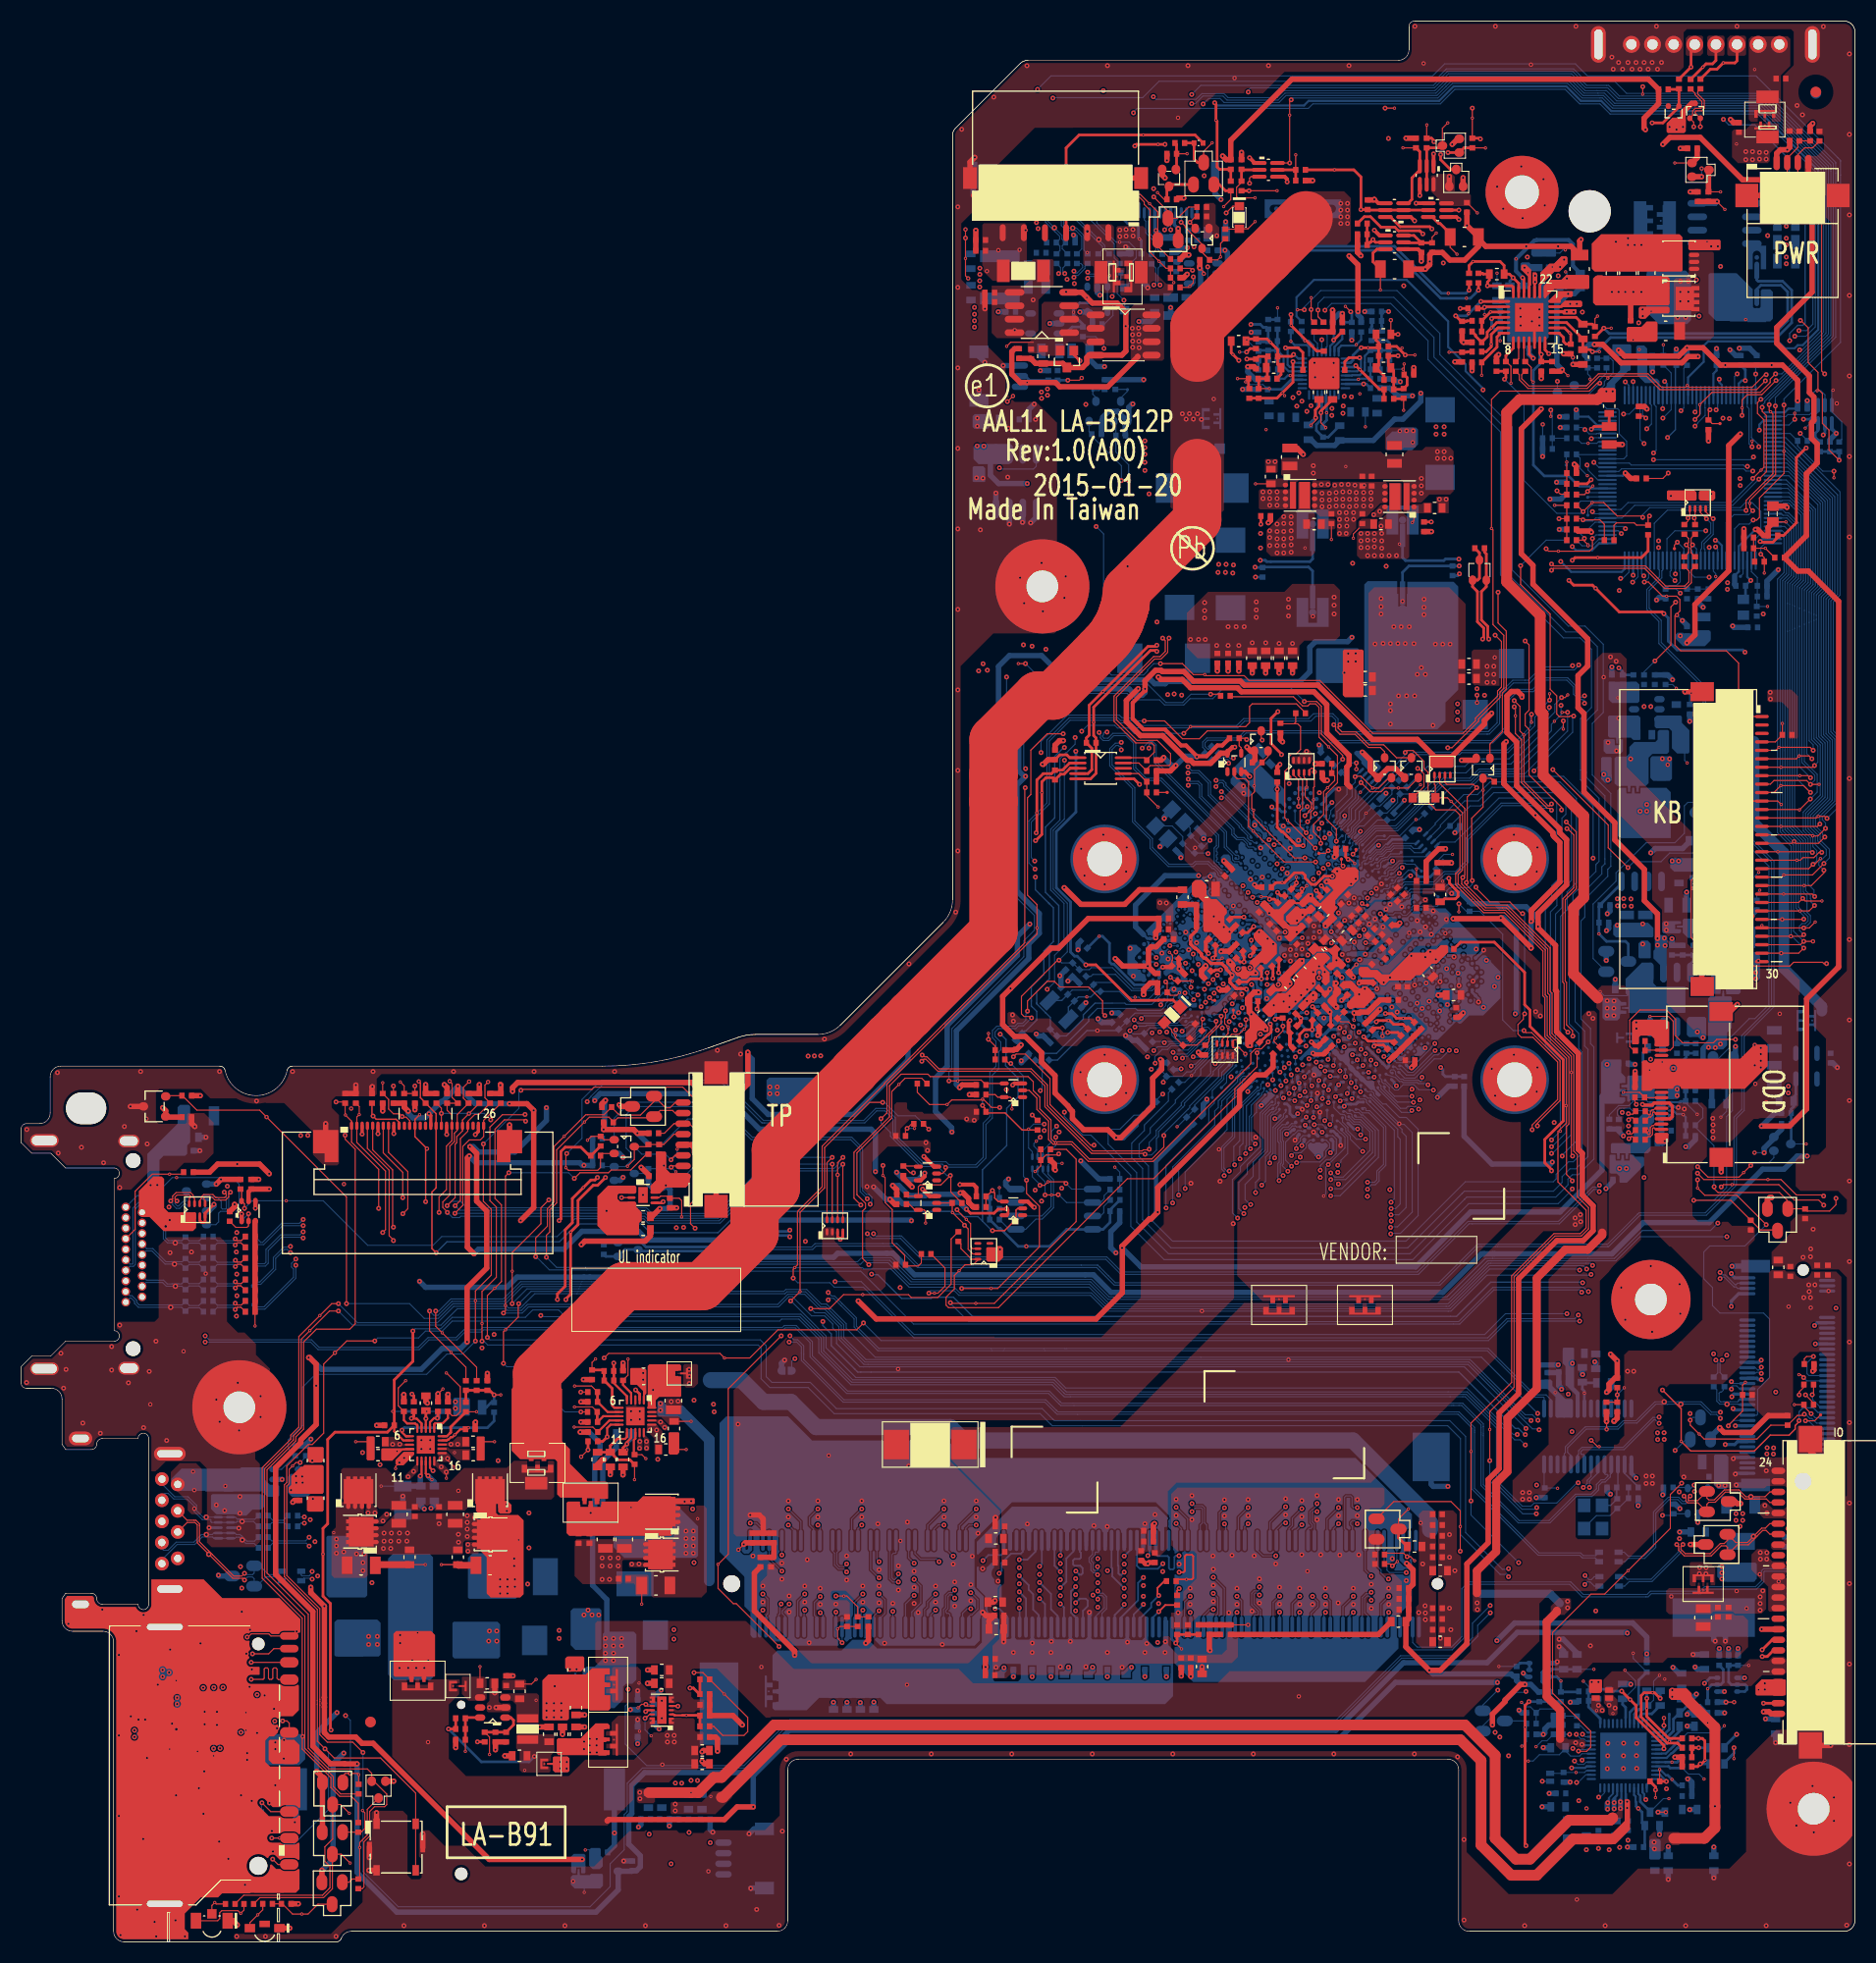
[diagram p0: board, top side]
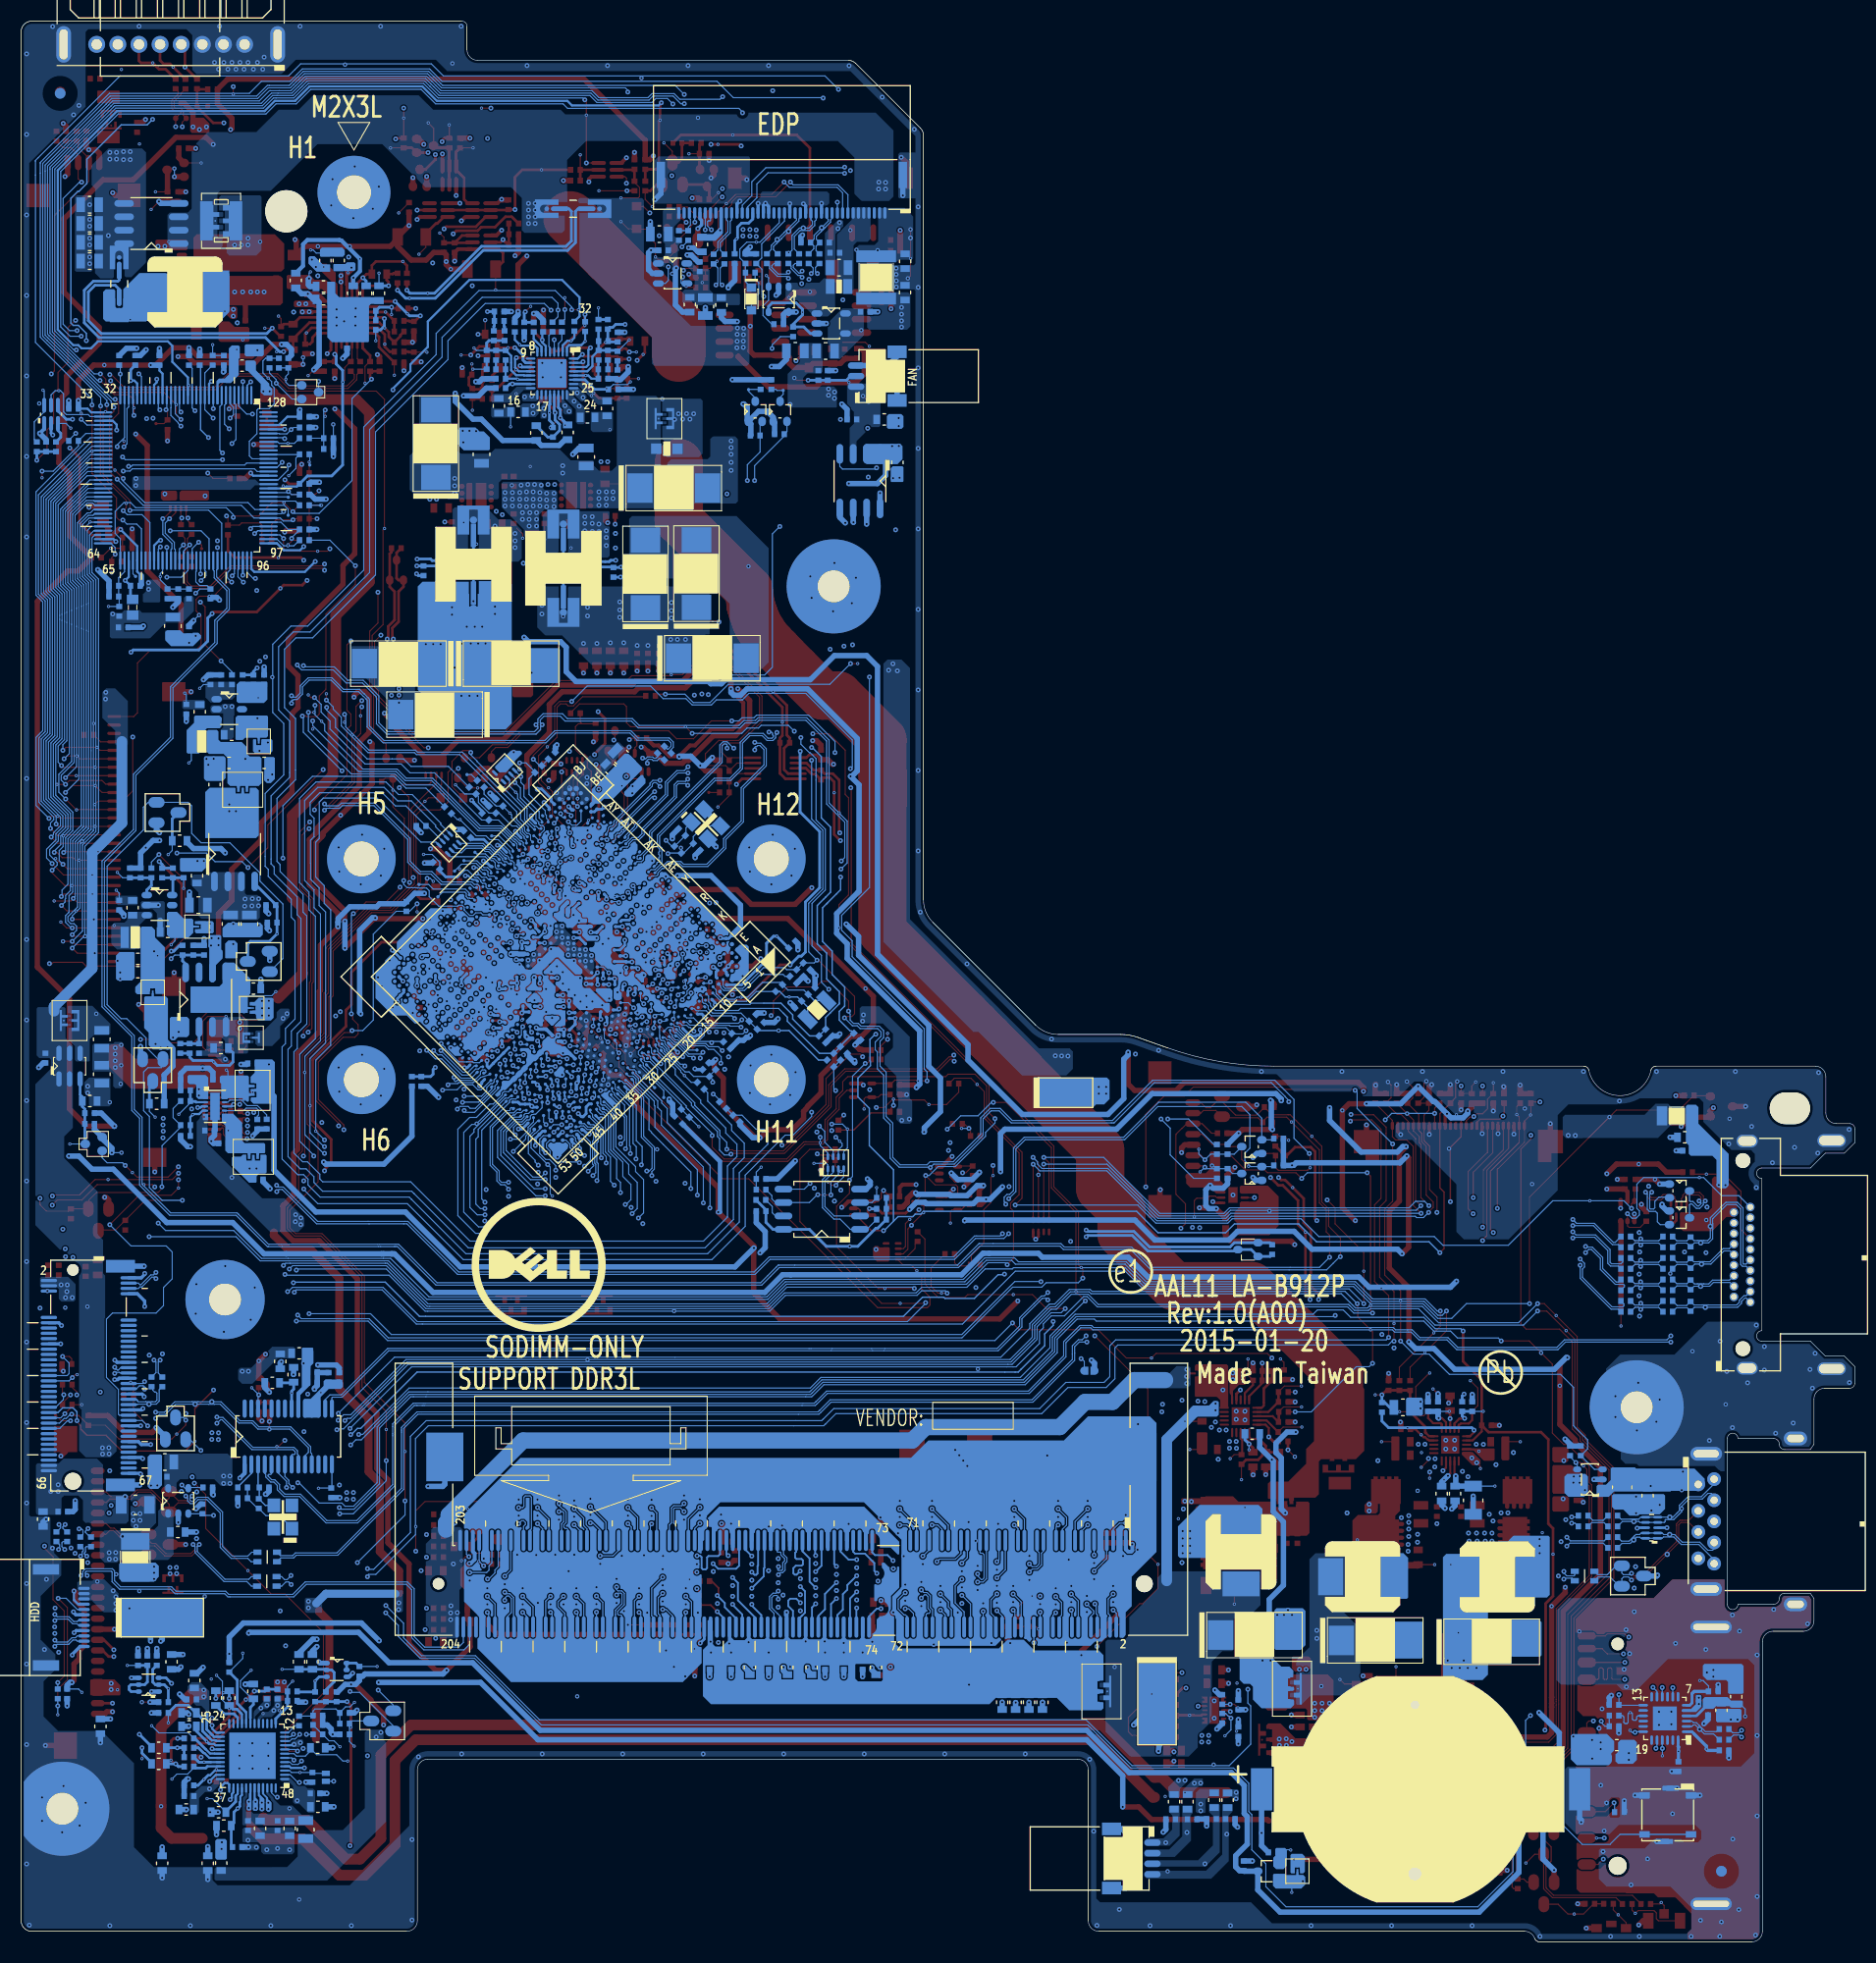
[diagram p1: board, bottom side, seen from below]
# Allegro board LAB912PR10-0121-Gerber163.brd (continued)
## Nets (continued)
USB20_HUB_P1: JEDP.35 U58.11
USB20_HUB_P2: JNGFF.3 U58.9
USB20_HUB_P3: LI6.1 U58.7
USB20_HUB_P4: RR4.2 U58.5
USB20_JUSB1_N0_R: D27.2 JUSB1.2 LI2.2
USB20_JUSB1_P0_R: D27.3 JUSB1.3 LI2.3
USB20_JUSB2_N1_R: D25.2 JIO1.22 LI5.2
USB20_JUSB2_P1_R: D25.3 JIO1.21 LI5.3
USB20_JUSB3_N3_R: D26.2 JIO1.18 LI6.3
USB20_JUSB3_P3_R: D26.3 JIO1.19 LI6.2
USB20_N0: LI2.1 USOC1.K16
USB20_N1: LI5.1 USOC1.G14
USB20_N2: RX21.2 USOC1.J12
USB20_P0: LI2.4 USOC1.M16
USB20_P1: LI5.4 USOC1.J14
USB20_P2: RX22.2 USOC1.K12
USB_EN#: CI13.1 CI26.1 UE1.84 UI4.4 UI5.4
USB_OC0#: CI15.1 RC44.2 UI5.3 USOC1.C20
USB_OC1#: CI17.1 RC46.2 UI4.3 USOC1.B20
USB_PLL_MON: RC47.2 USOC1.M13
USB_RCOMP: RC45.2 USOC1.C7 USOC1.D6
VCIN0_PH: PR13.2 R696.1 UE1.109
VCIN1_BATT_DROP: PR36.2 UE1.64
VCIN1_PROCHOT: PR15.2 R697.1 UE1.102
VCORE_GSNS: PC503.2 PC535.2 PU500.12 PU500.30 RC58.1 USOC1.N28
VCORE_VSNS: PC527.1 PC533.2 PR542.1 RC56.2 USOC1.P28
VCOUT0_PH: PR114.1 UE1.104
VCOUT1_PH: PR17.1 PR18.2 RE13.2 UE1.103
VFB: PR726.1 PU700.15 PU700.16
VGA_V1P35_S3_F1: CC35.1 CC36.1 RC67.2 USOC1.BD1
VGATE: PR530.1 PU500.15 UE1.97
VGFX_VSNS: PC502.1 PR501.2 PR504.2 RC55.2 USOC1.BB8
VL: PC117.1 PU100.13
VR_HOT#: PC520.1 PR525.1 PU500.6 R44.1
VR_ON: CE34.1 PR516.1 RE1.2 RE12.2
VR_ON_EC: RE12.1 UE1.121
VR_ON_R: PR516.2 PU500.2
VR_SVID_ALERT#: PU500.4 RC27.2 RC28.2
VR_SVID_ALERT#_SOC: RC28.1 USOC1.B24
VR_SVID_CLK: PR520.1 PR527.1 USOC1.C25
VR_SVID_CLK_R: PR520.2 PU500.3
VR_SVID_DATA: PR521.1 PR526.1 RC29.2
VR_SVID_DATA_R: PR521.2 PU500.5
VR_SVID_DATA_SOC: RC29.1 USOC1.A25
VSUM+: PC529.1 PC530.1 PR535.1 PR536.2 PR541.1 PU500.10
VSUM-: PC529.2 PC530.2 PC532.2 PC534.1 PH503.2 PL501.3 PR540.2 PR541.2
VSUMG+: PC513.2 PC514.2 PR500.2 PR509.2 PR513.2 PU500.32
VSUMG-: PC512.1 PC513.1 PC514.1 PH500.1 PL500.3 PR502.2 PR507.1 PR509.1
VTTREF_1.35VP: PC212.1 PU200.4
WL_OFF#: QM30.3 RE14.2 RP54.3 USOC1.BA26
WL_OFF#_EC: RE14.1 UE1.98
WLAN_CLKREQ#: JNGFF.45 RP63.2 USOC1.BD7
WLAN_RADIO_DIS#_R: JNGFF.48 QM30.1 RM110.2
WLAN_WAKE#: JNGFF.47 R490.2 UE1.86
XDP_H_PRDY#: CC52.1 JDB1.2 RC65.2 USOC1.D18
XDP_H_PREQ_BUF#: CC50.1 JDB1.1 RC61.2 USOC1.F16
XDP_H_TCK: CC65.1 JDB1.26 RP66.6 USOC1.D14
XDP_H_TDI: CC61.1 JDB1.22 RP66.8 USOC1.F12
XDP_H_TDO: CC56.1 JDB1.20 RC63.2 USOC1.G16
XDP_H_TMS: CC63.1 JDB1.23 RP66.7 USOC1.F14
XDP_H_TRST#: CC59.1 JDB1.21 RP66.5 USOC1.G12
XDP_OBSDATA_A0: JDB1.4 USOC1.N24
XDP_OBSDATA_A1: JDB1.5 USOC1.M20
XDP_OBSDATA_A2: JDB1.7 USOC1.J18
XDP_OBSDATA_A3: JDB1.8 USOC1.M18
XDP_RSTBTN#: CC12.1 CC49.1 CC53.1 JDB1.18 RC24.2 RC62.2
XTAL_25M_IN: CC9.1 RC19.1 USOC1.AH12 YC1.1
XTAL_25M_OUT: CC10.1 RC19.2 USOC1.AH10 YC1.3
N17188574: PC400.2 PJP400.2 PU400.4
N17188613: PC405.1 PR401.2
N17227658: PC412.1 PJP404.2 PU402.5 PU402.9
N17227663: PC413.2 PR410.2 PR412.1 PU402.2
N17227696: PC415.1 PR409.2 PR411.1 PU402.8
N17253612: PC116.1 PR111.2 PU100.12
N17256470: PC210.2 PR209.2 PU200.12
N17256593: PC211.1 PR202.2
N17322320: PC7.1 PH1.1 PR10.2 PR13.1
N17322935: PQ3.3 PR12.2
N17322941: PQ3.5 PQ3.6 PR14.1 PR19.2
N17330968: RC52.1 T211.1(TP-1)
N17354752: PL501.2 PR536.1
N17407779: CE12.1 R2354.1
N17434553: RE36.1 T218.1(TP-1)
N17434554: RE36.2 UE1.107
N18943829: PR720.2 PR724.1
N18944147: PC722.2 PC726.1 PR720.3 PU700.17
N18956218: PC722.1 PR724.2 PU700.18
N18967347: PC727.1 PR723.2
N18967375: PC721.1 PU700.4
N18967379: PR723.1 PU700.6
N18967435: PC723.1 PU700.7
N18967441: PR725.1 PR728.2 PU700.5
N18999155: PC706.1 PC709.1 PR704.2 PU700.28
N19000258: PC707.1 PC709.2 PR705.2 PU700.27
N19021042: PC710.1 PR709.2 PU700.26
N19093256: PR717.2 PU700.10
N19093259: PR719.2 PU700.9
N19095003: PR722.2 PU700.8
N19142937: PC700.2 PC701.1 PQ704.4 PQ705.4 PQ707.1 PR701.2 PR703.1
N19565438: PQ707.2 PQ708.1
N19565442: PQ709.3 PQ710.3 PR703.2
N19565444: PQ709.2 PQ709.5 PQ712.1 PR712.2
N19565472: PQ711.1 PR708.1
N22321388: T212.1(TP-1) UE1.82
N23955686: T105.1(TP-1) USOC1.C21
N23993932: CC24.2 RC39.2
N24334655: PC300.2 PJP300.2 PU300.4
N24334673: PC305.1 PR301.2
N24559749: PC307.2 PJP302.2 PU301.4
N24559796: PC306.1 PR306.2
N24654163: PC112.2 PR107.1
N24654248: PC113.1 PR108.2
N25654694: QA5.5 QA5.6 RA2.2
N25654700: CA1.1 CA2.1 QA5.2 RA3.2
N25858228: JODD1.8 RS09.2
N25860239: C1132.1 R1049.2 RC69.1 Y9.1
N25865342: R2448.2 R2450.1 U2407.7
N26297922: CX52.1 UX3.4
N26299865: CE60.1 UE4.6
N26526512: PC10.1 PR34.1 PR35.1 PR36.1
N26599744: PC12.1 PR11.2 PR15.1 PR18.1 PR20.1 PR22.1 PR23.1
N26600179: PR117.1 PU100.19
N26695162: RX10.2 UX4.3
N26916933: C976.2 U11.7
N26916935: C967.2 U11.9
N26924121: C1123.2 U12.7
N26924123: C1127.2 U12.9
N26952483: R1048.1 U58.14
N26952856: C1119.1 R1050.2 U58.21
N27019358: T103.1(TP-1) USOC1.AY26
N27069111: RA34.1 RA155.1 UA1.13
N27069175: CA24.1 UA1.37
N27069177: CA24.2 UA1.35
N27069191: CA23.2 UA1.28
N27069244: CA65.2 CA69.1 RA79.1 RA81.2
N27069257: CA65.1 UA1.12
N27069271: CA25.2 UA1.34
N27069366: RA130.2 UA1.8
N27069480: CA63.2 UA1.39
N27069495: CA64.2 UA1.7
N27069508: CA62.2 RA154.2 UA1.27
N27069623: CA21.1 R2355.2
N27070739: CA68.2 RA82.1
N27070741: CA67.2 RA80.1
N27098098: R2356.1 UA1.20
N27098403: QA1.5 QA1.6 RA16.2 RA17.2
N27098689: QA1.2 RA18.1 RA20.1
N27376108: PJP1.1 PJPDC1.1 PJPDC1.2 PL2.1
N27796256: CS17.1 JODD1.17 RS10.2
N28004468: QE9.2 R36.1
N28121198: PC515.1 PR511.2
N28124976: PQ10.6 PR23.2
N28125082: PQ10.3 PR22.2
N28199307: R34.1 U68.5
N28199357: R32.1 U69.5
N28392619: PR524.2 PU500.8
N28393122: PC517.2 PR518.1 PU500.22
N28398304: RD15.1 RX5.1 UE1.117
N28546463: D2401.2 R5205.2
N29841026: PQ713.3 PR730.2
N39970373: PQ710.6 PQ712.2 PR718.2
N40812716: CR3.2 UR1.6
N47007898: PC11.2 PQ4.5 PR26.1
N47008110: PC9.1 PQ4.2 PR17.2
N47008134: PL3.1 PQ1.1 PR2.2
N48037563: JDIMM2.197 RD6.2
N48037565: JDIMM2.201 RD7.2
N48039107: CD21.1 CD22.1 JDIMM2.126 RD4.1
N52907207: PQ706.4 PR706.1 PR708.2
N52907447: PQ711.2 PR714.1
N55201771: JHDMI1.13 RX12.2
N59110906: RE43.2 T203.1(TP-1)
N61580896: Q2307.1 R2314.2
N61580898: Q2308.1 R2315.2
N100764683: PC506.1 PR502.1
N100764685: PC506.2 PR507.2 PU500.31
N100764689: PC532.1 PR539.2
N100764691: PR539.1 PR540.1 PU500.11
N100764720: PC518.1 PR519.2 PR522.2 PU500.21
N100764741: PC504.1 PR503.1 PR508.1 PU500.28
N100764791: PC504.2 PC505.1 PC507.2 PR504.1 PR505.1 PU500.29
N100764795: PC528.2 PC531.2 PR534.2 PU500.14
N100764809: PC528.1 PR533.2 PR538.2 PR542.2 PR543.1 PU500.13
N100764813: PC507.1 PR503.2
N100764860: PR510.2 PU500.27
N100764905: PC531.1 PR543.2
N100764954: PC527.2 PR538.1
N100764996: PH500.2 PR500.1
N100765028: PC525.2 PR533.1
N100765040: PC505.2 PR501.1
N100765116: PH503.1 PR535.2
N100765769: PC511.1 PR505.2
N100765781: PR522.1 PU500.20
N100768097: PC526.1 PR532.2
N100768278: PC516.1 PR512.2
N100768460: PC524.1 PR531.2
N100768540: PL500.2 PR513.1
N102723193: T102.1(TP-1) USOC1.BG18
N102723222: T101.1(TP-1) USOC1.BH18
N102723231: T100.1(TP-1) USOC1.BG21

Pads without a net: FD1 1; FD2 1; FD3 1; FD4 1; JDB1 11 14 15 24; JDIMM2 77 122 125 198; JEDP 3 22 33 39; JHDMI1 14; JIO1 10 16; JKB 2 3 30; JNGFF 6 8 9 11 12 13 14 15 16 17 19 20 21 22 23 24 26 28 34 36 38 40 51 52 53 54 56 57 58 59 60 62 63 65; JODD1 9 16; LED2 3; PD2 3; PJPDC1 4; PU300 5; PU301 5; PU400 5; PU402 7; PU500 9; RP1 4 5; RP54 4; RP65 4; RP68 1 8; U58 12 13 22 23 24 25 27 28; U68 1; U69 1; U2407 8; UA1 14 15 16 23 24 48; UC5 1; UC7 1; UC10 1; UE1 1 14 17 25 26 37 71 90 119 120 126 127 128; UR1 7 9 12 14 16 17 19 22 23; USOC1 A13 A17 AB2 AB3 AB7 AB9 AB12 AB13 AB14 AC1 AC3 AD2 AD3 AD4 AD6 AD9 AD10 AD12 AD40 AD41 AF4 AF6 AF13 AF14 AF40 AF41 AF48 AF50 AF51 AF52 AG51 AG53 AH13 AH14 AH40 AH44 AH52 AJ51 AK4 AK6 AK7 AK9 AK40 AK42 AK45 AK47 AK48 AK50 AK51 AK52 AL1 AL3 AL51 AL53 AM4 AM6 AM9 AM10 AM13 AM14 AM41 AM42 AM45 AM47 AM48 AM50 AM52 AP4 AP6 AP7 AP9 AP10 AP12 AP41 AP42 AP44 AP45 AP47 AP48 AP50 AP51 AP52 AR51 AR53 AT6 AT7 AT13 AT14 AT20 AT22 AT26 AT32 AT34 AT36 AT40 AT41 AT42 AT44 AT45 AT48 AT50 AT51 AU20 AU22 AU26 AU34 AU36 AU53 AV9 AV10 AV20 AV22 AV26 AV28 AV32 AV34 AV36 AV40 AV44 AV45 AV48 AV50 AV52 AW1 AW41 AW51 AW53 AY2 AY3 AY6 AY7 AY20 AY24 AY28 AY30 AY34 AY38 AY40 AY42 AY44 AY45 AY47 AY48 AY51 AY52 B4 B5 B12 B14 B16 B26 B28 BA1 BA3 BA18 BA20 BA24 BA28 BA34 BA36 BA38 BA42 BA51 BB3 BB4 BB44 BB47 BB49 BB50 BB51 BC14 BC18 BC24 BC36 BC38 BC40 BC44 BC52 BC53 BD2 BD5 BD12 BD16 BD18 BD20 BD22 BD28 BD32 BD34 BD36 BD38 BD40 BD42 BD44 BD47 BE46 BE51 BE52 BF2 BF14 BF22 BF27 BF28 BF32 BF34 BF40 BF42 BF48 BF50 BF52 BG23 BG26 BG27 BG29 BG32 BG33 BG35 BG36 BG37 BG38 BG40 BG41 BG43 BG47 BH4 BH5 BH6 BH7 BH8 BH22 BH26 BH32 BH34 BH36 BH38 BH40 BH42 BH44 BH46 BH47 BH48 BH49 BH50 BJ9 BJ29 BJ33 BJ37 BJ41 BJ45 C13 C16 C18 C27 C30 D2 D26 D28 D32 D34 D48 E2 E46 F1 F18 F28 F32 F34 G2 G30 H3 H4 H5 H7 H8 J3 J28 J34 K2 K3 K18 K20 K24 K28 K34 L1 L3 M2 M3 M4 M6 M7 M9 M10 M22 M24 M32 N3 N32 N34 P2 P3 P6 P7 P10 P12 P14 P34 R1 R3 T2 T3 T4 T6 T7 T9 T10 T12 T13 T14 V2 V3 V4 V6 V9 V10 V13 V14 W1 W3 Y2 Y3 Y4 Y6 Y12 Y13; Y9 2 4

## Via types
v1: diameter 0.305, hole 0.152, TOP to BOTTOM, 442 vias
v2: diameter 0.457, hole 0.203, TOP to BOTTOM, 3086 vias
v3: diameter 0.508, hole 0.254, TOP to BOTTOM, 20 vias
v4: diameter 0.406, hole 0.203, TOP to BOTTOM, 136 vias

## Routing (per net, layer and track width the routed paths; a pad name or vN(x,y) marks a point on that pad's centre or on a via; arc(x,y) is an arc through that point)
1.0VS_GATE: length 10.7
  BOTTOM w0.254: Q70.1 152.1,94.45 151.85,94.7 150.04,94.7 v1(149.33,95.41) R1061.1 149.33,98 C1131.1 149.61,98.28 149.61,98.34 151.44,100.17 U60.4
1.8VS_ON: length 4.2
  BOTTOM w0.102: v1(158.63,78.33) 157.54,79.42 R1055.1
  BOTTOM w0.203: U12.2 156.98,79.48
  BOTTOM w0.254: 156.98,79.48 157.05,79.55 157.5,79.55 R1055.1 C1125.2
1.35VS_ON: length 3.5
  BOTTOM w0.203: U12.4 156.37,78.68 156.7,78.35 157.25,78.35 v1(157.31,78.3) 157.54,78.07 R1056.1
  BOTTOM w0.254: R1056.1 C1128.2
3VS_ON: length 3.8
  TOP w0.203: U11.2 61.73,21.53 61.8,21.46 61.88,21.46 61.89,21.45 62.6,21.45
  TOP w0.254: 62.6,21.45 v1(62.96,21.45) 64.22,21.45 C980.1 R927.1
5VS_ON: length 5.4
  TOP w0.203: v2(62.16,22.31) 62.14,22.33 U11.4
  TOP w0.254: R926.2 C979.2 64.19,23.45 63.62,24.02 v2(63.3,24.02)
  IN1 w0.254: v2(63.3,24.02) 62.16,22.88 v2(62.16,22.31)
+0.675VS: length 74.6
  BOTTOM w1.524: 65.27,53.17 68.19,53.17 70.26,51.11 72.86,51.11 75.24,48.73 87.94,48.73 89.21,47.46 126.04,47.46 133.09,40.41 133.09,39.9 133.34,39.64 133.34,39.01
  vias: v2(63.23,54.19) v2(63.25,53.53) v2(63.24,52.85) v2(132.27,31.16) v2(132.64,35.77) v2(132.87,31.81) v2(132.9,31.14) v2(132.9,30.5) v4(132.45,39.66)
+0.675VSP: length 2.7
  TOP w0.254: v2(58.16,52.24) 58.53,51.86 PU200.2
  IN1 w0.254: v2(59.81,52.24) v2(58.16,52.24)
+1.0VALW: length 18.4
  TOP w0.102: v2(137.79,118) v4(137.79,117.29)
  TOP w0.254: C1074.1 115.36,92.75 v2(115.74,92.75) 115.74,93.27 115.62,93.38 C1039.2 ; C1036.2 117.3,91.95 117.38,91.87 v2(117.38,91.15) 116.33,91.15 116.05,90.87 C1037.2
  TOP w0.508: C1034.2 107.42,94.19 106.97,94.19 106.7,93.92 106.7,92.43 v2(106.63,92.36) ; v2(106.63,92.36) 107.31,91.68 C1035.2 ; v2(106.63,92.36) 104.25,92.36 v2(103.55,93.06)
  BOTTOM w0.254: v2(115.74,92.75) 116.29,92.75 USOC1.V18 116.32,92.79 USOC1.Y19 ; USOC1.C3 106.49,92.53 106.49,92.49 v2(106.63,92.36) 106.98,92.01 USOC1.C5 106.8,91.79 106.8,91.6 USOC1.B6 ; USOC1.U22 117.36,91.13 v2(117.38,91.15) 117.39,91.16 USOC1.V22
  vias: v2(108.51,118.05) v2(109.12,118.11) v2(109.84,118) v2(137.79,118.61) v2(138.5,117.99) v2(153.22,107.02) v2(153.85,107.65) v2(153.85,107.02)
+1.0VALWP: length 10.9
  IN1 w0.254: v2(152.33,111.97) 152.01,112.29 152.01,113.98 151.21,114.78 v2(151.21,120.58)
  BOTTOM w0.254: v2(151.21,120.58) 151.21,120.59 151.57,120.24 PR307.1 PC310.1
+1.0VALWP_ON: length 1.2
  BOTTOM w0.102: PC309.1 156.29,119.01 v1(156.65,118.65)
+1.0VS: length 190.7
  TOP w0.254: v2(118.47,91.2) 118.48,91.21 118.48,92.24 118.37,92.35 ; v2(113.52,92) 113.02,92 112.91,91.9 C1060.2
  TOP w0.305: C1044.2 116.66,93.66 v2(116.32,93.33)
  TOP w0.356: C1061.2 125.02,89.12 v2(124.97,89.12)
  TOP w0.508: v2(107.63,119.72) 107.85,119.49 109.89,119.49 110.68,118.7 115.12,118.7 115.5,118.32 122.36,118.32 123.56,117.11 123.56,114.42 125.69,112.3 125.69,111.42 125.47,111.21 125.47,109.62 125.79,109.3 ; v2(107.83,83.52) 107.94,83.41 107.94,82.6 107.09,81.75 107.09,79.13 104.08,76.12 v2(103.64,76.12) 103.6,76.12 102.85,76.87 100.56,76.87 99.5,77.94 99.5,78.6 99.29,78.81 99.08,79.12 97.85,80.35 97.85,82 96.58,83.27 96.58,84.16 95.04,85.69 94.02,85.69 92.89,86.83 92.89,89.49 v4(93.64,90.24) 97.47,94.06 98.19,94.06 100.98,96.86 C1048.2 C1049.2 107.38,95.55 v2(107.38,95.04) ; C1070.2 127.86,90.84 126.71,90.84 v2(126.62,90.76) ; v2(124.11,154.45) 124.13,154.44 PC523.1 PR525.2 124.11,152.39 PR526.2 PR527.2
  IN1 w0.508: v2(154.23,103.08) 153.8,102.65 153.8,101.23 152.36,99.78 v2(152.36,98.71) ; v2(107.63,119.72) 107.63,119.78 106.57,120.84 106.57,123.88 107.5,124.81 v2(107.5,124.93) ; v2(106.75,137.05) 106.74,137.07 106.74,137.59 105.34,138.98 105.34,142.2 106.19,143.05 106.19,146.34 109.4,149.55 109.4,152.09 112.87,155.56 123.6,155.56 124.11,155.05 v2(124.11,154.45)
  IN2 w0.254: v2(111.44,100.92) 111.44,100.54 112.32,99.65 112.32,96.62 112.52,96.43 112.52,94.38 ; v2(113.52,92) 113.35,92.17 113.35,93.23 112.52,94.06 112.52,94.38 ; 112.52,94.38 114.17,94.38 115.56,95.78 116.26,95.78 117.15,94.89
  IN2 w0.508: v2(107.5,124.93) 107.5,136.3 v2(106.75,137.05)
  BOTTOM w0.254: 106.23,95.33 106.59,94.97 USOC1.G1 107.32,94.97 v2(107.38,95.04) ; v2(126.62,90.76) 126.62,90.22 USOC1.AJ36 ; v2(126.62,90.76) 126.91,90.76 126.92,90.77 USOC1.AK36 ; v2(126.62,90.76) 126.62,91.1 126.64,91.13 USOC1.AK35 ; USOC1.Y22 v2(118.47,91.2) ; USOC1.Y18 v2(116.32,93.33) ; USOC1.V24 117.93,90.63 v2(117.92,90.61) ; v2(125.26,96.69) 124.85,96.28 124.85,95.96 USOC1.AN25 ; USOC1.AF21 USOC1.AG21 v2(121.25,95.03) ; v2(118.98,90.61) 119.01,90.64 USOC1.Y24 ; 126.14,94.61 126.09,94.56 USOC1.AN29 ; 126.14,94.61 v2(126.17,94.64) ; 126.14,94.61 USOC1.AN30 ; USOC1.AF16 USOC1.AF18 119.6,95.54 v2(119.62,95.57) ; v2(116.29,92.2) USOC1.U19 ; USOC1.AM16 USOC1.AM18 ; 112.99,91.97 113.03,92 v2(113.52,92) ; USOC1.U18 115.29,92.22 v2(115.18,92.1) ; v2(124.71,109.1) 124.68,109.13 124.3,109.13 123.4,108.23 123.4,107.99 USOC1.BJ6 ; v2(121.68,87.95) USOC1.V32
  BOTTOM w0.508: v2(107.83,83.52) 108.14,83.21 RC15.2 ; v2(103.64,76.12) 104.31,76.12 105.53,77.34 RC27.1 ; v2(111.44,100.92) 108.26,100.92 105.47,98.13 105.47,96.1 106.23,95.33 ; v2(154.23,103.08) 154.64,103.49 157.24,103.49 157.85,104.1 R1052.2
  vias: v2(120.75,96.65) v2(121.28,97.19) v2(123.3,87.45) v2(124.67,97.39) v2(125.67,98.33) v2(126.15,98.81) v2(128.26,99.7) v2(128.74,100.14) v2(151.07,98.73) v2(151.09,98.06) v2(151.67,98.74) v2(151.71,98.05) v2(152.39,98.03)
+1.0VS_R: length 4.4
  BOTTOM w0.102: v1(159.63,102.92) 159.25,103.3 R1052.1
  BOTTOM w0.254: R1052.1 159.25,106.29 Q71.1
+1.05V_PGOOD: length 2.6
  BOTTOM w0.102: UE1.106 148.64,135.97 148.28,135.61 T210.1
+1.5VS: length 63.3
  TOP w0.762: 149.64,67.14 149.64,66.89 148.27,65.51 146.13,65.51 143.44,62.82 143.44,52.34 140.67,49.58 140.67,44.51 139.6,43.44 139.6,36.94 137.78,35.11 137.78,33 ; 145.65,19.21 145.65,21.94 144.38,23.21 144.38,30.28 145.34,31.25 145.34,31.35
  BOTTOM w0.203: v2(147.72,18.69) 147.8,18.61 UA1.9
  BOTTOM w0.254: v2(126.69,92.97) 126.66,92.94 USOC1.AM32
  BOTTOM w0.508: RA8.1 v2(152.03,8.97)
  BOTTOM w0.762: 145.62,32.04 144.71,32.95 138.13,32.95
  vias: v2(137.8,32.09) v2(137.83,31.45) v2(143.34,88.04) v2(143.78,87.64) v2(146.36,32.24) v2(146.36,31.62) v2(147.12,18.85) v2(148.38,87.85) v2(148.76,87.41) v2(151.29,8.95) v4(134.79,95.46)
+1.05VS: length 12.7
  TOP w0.102: v4(126.37,92.5) 125.66,91.79 C1042.1
  TOP w0.254: C1040.1 122.71,88.03 v2(122.22,88.52)
  TOP w0.356: RC100.1 120.68,87.85 v2(121.12,87.42) 121.12,87.08 C1038.1
  TOP w0.381: C1041.1 124.94,91.27 v2(125,91.27)
  TOP w0.508: C1042.1 125.66,91.72 v2(126.08,91.3)
  BOTTOM w0.254: USOC1.AA33 v2(122.22,88.52) ; USOC1.U35 USOC1.U33 121.11,87.41 v2(121.12,87.42) 121.13,87.41 USOC1.V33
  BOTTOM w0.508: 159.19,84.54 159.19,82.89 160.01,82.06 R2315.1
  vias: v2(159.7,84.67) v2(160.34,84.64) v2(160.83,84.98)
+1.05VS_SOC: length 1.1
  BOTTOM w0.254: USOC1.Y32 121.69,89.06 v2(121.69,89.06) ; v2(122.27,89.61) USOC1.AC32
  vias: v1(122.28,89.1)
+1.5VSP: length 7.3
  BOTTOM w0.254: PC414.1 153.5,84.17 153.5,83.28 153.82,82.96 155,82.96 v1(155.31,83.28) 155.45,83.42 157.28,83.42 157.6,83.74 PC413.1 PR410.1
+1.05VSP: length 12.7
  TOP w0.254: v2(160.97,93.76) 160.11,93.76 158.36,95.51 158.36,100.13 v2(160.48,102.26)
  BOTTOM w0.254: PR302.1 PC301.1 160.2,101.98 v2(160.48,102.26)
  vias: v1(160.64,93.34)
+1.05VSP_ON: length 5.3
  BOTTOM w0.102: PC304.1 163.94,100.72 v1(164.45,101.23)
  BOTTOM w0.254: PC304.1 PR303.1 PR300.2 161.22,99.99 161.66,99.56 PU300.1
+1.8VALW: length 252.7
  TOP w0.254: v2(50.92,68.27) 51.09,68.44 51.09,74.81 51.49,75.22 52.98,75.22 53.78,74.42 RE34.1 53.93,74.42 R36.2 ; v2(89.46,69.35) 89.84,68.97 92.08,68.97 92.46,69.35 93.21,69.35 v2(93.26,69.4) 93.4,69.26 93.4,68.92 93.26,68.78 UC5.5
  TOP w0.305: JDB1.16 38.77,78.21 v2(38.6,78.38)
  TOP w0.508: R34.2 82.68,69.82 v2(82.23,70.28) ; RC61.1 RC62.1 36.25,79.01 v2(36.63,78.63) ; v2(47.28,68.27) 48.51,69.5 v4(48.51,78.7) 47.87,79.33 v2(46.22,79.33) ; R32.2 v2(89.74,80.2) ; RC63.1 v2(41.33,80.98)
  TOP w1.016: 149.38,146.18 149.18,145.98 141.83,145.98 140.6,144.75 140.6,128.72 143.77,125.55 143.77,116.49 144.05,116.21 144.05,110.42 147.89,106.58 147.89,98.83 146.92,97.86 146.92,91.63 149.22,89.33
  IN1 w1.016: 63.76,68.97 77.3,68.97 79.03,70.7
  IN2 w1.016: 48.9,16.59 36.07,16.59 33.52,19.15 28.7,19.15 24.06,23.78 24.06,29.1 22,31.16 22,44.83 24.42,47.24 24.42,58.73 30.89,65.21 36.86,65.21 38.54,66.89 45.89,66.89 v2(47.28,68.27) v2(50.92,68.27) 56.91,68.27 57.84,67.34 60.81,67.34 60.83,67.33
  BOTTOM w0.229: USOC1.AA18 116.87,93.88 116.42,94.32 v2(116.42,94.81)
  BOTTOM w0.254: v2(93.26,69.4) 93.24,69.38 RC99.1 ; USOC1.N20 115.43,89.8 v2(115.53,89.7)
  BOTTOM w0.508: RC46.1 RC44.1 105.18,85.33 104.88,85.63 104.69,85.63 104.54,85.78 v2(104.53,85.78) ; v2(89.46,69.35) 88.81,70 88,70 87.88,69.87 83.43,69.87 83.03,70.28 v2(82.23,70.28) 81.86,70.28 v2(80.68,71.46) ; v2(36.63,78.63) 36.63,78.44 37.08,78 38.22,78 v2(38.6,78.38) 39.76,79.54 39.88,79.54 v2(41.33,80.98) 42.98,79.33 v2(46.22,79.33)
  vias: v2(51.03,17.03) v2(51.03,16.42) v2(51.64,17.03) v2(51.63,16.4) v2(62.01,67.6) v2(62.69,67.62) v2(80.05,71.48) v2(85.63,75.65) v2(85.78,74.91) v2(89.49,77.88) v2(90.2,77.76) v2(93.83,87.74) v2(93.91,87.14) v2(117.89,89.29) v2(142.11,42.53) v2(142.11,41.89) v2(142.74,42.53) v2(142.74,41.89) v2(150.03,146.76) v2(150.11,89.07) v2(150.11,88.37) v2(150.11,87.68) v2(150.63,146.76) v2(150.76,89.06) v2(150.74,88.37) v2(150.74,87.68) v2(156.72,80.7) v2(156.72,80.11)
+1.8VALWP: length 11.3
  TOP w0.254: v2(40.44,20.15) PR402.1 PC401.1
  BOTTOM w0.254: v2(48.57,17.55) 48.06,17.04 43.55,17.04 v2(40.44,20.15)
  vias: v1(47.66,16.24)
+1.8VS: length 454.5
  TOP w0.254: v2(18.25,69.81) 17.41,68.97 RP15.4 17.41,68.21 17.3,68.09 17.11,68.09 16.91,68.29 RP15.3
  TOP w0.406: v2(114.86,113.09) 114.64,113.09 114.17,112.61 UC10.5 ; v2(122.11,85.18) 122.48,84.82 C1055.1 C1054.1
  TOP w0.508: v2(18.47,71.73) v4(18.92,72.17) R376.1 ; QC4.2 130.06,111.05 129.33,111.05 128.45,110.18 QC3.2 127.68,110.89 127.68,111.86 v2(126.93,112.61) ; RC43.1 122.48,111.51 v2(122.46,111.49) ; RC8.2 118.49,82.79 117.76,82.06 116.83,82.06 115.31,80.54 115.31,79.13 107.58,71.39 v2(107.58,69.07) 106.94,68.44 106.79,68.44 104.2,65.84 ; v2(42.41,74.38) 42.23,74.2 42.23,65.76 v2(42.86,65.13) ; RC102.1 132.98,102.27 134.17,103.46 v2(134.8,103.46) ; v2(142.91,96.6) 142.93,96.63 142.93,97.62 145.63,100.32 145.63,104.06 145.1,104.6 144.98,104.77 144.98,104.97 v2(143.31,106.64) 140.34,109.61 RC17.1 140.34,113.39 v2(140.54,113.6) ; v2(105.72,118.61) 104.6,117.5 104.6,115.5 105.94,114.17 108.03,114.17 110.37,111.83 110.69,111.83 110.97,111.55 112.57,111.55 113.53,112.51 UC10.5 ; 104.2,65.84 v2(104.2,65.68) ; 104.2,65.84 104.22,65.82 104.22,61.45 101.73,58.96 80.93,58.96 v2(79.23,60.66) ; v2(142.91,94.06) 142.91,94.09 140.09,96.91 v2(140.04,96.91) 139.97,96.84 v2(135.53,96.84) ; R8.1 119.18,113.79 v2(119.39,113.58) ; RC16.1 130.28,96.24 v2(130.47,96.43) ; RC18.1 116.78,111.89 116.78,112.65 QC2.2 116.38,112.72 v2(116.01,113.09)
  IN1 w0.406: v2(141.41,87.84) 140.75,87.18 129.43,87.18 129.28,87.33 128.9,87.33 128.52,87.71 127.65,87.71 127.24,87.31 124.83,87.31 123.76,86.24 123.76,86.06 122.88,85.18 v2(122.11,85.18)
  IN1 w0.508: v2(79.23,60.66) 81.36,62.8 81.36,63.62 84.26,66.52 v2(84.26,68.26) ; v2(150.09,83.05) 147.08,83.05 142.96,87.18 142.07,87.18 v2(141.41,87.84)
  IN2 w0.381: v2(135.53,96.84) 135.53,96.69 135.1,96.26 133.82,96.26 132.83,97.25 131.96,97.25 131.14,96.43 v2(130.47,96.43) 130.47,95.48 128.35,93.37 127.34,93.37 v2(127.22,93.49)
  IN2 w0.508: v2(143.31,106.64) 143.06,106.38 139.89,106.38 136.82,103.31 134.96,103.31 v2(134.8,103.46) ; v2(53.27,73.5) 54.03,74.26 v2(56.97,74.26) v2(56.97,72.36) ; v2(105.72,118.61) 105.63,118.7 105.63,124.82 106.36,125.55 106.36,136.36 105.59,137.12 105.59,140.11 105.21,140.5 v2(105.21,145.56) 113.16,153.51 v2(113.16,161.49) ; v2(114.86,113.09) v2(116.01,113.09) 116.11,112.99 117.6,112.99 118.19,113.58 v2(119.39,113.58) 119.4,113.6 120.32,112.68 v2(121.65,112.68) 121.65,112.05 122.22,111.49 v2(122.46,111.49) 122.99,112.02 123.89,112.02 124.48,112.61 v2(126.93,112.61) 127.18,112.35 130.36,112.35 130.99,111.72 134.8,111.72 135.95,112.86 139.81,112.86 v2(140.54,113.6) ; v2(18.25,69.81) 18.25,71.5 v2(18.47,71.73) 19.35,72.61 20.6,72.61 22.41,74.42 42.37,74.42 v2(42.41,74.38)
  BOTTOM w0.33: USOC1.U38 122.44,85.25 122.37,85.18 v2(122.11,85.18)
  BOTTOM w0.406: v2(107.58,69.07) 107.42,69.07 107.41,69.08 107.41,73.86 RC10.1
  BOTTOM w0.508: v2(142.91,94.06) v2(142.91,96.6) ; v2(105.21,145.56) 105.15,145.56 104.83,145.25 104.83,144.03 QE11.2 ; QE7.2 56.69,72.08 v2(56.97,72.36) ; RX3.1 104.49,142.62 104.49,143.68 QE11.2 ; v2(84.26,68.26) 84.19,68.32 68.14,68.32 66.25,66.43 59.25,66.43 58.43,67.25 53.07,67.25 51.38,65.57 43.29,65.57 v2(42.86,65.13) ; v2(18.25,69.81) 18.25,69.65 17.78,69.19 Q58.2 ; v2(18.47,71.73) Q57.2 ; v2(42.41,74.38) 43.05,73.74 52.88,73.74 53.12,73.5 v2(53.27,73.5) 53.28,73.49 RE31.1 RE30.1 ; RX2.1 102.24,143.78 QE10.2 102.37,144.31 102.93,144.86 103.77,144.86 QE11.2 ; v2(104.2,65.68) 105.99,63.89 131.99,63.89 137.19,69.09 145.66,69.09 149.61,73.05 149.61,80.02 149.9,80.31 ; v2(141.41,87.84) 141.51,87.94 141.51,95.74 140.32,96.93 140.06,96.93 v2(140.04,96.91) ; v2(56.97,74.26) 56.61,74.62 QE8.2
+1.8VS_OUT: length 0.8
  BOTTOM w0.102: v1(154.12,82.52) 153.98,82.38 153.98,81.8
+1.8VSP_ON: length 6.6
  TOP w0.102: PR400.2 44.33,19.39 v1(44.33,17.74)
  TOP w0.254: PU400.1 46.35,21.23 46.6,20.98 46.6,20.54 PC404.1 PR403.1 PR400.2
+1.35V: length 79.4
  TOP w0.508: R1029.1 128.44,29.09 CD62.2 ; v2(73.21,27.14) 73.21,27.52 69.4,31.33 69.4,34.91 R1027.1 ; RD3.1 80.19,28.53 v2(79.94,28.28) ; CD11.1 93,30.87 CD13.1 v2(93,28.41)
  IN1 w0.508: v2(144.91,73.81) 145.04,73.68 147.38,73.68 147.82,73.24 150.3,73.24 151.19,72.35 v2(153.6,72.35)
  BOTTOM w0.356: 97.21,39.81 97.2,39.8 JDIMM2.87 ; JDIMM2.93 99,39.67 98.98,39.7 ; v2(102.79,39.31) 102.6,39.13 JDIMM2.105 ; JDIMM2.111 104.4,39.14 104.86,39.59 106.34,39.59 v2(106.36,39.58) 106.2,39.43 JDIMM2.117 ; JDIMM2.123 108,39.75 v2(107.31,40.44) ; JDIMM2.81 95.4,39.39 v2(95.23,39.56) 95.19,39.59 93.94,39.59 93.6,39.26 JDIMM2.75 ; JDIMM2.99 100.8,39 101.2,39.4 v2(101.53,39.4)
  BOTTOM w0.508: CD16.1 92.26,26.31 v2(92.26,25.99) ; v2(108.26,27.39) 108.39,27.26 CD10.1 ; v2(104.2,25.99) 104.2,26.31 CD20.1 ; RC6.1 136.57,76.26 139.21,73.62 144.72,73.62 v2(144.91,73.81) ; CD18.1 98.35,26.31 v2(98.35,26.04) ; v2(100.77,26.04) 100.77,26.44 CD17.1 ; CD42.1 v2(95.69,27.39) ; CD6.1 v2(97.47,27.39) ; CD9.1 v2(93.91,27.39) ; CD35.1 v2(106.36,27.39)
  vias: v2(95.7,28.29) v2(97.5,28.44) v2(99.3,28.44) v2(101.1,31.19) v2(102.8,27.39) v2(104.7,28.36) v2(106.53,28.24) v2(108.3,28.41) v2(147.07,68.52) v2(147.08,67.89) v2(147.57,68.83) v2(147.6,68.17) v4(119.94,55.1)
+1.35V_SOC: length 14.1
  BOTTOM w0.254: USOC1.BD49 136.07,90.53 v2(136.08,90.51) ; v2(124.88,75.38) 124.86,75.4 124.86,76.07 USOC1.F53 124.2,76.73 USOC1.F52 ; USOC1.BD52 137.34,89.87 USOC1.BD53 137.93,89.28 v2(137.93,88.96) ; USOC1.BG51 137.78,91.31 v2(137.41,90.94) ; USOC1.H46 122.6,79.97 122.68,80.06 v2(122.68,80.33) ; USOC1.AV41 USOC1.AV42 v2(131.88,90.56) ; USOC1.BJ48 137.68,93.13 v2(138.42,93.87) ; v2(135.61,93.23) 135.48,93.37 USOC1.BF44 ; v2(122.32,76.65) 122.48,76.48 122.53,76.48 USOC1.C51 ; USOC1.D44 121.07,78.99 v2(121.25,78.8) ; v2(120.56,75.88) 120.79,76.11 120.79,76.26 USOC1.A48 ; USOC1.AK38 127.77,90.18 128.29,90.18 v2(128.31,90.21) 128.31,90.75 USOC1.AM38 ; USOC1.BB46 134.34,90.94 v2(134.29,90.88) ; USOC1.F49 122.91,78.52 v2(122.92,78.52)
  BOTTOM w0.33: v2(124.8,86.52) 124.67,86.39 123.87,86.39 USOC1.Y38 USOC1.V38
  vias: v2(122.35,82.06) v4(130.44,77.44)
+1.35VP: length 106.8
  TOP w0.102: v2(53.65,46.57) v4(53,45.92)
  TOP w0.203: PU200.5 57.33,51.65 56.1,52.88 PR204.2
  TOP w0.254: v2(53.65,46.57) PR210.1 ; v2(56.09,54.78) PC216.2 56.1,54.03 PR204.2
  IN2 w0.254: v2(53.65,46.57) 53.65,48.13 53.78,48.26 53.78,54.92 54.84,55.99 61.18,55.99 61.91,55.27 63.84,55.27 64.76,54.35 64.76,50.06 65.82,49 65.82,32.79 61.78,28.75 v2(61.78,28.66) ; v2(56.09,54.78) 56.76,55.46 61.08,55.46 61.75,54.79 63.72,54.79 64.35,54.15 64.35,49.71 65.36,48.7 65.36,33.13 v2(61.78,29.55)
  BOTTOM w1.016: 65.13,34.17 65.13,47.53 62.41,50.25
  vias: v2(60.51,50.95) v2(60.51,50.31)
+1.35VS: length 47.3
  TOP w0.254: CC39.1 121,85.88 121.45,86.34 v2(122.19,86.34) 122.19,87.22 CC41.1 ; CC40.1 119.04,92.24 119.01,92.2 v2(119.01,91.74)
  TOP w0.508: v2(84.32,71.46) 83.5,72.28 RC30.1
  IN1 w0.254: v2(84.32,71.46) 84.77,71.9 85.73,71.9 86.73,72.91 86.73,73.22 88.91,75.4 91.56,75.4 95.63,79.46 96.2,79.46 99.9,83.17 99.9,83.27 101.29,84.65 105.26,84.65 105.45,84.83 106.86,84.83 106.96,84.93 107.43,84.93 107.71,84.65 113.84,84.65 114.99,85.81 115.37,85.81 115.82,86.25 116.01,86.25
  BOTTOM w0.203: v2(119.01,91.74) 119.54,91.2 USOC1.AA25
  BOTTOM w0.254: v2(124.45,90.74) 124.46,90.75 USOC1.AG32 ; v2(124.43,88.52) 124.42,88.52 124.45,88.56 USOC1.AD36
  BOTTOM w0.33: USOC1.V36 v2(122.19,86.34) 122.19,86.33 USOC1.U36
  vias: v2(115.68,109.39) v2(115.71,108.72) v2(119.09,95.01) v2(151.28,73.2) v2(151.92,73.2) v4(111.11,103.55)
+1.35VS_OUT:
  vias: v1(153.94,76.79)
+3V_HUB: length 17.8
  TOP w0.508: v2(150.42,55.62) v4(151.06,54.99) R1051.1 150.86,53.37 150.29,52.8 150.29,52.26 v2(150.06,52.03)
  IN1 w0.508: v2(146.42,51.85) 147.11,52.54 147.11,54.17 148.56,55.62 v2(150.42,55.62)
  IN2 w0.508: v2(145.47,54.62) 145.47,53.83 146.48,52.83 146.48,51.9 v2(146.42,51.85)
  BOTTOM w0.508: R1047.1 143.44,54.33 143.72,54.61 145.46,54.61 v2(145.47,54.62) ; v2(150.06,52.03) 150.49,52.46 R1050.1
+3VALW: length 459.1
  TOP w0.381: UC7.5 85.12,72.08 85.52,72.47 v2(85.52,72.77)
  TOP w0.508: 55.45,11.48 55.48,11.45 55.61,11.58 66.57,11.58 67.77,12.78 v2(69.29,12.78) ; RE2.2 59.56,66.82 59.06,66.33 53.35,66.33 v2(53.02,66) ; v2(157.65,122.96) 158.41,123.72 158.41,126.58 161.61,129.78 161.61,141.63 v2(162.71,142.72) ; v2(153.73,171.53) 153.6,171.66 153.6,172.61 154.97,173.99 PR7.2 154.01,176.31 120.28,176.31 114.48,170.52 PR4.2 114.05,168.69 v2(113.71,169.03) ; v2(98.72,99.78) 100.3,98.2 104.45,98.2 105.84,99.59 R1022.1
  IN1 w0.508: v2(130.85,156.75) 132.44,155.16 132.44,148.25 131.68,147.49 v2(131.68,146.34) ; v2(82.86,72.84) 82.42,72.84 81.3,71.72 81.3,66.61 80.53,65.84 79.11,65.84 77.68,67.28 75.2,67.28 v2(74.22,66.3) ; v2(162.49,27.77) 162.49,27.76 161.86,27.14 159.44,27.14 158.77,27.81 157.83,27.81 157.28,27.26 v2(153.85,27.26) ; v2(95.46,96.34) 96.96,97.84 96.96,105.51 102.34,110.89 102.34,112.99 103.41,114.06 103.41,120.28 105.1,121.97 105.1,126.6 109.15,130.65 109.15,143.28 108.58,143.85 108.58,145.49 110.03,146.95 v2(115.6,146.95) ; v2(85.52,72.77) 85.97,73.22 85.97,73.78 88.09,75.9 v2(88.09,76.65)
  IN2 w0.508: v2(53.02,66) 73.92,66 v2(74.22,66.3) ; v2(139.72,24.56) 139.88,24.72 139.88,28.29 v2(139.67,28.51) ; v2(130.85,156.75) 130.78,156.83 120.39,156.83 118.08,154.52 ; v2(95.46,96.34) 98.74,99.61 98.74,99.77 v2(98.72,99.78) ; v2(115.6,146.95) 116.16,146.95 117.89,148.67 117.89,154.33 118.08,154.52 ; 118.08,154.52 118.08,155.11 115.94,157.25 115.94,163.41 113.71,165.64 v2(113.71,169.03) ; v2(153.73,171.53) 154.62,171.53 155.89,172.8 159.03,172.8 160.49,171.34 167.16,171.34 170.74,167.76 170.74,149.93 169.6,148.79 169.6,146.18 169.65,146.13 169.65,145.17 169.35,144.86 167.21,144.86 166.07,143.72 163.71,143.72 v2(162.71,142.72)
  BOTTOM w0.508: v2(95.46,96.34) 94.29,95.17 94.29,93.38 87.65,86.74 87.65,82.88 86.54,81.77 86.54,78.58 88.07,77.06 88.07,76.68 v2(88.09,76.65) ; PR530.2 129.53,147.07 130.26,146.34 v2(131.68,146.34) ; PR510.1 v2(115.6,146.95) ; RA17.1 v2(162.49,27.77) ; v2(139.72,24.56) 130.07,24.56 124.64,19.13 72.7,19.13 69.29,15.72 v2(69.29,12.78) ; v2(139.67,28.51) 141.34,30.18 152.52,30.18 153.85,28.85 v2(153.85,27.26) R2356.2 ; v2(85.52,72.77) 84.91,72.16 83.53,72.16 82.86,72.83 v2(82.86,72.84)
  vias: v2(61.16,19.54) v2(61.17,18.92) v2(61.8,19.54) v2(61.82,18.92) v2(150.2,113.52) v2(150.42,121.62) v2(150.96,121.21) v2(150.99,112.73) v2(154.87,48.18) v2(154.88,47.54) v2(155.49,48.19) v2(155.5,47.56) v2(155.7,96.36) v2(155.71,95.77) v2(157.03,123.62) v2(160.1,77.95) v2(160.13,77.33) v2(160.1,76.73) v2(160.13,76.11) v4(38.51,18.91) v4(60.69,16.77) v4(149.78,119.71)
+3VALW_EC: length 329.2
  TOP w0.508: C1.1 13.75,78.06 U70.2 13.68,78.66 v2(13.39,78.95) ; v2(151.19,150.66) 151.75,150.1 156.88,150.1 v2(157.66,150.88) 159.18,150.88 160.81,149.25 v2(161.28,149.25) v4(165.68,149.25) 166.69,149.25 168.13,147.81 v2(168.13,145.88) ; R1.1 v2(16.95,80.09) ; v2(46.51,80.5) 46.51,80.86 46.99,81.34 63.48,81.34 64.23,80.59 68.17,80.59 68.78,81.2 v2(68.78,84.2) ; C2.1 167.38,169.86 v2(167.15,169.63) 166.49,169.63 166.15,169.29 JPWR.1
  IN1 w0.508: v2(164.88,125.69) 165.54,125.69 168.71,128.86 168.71,139.36 171.16,141.82 171.16,144.2 170.11,145.26 168.57,145.26 168.13,145.7 v2(168.13,145.88) ; v2(144.7,136.56) 144.76,136.49 144.76,134.36 145.43,133.69 v2(145.57,133.69) 145.71,133.55 v2(145.71,130.65) ; v2(13.39,78.95) 15.8,78.95 v2(16.95,80.09)
  IN2 w0.508: v2(46.51,80.5) 45.87,80.5 44.91,79.55 42.3,79.55 40.09,77.34 30.14,77.34 28.8,78.68 25.84,78.68 24.48,77.33 19.72,77.33 v2(16.95,80.09) ; v2(159.95,137.05) 159.09,137.92 159.09,147.15 161.12,149.18 161.22,149.18 v2(161.28,149.25) ; v2(145.57,133.69) 145.1,133.22 140.3,133.22 138.59,131.5 138.59,125.62 136.53,123.57 126.04,123.57 v2(125.95,123.48) ; v2(151.19,150.66) 150.3,150.66 147.31,147.67 147.31,145.16 v2(147.17,145.02) 146.58,144.42 146.58,141.08 144.7,139.2 v2(144.7,136.56) ; v2(167.15,169.63) 168.8,167.98 169.6,167.98 169.63,167.95 169.65,167.95 170.11,167.49 170.11,150.2 168.13,148.22 v2(168.13,145.88)
  BOTTOM w0.203: UE1.33 166.92,144.77 167.27,145.12 CE1.1 ; CE6.2 160.46,148.72 160.16,148.43 UE1.22 ; UE1.96 151.76,129.95 151.49,129.67 146.69,129.67 v2(145.71,130.65) ; UE1.125 149.14,143.57 148.35,144.36 CE5.2
  BOTTOM w0.508: CE6.2 161.27,149.23 v2(161.28,149.25) ; v2(144.7,136.56) 145.73,136.56 146.16,136.99 R696.2 ; v2(68.78,84.2) 68.78,83.95 69.2,83.54 69.2,79.81 70.69,78.32 78.78,78.32 83.93,83.47 83.93,84.93 92.5,93.49 92.5,120.72 93.53,121.75 96.58,121.75 98.86,119.46 106.9,119.46 107.28,119.08 108.27,119.08 108.49,119.3 121.04,119.3 121.96,120.23 121.96,122.54 122.5,123.07 125.55,123.07 v2(125.95,123.48) ; CE5.2 147.2,144.99 v2(147.17,145.02) ; R488.1 v2(157.66,150.88) ; R697.2 v2(145.57,133.69) ; v2(168.13,145.88) CE1.1
+3VALW_SOC: length 13.8
  TOP w0.305: C1067.1 111.23,95.73 110.69,95.18 v1(110.69,94.86) 110.69,94.43 111.07,94.05 111.17,94.05 111.71,93.51 111.71,93.35 111.96,93.09 112.13,93.09 112.61,92.61 113.63,92.61 114.08,92.16 114.08,92.04 v2(114.62,91.5) 114.62,91.34 114.41,91.14 114.41,90.81 115,90.23 115.9,90.23 v2(115.97,90.17)
  TOP w0.508: C1067.1 C1063.1 C1065.1 111.17,98.19 R1022.2
  BOTTOM w0.254: v2(115.97,90.17) 116.12,90.01 USOC1.N22
+3VALWP: length 110.1
  TOP w0.254: v2(36.99,51.85) 37.17,51.67 PR100.1
  TOP w0.508: v2(33.65,48.89) PR106.1
  IN2 w0.254: v2(36.99,51.85) 37.8,52.66 48.06,52.66 51.24,49.49 51.24,45.17 51.87,44.53 51.87,33.18 49.26,30.56 37.39,30.56 v2(35.87,29.04) ; v2(33.65,48.89) 34.47,49.72 34.47,51.14 36.51,53.17 48.19,53.17 51.62,49.74 51.62,45.42 52.25,44.79 52.25,32.61 49.61,29.97 37.69,29.97 36,28.28 v2(35.87,28.28)
  BOTTOM w0.254: v2(36.99,51.85) 37.17,51.67 PR100.1
  vias: v1(37.52,29.26) v2(35.81,25.93) v2(36.63,25.93) v2(37.01,26.63) v2(37.39,25.93) v2(38.16,25.93) v2(38.54,26.63)
+3VLP: length 331.5
  TOP w0.203: PU100.3 38.3,49.51 v2(38.31,49.53)
  TOP w0.254: PC105.1 v2(38.31,49.53)
  TOP w0.508: v2(53.09,7.81) 44.3,7.81 33.32,18.79 32.26,18.79 31.67,19.39 29.11,19.39 28.7,19.8 28.7,22.23 28.7,22.23 28.7,22.59 28.7,23.14 28.7,23.14 v4(28.7,31.77) 27.41,33.05 v2(27.41,33.56) ; v2(169.56,172.12) 169.31,171.86 RE49.2
  IN1 w0.508: v2(37.71,62.53) 37.69,62.53 37.69,50.78 38.31,50.16 v2(38.31,49.53) 37.64,48.85 36.7,48.85 35.74,49.8 27.68,49.8 25.84,47.96 25.84,45.8 25.33,45.3 25.33,43.52 24.82,43.01 24.82,34.76 26.09,33.49 27.34,33.49 v2(27.41,33.56)
  IN2 w0.508: 162.46,128.39 163.23,127.63 163.23,124.29 162.49,123.55 162.49,120.92 163.51,119.91 166.62,119.91 168.53,118 168.53,105.89 171.23,103.19 171.23,93.98 170.26,93.01 170.26,75.6 v2(169.04,74.38) ; 162.64,139.12 162.64,141.4 163.56,142.31 166.86,142.31 168,143.45 169.32,143.45 171.38,145.51 171.38,171.23 170.49,172.12 v2(169.56,172.12)
  BOTTOM w0.508: v2(169.04,74.38) 168.09,74.38 166.85,73.13 164.82,73.13 159.77,68.09 153.53,68.09 150.56,65.12 148.46,65.12 139.44,65.12 139.44,65.12 139.25,65.12 139.25,65.12 138.51,65.12 138.51,65.12 138.4,65.12 138.21,65.12 134.57,61.48 103.15,61.48 101.49,63.14 100.71,63.14 84.55,63.14 82.52,65.17 82.47,65.17 81.93,65.17 81.93,65.17 77.27,65.17 76.9,64.8 68.78,64.8 66.9,62.92 53.83,62.92 53.82,62.92 53.26,62.92 46.93,62.92 45.97,61.96 38.28,61.96 v2(37.71,62.53)
  vias: v2(161.5,128.65) v2(161.49,128.02) v2(162.68,138.5) v2(162.7,137.84)
+3VS: length 529.4
  TOP w0.254: C2498.1 98.3,112.35 98.97,112.35 99.24,112.08 U2407.1
  TOP w0.381: RC53.1 113.68,113.24 113.21,113.24 112.2,112.23 111.27,112.23 ; 106.37,118.45 105.2,117.28 105.2,115.78 106.22,114.77 108.25,114.77 109.77,113.24 110.25,113.24 111.27,112.23 ; 111.27,112.23 v2(111.27,112.17)
  TOP w0.406: R122.1 21.52,71 Q14.5
  TOP w0.508: R11.2 82.87,71.19 v2(82.48,71.59) ; 106.37,118.45 v2(106.37,118.6) 106.37,119.36 107.36,120.35 107.89,120.35 108,120.24 110.04,120.24 110.94,119.34 115.38,119.34 115.76,118.96 122.74,118.96 127.88,113.81 132.14,113.81 133.66,112.29 ; v2(142.32,24.37) 141.92,24.37 140.44,22.89 140.44,22.74 139.25,21.55 v2(139.25,20.53) ; v2(88.82,80.87) 89.06,81.11 R9.2 ; Q6103.2 v2(35.26,15.21) ; R122.1 v2(23.48,71.25) ; v2(23.48,72.7) 22.56,73.62 v4(20.45,73.62) 18.6,73.62 17.84,72.85 RX12.1 ; C2498.1 97.19,111.89 96.75,111.46 v2(96.67,111.46) ; v2(139.17,116.29) 138.49,115.61 138.49,115.27 135.43,112.21 ; v2(142.04,117.81) 142.04,117.95 141.65,118.35 141.04,118.35 140.62,117.93 140.62,114.47 141.55,113.55 141.55,109.42 145.61,105.35 145.61,104.98 146.26,104.33 146.26,100.05 143.57,97.36 v2(143.57,96.1) 143.57,95.97 145.22,94.32 145.22,90.08 145.32,89.97 145.32,86.15 147.37,84.1 147.37,75.02 147.76,74.64 147.76,70.69 148.77,69.67 148.77,67.31 147.84,66.38 145.35,66.38 141.73,62.76 141.73,51.9 139.88,50.06 139.88,44.8 138.84,43.76 138.84,37.78 136.84,35.77 136.84,28.23 134.31,25.7 v2(133.28,25.7) 131.06,27.92 CD62.1 131.32,30.58 CD31.1 CD47.1 CD30.1 131.37,33.49 131.73,33.84 131.73,35.22 v2(131.13,35.82) ; v2(109.28,111.34) 108.77,110.83 R2451.1 R2448.1 ; v2(108.13,112.1) 107.88,111.84 R2449.1 ; RC20.1 90.11,69.55 90.07,69.59 90.07,69.6 89.72,69.96 89.71,69.96 89.67,70 89.67,70.37 89.15,70.89 v2(88.89,70.89) ; v2(148.9,151.2) 149.69,151.2 151.43,149.46 157.18,149.46 157.77,150.05 v2(158.7,150.05)
  IN1 w0.508: v2(147.42,13.36) 148.75,14.69 150.17,14.69 151.19,15.71 154.23,15.71 155.45,14.49 v2(155.72,14.49) ; v2(93.24,80.67) 93.03,80.87 v2(88.82,80.87) ; v2(156.14,136.86) 156.14,136.38 155.63,135.87 155.63,131.39 154.9,130.66 154.9,127.12 v2(154.78,127.01) ; v2(140.77,17.61) 141.28,18.12 141.47,18.12 146.04,22.69 v2(146.61,22.69) 147.12,23.2 147.12,25.48 148.27,26.63 152.08,26.63 152.15,26.7 152.16,26.7 153.99,28.53 159.19,28.53 159.95,27.77 v2(160.71,27.77) ; v2(107.18,165.95) 107.18,171.47 108.13,172.42 149.03,172.42 152.58,168.87 159.57,168.87 161.47,170.77 164.62,170.77 168.45,166.95 168.45,166.06 169.35,165.16 169.35,152.26 168.37,151.28 168.07,151.28 167.72,150.93 167.72,150.91 167.67,150.86 167.65,150.86 167.61,150.82 163.52,150.82 162.75,150.05 v2(158.7,150.05) ; v2(100.77,145.52) 100.77,147.75 99.41,149.11 99.41,153.47 v2(100.2,154.27) 100.2,154.66 97.57,157.29 97.57,159.52 v2(99.6,161.55)
  IN2 w0.508: v2(96.67,111.46) 96.75,111.46 95.61,110.32 v2(95.05,110.32) ; v2(156.14,136.86) 156.6,137.32 156.6,144.56 156.48,144.67 156.48,147.82 158.7,150.04 v2(158.7,150.05) ; v2(88.89,70.89) 89.02,71.02 89.06,71.02 89.46,71.43 89.46,71.71 89.77,72.02 89.77,73.53 93.38,77.13 93.38,80.53 v2(93.24,80.67) ; v2(110.38,160.36) 110.38,160.7 111.69,162.01 111.69,165.34 111.11,165.92 107.21,165.92 v2(107.18,165.95) 106.84,165.95 106.37,165.48 102.69,165.48 101.49,164.27 101.49,163.44 v2(99.6,161.55) ; v2(142.04,117.81) 142.04,117.95 141.73,118.27 140.82,118.27 139.17,116.62 v2(139.17,116.29)
  BOTTOM w0.356: v2(131.13,35.82) 130.99,35.82 130.63,36.19 130.63,36.77 130.8,36.95 JDIMM2.199
  BOTTOM w0.457: v2(110.38,160.36) 109.92,160.36 109.53,159.96 RX27.2
  BOTTOM w0.508: R6110.1 147.97,150.19 147.97,150.76 148.42,151.2 v2(148.9,151.2) ; v2(108.13,112.1) 108.9,111.34 v2(109.28,111.34) 110.17,112.23 111.27,112.23 v2(111.27,112.17) ; v2(88.82,80.87) 88.51,81.17 88.51,86.23 95.37,93.09 95.37,94.47 96.36,95.46 96.36,97.33 94.39,99.3 94.25,99.44 94.25,109.51 v2(95.05,110.32) 94.93,110.32 94.42,110.83 94.42,113.9 99.12,118.6 104.86,118.6 105.47,117.99 106.1,117.99 106.37,118.26 v2(106.37,118.6) ; RA155.2 147.3,22.69 v2(146.61,22.69) ; v2(135.39,99.24) 136.31,99.24 RC68.1 137.29,98.26 139.63,98.26 139.91,97.97 142.44,97.97 143.54,96.87 143.54,96.54 143.57,96.51 v2(143.57,96.1) ; v2(99.6,161.55) 99.75,161.4 RT17.1 ; v2(82.48,71.59) 83.08,71.59 84.03,70.63 85.57,70.63 85.69,70.75 88.75,70.75 v2(88.89,70.89) ; v2(100.2,154.27) UX4.5 101.16,154.27 101.39,154.04 RX10.1 ; v2(154.78,127.01) 155.03,127.26 155.5,127.26 RA54.2 ; RS7.1 v2(169.2,22.35) ; RA1.1 143.59,23.66 142.88,24.37 v2(142.32,24.37) 141.9,24.37 141.53,24.73 RA2.1 141.22,25.15 141.01,25.36 133.62,25.36 v2(133.28,25.7) ; RA18.2 v2(160.71,27.77)
  vias: v2(13.39,25.74) v2(13.39,25.1) v2(14,25.5) v2(53.28,18.96) v2(53.27,18.25) v2(53.82,19.22) v2(53.8,18.6) v2(53.84,17.93) v2(54.48,19.2) v2(54.46,18.6) v2(54.48,17.93) v2(74.48,83.84) v2(75.08,83.85) v2(75.67,83.87) v2(90.62,120.3) v2(91.04,120.98) v2(91.45,120.37) v2(96.56,146.69) v2(96.58,146.1) v2(97.14,146.98) v2(97.14,146.39) v2(162.3,40.53) v2(162.3,39.9) v2(162.68,39.33) v2(162.93,40.53) v2(162.93,39.9)
+3VS_CAM:
  vias: v4(107.4,162)
+3VS_CARD: length 1.7
  BOTTOM w0.102: RR9.1 10.84,22.5 10.38,22.04 v4(10.38,21.34)
+3VS_LCDIN:
  vias: v4(94.04,152.55)
+3VS_OUT: length 0.7
  BOTTOM w0.508: v2(58.35,21.04) C1138.2
  vias: v1(58.53,19.93)
+3VS_SOC: length 19.9
  TOP w0.254: R1023.2 134.44,98.45 134.71,98.72 135.75,98.72 136,98.97 136,99.37 135.64,99.73 135.42,99.97 135.18,100.2 135.18,100.6 v2(135.12,100.67)
  IN2 w0.305: v2(124,95.62) 125.34,95.62 127.38,97.65 127.66,97.65 129.91,99.91 132.52,99.91 133.5,100.89 134.9,100.89 v2(135.12,100.67)
  BOTTOM w0.102: v1(134.55,100.38) 134.83,100.67 v2(135.12,100.67)
  BOTTOM w0.229: USOC1.AN24 v2(124,95.62) 124.53,95.08 125.05,95.08 USOC1.AN27
+3VS_TP: length 23.1
  TOP w0.508: RE10.1 55.15,77.54 55.15,76.92 v2(55.12,76.89) 57.97,76.89 v2(58.32,76.54) RE28.1 ; v2(60.45,69.4) 59.71,68.66 RE26.2 ; v2(55.3,79.65) 54.97,79.32 RE9.1
  IN2 w0.508: v2(61.02,71.6) 59.68,72.93 59.68,75.18 v2(58.32,76.54)
  BOTTOM w0.508: v2(60.45,69.4) 61.14,69.4 61.42,69.68 61.42,71.19 v2(61.02,71.6) 60.76,71.34 59.77,71.34 59.37,71.75 RE17.1 ; v2(55.3,79.65) 55.23,79.57 55.23,77 v2(55.12,76.89) ; v2(58.32,76.54) 59.37,75.5 RE19.1
  vias: v4(60.84,73.48)
+3VS_TPIN:
  vias: v4(55.4,69.18)
+3VS_WLAN_NGFF: length 8.8
  TOP w0.508: v2(160.76,48.67) 160.76,48.61 161.16,48.22 163.76,48.22 165.36,49.82 RM110.1
  BOTTOM w0.508: QM30.2 159.9,47.81 v2(160.76,48.67)
  vias: v2(168.71,60.98) v2(169.18,62.18) v2(169.22,61.55) v2(169.35,60.98) v2(169.77,62.19) v2(170.05,43.26) v2(170.05,42.63) v2(170.74,42.63) v4(167.28,60.13) v4(169.37,60.03) v4(171.06,61.6)
+5V_AUDIO: length 20.8
  TOP w1.016: 156.41,9.8 159.31,9.8 160.31,10.79 v4(160.31,12.83) 160.31,20.3 157.54,23.07
  BOTTOM w0.203: 155.42,19.54 155.29,19.41 UA1.26
  BOTTOM w0.254: 155.42,19.54 155.99,20.11 155.99,21.55 156,21.56
  vias: v2(154.55,9.43) v2(154.58,8.8) v2(156.27,23.83) v2(156.27,23.2)
+5V_HDD:
  vias: v2(164.59,32.66) v2(164.59,32.02) v2(164.59,31.39) v2(164.84,33.23) v4(156.18,32.7) v4(162.36,33.21) v4(163.3,31.57) v4(166.34,34.11)
+5V_HUB: length 30.2
  TOP w0.102: v2(150.06,49.26) v4(150.06,48.51)
  TOP w0.508: v2(150.06,49.26) 150.04,49.27 R1046.1
  IN1 w0.508: v2(150.06,49.26) 149.85,49.26 148.89,48.29 v2(146.78,48.29)
  IN2 w0.508: v2(156.97,38.79) 152.98,38.79 152.17,39.61 152.17,44.82 148.19,48.79 147.28,48.79 ; 147.28,48.79 v2(146.78,48.29) ; 147.28,48.79 147.28,53.13 146.82,53.59 v2(146.82,54.76)
  BOTTOM w0.508: R1053.2 v2(156.97,38.79)
+5V_PVDD:
  vias: v4(148.15,12.63)
+5V_USB_PWR1:
  vias: v4(16.27,44.51) v4(16.39,42.76) v4(16.39,41)
+5V_USB_PWR2:
  vias: v2(164.6,36.85) v2(164.61,36.23) v2(165.22,36.84) v2(165.21,36.23) v4(164.55,34.79)
+5VALW: length 199.6
  TOP w0.254: PU700.11 142.73,150.27 v2(143.11,149.89)
  TOP w0.508: PR3.1 109.48,165.06 v2(110.04,165.06) ; Q6101.3 28.52,10.41 Q6102.3 28.52,15.59 v2(27.97,16.14) ; v2(143.86,145.09) 141.98,143.21 141.98,131.39 143.08,130.28 143.08,128.51 148.27,123.32 148.27,120.76 147.35,119.85 147.35,116.82 147.91,116.26 147.91,108.85 150.83,105.93 150.83,104.3 153.63,101.51 153.63,98.55 154.87,97.3 v2(154.87,94.98) ; v2(55.17,45.64) 55.01,45.64 54.55,45.18 PR203.1 ; v2(125.68,159.57) 126.52,158.73 v2(126.52,154.31)
  IN1 w0.508: v2(150.04,95.72) 150.32,95.44 154.41,95.44 v2(154.87,94.98) ; v2(129.41,170.7) 112.62,170.7 110.04,168.12 v2(110.04,165.06) ; v2(134.6,158.91) 133.14,157.45 133.14,147.25 v2(132.47,146.58)
  IN2 w0.508: v2(129.41,170.7) 131.12,168.98 131.12,161.04 131.07,160.99 ; 131.07,160.99 129.22,160.99 128.58,160.36 126.17,160.36 125.68,159.87 v2(125.68,159.57) ; 131.07,160.99 131.73,160.33 133.18,160.33 v2(134.6,158.91) 135.69,157.82 138.61,157.82 139.81,156.62 139.81,151.67 140.52,150.96 142.04,150.96 v2(143.11,149.89) 143.11,145.84 v2(143.86,145.09)
  BOTTOM w0.203: v2(156.84,78.98) 156.56,78.98 156.46,79.08 U12.3
  BOTTOM w0.508: v2(132.47,146.58) 132.47,145.82 130.78,144.13 129.99,144.13 127.98,142.11 PR519.1 124.32,141.64 122.62,141.64 122.08,142.18 PR518.2 ; PR209.1 56.33,46.79 v2(55.17,45.64) 55.05,45.51 55.05,40.72 54.08,39.76 54.08,33.75 55.43,32.41 55.43,28.85 v2(55.3,28.72) ; v2(126.52,154.31) 126.52,154 126.82,153.7 PR524.1 ; v2(143.11,149.89) 142.7,150.3 PC715.1 ; v2(27.97,16.14) 27.97,19.78 v2(29.89,21.7) ; R1061.2 150.25,95.92 v2(150.04,95.72)
  vias: v2(25.55,42.76) v2(26.02,44.08) v2(26.04,43.45) v2(26.6,44.05) v2(26.64,43.47) v2(55.3,28.02) v2(55.3,27.33) v2(55.3,26.63) v2(56.06,28.72) v2(56.06,28.02) v2(56.06,27.33) v2(56.06,26.63) v2(56.83,28.72) v2(56.83,28.02) v2(152.04,54.01) v2(152.62,54.01) v2(153.79,44.09) v2(153.79,43.39) v2(154.39,44.09) v2(154.39,43.39) v2(154.87,94.34) v2(155.52,95) v2(155.58,94.31) v2(157.41,78.84) v4(70.06,26.02) v4(83.84,24.34) v4(120.92,23.24)
+5VALWP: length 67.6
  TOP w0.102: v2(39.45,51.87) 39.46,51.87 v1(39.92,52.33)
  TOP w0.203: PU100.14 38.7,44.88 v2(38.98,44.6)
  TOP w0.508: PR101.2 v2(39.45,51.87)
  IN1 w0.254: v2(39.45,51.87) 40.05,52.47 45.21,52.47 52.69,44.99 52.69,31.75 50.92,29.98 v2(50.92,29.48)
  IN1 w0.508: v2(38.98,44.6) 38.98,45.88 39.55,46.44 48.82,46.44 52.11,43.15 52.11,32.01 50.31,30.21 50.31,29.12 50.7,28.72 v2(50.92,28.72)
  BOTTOM w0.508: v2(39.45,51.87) PR101.2
+5VS: length 228.8
  TOP w0.508: Q6104.3 v2(28.47,6.79)
  IN1 w1.016: 90.99,142.58 91.62,143.21 91.62,145.92 93.87,148.16 93.87,168.71 94.93,169.77 94.93,175.33 96.11,176.51 114.33,176.51 114.48,176.36 150.96,176.36 152.73,174.58 165.54,174.58 171.76,168.36 171.76,150.71 168.14,147.09 167.41,147.09 167.22,146.9 163.25,146.9 161.73,145.37
  IN2 w0.508: v2(95.22,138.03) 95.21,138.04 95.21,153.75 96.5,155.05 96.5,158.76 97.03,159.29 103.32,159.29 105.05,157.56 105.05,154.11 v2(105.79,153.37)
  BOTTOM w0.508: v2(95.22,138.03) 92.51,138.03 91.74,138.81 91.74,140.13 ; v2(30.54,17.86) 29.52,16.85 29.52,7.84 v2(28.47,6.79) ; v2(105.79,153.37) 106.92,153.37 107.28,153.73 RX28.2
  BOTTOM w1.016: 170.43,88.1 170.43,88.54 166.83,92.13 166.83,103.08 164.01,105.9 164.01,113.62
  vias: v2(26.46,76.32) v2(27.13,76.33) v2(49.73,22.59) v2(49.73,21.89) v2(49.73,21.25) v2(50.43,22.59) v2(50.43,21.89) v2(50.43,21.25) v2(51.12,22.59) v2(51.12,21.89) v2(51.12,21.25) v2(90.48,141.59) v2(91.12,141.57) v2(139.5,19.83) v2(139.95,19.39) v2(158.86,35.44) v2(158.83,34.86) v2(159.47,35.43) v2(159.45,34.84) v2(161.07,144.22) v2(161.68,144.18) v2(165.25,46.77) v2(165.22,46.19) v2(165.54,118.27) v2(165.56,117.64) v2(165.86,46.76) v2(165.84,46.17) v4(50.5,24.2)
+5VS_ODD:
  vias: v2(164.65,84.62) v2(164.65,84.03) v2(164.65,83.4) v2(164.65,82.76) v4(164.08,84.89) v4(164.08,82.96) v4(164.13,81.21)
+5VS_ODD_R1:
  vias: v4(166.44,87.84)
+5VS_OUT: length 0.9
  BOTTOM w0.508: v2(58.35,23.77) C1139.2
  vias: v1(58.48,24.49)
+5VS_TOUCH: length 23.3
  TOP w0.102: v4(111.93,157.89) 111.93,158.05 v2(111.55,158.43)
  TOP w0.508: v2(111.55,158.43) 111.55,158.55 111.56,158.57 RX42.1
  IN2 w0.508: v2(106.24,147.86) 106.24,147.86 106.61,147.86 111.55,152.8 v2(111.55,158.43)
  BOTTOM w0.508: v2(106.24,147.86) RX39.1 RX40.1 ; RX30.1 110.95,154.26 111.63,154.94 111.63,158.35 v2(111.55,158.43)
+V18R: length 4.6
  TOP w0.254: v2(148.61,143.17) 148.87,143.43 CE16.1 RE21.2
  BOTTOM w0.203: UE1.124 v2(148.61,143.17)
+VCC_3IN1:
  vias: v2(14.76,23.11) v2(14.76,22.51) v2(24.06,18.88) v2(24.06,18.25) v4(24.87,19.11) v4(24.86,17.34) v4(26.65,19.44)
+VCC_LPC:
  vias: v1(153.14,150.72)
+VCC_LPC_SOC: length 8.8
  TOP w0.102: RC102.2 v1(132.06,101.56)
  IN2 w0.508: v2(132.9,98.64) 132.24,98.64 130.97,97.37 130.12,97.37 129.61,96.86 129.61,95.88 128.96,95.23 128.35,95.23 127.95,94.83
  BOTTOM w0.203: USOC1.AM27 v2(124.01,94.55)
B+_3/5V: length 1.7
  BOTTOM w0.508: v2(36.12,42.18) PR111.1
  vias: v4(41.38,42.69)
GND: length 1275.3
  TOP w0.203: U11.8 59.24,21.93 v2(59.11,21.8)
  TOP w0.254: CC19.2 123.94,87.94 v2(123.86,88.02) ; PU700.12 143.23,152.53 v2(143.69,152.99) ; PU700.14 144.23,150.68 v2(144.58,150.33) ; UE4.5 60.65,69.95 v2(60.76,70.06) ; U2407.6 105.32,110.08 v2(105.85,109.56) ; RP66.4 77.77,66.75 v2(77.53,66.51) 77.27,66.76 RP66.3
  TOP w0.305: v2(153.45,79.27) 153.51,79.21 154.36,79.21 154.56,79.4 JODD1.7 155.98,79.4 156.28,79.11 156.28,78.12 156.06,77.91 JODD1.4 ; JDB1.9 v2(35.27,76.5) ; JDB1.3 v2(32.27,76.45) ; JDB1.19 40.27,76.43 v2(40.28,76.42) ; v2(42.98,76.41) 43.27,76.7 JDB1.25 ; JDB1.6 v2(33.77,76.49)
  TOP w0.356: PQ710.1 131.52,163.26 v2(131.88,162.9) ; v2(136.07,163.03) 135.83,163.26 PQ713.4 ; PQ3.4 132.2,160.22 PR19.1 ; PC934.1 123.05,90.05 123.09,90.05 CC44.2 123.87,90.12 123.87,90.18 v2(123.87,90.19) ; v2(128.07,162.01) 128.57,161.52 PQ3.1 ; v2(132.38,165.3) PQ709.4 ; PQ4.4 119.58,167.07 119.82,166.84 v2(119.82,166.58) ; v2(128.07,164.93) 128.09,164.93 128.45,164.56 PQ710.4 ; CC39.2 120.08,84.88 C1038.2 119.95,86.18 119.95,87.08 v2(120.08,87.2) ; v2(116.26,168.87) 116.75,168.37 PQ4.1 ; v2(132.02,164.56) PQ713.1 ; v2(133.68,169.23) PQ709.1
  TOP w0.381: UC5.3 95.27,70.08 95.82,69.53 v2(95.89,69.53) ; UC7.3 86.4,73.38 v2(85.44,74.34) ; U68.3 85.98,70.58 v2(85.32,71.24) ; v2(88.85,71.68) 90.13,71.68 90.4,71.41 CC11.2 ; U69.3 94,81.25 v2(93.85,81.1) ; UC10.3 115.81,110.77 v2(116.27,110.31)
  TOP w0.406: Q14.1 v2(20.87,68.9) ; RC45.1 109.56,92.6 109.61,92.54 v2(109.61,92.11) ; C1054.2 C1055.2 123.26,84 122.38,84 v2(122.27,84.11) ; Q14.4 v2(22.17,69.44) ; RC57.2 116.97,99.83 v2(116.73,100.06)
  TOP w0.457: CD41.2 106.09,36.1 106.39,35.8 v2(106.63,35.8) 106.75,35.91 CD36.2
  TOP w0.508: PR105.2 40.39,51.81 v2(40.4,51.82) ; v2(128.07,164.93) 128.02,164.88 PC708.2 ; JDB1.27 v2(28.82,77.44) ; CD34.2 CD5.2 107.16,39.49 v2(107.26,39.59) ; v2(23.93,22.06) 24.2,22.33 JREAD.6 ; PR404.2 v2(41.13,18.38) ; PU400.2 v2(44.95,22.18) ; v2(169.4,167.09) 169.15,167.34 JPWR.4 ; PR19.1 v2(132.52,159.09) ; v2(92.17,32.3) 92.02,32.15 CD12.2 ; C2318.2 64.7,16.85 v2(64.45,17.1) ; PC210.1 56.97,44.22 v2(56.95,44.2) ; CC29.1 131.91,83.06 v2(131.59,82.74) ; v2(157.46,118.32) 157.47,118.33 JKB.32 ; v2(55.76,44.23) PC213.2 ; JKB.31 159.06,90.47 159.06,91.73 v2(159.07,91.74) ; v2(20.46,1.6) 20.06,2 LED1.3 ; v2(110.36,157.84) 110.03,157.51 RX23.2 ; D25.1 162.21,41.68 162.4,41.49 v2(162.74,41.49) ; v2(128.59,88.27) 127.27,86.96 CC2.2 ; v2(110.51,159.67) 110.08,159.67 R3405.2 ; v2(97.87,73.06) 97.8,73.13 97.8,73.62 R1024.2 ; CE26.2 152.33,138.51 v2(151.82,139.02) ; v2(44.89,18.18) PR403.2 PC404.2 ; JODD1.22 v2(160.9,72.88) ; CD8.2 92.18,40.13 v2(92.22,40.17) ; v2(65.91,18.05) 65.91,19.2 65.72,19.39 C1143.1 ; v2(119.06,120.1) PC913.1 ; DE3.1 56.76,79.08 v2(56.61,79.23) ; PC5.2 162.07,172.19 v2(161.78,172.49) ; v2(52.98,51.11) PC215.2 ; PH1.2 134.68,93.79 v2(133.89,93) ; C2498.2 97.85,113.27 98.28,113.7 v2(98.63,113.7) ; PQ2.3 107.99,167.23 v2(108.26,166.96) ; RC41.1 C1035.1 106.86,90.76 106.24,90.14 106.24,89.67 v2(106.23,89.66) ; v2(153.87,145.09) 153.64,145.32 CE27.2 ; CC41.2 122.84,85.94 v2(122.72,85.82) ; v2(108.44,168.61) PR5.1 ; PC7.2 147.19,139.03 147.19,139.67 147.01,139.85 v2(147,139.85) ; v2(53.33,21.48) C2308.2 ; PC727.2 v2(135.69,149.55) ; CD37.2 CD38.2 ; 152.33,155.02 PC716.2 ; CC50.2 CC52.2 v2(31.68,81.1) ; v2(133.47,133.48) PH502.1 ; v2(126.8,159.6) 126.47,159.93 PC8.2 PR21.2 ; CC43.2 114.57,101.58 v2(113.83,102.32) ; RC42.1 110.11,91.61 v2(109.61,92.11) ; Q9.3 v2(109.51,162.16) ; v2(65.73,71.19) 65.77,71.15 JTP.9 ; v2(36.21,51.8) 36.23,51.79 PR104.1 ; v2(112.1,92.39) 112.1,92.33 111.72,91.94 111.72,91.49 C1060.1 ; SW2.6 v2(38.01,10.23) ; JIO1.26 169.35,46.42 v2(169.79,45.98) ; v2(44.13,53.81) PR116.2 ; RC23.1 v2(114.37,95.61) ; JREAD.15 v2(21.18,5.4) ; v2(123.62,109.94) 123.35,109.94 123.16,110.13 123.16,110.59 RC48.2 ; v2(116.1,149.09) 116.68,149.09 PC512.2 ; CC56.2 40.32,80.87 v2(40.05,81.14) ; v2(33.24,80.94) 33.2,80.91 CC54.2 ; JREAD.3 v2(24.05,14.82) ; CE16.2 v2(151.54,141.73) ; v2(136.49,87.92) 136.07,87.51 CC31.1 ; v2(156.01,171.79) 156.01,171.98 PD2.1 ; v2(136.47,166.98) PQ708.3 ; v2(90.25,168.91) 89.8,168.45 PJPDC1.8 ; v2(162.43,88.73) 161.75,88.05 JODD1.21 ; PR729.1 136.38,151.53 v2(136.51,151.4) PR728.1 ; v2(91,31.19) 91.31,30.88 CD11.2 91.6,30.39 CD13.2 ; PC723.2 v2(137.32,148.71) ; v2(91.22,154.58) PC3.2 PC4.2 ; CD2.2 70.23,40.04 69.86,40.4 v2(69.01,40.4) ; CD2.2 CD1.2 ; CD2.2 C1076.2 ; v2(16.44,77.17) 16.14,77.48 C1.2 ; PR20.2 147.35,133.54 148.51,133.54 v2(148.61,133.43) ; v2(118.04,134.32) 118.24,134.53 PH501.1 ; PQ712.3 135.96,170.66 v2(135.44,170.14) ; v2(124.29,102.7) 124.44,102.84 RC50.1 ; CC57.2 v2(34.22,78.65) ; C979.1 C1144.1 C980.2 67.37,21.42 v2(68.26,20.53) ; v2(53.22,53.22) PR206.2 ; v2(135.37,102.11) 135.34,102.14 C1075.2 ; R1033.2 93.93,84.41 93.98,84.46 94.2,84.46 v2(94.63,84.89) ; QC1.3 137.52,111.84 v2(136.33,111.84) ; v2(159.7,142.07) CE35.2 ; PC405.2 v2(46.55,25.18) ; PC519.2 120.74,141.4 v2(121.34,140.8) ; v2(58.68,73.31) 59.42,72.58 CE59.2 ; v2(45.36,81.08) 45.36,81.15 45.4,81.11 CC65.2 CC63.2 ; v2(115.25,120.29) PC928.1 ; U70.1 v2(10.34,79.08) ; v2(59.29,25.74) C2306.2 ; v2(111.42,84.2) 111.66,83.95 CC13.2 ; PC725.1 139.63,150.03 v2(139.83,150.24) ; v2(104.87,166.79) 105.02,166.95 PJPDC1.7 ; v2(157.28,171.79) 157.28,173.19 158.11,174.01 PD1.1 ; CD4.2 91.26,26 v2(91.27,26.02) CD7.2 ; CI14.2 25.89,41.79 v2(25.71,41.61) ; PR716.2 v2(143.87,147.98) ; v2(120.33,120.1) PC916.1 ; v2(43.01,49.19) 42.97,49.16 PR117.2 ; v2(134.12,89.61) 134.13,89.62 CC33.2 ; EC6104.2 v2(26.23,3.6) ; JIO1.25 v2(171.25,18.59) ; v2(169.57,54.02) 169.68,54.13 RM11.1 ; v2(123.86,88.02) 123.35,88.53 C1040.2 ; v2(38.45,51) 38.31,51.14 PC105.2 ; v2(56.97,54.8) PC212.2 ; SW2.1 v2(33.64,12.22) ; PC403.2 v2(49.08,20.34) ; v2(20.2,69.81) 20.2,69.58 R121.2 ; C1039.1 C1074.2 113.6,93.77 v2(113.57,93.73) ; v2(90.35,162) PC1.2 PC2.2 ; v2(52.98,49.21) PC214.2 ; PC726.2 v2(146.87,149.31) ; JDB1.28 v2(46.22,77.33) ; v2(164.88,165.56) 164.62,165.3 JPWR.5 ; LE2.1 167.01,135.9 v2(167.13,135.78) ; v2(38.28,81.14) CC51.2 CC53.2 ; C1045.2 114.12,90.2 114.01,90.09 113.48,90.09 v2(113.34,90.23) ; C2316.2 64.57,18.12 v2(64.45,17.99) ; CE60.2 v2(62.03,69.48) ; D26.1 v2(157.98,37.61) ; SW2.2 v2(32.91,6.77) ; v2(117.79,120.1) PC914.1 ; C1121.2 151.06,49.58 150.76,49.27 v2(150.76,49.31) ; PC400.1 v2(44.82,23.58) ; v2(129.45,83.4) 129.91,83.86 RC5.1 RC3.1 RC4.1 RC1.1 RC2.1 ; CD40.2 v2(110.7,25.13) ; v2(59.28,24.47) C2305.2 ; CD39.2 v2(109.8,25.17) ; v2(53.33,20.34) C2323.2 ; CD14.2 v2(111.77,26.03) ; CC59.2 CC61.2 v2(43.36,81.14) ; v2(163.05,133.74) PC10.2 PR35.2 ; CC49.2 v2(37.27,78.76) ; C2324.2 v2(51.24,19.64) ; v2(116.52,120.1) PC915.1 ; Q8.3 165.27,70.24 165.49,70.46 165.66,70.46 v2(165.64,70.48) ; R1030.1 C1078.2 112.45,27.64 v2(112.52,27.58) ; R122.2 v2(22.49,72.17) ; CS10.2 152.75,80.91 CS11.2 v2(152.75,82.39) ; PC402.2 v2(45.78,17.61) ; v2(115.5,169.38) PC9.2 ; v2(113.21,120.29) PC926.1 ; SW2.5 v2(32.97,7.97) ; v2(114.23,120.29) PC927.1 ; PC523.2 v2(125.04,154.12) ; v2(122.23,166.71) PR26.2 ; v2(63.72,74.71) 63.72,75.15 63.43,75.44 JTP.4 ; v2(159.05,167.07) PQ711.3 ; PC534.2 v2(131.81,149) ; LED2.1 v2(25.42,1.3)
  VCC w0.203: 101.03,80.08 H11.1 ; H11.1 102.55,79.52 ; H11.1 101.03,83.12 ; H11.1 104.63,81.6 ; H11.1 104.07,80.08 ; H11.1 100.47,81.6 ; H11.1 102.55,83.68 ; H11.1 104.07,83.12 ; 151.42,179.6 PBATT1.1 ; PBATT1.1 153.38,179.6 ; PBATT1.1 153.14,178.86 ; PBATT1.1 152.4,180.58 ; PBATT1.1 151.66,180.34 ; PBATT1.1 152.4,178.62 ; PBATT1.1 153.14,180.34 ; PBATT1.1 151.66,178.86 ; 152.83,62.22 H4.1 ; H4.1 152.32,60.8 ; H4.1 152.83,59.38 ; H4.1 155.67,62.22 ; H4.1 154.25,58.87 ; H4.1 155.67,59.38 ; H4.1 156.18,60.8 ; H4.1 154.25,62.73 ; 10.2,53.52 JHDMI1.22 ; JHDMI1.22 11.38,55.08 ; JHDMI1.22 9.02,55.08 ; JHDMI1.22 10.2,55.08 ; JHDMI1.22 11.38,54.3 ; JHDMI1.22 9.02,53.52 ; JHDMI1.22 9.02,54.3 ; JHDMI1.22 11.38,53.52 ; 168.65,177.69 PBATT1.9 ; PBATT1.9 170.4,177.69 ; PBATT1.9 170.4,179.6 ; PBATT1.9 169.52,177.69 ; PBATT1.9 168.65,179.6 ; 9.32,62.55 JHDMI1.5 ; JHDMI1.5 9.44,63.01 ; JHDMI1.5 10.36,63.01 ; JHDMI1.5 10.48,62.55 ; JHDMI1.5 10.36,62.09 ; JHDMI1.5 9.44,62.09 ; PBATT1.10 150.15,179.6 ; PBATT1.10 148.4,177.69 ; PBATT1.10 148.4,179.6 ; PBATT1.10 150.15,177.69 ; PBATT1.10 149.28,177.69 ; 13.6,2.82 JREAD.14 ; JREAD.14 11.47,4.38 ; JREAD.14 15.73,3.6 ; JREAD.14 11.47,3.6 ; JREAD.14 13.6,4.38 ; JREAD.14 15.73,4.38 ; JREAD.14 15.73,2.82 ; JREAD.14 11.47,2.82 ; H3.1 22.58,50.6 ; H3.1 18.72,50.6 ; H3.1 22.07,52.02 ; H3.1 19.23,49.18 ; H3.1 22.07,49.18 ; H3.1 20.65,48.67 ; H3.1 20.65,52.53 ; H3.1 19.23,52.02 ; JUSB1.10 14.07,47.03 ; JUSB1.10 15.75,47.03 ; JUSB1.10 15.75,46.2 ; JUSB1.10 14.07,45.37 ; JUSB1.10 15.75,45.37 ; JUSB1.7 13.32,40.63 ; JUSB1.7 12.68,39.17 ; JUSB1.7 12.68,40.44 ; JUSB1.7 13.95,40.44 ; JUSB1.7 13.32,38.97 ; JUSB1.7 12.49,39.8 ; JUSB1.7 13.95,39.17 ; JUSB1.7 14.15,39.8 ; 14.82,35.47 JUSB1.4 ; JUSB1.4 15.45,36.94 ; JUSB1.4 15.45,35.67 ; JUSB1.4 15.65,36.3 ; JUSB1.4 14.82,37.13 ; JUSB1.4 14.18,36.94 ; 9.44,68.09 JHDMI1.17 ; JHDMI1.17 9.32,68.55 ; JHDMI1.17 10.36,68.09 ; JHDMI1.17 10.36,69.01 ; JHDMI1.17 9.44,69.01 ; JHDMI1.17 10.48,68.55 ; H9.1 98.07,129.72 ; H9.1 98.07,126.88 ; H9.1 95.23,126.88 ; H9.1 94.72,128.3 ; H9.1 98.58,128.3 ; H9.1 95.23,129.72 ; H9.1 96.65,126.37 ; H9.1 96.65,130.23 ; 156.4,178.62 PBATT1.3 ; PBATT1.3 156.4,180.58 ; PBATT1.3 157.14,180.34 ; PBATT1.3 155.66,180.34 ; PBATT1.3 157.14,178.86 ; PBATT1.3 155.66,178.86 ; PBATT1.3 155.42,179.6 ; H5.1 141.35,104.58 ; H5.1 139.83,104.02 ; H5.1 143.43,102.5 ; H5.1 142.87,104.02 ; H5.1 142.87,100.98 ; H5.1 139.83,100.98 ; H5.1 141.35,100.42 ; H5.1 139.27,102.5 ; 0.68,76.63 JHDMI1.20 ; JHDMI1.20 2.2,75.07 ; JHDMI1.20 3.72,75.85 ; JHDMI1.20 2.2,76.63 ; JHDMI1.20 3.72,75.07 ; JHDMI1.20 3.72,76.63 ; JHDMI1.20 0.68,75.85 ; H6.1 142.87,83.12 ; H6.1 139.27,81.6 ; H6.1 139.83,83.12 ; H6.1 141.35,83.68 ; H6.1 139.83,80.08 ; H6.1 143.43,81.6 ; H6.1 142.87,80.08 ; H6.1 141.35,79.52 ; 11.47,29.8 JREAD.13 ; JREAD.13 15.73,29.02 ; JREAD.13 15.73,29.8 ; JREAD.13 11.47,29.02 ; JREAD.13 15.73,30.58 ; JREAD.13 13.6,29.02 ; JREAD.13 11.47,30.58 ; JREAD.13 13.6,30.58 ; 0.68,54.25 JHDMI1.23 ; JHDMI1.23 3.72,55.03 ; JHDMI1.23 3.72,53.47 ; JHDMI1.23 0.68,53.47 ; JHDMI1.23 2.2,55.03 ; JHDMI1.23 3.72,54.25 ; JHDMI1.23 2.2,53.47 ; H10.1 171.07,11.18 ; H10.1 167.72,12.6 ; H10.1 171.58,12.6 ; H10.1 169.65,10.67 ; H10.1 171.07,14.02 ; H10.1 169.65,14.53 ; H10.1 168.23,11.18 ; H10.1 168.23,14.02 ; PBATT1.2 154.4,180.58 ; PBATT1.2 153.66,178.86 ; PBATT1.2 155.38,179.6 ; PBATT1.2 155.14,178.86 ; PBATT1.2 155.14,180.34 ; PBATT1.2 153.66,180.34 ; PBATT1.2 153.42,179.6 ; PBATT1.2 154.4,178.62 ; 10.99,63.59 JHDMI1.8 ; JHDMI1.8 11.91,64.51 ; JHDMI1.8 10.87,64.05 ; JHDMI1.8 12.03,64.05 ; JHDMI1.8 11.91,63.59 ; JHDMI1.8 10.99,64.51 ; 100.47,102.5 H12.1 ; H12.1 101.03,100.98 ; H12.1 104.07,100.98 ; H12.1 102.55,104.58 ; H12.1 104.07,104.02 ; H12.1 102.55,100.42 ; H12.1 101.03,104.02 ; H12.1 104.63,102.5 ; JUSB1.11 14.07,34.23 ; JUSB1.11 14.07,32.57 ; JUSB1.11 15.75,33.4 ; JUSB1.11 15.75,34.23 ; JUSB1.11 15.75,32.57 ; 142.05,163.57 H1.1 ; H1.1 144.08,165.6 ; H1.1 140.02,165.6 ; H1.1 143.54,164.11 ; H1.1 140.56,164.11 ; H1.1 142.05,167.63 ; H1.1 140.56,167.09 ; H1.1 143.54,167.09 ; 4.34,48.48 JUSB1.13 ; JUSB1.13 5.62,48.48 ; JUSB1.13 6.9,47.65 ; JUSB1.13 6.9,48.48 ; JUSB1.13 4.34,47.65 ; JUSB1.12 6.9,31.95 ; JUSB1.12 4.34,31.12 ; JUSB1.12 6.9,31.12 ; JUSB1.12 5.62,31.12 ; JUSB1.12 4.34,31.95 ; JHDMI1.21 10.2,76.58 ; JHDMI1.21 11.38,76.58 ; JHDMI1.21 10.2,75.02 ; JHDMI1.21 9.02,75.8 ; JHDMI1.21 11.38,75.8 ; JHDMI1.21 9.02,76.58 ; JHDMI1.21 11.38,75.02 ; JHDMI1.21 9.02,75.02 ; JHDMI1.11 10.48,65.55 ; JHDMI1.11 9.44,66.01 ; JHDMI1.11 9.44,65.09 ; JHDMI1.11 10.36,65.09 ; JHDMI1.11 9.32,65.55 ; JHDMI1.11 10.36,66.01 ; JHDMI1.2 11.91,60.59 ; JHDMI1.2 10.99,60.59 ; JHDMI1.2 12.03,61.05 ; JHDMI1.2 11.45,60.47 ; JHDMI1.2 10.99,61.51 ; JHDMI1.2 10.87,61.05 ; JHDMI1.2 11.91,61.51
  GND w0.203: JUSB1.11 15.75,34.23 ; JUSB1.11 15.75,33.4 ; JUSB1.11 14.07,32.57 ; JUSB1.11 15.75,32.57 ; JUSB1.11 14.07,34.23 ; 12.68,40.44 JUSB1.7 ; JUSB1.7 13.95,39.17 ; JUSB1.7 13.32,40.63 ; JUSB1.7 14.15,39.8 ; JUSB1.7 13.95,40.44 ; JUSB1.7 13.32,38.97 ; JUSB1.7 12.49,39.8 ; JUSB1.7 12.68,39.17 ; 100.47,102.5 H12.1 ; H12.1 102.55,100.42 ; H12.1 104.07,100.98 ; H12.1 104.07,104.02 ; H12.1 101.03,100.98 ; H12.1 104.63,102.5 ; H12.1 101.03,104.02 ; H12.1 102.55,104.58 ; JHDMI1.8 11.91,64.51 ; JHDMI1.8 10.99,63.59 ; JHDMI1.8 10.99,64.51 ; JHDMI1.8 12.03,64.05 ; JHDMI1.8 11.91,63.59 ; JHDMI1.8 10.87,64.05 ; JREAD.14 13.6,4.38 ; JREAD.14 11.47,3.6 ; JREAD.14 11.47,4.38 ; JREAD.14 15.73,3.6 ; JREAD.14 15.73,2.82 ; JREAD.14 11.47,2.82 ; JREAD.14 13.6,2.82 ; JREAD.14 15.73,4.38 ; 19.23,49.18 H3.1 ; H3.1 20.65,52.53 ; H3.1 22.58,50.6 ; H3.1 22.07,49.18 ; H3.1 19.23,52.02 ; H3.1 22.07,52.02 ; H3.1 18.72,50.6 ; H3.1 20.65,48.67 ; 0.68,76.63 JHDMI1.20 ; JHDMI1.20 3.72,76.63 ; JHDMI1.20 3.72,75.07 ; JHDMI1.20 3.72,75.85 ; JHDMI1.20 0.68,75.85 ; JHDMI1.20 2.2,75.07 ; JHDMI1.20 2.2,76.63 ; 101.03,83.12 H11.1 ; H11.1 101.03,80.08 ; H11.1 102.55,79.52 ; H11.1 104.07,83.12 ; H11.1 100.47,81.6 ; H11.1 104.07,80.08 ; H11.1 104.63,81.6 ; H11.1 102.55,83.68 ; 5.62,31.12 JUSB1.12 ; JUSB1.12 4.34,31.95 ; JUSB1.12 6.9,31.12 ; JUSB1.12 4.34,31.12 ; JUSB1.12 6.9,31.95 ; JHDMI1.2 12.03,61.05 ; JHDMI1.2 10.99,61.51 ; JHDMI1.2 10.87,61.05 ; JHDMI1.2 11.45,60.47 ; JHDMI1.2 11.91,61.51 ; JHDMI1.2 11.91,60.59 ; JHDMI1.2 10.99,60.59 ; JHDMI1.22 11.38,53.52 ; JHDMI1.22 9.02,53.52 ; JHDMI1.22 10.2,53.52 ; JHDMI1.22 9.02,54.3 ; JHDMI1.22 11.38,55.08 ; JHDMI1.22 10.2,55.08 ; JHDMI1.22 11.38,54.3 ; JHDMI1.22 9.02,55.08 ; JHDMI1.21 11.38,75.02 ; JHDMI1.21 11.38,75.8 ; JHDMI1.21 9.02,75.02 ; JHDMI1.21 10.2,75.02 ; JHDMI1.21 11.38,76.58 ; JHDMI1.21 10.2,76.58 ; JHDMI1.21 9.02,75.8 ; JHDMI1.21 9.02,76.58 ; PBATT1.3 157.14,180.34 ; PBATT1.3 156.4,178.62 ; PBATT1.3 157.14,178.86 ; PBATT1.3 155.66,178.86 ; PBATT1.3 156.4,180.58 ; PBATT1.3 155.66,180.34 ; 169.52,177.69 PBATT1.9 ; PBATT1.9 170.4,179.6 ; PBATT1.9 170.4,177.69 ; PBATT1.9 168.65,179.6 ; PBATT1.9 168.65,177.69 ; 0.68,54.25 JHDMI1.23 ; JHDMI1.23 3.72,54.25 ; JHDMI1.23 2.2,53.47 ; JHDMI1.23 3.72,55.03 ; JHDMI1.23 0.68,53.47 ; JHDMI1.23 3.72,53.47 ; JHDMI1.23 2.2,55.03 ; H6.1 142.87,80.08 ; H6.1 141.35,79.52 ; H6.1 142.87,83.12 ; H6.1 139.83,83.12 ; H6.1 139.83,80.08 ; H6.1 139.27,81.6 ; H6.1 143.43,81.6 ; H6.1 141.35,83.68 ; 9.32,68.55 JHDMI1.17 ; JHDMI1.17 9.44,68.09 ; JHDMI1.17 10.36,68.09 ; JHDMI1.17 9.44,69.01 ; JHDMI1.17 10.48,68.55 ; JHDMI1.17 10.36,69.01 ; JHDMI1.5 10.36,63.01 ; JHDMI1.5 10.36,62.09 ; JHDMI1.5 9.32,62.55 ; JHDMI1.5 9.44,62.09 ; JHDMI1.5 9.44,63.01 ; JHDMI1.5 10.48,62.55 ; 9.44,66.01 JHDMI1.11 ; JHDMI1.11 10.36,66.01 ; JHDMI1.11 10.48,65.55 ; JHDMI1.11 9.32,65.55 ; JHDMI1.11 10.36,65.09 ; JHDMI1.11 9.44,65.09 ; 153.66,178.86 PBATT1.2 ; PBATT1.2 155.14,180.34 ; PBATT1.2 154.4,178.62 ; PBATT1.2 154.4,180.58 ; PBATT1.2 153.66,180.34 ; PBATT1.2 155.14,178.86 ; JREAD.13 15.73,29.8 ; JREAD.13 13.6,29.02 ; JREAD.13 15.73,30.58 ; JREAD.13 13.6,30.58 ; JREAD.13 11.47,29.8 ; JREAD.13 15.73,29.02 ; JREAD.13 11.47,29.02 ; JREAD.13 11.47,30.58 ; H9.1 98.58,128.3 ; H9.1 94.72,128.3 ; H9.1 98.07,129.72 ; H9.1 95.23,129.72 ; H9.1 98.07,126.88 ; H9.1 95.23,126.88 ; H9.1 96.65,126.37 ; H9.1 96.65,130.23 ; 14.18,36.94 JUSB1.4 ; JUSB1.4 14.82,35.47 ; JUSB1.4 15.45,35.67 ; JUSB1.4 15.65,36.3 ; JUSB1.4 14.82,37.13 ; JUSB1.4 15.45,36.94 ; PBATT1.10 150.15,179.6 ; PBATT1.10 148.4,177.69 ; PBATT1.10 148.4,179.6 ; PBATT1.10 149.28,177.69 ; PBATT1.10 150.15,177.69 ; PBATT1.1 153.14,178.86 ; PBATT1.1 151.66,178.86 ; PBATT1.1 152.4,178.62 ; PBATT1.1 153.14,180.34 ; PBATT1.1 151.42,179.6 ; PBATT1.1 152.4,180.58 ; PBATT1.1 151.66,180.34 ; 168.23,14.02 H10.1 ; H10.1 167.72,12.6 ; H10.1 171.58,12.6 ; H10.1 171.07,11.18 ; H10.1 169.65,14.53 ; H10.1 171.07,14.02 ; H10.1 168.23,11.18 ; H10.1 169.65,10.67 ; 139.83,104.02 H5.1 ; H5.1 141.35,104.58 ; H5.1 141.35,100.42 ; H5.1 139.27,102.5 ; H5.1 142.87,100.98 ; H5.1 142.87,104.02 ; H5.1 139.83,100.98 ; H5.1 143.43,102.5 ; H4.1 155.67,59.38 ; H4.1 156.18,60.8 ; H4.1 152.32,60.8 ; H4.1 154.25,58.87 ; H4.1 152.83,62.22 ; H4.1 155.67,62.22 ; H4.1 152.83,59.38 ; H4.1 154.25,62.73 ; 140.56,164.11 H1.1 ; H1.1 143.54,164.11 ; H1.1 142.05,163.57 ; H1.1 142.05,167.63 ; H1.1 144.08,165.6 ; H1.1 143.54,167.09 ; H1.1 140.02,165.6 ; H1.1 140.56,167.09 ; JUSB1.13 6.9,47.65 ; JUSB1.13 4.34,47.65 ; JUSB1.13 6.9,48.48 ; JUSB1.13 5.62,48.48 ; JUSB1.13 4.34,48.48 ; JUSB1.10 15.75,47.03 ; JUSB1.10 14.07,47.03 ; JUSB1.10 15.75,46.2 ; JUSB1.10 15.75,45.37 ; JUSB1.10 14.07,45.37
  BOTTOM w0.102: v2(164.97,74.7) v4(164.05,74.7) ; v4(144.01,143.63) 144,143.62 RE1.1 ; 125.93,151.65 v2(125.93,151.6) ; v4(156.71,125.59) 157.22,125.08 v2(157.22,125.06) ; v2(159.05,167.07) 159.05,167.85 v4(159.05,167.85) ; 61.52,11.63 CA30.2 ; v4(146.87,149.97) v2(146.87,149.31)
  BOTTOM w0.152: USOC1.BJ27 130.48,100.52 130.76,100.52 130.8,100.55 130.88,100.55 131.23,100.91 v2(131.5,100.91)
  BOTTOM w0.203: UE1.94 v2(152.56,129.36) ; v2(155.54,147.7) 155.76,147.47 UE1.11 ; USOC1.A43 118.88,77.92 v2(118.66,77.92) ; v2(160.71,147.91) 160.71,147.62 160.96,147.37 UE1.24 ; UE1.113 151.59,138.77 151.82,139 v2(151.82,139.02) ; USOC1.J16 112.65,90.23 v2(113.34,90.23) ; v2(164.51,143.09) 164.51,143.61 164.87,143.97 UE1.35 ; v2(153.45,79.27) 153.64,79.08 U12.8 ; UA1.4 148.16,16.61 148.01,16.47 v2(146.74,16.47)
  BOTTOM w0.229: USOC1.A27 113.09,83.12 v2(113.01,83.12) ; v2(111.42,84.2) 111.47,84.25 111.47,84.26 111.82,84.61 111.83,84.61 USOC1.A23
  BOTTOM w0.254: v2(129.8,102.31) 129.59,102.1 129.43,102.1 129.11,101.78 USOC1.BJ23 ; USOC1.A47 120.39,76.82 120.29,76.82 119.94,76.47 v2(119.78,76.47) ; USOC1.J53 126.13,76.94 v2(126.49,76.94) ; 125.22,79.09 125.12,79 124.72,79 ; 125.22,79.09 v2(125.22,79.09) ; 125.22,79.09 125.41,79.29 USOC1.M51 126.33,79.29 USOC1.N51 126.52,79.48 USOC1.P52 ; USOC1.AB45 USOC1.AB47 USOC1.AB48 USOC1.AB50 128.87,83.14 USOC1.AB51 129.45,82.9 v2(129.45,83.4) ; v2(107.86,88.69) 107.86,88.88 108.17,89.19 USOC1.A11 ; USOC1.AA53 129.95,81.37 129.95,81.24 v2(130.16,81.03) ; USOC1.A15 109.12,87.82 108.86,87.56 v2(108.86,87.52) ; USOC1.AT12 119.88,101.21 v2(119.82,101.15) ; v2(120.73,95.58) USOC1.AJ21 ; USOC1.E53 124.17,75.77 124.17,74.94 v2(123.92,74.69) ; USOC1.BJ19 128.27,103.8 v2(128.47,103.8) ; v2(126.76,105.11) 126.65,105 126.65,104.92 USOC1.BJ15 ; v2(121.53,77.3) 121.79,77.04 USOC1.C49 ; v2(125.26,106.59) 125.26,106.29 USOC1.BJ11 ; USOC1.Y25 120.04,90.64 v2(120.08,90.68) ; DI1.8 20.57,39.2 v2(20.61,39.16) ; v2(130.92,108.06) 130.71,107.85 130.71,107.81 129.93,107.03 RC60.1 ; USOC1.A35 116.09,80.63 v2(116.09,80.48) ; v2(168.69,144.12) 169.27,144.12 170.07,144.91 PQ10.4 ; v2(120.81,78.39) 120.53,78.1 USOC1.C45 120.08,78.4 120.08,79.02 119.79,79.31 USOC1.C42 ; USOC1.P47 124.94,81.38 v2(124.69,81.13) 124.44,80.88 USOC1.M47 ; USOC1.A19 110.28,85.81 110.14,85.81 110.04,85.71 109.71,85.71 109.61,85.81 109.4,85.81 109.24,85.97 109.24,86.29 v2(109.28,86.33) ; v2(124.06,107.84) 123.57,107.35 USOC1.BJ7 ; USOC1.A49 121.44,75.74 121.21,75.51 v2(121.21,75.37) ; v2(131.59,82.74) 131.33,82.74 USOC1.AE53 ; v2(118.38,107.42) 118.59,107.21 USOC1.BC1 119.29,106.97 USOC1.BC2 ; DI1.3 v2(17.79,39.2)
  BOTTOM w0.305: USOC1.J40 120.81,81.43 120.94,81.29 ; JNGFF.1 162.18,62.85 161.85,63.18 v2(161.85,63.27) ; JEDP.16 99.3,164.3 v2(99.51,164.51) ; JNGFF.25 164.47,54.85 v2(164.69,55.06) ; v2(161.28,47.07) 162.17,47.07 162.45,47.35 JNGFF.55 ; JEDP.23 102.8,164.26 v2(103.1,164.56) 103.3,164.36 JEDP.24 ; v2(162.02,50.48) 162.15,50.35 JNGFF.43 ; JHDD.9 168.34,29.46 v2(168.54,29.27) ; JEDP.19 v2(100.8,164.53) ; JNGFF.37 162.1,51.85 161.91,51.66 v2(161.91,51.6) ; JNGFF.49 v2(162.24,48.85) ; JNGFF.18 v2(169.81,56.6) ; JHDD.12 167.96,27.96 168.71,27.21 v2(168.71,27.15) ; CC8.1 109.71,82.56 v2(109.78,82.63) ; v2(121.73,107.45) 121.41,107.13 USOC1.BF4 ; JEDP.25 v2(103.8,164.55) ; JHDD.6 168.37,30.96 168.6,31.19 v2(168.6,31.24) ; 120.94,81.29 121,81.23 USOC1.G42 ; 120.94,81.29 v2(120.95,81.29) ; JNGFF.10 169.99,58.6 v2(169.73,58.34) ; JNGFF.31 164.28,53.35 164.41,53.22 v2(164.7,53.22) ; v2(162.24,44.28) 162.31,44.35 JNGFF.67 ; v2(105.53,164.76) 105.8,164.49 JEDP.29 ; v2(162.05,45.74) 162.15,45.85 JNGFF.61 ; JEDP.13 v2(97.8,164.56) ; JEDP.36 109.3,163.09 109.15,162.94 109.15,162.52 v2(109.51,162.16) ; v2(161.85,60.14) 161.85,60.65 162.55,61.35 JNGFF.7
  BOTTOM w0.356: JDIMM2.61 87,36.96 v2(88.21,35.75) ; JDIMM2.155 117.6,39.78 117.05,40.33 116.13,40.33 v2(116.12,40.34) ; v2(129.77,36.27) 129.6,36.44 JDIMM2.195 ; JDIMM2.71 90,36.53 v2(90.02,36.5) ; v2(79.66,32.16) 80.27,31.55 80.27,31.08 80.1,30.91 JDIMM2.38 ; JDIMM2.9 71.4,39.01 v2(72.61,40.22) ; v2(78.13,34.25) 79.8,35.92 JDIMM2.37 ; v2(78.13,36.54) 78,36.66 JDIMM2.31 ; v2(124.64,32.09) 124.5,31.94 JDIMM2.178 ; JDIMM2.128 v2(109.5,31.16) ; v2(171.79,142.78) 171.37,143.2 PQ10.1 ; JDIMM2.14 72.9,31.01 v2(72.69,31.22) ; JDIMM2.49 83.4,39.26 v2(83.88,39.73) 84,39.61 84.66,39.61 85.2,39.07 JDIMM2.55 ; v2(126.46,40.34) 127.8,39 JDIMM2.189 ; JDIMM2.48 83.1,31.45 v2(82.5,32.04) ; v2(87.18,28.15) 86.7,28.63 JDIMM2.60 ; v2(116.7,36.54) 116.4,36.84 JDIMM2.151 ; v2(109.31,40.37) 108.77,39.82 108.77,39.34 109.2,38.91 JDIMM2.127 ; JDIMM2.54 v2(84.9,31.17) ; JDIMM2.179 v2(124.8,36.62) ; JDIMM2.185 v2(126.6,36.64) ; v2(110.81,39.96) 111,39.77 JDIMM2.133 ; JDIMM2.72 90.3,30.73 90.76,31.19 v2(91,31.19) ; v2(70.2,33.68) 71.1,32.78 JDIMM2.8 ; JDIMM2.66 88.5,31.63 v2(88.35,31.78) ; v2(112.52,27.58) 112.5,27.6 JDIMM2.138 ; JDIMM2.13 72.6,36.45 v2(72,35.85) ; v2(119.1,31.97) 119.7,31.37 JDIMM2.162 ; v2(114.3,31.16) 114.3,31.16 JDIMM2.144 ; v2(75.4,40.22) 76.2,39.42 JDIMM2.25 ; v2(70.2,32.16) 69.3,31.26 JDIMM2.2 ; v2(87.34,40.22) 88.2,39.36 JDIMM2.65 ; JDIMM2.134 111.3,31.29 v2(110.64,31.95) ; v2(69.26,36.52) 69.6,36.86 JDIMM2.3 ; v2(123.45,31.95) 122.7,31.2 JDIMM2.172 ; JDIMM2.19 v2(74.4,36.17) ; v2(122.22,31.94) 121.63,31.36 121.63,31.1 121.5,30.96 JDIMM2.168 ; v2(116.5,31.31) 116.1,30.91 JDIMM2.150 ; JDIMM2.145 v2(114.6,36.59) ; v2(117.19,32.07) 117.9,31.37 JDIMM2.156 ; v2(129.43,31.95) 130.07,31.31 130.07,31.03 129.9,30.87 JDIMM2.196 ; JDIMM2.167 v2(121.2,36.64) ; v2(81.72,28.28) 81.9,28.46 JDIMM2.44 ; v2(118.74,35.78) 119.4,36.43 JDIMM2.161 ; JDIMM2.43 81.6,39.05 v2(81.08,39.57) ; JDIMM2.139 v2(112.8,36.53) ; JDIMM2.173 v2(123,36.64)
  BOTTOM w0.381: U58.1 152.39,44.36 v2(152.85,43.9) ; QA5.4 142.52,25.09 v2(142.17,25.43)
  BOTTOM w0.457: QA5.1 145.26,26.39 v2(145.38,26.51) ; C1123.1 151.2,76.73 v2(151.64,76.28)
  BOTTOM w0.508: v2(122.84,113.29) 122.97,113.16 122.97,112.99 123.01,112.95 CC12.2 ; v2(132.35,105.29) 131.79,105.29 RC14.2 ; v2(99.12,25.99) 99.12,25.67 CD18.2 ; PC12.2 171.19,142.18 v2(171.79,142.78) ; CC15.2 CC16.2 v2(99.07,90.94) ; v2(109.76,102.62) 109.76,102.84 CC10.2 ; v2(68.26,20.53) 66.24,22.55 CLIP2.1 65.86,22.36 65.86,18.55 v2(65.91,18.05) ; v2(171.19,40) 171.47,39.72 CM6.2 ; v2(145.56,28.65) 145.94,28.65 147.25,27.34 CA1.2 ; v2(161.98,124.54) 162.11,124.42 CE2.2 ; CA31.2 62.24,11.63 61.52,11.63 ; D27.1 18.75,34.63 v2(18.68,34.7) ; v2(145.79,52.31) 145.79,52.4 145.52,52.66 C1118.2 C1117.2 145.47,53.88 C1122.1 ; UI5.2 v2(24.69,43.77) ; v2(100.03,93.9) 100.03,94.48 RC49.1 ; CE1.2 v2(169.04,145.88) ; v2(60.38,20.15) 59.87,20.66 C967.1 ; v2(112.22,79.76) 112.22,79.61 111.88,79.27 111.88,78.33 RC11.2 ; JSPK.5 69.35,10.69 v2(68.89,10.23) ; C1147.2 152.19,83.05 v2(152.75,83.05) ; 113,167.14 113,165.47 v2(113.56,164.92) ; v2(150.42,42.38) 150.36,42.38 150.09,42.64 C1133.2 ; CD17.2 101.4,25.67 v2(101.4,25.99) ; PC533.1 v2(127.16,154.31) ; CA57.2 v2(143.95,12.78) ; v2(144.06,18.4) 144.09,18.37 CA64.1 ; v2(57.66,21.98) C1139.1 ; v2(156.99,41) 156.56,41.44 CI17.2 ; v2(157.92,12.52) 157.93,12.53 CA59.2 ; v2(135.03,43.11) 133.65,43.11 133.45,43.31 JDIMM2.205 ; v2(95.55,134.31) 96.07,134.83 UE3.5 ; CC7.2 136.15,105.44 v2(135.69,104.99) ; C1127.1 150.32,76.93 C1123.1 ; v2(141.76,21.93) 142.02,21.67 RA81.1 ; PC908.2 76.89,22.66 v2(76.88,22.68) ; v2(156.24,94.95) PR411.2 PC415.2 ; CD35.2 v2(106.36,25.1) ; RA32.2 v2(160.2,6.05) ; SW1.1 v2(14.66,13.87) ; v2(103.23,87.92) 103.86,87.92 CC22.2 ; CE36.2 v2(156.65,150.76) ; PC412.2 v2(150.87,91.1) ; RA19.2 v2(144.06,19.64) 144.2,19.78 144.2,20.15 144.58,20.53 CA21.2 CA69.2 ; v2(160.45,104.25) 161.07,104.25 v4(161.75,103.56) 162.24,103.08 PR303.2 PC304.2 ; PR529.2 125.93,151.65 ; v2(166.3,129.88) 165.23,128.81 CE8.2 RE5.1 ; v2(23.04,23.33) 23.25,23.12 CR9.2 ; C1148.2 150.65,71.95 v2(149.99,71.29) ; CC18.2 100.33,88.46 v2(100.77,88.9) ; JEDP.42 v2(90.1,165.3) ; RC7.1 135.09,80.99 v2(134.04,79.94) ; CE23.2 95.38,145.05 v2(95.88,145.55) ; UX1.2 v2(97.35,153.18) ; CR4.1 v2(17.33,16.14) ; C1128.1 158.45,75.93 157.79,75.27 v2(157.54,75.27) ; v2(93.45,72.21) 93.19,71.94 93.19,71.64 93.57,71.25 UC8.4 ; PR534.1 129.48,147.96 PC525.1 129.91,147.94 130.18,147.67 v2(130.52,147.67) ; RX26.2 RX9.2 105,159.98 v2(104.54,160.43) ; CC20.1 94.17,85.36 v2(94.63,84.89) ; v2(96.07,85.94) 96.27,85.74 RC26.2 CC14.2 ; YC1.4 108.19,106.47 v2(108.19,106.33) ; PU300.2 v2(160.57,98.13) ; v2(147.78,53.7) 147.76,53.73 C1119.2 ; CC17.2 98.41,91.34 v2(98.31,91.45) CE31.2 ; v2(40.4,51.82) PR103.2 ; v2(154.41,148.6) 154.36,148.65 CE12.2 ; v2(14.28,20.66) 13.9,21.04 CR1.2 ; v2(27.43,47.58) 26.96,47.11 CI13.2 CI15.2 ; 108.55,104.42 107.79,103.66 v2(107.78,103.66) ; CX6.2 109.49,159.01 110.15,159.67 v2(110.51,159.67) ; CA32.2 65.21,10.64 v2(65.46,10.38) ; SW1.2 v2(20.81,13.87) ; JFAN.4 90.65,150.07 v2(91.21,149.51) ; CA29.2 58.65,11.09 v2(58.43,10.87) ; CX22.2 v2(17.49,76.16) ; v2(60.57,23.83) 60.14,23.4 C976.1 ; v2(79.42,22.65) 79.43,22.64 PC904.2 ; v2(163.82,97.07) 163.82,97.23 PC305.2 ; RE18.2 163.58,150.83 v2(162.62,150.83) ; CX51.2 v2(108.79,154.69) ; UE3.6 94.8,134.39 v2(94.77,134.36) ; v2(168.43,41.74) 168.43,40.93 168.64,40.72 CM7.2 ; CR3.1 v2(12.93,24.34) ; RA29.2 v2(155.89,5.91) ; PR309.2 v2(150.55,120.67) ; v2(72.26,55.06) 71.96,54.77 CLRP1.2 ; CR6.2 v2(22.33,19.77) ; v2(93.02,25.94) 93.02,25.74 92.64,25.36 CD16.2 ; C1126.1 155.35,75.59 v2(155.56,75.79) 155.56,76.03 155.25,76.33 C1146.1 155.2,76.84 U12.11 ; CC21.2 103.97,68.07 103.13,67.23 103.13,65.7 v2(103.61,65.22) ; CX9.2 v2(92.47,154.29) ; RA30.2 v2(158.24,27.2) ; v2(150.12,97.32) 150.37,97.57 C1131.2 ; JDIMM2.206 v2(67.85,49) ; CE6.1 v2(160.46,150.81) ; v2(92.26,137.13) UE3.8 ; RS9.1 166.6,76.9 QS3.3 165.73,76.02 165.73,75.88 164.97,75.12 v2(164.97,74.7) ; v2(161.73,150.69) 162.27,150.15 CE29.2 ; v2(156.29,119.46) 155.84,119.92 PC309.2 PR305.2 ; CE10.2 RE7.1 158.68,126.83 v2(159.19,126.32) ; PR102.1 v2(36.21,51.8) ; RR1.2 v2(11.92,17.41) ; CA2.2 145.98,27.53 v2(145.56,27.95) ; CX49.2 v2(114,162.81) ; v2(111.92,104.41) 111.92,104.77 CC9.2 ; v2(148.93,54.91) 149.03,54.81 C1120.2 ; CD42.2 v2(95.69,25.1) ; v2(102.53,149.11) 101.8,149.11 101.12,149.78 CX7.2 ; v2(69.06,5.06) 69.09,5.09 JSPK.6 ; PC520.2 124.15,153.51 124.75,154.12 v2(125.04,154.12) ; v2(129.83,108.06) CC25.2 ; RA31.2 v2(166.05,18.85) ; CA58.2 v2(144.62,14.05) ; SW1.5 v2(16.82,14.55) ; CC24.1 101.99,72.21 v2(100.29,73.92) ; CD6.2 v2(97.47,25.1) ; UI4.2 v2(158.68,39.71) ; v2(157.92,115.53) PC306.2 ; RC59.2 134.64,102.11 v2(135.37,102.11) ; CE18.1 146.13,138.16 v2(145.32,138.16) ; RX20.2 106.01,157.26 106.62,156.65 v2(106.62,156.56) ; CE32.2 v2(96.46,148.72) ; v2(116.1,149.09) 116.1,148.58 116.82,147.87 PC511.2 117.2,147.96 PR508.2 ; PC519.2 120.74,141.4 v2(121.34,140.8) ; C1059.1 v2(157.63,99.36) ; C1125.1 C1145.1 158.45,82.18 157.94,82.68 v2(156.37,82.68) 155.78,82.68 155.4,82.3 C1124.1 ; R1048.2 v2(143.39,42.04) ; v2(102.1,155.86) 101.86,156.1 UX4.2 ; v2(144,140.6) CE34.2 RE1.1 ; PC502.2 v2(116.41,152.35) ; PC116.2 37.84,41.3 v2(38.16,40.98) ; v2(155.37,42.31) 155.43,42.38 CI26.2 ; v2(105.09,25.99) 104.83,25.74 104.83,25.73 104.58,25.47 CD20.2 ; JNGFF.68 v2(161.92,63.95) ; CR11.2 v2(21.82,13.34) ; CX50.2 113.93,160.1 v2(113.94,160.12) 114.17,159.88 114.17,158.28 113.81,157.92 UX3.2 ; C1132.2 v2(153.04,41.28) ; CE61.1 157.66,124.62 v2(157.22,125.06) ; CS13.2 171.46,83.19 v2(171.89,82.76) ; CD9.2 v2(93.91,25.1) ; v2(38.79,41.04) 39.11,41.36 PC117.2 ; CD33.2 v2(102.8,25.1) ; CA22.2 v2(146.6,15.12) ; v2(25.9,11.32) 25.9,11.53 26.05,11.68 JRTC.2 ; JFAN.3 v2(92.94,149.2) ; PC902.2 v2(80.7,22.69) ; CA60.2 CA25.1 158.12,15.12 157.82,15.43 v2(157.73,15.43) ; CD10.2 v2(108.39,25.1) ; UE3.7 v2(93.53,134.2) ; v2(160.33,28.47) 160.19,28.61 CLIP3.1 161.3,29.58 v2(161.3,28.47) ; Q71.3 160.74,105.27 v2(160.46,104.99) ; Q2308.3 162.25,83.74 v2(162.25,84.75) ; SW1.6 v2(18.74,9.5) ; v2(129.17,108.72) CC26.2 ; PC300.1 v2(160.39,96.69) ; Q70.3 v2(150.02,92.9) ; v2(58.35,18.75) C1138.1 ; JNGFF.69 v2(162.33,43.25) ; CA30.2 v2(61.35,10.97) ; CE28.2 v2(145.66,143.34) ; CC23.2 v2(57.03,7.65) ; CX21.2 v2(16.92,74.89) ; CE5.1 v2(145.6,144.36) ; JFAN.5 v2(90.65,146.88) ; PC906.2 v2(78.16,22.68)
  vias: v2(0.54,76.89) v2(0.51,52.94) v2(3.44,82.28) v2(3.51,74.66) v2(3.77,55.71) v2(4.02,52.41) v2(4.25,54.19) v2(4.48,30.11) v2(5.71,75.2) v2(5.84,49.11) v2(7.5,48.14) v2(7.68,31.45) v2(7.8,73.74) v2(8.57,56.35) v2(8.57,54.12) v2(9.25,27.16) v2(9.25,19.54) v2(9.25,11.92) v2(9.25,4.3) v2(9.33,71.39) v2(9.33,58.38) v2(9.4,0.64) v2(9.77,77.17) v2(10.15,52.92) v2(10.92,29.41) v2(10.99,3.05) v2(11.11,21.04) v2(11.31,82.38) v2(11.59,48.67) v2(11.59,30.95) v2(11.55,9.74) v2(11.74,21.04) v2(11.93,75.52) v2(12.12,54) v2(12.63,1.89) v2(12.76,56.85) v2(12.78,0.52) v2(13.77,47.46) v2(13.99,69.55) v2(14.09,65.24) v2(14.1,27.67) v2(14.61,2.04) v2(15.5,0.52) v2(16.12,65.3) v2(16.97,28.25) v2(17.25,12.12) v2(17.37,21.79) v2(17.37,20.59) v2(18.47,51.33) v2(18.47,41.36) v2(18.54,21.78) v2(18.54,20.53) v2(18.78,82.38) v2(18.79,49.23) v2(19.26,40.83) v2(19.52,71.52) v2(19.61,7.86) v2(20.37,65.3) v2(20.38,59.23) v2(20.41,67.14) v2(20.41,63.2) v2(20.42,61.16) v2(20.4,0.52) v2(20.5,52.92) v2(20.63,48.41) v2(20.71,42.15) v2(20.71,40.57) v2(20.76,35.52) v2(20.88,33.49) v2(20.88,31.25) v2(21.32,27.27) v2(21.39,17.86) v2(21.39,17.23) v2(21.66,29.55) v2(21.62,24.14) v2(21.84,25.79) v2(22.28,79.59) v2(22.66,51.65) v2(22.66,49.68) v2(23.12,0.52) v2(23.5,13.15) v2(23.73,10.5) v2(23.83,8.55) v2(24.21,20.21) v2(25.69,82.38) v2(27.36,39.96) v2(27.55,45.55) v2(27.62,41.93) v2(27.81,37.88) v2(28.06,34.63) v2(29.8,0.52) v2(32.31,46.31) v2(32.89,28.91) v2(32.89,28.15) v2(33.2,33.99) v2(33.31,82.38) v2(33.71,28.91) v2(33.71,28.15) v2(33.97,45.17) v2(34.28,37.23) v2(34.35,38.69) v2(34.35,37.93) v2(34.98,37.93) v2(34.98,37.23) v2(35.05,38.69) v2(35.74,37.93) v2(35.81,38.69) v2(36.23,1.53) v2(36.57,38.69) v2(36.51,37.93) v2(37.88,47.49) v2(37.88,46.65) v2(38.72,47.49) v2(38.72,46.65) v2(39.55,39.58) v2(40.93,82.38) v2(41.1,51.13) v2(41.1,50.49) v2(41.38,38.58) v2(41.4,37.83) v2(42.22,40.34) v2(42.22,39.71) v2(42.22,39.07) v2(42.22,38.37) v2(42.92,40.15) v2(43.62,56.22) v2(43.85,1.53) v2(44.25,28.47) v2(44.32,29.42) v2(44.32,22.18) v2(44.76,57.49) v2(45.01,29.42) v2(45.01,28.47) v2(45.14,45.55) v2(47.94,33.87) v2(48.06,40.6) v2(48.06,37.3) v2(48.55,82.38) v2(51.47,1.53) v2(51.94,25.8) v2(52.57,25.8) v2(53.27,30.95) v2(53.65,31.4) v2(54.03,30.95) v2(54.67,30.95) v2(54.98,36.34) v2(54.98,35.58) v2(54.98,34.31) v2(55.68,34.31) v2(55.75,36.34) v2(55.75,35.58) v2(56.17,82.38) v2(56.51,36.34) v2(56.51,35.58) v2(57.73,50.22) v2(57.73,49.4) v2(58.55,50.22) v2(58.55,49.46) v2(58.55,47.37) v2(58.53,46.72) v2(58.86,70.7) v2(58.87,53.84) v2(58.87,53.21) v2(59.09,1.53) v2(60.25,45.68) v2(60.64,22.82) v2(60.64,21.17) v2(61.52,51.14) v2(62.17,51.18) v2(63.56,40.98) v2(63.68,35.9) v2(65.53,50.88) v2(65.59,50.17) v2(65.89,84.39) v2(66.71,1.53) v2(68.09,84.03) v2(69.61,3.07) v2(70.86,80.92) v2(70.86,80.28) v2(71.56,80.92) v2(71.56,80.28) v2(71.74,1.56) v2(72,34.33) v2(72.04,10.47) v2(72.42,17.28) v2(72.61,41.74) v2(72.69,32.74) v2(74.16,33.68) v2(74.16,32.16) v2(74.58,28.32) v2(75.4,41.74) v2(75.63,33.47) v2(75.63,31.94) v2(76.03,85.45) v2(77.11,31.97) v2(78.52,17.79) v2(79.56,41.74) v2(79.56,40.22) v2(79.66,33.68) v2(81.2,35.22) v2(81.2,33.7) v2(81.2,32.1) v2(83.03,35.59) v2(83.03,33.3) v2(84.03,92.57) v2(84,45.04) v2(84.38,45.55) v2(84.51,35.08) v2(84.51,33.56) v2(84.51,32.03) v2(84.77,46.06) v2(85.15,46.57) v2(86.14,17.79) v2(86.54,33.68) v2(86.54,32.16) v2(87.34,41.74) v2(88.35,34.07) v2(88.45,97.47) v2(88.65,164.22) v2(88.65,156.6) v2(88.65,148.98) v2(88.65,141.36) v2(88.65,133.74) v2(88.65,126.12) v2(88.65,118.5) v2(88.65,110.88) v2(88.65,103.26) v2(89.02,171.56) v2(89.88,33.81) v2(89.88,32.29) v2(90.39,41.74) v2(90.39,40.22) v2(90.49,144.23) v2(90.49,143.47) v2(90.42,138.58) v2(90.56,38.68) v2(90.73,158.41) v2(90.73,157.83) v2(90.72,157.22) v2(90.72,156.64) v2(90.79,133.65) v2(91.03,138.54) v2(91,35.33) v2(92.06,174.61) v2(92.46,34.15) v2(92.64,65.54) v2(93.38,138.64) v2(93.43,143.27) v2(93.76,17.79) v2(94.47,35.42) v2(94.47,33.89) v2(94.47,32.37) v2(94.54,129.12) v2(94.93,126.7) v2(95.07,167.66) v2(95.19,177.58) v2(95.97,71.15) v2(96.09,162.73) v2(96.01,144.1) v2(96.25,162.16) v2(96.39,34.78) v2(96.39,33.26) v2(96.58,130.51) v2(96.58,70.11) v2(96.7,125.94) v2(96.83,76.79) v2(98.24,76.65) v2(98.35,35.81) v2(98.35,34.29) v2(98.35,32.76) v2(98.48,71.33) v2(98.74,127.21) v2(98.86,129.24) v2(98.99,157.36) v2(99.68,156.95) v2(99.8,34.38) v2(99.8,32.86) v2(99.8,31.34) v2(100.26,82.32) v2(100.32,103.46) v2(100.64,100.92) v2(100.77,80.16) v2(101.38,17.79) v2(101.44,32.82) v2(101.9,36.28) v2(101.9,33.99) v2(101.9,31.68) v2(102.42,104.8) v2(102.55,100.1) v2(102.55,83.97) v2(102.67,79.27) v2(102.81,177.59) v2(102.81,35.13) v2(103.98,162.03) v2(103.98,161.41) v2(104.4,35.76) v2(104.4,34.23) v2(104.4,32.71) v2(104.58,162.07) v2(104.58,161.45) v2(104.58,101.3) v2(104.51,82.95) v2(104.58,80.35) v2(104.64,103.59) v2(104.96,94.04) v2(105.23,162.07) v2(105.24,161.46) v2(105.26,91.41) v2(106.22,33.73) v2(106.22,32.71) v2(106.36,142.07) v2(106.36,141.44) v2(106.36,140.8) v2(106.36,140.04) v2(106.36,139.28) v2(106.6,83.76) v2(106.97,82.6) v2(107.56,28.34) v2(107.65,32.02) v2(107.78,98.36) v2(107.75,86.13) v2(107.97,93.59) v2(108.04,35.06) v2(108.39,98.33) v2(108.43,86.11) v2(108.55,93.03) v2(109,17.79) v2(109.11,90.18) v2(109.28,83.65) v2(109.31,41.89) v2(109.6,35.75) v2(110.22,95.57) v2(110.43,177.59) v2(110.5,93.9) v2(110.64,33.47) v2(110.71,71.8) v2(110.81,42.25) v2(111.25,94.57) v2(112.53,100.84) v2(112.88,97.06) v2(112.83,35.27) v2(112.83,33.75) v2(112.83,32.23) v2(113.28,129.62) v2(113.34,130.39) v2(113.4,96.53) v2(113.47,71.99) v2(113.83,96.05) v2(113.88,41.84) v2(113.88,40.32) v2(113.98,129.62) v2(114.04,130.39) v2(114.44,92.72) v2(114.52,81.88) v2(114.67,129.56) v2(114.74,130.32) v2(114.72,98.06) v2(114.71,67.98) v2(114.92,86.29) v2(115.07,33.47) v2(115.07,31.95) v2(115.21,87.95) v2(115.82,69.51) v2(116.12,41.87) v2(116.3,84.85) v2(116.35,100.56) v2(116.42,87.8) v2(116.62,17.79) v2(116.74,105.7) v2(116.83,91.7) v2(116.85,76.16) v2(117.16,95.58) v2(117.11,89.88) v2(117.19,34.36) v2(117.3,133.31) v2(117.3,131.94) v2(117.31,103.54) v2(117.38,79.16) v2(117.46,100.78) v2(117.77,86.37) v2(117.97,94.96) v2(117.99,81.13) v2(118.05,177.59) v2(118.13,97.37) v2(118.51,94.45) v2(119.1,33.57) v2(119.46,105.61) v2(119.67,41.94) v2(119.67,40.42) v2(120,110.22) v2(119.94,105.2) v2(120.01,109.63) v2(120.11,103.51) v2(120.89,104.27) v2(121.06,74.28) v2(121,33.47) v2(121,31.95) v2(121.23,92.85) v2(121.21,41.76) v2(121.21,40.24) v2(122.06,104.58) v2(122.04,99) v2(122.4,149.46) v2(122.46,148.09) v2(122.65,42.25) v2(122.65,39.96) v2(122.79,74.29) v2(122.87,108.77) v2(122.95,72.36) v2(123.12,137.12) v2(123.12,136.48) v2(123.12,135.85) v2(123.45,96.17) v2(123.4,93.97) v2(123.45,33.47) v2(123.56,100.34) v2(123.82,137.12) v2(123.82,136.48) v2(123.82,135.85) v2(123.84,104.88) v2(124.19,148.09) v2(124.23,149.45) v2(124.24,17.79) v2(124.33,137.88) v2(124.45,137.18) v2(124.45,136.55) v2(124.45,135.91) v2(124.49,92.91) v2(124.55,101.33) v2(124.62,72.84) v2(124.67,71.74) v2(124.68,41.87) v2(124.68,40.34) v2(124.77,135.28) v2(124.77,134.64) v2(124.77,134.01) v2(124.77,133.31) v2(124.96,137.94) v2(125.09,137.24) v2(125.09,136.55) v2(125.09,135.91) v2(125.41,135.28) v2(125.47,134.64) v2(125.47,134.01) v2(125.41,133.31) v2(125.6,137.94) v2(125.6,121.94) v2(125.6,121.18) v2(125.67,177.59) v2(125.69,85.65) v2(125.72,137.24) v2(125.72,136.55) v2(125.72,135.85) v2(125.87,100.14) v2(126.02,130.49) v2(126.08,33.47) v2(126.08,31.95) v2(126.1,135.28) v2(126.1,134.64) v2(126.23,137.88) v2(126.36,137.18) v2(126.36,136.55) v2(126.36,135.91) v2(126.31,121.95) v2(126.31,121.19) v2(126.31,100.62) v2(126.46,41.87) v2(126.63,89.68) v2(127.06,137.18) v2(127.06,136.55) v2(127.06,135.91) v2(127.17,90.21) v2(127.42,70.57) v2(127.6,96.32) v2(127.76,137.18) v2(127.76,136.55) v2(127.76,135.91) v2(127.78,33.85) v2(127.78,31.57) v2(128.13,96.81) v2(128.89,96.06) v2(128.96,90.81) v2(129.19,130.21) v2(129.17,97.74) v2(129.43,33.47) v2(129.58,98.2) v2(129.56,91.28) v2(129.54,71.2) v2(129.67,68.23) v2(129.73,88.49) v2(130.23,88.01) v2(130.67,97.97) v2(131.1,34.2) v2(131.12,143.02) v2(131.57,93.32) v2(131.63,80.7) v2(131.76,143.02) v2(131.86,17.79) v2(131.91,181.31) v2(132.13,96.66) v2(132.12,88.85) v2(132.38,79.69) v2(132.4,95.59) v2(132.59,88.35) v2(132.89,93.21) v2(132.88,84.61) v2(132.91,96.06) v2(132.97,90.76) v2(133.26,89.03) v2(133.36,93.71) v2(133.46,95.36) v2(133.65,97.58) v2(133.91,143.4) v2(133.91,142.71) v2(134.26,88.11) v2(134.32,28.74) v2(134.68,143.4) v2(134.68,142.71) v2(134.89,96.78) v2(134.92,92.11) v2(134.98,88.72) v2(135.18,38.55) v2(135.18,36.41) v2(135.18,31.58) v2(135.31,29.55) v2(135.69,35.14) v2(135.82,84.34) v2(135.95,117.18) v2(135.95,116.42) v2(135.95,115.65) v2(135.99,91.69) v2(135.95,17.51) v2(136.56,9.69) v2(136.56,2.07) v2(137.71,93.97) v2(138.4,88.46) v2(138.68,92.91) v2(138.74,120.73) v2(138.74,119.97) v2(138.74,119.21) v2(139.19,103.46) v2(139.19,82.63) v2(139.38,120.73) v2(139.38,119.97) v2(139.38,119.21) v2(139.44,90.43) v2(139.53,181.31) v2(139.5,100.92) v2(139.5,80.09) v2(139.69,166.14) v2(139.77,91.29) v2(140.26,164.04) v2(141.28,104.8) v2(141.28,83.97) v2(141.41,100.1) v2(141.41,79.27) v2(141.89,154.6) v2(141.98,168.04) v2(141.92,153.82) v2(141.92,152.99) v2(142.11,163.15) v2(142.3,1.53) v2(142.55,159.47) v2(143.44,101.3) v2(143.44,80.48) v2(143.5,103.59) v2(143.5,82.76) v2(143.69,154.52) v2(143.69,153.75) v2(144.07,166.84) v2(144.2,164.36) v2(145.47,157.69) v2(146.28,154.29) v2(146.86,18.31) v2(146.93,154.27) v2(147.15,181.31) v2(147.76,154.26) v2(148.14,8.72) v2(148.52,28.02) v2(149.03,31.33) v2(149.28,8.85) v2(149.79,110.5) v2(149.92,1.53) v2(150.18,109.98) v2(150.17,18.79) v2(150.16,17.61) v2(150.12,16.39) v2(150.3,8.72) v2(150.55,178.39) v2(150.55,156.17) v2(150.68,177.25) v2(151.06,96.22) v2(151.19,177.88) v2(151.19,156.17) v2(151.44,61.93) v2(151.57,177.25) v2(151.53,78.51) v2(151.67,18.8) v2(151.65,17.61) v2(151.64,16.4) v2(151.82,156.17) v2(151.82,58.89) v2(152.08,177.88) v2(152.08,9.62) v2(152.13,77.22) v2(152.46,177.25) v2(152.58,156.17) v2(152.84,177.88) v2(152.86,87.03) v2(152.88,86.44) v2(152.88,17.62) v2(152.9,18.79) v2(152.9,16.42) v2(153.09,153.25) v2(153.22,177.25) v2(153.35,156.17) v2(153.47,96.35) v2(153.47,94.45) v2(153.6,177.88) v2(153.6,116.92) v2(153.98,177.25) v2(154.23,116.92) v2(154.22,83.55) v2(154.23,63.97) v2(154.36,177.88) v2(154.36,57.74) v2(154.77,181.31) v2(154.87,177.25) v2(155.25,177.88) v2(155.33,111.98) v2(156.01,111.97) v2(156.25,102.31) v2(156.67,171.53) v2(156.86,102.31) v2(156.97,62.25) v2(156.93,42.59) v2(156.95,38.17) v2(157.03,59.46) v2(157.36,44) v2(157.54,1.53) v2(157.96,50.01) v2(158.38,42.63) v2(158.55,157.31) v2(158.64,86.13) v2(158.81,153.88) v2(159.18,85.59) v2(160.18,55.66) v2(160.66,43.2) v2(160.84,158.58) v2(160.97,35.52) v2(160.97,34.93) v2(160.97,34.35) v2(161.26,43.19) v2(161.42,55.53) v2(162.39,181.31) v2(164.18,91.75) v2(164.18,91.16) v2(165.03,41.31) v2(165.16,44.59) v2(165.16,1.53) v2(165.23,40.59) v2(167.06,164.42) v2(167.06,163.03) v2(167.06,162.39) v2(167.06,161.25) v2(167.06,160.61) v2(167.06,159.47) v2(167.06,158.83) v2(167.25,80.98) v2(167.25,80.35) v2(167.25,35.9) v2(167.44,13.17) v2(168.08,173.82) v2(168.01,11.01) v2(168.45,36.77) v2(168.59,172.93) v2(168.65,64.79) v2(168.83,37.28) v2(169.37,65.59) v2(169.35,64.85) v2(169.54,14.75) v2(169.6,67.46) v2(169.67,10.37) v2(170,27.41) v2(170.34,31.59) v2(170.38,29.81) v2(170.36,29.19) v2(170.57,181.29) v2(170.59,37.27) v2(171.15,34.32) v2(171.34,27.67) v2(171.57,13.67) v2(171.57,11.45) v2(172.78,1.58) v2(173.03,178.7) v2(173.03,171.08) v2(173.03,163.46) v2(173.03,155.84) v2(173.03,148.22) v2(173.03,140.6) v2(173.03,132.98) v2(173.03,110.12) v2(173.03,94.88) v2(173.03,87.26) v2(173.03,79.64) v2(173.03,72.02) v2(173.03,64.4) v2(173.03,56.78) v2(173.03,49.16) v2(173.03,41.54) v2(173.03,33.92) v2(173.03,26.3) v2(173.03,18.68) v2(173.03,7.37) v4(11.86,77.91) v4(12.22,50.87) v4(15.37,55.9) v4(17.47,63.25) v4(19.32,43.15) v4(26.08,29.38) v4(30.55,71.72) v4(31.24,78.87) v4(38.41,75.08) v4(52.24,5.74) v4(65.04,6.68) v4(76.43,46.03) v4(83,54.22) v4(83.22,37.96) v4(104.72,130.2) v4(109.49,172.65) v4(111.75,59.71) v4(113.37,75.01) v4(114.84,176.41) v4(121.74,35.09) v4(125.24,120.12) v4(127.11,137.87) v4(130.49,143) v4(131.37,95.5) v4(131.71,141.93) v4(132.73,177.8) v4(139.46,121.57) v4(142.89,177.68) v4(142.98,153.39) v4(147.24,4.01) v4(155.84,111.41) v4(164.42,92.86) v4(165.16,79.47) v4(171.84,145.61)
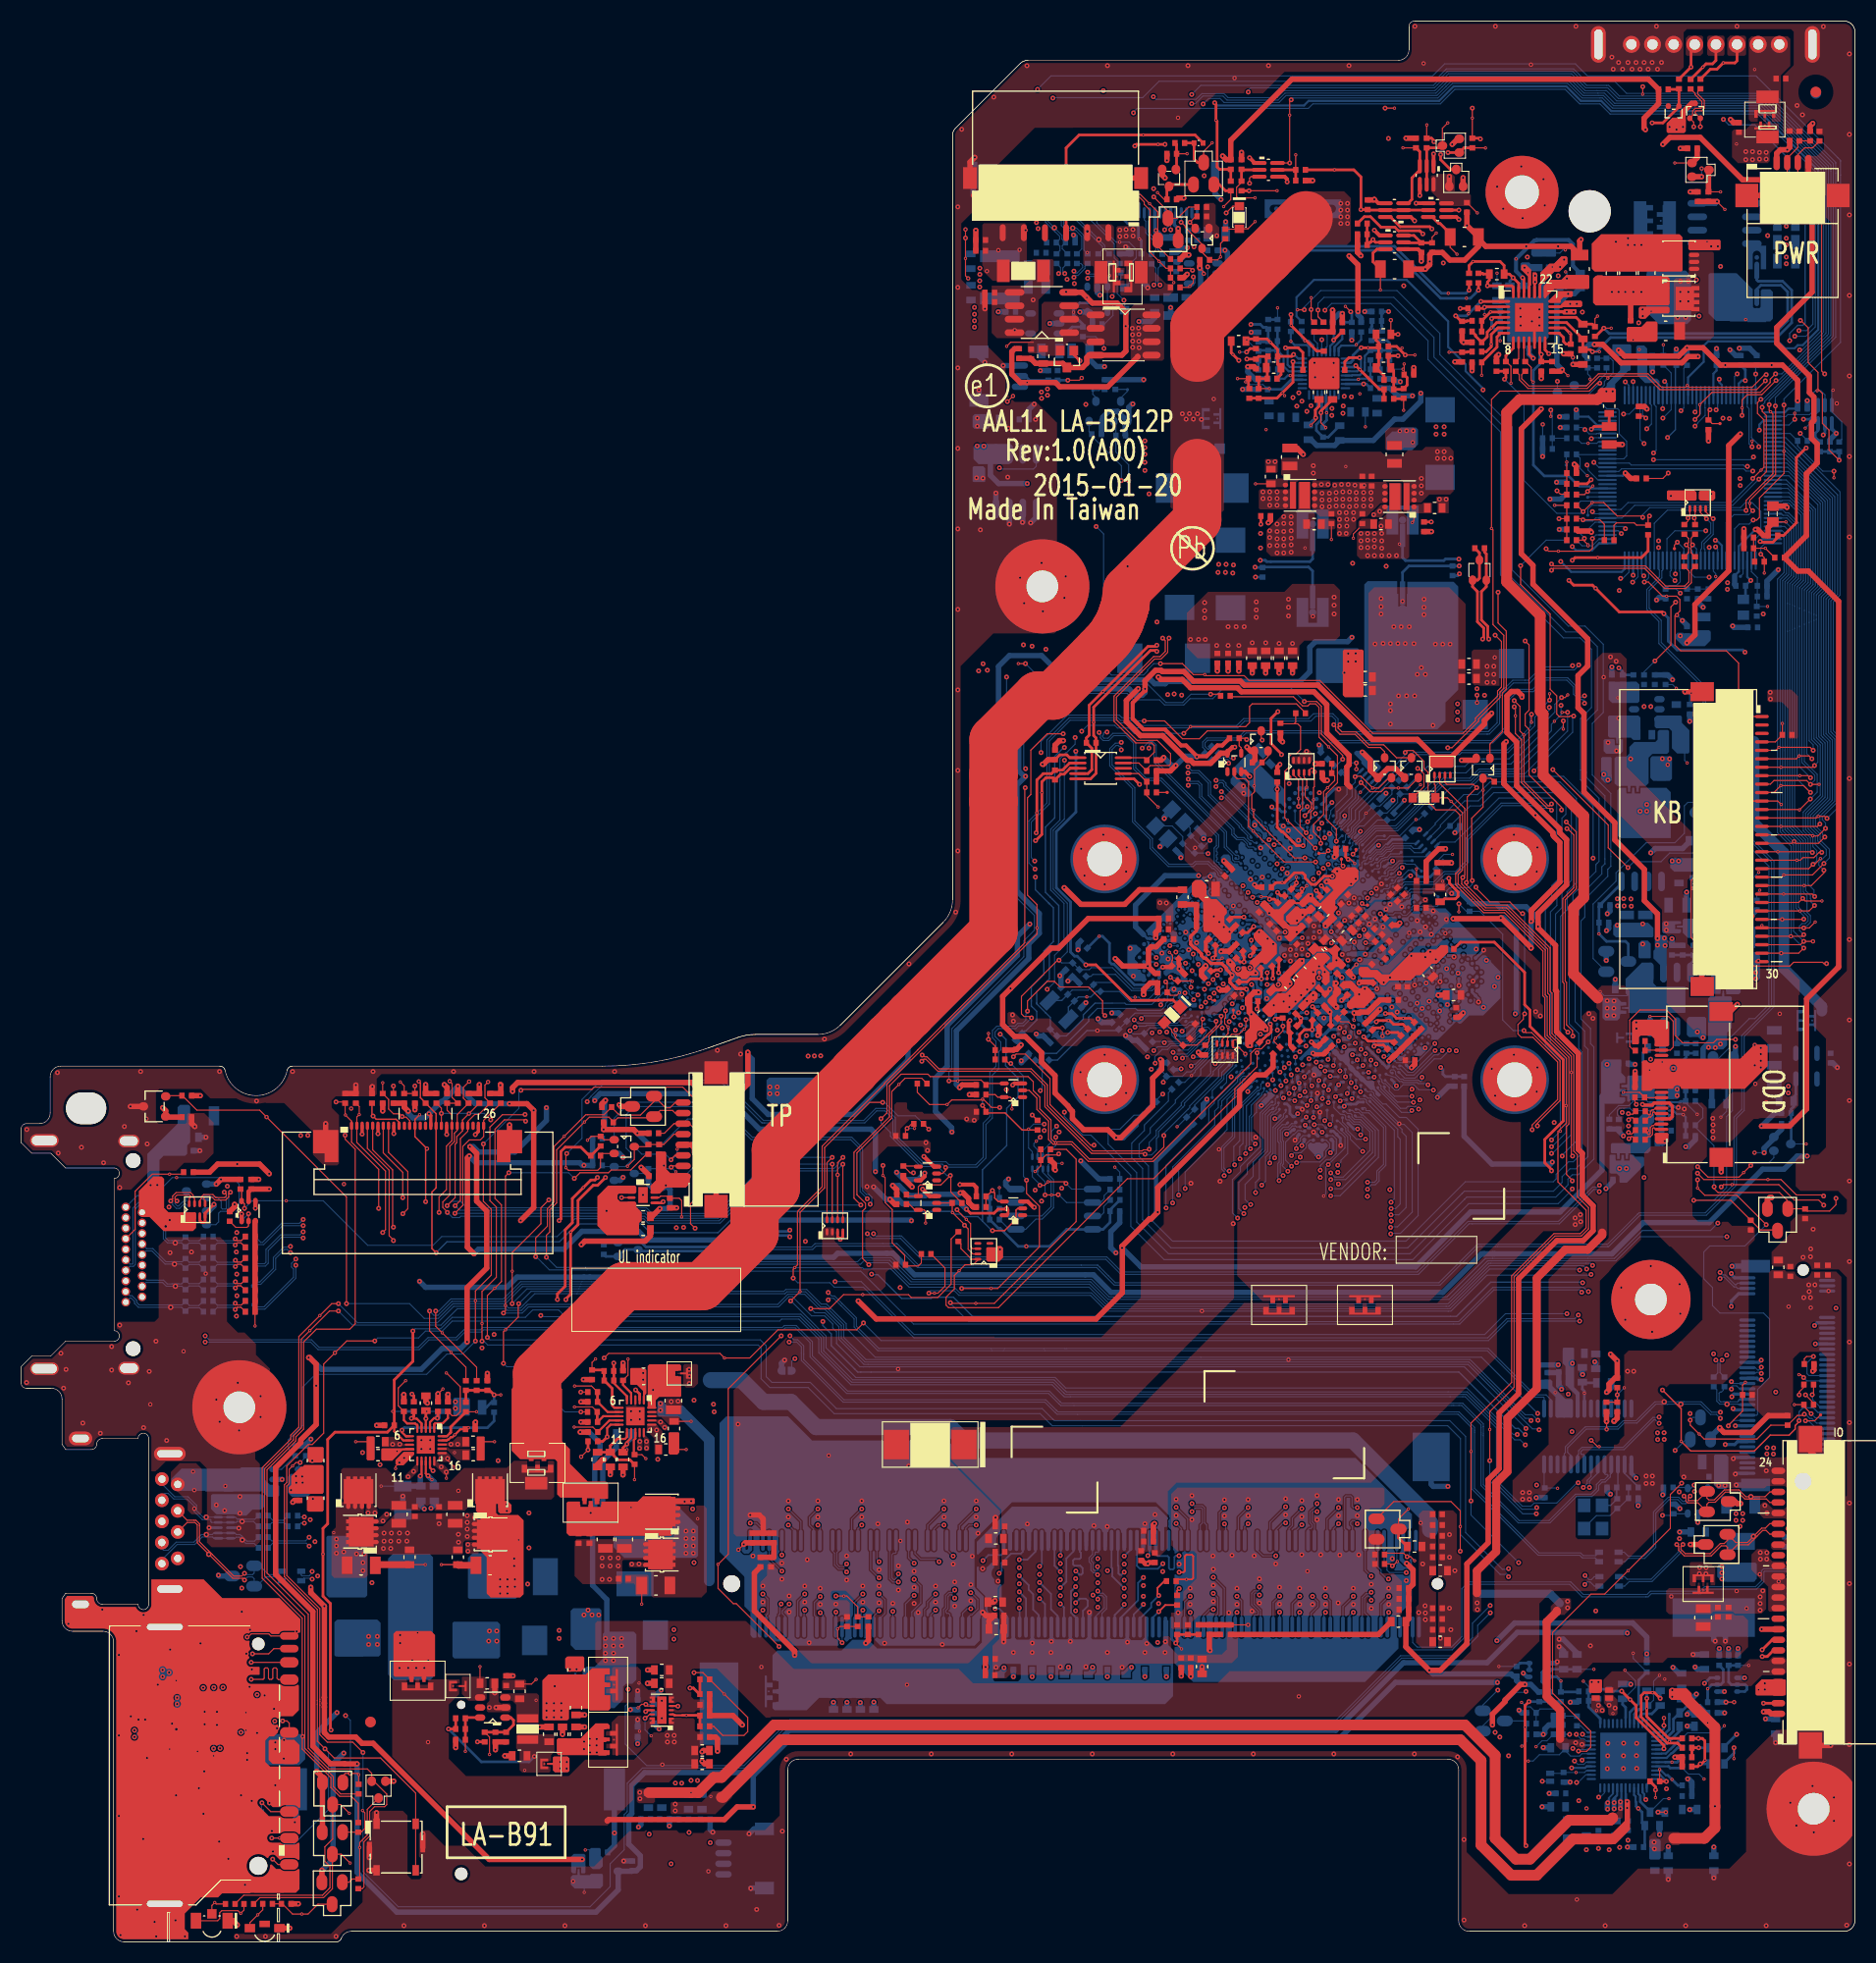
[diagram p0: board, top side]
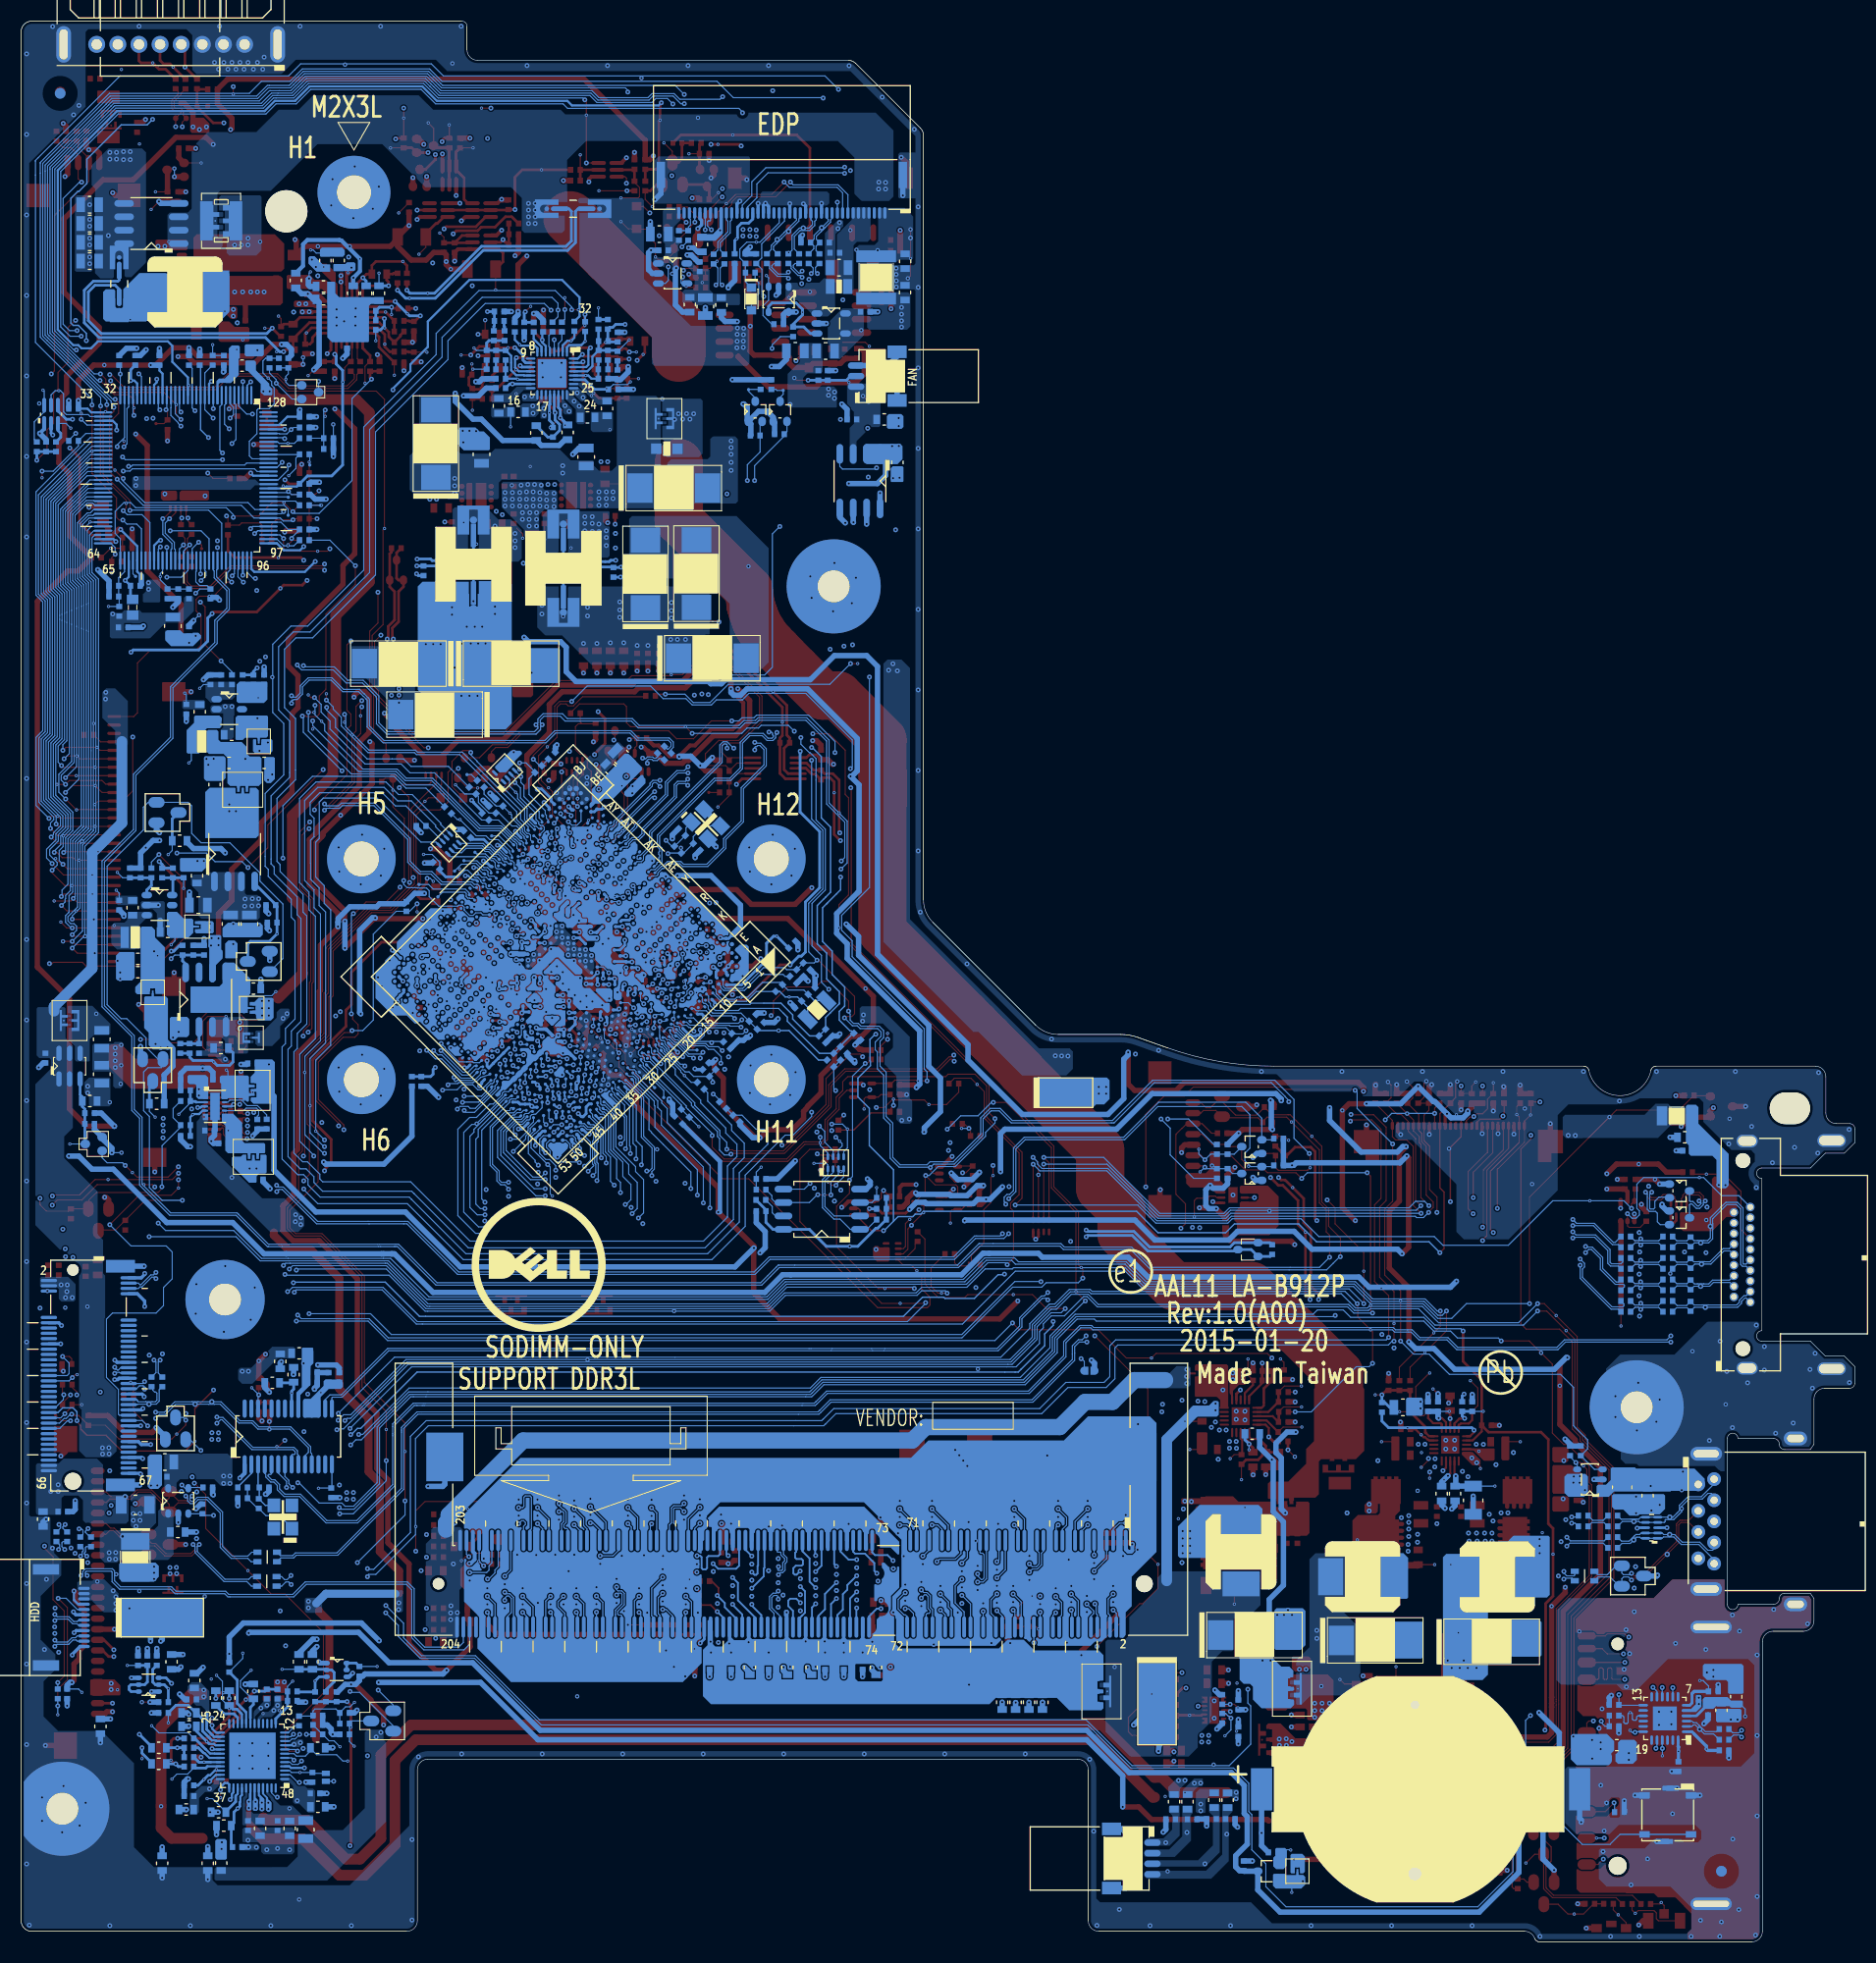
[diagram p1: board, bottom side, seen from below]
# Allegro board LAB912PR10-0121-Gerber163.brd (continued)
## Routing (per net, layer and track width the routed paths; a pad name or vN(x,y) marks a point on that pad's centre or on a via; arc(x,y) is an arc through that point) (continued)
GNDA: length 21.5
  TOP w0.102: v2(155.48,20.48) v4(155.48,21.19) ; v2(161.35,22.69) v4(162.12,22.69) ; v2(154.92,12.28) v4(155.66,12.28)
  TOP w0.508: JIO1.9 v2(164.73,29.59) ; JIO1.1 165.62,21.59 165.43,21.78 v2(164.9,21.78) ; RA84.2 RA83.2 v2(156.52,17.48)
  BOTTOM w0.203: v2(153.76,13.47) 153.61,13.63 153.61,14 153.45,14.15 UA1.38 ; UA1.25 155.1,19.81 155.48,20.19 v2(155.48,20.48)
  BOTTOM w0.406: QA1.4 v2(163.11,24.99) ; QA1.1 v2(161.2,23.69)
  BOTTOM w0.508: CA71.2 156.89,25.42 v2(156.33,25.98) ; CA51.2 158.04,22.94 v2(158.55,23.45) ; RA31.1 v2(165.09,21.1) ; CA23.1 157.7,20.4 v2(157.68,20.43) ; CA74.2 152.32,24.4 v2(152.34,24.38) ; RA154.1 v2(161.22,21.67) ; CA62.1 157.82,21.67 v2(157.68,21.53) ; CA61.2 v2(155.06,10.16) ; CA63.1 v2(154.92,12.28) ; RA29.1 v2(155.89,9.01) ; RA20.2 v2(161.35,22.69) ; v2(158.43,26.02) 158.64,25.8 RA30.1 ; RA32.1 v2(160.2,8.97)
V1: length 26.5
  TOP w0.102: PR702.2 v1(137.81,163.65)
  TOP w0.508: v2(135.17,167.09) PQ708.2 ; v2(157.03,169.76) PR714.2
  IN2 w0.508: v2(135.17,167.09) 136.2,168.12 136.2,168.15 137.81,169.76 154.39,169.76 154.39,169.73 154.97,169.15 155.79,169.15 156.37,169.73 156.37,169.76 v2(157.03,169.76)
V18: length 2.1
  BOTTOM w0.254: UR1.24 16.73,18.5
  BOTTOM w0.305: CR4.2 v1(16.69,18.03) 16.69,18.46 16.73,18.5
VCCST_PG_EC: length 3.7
  TOP w0.102: T209.1 160.04,143.71 CE35.1 159.7,144.88 v2(159.84,145.02)
  BOTTOM w0.102: UE1.21 159.76,145.09 v2(159.84,145.02)
VDD_1.35VP: length 8.4
  TOP w0.102: v1(58.06,43.75) PR201.1
  TOP w0.203: PU200.11 57.33,47.79 57.16,47.61 56.42,47.61
  TOP w0.254: PC213.1 55.76,46.95 56.42,47.61 ; PC213.1 PR203.2 ; PC213.1 56.48,45.63 57.61,45.63 58.04,45.2 PR201.1
VDDP_LDO: length 11.2
  TOP w0.102: v1(146.39,148.25) 145.85,148.79 v2(145.85,148.8)
  TOP w0.508: PR710.1 145.71,148.66 v2(145.85,148.8)
  BOTTOM w0.508: PR709.1 147,155.99 v2(146.41,155.99) 145.89,155.47 PC714.1 145.34,155.18 145.34,149.31 v2(145.85,148.8)
VIN: length 106.2
  TOP w0.254: v2(136.2,154.6) PR711.2
  TOP w0.508: v2(147.63,161.12) 147.5,160.99 PR707.1 146.68,160.49 v4(145.46,160.49) v4(142.45,160.49) 138.61,160.49 137.92,161.18 ; 137.92,161.18 PR730.1 v2(136.84,162.45) PR702.1 ; 137.92,161.18 137.92,160.47 136.63,159.19 135.22,159.19 134.51,159.9 PR14.2 133.32,159.68 v2(133.32,159.05) 133.32,158.76 v4(132.89,158.33) PR12.1 ; v2(157.97,165.64) PR706.2
  IN1 w0.508: v2(136.84,162.45) 137.42,163.04 137.42,167.27 136.76,167.93 131.53,167.93 130.13,169.32 117.62,169.32 116.53,168.23 116,168.23 115.99,168.24 113.05,168.24 v2(111.97,167.17)
  IN2 w0.508: v2(157.97,165.64) 157.97,166.02 156.77,167.22 151.31,167.22 150.96,166.86 150.96,162.42 149.66,161.12 v2(147.63,161.12) ; v2(133.32,159.05) 133.32,158.58 136.2,155.7 v2(136.2,154.6) ; v2(95.78,155.42) 95.78,160.82 96.92,161.96 96.92,165.07 97.67,165.82 102.14,165.82 103.99,167.67 111.46,167.67 v2(111.97,167.17)
+BIOS_SPI: length 17.9
  BOTTOM w0.254: RC38.1 RC99.2 RC36.1 92.48,67.55 92.65,67.55 94.37,65.83 v4(95.13,65.83) 97.34,65.83 98.95,67.44 UC8.8 102.39,67.44 103.06,68.11 CC21.1 103.06,69.29 RC37.1
+CHGRTC: length 0.6
  BOTTOM w0.102: 53.3,5.33 v1(53.3,4.68)
+CODEC_AVDD2: length 6.1
  BOTTOM w0.203: 152.85,13.22 152.8,13.27 152.8,13.76 152.65,13.9 UA1.40
  BOTTOM w0.254: 152.85,13.22 152.85,12.83 v4(153.05,12.63) 153.41,12.28 153.41,11.26 CA61.1 153.66,9.09 RA8.2
+DDR_SOC_VREF: length 12.7
  TOP w0.102: v4(128.85,85.73) 128.85,86.5 v2(128.83,86.51)
  TOP w0.254: v2(128.83,86.51) 128.09,86.51 CC2.1
  IN1 w0.254: v2(128.83,86.51) 128.83,86.51 128.83,85.9 129.38,85.35 130.67,85.35 133.25,82.77 v2(134.36,82.77)
  BOTTOM w0.254: USOC1.AF44 128.82,86.5 v2(128.83,86.51) ; RC6.2 RC7.2 134.79,81.9 134.56,82.13 134.56,82.56 v2(134.36,82.77)
+DIMM1_VREF_CA: length 4.7
  TOP w0.102: R1029.2 v4(116.12,30.01)
  TOP w0.508: R1029.2 R1030.2 C1078.1 RD4.2
+DIMM1_VREF_DQ: length 8.5
  TOP w0.102: v2(68.39,37.63) 68.39,37.62 v4(67.89,37.12)
  TOP w0.508: v2(68.39,37.63) 68.54,37.77 CD1.1 CD2.1 C1076.1 71.24,36.4 R1028.2 R1027.2
  BOTTOM w0.356: JDIMM2.1 69,37.15 68.78,36.93 68.49,36.93 68.38,37.04 68.38,37.62 v2(68.39,37.63)
+EC_VCCA: length 44
  TOP w0.254: v2(148.58,138.39) 148.2,138.01 PR10.1 ; v2(155.47,125.72) 155.31,125.88 151.25,125.88 v4(149.02,128.11) 148.71,128.42 146.93,128.42 v2(146.49,128.86)
  IN2 w0.254: v2(163.15,122.07) 163.73,122.66 163.73,127.84 163.7,127.88 v2(163.7,128.86) ; v2(146.49,128.86) 146.3,129.05 146.3,136.1 v2(148.58,138.39)
  BOTTOM w0.203: UE1.67 163.36,129.19 v2(163.7,128.86) 163.36,128.53 163.36,128.52 CE7.1
  BOTTOM w0.254: LE1.2 163.2,127.28 CE7.1 ; v2(155.47,125.72) 155.89,125.31 155.89,123.12 156.72,122.28 162.94,122.28 v2(163.15,122.07)
+FAN_POWER: length 0.7
  TOP w0.102: v4(93.87,146.31) 93.35,145.79 v2(93.34,145.79)
+INV_PWR_SRC: length 4.7
  TOP w0.102: v4(89.38,162.09) v2(89.38,161.27) v1(89.38,159.34) 89.38,157.7 v4(89.63,157.45)
+LCDVDD:
  vias: v4(98.9,156.18)
+LCDVDD_CONN:
  vias: v4(95.07,162.01)
+MIC2-VREFO: length 10.2
  TOP w0.254: v2(151.48,23.73) v4(152.28,22.93) 152.85,22.36 152.85,21.22 155.48,18.59 v2(155.48,18.28)
  BOTTOM w0.203: UA1.29 155.32,18.21 155.39,18.28 v2(155.48,18.28)
  BOTTOM w0.254: v2(151.48,23.73) 150.48,23.73 RA53.2 RA1109.2
+RTCBATT: length 6.2
  BOTTOM w0.508: RC33.2 56.15,9.11 v2(56.15,10.31) JRTC.1
+RTCBATT_R: length 0.7
  BOTTOM w0.102: 54.07,8.72 53.42,8.72 v1(53.4,8.69)
+RTCVCC: length 348
  TOP w0.508: v2(31.79,16.85) 30.63,16.85 30.61,16.86 29.27,16.86 27.61,18.52 27.61,31.27 24.09,34.79 24.09,44.89 26.47,47.28 26.47,47.52 27.92,48.97 v4(27.92,52.64) 27.92,54.68 27.3,55.3 v2(27.21,55.3) ; v2(42.47,75.27) 43.11,74.63 43.11,70.12 44.06,69.17 44.06,63.77 42.21,61.92 v2(42.21,56.79)
  IN1 w0.508: v2(161.6,27.77) 161.91,28.07 161.91,28.85 161.21,29.55 152.33,29.55 v2(152.01,29.23) ; v2(101.92,87.37) 101.85,87.44 100.85,87.44 97.44,90.85 96.58,90.85 94.57,88.84 94.57,87.08 95.31,86.34 95.31,84.05 v2(94.66,83.4) 94.66,83.27 93.92,82.53 87.38,82.53 84.97,80.12 84.97,79.62 84.35,79 83.39,79 80.85,76.46 v2(80.85,72.91) ; v2(49.71,78.95) 49.9,78.76 53.68,78.76 54.25,79.33 54.25,79.55 54.29,79.59 v2(54.29,79.62)
  IN2 w0.508: v2(116.45,90.62) 116.43,90.64 116.32,90.64 116.21,90.75 115.72,90.75 115.61,90.64 115.5,90.64 113.09,88.22 112.21,88.22 111.92,87.93 110.97,87.93 109.75,89.15 108.7,89.15 108.58,89.27 107.62,89.27 107.2,88.86 102.67,88.86 101.92,88.1 v2(101.92,87.37)
  BOTTOM w0.254: USOC1.P22 116.62,90.45 v2(116.45,90.62)
  BOTTOM w0.508: v2(152.01,29.23) 151.95,29.29 141.61,29.29 138.74,26.42 130.82,26.42 124.42,20.02 72.69,20.02 68.69,16.02 59.01,16.02 57.79,14.8 57.79,12.15 57.51,11.86 57.51,9.25 58.6,8.15 58.6,7.11 58.24,6.74 CC23.1 57.79,6.69 DC3.1 56.51,4.92 54.4,2.81 35.55,2.81 31.79,6.57 v2(31.79,16.85) ; v2(80.85,72.91) 80.85,76.51 80.45,76.92 69.88,76.92 66.52,80.28 54.79,80.28 54.29,79.78 v2(54.29,79.62) ; RA16.1 v2(161.6,27.77) ; v2(42.47,75.27) 42.79,75.27 43.3,74.76 46.73,74.76 49.71,77.74 v2(49.71,78.95) ; v2(94.66,83.4) 94.66,83.22 95.36,83.92 RC34.1 ; RC35.1 102.27,87.02 v2(101.92,87.37) ; v2(42.21,56.79) 41.57,56.15 39.83,56.15 37.86,54.19 28.44,54.19 27.32,55.3 v2(27.21,55.3)
+SOC_VCC:
  vias: v2(118.55,88.65) v2(119.49,89.01) v2(120.05,89.54) v2(120.03,88.47) v2(120.64,91.23) v2(120.61,89) v2(121.14,89.61) v2(121.71,90.14) v2(122.29,91.78) v2(122.28,90.7) v2(122.84,92.34) v2(123.38,91.8) v2(128.14,122.84) v2(128.71,127.15) v2(128.71,126.39) v2(128.71,125.69) v2(128.9,122.89) v2(129.6,122.89) v2(129.6,117.18) v2(129.6,116.54) v2(129.6,115.27) v2(129.91,124.48) v2(130.3,122.89) v2(130.36,117.94) v2(130.61,124.48) v2(130.99,122.89) v2(131.12,117.94) v2(131.37,124.48) v2(131.82,122.88) v2(131.88,117.94) v2(132.14,119.97) v2(132.52,120.61) v2(132.77,127.08) v2(132.77,126.32) v2(132.77,125.62) v2(132.9,119.97) v2(133.62,115.15) v2(133.85,122.83) v2(134.55,122.83) v2(135.25,122.83) v4(130.74,126.89)
+SOC_VNN: length 0.9
  TOP w0.406: RC55.1 118.88,111.2 v2(119.14,111.45)
  vias: v2(110.67,123.27) v2(111.44,123.27) v2(112.01,126.77) v2(112.01,126) v2(112.01,125.31) v2(112.07,123.27) v2(113.15,122.7) v2(114.23,124.48) v2(114.23,122.7) v2(114.99,124.48) v2(115.25,122.7) v2(115.75,124.48) v2(116.52,122.96) v2(116.9,126.83) v2(116.9,126.07) v2(116.9,125.37) v2(117.79,122.96) v2(119.06,122.89) v2(119.57,93.36) v2(119.94,127.08) v2(119.94,126.32) v2(119.94,125.5) v2(120.13,93.92) v2(120.13,92.84) v2(120.33,122.89) v2(120.67,93.41) v2(121.23,93.97) v2(121.78,94.5) v2(121.78,93.42) v2(122.35,96.15) v2(122.34,95.06) v2(122.88,95.6) v2(124.26,127.27) v2(124.26,126.51) v2(124.26,125.69) v2(125.04,93.45) v2(125.57,92.92) v4(122.26,125.46)
+V_TS:
  vias: v1(109.09,157.06)
+VDISPLAY_VCC:
  vias: v2(12.25,71.62) v2(12.88,71.64) v4(14.06,68.32)
ACIN: length 180.6
  TOP w0.102: v1(133.04,171.98) 133.03,171.97 PR712.1
  TOP w0.254: PR712.1 133.48,170.72 133.71,170.49 v2(133.71,170.39) ; DC1.1 109.02,89.15 107.67,89.15 107.63,89.11 105.09,89.11 101.72,92.48 v2(100.77,92.48) ; v2(132.66,161.67) 132.36,161.96 130.35,161.96 130.01,162.3 128.7,162.3 127.7,163.29 127.12,163.29 PR16.1 ; PR710.2 PR716.1 v2(143.87,150.26) 143.73,150.4 PU700.13
  IN1 w0.254: v2(99.82,112.69) 99.12,113.39 99.12,114.69 98.85,114.96 98.85,121.28 100.89,123.32 100.89,142.96 102.92,144.98 102.92,147.17 104.03,148.28 104.03,153.25 105.39,154.61 105.39,160.8 105.77,161.18 105.77,162.46 107.69,164.38 107.69,170.25 109.1,171.66 131.88,171.66 133.15,170.39 v2(133.71,170.39)
  IN2 w0.254: v2(143.87,150.26) 142.67,151.47 140.77,151.47 140.32,151.93 140.32,157.13 138.87,158.58 137.22,158.58 134.23,161.56 132.76,161.56 v2(132.66,161.67) 132.66,162.76 133.17,163.27 133.17,169.44 133.71,169.99 v2(133.71,170.39)
  BOTTOM w0.203: UE1.110 148.64,137.57 148.46,137.75 147.45,137.75 CE18.2
  BOTTOM w0.254: CE18.2 146.45,138.76 144.15,138.76 143.12,139.78 143.12,148.74 143.73,149.35 143.73,150.12 v2(143.87,150.26) ; v2(100.77,92.48) 99.94,93.3 99.7,93.3 99.32,93.68 99.32,98.43 97.97,99.78 97.97,105.09 99.83,106.94 99.83,112.56 99.82,112.57 v2(99.82,112.69)
ACIN_65W: length 1.9
  BOTTOM w0.102: UE1.108 148.3,136.77 T221.1
ACOFF: length 76.4
  TOP w0.102: PR718.1 v1(137.34,172.63) v2(137.34,173.57)
  TOP w0.254: PR718.1 138.03,170.72 v2(138.11,170.65) ; v2(136.07,163.91) PQ713.5
  IN1 w0.127: v2(162.41,148.41) 162.55,148.41 162.55,148.5 163.65,149.6 163.9,149.85 168.45,149.85 170.05,151.44 170.05,167.47 165.91,171.6 160.75,171.6 159.5,172.86 159.29,172.86 159.29,172.85 151.97,172.85 150.76,174.07 137.85,174.07 v2(137.34,173.57)
  IN2 w0.254: v2(138.11,170.65) 137.85,170.39 137.72,170.39 134.55,167.22 134.55,166.33 136.07,164.8 v2(136.07,163.91)
  BOTTOM w0.102: UE1.27 162.16,148.16 v2(162.41,148.41)
ACSETIN: length 5.8
  TOP w0.254: PR711.1 138.39,154.6 v2(138.5,154.72) 138.55,154.77 PU700.2
  BOTTOM w0.102: v2(138.5,154.72) v1(138.5,154.02)
  BOTTOM w0.254: PR715.2 PC712.2 139.64,154.72 v2(138.5,154.72)
AD_BID0: length 5.6
  BOTTOM w0.102: UE1.66 163.76,129.68 164.32,129.13 CE8.1 RE5.2 164.27,127.29 RE3.1 v1(165.28,126.4)
AD_BID1: length 5.1
  BOTTOM w0.102: RE11.1 RE7.2 CE10.1 159.7,128.24 160.38,128.93 v1(160.38,129.23) 160.38,129.51 160.16,129.73 UE1.75
AD_I_HW1: length 7.3
  TOP w0.102: v2(167.86,144.11) v1(167.86,144.69)
  IN1 w0.127: v2(170.55,142.63) 169.35,142.63 v2(167.86,144.11)
  BOTTOM w0.102: v2(167.86,144.11) 167.32,143.57 UE1.36
  BOTTOM w0.254: v2(170.55,142.63) 170.72,142.79 PQ10.2
AD_I_HW2: length 8.1
  BOTTOM w0.102: UE1.34 167.01,144.37 167.2,144.56 169.27,144.56 169.54,144.83 169.54,146.54 169.82,146.82 v1(169.98,146.82) 170.33,146.82 170.72,146.43 PQ10.5
ADP_I: length 43.6
  TOP w0.102: v2(153.47,134.83) 153.35,134.96 151.06,134.96 149.79,136.23 v1(148.68,136.23) v2(147.83,135.38) 147.24,135.97 PR11.1
  TOP w0.254: v2(140.39,147.91) 140.52,148.04 PR722.1 PC725.2
  BOTTOM w0.102: UE1.65 164.16,132.82 164.65,133.31 164.65,135.4 163.82,136.23 163.19,136.23 162.71,135.75 154.13,135.75 153.47,135.09 v2(153.47,134.83) ; v2(140.39,147.91) 142.23,146.07 142.23,138.32 145.34,135.21 147.67,135.21 v2(147.83,135.38)
ADPIN:
  vias: v4(91.41,158.14) v4(92.49,160.12) v4(94.49,160.15)
AUD_HP_OUT_L_CN: length 12.8
  TOP w0.254: JIO1.8 165.72,28.59 v2(164.78,27.64)
  IN2 w0.254: v2(162.36,19.64) 163.7,20.98 163.7,25.04 164.27,25.61 164.27,27.33 164.59,27.64 v2(164.78,27.64)
  BOTTOM w0.254: LA8.2 161.21,18.49 v2(162.36,19.64)
AUD_HP_OUT_R_CN: length 14.4
  TOP w0.102: v2(162.11,18.37) v1(162.11,17.34)
  TOP w0.254: JIO1.7 165.84,27.59 165.26,27.01 v2(164.78,27.01)
  IN2 w0.254: v2(164.78,27.01) 164.78,25.4 164.26,24.88 164.26,20.58 162.11,18.44 v2(162.11,18.37)
  BOTTOM w0.254: v2(162.11,18.37) 162.11,17.86 161.21,16.96 LA9.2
B+: length 253.6
  TOP w0.508: v2(155.38,170.14) 156.04,170.8 158.91,170.8 162.92,166.78 165.79,166.78 169.5,163.08 169.5,156.15 166.16,152.81 166.16,151.3 169.25,148.22 169.25,146.64 169.67,146.22 169.67,144 169.45,143.78 169.45,142.31 169.98,141.78 169.98,139.97 168.97,138.96 168.97,133.1 PR34.2 168.15,129.75 169.14,129.75 172.01,126.88 172.01,92.28 171.95,92.22 168.98,89.25 168.98,78.84 167.35,77.21 v2(164.71,77.21)
  TOP w4.572: 48.82,51.9 48.82,53.81 52.79,57.77 52.81,57.77 54.58,59.54 54.58,59.56 57.08,62.06 64.45,62.06 69.41,67.03 69.41,69.31 71.43,71.33 71.43,74.96 78.87,82.4 78.87,82.45 81.8,85.38 82.03,85.62 82.03,85.62 83.17,86.76 83.22,86.8 84.18,87.77 84.18,87.78 92.03,95.63 92.03,107.96 92,107.99 92,110.49 92.03,110.52 92.03,113.77 96.22,117.97 97.69,117.97 100.2,120.48 101.99,122.31 102.48,122.79 102.55,122.88 102.93,123.26 103.06,123.46 103.22,123.65 103.49,124.13 103.79,124.58 103.88,124.81 104,125.02 104.18,125.54 104.34,125.96 104.34,126.05 104.49,126.49 104.5,126.52 104.68,127.96 111.31,134.59 111.31,139.97
  TOP w5.08: 121.6,163.16 117.89,159.46 117.87,159.46 111.31,152.89 111.31,150.2
  BOTTOM w0.508: RS6.2 165.97,78.44 164.73,77.2 v2(164.71,77.21)
  vias: v2(90.23,154.71) v2(90.23,154.06) v2(90.23,153.44) v2(90.23,152.84) v2(91.74,166.53) v2(91.74,165.91) v2(92.37,166.56) v2(92.4,165.91) v2(109.9,144.64) v2(110.25,144.13) v2(110.57,144.65) v2(110.95,144.13) v2(111.33,144.64) v2(111.7,144.1) v2(124.9,164.55) v2(124.9,163.91) v2(124.9,163.28) v2(124.9,162.64) v2(125.53,164.55) v2(125.53,163.91) v2(125.53,163.28) v2(125.53,162.64) v4(112.87,146.03)
B+_1.35VP: length 10
  TOP w0.508: v2(52.91,48.26) PR205.1
  BOTTOM w0.508: v2(53.9,40.6) 54.29,40.98 54.29,45.8 54.79,46.31 54.79,47.2 53.74,48.26 v2(52.91,48.26)
  vias: v1(57.73,41.12)
BAT_AMBER: length 6.1
  TOP w0.102: LED1.1 18.6,2 18.79,2.19 18.79,2.75 18.99,2.95 20.53,2.95 v1(20.78,2.7) 21.09,3.01 R6103.1
BAT_WHITE: length 2.2
  TOP w0.102: LED1.2 18.05,3.45 v1(18.33,3.72) 18.46,3.59 R6107.1
BATT+: length 32.9
  TOP w0.508: PR726.2 v2(145.98,150.31)
  IN1 w0.508: v2(145.98,150.31) 146.72,150.31 148.51,152.1 150.04,152.1 150.55,152.61 166.55,152.61 168.08,154.14 168.08,156.42 165.3,159.2 v2(165.3,161.5)
  vias: v1(162.35,170.18) v2(163.23,169.45) v2(163.23,168.69) v2(163.86,169.45) v2(163.86,168.69) v2(164.52,169.38) v2(164.52,168.74) v2(165.16,169.38) v2(165.16,168.74)
BATT++:
  vias: v1(164.06,177.22)
BATT_LOW_LED: length 13.3
  TOP w0.102: R6103.2 22.6,4.19 28.62,4.19 29.46,5.02 Q6101.1 30.3,8.3 v1(31.13,7.46)
BATT_LOW_LED#: length 281.1
  TOP w0.102: R6105.2 31.91,13.11 31.25,13.77 30.15,13.77 29.32,14.61 29.32,15.53 26.6,18.25 26.6,30.63 22.82,34.41 22.82,44.88 25.52,47.58 25.52,47.97 26.28,48.73 26.28,57.3 v1(28.27,59.29) 29.39,60.41 v2(30.03,60.41)
  IN1 w0.127: v2(152.52,128.7) 152.52,126.93 155.28,124.16 156.25,123.2 157.2,123.2 157.45,123.44 158.42,123.44 162.24,119.62 162.24,116.22 165.37,113.08 165.37,102.38 167.15,100.6 167.15,93.41 167.15,86.92 166.54,86.3 166.54,82.54 166.54,81.9 166.3,81.66 166.3,77.03 166.59,76.74 166.59,75.66 166.59,72.89 166.3,72.6 166.3,69.62 164.71,68.03 164.71,64.45 153.49,53.23 149.54,53.23 147.45,51.15 145.42,51.15 143.64,49.37 v2(143.55,49.37)
  BOTTOM w0.102: v2(152.52,128.7) 153.03,129.2 153.03,129.9 152.96,129.97 UE1.93 ; v2(30.03,60.41) 31.83,58.61 39.4,58.61 40.95,60.16 45.97,60.16 46.13,60 47.26,60 47.55,60.29 48.61,61.35 52.6,61.35 72.29,61.35 72.47,61.53 74.25,61.53 75.67,60.11 76.16,60.11 77.86,58.41 77.86,57.22 79.96,55.11 137.13,55.11 142.35,49.89 143.03,49.89 v2(143.55,49.37)
BATT_LOW_LED_R#: length 4
  TOP w0.102: Q6101.2 R6105.1 32.18,10.38 32.53,10.74 32.53,12.21 v1(32.31,12.43)
BATT_PRS: length 10
  TOP w0.102: v2(153.47,175.6) v1(153.47,174.89)
  TOP w0.254: PR6.1 v2(158.04,177.45) 158.04,179.25 PBATT1.4
  IN1 w0.254: v2(153.47,175.6) 155,175.6 156.85,177.45 v2(158.04,177.45)
BATT_TEMP: length 122.9
  TOP w0.254: v2(168.94,141.4) 168.93,141.4 168.01,140.48 168.01,134.32 166.81,133.12 CE9.2 166.24,132.93 165.79,132.48 164.65,132.48 v2(164.59,132.55) ; PR7.1 156.85,175.34 PR6.2 156.9,173.77 PD2.2 156.89,173.69 155.38,172.17 v2(154.36,172.17) ; PC11.1 v1(124.3,167.72) 126.13,167.72 126.8,167.05 v2(126.8,163.96) PC708.1 127.49,163.91 PQ710.5 PQ710.2 PQ713.2
  IN2 w0.254: v2(126.8,163.96) 126.8,165.25 125.85,166.2 125.85,171.22 128.68,174.05 130.07,174.05 131.95,172.17 v2(154.36,172.17) 155.5,173.31 159.24,173.31 160.7,171.85 167.79,171.85 168.4,171.85 169.18,172.64 170.78,172.64 171.89,171.53 171.89,145.21 168.94,142.26 v2(168.94,141.4)
  BOTTOM w0.203: v2(164.59,132.55) 164.81,132.77 UE1.63
BEEP#: length 156.6
  IN1 w0.127: v2(143.43,43.24) 143.65,43.46 146.24,43.46 146.65,43.87 150.17,43.87 151.61,45.31 153.95,45.31 156.14,47.51 160.27,47.51 160.79,48.03 162.01,48.03 162.87,48.89 162.87,54.97 163.93,56.03 165.37,56.03 171.28,61.94 171.28,70.86 170.96,71.18 170.96,83.2 170.11,84.05 170.11,92.54 170.62,93.05 170.62,93.22 171.62,94.22 171.62,97.71 171.62,99.91 171.34,100.19 171.34,107.08 170.43,107.99 170.43,108.2 170.43,118.45 163.99,124.88 163.84,124.88 163.17,125.56 161.75,125.56 161.07,126.25 161.07,143.11 160.42,143.76 v2(160.42,145)
  IN2 w0.127: v2(142.42,23.71) 142.89,24.18 142.89,25.66 142.89,26.5 142.89,36.95 143.9,37.96 143.9,42.77 v2(143.43,43.24)
  BOTTOM w0.102: v2(142.42,23.71) 142.33,23.62 141.51,23.62 138.33,20.44 DA8.2 ; UE1.23 160.56,145.15 v2(160.42,145)
BKOFF#: length 142.9
  TOP w0.102: v2(164.65,146.01) 164.33,145.69 164.33,144.67 164.95,144.06 164.95,139.57 v1(164.67,139.3) v2(163.89,138.51)
  IN1 w0.127: v2(107.16,174.65) 107.16,173.99 106.47,173.3 106.47,169.67 104.1,167.29 104.1,165.2 104.35,164.94 104.35,164.3 102.93,162.87 102.93,157.89 104.37,156.44 v2(104.37,155.38)
  BOTTOM w0.102: DX1.2 104.44,155.32 v2(104.37,155.38) 103.74,156.01 103.74,157.04 104.08,157.39 RX25.1 ; v2(164.65,146.01) 164.88,146.01 170.92,152.04 171.05,152.18 171.05,167.7 171.05,168.08 165.28,173.85 164.88,174.25 151.01,174.25 150.04,175.22 149.94,175.22 149.14,175.22 149.14,175.22 148.02,175.22 147.56,175.68 146.65,176.59 135.18,176.59 134.67,176.08 134.67,176.08 134.27,175.68 133.81,175.22 119.53,175.22 118.87,174.56 114.22,174.56 113.84,174.94 111.75,174.94 111.21,174.4 107.4,174.4 v2(107.16,174.65) ; UE1.105 151.42,135.57 152.08,136.23 161.85,136.23 163.91,138.29 163.91,138.49 v2(163.89,138.51)
BOOT1:
  vias: v1(126.7,146.53)
BOOT_1.35VP: length 1.6
  TOP w0.102: PR200.2 v1(63.4,49.27)
BOOTG:
  vias: v1(119.58,146.35)
BST:
  vias: v1(142.61,157.98) v2(142.28,158.47)
BST_1.35VP: length 1.2
  TOP w0.102: PC207.1 v1(62.95,46.6)
BST_3V:
  vias: v1(35.58,46.44)
BST_5V:
  vias: v1(41.01,46.31)
BST_CHGA: length 1.5
  BOTTOM w0.102: PC713.1 145.62,159.85 145.92,160.14 v1(146.14,160.14)
BT_ON#: length 104.1
  TOP w0.102: v2(146.83,74.38) 146.71,74.5 146.71,83.82 144.66,85.88 144.66,89.62 144.48,89.8 144.48,93.97 140.58,97.87 140.2,97.87 138.6,97.87 136.34,100.13 136.34,100.6 136.44,100.71 v2(136.44,100.74) 136.44,100.76 136.63,100.95 136.63,107.28 134.25,109.65 RP54.2 ; v2(168.88,51.77) 169.64,51.01 RM9.2 ; v2(170.59,70.59) 170.49,70.7 168.01,70.7 166.55,72.16 v1(165.32,72.16) 159.25,72.16 v2(158.65,72.75)
  IN1 w0.127: v2(158.65,72.75) 156.8,72.75 155.87,73.68 148.14,73.68 147.44,74.38 v2(146.83,74.38)
  IN2 w0.102: 134.17,100.16 133.41,100.16 132.77,99.53 129.98,99.53 127.79,97.33 127.49,97.33 126.66,96.5 v2(126.66,95.2)
  IN2 w0.127: v2(168.88,51.77) 168.88,51.81 169.36,52.29 170.38,52.29 171.34,53.26 171.34,60.16 171.96,60.78 171.96,69.22 170.63,70.56 170.63,70.59 v2(170.59,70.59) ; 134.17,100.16 135.39,100.16 135.9,100.67 136.37,100.67 v2(136.44,100.74)
  BOTTOM w0.102: v2(126.66,95.2) 126.63,95.2 126.45,95.39 USOC1.AT28
CAPS_LED: length 24.7
  TOP w0.102: JKB.1 162.89,115.98 162.54,116.33 162.54,121.04 161.38,122.19 157.07,122.19 156.52,122.74 156.52,125.5 156.99,125.97 156.99,127.06 156.68,127.37 v1(155.73,127.37) 155.35,127.37 154.01,128.71 v2(153.63,128.71)
  BOTTOM w0.102: UE1.91 153.76,129.87 154.03,129.6 154.03,129.12 v2(153.63,128.71)
CHG:
  vias: v1(163.21,153.55)
CHG_B+:
  vias: v2(152.08,161.25) v2(152.08,160.61) v2(152.71,160.61) v2(153.35,160.61) v4(150.93,160.92)
CLK_PCIE_WLAN: length 117.5
  IN2 w0.102: v2(115.63,99.96) 115.63,100.9 118.17,103.44 118.73,103.44 119,103.71 119,105 118.77,105.23 118.77,107.83 121.18,110.23 121.6,110.23
  IN2 w0.127: 121.6,110.23 122.84,110.23 123.29,110.68 125.36,110.68 125.78,111.1 129.31,111.1 129.97,110.45 135.59,110.45 137.12,111.97 140.42,111.97 142.18,113.73 145.83,113.73 149.75,109.8 149.76,109.8 150.84,108.72 159.37,108.72 163.64,104.46 163.64,102.36 166.05,99.95 166.05,86.78 165.77,86.5 165.77,82.52 163.83,80.58 163.83,74.23 163.23,73.64 163.23,68.4 164.42,67.22 164.42,59.27 160.88,55.73 160.88,55.17 v2(160.98,55.07)
  BOTTOM w0.102: USOC1.AF7 115.46,99.78 v2(115.63,99.96) ; v2(160.98,55.07) 160.79,54.88 160.79,53.88 RI5.2
CLK_PCIE_WLAN#: length 117.5
  IN2 w0.102: 121.86,109.97 121.25,109.97 119.01,107.73 119.01,105.33 119.23,105.1 119.23,103.62 118.82,103.21 118.27,103.21 115.86,100.8 115.86,100.32 116.01,100.17 116.01,99.8 115.96,99.74 115.96,99.49 v2(116.12,99.33)
  IN2 w0.127: 121.86,109.97 122.95,109.97 123.39,110.42 125.47,110.42 125.89,110.84 129.21,110.84 129.86,110.19 135.7,110.19 137.22,111.71 140.53,111.71 142.28,113.47 145.72,113.47 149.65,109.55 149.65,109.55 150.73,108.47 159.26,108.47 163.38,104.35 163.38,102.26 165.79,99.84 165.79,86.89 165.51,86.61 165.51,82.63 163.57,80.69 163.57,74.34 162.98,73.74 162.98,68.3 164.16,67.11 164.16,59.38 160.62,55.83 160.62,55.29 v2(160.39,55.07)
  BOTTOM w0.102: v2(160.39,55.07) 160.57,54.89 160.57,53.84 RI6.2 ; v2(116.12,99.33) 116.04,99.33 115.86,99.14 115.86,98.88 USOC1.AF9
CLK_PCIE_WLAN#_R: length 4.5
  BOTTOM w0.102: JNGFF.41 162.56,50.85 162.52,50.9 v3(161.45,50.9) 160.76,50.9 160.48,51.18 160.48,52.26 RI6.1
CLK_PCIE_WLAN_R: length 4.5
  BOTTOM w0.102: RI5.1 161.1,52.44 161.1,52.22 160.92,52.04 160.8,52.04 160.7,51.94 160.7,51.27 160.85,51.11 161.14,51.11 161.15,51.13 161.75,51.13 161.76,51.11 162.46,51.11 162.54,51.19 162.54,51.27 162.62,51.35 JNGFF.39
CLK_SMB: length 5.7
  TOP w0.254: PBATT1.6 162.4,178.05 162.2,177.85 v1(161.09,177.85) 160.5,177.25 159.87,177.25 PR8.1
CLR_CMOS: length 43.2
  IN1 w0.127: v2(96.46,80.58) 96.23,80.58 92.91,77.25 91.38,77.25 90.19,76.06 88.98,76.06 86.42,73.49 86.42,73.04 85.7,72.32 84.36,72.32 83.75,71.71 83.75,69.67 83.05,68.97 83.05,67.02 80.79,64.76 78.76,64.76 77.84,63.84 77.84,61.58 74.61,58.34 74.61,56.57 v2(73.23,55.2)
  BOTTOM w0.102: v2(73.23,55.2) 73.18,55.2 72.93,54.95 CLRP1.1 ; R1088.1 R1089.1 96.63,80.75 v2(96.46,80.58)
CPU_B+:
  vias: v1(125.37,139.64) v2(117.53,137.24) v2(117.53,136.61) v2(118.17,137.24) v2(118.17,136.61) v2(118.17,135.97) v2(118.87,137.24) v2(118.87,136.61) v2(118.87,135.97) v2(122.29,139.72) v2(122.29,139.02) v2(132.52,138.51) v2(132.52,137.82) v2(132.52,137.12) v2(134.04,141.05) v2(134.04,140.42) v2(134.68,141.05) v2(134.68,140.42) v2(135.31,140.42)
CPU_DPB_CTRLCLK_R: length 13
  TOP w0.102: v2(14.74,70.12) 14.57,70.3 14.57,70.5 14.76,70.69 15.95,70.69 16.05,70.59 16.05,70.49 15.91,70.35 RP15.8
  IN2 w0.127: v2(14.74,70.12) 14.57,70.3 14.57,70.55 14.29,70.82 11.6,70.82 10.51,69.73 10.51,68.16 JHDMI1.15
  BOTTOM w0.102: v2(14.74,70.12) 14.57,69.95 14.57,69.86 14.78,69.65 14.9,69.65 15.32,70.07 15.56,70.07 15.65,70.16 Q57.1
CPU_DPB_CTRLDAT_R: length 13.9
  TOP w0.102: v2(14.16,70.12) 14.34,70.3 14.34,70.59 14.66,70.92 16.04,70.92 16.28,70.68 16.28,70.49 16.41,70.35 RP15.7
  IN2 w0.127: JHDMI1.16 11.12,67.72 10.92,67.72 10.76,67.88 10.76,69.62 11.71,70.57 14.18,70.57 14.31,70.44 14.31,70.28 v2(14.16,70.12)
  BOTTOM w0.102: Q58.1 15.65,69.77 15.58,69.85 15.42,69.85 15,69.43 14.68,69.43 14.34,69.77 14.34,69.95 v2(14.16,70.12)
CPU_EDP_AUX#_C: length 4.9
  BOTTOM w0.102: JEDP.12 97.3,163.17 97.16,163.02 97.16,162.87 v3(97.79,162.24) 98.51,161.52 98.51,161.17 RT17.2 98.53,160.54 98.53,160.26 CX43.2
CPU_EDP_AUX_C: length 4.9
  BOTTOM w0.102: JEDP.11 96.8,163.13 96.94,162.99 96.94,162.78 97.44,162.29 97.44,162.27 97.82,161.88 97.84,161.88 98.29,161.43 98.29,161.16 RT18.1 98.32,160.5 98.32,160.09 CX44.2
CPU_EDP_N0_C: length 5.4
  BOTTOM w0.102: CX46.2 100.37,160.23 100.37,161.42 99.81,161.98 98.91,161.98 98.44,162.45 98.44,162.86 98.3,163 JEDP.14
CPU_EDP_N1_C: length 5.1
  BOTTOM w0.102: CX47.2 102.34,160.17 102.34,160.47 102.09,160.73 102.07,160.73 101.58,161.21 101.58,161.23 v3(100.91,161.9) 100.51,162.31 99.94,162.87 99.94,163.08 99.8,163.22 JEDP.17
CPU_EDP_P0_C: length 5.4
  BOTTOM w0.102: CX42.2 100.59,160.12 100.59,161.51 99.89,162.21 v3(99.52,162.21) 98.99,162.21 98.66,162.54 98.66,162.86 98.8,163 JEDP.15
CPU_EDP_P1_C: length 5.1
  BOTTOM w0.102: JEDP.18 100.3,163.22 100.16,163.08 100.16,162.96 100.87,162.25 100.89,162.25 101.35,161.79 101.35,161.77 v3(102,161.12) 102.56,160.56 102.56,160.18 CX45.2
CS1: length 8.3
  TOP w0.102: v1(40.24,53.84) 40.27,53.84 41.56,52.55 41.56,50.19 41.18,49.8 40.79,49.8 40.39,50.2
  TOP w0.203: PR105.1 40.39,49.58 39.91,49.09 39.2,49.09 39.1,48.99 PU100.1
CS2: length 6
  TOP w0.102: v1(36.39,53.12) 35.69,52.42 35.69,50.74 PR104.2
  TOP w0.203: PR104.2 36.23,49.37 36.53,49.07 37.29,49.07 37.5,48.86 PU100.5
CS_1.35VP: length 3.4
  TOP w0.102: PR201.2 58.75,46.12 v1(59.12,45.74)
  TOP w0.203: PR201.2 57.99,46.18 57.99,47.5 58.13,47.65 PU200.13
CSIN: length 22.5
  TOP w0.254: v2(137.04,156.33) PR705.1
  BOTTOM w0.254: v2(137.04,156.33) 136.75,156.04 v1(135.07,156.04) 134.42,156.04 129.98,160.49 121.98,160.49 121.47,160.99 121.47,163.79 121.72,164.04 PR700.3
CSIP: length 24.2
  TOP w0.254: v2(137.93,156.33) PR704.1
  BOTTOM w0.254: PR700.2 120.83,164.04 121.09,163.79 121.09,160.84 121.82,160.1 129.82,160.1 134.35,155.57 v1(136.79,155.57) 137.17,155.57 v2(137.93,156.33)
DAT_SMB: length 4.7
  TOP w0.254: PR9.1 v1(159.16,177.45) 159.47,177.76 160.08,177.76 160.4,178.08 PBATT1.5
DBC_EN: length 134.2
  TOP w0.102: v2(110.86,158.21) 110.67,158.4 RX19.2 ; v2(163.25,135.49) 163.25,136.42 165.79,138.96 165.79,144.61 v1(165.58,144.83) 165.44,144.96 v2(165.44,145.5)
  IN2 w0.127: v2(110.79,174.86) 111.26,174.39 111.26,173.54 112.91,171.89 112.91,165.7 112.45,165.24 112.45,160.1 110.86,158.52 v2(110.86,158.21)
  BOTTOM w0.102: UE1.89 154.56,134.27 155.81,135.52 163.25,135.52 v2(163.25,135.49) ; v2(165.44,145.5) 165.44,145.92 171.11,151.58 171.51,151.99 171.51,167.51 171.51,167.51 171.51,168.27 171.51,168.27 171.51,168.33 165.13,174.71 151.26,174.71 150.25,175.72 150.06,175.72 150.06,175.71 148.17,175.71 148.01,175.87 146.84,177.05 134.99,177.05 134.48,176.54 133.66,175.71 111.64,175.71 v2(110.79,174.86)
DBC_EN_R: length 22.4
  TOP w0.102: v2(100.74,166.57) 102.14,165.17 105.81,165.17 106.29,164.69 106.29,164.45 106.85,163.89 106.85,159.91 v1(107.7,159.07) 108.36,158.4 RX19.1 RX23.1
  BOTTOM w0.102: JEDP.8 95.3,165.38 96.23,166.3 100.48,166.3 v2(100.74,166.57)
DBG_UART_RXD: length 1.5
  TOP w0.102: v2(125.11,101.83) 124.95,101.99 T107.1
  BOTTOM w0.102: USOC1.BC16 124.93,102.01 v2(125.11,101.83)
DBG_UART_TXD: length 1.5
  TOP w0.102: v2(123.71,103.28) 123.46,103.03 T106.1
  BOTTOM w0.102: USOC1.BD14 123.78,103.21 v2(123.71,103.28)
DCIN: length 2.1
  BOTTOM w0.102: v1(146.17,158.07) 146.3,157.95 v2(146.3,157.44)
  BOTTOM w0.508: v2(146.3,157.44) 146.36,157.37 146.36,156.83 146.22,156.69 PC711.1
DDI0_RCOMPN: length 1.5
  TOP w0.254: v2(118.91,99.33) 119.23,99.01 RC9.1
  BOTTOM w0.254: v2(118.91,99.33) 118.91,98.71 USOC1.AK13
DDI0_RCOMPP: length 2.4
  TOP w0.102: v1(117.37,98.93) 117.92,98.93 v2(118.15,98.69)
  TOP w0.254: v2(118.15,98.69) 118.61,98.69 RC9.2
  BOTTOM w0.254: USOC1.AK12 118.15,98.96 v2(118.15,98.69)
DDI1_ENABLE: length 3.3
  TOP w0.102: v2(119.42,86.68) 119.42,86.24 v1(118.72,85.54) 118.57,85.39 118.57,85.24 119.12,84.69 RC8.1
  BOTTOM w0.102: USOC1.P30 119.37,86.73 v2(119.42,86.68)
DDI1_ENBKL: length 51
  TOP w0.102: R28.2 88.94,66.06 88.94,65.63 89.96,64.61 RP1.8 90.54,64.53 90.1,64.09 89.34,64.09 v1(88.78,63.53) 88.32,63.08 88.32,61.81 87.54,61.02 87.54,60.27 87.78,60.03 92.49,60.03 104.69,72.23 107.17,72.23 114.86,79.93 114.86,80.73 116.97,82.84 v2(116.97,84.15)
  BOTTOM w0.102: v2(116.97,84.15) 116.97,84.13 117.19,84.35 117.19,85.09 117.36,85.25 USOC1.J30
DDI1_ENVDD: length 70.4
  TOP w0.102: 88.14,69.03 88.12,69.05 R30.1 U68.2 ; 88.14,69.03 89.27,67.9 89.27,67.84 v2(89.29,67.83) 89.63,67.48 89.63,65.55 90.07,65.11 RP1.7 ; 88.14,69.03 v1(88.14,69.02)
  IN1 w0.127: v2(83.19,61.93) 83.19,62.12 86.23,65.16 86.23,66.58 87.48,67.83 v2(89.29,67.83)
  IN2 w0.102: 106.02,86.1 106.72,86.8 108.39,86.8 108.9,86.29 108.9,86.06 109.72,85.24 111.25,85.24 112.83,83.65 115.88,83.65 118.04,85.81 118.4,85.81 v2(118.89,86.3)
  IN2 w0.127: 106.02,86.1 105.11,85.19 100.95,85.19 97.38,81.62 97.38,76.42 96.67,75.71 95.75,75.71 90.99,70.95 90.99,68.85 84.07,61.93 v2(83.19,61.93)
  BOTTOM w0.102: USOC1.N30 118.87,86.32 118.89,86.29 v2(118.89,86.3)
DDI1_PWM: length 76.6
  TOP w0.102: RP1.6 90.07,65.61 89.86,65.82 89.86,67.98 v1(89.45,68.38) 88.58,69.26 v2(88.58,69.3) ; U69.2 95.4,80.6 96.13,79.87 96.13,78.8 97.24,77.69 97.24,75.94 97.68,75.5 99.38,75.5 101,73.87 107.13,73.87 116.38,83.12 116.38,84.09 116.82,84.53 117.37,84.53 v2(118.02,85.18)
  IN1 w0.102: 109.9,82.22 109.92,82.25 110.17,82.25 110.29,82.38 110.29,83.01 110.68,83.4 111.09,83.4 111.28,83.59 116.95,83.59 118.02,84.66 v2(118.02,85.18)
  IN1 w0.127: 109.9,82.22 109.45,81.78 107.88,81.78 107.22,81.12 107.22,79.71 104.38,76.87 101.1,76.87 98.38,74.15 93.34,74.15 88.58,69.38 v2(88.58,69.3)
  BOTTOM w0.102: 118.36,86.35 118.36,85.52 v2(118.02,85.18)
DDR_A_BS0: length 74.3
  IN2 w0.102: v2(123.71,79.44) 123.54,79.62 123.54,79.85 124.07,80.38 124.85,80.38 125.15,80.69 125.66,80.69 127.44,78.91 127.44,78.57 126.08,77.21 126.08,76.4 126.53,75.95 126.53,75.46 126.76,75.23 128.18,75.23 129.17,74.24 129.17,74.21
  IN2 w0.216: v2(104.4,34.99) 104.88,34.99 105.27,35.38 105.27,40.53 105.49,40.75 105.99,40.75 106.11,40.88 106.11,41.36 105.99,41.49 105.62,41.49 105.49,41.61 105.49,42.11 105.62,42.24 106.85,42.24 106.98,42.36 106.98,42.86 114.38,50.26 114.98,50.26 127.87,63.14 128.17,63.14 128.75,62.57 128.93,62.57 129.36,63 129.36,63.18 128.79,63.75 128.79,64.06 129.09,64.36 129.4,64.36 129.97,63.78 130.15,63.78 130.59,64.22 130.59,64.4 130.01,64.97 130.01,65.28 130.85,66.12 130.85,72.54 129.17,74.21
  BOTTOM w0.165: v2(123.71,79.44) 123.74,79.47 123.74,79.98 ; JDIMM2.109 103.8,35.62 103.85,35.57 103.85,34.87 103.98,34.74 104.15,34.74 v2(104.4,34.99)
DDR_A_BS1: length 74.2
  IN2 w0.102: v2(122.82,81.53) 124.03,81.53 124.54,82.04 124.96,82.04 125.18,82.26 125.79,82.26 129.08,78.98 129.08,78.8 131.46,76.43
  IN2 w0.216: 131.46,76.43 133.96,73.93 133.96,63.16 117.84,47.04 115.91,47.04 112.1,43.23 112.1,40.39 108.91,37.21 108.91,35.17 108.29,34.56 107.75,34.56 106.42,33.23 106.04,33.23 104.75,31.95 v2(104.4,31.95)
  BOTTOM w0.165: v2(122.82,81.53) 122.74,81.45 USOC1.K44 ; JDIMM2.108 103.5,30.93 104.37,31.81 104.37,31.82 104.4,31.85 v2(104.4,31.95)
DDR_A_BS2: length 70.8
  IN2 w0.102: 117.82,72.94 118.2,72.94 119.13,73.87 120.6,73.87 v2(120.71,73.75)
  IN2 w0.216: v2(92.56,34.88) 92.56,36.53 91.76,37.34 91.76,41.35 92.14,41.74 92.14,54.47 105.63,67.96 108.56,67.96 109.21,68.6 111.75,68.6 112.27,69.12 112.57,69.12 112.78,68.91 113.09,68.91 113.39,69.21 113.39,69.52 113.18,69.73 113.18,70.04 113.49,70.34 113.79,70.34 114.01,70.13 114.31,70.13 114.62,70.44 114.62,70.74 114.4,70.95 114.4,71.26 114.71,71.57 115.01,71.57 115.5,71.08 115.96,71.08 116.34,71.46 116.34,71.76 115.78,72.33 115.78,72.63 116.23,73.09 116.54,73.09 117.1,72.53 117.41,72.53 117.82,72.94
  BOTTOM w0.102: USOC1.D52 123.52,75.88 123.84,75.55 123.84,75.2 123.49,74.84 123.49,74.39 122.92,73.82 120.78,73.82 v2(120.71,73.75)
  BOTTOM w0.165: JDIMM2.79 94.8,36.93 94.62,36.75 93.69,36.75 92.8,35.86 92.8,35.12 v2(92.56,34.88)
DDR_A_CAS#: length 71
  IN2 w0.102: 131.02,75.99 130.83,76.17 130.83,76.2 128.57,78.47 128.57,79.2 126.06,81.71 125.71,81.71 125.5,81.5 124.87,81.5 124.86,81.51 124.29,81.51 123.82,81.04 v2(123.31,81.04)
  IN2 w0.216: 131.02,75.99 133.33,73.67 133.33,63.42 118.91,49 118.61,49 118.38,49.22 118.08,49.22 117.77,48.92 117.77,48.61 118,48.39 118,48.08 117.68,47.77 117.37,47.77 117.14,47.99 116.88,47.99 116.65,47.77 115.67,47.77 111.45,43.54 111.45,42.93 111.25,42.74 110.64,42.74 110.22,42.31 110.22,39.45 108.26,37.5 108.26,36 v2(108.06,35.8)
  BOTTOM w0.165: USOC1.M44 123.31,81.56 v2(123.31,81.04) ; v2(108.06,35.8) 107.58,35.31 105.89,35.31 105.6,35.6 JDIMM2.115
DDR_A_CKE0: length 71.5
  IN2 w0.102: 114.67,74.45 114.67,74.69 116.52,76.54 118.12,76.54 118.78,75.88 119.83,75.88 120.18,76.23 120.18,76.63 v2(121.62,78.06)
  IN2 w0.216: v2(91.03,36.09) 91.03,36.24 90.3,36.96 90.3,38.21 89.93,38.59 89.93,44.36 90.14,44.57 90.77,44.57 90.9,44.7 90.9,45.31 90.77,45.44 90.14,45.44 89.93,45.65 89.93,46.09 90.14,46.3 90.77,46.3 90.9,46.43 90.9,47.04 90.77,47.16 90.14,47.16 89.93,47.38 89.93,47.81 90.14,48.03 90.77,48.03 90.9,48.16 90.9,48.76 90.77,48.89 90.14,48.89 89.93,49.11 89.93,49.54 90.14,49.76 90.77,49.76 90.9,49.88 90.9,50.49 90.77,50.62 90.14,50.62 89.93,50.84 89.93,51.27 90.14,51.48 90.77,51.48 90.9,51.61 90.9,54.99 105.14,69.23 107.05,69.23 110.42,72.61 112.83,72.61 114.67,74.45
  BOTTOM w0.165: JDIMM2.73 93,36.87 92.74,36.61 91.55,36.61 v2(91.03,36.09) ; USOC1.C47 121.54,78.06 v2(121.62,78.06)
DDR_A_CKE2: length 72.4
  IN2 w0.102: v2(121.71,79.17) 121.71,78.72 120.03,77.05 116.39,77.05 114.23,74.89
  IN2 w0.216: v2(92.17,31.54) 91.31,31.54 90.43,32.42 90.43,35.44 89.53,36.34 89.53,37.98 89.3,38.2 89.3,52.15 89.43,52.28 90.15,52.28 90.28,52.41 90.28,53.17 90.15,53.3 89.43,53.3 89.3,53.42 89.3,53.93 89.49,54.12 89.91,54.12 90.17,54.38 90.17,55.14 104.88,69.85 106.79,69.85 110.31,73.37 112.18,73.37 112.69,73.87 113.21,73.87 114.23,74.89
  BOTTOM w0.165: v2(121.71,79.17) 121.6,79.17 121.28,79.49 USOC1.F44 ; v2(92.17,31.54) 92.57,31.54 93.3,30.81 JDIMM2.74
DDR_A_CLK0: length 72.3
  IN2 w0.102: 127.71,72.75 127.69,72.77 127.43,73.04 127.43,73.57 127.18,73.81 126.65,73.81 125.78,74.68 125.78,75.72 125.36,76.14 125.36,77.93 124.38,78.91 124.38,79.14 v2(124.83,79.6)
  IN2 w0.127: 127.71,72.75 128.1,72.36 128.1,66.83 118.4,57.14 118.01,57.14 117.62,57.52 117.44,57.52 117.17,57.25 117.17,57.07 117.56,56.69 117.56,56.29 117.14,55.87 116.75,55.87 116.36,56.26 116.18,56.26 115.91,55.99 115.91,55.81 116.3,55.42 116.3,55.03 115.87,54.61 115.44,54.61 114.62,55.42 114.32,55.42 114.09,55.19 114.09,54.92 114.52,54.49 114.52,53.97 114.26,53.7 113.46,53.7 113.15,54.01 113.02,54.01 112.73,53.72 103.51,44.5 103.51,43.77 103.18,43.44 102.27,43.44 102.13,43.3 102.13,42.87 102.27,42.73 102.69,42.73 102.97,42.45 102.97,41.92 102.69,41.64 102.29,41.64 102.16,41.52 102.16,41.14 102.29,41.01 102.52,41.01 102.8,40.73 102.8,40.02 102.56,39.78 102.33,39.78 102.21,39.66 102.21,38.95 102.33,38.82 102.51,38.82 102.79,38.54 102.79,37.95 102.51,37.68 102.26,37.68 102.13,37.55 102.13,37.04 102.22,36.95 102.31,36.95 102.57,36.7 102.57,35.5 101.87,34.81 v2(101.87,34.75)
  BOTTOM w0.102: JDIMM2.101 101.4,36.68 101.07,36.36 101.07,35.97 101.25,35.8 101.25,35.17 101.48,34.95 101.68,34.95 v2(101.87,34.75) ; USOC1.M50 124.95,79.7 124.85,79.6 v2(124.83,79.6)
DDR_A_CLK0#: length 72.3
  IN2 w0.102: 127.53,72.57 127.52,72.58 127.52,72.59 127.47,72.65 127.47,72.67 127.46,72.67 127.19,72.94 127.19,73.47 127.08,73.58 126.55,73.58 126.49,73.65 126.49,73.65 125.55,74.58 125.55,75.62 125.13,76.04 125.13,76.15 125.12,76.16 125.12,77.83 124.14,78.81 124.14,79.29 124.45,79.61 124.45,79.95 v2(124.4,80)
  IN2 w0.127: 127.53,72.57 127.84,72.26 127.84,66.94 118.29,57.39 118.12,57.39 117.73,57.78 117.34,57.78 116.92,57.36 116.92,56.96 117.3,56.58 117.3,56.4 117.03,56.13 116.85,56.13 116.47,56.52 116.08,56.52 115.66,56.09 115.66,55.7 116.04,55.32 116.04,55.14 115.77,54.86 115.54,54.86 114.72,55.68 114.21,55.68 113.84,55.3 113.84,54.81 114.27,54.38 114.27,54.08 114.15,53.96 113.56,53.96 113.26,54.26 112.91,54.26 112.62,53.97 103.25,44.6 103.25,43.88 103.07,43.7 102.16,43.7 101.87,43.41 101.87,42.76 102.16,42.47 102.58,42.47 102.71,42.35 102.71,42.03 102.58,41.9 102.19,41.9 101.91,41.62 101.91,41.03 102.19,40.75 102.41,40.75 102.54,40.63 102.54,40.13 102.45,40.04 102.23,40.04 101.95,39.76 101.95,38.84 102.23,38.56 102.41,38.56 102.53,38.44 102.53,38.06 102.41,37.93 102.15,37.93 101.87,37.66 101.87,36.93 102.11,36.7 102.21,36.7 102.31,36.59 102.31,35.61 102.11,35.4 101.98,35.4 101.87,35.51 v2(101.87,35.52)
  BOTTOM w0.102: USOC1.M48 124.57,80.18 v2(124.4,80) ; v2(101.87,35.52) 101.94,35.45 101.94,35.22 101.87,35.16 101.57,35.16 101.47,35.26 101.47,35.89 101.29,36.06 101.29,36.27 101.64,36.62 101.64,36.83 101.71,36.89 101.94,36.89 102,36.95 JDIMM2.103
DDR_A_CLK2: length 71.4
  IN2 w0.102: v2(125.95,79.81) 125.76,79.81 125.67,79.73 125.67,79.61 125.67,79.51 126.02,79.16 126.02,77.86 125.82,77.65 125.82,76.32 126.23,75.9 126.23,74.98 126.78,74.43 127.26,74.43 127.65,74.04
  IN2 w0.127: 127.65,74.04 129.12,72.57 129.12,66.41 115.39,52.68 113.14,52.68 104.53,44.07 104.53,43.35 103.99,42.82 103.99,41.46 103.82,41.28 103.82,37.08 103.59,36.85 103.59,34.63 103.32,34.36 102.93,34.36 102.8,34.23 102.8,33.83 102.93,33.7 103.3,33.7 103.58,33.42 103.58,31.4 103.3,31.12 102.74,31.12 102.47,31.4 102.47,32.45 102.3,32.62 102.07,32.62 v2(101.9,32.44)
  BOTTOM w0.102: JDIMM2.102 101.7,30.81 101.94,31.05 102.51,31.62 102.51,32.58 102.3,32.79 102.01,32.79 101.9,32.67 v2(101.9,32.44) ; v2(125.95,79.81) 125.96,79.81 126.12,79.98 USOC1.P50
DDR_A_CLK2#: length 71.4
  IN2 w0.102: 127.39,73.94 127.13,74.2 126.69,74.2 126,74.88 126,75.81 125.59,76.22 125.59,77.75 125.79,77.95 125.79,79.07 125.58,79.28 125.44,79.41 125.44,79.42 125.44,79.82 125.46,79.84 125.46,80.26 v2(125.5,80.3)
  IN2 w0.127: v2(101.9,33.2) 101.9,33.04 102.06,32.88 102.4,32.88 102.72,32.56 102.72,31.5 102.85,31.38 103.19,31.38 103.32,31.5 103.32,33.32 103.19,33.44 102.82,33.44 102.54,33.72 102.54,34.34 102.82,34.62 103.21,34.62 103.33,34.74 103.33,36.96 103.56,37.18 103.56,41.39 103.74,41.57 103.74,42.92 104.27,43.46 104.27,44.18 113.03,52.94 115.29,52.94 128.86,66.52 128.86,72.47 127.39,73.94
  BOTTOM w0.102: JDIMM2.104 102.3,31.11 102.72,31.53 102.72,32.67 102.39,33 102.1,33 v2(101.9,33.2) ; USOC1.P48 125.69,80.84 125.69,80.49 v2(125.5,80.3)
DDR_A_CS0#: length 76.8
  IN2 w0.102: 132.56,77.93 132.39,78.1 131.22,78.1 128.9,80.43 128.58,80.43 125.1,83.91 123.53,83.91 123.31,83.69 123.31,83.33 123.4,83.23 v2(123.4,82.43)
  IN2 w0.216: 132.56,77.93 132.59,77.93 135.82,74.7 135.82,62.06 116.1,42.33 115.93,42.33 115.66,42.06 114.96,41.36 114.96,39.47 109.86,34.37 108.99,34.37 108.16,33.54 107.77,33.54 106.52,32.29 106.52,32.25 v2(106.22,31.95)
  BOTTOM w0.165: v2(106.22,31.95) 106.19,31.92 106.19,31.88 105.3,30.99 JDIMM2.114 ; USOC1.P44 124.09,82.43 v2(123.4,82.43)
DDR_A_CS2#: length 75.5
  IN2 w0.102: 131.37,77.05 129.4,79.03 129.4,79.04 125.11,83.33 124.03,83.33 123.81,83.1 123.81,82.56 123.9,82.48 v2(123.9,81.94)
  IN2 w0.216: 131.37,77.05 131.71,77.05 134.58,74.18 134.58,62.85 117.7,45.97 117.32,45.97 116.87,46.42 116.69,46.42 116.3,46.03 116.3,45.85 116.86,45.3 116.86,45.13 116.56,44.83 116.25,44.83 115.59,45.49 115.28,45.49 114.98,45.19 114.98,44.88 115.64,44.22 115.64,43.91 115.21,43.49 114.88,43.49 114.51,43.86 114.06,43.86 112.76,42.55 112.76,39.99 109.58,36.81 v2(109.58,36.55)
  BOTTOM w0.165: v2(109.58,36.55) 109.28,36.55 109.15,36.42 109.15,35.39 109.02,35.26 108.76,35.26 108.63,35.39 108.63,36.39 108.5,36.52 107.58,36.52 107.4,36.7 JDIMM2.121 ; USOC1.P45 123.95,81.88 v2(123.9,81.94)
DDR_A_D0: length 88.7
  IN1 w0.102: 115.58,82.01 116.91,82.01 119.16,84.26 v2(121.01,84.26)
  IN1 w0.127: v2(69.01,39.64) 68.65,39.64 68.59,39.71 68.59,41.01 69.05,41.46 69.05,43.16 69.42,43.54 69.42,45.59 87.27,63.43 88.47,63.43 89.78,64.74 90.14,64.74 90.42,64.46 90.6,64.46 90.93,64.78 90.93,64.96 90.58,65.31 90.58,65.49 91.14,66.05 91.32,66.05 92.32,65.05 92.78,65.05 93.39,65.66 93.39,65.84 92.78,66.45 92.78,66.63 93.05,66.9 93.23,66.9 93.84,66.29 94.02,66.29 94.29,66.56 94.29,66.74 93.75,67.27 93.75,67.45 94.02,67.72 94.2,67.72 94.74,67.19 94.92,67.19 95.19,67.46 95.19,67.64 94.79,68.04 94.79,68.22 95.05,68.49 95.23,68.49 95.64,68.09 95.82,68.09 96.23,68.5 97.6,68.5 97.94,68.84 97.94,69.01 97.73,69.22 97.73,69.4 98,69.67 98.18,69.67 98.39,69.46 98.57,69.46 99.22,70.11 99.22,70.29 98.75,70.76 98.75,70.94 99.02,71.21 99.2,71.21 99.67,70.74 99.85,70.74 100.12,71.01 100.12,71.19 99.49,71.82 99.49,71.99 99.76,72.26 99.94,72.26 100.56,71.64 100.74,71.64 102.9,73.8 102.9,73.93 103.38,74.42 105.04,74.42 108.01,77.39 108.73,77.39 111.7,80.36 113.94,80.36 115.58,82.01
  BOTTOM w0.102: v2(121.01,84.26) 120.98,84.29 USOC1.M36 ; v2(69.01,39.64) 69.59,39.64 70.2,39.03 JDIMM2.5
DDR_A_D1: length 88.4
  IN1 w0.102: v2(119.56,82.75) 119.7,82.6 119.7,82.25 118.86,81.41
  IN1 w0.127: v2(72,35.09) 72.56,35.09 72.69,35.22 72.69,37.09 72.56,37.22 71.61,37.22 71.49,37.35 71.49,37.85 71.61,37.98 71.75,37.98 71.88,38.11 71.88,38.53 71.75,38.65 71.57,38.65 71.44,38.78 71.44,41.46 71.44,42.03 71.85,42.44 71.85,44.23 87.52,59.9 88.07,59.9 89.01,60.84 92.03,60.84 92.41,61.22 92.87,61.22 93.25,60.84 93.43,60.84 93.78,61.19 93.78,61.37 93.26,61.89 93.26,62.07 93.57,62.38 93.75,62.38 94.58,61.54 94.93,61.54 95.1,61.71 95.1,61.89 94.18,62.81 94.18,62.99 94.45,63.26 94.63,63.26 95.55,62.34 95.73,62.34 96,62.61 96,62.79 95.08,63.71 95.08,63.89 95.35,64.16 95.53,64.16 96.44,63.24 96.62,63.24 105.37,71.98 106.71,71.98 112.28,77.54 114.37,77.54 115.77,78.93 116.38,78.93 117.25,79.8 117.43,79.8 117.66,79.57 117.84,79.57 118.12,79.85 118.12,80.03 117.89,80.26 117.89,80.44 118.86,81.41
  BOTTOM w0.102: v2(72,35.09) 70.8,36.29 JDIMM2.7 ; v2(119.56,82.75) 119.42,82.88 USOC1.J36
DDR_A_D2: length 88
  IN1 w0.127: v2(72.61,39.45) 73.05,39.01 73.41,39.01 73.65,39.25 73.65,42.98 86.19,55.52 87.36,55.52 89.21,57.36 90.02,57.36 90.38,57.72 93.58,57.72 94.46,58.6 94.64,58.6 95.25,57.99 95.43,57.99 95.7,58.26 95.7,58.44 95.09,59.04 95.09,59.22 95.36,59.49 95.54,59.49 96.15,58.89 96.32,58.89 96.59,59.16 96.59,59.34 95.99,59.94 95.99,60.12 96.26,60.39 96.44,60.39 97.04,59.79 97.22,59.79 97.49,60.05 97.49,60.23 96.89,60.84 96.89,61.02 97.16,61.29 97.34,61.29 97.94,60.68 98.12,60.68 98.39,60.95 98.39,61.13 97.78,61.74 97.78,61.92 98.05,62.19 98.23,62.19 98.84,61.58 99.02,61.58 99.29,61.85 99.29,62.03 98.68,62.64 98.68,62.82 98.95,63.09 99.13,63.09 99.74,62.48 99.92,62.48 100.19,62.75 100.19,62.93 99.58,63.53 99.58,63.71 99.85,63.98 100.03,63.98 100.64,63.38 100.82,63.38 101.08,63.65 101.08,63.83 100.48,64.43 100.48,64.61 106.09,70.23 107.44,70.23 112.2,74.99 114.57,74.99 117.06,77.48 118.78,77.48 119.61,78.31 119.61,79.32 121.89,81.6 v2(121.89,83.58)
  BOTTOM w0.102: JDIMM2.15 73.2,38.86 v2(72.61,39.45) ; v2(121.89,83.58) 121.95,83.65 122.39,83.65 122.56,83.82 USOC1.P40
DDR_A_D3: length 88.1
  IN1 w0.102: v2(121.28,83.02) 121.28,82.38 121.02,82.12 121.02,81.96 118.99,79.93 118.99,78.94
  IN1 w0.127: 118.99,78.94 118.19,78.14 116.86,78.14 115.09,76.37 114.47,76.37 114.33,76.23 114.33,75.74 114.17,75.57 113.54,75.57 113.38,75.74 113.38,76.22 113.23,76.37 112.76,76.37 112.54,76.15 112.54,75.78 112.37,75.61 112,75.61 107.2,70.81 105.85,70.81 94.56,59.52 93.77,59.52 93.57,59.32 93.57,58.53 93.34,58.3 93.02,58.3 92.9,58.43 92.9,59.51 92.77,59.63 92.39,59.63 92.26,59.51 92.26,58.43 92.13,58.3 91.75,58.3 91.63,58.43 91.63,59.51 91.5,59.63 91.12,59.63 90.99,59.51 90.99,58.43 90.86,58.3 90.14,58.3 89.78,57.95 88.96,57.95 88.21,57.2 88.06,57.2 87.7,57.56 87.52,57.56 87.31,57.35 87.31,57.17 87.67,56.81 87.67,56.65 87.41,56.39 87.02,56.39 86.43,56.98 86.25,56.98 85.78,56.51 85.78,56.33 85.89,56.23 85.89,56.05 85.65,55.8 85.47,55.8 85.36,55.91 85.18,55.91 84.91,55.64 84.91,55.46 85.02,55.35 85.02,55.17 84.75,54.9 84.57,54.9 84.46,55.01 84.28,55.01 84.01,54.74 84.01,54.56 84.12,54.46 84.12,54.28 83.85,54.01 83.67,54.01 83.57,54.11 83.39,54.11 83.12,53.84 83.12,53.66 83.22,53.56 83.22,53.38 82.95,53.11 82.77,53.11 82.67,53.21 82.49,53.21 82.22,52.94 82.22,52.76 82.32,52.66 82.32,52.48 82.05,52.21 81.87,52.21 81.77,52.31 81.59,52.31 81.33,52.04 81.33,51.86 81.43,51.76 81.43,51.58 81.16,51.31 80.98,51.31 80.88,51.41 80.7,51.41 80.43,51.14 80.43,50.96 80.53,50.86 80.53,50.68 80.26,50.41 80.08,50.41 79.98,50.51 79.8,50.51 79.53,50.24 79.53,50.06 79.63,49.96 79.63,49.79 79.36,49.52 79.18,49.52 79.08,49.62 78.9,49.62 78.63,49.35 78.63,49.17 78.73,49.07 78.73,48.89 78.46,48.62 78.28,48.62 78.18,48.72 78,48.72 77.73,48.45 77.73,48.27 77.83,48.17 77.83,47.99 77.56,47.72 77.38,47.72 77.28,47.82 77.1,47.82 76.83,47.55 76.83,47.37 76.93,47.27 76.93,47.09 76.67,46.82 76.49,46.82 76.39,46.92 76.21,46.92 75.94,46.65 75.94,46.47 76.04,46.37 76.04,46.19 75.77,45.92 75.59,45.92 75.49,46.02 75.31,46.02 75.04,45.75 75.04,45.57 75.14,45.47 75.14,45.29 74.87,45.03 74.69,45.03 74.59,45.12 74.41,45.12 74.14,44.86 74.14,44.68 74.24,44.58 74.24,44.4 73.97,44.13 73.79,44.13 73.69,44.23 73.51,44.23 73.24,43.96 73.24,43.78 73.34,43.68 73.34,43.5 73.03,43.19 73.03,41.21 72.8,40.98 v2(72.61,40.98)
  BOTTOM w0.102: v2(72.61,40.98) 73.8,39.79 JDIMM2.17 ; USOC1.M40 121.29,83.02 v2(121.28,83.02)
DDR_A_D4: length 88.4
  IN1 w0.102: 116.12,83.12 117.1,83.12 118.86,84.88 120.75,84.88 v2(121.65,85.78)
  IN1 w0.127: 116.12,83.12 114.21,83.12 112.75,81.66 111.35,81.66 108.25,78.56 107.5,78.56 104.53,75.59 103.26,75.59 102.75,75.59 102.3,75.14 102.3,75.09 101.86,74.65 101.8,74.65 100.64,73.49 98.9,73.49 95.54,70.12 92.31,70.12 86.93,64.75 86.93,64.75 71.09,48.9 67.39,45.2 67.39,35.77 68.37,34.79 68.37,33.22 v2(70.2,31.4)
  BOTTOM w0.102: USOC1.P36 121.43,85.56 v2(121.65,85.78) ; JDIMM2.4 69.9,31.1 v2(70.2,31.4)
DDR_A_D5: length 88.9
  IN1 w0.102: 116.31,82.56 117.04,82.56 119.01,84.53 120.73,84.53 120.99,84.79 v2(121.6,84.79)
  IN1 w0.127: v2(70.2,32.92) 68.98,34.14 68.98,35.01 67.97,36.01 67.97,43.58 68.1,43.71 68.37,43.71 68.5,43.83 68.5,44.21 68.37,44.34 68.1,44.34 67.97,44.47 67.97,44.9 68.1,45.03 68.49,45.03 68.62,45.16 68.62,45.61 87.14,64.13 88.34,64.13 90.93,66.72 91.99,66.72 94.36,69.08 96.59,69.08 97.33,69.83 97.33,71.09 99.09,72.85 100.86,72.85 102.08,74.06 102.1,74.06 102.89,74.85 102.9,74.85 103.05,75 104.79,75 107.77,77.97 108.49,77.97 111.41,80.89 112.93,80.89 114.6,82.56 116.31,82.56
  BOTTOM w0.102: v2(70.2,32.92) 70.67,32.45 70.67,31.07 70.5,30.9 JDIMM2.6 ; USOC1.N36 121.6,84.79 v2(121.6,84.79)
DDR_A_D6: length 88.5
  IN1 w0.102: 118.41,79.24 118.58,79.41 118.58,79.81 120.78,82.01 v2(120.78,82.55)
  IN1 w0.127: 118.41,79.24 117.76,78.6 116.35,78.6 114.72,76.96 112.52,76.96 106.96,71.39 105.61,71.39 94.47,60.26 90.48,60.26 90.35,60.13 90.35,59.14 90.23,59.01 89.85,59.01 89.72,59.14 89.72,59.9 89.59,60.03 89.08,60.03 88.96,59.9 88.96,58.76 88.83,58.63 88.32,58.63 88.19,58.76 88.19,58.97 88.07,59.1 87.56,59.1 87.43,58.97 87.43,58.38 87.31,58.25 86.7,58.25 72.43,43.99 72.43,42.16 72.03,41.75 72.03,39.21 73.3,37.94 73.3,37.52 73.42,37.4 73.87,37.4 74,37.27 74,36.89 73.87,36.76 73.42,36.76 73.3,36.63 73.3,36.25 73.42,36.13 73.87,36.13 74,36 74,35.62 73.87,35.49 73.42,35.49 73.3,35.36 73.3,34.98 73.42,34.86 74.1,34.86 74.22,34.73 74.22,34.35 74.1,34.22 73.42,34.22 73.3,34.09 73.3,33.16 73.53,32.92 v2(74.16,32.92)
  BOTTOM w0.102: v2(74.16,32.92) 73.5,32.26 JDIMM2.16 ; USOC1.K40 120.93,82.39 v2(120.78,82.55)
DDR_A_D7: length 88.5
  IN1 w0.127: v2(122.15,81.03) 122.15,80.53 120.17,78.55 120.17,77.99 119.2,77.01 117.13,77.01 114.46,74.34 112.38,74.34 107.68,69.64 107.44,69.64 106.88,69.08 106.7,69.08 106.52,69.26 106.34,69.26 106.07,68.99 106.07,68.81 106.49,68.39 106.49,68.21 106.22,67.94 106.04,67.94 105.46,68.53 105.28,68.53 105.01,68.26 105.01,68.08 105.6,67.49 105.6,67.31 105.33,67.04 105.15,67.04 104.56,67.63 104.38,67.63 104.11,67.36 104.11,67.18 104.7,66.59 104.7,66.41 104.43,66.14 104.25,66.14 103.66,66.73 103.48,66.73 103.21,66.46 103.21,66.28 103.56,65.94 103.56,65.76 103.29,65.49 103.11,65.49 102.76,65.83 102.58,65.83 102.32,65.56 102.32,65.38 102.9,64.8 102.9,64.62 102.64,64.36 102.46,64.36 101.86,64.96 101.68,64.96 101.42,64.69 101.42,64.51 102.01,63.91 102.01,63.73 95.42,57.13 90.62,57.13 90.26,56.78 89.45,56.78 87.6,54.93 86.43,54.93 74.24,42.74 74.24,37.94 74.82,37.36 74.82,32.06 v2(74.16,31.4)
  BOTTOM w0.102: v2(122.15,81.03) 122,81.18 USOC1.K42 ; JDIMM2.18 74.1,31.34 v2(74.16,31.4)
DDR_A_D8: length 74.3
  IN1 w0.127: v2(75.4,40.98) 75.82,41.4 75.82,42.67 83.17,50.02 83.52,50.02 83.79,49.75 84.08,49.75 84.37,50.05 84.37,50.22 83.97,50.62 83.97,50.8 84.24,51.07 84.42,51.07 84.82,50.67 85,50.67 85.27,50.94 85.27,51.12 84.87,51.52 84.87,51.7 85.14,51.97 85.32,51.97 85.72,51.57 85.9,51.57 86.17,51.84 86.17,52.02 85.77,52.42 85.77,52.6 86.04,52.87 86.22,52.87 86.61,52.47 86.79,52.47 87.06,52.74 87.06,52.92 86.67,53.32 86.67,53.5 86.94,53.76 87.12,53.76 87.51,53.37 87.69,53.37 89.06,54.73 89.7,54.73 89.82,54.86 89.82,55.37 89.95,55.49 90.33,55.49 90.46,55.37 90.46,54.86 90.58,54.73 90.97,54.73 91.09,54.86 91.09,55.84 91.22,55.96 91.6,55.96 91.73,55.84 91.73,54.86 91.85,54.73 94.67,54.73 108.98,69.05 v2(108.98,69.94)
  BOTTOM w0.102: USOC1.B32 115.13,81.72 115.13,81.42 113.3,79.59 113.3,78.98 112.96,78.64 112.96,77.32 108.98,73.34 v2(108.98,69.94) ; v2(75.4,40.98) 74.61,40.18 74.61,39.45 75,39.06 JDIMM2.21
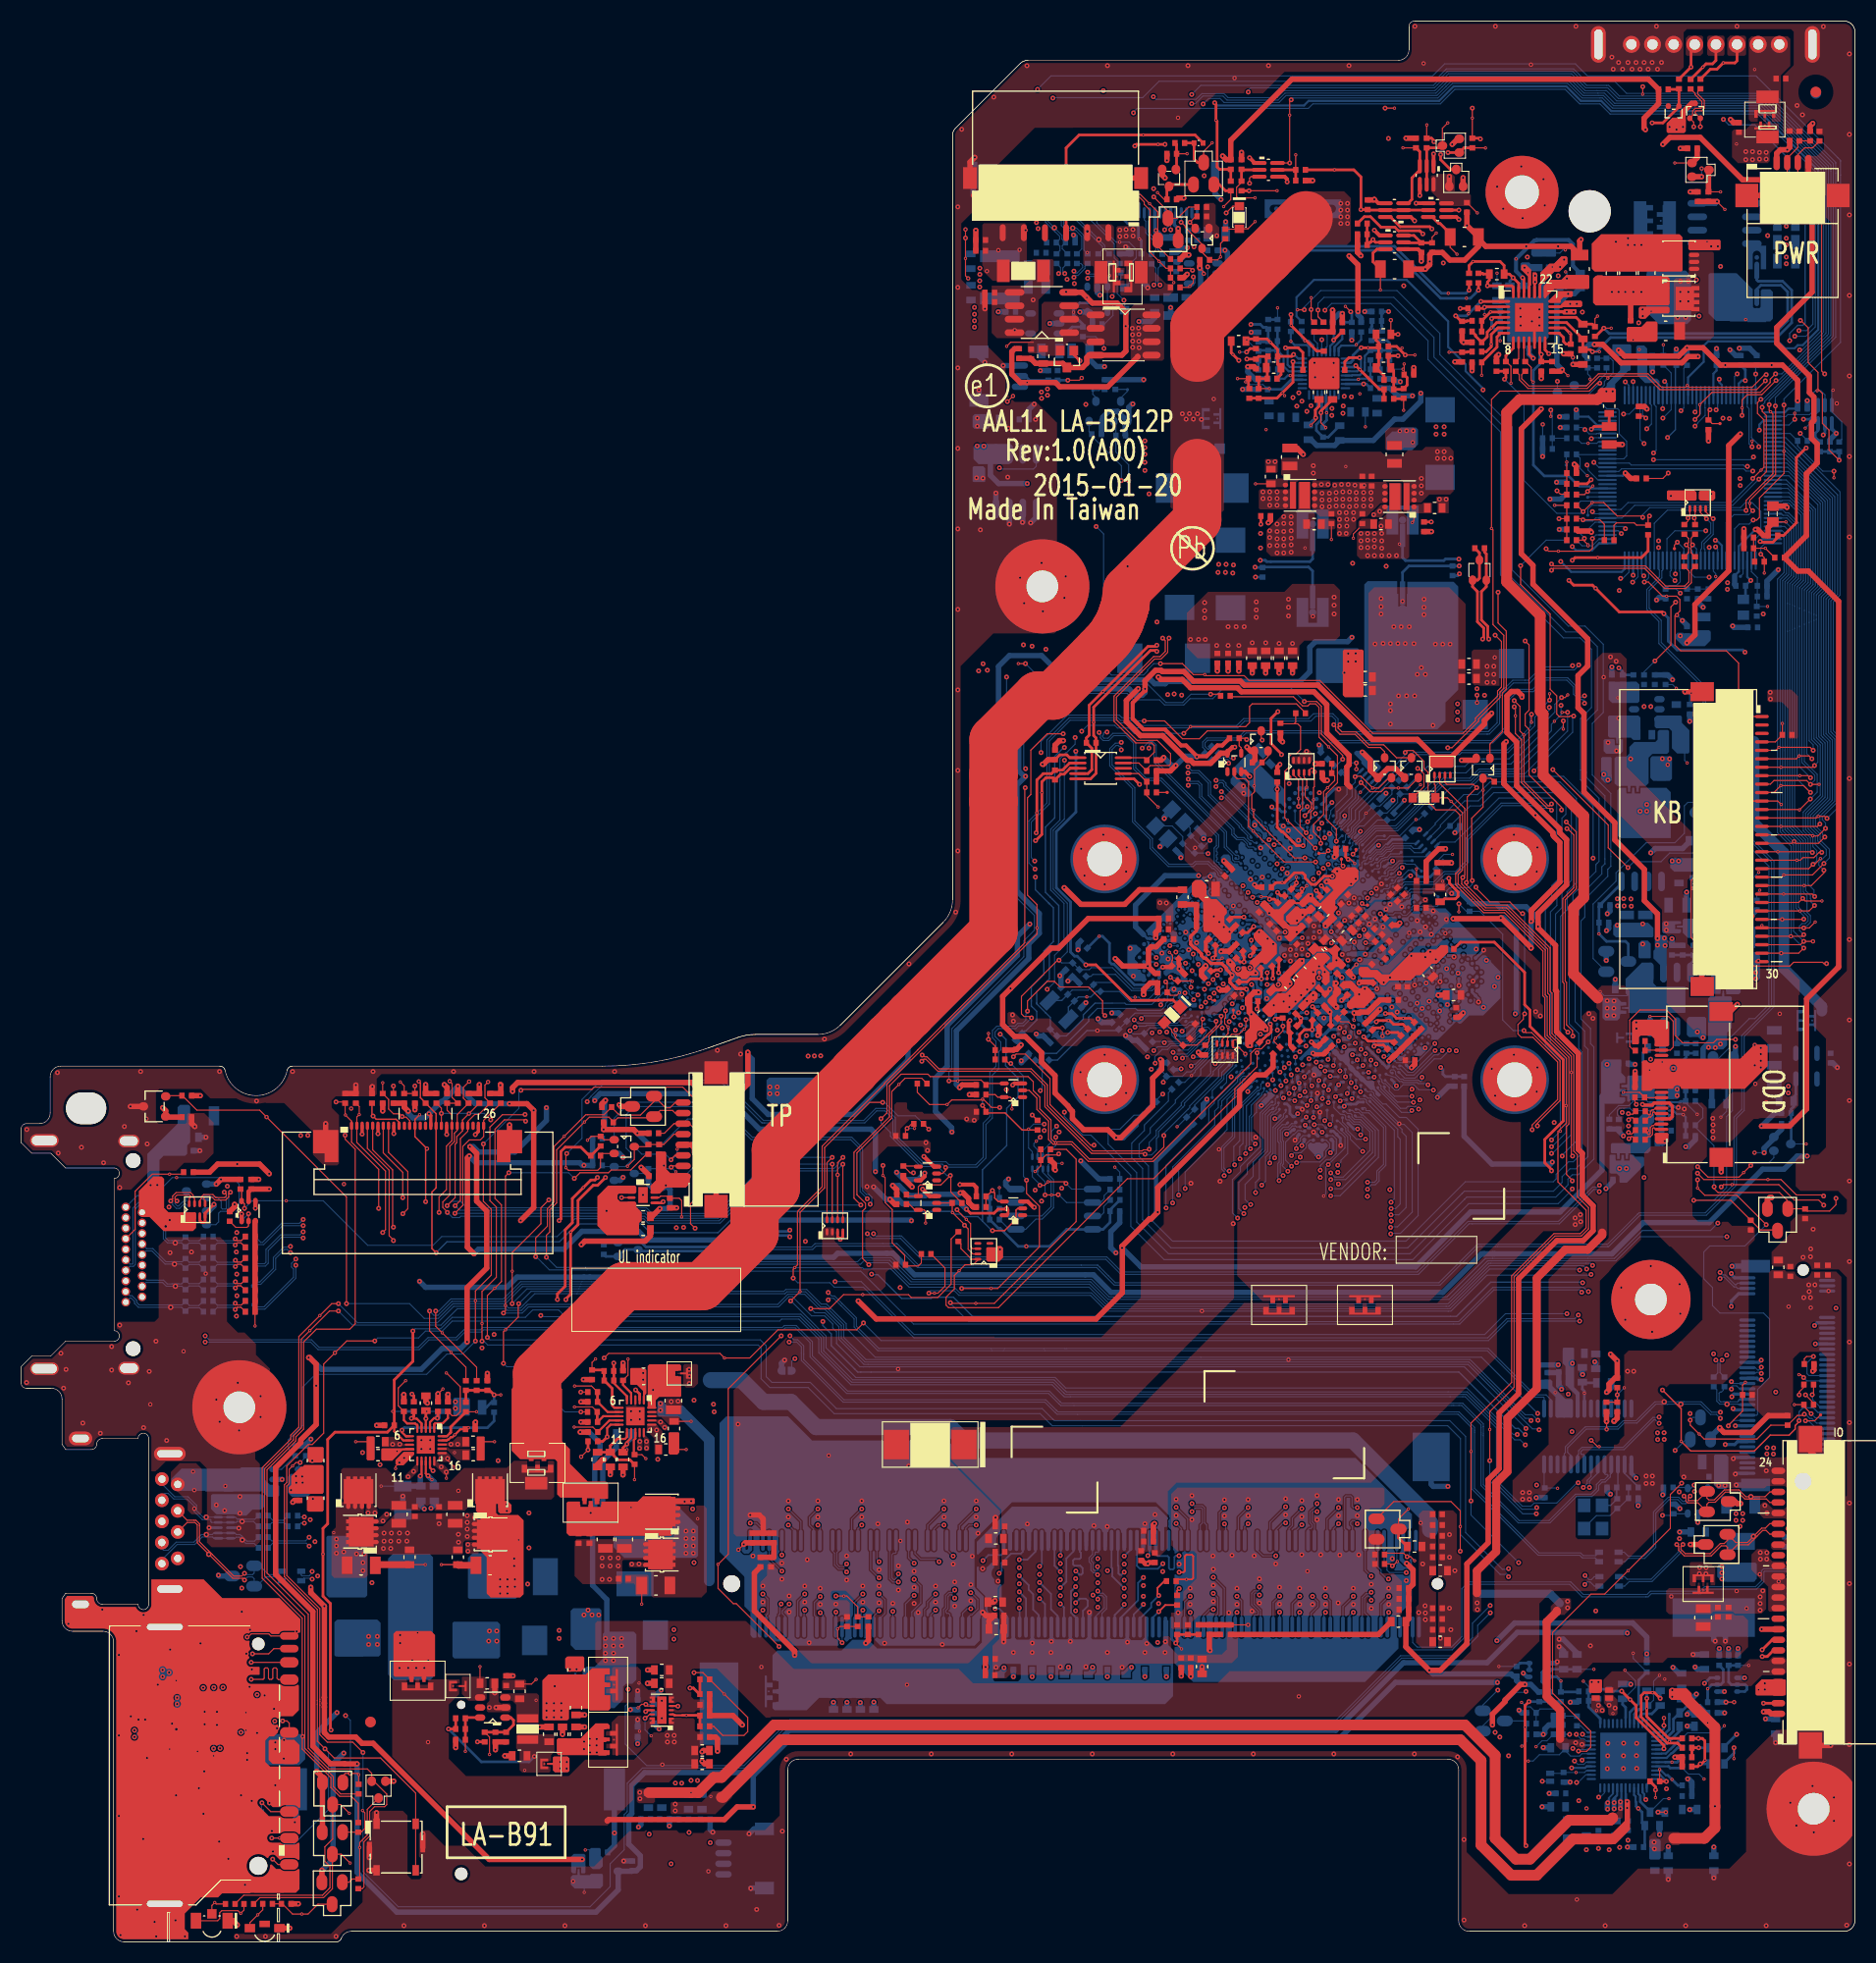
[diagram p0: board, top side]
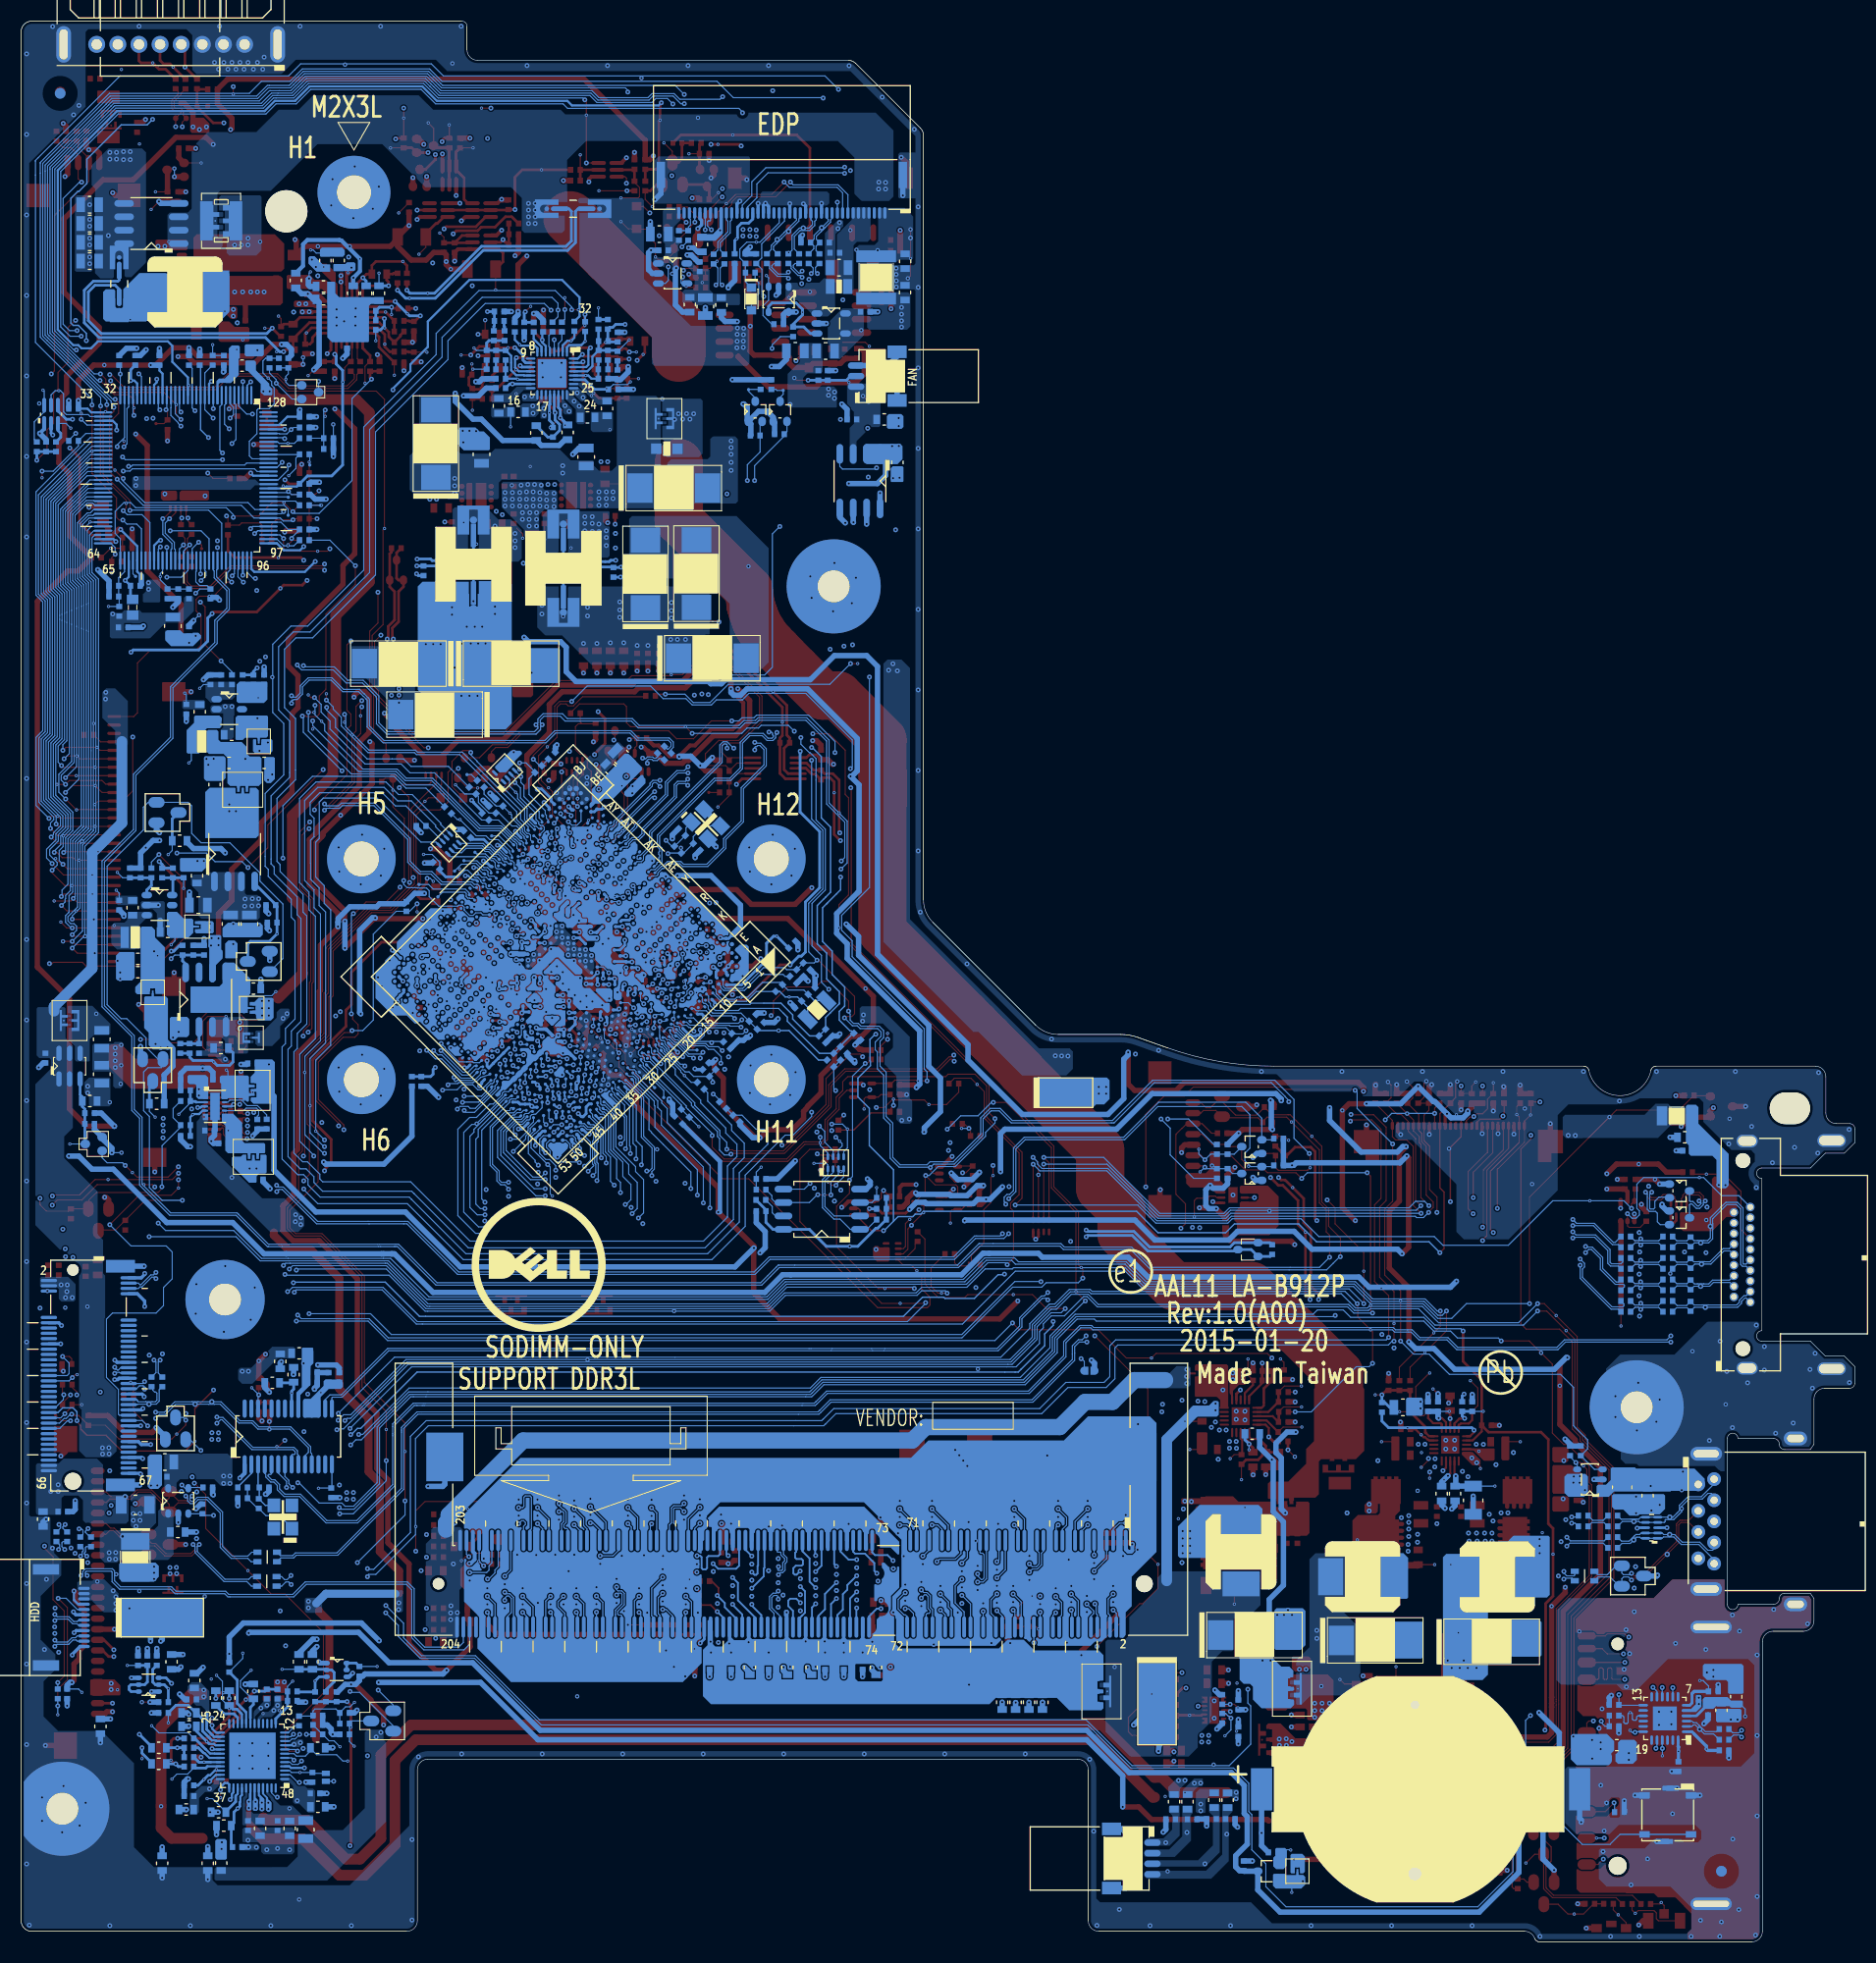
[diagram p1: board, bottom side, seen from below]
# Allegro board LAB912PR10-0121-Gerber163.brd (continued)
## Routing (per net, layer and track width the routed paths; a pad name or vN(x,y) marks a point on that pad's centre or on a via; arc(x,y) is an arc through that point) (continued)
DDR_A_D9: length 73.7
  IN1 w0.127: v2(75.4,39.45) 75.65,39.21 75.65,38.18 75.52,38.06 74.95,38.06 74.82,38.18 74.82,42.5 86.67,54.35 87.85,54.35 89.69,56.19 90.51,56.19 90.86,56.55 91.84,56.55 92.32,56.07 92.32,55.46 92.45,55.33 92.83,55.33 92.95,55.46 92.95,56.42 93.08,56.55 93.46,56.55 93.59,56.42 93.59,55.46 93.72,55.33 94.1,55.33 94.22,55.46 94.22,56.24 94.53,56.55 95.66,56.55 108.36,69.25 v2(108.36,69.46)
  BOTTOM w0.102: v2(75.4,39.45) 75.6,39.26 JDIMM2.23 ; USOC1.C32 115.95,82.55 115.52,82.55 115.35,82.38 115.35,82.24 114.93,81.81 114.93,81.6 112.92,79.59 112.92,79.39 112.4,78.87 112.4,77.55 108.35,73.5 108.35,69.48 v2(108.36,69.46)
DDR_A_D10: length 73.8
  IN1 w0.127: v2(115.36,74.11) 115.43,74.03 115.43,72.97 113.92,71.46 113.92,70.82 112.53,69.43 112.53,67.3 96.44,51.2 90.76,51.2 82.87,43.31 81.84,43.31 81.72,43.19 81.72,42.65 81.84,42.53 82.83,42.53 82.96,42.4 82.96,40.29 82.83,40.17 82.33,40.17 82.2,40.29 82.2,41.66 82.07,41.79 81.64,41.79 81.51,41.66 81.51,40.19 81.39,40.06 80.97,40.06 80.84,40.19 80.84,41.61 80.71,41.74 80.33,41.74 80.21,41.61 80.21,40.74 80.08,40.61 79.68,40.61 79.56,40.74 v2(79.56,40.98)
  BOTTOM w0.102: USOC1.C36 117.33,81.18 117.33,80.75 117.15,80.57 117.02,80.57 115.64,79.2 115.64,75.58 115.33,75.27 115.33,74.13 v2(115.36,74.11) ; v2(79.56,40.98) 78.6,40.02 JDIMM2.33
DDR_A_D11: length 73.3
  IN1 w0.127: v2(115.89,74.61) 116.02,74.49 116.02,72.73 114.61,71.33 114.61,70.69 113.11,69.19 113.11,67.05 96.68,50.62 91,50.62 83.89,43.51 83.89,40.4 83.46,39.96 83.46,38.57 83.57,38.45 83.76,38.45 83.89,38.32 83.89,37.82 83.76,37.69 82.26,37.69 82.14,37.82 82.14,38.96 82.01,39.09 81.57,39.09 81.45,38.96 81.45,37.79 81.32,37.66 80.96,37.66 80.83,37.79 80.83,38.96 80.7,39.09 80.33,39.09 80.21,38.96 80.21,37.56 80.08,37.43 79.7,37.43 79.55,37.59 79.55,39.44 v2(79.56,39.45)
  BOTTOM w0.102: v2(79.56,39.45) 79.2,39.1 JDIMM2.35 ; v2(115.89,74.61) 115.89,75.29 115.97,75.37 115.97,79.13 USOC1.A37
DDR_A_D12: length 73.7
  IN1 w0.127: v2(75.63,32.68) 76.11,33.15 76.11,36.52 76.41,36.82 76.41,42.43 83.15,49.17 84.32,49.17 89.3,54.15 94.91,54.15 109.57,68.8 109.57,70.67 v2(109.55,70.68)
  BOTTOM w0.102: JDIMM2.22 75.3,30.7 75.07,30.92 75.07,32.12 v2(75.63,32.68) ; v2(109.55,70.68) 109.55,73.09 113.57,77.11 113.57,79.12 113.63,79.18 113.63,79.57 115.36,81.29 115.36,81.67 115.64,81.95 116.04,81.95 USOC1.C33
DDR_A_D13: length 74.1
  IN1 w0.127: v2(75.63,31.16) 75.63,31.15 75.63,30.75 75.76,30.63 76.4,30.63 76.53,30.75 76.53,32.62 76.69,32.79 76.69,36.24 76.99,36.54 76.99,42.19 83.39,48.59 84.56,48.59 89.54,53.57 95.41,53.57 110.17,68.32 v2(110.17,71.31)
  BOTTOM w0.102: JDIMM2.24 75.9,30.89 v2(75.63,31.16) ; v2(110.17,71.31) 110.17,72.87 112.79,75.5 113.9,76.6 113.9,76.65 114.13,76.88 114.13,79.73 115.58,81.19 115.58,81.49 USOC1.A33
DDR_A_D14: length 73.4
  IN1 w0.127: v2(116.35,75.07) 116.64,74.78 116.64,72.53 115.26,71.15 115.26,70.51 113.7,68.95 113.7,66.81 96.92,50.03 91.24,50.03 84.48,43.27 84.48,37.4 84.16,37.08 80.88,37.08 79.85,36.06 79.85,34.47 79.62,34.23 79.29,34.23 79.17,34.11 79.17,33.05 79.29,32.92 v2(79.66,32.92)
  BOTTOM w0.102: USOC1.C37 117.63,80.54 117.42,80.33 117.42,80.18 116.43,79.19 116.43,78.32 116.24,78.13 116.24,75.18 v2(116.35,75.07) ; JDIMM2.34 78.9,32.16 v2(79.66,32.92)
DDR_A_D15: length 72.4
  IN1 w0.127: v2(79.66,31.4) 80.44,32.18 80.44,35.81 81.12,36.49 84.82,36.49 85.06,36.74 85.06,43.02 91.48,49.45 97.16,49.45 114.28,66.57 114.28,68.7 115.88,70.3 115.88,70.94 117.28,72.34 117.28,75.06 v2(116.81,75.53)
  BOTTOM w0.102: JDIMM2.36 79.5,31.24 v2(79.66,31.4) ; v2(116.81,75.53) 116.44,75.89 116.44,78.04 116.92,78.52 116.92,79.3 117.72,80.1 USOC1.B38
DDR_A_D16: length 81.6
  IN2 w0.102: v2(118.45,81.59) 118.43,81.56 115.24,81.56 114.89,81.21 112.05,81.21 111.48,80.64
  IN2 w0.127: v2(81.2,34.46) 81.08,34.61 80.26,35.44 80.26,42.4 80.13,42.53 79.27,42.53 79.14,42.65 79.14,43.03 79.27,43.16 80.13,43.16 80.26,43.29 80.26,43.67 80.13,43.8 79.27,43.8 79.14,43.92 79.14,44.3 79.27,44.43 80.13,44.43 80.26,44.56 80.26,44.94 80.13,45.07 79.27,45.07 79.14,45.19 79.14,45.57 79.27,45.7 80.13,45.7 80.26,45.83 80.26,46.16 80.13,46.29 79.74,46.29 79.61,46.41 79.61,46.79 79.74,46.92 80.13,46.92 80.26,47.05 80.26,53.23 87.53,60.5 87.52,60.51 87.52,61.04 92.31,65.83 93.01,66.53 93.74,66.53 97.59,70.38 97.59,71.2 99.74,73.35 100.56,73.35 102.55,75.33 102.55,75.78 103.31,76.54 104.44,76.54 107.01,79.1 108.73,79.1 109.34,79.71 110.55,79.71 110.85,80.02 110.85,80.02 111.48,80.64
  BOTTOM w0.102: JDIMM2.39 80.4,35.22 80.98,34.64 v2(81.2,34.46) ; USOC1.F36 118.45,82.23 v2(118.45,81.59)
DDR_A_D17: length 83.4
  IN2 w0.102: 111.81,80.15 112.64,80.98 117.02,80.98 117.7,80.31 118.37,80.31 118.48,80.21 118.94,80.21 119.7,80.97 v2(119.7,81.49)
  IN2 w0.127: v2(81.2,35.98) 81.5,36.29 81.5,36.82 81.37,36.95 80.97,36.95 80.84,37.08 80.84,37.46 80.97,37.58 81.37,37.58 81.5,37.71 81.5,38.09 81.37,38.22 80.97,38.22 80.84,38.35 80.84,38.73 80.97,38.85 81.37,38.85 81.5,38.98 81.5,40 81.37,40.13 80.97,40.13 80.84,40.26 80.84,40.64 80.97,40.77 81.37,40.77 81.5,40.89 81.5,41.27 81.37,41.4 80.97,41.4 80.84,41.53 80.84,41.91 80.97,42.04 81.37,42.04 81.5,42.16 81.5,42.54 81.37,42.67 80.97,42.67 80.84,42.8 80.84,43.18 80.97,43.31 81.37,43.31 81.5,43.43 81.5,43.81 81.37,43.94 80.97,43.94 80.84,44.07 80.84,44.45 80.97,44.58 81.37,44.58 81.5,44.7 81.5,45.1 81.37,45.22 80.97,45.22 80.84,45.35 80.84,45.73 80.97,45.86 81.37,45.86 81.5,45.99 81.5,46.37 81.37,46.49 80.97,46.49 80.84,46.62 80.84,47 80.97,47.13 81.37,47.13 81.5,47.26 81.5,47.64 81.37,47.76 80.97,47.76 80.84,47.89 80.84,48.27 80.97,48.4 81.37,48.4 81.5,48.53 81.5,48.91 81.37,49.03 80.97,49.03 80.84,49.16 80.84,49.54 80.97,49.67 81.37,49.67 81.5,49.8 81.5,50.18 81.37,50.3 80.97,50.3 80.84,50.43 80.84,50.81 80.97,50.94 81.37,50.94 81.5,51.07 81.5,51.45 81.37,51.57 80.97,51.57 80.84,51.7 80.84,52.08 80.97,52.21 81.37,52.21 81.5,52.34 81.5,53.46 103.18,75.14 103.87,75.14 107.17,78.44 109.32,78.44 110,79.13 110.79,79.13 111.09,79.43 111.1,79.43 111.81,80.15
  BOTTOM w0.102: USOC1.G38 119.6,81.87 119.7,81.77 v2(119.7,81.49) ; JDIMM2.41 81,36.18 v2(81.2,35.98)
DDR_A_D18: length 83.1
  IN2 w0.102: v2(120.47,80.81) 120.47,80.19 120.16,79.87 120.16,79.78 120.16,79.78 120.16,79.46 120.16,79.46 120.16,79.38 119.79,79.01 117.92,79.01 117.91,79 117.89,79 117.86,78.97
  IN2 w0.127: 117.86,78.97 117.59,78.7 114.53,78.7 113.62,77.78 113.26,77.42 112.62,77.42 111.22,76.03 109.35,76.03 105.73,72.41 103.82,72.41 102.32,70.91 86.75,55.33 86.75,49.67 86.62,49.55 85.71,49.55 85.58,49.42 85.58,49.04 85.71,48.91 86.62,48.91 86.75,48.78 86.75,48.4 86.62,48.28 85.71,48.28 85.58,48.15 85.58,47.77 85.71,47.64 86.62,47.64 86.75,47.51 86.75,46.92 86.62,46.79 85.69,46.79 85.57,46.67 85.57,45.4 85.44,45.27 85.19,45.27 85.06,45.14 85.06,44.06 84.93,43.93 83.99,43.93 83.87,43.81 83.87,43.42 83.99,43.3 84.93,43.3 85.06,43.17 85.06,42.79 84.93,42.66 83.99,42.66 83.87,42.54 83.87,42.15 83.99,42.03 84.93,42.03 85.06,41.9 85.06,41.52 84.93,41.39 83.99,41.39 83.87,41.27 83.87,40.88 83.99,40.76 84.93,40.76 85.06,40.63 85.06,40.25 84.93,40.12 84.42,40.12 84.3,40 84.3,39.61 84.42,39.49 84.93,39.49 85.06,39.36 85.06,38.81 84.93,38.68 84.43,38.68 84.3,38.56 84.3,38.18 84.43,38.05 84.93,38.05 85.06,37.92 85.06,37.54 84.93,37.41 84.43,37.41 84.3,37.29 84.3,36.91 84.43,36.78 84.93,36.78 85.06,36.65 85.06,36.26 84.65,35.84 v2(84.51,35.84)
  BOTTOM w0.102: v2(84.51,35.84) 84,36.36 JDIMM2.51 ; USOC1.F42 120.5,80.78 v2(120.47,80.81)
DDR_A_D19: length 83.6
  IN2 w0.102: 113.6,75.52 113.97,75.52 115.88,77.43 119.18,77.43 121.5,79.75 v2(121.5,80.47)
  IN2 w0.127: 113.6,75.52 113.19,75.52 111.85,74.18 109.97,74.18 106.46,70.66 104.55,70.66 104.08,70.19 104.08,70.19 88.5,54.61 88.5,42.83 88.37,42.7 87.98,42.7 87.85,42.58 87.85,42.21 87.98,42.08 88.37,42.08 88.5,41.96 88.5,41.56 88.37,41.44 87.98,41.44 87.85,41.31 87.85,40.9 87.98,40.77 88.37,40.77 88.5,40.64 88.5,40.28 88.37,40.15 87.98,40.15 87.85,40.03 87.85,39.58 87.98,39.45 88.33,39.45 88.46,39.33 88.46,37.88 88.72,37.63 88.72,35.36 88.84,35.24 89.33,35.24 89.46,35.11 89.46,32.08 89.33,31.95 88.97,31.95 88.84,32.08 88.84,34.39 88.72,34.51 87.92,34.51 87.79,34.64 87.79,37.1 87.66,37.23 87.2,37.23 87.08,37.1 87.08,36.11 86.95,35.99 v2(86.87,35.99)
  BOTTOM w0.102: JDIMM2.53 84.6,36.75 85.12,36.23 86.63,36.23 v2(86.87,35.99) ; v2(121.5,80.47) 121.51,80.48 USOC1.J42
DDR_A_D20: length 83.7
  IN2 w0.102: v2(120.2,82.07) 119.43,82.07 119.3,81.94 118.98,81.94 118.75,82.17 116.77,82.17 116.56,82.38 111.56,82.38 110.65,81.47
  IN2 w0.127: v2(81.2,31.33) 81.2,31.17 81.07,31.05 80.21,31.05 80.08,31.17 80.08,33.86 79,34.95 79,36.26 77.97,37.3 77.97,50.7 78.1,50.83 78.77,50.83 78.9,50.96 78.9,51.34 78.77,51.47 78.19,51.47 78.06,51.59 78.06,52.13 78.19,52.26 78.57,52.26 78.77,52.45 78.77,53.39 86.35,60.98 86.35,61.54 90.96,66.15 90.96,67.05 91.94,68.03 92.65,68.03 94.3,69.68 94.3,70.09 98.07,73.85 98.4,73.85 102.4,77.85 104.1,77.85 107.1,80.86 108.39,80.86 108.9,81.36 110.55,81.36 110.65,81.47
  BOTTOM w0.102: USOC1.G40 120.3,81.97 v2(120.2,82.07) ; JDIMM2.40 80.7,30.84 v2(81.2,31.33)
DDR_A_D21: length 82.4
  IN2 w0.102: 111.06,81.06 111.5,81.49 114.82,81.49 115.3,81.97 118.61,81.97 118.83,81.75 118.83,81.18 118.71,81.06 v2(118.71,80.59)
  IN2 w0.127: 111.06,81.06 110.61,80.6 109.4,80.6 108.49,79.69 106.76,79.69 104.34,77.27 102.81,77.27 96.19,70.64 96.19,70.53 86.94,61.29 86.94,60.74 86.87,60.67 79.5,53.3 79.5,50.25 79.37,50.12 78.68,50.12 78.55,49.99 78.55,49.61 78.68,49.49 79.37,49.49 79.5,49.36 79.5,48.98 79.37,48.85 78.68,48.85 78.55,48.72 78.55,48.34 78.68,48.22 79.37,48.22 79.5,48.09 79.5,47.71 79.37,47.58 78.68,47.58 78.55,47.45 78.55,37.54 79.65,36.44 79.65,35.13 80.67,34.12 80.67,33.47 v2(81.2,32.94)
  BOTTOM w0.102: JDIMM2.42 81.3,30.64 81.76,31.1 81.76,32.38 v2(81.2,32.94) ; 118.21,80.68 118.31,80.59 v2(118.71,80.59)
DDR_A_D22: length 83.4
  IN2 w0.102: v2(121.02,80.07) 121.02,79.56 119.96,78.5 118.7,78.5 117.9,77.69 115.48,77.69 114.09,76.3
  IN2 w0.127: v2(84.51,32.8) 85.52,32.8 85.65,32.66 85.65,31.17 85.92,30.91 87.76,30.91 87.89,31.03 87.89,31.38 87.76,31.5 87.12,31.5 86.99,31.63 86.99,31.99 87.12,32.11 87.76,32.11 87.89,32.24 87.89,32.58 87.76,32.71 87.12,32.71 86.99,32.84 86.99,33.23 87.12,33.36 87.76,33.36 87.89,33.49 87.89,33.82 87.76,33.95 87.12,33.95 86.99,34.08 86.99,34.91 86.23,35.67 86.23,37.08 86.79,37.64 86.79,38.18 86.91,38.31 87.71,38.31 87.84,38.44 87.84,38.81 87.71,38.93 86.91,38.93 86.79,39.06 86.79,42.34 87.91,43.46 87.91,54.85 103.49,70.43 104.31,71.24 106.21,71.24 109.73,74.76 111.61,74.76 113.06,76.21 114,76.21 114.09,76.3
  BOTTOM w0.102: v2(121.02,80.07) 121.12,79.98 USOC1.G44 ; JDIMM2.50 83.7,31.98 v2(84.51,32.8)
DDR_A_D23: length 83.4
  IN2 w0.102: v2(120.54,79.62) 120.54,79.48 119.88,78.81 118.01,78.81 117.51,78.32 115.12,78.32 113.64,76.84 113.55,76.84
  IN2 w0.127: v2(84.51,34.32) 84.51,34.2 84.64,34.07 86.28,34.07 86.4,34.2 86.4,34.67 86.28,34.79 85.2,34.79 85.07,34.92 85.07,35.33 85.2,35.45 85.52,35.45 85.64,35.58 85.64,37.6 85.77,37.73 86.05,37.73 86.18,37.86 86.18,38.23 86.05,38.36 85.77,38.36 85.64,38.49 85.64,38.9 85.77,39.02 86.05,39.02 86.18,39.15 86.18,39.56 86.05,39.68 85.77,39.68 85.64,39.81 85.64,40.22 85.77,40.34 86.05,40.34 86.18,40.47 86.18,40.9 86.05,41.03 85.77,41.03 85.64,41.16 85.64,41.63 85.77,41.75 86.07,41.75 86.2,41.88 86.2,42.79 86.07,42.92 85.77,42.92 85.64,43.05 85.64,43.44 85.77,43.57 87.19,43.57 87.33,43.71 87.33,44.03 87.2,44.15 85.77,44.15 85.64,44.28 85.64,44.66 85.77,44.79 87.2,44.79 87.33,44.92 87.33,45.33 87.2,45.46 86.37,45.46 86.24,45.59 86.24,46.08 86.37,46.21 87.2,46.21 87.33,46.34 87.33,55.09 102.91,70.67 104.06,71.83 105.97,71.83 109.53,75.39 111.41,75.39 112.86,76.84 113.55,76.84
  BOTTOM w0.102: v2(120.54,79.62) 120.45,79.71 USOC1.D42 ; v2(84.51,34.32) 85.15,33.68 85.15,32.09 84.3,31.24 JDIMM2.52
DDR_A_D24: length 68.2
  IN1 w0.127: v2(87.34,40.98) 87.11,40.98 86.91,41.17 86.91,42.4 89.71,45.2 90.64,45.2 90.77,45.33 90.77,46.24 90.89,46.36 91.36,46.36 91.49,46.49 91.49,46.98 91.62,47.1 92,47.1 92.13,46.98 92.13,46.49 92.25,46.36 92.63,46.36 92.76,46.49 92.76,47.57 92.89,47.7 93.27,47.7 93.4,47.57 93.4,46.49 93.52,46.36 93.9,46.36 94.03,46.49 94.03,47.57 94.16,47.7 94.54,47.7 94.67,47.57 94.67,46.49 94.79,46.36 95.17,46.36 95.3,46.49 95.3,47.57 95.43,47.7 95.81,47.7 95.94,47.57 95.94,46.49 96.06,46.36 96.59,46.36 96.73,46.5 96.73,47.38 96.96,47.61 97.84,47.61 116.37,66.14 116.37,66.18 116.38,66.18 116.38,69.79 v2(116.37,69.8)
  BOTTOM w0.102: v2(116.37,69.8) 116.29,69.8 115.84,70.25 115.84,71.69 116.6,72.46 116.6,73.8 117.75,74.94 117.75,78.32 118.19,78.77 118.36,78.77 USOC1.A41 ; JDIMM2.57 85.8,39.44 v2(87.34,40.98)
DDR_A_D25: length 67.7
  IN1 w0.127: v2(116.83,70.92) 116.99,70.76 116.99,65.93 96.82,45.77 95.6,45.77 95.3,45.46 95.3,44.24 95.17,44.11 94.79,44.11 94.66,44.24 94.66,45.65 94.53,45.78 94.15,45.78 94.03,45.65 94.03,44.24 93.9,44.11 93.52,44.11 93.39,44.24 93.39,45.65 93.26,45.78 92.83,45.78 92.7,45.65 92.7,44.7 92.59,44.58 92.11,44.58 91.98,44.71 91.98,45.65 91.86,45.78 91.48,45.78 91.35,45.65 91.35,44.71 91.22,44.58 89.93,44.58 87.93,42.59 87.93,39.62 87.76,39.45 v2(87.34,39.45)
  BOTTOM w0.102: v2(116.83,70.92) 116.83,71.89 117.19,72.25 117.19,74.06 117.97,74.84 117.97,78.17 118.35,78.55 118.56,78.55 118.79,78.78 118.79,78.98 119,79.2 USOC1.C41 ; JDIMM2.59 86.4,39.06 86.8,39.45 v2(87.34,39.45)
DDR_A_D26: length 67
  IN1 w0.127: v2(90.39,40.98) 92.61,40.98 92.74,40.85 92.74,40.6 92.86,40.47 93.24,40.47 93.37,40.6 93.37,40.85 93.5,40.98 93.88,40.98 94.01,40.85 94.01,40.6 94.13,40.47 94.51,40.47 94.64,40.6 94.64,40.85 94.77,40.98 96.77,40.98 97.98,42.19 97.98,42.37 97.47,42.89 97.47,43.07 97.74,43.34 97.92,43.34 98.43,42.82 98.61,42.82 98.88,43.09 98.88,43.27 98.37,43.79 98.37,43.97 98.64,44.24 98.82,44.24 99.33,43.72 99.51,43.72 99.78,43.99 99.78,44.17 99.26,44.69 99.26,44.87 99.53,45.14 99.71,45.14 100.23,44.62 100.41,44.62 100.68,44.89 100.68,45.07 100.16,45.58 100.16,45.76 100.43,46.03 100.61,46.03 101.13,45.52 101.31,45.52 101.58,45.79 101.58,45.97 101.06,46.48 101.06,46.66 101.33,46.93 101.51,46.93 102.03,46.42 102.21,46.42 102.47,46.69 102.47,46.87 101.96,47.38 101.96,47.56 111.7,57.3 119.44,65.04 119.44,71.67 v2(119.06,72.05)
  BOTTOM w0.102: v2(119.06,72.05) 118.94,72.17 118.94,73.67 119.07,73.8 119.07,75.62 118.94,75.75 118.94,76.93 119.36,77.35 119.69,77.35 USOC1.A45 ; JDIMM2.67 88.8,39.39 v2(90.39,40.98)
DDR_A_D27: length 66.5
  IN1 w0.102: 120.02,71.94 120.02,71.94 v2(119.43,72.53)
  IN1 w0.127: v2(90.39,39.45) 94.52,39.45 95.34,40.27 96.93,40.27 103.35,46.7 103.35,46.88 102.82,47.41 102.82,47.59 103.09,47.86 103.27,47.86 103.8,47.33 103.98,47.33 104.25,47.6 104.25,47.78 103.71,48.31 103.71,48.49 103.98,48.76 104.16,48.76 104.7,48.22 104.88,48.22 105.15,48.49 105.15,48.67 104.61,49.21 104.61,49.39 104.88,49.66 105.06,49.66 105.6,49.12 105.78,49.12 106.04,49.39 106.04,49.57 105.51,50.11 105.51,50.29 105.78,50.56 105.96,50.56 106.49,50.02 106.67,50.02 106.94,50.29 106.94,50.47 106.41,51 106.41,51.18 106.68,51.45 106.86,51.45 107.39,50.92 107.57,50.92 107.84,51.19 107.84,51.37 107.31,51.9 107.31,52.08 120.02,64.8 120.02,71.94
  BOTTOM w0.102: v2(119.43,72.53) 119.17,72.8 119.17,73.62 119.27,73.72 119.27,75.71 119.17,75.81 119.17,76.82 119.46,77.12 119.91,77.12 120.24,77.45 120.51,77.45 USOC1.B46 ; v2(90.39,39.45) 89.72,39.45 89.4,39.14 JDIMM2.69
DDR_A_D28: length 68.5
  IN1 w0.127: v2(115.72,68.93) 115.79,68.86 115.79,66.43 97.65,48.28 91.97,48.28 86.33,42.64 86.33,35.73 86.96,35.1 86.96,33.34 v2(86.54,32.92)
  BOTTOM w0.102: v2(86.54,32.92) 85.78,32.16 85.78,31.71 85.5,31.43 JDIMM2.56 ; v2(115.72,68.93) 115.24,69.41 115.24,71.88 116.05,72.69 116.05,73.57 117.49,75.02 117.49,78.37 118.31,79.2 118.58,79.2 118.7,79.32 118.7,79.8 USOC1.C40
DDR_A_D29: length 67.7
  IN1 w0.127: v2(115.13,68.51) 115.21,68.43 115.21,66.67 97.4,48.86 91.73,48.86 85.64,42.78 85.64,35.4 85.91,35.14 85.91,32.03 v2(86.54,31.4)
  BOTTOM w0.102: JDIMM2.58 86.1,30.95 v2(86.54,31.4) ; v2(115.13,68.51) 114.64,69 114.64,72.16 115.4,72.91 115.4,73.38 117.26,75.25 117.26,78.45 118.32,79.5 USOC1.B40
DDR_A_D30: length 66.7
  IN1 w0.102: v2(120.23,73.42) 121.19,72.46 121.19,70.77
  IN1 w0.127: 121.19,70.77 121.19,64.22 111.06,54.09 111.06,53.91 112.07,52.89 112.07,52.71 111.8,52.44 111.62,52.44 110.61,53.46 110.43,53.46 110.16,53.19 110.16,53.01 110.68,52.49 110.68,52.31 95.04,36.67 93.64,36.67 91.12,34.15 91.12,32.68 v2(89.88,31.53)
  BOTTOM w0.102: v2(89.88,31.53) 89.54,31.53 89.1,31.09 JDIMM2.68 ; USOC1.B48 121.18,76.73 121.12,76.79 120.84,76.79 120.47,76.42 120.39,76.42 119.68,75.71 119.68,73.98 v2(120.23,73.42)
DDR_A_D31: length 67.2
  IN1 w0.127: v2(89.88,33.05) 90.27,33.05 90.53,33.31 90.53,36.25 91.86,37.58 95.11,37.58 108.73,51.21 108.73,51.39 108.18,51.94 108.18,52.12 108.45,52.39 108.62,52.39 109.18,51.83 109.36,51.83 109.63,52.1 109.63,52.28 109.07,52.84 109.07,53.02 120.61,64.55 120.61,72.11 119.88,72.83 v2(119.88,72.94)
  BOTTOM w0.102: USOC1.B47 120.71,77.14 120.62,77.23 120.31,77.23 119.98,76.9 119.62,76.9 119.37,76.65 119.37,75.89 119.47,75.79 119.47,73.63 119.37,73.53 119.37,73.45 v2(119.88,72.94) ; JDIMM2.70 89.7,30.8 89.85,30.95 89.97,30.95 90.55,31.52 90.55,32.4 90.05,32.9 v2(89.88,33.05)
DDR_A_D32: length 60.7
  IN1 w0.102: 124.33,71.5 124.11,71.72 123.8,71.72 123.51,72.01 123.51,72.42 123.87,72.78 v2(123.94,72.78)
  IN1 w0.127: 124.33,71.5 124.57,71.26 124.57,70.41 123.28,69.12 123.28,63.81 113.83,54.36 113.83,50.2 108.1,44.47 108.1,41.52 108.68,40.93 108.68,38.9 108.81,38.77 109.96,38.77 110.09,38.64 110.09,37.63 110.22,37.5 110.76,37.5 110.89,37.63 110.89,39.33 110.74,39.48 110.41,39.48 110.29,39.61 110.29,40.08 110.16,40.2 109.8,40.2 109.67,40.08 109.67,39.71 109.57,39.61 v2(109.31,39.61)
  BOTTOM w0.102: v2(109.31,39.61) 109.8,39.12 JDIMM2.129 ; USOC1.K52 126.15,77.61 126.7,77.61 127.65,76.66 127.65,74.91 125.12,72.39 124.34,72.39 v2(123.94,72.78)
DDR_A_D33: length 61.7
  IN1 w0.102: 124.79,72.15 v2(123.94,72.15)
  IN1 w0.127: v2(109.31,41.13) 108.68,41.76 108.68,42.91 108.81,43.04 109.43,43.04 109.56,43.16 109.56,43.56 109.43,43.68 108.81,43.68 108.68,43.81 108.68,44.18 108.81,44.31 109.54,44.31 109.67,44.43 109.67,45.03 114.55,49.91 114.55,50.78 114.68,50.91 115.5,50.91 115.63,51.04 115.63,51.5 115.5,51.63 114.55,51.63 114.42,51.76 114.42,52.14 114.55,52.27 115.5,52.27 115.63,52.39 115.63,52.77 115.5,52.9 114.55,52.9 114.42,53.03 114.42,53.41 114.55,53.54 115.5,53.54 115.63,53.66 115.63,54.04 115.5,54.17 115.16,54.17 115.03,54.3 115.03,54.68 115.16,54.81 115.5,54.81 115.63,54.93 115.63,55.33 116.32,56.03 117.44,56.03 117.63,56.22 117.63,57.34 123.91,63.61 123.91,68.92 125.25,70.26 125.25,71.83 124.93,72.15 124.79,72.15
  BOTTOM w0.102: v2(123.94,72.15) 125.34,72.15 127.9,74.71 127.9,76.7 126.76,77.84 126.21,77.84 125.95,78.1 125.95,78.28 125.83,78.41 125.52,78.41 125.33,78.6 USOC1.K51 ; JDIMM2.131 110.4,40.04 v2(109.31,41.13)
DDR_A_D34: length 62.3
  IN1 w0.127: v2(113.88,41.08) 114.36,41.08 114.53,41.25 114.53,42.52 114.95,42.95 114.95,44.45 123.55,53.05 123.55,54.47 123.77,54.68 125.2,54.68 125.33,54.81 125.33,55.27 125.2,55.39 123.65,55.39 123.53,55.52 123.53,55.9 123.65,56.03 125.17,56.03 125.3,56.15 125.3,56.54 125.17,56.66 123.65,56.66 123.53,56.79 123.53,57.17 123.65,57.3 125.17,57.3 125.3,57.42 125.3,57.81 125.17,57.93 124.69,57.93 124.56,58.06 124.56,58.44 124.69,58.57 125.17,58.57 125.3,58.69 125.3,59.18 125.78,59.66 126.54,59.66 126.78,59.9 126.78,60.66 128.16,62.04 128.16,65.39 128.6,65.82 129.26,65.82 130.24,66.81 130.24,67.27 129.92,67.6 129.59,67.6 v2(129.61,67.62)
  BOTTOM w0.102: JDIMM2.141 113.4,40.59 v2(113.88,41.08) ; USOC1.T52 130.51,77.37 130.9,77.37 131.66,76.61 131.66,69.08 130.26,67.67 129.66,67.67 v2(129.61,67.62)
DDR_A_D35: length 62.4
  IN1 w0.127: v2(113.88,39.55) 113.89,39.55 113.89,39.16 113.76,39.04 113.42,39.04 113.29,39.16 113.29,42.18 113.42,42.31 113.76,42.31 113.89,42.44 113.89,42.87 113.76,43 113.43,43 113.3,43.12 113.3,43.59 113.43,43.72 114.23,43.72 114.36,43.85 114.36,44.68 121.96,52.29 121.96,53.13 122.18,53.35 122.79,53.35 122.94,53.5 122.94,53.89 122.82,54.02 122.07,54.02 121.94,54.14 121.94,54.52 122.07,54.65 122.82,54.65 122.94,54.78 122.94,55.16 122.82,55.29 122.08,55.29 121.94,55.43 121.94,55.78 122.08,55.92 122.82,55.92 122.94,56.05 122.94,56.43 122.82,56.56 122.51,56.56 122.33,56.73 122.33,57.01 122.51,57.19 122.82,57.19 122.94,57.32 122.94,57.65 123.21,57.91 123.74,57.91 123.9,58.08 123.9,58.61 127.57,62.28 127.57,65.83 128.21,66.47 128.82,66.47 128.91,66.56 128.91,66.9 129.03,67.01 v2(129.63,67.01)
  BOTTOM w0.102: v2(113.88,39.55) 114,39.44 JDIMM2.143 ; v2(129.63,67.01) 129.68,67.06 130.54,67.06 132.22,68.75 132.22,76.92 131.1,78.03 130.45,78.03 129.18,79.3 128.87,79.3 128.02,80.16 128.02,80.31 127.86,80.47 127.42,80.47 USOC1.T51
DDR_A_D36: length 61.7
  IN1 w0.127: v2(123.94,70.62) 122.69,69.37 122.69,64.05 113.24,54.6 113.24,50.5 107.51,44.77 107.51,41.28 108.01,40.78 108.01,38.71 108.54,38.18 109.33,38.18 109.51,38.01 109.51,37.38 110.22,36.67 110.22,33.13 v2(110.64,32.71)
  BOTTOM w0.102: JDIMM2.130 110.1,32.17 v2(110.64,32.71) ; USOC1.L51 126,78.7 126.21,78.49 126.61,78.49 126.84,78.26 127,78.26 128.46,76.8 128.46,74.25 124.82,70.62 v2(123.94,70.62)
DDR_A_D37: length 60.8
  IN1 w0.127: v2(110.64,31.18) 110.45,31.18 108.95,32.68 108.95,36.82 106.84,38.93 106.84,44.92 112.66,50.74 112.66,54.84 121.84,64.02 121.84,69.44 123.68,71.29 v2(123.94,71.29)
  BOTTOM w0.102: JDIMM2.132 110.7,31.13 v2(110.64,31.18) ; v2(123.94,71.29) 124.99,71.29 128.15,74.45 128.15,76.8 126.89,78.06 126.39,78.06 USOC1.L53
DDR_A_D38: length 62.4
  IN1 w0.127: v2(112.83,32.99) 113.58,33.74 113.58,37.1 113.46,37.23 113.11,37.23 112.99,37.36 112.99,37.74 113.11,37.86 113.46,37.86 113.58,37.99 113.58,38.32 113.46,38.45 112.83,38.45 112.71,38.58 112.71,43.86 121.35,52.51 121.35,56.89 126.99,62.52 126.99,66.16 v2(129.65,68.82)
  BOTTOM w0.102: v2(129.65,68.82) 130.39,68.82 131.08,69.51 131.08,76.26 130.69,76.64 130.69,76.9 127.73,79.86 127.44,79.86 127.23,80.08 USOC1.R51 ; JDIMM2.140 113.1,30.92 113.25,31.07 113.25,32.57 v2(112.83,32.99)
DDR_A_D39: length 62
  IN1 w0.127: v2(129.66,69.4) 129.36,69.4 126.4,66.45 126.4,62.76 120.77,57.13 120.77,54.15 120.64,54.02 120.24,54.02 120.11,53.89 120.11,53.51 120.24,53.38 120.64,53.38 120.77,53.26 120.77,52.75 120.66,52.64 120.4,52.64 120.18,52.42 120.18,52.16 112.08,44.06 112.08,34.34 112.29,34.13 112.66,34.13 112.83,34.3 v2(112.83,34.51)
  BOTTOM w0.102: JDIMM2.142 113.7,30.69 113.87,30.87 113.87,33.47 v2(112.83,34.51) ; 127.64,79.55 130.29,76.91 130.29,76.21 130.52,75.98 130.52,69.84 130.08,69.4 v2(129.66,69.4)
DDR_A_D40: length 70.9
  IN1 w0.102: 126.48,78.66 126.48,79.82 125.88,80.43 v2(125.88,81.33)
  IN1 w0.127: v2(116.12,41.1) 115.83,41.1 115.7,41.23 115.7,42.04 116.12,42.46 116.12,43.95 127.85,55.68 127.85,56.48 127.98,56.61 128.75,56.61 128.87,56.74 128.87,57.89 129,58.02 130.16,58.02 130.28,58.14 130.28,58.72 130.16,58.85 128.62,58.85 128.49,58.97 128.49,59.38 128.62,59.51 131.24,59.51 131.36,59.63 131.36,60.02 131.24,60.14 129.52,60.14 129.39,60.27 129.39,60.65 129.52,60.78 131.24,60.78 131.36,60.9 131.36,61.29 131.24,61.41 130.65,61.41 130.52,61.54 130.52,62.58 130.4,62.71 130.07,62.71 129.94,62.58 129.94,61.54 129.81,61.41 129.48,61.41 129.36,61.54 129.36,63.15 129.48,63.28 130.34,63.28 130.47,63.41 130.47,65.36 131.03,65.92 131.26,65.92 131.41,66.07 131.41,68.03 131.07,68.37 131.07,70.76 129.78,72.06 129.6,72.06 129.25,71.71 129.07,71.71 128.8,71.98 128.8,72.16 129.15,72.5 129.15,72.68 128.88,72.95 128.7,72.95 128.49,72.74 128.31,72.74 128.04,73.01 128.04,73.19 128.25,73.4 128.25,73.58 128.04,73.79 127.86,73.79 127.65,73.59 127.44,73.59 127.25,73.78 127.25,74.07 127.63,74.46 127.63,76.14 127.4,76.37 127.4,76.6 126.48,77.52 126.48,78.66
  BOTTOM w0.102: JDIMM2.147 115.2,40.18 v2(116.12,41.1) ; v2(125.88,81.33) 125.83,81.38 USOC1.T47
DDR_A_D41: length 69.6
  IN1 w0.127: v2(125.34,81.88) 125.14,81.88 124.92,81.67 124.92,81.47 125.11,81.28 125.11,79.94 125.63,79.43 125.63,72.28 125.74,72.17 126.07,72.17 126.19,72.3 126.19,72.55 126.3,72.66 127.69,72.66 128.2,72.14 128.2,70.82 128.43,70.6 130.08,70.6 130.4,70.28 130.4,68.03 130.83,67.6 130.83,66.55 129.81,65.53 129.81,65.35 129.69,65.22 128.94,65.22 128.81,65.1 128.81,64.59 128.94,64.47 129.67,64.47 129.8,64.34 129.8,64.03 129.67,63.9 128.87,63.9 128.75,63.77 128.75,60.78 128.62,60.66 127.6,60.66 127.48,60.53 127.48,60.08 127.6,59.95 127.78,59.95 127.91,59.82 127.91,59.3 127.78,59.18 127.29,59.18 127.16,59.05 127.16,58.25 127.29,58.12 128,58.12 128.12,58 128.12,57.45 128,57.32 126.78,57.32 126.65,57.45 126.65,58.94 126.52,59.06 126.01,59.06 125.88,58.94 125.88,56.73 126.04,56.57 127.06,56.57 127.16,56.47 127.16,55.89 127.03,55.76 126.16,55.76 126.03,55.63 126.03,54.69 115.54,44.19 115.54,42.7 115.12,42.28 115.12,39.45 115.24,39.33 115.99,39.33 116.12,39.45 v2(116.12,39.58)
  BOTTOM w0.102: USOC1.T45 125.33,81.89 v2(125.34,81.88) ; v2(116.12,39.58) 115.8,39.26 JDIMM2.149
DDR_A_D42: length 69.8
  IN1 w0.102: v2(124.22,85.71) 123.96,85.71 123.83,85.58 123.83,85.02 124.08,84.77 124.72,84.77 125.05,85.1 125.37,85.1 125.66,84.8 125.66,84.59 125.25,84.18 125.25,83.98 125.61,83.63
  IN1 w0.127: 125.61,83.63 129.81,79.42 129.81,77.02 135.03,71.8 135.03,66.47 135.22,66.28 135.46,66.28 135.59,66.15 135.59,65.77 135.46,65.64 135.22,65.64 135.1,65.51 135.1,65.13 135.22,65.01 135.46,65.01 135.59,64.88 135.59,64.5 135.46,64.37 135.22,64.37 135.1,64.24 135.1,63.86 135.22,63.74 135.46,63.74 135.59,63.61 135.59,63.23 135.46,63.1 135.22,63.1 135.1,62.97 135.1,62.59 135.22,62.47 135.46,62.47 135.59,62.34 135.59,61.96 135.46,61.83 135.22,61.83 135.1,61.7 135.1,61.32 135.22,61.2 135.46,61.2 135.59,61.07 135.59,60.69 135.46,60.56 135.22,60.56 135.1,60.43 135.1,57.21 121.91,44.03 121.91,42.93 121.51,42.53 121.51,42.31 121.39,42.18 120.96,42.18 120.83,42.31 120.83,42.55 120.58,42.81 120.35,42.81 120.1,42.55 120.1,41.7 120.22,41.57 120.54,41.57 120.67,41.45 120.67,40.34 120.54,40.22 120.23,40.22 120.1,40.34 120.1,40.71 120,40.82 119.8,40.82 119.67,40.95 v2(119.67,41.18)
  BOTTOM w0.102: USOC1.Y40 124.46,85.94 v2(124.22,85.71) ; v2(119.67,41.18) 118.2,39.71 JDIMM2.157
DDR_A_D43: length 70.6
  IN1 w0.102: 131.34,76.31 130.1,77.55 130.1,80.55 126.23,84.42 126.23,84.52 125.45,85.3 124.7,85.3 v2(124.68,85.27)
  IN1 w0.127: 131.34,76.31 135.64,72.02 135.64,66.92 136.18,66.38 136.18,60.14 136.05,60.02 135.81,60.02 135.68,59.89 135.68,59.51 135.81,59.38 136.05,59.38 136.18,59.25 136.18,58.87 136.05,58.75 135.81,58.75 135.68,58.62 135.68,58.24 135.81,58.11 136.05,58.11 136.18,57.98 136.18,57.47 135.82,57.11 122.5,43.79 122.5,42.69 122.1,42.29 122.1,37.99 121.97,37.86 121.53,37.86 121.41,37.99 121.41,38.79 121.28,38.92 120.91,38.92 120.78,38.79 120.78,36.93 120.66,36.81 120.31,36.81 120.19,36.93 120.19,39.52 120.06,39.65 119.67,39.65 v2(119.67,39.66)
  BOTTOM w0.102: JDIMM2.159 118.8,39.02 119.44,39.66 v2(119.67,39.66) ; v2(124.68,85.27) 124.49,85.09 USOC1.V41
DDR_A_D44: length 70.6
  IN1 w0.102: v2(126.31,80.87) 126.31,80.35 126.9,79.76 126.9,77.57 128.11,76.36
  IN1 w0.127: v2(115.07,31.18) 114.57,31.68 114.57,32.79 114.17,33.19 114.17,33.55 114.29,33.68 114.62,33.68 114.75,33.8 114.75,34.2 114.62,34.32 114.29,34.32 114.17,34.45 114.17,38.62 114.29,38.74 114.76,38.74 114.89,38.62 114.89,37.7 115.02,37.57 115.59,37.57 115.72,37.7 115.72,38.62 115.84,38.74 116.58,38.74 116.71,38.87 116.71,43.61 132,58.9 132,61.99 131.87,62.12 131.25,62.12 131.12,62.25 131.12,62.63 131.25,62.76 131.87,62.76 132,62.88 132,63.26 131.87,63.39 131.25,63.39 131.12,63.52 131.12,63.9 131.25,64.03 131.87,64.03 132,64.15 132,64.53 131.87,64.66 131.25,64.66 131.12,64.79 131.12,65.17 131.25,65.3 131.87,65.3 132,65.42 132,68.3 131.65,68.64 131.65,71.01 128.11,74.55 128.11,76.36
  BOTTOM w0.102: v2(126.31,80.87) 126.33,80.9 USOC1.T48 ; v2(115.07,31.18) 114.9,31.02 JDIMM2.146
DDR_A_D45: length 70.7
  IN1 w0.102: 129.23,74.26 128.72,74.77 128.72,76.7 127.23,78.19 127.23,80 v2(126.77,80.46)
  IN1 w0.127: v2(115.07,32.71) 115.44,32.71 115.56,32.58 115.56,31.86 115.69,31.73 116.26,31.73 116.39,31.86 116.39,33.49 116.26,33.62 115.6,33.62 115.47,33.74 115.47,34.12 115.6,34.25 116.49,34.25 116.62,34.38 116.62,34.76 116.49,34.89 114.88,34.89 114.75,35.01 114.75,35.39 114.88,35.52 116.15,35.52 116.28,35.65 116.28,36.09 116.15,36.22 115.2,36.22 115.07,36.34 115.07,36.79 115.2,36.91 116.15,36.91 116.28,37.04 116.28,37.52 117.29,38.53 117.29,43.23 132.58,58.52 132.58,68.6 132.26,68.92 132.26,71.22 129.35,74.14 129.23,74.26
  BOTTOM w0.102: USOC1.T50 126.79,80.49 v2(126.77,80.46) ; v2(115.07,32.71) 115.5,32.28 JDIMM2.148
DDR_A_D46: length 70.7
  IN1 w0.102: 127.2,84.79 127.06,84.93 126.4,84.93 v2(126.27,85.06)
  IN1 w0.127: v2(119.1,32.73) 119.57,32.73 119.82,32.98 119.82,34.64 119.94,34.77 120.88,34.77 121.01,34.89 121.01,35.35 120.88,35.48 120.44,35.48 120.31,35.61 120.31,36.1 120.44,36.22 121.87,36.22 122,36.35 122,37.06 122.78,37.84 122.78,38.77 123.08,39.07 123.08,43.54 136.77,57.23 136.77,66.63 136.28,67.11 136.28,72.21 130.74,77.75 130.74,81.33 127.28,84.79 127.2,84.79
  BOTTOM w0.102: v2(126.27,85.06) 126.15,84.94 USOC1.Y42 ; v2(119.1,32.73) 118.5,32.13 JDIMM2.158
DDR_A_D47: length 70.7
  IN1 w0.102: 127.55,85.28 126.69,85.28 125.88,86.09 v2(125.23,86.09)
  IN1 w0.127: v2(119.1,31.21) 120.47,32.57 120.47,33.53 122.58,35.64 122.58,36.82 123.45,37.68 123.45,38.49 123.67,38.71 123.67,43.3 137.35,56.99 137.35,66.87 136.99,67.23 136.99,72.42 131.12,78.28 131.12,82.29 128.14,85.28 127.55,85.28
  BOTTOM w0.102: JDIMM2.160 v2(119.1,31.21) ; v2(125.23,86.09) 125.38,86.23 USOC1.AB40
DDR_A_D48: length 84.3
  IN2 w0.102: 132.7,82.72 132.21,82.72 131.85,82.36 128.67,82.36 128.37,82.66 128.02,82.66 127.2,83.48 v2(126.46,83.48)
  IN2 w0.127: 132.7,82.72 133.08,82.72 135.02,80.78 135.02,80 139.01,76.02 139.01,60.74 135.15,56.88 135.15,56.7 135.83,56.02 135.83,55.84 135.56,55.57 135.38,55.57 134.7,56.25 134.52,56.25 134.25,55.98 134.25,55.8 134.93,55.13 134.93,54.95 134.66,54.68 134.48,54.68 133.8,55.35 133.62,55.35 133.36,55.09 133.36,54.86 134.01,54.2 134.01,54.02 133.74,53.75 133.56,53.75 132.98,54.34 132.8,54.34 132.53,54.07 132.53,53.89 133.11,53.31 133.11,53.13 132.84,52.86 132.66,52.86 132.08,53.44 131.9,53.44 131.63,53.17 131.63,52.99 132.21,52.41 132.21,52.23 131.94,51.96 131.76,51.96 131.18,52.54 131,52.54 130.73,52.27 130.73,52.09 131.31,51.51 131.31,51.33 131.04,51.06 130.86,51.06 130.28,51.64 130.1,51.64 129.83,51.37 129.83,51.19 130.42,50.61 130.42,50.43 130.15,50.16 129.97,50.16 129.38,50.74 129.2,50.74 128.93,50.48 128.93,50.3 129.52,49.71 129.52,49.53 129.25,49.26 129.07,49.26 128.48,49.85 128.31,49.85 128.04,49.58 128.04,49.4 128.62,48.81 128.62,48.64 128.35,48.37 128.17,48.37 127.59,48.95 127.41,48.95 127.14,48.68 127.14,48.5 127.72,47.92 127.72,47.74 127.45,47.47 127.27,47.47 126.69,48.05 126.51,48.05 126.24,47.78 126.24,47.6 126.82,47.02 126.82,46.84 123.9,43.92 123.6,43.92 123.06,44.46 122.73,44.46 120.78,42.52 120.78,41.43 v2(121.21,41)
  BOTTOM w0.102: JDIMM2.163 120,39.09 120.31,39.4 120.31,40.1 v2(121.21,41) ; v2(126.46,83.48) 126.22,83.24 USOC1.V45
DDR_A_D49: length 85.8
  IN2 w0.102: v2(126.99,82.94) 127.44,82.94 127.93,82.45 128.29,82.45 128.59,82.16 132.11,82.16 132.18,82.23 132.6,82.23
  IN2 w0.127: v2(121.21,39.48) 121.06,39.48 120.94,39.35 120.94,38.83 121.06,38.7 121.46,38.7 121.58,38.58 121.58,37.59 121.46,37.46 120.44,37.46 120.31,37.33 120.31,36.96 120.44,36.84 120.65,36.84 120.78,36.71 120.78,36.33 120.65,36.2 120.44,36.2 120.31,36.07 120.31,35.69 120.44,35.57 121.51,35.57 121.63,35.44 121.63,34.11 121.51,33.98 120.94,33.98 120.81,34.11 120.81,34.64 120.68,34.77 119.64,34.77 119.51,34.89 119.51,37.83 119.64,37.96 120.07,37.96 120.2,38.08 120.2,38.43 120.07,38.55 119.5,38.55 119.37,38.68 119.37,39.06 119.5,39.19 120.07,39.19 120.2,39.32 120.2,42.76 122.8,45.36 122.98,45.36 123.66,44.68 123.84,44.68 124.11,44.95 124.11,45.13 123.43,45.81 123.43,45.99 123.7,46.26 123.88,46.26 124.56,45.58 124.74,45.58 125.01,45.85 125.01,46.03 124.33,46.71 124.33,46.89 124.6,47.16 124.78,47.16 125.46,46.48 125.64,46.48 125.91,46.75 125.91,46.93 125.23,47.61 125.23,47.79 138.42,60.98 138.42,75.77 134.69,79.51 134.69,80.28 132.74,82.23 132.6,82.23
  BOTTOM w0.102: v2(121.21,39.48) 120.6,38.87 JDIMM2.165 ; v2(126.99,82.94) 126.79,82.74 USOC1.V47
DDR_A_D50: length 86.2
  IN2 w0.102: 130.87,84.54 128.69,84.54 v2(128.47,84.32)
  IN2 w0.127: 130.87,84.54 132.01,85.68 136.58,85.68 137.66,84.6 142.87,84.6 144.56,82.91 144.56,79.37 142.35,77.16 142.35,57.4 136.29,51.34 136.29,51.11 137.15,50.25 137.15,50.07 136.88,49.8 136.7,49.8 135.87,50.64 135.69,50.64 135.42,50.37 135.42,50.19 136.98,48.62 136.98,48.44 136.71,48.17 136.53,48.17 135.94,48.77 135.76,48.77 135.49,48.5 135.49,48.32 136.08,47.72 136.08,47.54 126.29,37.75 124.41,37.75 123.79,38.37 123.79,40.22 v2(124.68,41.1)
  BOTTOM w0.102: USOC1.AD48 v2(128.47,84.32) ; JDIMM2.175 123.6,40.02 v2(124.68,41.1)
DDR_A_D51: length 85.5
  IN2 w0.102: 131.4,84.74 130.89,84.24 129.41,84.24 v2(128.98,83.8)
  IN2 w0.127: v2(124.68,39.58) 124.6,39.5 124.6,38.5 124.73,38.37 125.38,38.37 125.51,38.5 125.51,38.96 125.59,39.04 126.75,39.04 127.86,40.14 127.86,40.32 126.85,41.33 126.85,41.51 127.12,41.78 127.3,41.78 128.3,40.77 128.48,40.77 131.89,44.18 131.89,44.36 131.65,44.59 131.65,44.77 131.92,45.04 132.1,45.04 132.34,44.81 132.52,44.81 132.99,45.27 132.99,45.94 131.62,47.31 131.62,47.49 132.02,47.9 132.2,47.9 133.82,46.29 134,46.29 134.27,46.56 134.27,46.74 132.65,48.35 132.65,48.53 132.92,48.8 133.1,48.8 134.72,47.18 134.9,47.18 135.17,47.45 135.17,47.63 133.55,49.25 133.55,49.43 133.55,49.43 133.79,49.67 133.97,49.67 134.78,48.86 134.96,48.86 135.23,49.13 135.23,49.3 134.42,50.12 134.42,50.3 141.56,57.44 141.56,76.89 138.28,80.17 138.28,82.47 135.33,85.42 132.08,85.42 131.4,84.74
  BOTTOM w0.102: v2(124.68,39.58) 124.2,39.1 JDIMM2.177 ; v2(128.98,83.8) 129.32,83.8 USOC1.AD50
DDR_A_D52: length 83.4
  IN2 w0.102: 132.24,81.13 131.69,81.68 128.78,81.68 128.21,82.25 127.85,82.25 127.79,82.31 v2(127.52,82.31)
  IN2 w0.127: 132.24,81.13 137.84,75.53 137.84,61.22 119.17,42.55 119.17,41.83 118.98,41.64 118.25,41.64 118.04,41.43 118.04,41 118.17,40.87 119.09,40.87 119.22,40.75 119.22,40.37 119.09,40.24 118.17,40.24 118.04,40.11 118.04,39.73 118.17,39.6 118.66,39.6 118.79,39.48 118.79,39.1 118.66,38.97 118.17,38.97 118.04,38.84 118.04,38.2 118.17,38.07 118.79,38.07 118.92,37.94 118.92,37.49 118.79,37.36 117.28,37.36 117.15,37.23 117.15,36.85 117.28,36.73 117.92,36.73 118.04,36.6 118.04,36.22 117.92,36.09 117.28,36.09 117.15,35.96 117.15,35.58 117.28,35.46 117.54,35.46 117.67,35.33 117.67,32.28 117.8,32.15 118.22,32.15 118.34,32.28 118.34,33.88 118.47,34.01 119.46,34.01 119.59,33.88 119.59,32.28 119.72,32.15 120.19,32.15 120.31,32.28 120.31,32.58 120.44,32.71 v2(121,32.71)
  BOTTOM w0.102: v2(127.52,82.31) 127.3,82.31 127.23,82.24 USOC1.V48 ; JDIMM2.164 120.3,32 v2(121,32.71)
DDR_A_D53: length 85.5
  IN2 w0.102: v2(128.06,81.85) 128.49,81.42 131.53,81.42 132.79,80.16 132.79,79.75 133.79,78.76
  IN2 w0.127: 133.79,78.76 137.25,75.29 137.25,61.46 118.41,42.62 117.46,41.67 117.46,38.2 117.33,38.07 116.41,38.07 116.28,37.94 116.28,36.51 116.15,36.38 114.98,36.38 114.86,36.25 114.86,35.87 114.98,35.75 116.15,35.75 116.28,35.62 116.28,35.24 116.15,35.11 113.63,35.11 113.51,34.98 113.51,33.45 113.63,33.32 114.23,33.32 114.36,33.45 114.36,34.35 114.48,34.48 116.15,34.48 116.28,34.35 116.28,33.97 116.15,33.84 115.61,33.84 115.49,33.71 115.49,33.33 115.61,33.21 116.15,33.21 116.28,33.08 116.28,32.7 116.15,32.57 115.61,32.57 115.49,32.44 115.49,30.88 115.61,30.75 120.57,30.75 v2(121,31.18)
  BOTTOM w0.102: USOC1.V50 127.99,81.78 v2(128.06,81.85) ; v2(121,31.18) 120.9,31.08 JDIMM2.166
DDR_A_D54: length 85.9
  IN2 w0.102: v2(126.81,84.49) 127.09,84.49 127.78,85.17 128.33,85.17 128.52,84.98 130.8,84.98 132.01,86.19
  IN2 w0.127: 132.01,86.19 136.96,86.19 137.92,85.24 143.06,85.24 144.8,83.5 145.14,83.15 145.14,79.13 143.98,77.96 143.98,76.95 143.94,76.91 143.49,76.46 143.49,76.23 142.96,75.69 142.96,57.19 137.8,52.03 137.8,48.44 130.98,41.61 130.98,41.43 131.07,41.34 131.07,41.16 130.8,40.89 130.62,40.89 130.53,40.98 130.35,40.98 130.08,40.72 130.08,40.54 130.17,40.44 130.17,40.26 129.91,39.99 129.73,39.99 129.63,40.09 129.45,40.09 129.18,39.82 129.18,39.64 129.28,39.54 129.28,39.36 129.01,39.09 128.83,39.09 128.73,39.19 128.55,39.19 128.28,38.92 128.28,38.74 128.38,38.65 128.38,38.47 128.11,38.2 127.93,38.2 127.84,38.29 127.66,38.29 122.86,33.5 122.86,31.77 v2(123.45,31.18)
  BOTTOM w0.102: JDIMM2.174 123.3,31.04 v2(123.45,31.18) ; USOC1.AB44 126.88,84.56 v2(126.81,84.49)
DDR_A_D55: length 86.2
  IN2 w0.102: 131.76,86.57 130.38,85.19 128.6,85.19 128.36,85.43 127.42,85.43 126.88,84.89 126.68,84.89 126.4,84.62 126.4,84.36 v2(126,83.96)
  IN2 w0.127: v2(123.45,32.71) 138.52,47.78 138.52,51.92 143.54,56.94 143.54,75.45 144.07,75.98 144.07,76.22 144.58,76.73 144.58,77.74 145.73,78.89 145.73,83.4 145.38,83.74 145.04,84.08 143.3,85.82 138.17,85.82 137.42,86.57 131.76,86.57
  BOTTOM w0.102: v2(123.45,32.71) 123.9,32.26 JDIMM2.176 ; v2(126,83.96) 126.34,83.96 126.37,83.93 USOC1.Y45
DDR_A_D56: length 72.9
  IN1 w0.102: v2(131.62,78.69) 131.62,78.61 132.63,77.6
  IN1 w0.127: 132.63,77.6 137.57,72.66 137.57,67.47 137.93,67.11 137.93,56.74 128.1,46.91 128.1,45.36 127.97,45.23 126.8,45.23 126.68,45.1 126.68,44.72 126.8,44.6 127.97,44.6 128.1,44.47 128.1,44.09 127.97,43.96 125.24,43.96 125.11,43.83 125.11,43.31 124.99,43.19 124.38,43.19 124.25,43.06 124.25,42.57 124.38,42.44 125.06,42.44 125.19,42.31 125.19,41.96 125.32,41.83 125.84,41.83 125.96,41.96 125.96,43.2 126.09,43.33 127.97,43.33 128.1,43.2 128.1,42.82 127.97,42.69 126.97,42.69 126.84,42.56 126.84,42.18 126.97,42.06 127.97,42.06 128.1,41.93 128.1,40.32 127.97,40.19 127.37,40.19 127.25,40.32 127.25,40.98 127.12,41.1 v2(126.46,41.1)
  BOTTOM w0.102: v2(126.46,41.1) 126.09,41.1 125.96,41.23 125.96,42.08 125.84,42.21 125.38,42.21 125.25,42.08 125.25,39.09 125.4,38.94 JDIMM2.181 ; v2(131.62,78.69) 131.44,78.52 130.63,78.52 128.4,80.75 USOC1.V52
DDR_A_D57: length 72.3
  IN1 w0.102: 133.05,78.02 132.26,78.8 v2(132.26,78.82)
  IN1 w0.127: 133.05,78.02 138.16,72.9 138.16,67.71 138.52,67.35 138.52,56.38 129.69,47.55 129.69,46.32 129.57,46.2 128.81,46.2 128.68,46.07 128.68,39.92 128.34,39.58 127.3,39.58 127.17,39.45 127.17,39.05 127.04,38.92 126.21,38.92 126.08,38.79 126.08,38.44 126.21,38.31 126.43,38.31 126.56,38.18 126.56,37.73 126.43,37.6 125.58,37.6 125.46,37.47 125.46,36.32 125.33,36.19 124.16,36.19 124.03,36.32 124.03,36.93 124.16,37.05 124.69,37.05 124.82,37.18 124.82,37.55 124.69,37.68 124.16,37.68 124.03,37.8 124.03,38.25 124.16,38.37 125.05,38.37 125.18,38.5 125.18,41.05 125.3,41.18 125.74,41.18 125.86,41.05 125.86,39.71 125.99,39.58 v2(126.46,39.58)
  BOTTOM w0.102: JDIMM2.183 126,39.33 125.82,39.51 125.82,39.69 125.99,39.87 126.17,39.87 v2(126.46,39.58) ; USOC1.W51 128.49,81.23 128.71,81.01 128.71,80.75 130.56,78.9 131.06,78.9 131.24,79.08 132.01,79.08 v2(132.26,78.82)
DDR_A_D58: length 73.2
  IN1 w0.102: 135.81,83.9 135.39,83.9 135.17,84.12 v2(135.17,84.39)
  IN1 w0.127: v2(129.41,34.35) 130.02,34.35 130.24,34.58 130.24,35.73 130.6,36.08 130.6,36.71 131.55,37.66 132.81,38.92 132.99,38.92 133.42,38.48 133.6,38.48 133.87,38.75 133.87,38.93 133.44,39.37 133.44,39.55 133.71,39.82 133.89,39.82 134.33,39.38 134.51,39.38 134.78,39.64 134.78,39.82 134.33,40.27 134.33,40.45 134.6,40.71 134.78,40.71 135.13,40.37 135.3,40.37 135.57,40.64 135.57,40.82 135.26,41.14 135.26,42.07 135.55,42.36 135.55,43.2 136.7,44.34 136.7,48.61 142.19,54.1 142.19,74.04 136.34,79.89 136.34,83.54 135.97,83.9 135.81,83.9
  BOTTOM w0.102: v2(135.17,84.39) 134.36,83.58 133.75,83.58 131.92,81.75 130.94,81.75 USOC1.AC53 ; v2(129.41,34.35) 129.28,34.35 128.71,34.92 128.71,35.2 128.4,35.51 JDIMM2.191
DDR_A_D59: length 74.1
  IN1 w0.102: v2(134.51,84.37) 135,84.86 135.85,84.86 136.3,84.4
  IN1 w0.127: 136.3,84.4 136.92,83.78 136.92,80.13 142.77,74.28 142.77,53.86 137.28,48.37 137.28,44.1 136.16,42.98 136.16,40.2 133.52,37.56 133.3,37.56 132.91,37.95 132.73,37.95 132.46,37.68 132.46,37.5 133.11,36.85 133.11,36.67 132.84,36.4 132.66,36.4 132.01,37.05 131.83,37.05 131.56,36.79 131.56,36.61 132.21,35.96 132.21,35.44 131.5,34.73 131.32,34.73 v2(131.1,34.96)
  BOTTOM w0.102: JDIMM2.193 129,35.86 129.27,35.59 129.27,35.19 129.5,34.96 v2(131.1,34.96) ; 129.87,82.83 130.05,82.83 130.26,82.62 130.53,82.62 131.11,82.04 131.83,82.04 133.75,83.96 134.1,83.96 v2(134.51,84.37)
DDR_A_D60: length 72.5
  IN1 w0.102: v2(131.77,79.46) 131.77,79.46 131.77,79.45 131.98,79.23 132.66,79.23 133.46,78.43
  IN1 w0.127: 133.46,78.43 138.74,73.15 138.74,67.96 139.1,67.59 139.1,55.71 131.14,47.75 131.14,47.14 130.96,46.96 130.44,46.96 130.31,46.83 130.31,46.4 130.44,46.27 130.66,46.27 130.79,46.15 130.79,45.7 130.66,45.58 129.44,45.58 129.26,45.4 129.26,44.98 129.39,44.85 130.05,44.85 130.18,44.72 130.18,44.34 130.05,44.22 129.39,44.22 129.26,44.09 129.26,43.71 129.39,43.58 130,43.58 130.13,43.45 130.13,43.07 130,42.95 129.39,42.95 129.26,42.82 129.26,42.46 129.39,42.33 129.9,42.33 130.03,42.21 130.03,41.83 129.9,41.7 129.39,41.7 129.26,41.57 129.26,39.65 127.15,37.54 127.15,36.58 126.63,36.06 126.04,36.06 125.91,35.94 125.91,35.73 125.79,35.61 125.05,35.61 124.92,35.48 124.92,35.03 125.05,34.91 125.79,34.91 125.91,34.78 125.91,34.37 125.79,34.25 124.91,34.25 124.78,34.12 124.78,32.84 124.91,32.71 v2(126.08,32.71)
  BOTTOM w0.102: JDIMM2.180 125.1,31.72 v2(126.08,32.71) ; v2(131.77,79.46) 131.77,79.46 131.77,79.45 131.73,79.48 130.26,79.48 129.02,80.72 USOC1.W53
DDR_A_D61: length 73.2
  IN1 w0.102: 133.91,78.88 132.68,80.11 131.69,80.11 v2(131.63,80.04)
  IN1 w0.127: v2(126.08,31.18) 127.12,31.18 127.25,31.31 127.25,31.67 127.12,31.8 126.65,31.8 126.52,31.92 126.52,32.29 126.72,32.49 126.87,32.49 126.99,32.62 126.99,33 126.87,33.13 126.69,33.13 126.56,33.25 126.56,33.63 126.69,33.76 127.07,33.76 127.2,33.89 127.2,34.27 127.07,34.4 126.66,34.4 126.54,34.52 126.54,35.05 126.66,35.17 126.82,35.17 126.94,35.3 126.94,35.52 127.73,36.3 127.73,37.29 130.57,40.13 130.57,40.76 130.7,40.89 131.31,40.89 131.44,41.02 131.44,41.37 131.31,41.49 130.85,41.49 130.73,41.62 130.73,42 130.85,42.13 131.31,42.13 131.44,42.25 131.44,42.64 131.31,42.76 130.88,42.76 130.75,42.89 130.75,43.27 130.88,43.4 131.31,43.4 131.44,43.52 131.44,43.91 131.31,44.03 130.93,44.03 130.8,44.16 130.8,44.54 130.93,44.67 131.31,44.67 131.44,44.79 131.44,46.48 131.56,46.6 132.72,46.6 132.85,46.73 132.85,47.06 132.72,47.19 132.01,47.19 131.88,47.32 131.88,47.65 132.01,47.77 132.45,47.77 132.58,47.9 132.58,48.18 139.69,55.28 139.69,67.84 139.33,68.2 139.33,73.46 133.91,78.88
  BOTTOM w0.102: JDIMM2.182 125.7,30.8 v2(126.08,31.18) ; v2(131.63,80.04) 129.99,80.04 129.49,80.54 129.49,80.86 129.11,81.24 128.94,81.24 128.79,81.39 128.79,81.59 128.6,81.78 USOC1.Y51
DDR_A_D62: length 72.2
  IN1 w0.102: 136.72,84.81 136.33,85.2 134.66,85.2 v2(133.82,84.37)
  IN1 w0.127: 136.72,84.81 137.5,84.02 137.5,80.37 143.36,74.52 143.36,53.62 137.86,48.13 137.86,43.86 136.74,42.73 136.74,39.48 133.06,35.8 133.06,35.42 130.36,32.71 v2(129.43,32.71)
  BOTTOM w0.102: USOC1.AD52 130.65,82.92 131.26,82.31 131.74,82.31 133.8,84.37 v2(133.82,84.37) ; JDIMM2.192 128.7,31.98 v2(129.43,32.71)
DDR_A_D63: length 73.4
  IN1 w0.102: v2(133.8,85.03) 134.58,85.81 136.9,85.81 137.31,85.4
  IN1 w0.127: 137.31,85.4 138.14,84.57 138.14,80.57 143.94,74.76 143.94,53.38 138.45,47.88 138.45,43.61 137.81,42.97 137.81,39.7 133.71,35.59 133.71,35.11 129.79,31.18 v2(129.43,31.18)
  BOTTOM w0.102: v2(133.8,85.03) 133.41,84.64 133.41,84.57 132.14,83.29 131.35,83.29 131.34,83.3 130.82,83.3 130.73,83.22 130.17,83.22 USOC1.AD51 ; v2(129.43,31.18) 129.3,31.06 JDIMM2.194
DDR_A_DM0: length 88.2
  IN1 w0.102: 117.36,80.75 117.36,81.04 118.64,82.32 v2(119.14,82.32)
  IN1 w0.127: v2(72,36.62) 71.68,36.62 71.56,36.49 71.56,35.8 71.43,35.67 70.98,35.67 70.86,35.8 70.86,41.7 70.86,42.27 71.27,42.68 71.27,44.47 88.22,61.43 91.79,61.43 95.19,64.82 95.8,64.82 96.49,64.13 96.67,64.13 97,64.47 97,64.65 96.04,65.61 96.04,65.79 96.39,66.14 96.57,66.14 97.55,65.16 97.72,65.16 98,65.44 98,65.62 97.35,66.27 97.35,66.45 97.62,66.72 97.8,66.72 98.45,66.07 98.63,66.07 98.9,66.34 98.9,66.52 98.61,66.81 98.61,66.99 98.88,67.26 99.06,67.26 99.35,66.97 99.53,66.97 99.8,67.24 99.8,67.42 99.51,67.71 99.51,67.89 99.78,68.16 99.96,68.16 100.25,67.87 100.43,67.87 100.7,68.13 100.7,68.31 100.41,68.6 100.41,68.78 100.68,69.05 100.86,69.05 101.15,68.76 101.32,68.76 101.59,69.03 101.59,69.21 101.3,69.5 101.3,69.68 101.57,69.95 101.75,69.95 102.04,69.66 102.22,69.66 102.46,69.9 102.46,70.08 102.17,70.37 102.17,70.55 102.44,70.82 102.62,70.82 102.91,70.53 103.09,70.53 103.36,70.8 103.36,70.98 103.07,71.27 103.07,71.44 103.34,71.71 103.52,71.71 103.81,71.42 103.99,71.42 105.12,72.56 106.47,72.56 112.12,78.21 114.12,78.21 115.47,79.56 116.17,79.56 117.36,80.75
  BOTTOM w0.102: JDIMM2.11 72,36.62 v2(72,36.62) ; v2(119.14,82.32) 118.91,82.54 USOC1.G36
DDR_A_DM1: length 73.3
  IN1 w0.127: v2(114.85,73.55) 114.67,73.72 113.01,73.72 111.89,72.61 111.89,72.08 110.75,70.94 110.75,68.08 95.65,52.98 89.79,52.98 84.8,48 83.63,48 77.58,41.95 77.58,36.3 77.37,36.09 77.37,33.96 77.53,33.8 77.53,31.63 v2(77.11,31.21)
  BOTTOM w0.102: JDIMM2.28 77.1,31.2 v2(77.11,31.21) ; v2(114.85,73.55) 114.77,73.62 114.77,75.28 115.33,75.84 115.33,79.18 USOC1.B36
DDR_A_DM2: length 82
  IN2 w0.102: v2(119.24,81.04) 119.24,81.56 119.54,81.87 119.86,81.87 120.08,81.65 120.08,81.06 119.03,80 118.3,80 118.19,80.11 116.53,80.11 116.39,79.97 113.44,79.97 112.83,79.36 112.6,79.36
  IN2 w0.127: v2(82.5,31.28) 81.95,31.84 81.95,32.47 82.09,32.61 82.09,51.33 82.21,51.45 83.74,51.45 83.86,51.58 83.86,52.22 83.74,52.34 82.21,52.34 82.09,52.47 82.09,53.02 82.21,53.15 83.17,53.15 83.29,53.27 83.29,53.96 83.42,54.08 83.97,54.08 84.09,53.96 84.09,53.47 84.22,53.34 84.72,53.34 84.85,53.47 84.85,55.98 103.37,74.51 104.06,74.51 107.36,77.81 109.66,77.81 110.39,78.54 111.03,78.54 111.34,78.85 111.34,78.85 111.84,79.36 112.6,79.36
  BOTTOM w0.102: v2(119.24,81.04) 119.24,81.45 USOC1.F38 ; JDIMM2.46 v2(82.5,31.28)
DDR_A_DM3: length 66.8
  IN1 w0.127: v2(88.21,36.52) 88.21,36.77 88.03,36.95 87.22,36.95 87.09,37.08 87.09,37.46 87.22,37.59 88.48,37.59 88.61,37.71 88.61,38.09 88.48,38.22 87.2,38.22 87.08,38.35 87.08,38.73 87.2,38.86 88.38,38.86 88.51,38.98 88.51,42.06 89.9,43.44 90.87,43.44 91,43.57 91,43.86 91.12,43.99 91.5,43.99 91.63,43.86 91.63,43.57 91.76,43.44 92.14,43.44 92.27,43.57 92.27,43.86 92.39,43.99 92.77,43.99 92.9,43.86 92.9,43.57 93.03,43.44 95.32,43.44 117.65,65.77 117.65,70.94 117.41,71.17 v2(117.41,71.62)
  BOTTOM w0.102: JDIMM2.63 87.6,37.13 v2(88.21,36.52) ; v2(117.41,71.62) 117.77,71.99 117.77,74.29 118.25,74.77 118.25,78.14 118.46,78.35 118.74,78.35 119.09,78.7 USOC1.B42
DDR_A_DM4: length 61
  IN1 w0.127: v2(112.83,31.46) 111.47,32.82 111.47,44.28 119.51,52.31 119.51,54.21 120.19,54.88 120.19,57.37 125.77,62.96 125.77,66.66 129.13,70.01 v2(129.65,70.01)
  BOTTOM w0.102: USOC1.P51 126.73,79.78 127.2,79.78 127.33,79.65 127.33,79.46 129.96,76.83 129.96,70.32 v2(129.65,70.01) ; v2(112.83,31.46) 112.5,31.46 111.9,30.86 JDIMM2.136
DDR_A_DM5: length 70.8
  IN1 w0.102: v2(125.21,84.71) 124.97,84.71 124.67,84.41 124.67,84.26 129.05,79.88 129.05,79.43 129.18,79.31 129.34,79.31 129.47,79.18 129.47,78.9 129.34,78.77 129.09,78.77 128.96,78.65 128.96,78.37 129.09,78.24 129.43,78.24 129.56,78.11 129.56,76.45 130.49,75.52
  IN1 w0.127: 130.49,75.52 134.03,71.98 134.03,71.83 134.19,71.66 134.35,71.66 134.45,71.56 134.45,71.15 134.3,70.99 134.17,70.99 134.04,70.87 134.04,70.48 134.17,70.36 134.3,70.36 134.42,70.23 134.42,57.8 134.04,57.42 134.04,57.29 134.11,57.22 134.11,57.06 133.76,56.71 133.58,56.71 133.54,56.74 133.36,56.74 133.09,56.47 133.09,56.29 133.13,56.26 133.13,56.08 132.86,55.81 132.68,55.81 132.64,55.84 132.46,55.84 132.2,55.57 132.2,55.39 132.23,55.36 132.23,55.18 131.96,54.91 131.78,54.91 131.75,54.94 131.57,54.94 131.3,54.67 131.3,54.49 131.33,54.46 131.33,54.28 131.06,54.01 130.88,54.01 130.85,54.05 130.67,54.05 130.4,53.78 130.4,53.6 130.43,53.56 130.43,53.38 130.16,53.11 129.98,53.11 129.95,53.15 129.77,53.15 129.5,52.88 129.5,52.7 129.53,52.66 129.53,52.49 129.26,52.22 129.08,52.22 129.05,52.25 128.87,52.25 128.6,51.98 128.6,51.8 128.64,51.77 128.64,51.59 128.37,51.32 128.19,51.32 128.15,51.35 127.97,51.35 127.7,51.08 127.7,50.9 127.74,50.87 127.74,50.69 127.47,50.42 127.29,50.42 127.26,50.45 127.08,50.45 126.81,50.18 126.81,50 126.84,49.97 126.84,49.79 126.57,49.52 126.39,49.52 126.36,49.55 126.18,49.55 125.91,49.29 125.91,49.11 125.94,49.07 125.94,48.89 125.67,48.62 125.49,48.62 125.46,48.66 125.28,48.66 125.01,48.39 125.01,48.21 125.04,48.17 125.04,47.99 124.77,47.73 124.59,47.73 124.56,47.76 124.38,47.76 124.11,47.49 124.11,47.31 124.14,47.28 124.14,47.1 123.88,46.83 123.7,46.83 123.66,46.86 123.48,46.86 123.21,46.59 123.21,46.41 123.25,46.38 123.25,46.2 122.98,45.93 122.8,45.93 122.76,45.96 122.58,45.96 122.32,45.69 122.32,45.51 122.35,45.48 122.35,45.3 122.07,45.02 121.91,45.02 121.87,45.06 121.69,45.06 121.33,44.7 121.33,43.85 121.09,43.61 120.31,43.61 119.08,42.38 119.08,39.41 119.6,38.89 119.6,37.3 119.44,37.14 119.34,37.03 119.34,36.84 119.74,36.43 119.74,36.2 119.5,35.96 119.16,35.96 118.74,36.37 v2(118.74,36.54)
  BOTTOM w0.102: JDIMM2.153 117,37.07 117.52,36.54 v2(118.74,36.54) ; 124.99,84.25 124.99,84.5 v2(125.21,84.71)
DDR_A_DM6: length 86
  IN2 w0.102: v2(128.23,83.09) 128.74,82.58 130.06,82.58 130.63,83.15 134.59,83.15 134.97,82.78
  IN2 w0.127: v2(122.22,32.71) 122.22,39.8 121.89,40.13 121.89,42.47 122.75,43.33 124.14,43.33 130.98,50.17 131.16,50.17 131.37,49.95 131.55,49.95 131.82,50.22 131.82,50.4 131.61,50.62 131.61,50.8 131.88,51.07 132.06,51.07 132.27,50.85 132.45,50.85 132.72,51.12 132.72,51.3 132.51,51.52 132.51,51.7 132.77,51.96 132.95,51.96 133.17,51.75 133.35,51.75 133.62,52.02 133.62,52.2 133.4,52.41 133.4,52.59 133.67,52.86 133.85,52.86 134.07,52.65 134.25,52.65 134.52,52.92 134.52,53.1 134.3,53.31 134.3,53.49 134.57,53.76 134.75,53.76 134.97,53.55 135.15,53.55 135.41,53.82 135.41,54 135.2,54.21 135.2,54.39 135.47,54.66 135.65,54.66 135.86,54.44 136.04,54.44 136.31,54.71 136.31,54.89 136.1,55.11 136.1,55.29 136.74,55.93 136.74,56.11 136.08,56.78 136.08,56.96 136.35,57.23 136.53,57.23 137.59,56.17 137.77,56.17 138.04,56.44 138.04,56.62 136.98,57.68 136.98,57.86 137.25,58.13 137.43,58.13 138.49,57.07 138.67,57.07 138.94,57.34 138.94,57.51 137.87,58.58 137.87,58.76 138.14,59.02 138.32,59.02 139.12,58.23 139.3,58.23 139.63,58.56 139.63,58.74 138.84,59.53 138.84,59.75 139.59,60.5 139.59,76.26 135.43,80.42 135.43,81.19 134.97,81.65 134.97,82.78
  BOTTOM w0.102: JDIMM2.170 122.1,31.1 122.74,31.74 122.74,32.19 v2(122.22,32.71) ; v2(128.23,83.09) 128.17,83.03 USOC1.Y50
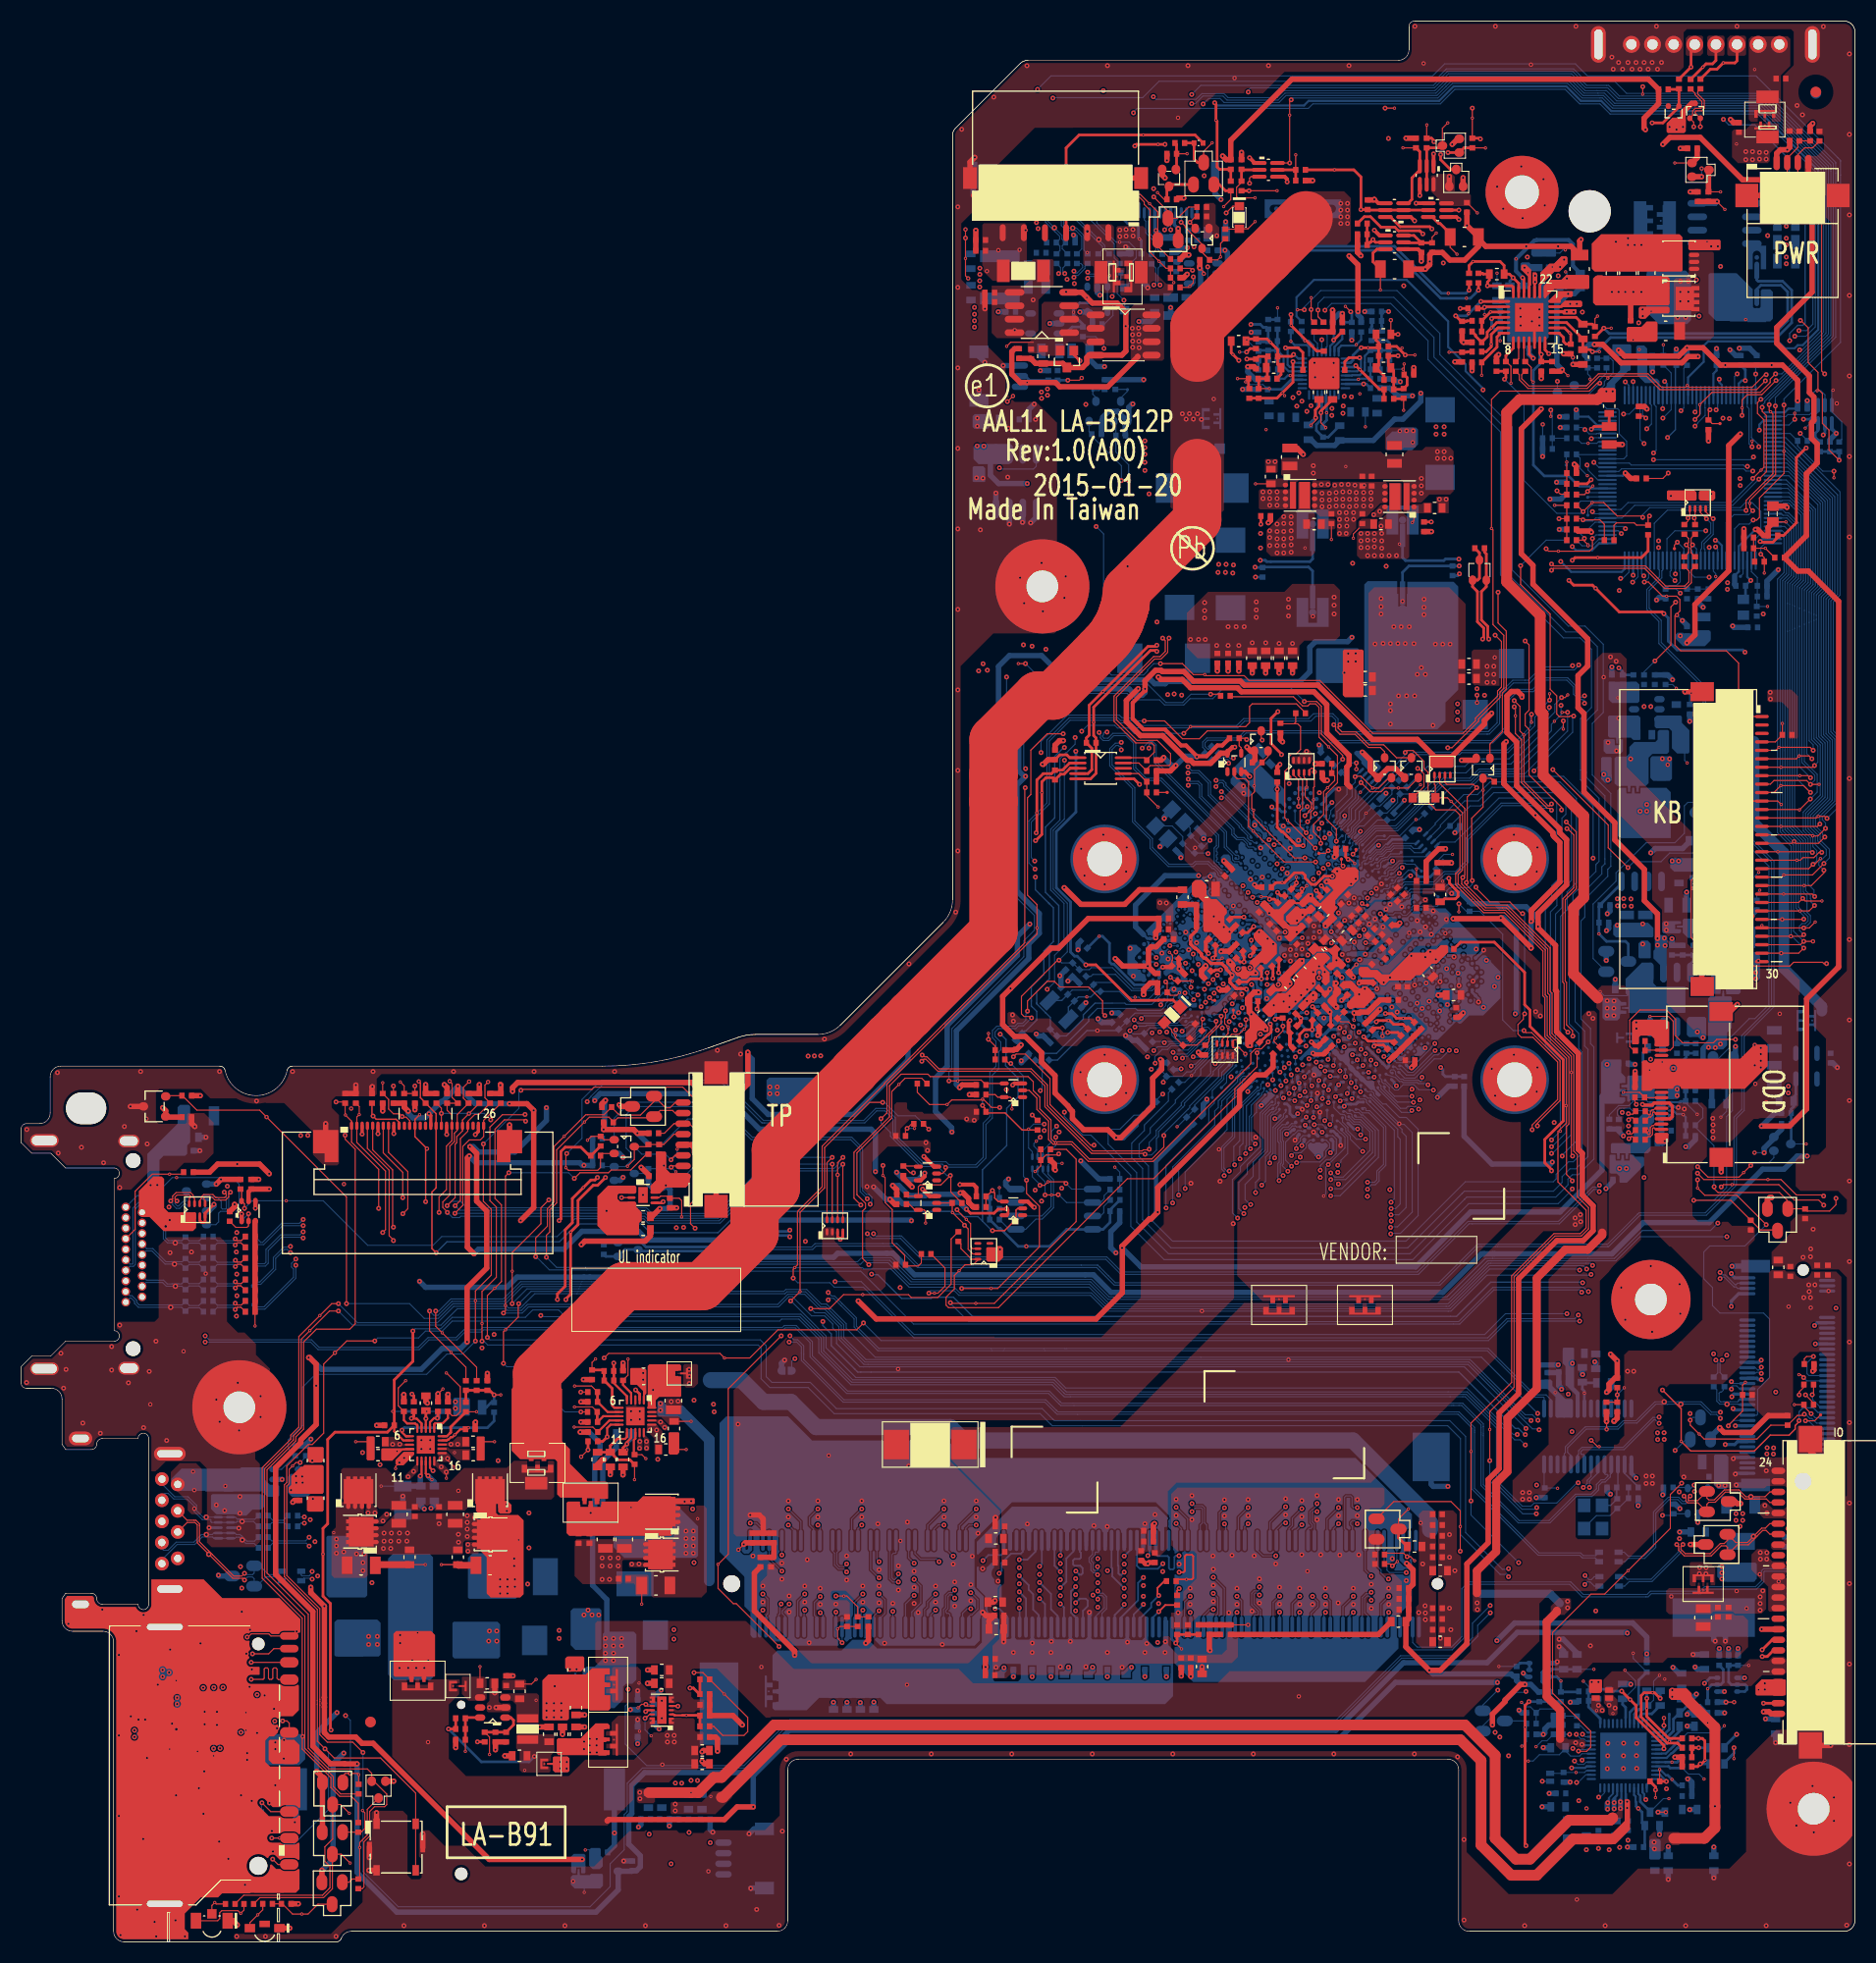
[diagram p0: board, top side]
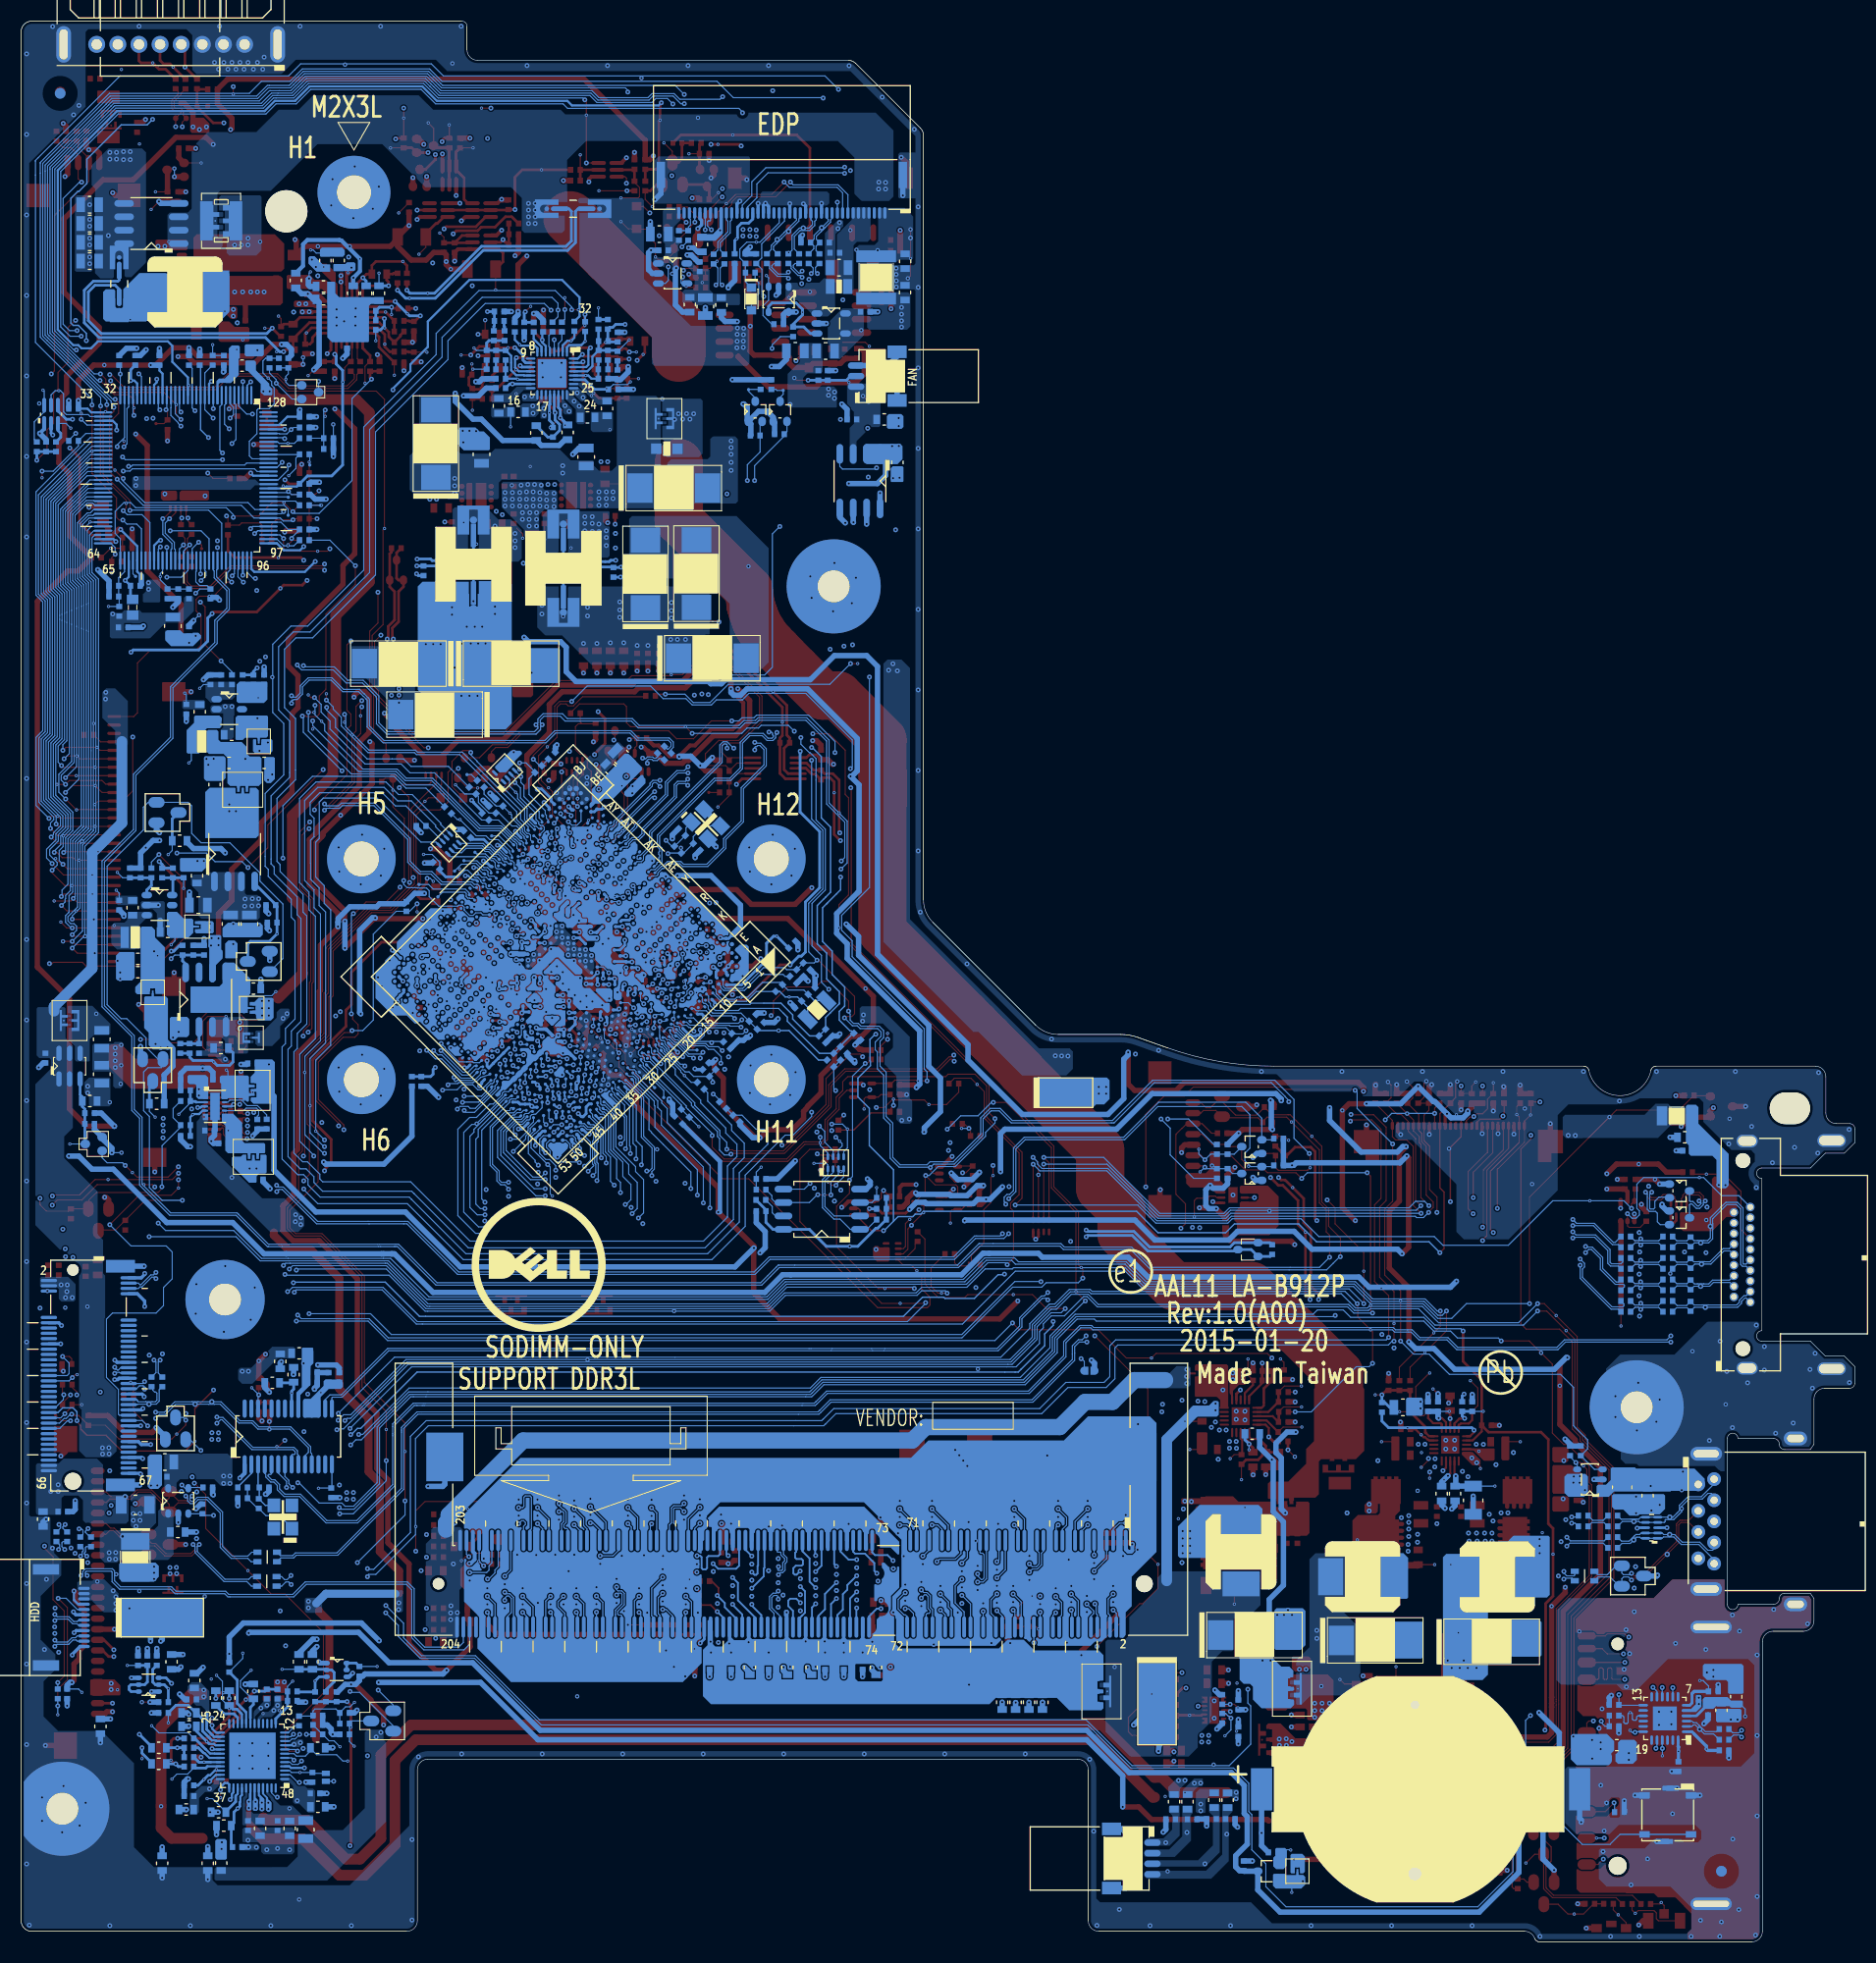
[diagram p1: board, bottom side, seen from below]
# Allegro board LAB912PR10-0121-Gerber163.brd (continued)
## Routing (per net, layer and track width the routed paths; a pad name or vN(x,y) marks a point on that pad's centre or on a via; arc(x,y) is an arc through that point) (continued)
DDR_A_DM7: length 72.5
  IN1 w0.102: v2(133.66,80.61) 134.13,80.61 134.55,80.19 134.55,79.07
  IN1 w0.127: 134.55,79.07 140.01,73.61 140.01,72.45 140.14,72.32 140.24,72.32 140.36,72.2 140.36,71.81 140.24,71.69 140.14,71.69 140.01,71.56 140.01,71.18 140.14,71.05 140.24,71.05 140.36,70.93 140.36,70.54 140.24,70.42 140.14,70.42 140.01,70.29 140.01,69.91 140.14,69.78 140.24,69.78 140.36,69.66 140.36,68.02 140.27,67.93 140.27,55.03 133.48,48.24 133.48,46.12 133.36,45.99 132.17,45.99 132.05,45.86 132.05,45.48 132.17,45.35 133.34,45.35 133.47,45.23 133.47,44.85 133.34,44.72 132.19,44.72 132.06,44.59 132.06,44.21 132.19,44.08 133.33,44.08 133.46,43.96 133.46,43.58 133.33,43.45 132.2,43.45 132.07,43.32 132.07,42.94 132.2,42.81 133.34,42.81 133.47,42.69 133.47,42.2 133.34,42.07 132.24,42.07 132.02,41.85 132.02,40.75 128.31,37.04 128.31,35.96 127.53,35.17 127.53,34.86 v2(127.78,34.61)
  BOTTOM w0.102: v2(127.78,34.61) 127.2,35.19 JDIMM2.187 ; USOC1.Y52 129.77,80.86 129.79,80.86 130,80.65 130.32,80.65 130.8,81.13 131.81,81.13 132.28,80.66 133.62,80.66 v2(133.66,80.61)
DDR_A_DQS0: length 87.7
  IN1 w0.102: 116.25,81.02 116.26,81.02 116.27,81.03 116.71,81.03 119.35,83.67 120.01,83.67 120.15,83.54 120.15,83.32 v2(119.99,83.16)
  IN1 w0.127: v2(72.69,31.98) 72.54,31.98 72.25,32.27 72.25,33.43 71.08,34.61 70.27,34.61 70.06,34.81 70.06,37.58 69.79,37.86 69.4,37.86 69.27,37.99 69.27,38.37 69.4,38.49 69.79,38.49 70.06,38.77 70.06,42.65 70.48,43.06 70.48,44.79 88.03,62.34 89.53,62.34 89.83,62.64 89.83,63.3 89.96,63.43 90.4,63.43 90.53,63.3 90.53,62.56 90.81,62.29 91.53,62.29 91.81,62.56 91.81,63.76 92,63.95 93.12,63.95 96.65,67.48 98.02,67.48 103.37,72.83 104.22,72.83 104.72,73.32 106.11,73.32 111.86,79.08 113.6,79.08 115.55,81.02 116.25,81.02
  BOTTOM w0.102: JDIMM2.12 72.3,30.82 72.03,31.09 72.03,31.32 v2(72.69,31.98) ; USOC1.J38 120.11,83.04 v2(119.99,83.16)
DDR_A_DQS1: length 72.8
  IN1 w0.127: v2(78.13,35.78) 78.36,35.78 78.76,36.17 78.76,36.87 78.53,37.1 78.53,41.82 79.5,42.8 80.54,42.8 80.65,42.9 80.65,43.94 81.07,44.36 81.98,44.36 82.29,44.67 82.29,44.85 82.12,45.02 82.12,45.41 82.55,45.83 82.94,45.83 83.11,45.66 83.29,45.66 84.87,47.24 85.24,47.24 90.22,52.22 96,52.22 111.51,67.73 111.51,70.56 111.95,71 112.45,71 112.73,71.29 112.73,72.37 113.32,72.96 v2(114.34,72.96)
  BOTTOM w0.102: v2(114.34,72.96) 114.1,72.96 113.83,73.23 113.83,75.14 114.85,76.16 114.85,79.85 116.26,81.26 116.5,81.26 116.71,81.47 116.94,81.47 ; v2(78.13,35.78) 77.86,35.51 77.46,35.51 77.21,35.76 77.21,36.85 77.4,37.04 JDIMM2.29
DDR_A_DQS2: length 82.8
  IN2 w0.102: 113.17,78.78 113.85,79.46 114.38,79.46 114.66,79.73 116.63,79.73 116.8,79.9 118.08,79.9 118.53,79.45 119.61,79.45 119.72,79.56 119.72,79.81 119.66,79.87 v2(119.47,79.87)
  IN2 w0.127: 113.17,78.78 112.83,78.44 112.2,78.44 110.8,77.05 107.77,77.05 104.15,73.43 103.37,73.43 85.73,55.79 85.73,52.74 85.6,52.62 84.96,52.62 84.69,52.34 84.69,51.75 84.96,51.47 85.6,51.47 85.73,51.34 85.73,50.68 85.61,50.56 83.13,50.56 82.85,50.29 82.85,49.45 83.13,49.18 84.43,49.18 84.56,49.05 84.56,48.67 84.43,48.54 83.13,48.54 82.85,48.26 82.85,47.67 83.13,47.39 84.4,47.39 84.53,47.27 84.53,46.88 84.4,46.76 83.13,46.76 82.85,46.48 82.85,36.92 83.5,36.27 83.5,35.99 83.5,35.53 83.5,34.5 83.43,34.43 83.26,34.43 83.2,34.48 83.17,34.48 83.03,34.63 v2(83.03,34.83)
  BOTTOM w0.102: v2(119.47,79.87) 119.27,79.87 119.2,79.94 119.2,80.28 USOC1.D40 ; v2(83.03,34.83) 83.03,34.64 82.67,34.28 82.59,34.28 82.42,34.45 82.42,36.65 82.56,36.79 82.74,36.79 82.8,36.85 JDIMM2.47
DDR_A_DQS3: length 66.7
  IN1 w0.127: v2(88.35,32.54) 88.35,32.56 89.14,33.35 89.14,34.99 89.6,35.45 89.6,36.88 89.73,37 89.9,37 90.18,37.28 90.18,37.93 89.9,38.21 89.78,38.21 89.6,38.39 89.6,41.64 90.2,42.24 95.56,42.24 118.66,65.34 118.66,71.37 118.45,71.58 118.45,72.57 118.78,72.9 118.78,73.5 118.63,73.64 v2(118.63,74.21)
  BOTTOM w0.102: USOC1.B44 119.78,78.09 118.7,77.01 118.7,74.27 v2(118.63,74.21) ; v2(88.35,32.54) 88.05,32.85 87.89,32.85 87.72,32.68 87.72,31.57 87.52,31.37 87.52,31.2 87.62,31.1 87.79,31.1 87.9,30.99 JDIMM2.64
DDR_A_DQS4: length 61.4
  IN1 w0.102: 126.4,71.43 126.4,71.45 126.52,71.57 126.54,71.57
  IN1 w0.127: v2(110.81,41.49) 110.57,41.24 110.43,41.24 110.33,41.34 110.33,42.42 110.7,42.79 110.7,44.58 116.64,50.52 116.64,50.79 116.76,50.91 116.94,50.91 117.22,51.19 117.22,51.85 116.94,52.13 116.83,52.13 116.71,52.26 116.71,52.75 116.83,52.88 117.43,52.88 117.56,52.75 117.56,52.63 117.83,52.35 118.46,52.35 118.74,52.63 118.74,53.9 118.46,54.17 117.18,54.17 117.05,54.3 117.05,54.77 117.18,54.89 119.11,54.89 119.39,55.17 119.39,55.93 119.11,56.21 118.87,56.21 118.74,56.33 118.74,56.74 118.87,56.87 119.14,56.87 119.42,57.15 119.42,57.69 124.95,63.21 124.95,68.49 125.38,68.92 126.93,68.92 127.21,69.2 127.21,69.9 126.93,70.18 126.52,70.18 126.4,70.3 126.4,71.43 ; v2(127.42,71.24) 127.42,71.28 127.13,71.57 126.54,71.57
  BOTTOM w0.102: JDIMM2.137 112.2,39.45 112.01,39.64 112.01,41.06 111.79,41.28 111.02,41.28 v2(110.81,41.49) ; USOC1.N53 126.96,78.88 127.04,78.96 127.18,78.96 127.27,78.87 127.27,78.73 127.32,78.68 127.63,78.68 129.16,77.16 129.16,73.5 128.52,72.86 128.52,72.03 128.16,71.66 127.78,71.66 127.42,71.3 v2(127.42,71.24)
DDR_A_DQS5: length 70.1
  IN1 w0.102: 128.27,79.58 128.26,79.59 128.25,79.59 127.94,79.91 127.94,80.33 125.2,83.07 124.76,83.07 124.64,82.94 v2(124.19,82.94)
  IN1 w0.127: 128.27,79.58 128.55,79.3 128.55,78.05 129.34,77.26 129.34,75.59 129.95,74.98 133.28,71.65 133.28,69.55 133.66,69.17 133.66,58.12 118.31,42.76 118.31,38.9 118.43,38.78 118.55,38.78 118.83,38.51 118.83,37.63 118.55,37.36 117.56,37.36 117.43,37.23 117.43,35.43 117.56,35.3 118.77,35.3 119.05,35.03 119.05,34.42 118.77,34.15 118.53,34.15 118.37,33.99 118.37,33.11 118.1,32.84 v2(117.19,32.84)
  BOTTOM w0.102: v2(117.19,32.84) 117.02,33 116.79,33 116.68,32.9 116.68,32 117.3,31.39 117.3,30.97 JDIMM2.154 ; USOC1.T42 124.32,83.07 v2(124.19,82.94)
DDR_A_DQS6: length 84.8
  IN2 w0.102: v2(127.23,84.05) 128.18,84.05 129.22,83.02 129.73,83.02 130.26,83.55 130.54,83.83 131.48,83.83 131.61,83.95 135.24,83.95 135.55,83.64
  IN2 w0.127: v2(122.65,40.72) 122.83,40.9 123.16,40.9 123.44,41.18 123.44,42.01 123.74,42.32 124.58,42.32 124.88,42.61 125.09,42.61 125.61,42.1 126,42.1 126.89,42.98 126.89,43.38 126.35,43.92 126.35,44.09 126.62,44.37 126.8,44.37 127.78,43.38 127.78,42.65 128.21,42.22 128.73,42.22 129.45,42.94 129.45,43.34 127.61,45.18 127.61,45.36 127.88,45.63 128.06,45.63 129.9,43.79 130.29,43.79 130.71,44.2 130.71,44.6 128.87,46.44 128.87,46.62 129.14,46.89 129.32,46.89 130.76,45.45 131.15,45.45 131.57,45.87 131.57,46.26 130.13,47.7 130.13,47.88 130.4,48.15 130.58,48.15 130.69,48.04 131.08,48.04 140.65,57.61 140.65,76.67 137.24,80.07 137.24,81.95 135.55,83.64
  BOTTOM w0.102: JDIMM2.171 122.4,39.57 122.19,39.77 122.19,40.61 122.31,40.72 v2(122.65,40.72) ; USOC1.Y47 127.19,84.01 v2(127.23,84.05)
DDR_A_DQS7: length 72.7
  IN1 w0.127: v2(132.58,81.84) 132.59,81.83 132.76,81.83 132.93,82 133.78,82 135.5,80.28 135.5,79.56 141.38,73.68 141.38,54.59 135.86,49.07 135.86,48.41 135.54,48.09 134.89,48.09 134.77,47.96 134.77,47.25 134.89,47.12 135.63,47.12 135.91,46.84 135.91,46.25 135.63,45.97 134.63,45.97 134.5,45.84 134.5,45.46 134.63,45.34 135.47,45.34 135.74,45.06 135.74,44.47 135.47,44.19 134.63,44.19 134.5,44.06 134.5,41.69 129.33,36.53 129.33,35.52 128.8,34.98 128.8,32.65 128.48,32.33 v2(127.78,32.33)
  BOTTOM w0.102: USOC1.AB52 129.66,82.23 129.57,82.32 129.57,82.44 129.66,82.53 129.91,82.53 130.08,82.37 130.08,82.11 130.53,81.66 130.75,81.66 130.86,81.55 132.27,81.55 132.37,81.45 132.48,81.45 132.58,81.55 v2(132.58,81.84) ; v2(127.78,32.33) 127.78,32.54 127.58,32.74 127.39,32.74 127.16,32.51 127.16,31.16 127.5,30.82 JDIMM2.188
DDR_A_DQS#0: length 87.6
  IN1 w0.102: v2(120.6,83.76) 120.25,83.76 120.11,83.9 119.26,83.9 116.61,81.26 116.27,81.26 116.26,81.27 116.25,81.27
  IN1 w0.127: v2(71.93,31.98) 72,32.05 72,33.33 70.97,34.35 70.16,34.35 69.81,34.71 69.81,37.48 69.68,37.6 69.3,37.6 69.02,37.88 69.02,38.47 69.3,38.75 69.68,38.75 69.81,38.88 69.81,42.75 70.22,43.17 70.22,44.89 87.93,62.6 89.42,62.6 89.58,62.75 89.58,63.41 89.85,63.69 90.51,63.69 90.79,63.41 90.79,62.67 90.92,62.54 91.42,62.54 91.55,62.67 91.55,63.87 91.89,64.21 93.01,64.21 96.54,67.74 97.92,67.74 103.27,73.09 104.12,73.09 104.61,73.58 106,73.58 111.75,79.33 113.5,79.33 115.44,81.27 116.25,81.27
  BOTTOM w0.102: JDIMM2.10 71.7,30.96 71.81,31.07 71.81,31.86 v2(71.93,31.98) ; v2(120.6,83.76) 120.61,83.75 USOC1.K38
DDR_A_DQS#1: length 72.8
  IN1 w0.127: v2(78.13,35.01) 78.14,35.02 78.14,35.19 79.01,36.06 79.01,36.98 78.78,37.21 78.78,41.71 79.61,42.54 80.65,42.54 80.91,42.79 80.91,43.84 81.17,44.1 82.09,44.1 82.55,44.56 82.55,44.96 82.38,45.12 82.38,45.3 82.65,45.57 82.83,45.57 83,45.4 83.39,45.4 84.97,46.99 85.35,46.99 90.33,51.96 96.11,51.96 111.77,67.63 111.77,70.46 112.06,70.75 112.55,70.75 112.99,71.18 112.99,72.26 113.25,72.53 v2(113.86,72.53)
  BOTTOM w0.102: JDIMM2.27 76.8,36.98 76.99,36.79 76.99,35.67 77.37,35.29 77.85,35.29 v2(78.13,35.01) ; v2(113.86,72.53) 113.86,72.9 113.62,73.14 113.62,75.23 114.63,76.25 114.63,79.94 116.26,81.56 USOC1.B34
DDR_A_DQS#2: length 82.8
  IN2 w0.102: 113.36,78.6 113.36,78.61 113.36,78.63 113.42,78.68 113.42,78.7 113.94,79.23 114.48,79.23 114.76,79.5 116.73,79.5 116.9,79.67 117.98,79.67 118.44,79.22 119.71,79.22 119.96,79.47 119.96,80.25 v2(120.01,80.3)
  IN2 w0.127: 113.36,78.6 113.27,78.52 112.94,78.19 112.3,78.19 110.91,76.79 107.88,76.79 104.26,73.17 103.48,73.17 85.98,55.68 85.98,52.64 85.71,52.36 85.07,52.36 84.94,52.23 84.94,51.85 85.07,51.72 85.71,51.72 85.98,51.45 85.98,50.58 85.71,50.31 83.23,50.31 83.1,50.18 83.1,49.56 83.23,49.43 84.54,49.43 84.82,49.15 84.82,48.56 84.54,48.28 83.23,48.28 83.1,48.16 83.1,47.78 83.23,47.65 84.51,47.65 84.78,47.37 84.78,46.78 84.51,46.5 83.23,46.5 83.1,46.37 83.1,37.03 83.75,36.38 83.75,35.99 83.75,35.53 83.75,34.39 83.45,34.08 83.04,34.08 v2(83.03,34.07)
  BOTTOM w0.102: v2(83.03,34.07) 82.5,34.07 82.2,34.36 JDIMM2.45 ; 119.8,80.89 119.8,80.51 v2(120.01,80.3)
DDR_A_DQS#3: length 67
  IN1 w0.127: v2(118.18,73.72) 118.23,73.72 118.38,73.57 118.38,73.54 118.52,73.39 118.52,73 118.19,72.67 118.19,71.48 118.41,71.26 118.41,65.45 95.45,42.49 90.09,42.49 89.34,41.74 89.34,38.28 89.67,37.95 89.8,37.95 89.92,37.83 89.92,37.39 89.8,37.26 89.62,37.26 89.34,36.98 89.34,35.56 88.89,35.1 88.89,33.53 88.66,33.3 v2(88.35,33.3)
  BOTTOM w0.102: v2(88.35,33.3) 88.12,33.07 87.8,33.07 87.5,32.77 87.5,31.66 87.3,31.46 JDIMM2.62 ; v2(118.18,73.72) 118.18,74.33 118.48,74.64 118.48,77.1 119.47,78.09 119.47,78.33 119.69,78.54 USOC1.C43
DDR_A_DQS#4: length 61.4
  IN1 w0.127: v2(110.81,40.72) 110.6,40.94 110.37,40.94 110.07,41.24 110.07,42.53 110.44,42.9 110.44,44.69 116.39,50.63 116.39,50.89 116.66,51.17 116.83,51.17 116.96,51.29 116.96,51.75 116.83,51.87 116.73,51.87 116.45,52.15 116.45,52.86 116.73,53.13 117.54,53.13 117.81,52.86 117.81,52.74 117.94,52.61 118.36,52.61 118.48,52.74 118.48,53.79 118.36,53.92 117.07,53.92 116.79,54.19 116.79,54.87 117.07,55.15 119.01,55.15 119.13,55.28 119.13,55.82 119.01,55.95 118.76,55.95 118.48,56.23 118.48,56.85 118.76,57.12 119.04,57.12 119.17,57.25 119.17,57.79 124.69,63.32 124.69,68.6 125.27,69.17 126.83,69.17 126.96,69.3 126.96,69.79 126.83,69.92 126.42,69.92 126.14,70.2 126.14,71.52 126.45,71.83 127.36,71.83 v2(127.42,71.9)
  BOTTOM w0.102: v2(127.42,71.9) 128.09,71.9 128.31,72.12 128.31,72.95 128.94,73.59 128.94,77.07 127.54,78.47 126.92,78.47 126.59,78.79 USOC1.M52 ; v2(110.81,40.72) 111.15,41.06 111.7,41.06 111.79,40.97 111.79,39.65 111.6,39.45 JDIMM2.135
DDR_A_DQS#5: length 70.1
  IN1 w0.102: 128.09,79.4 128.08,79.4 128.08,79.42 128.03,79.48 128.03,79.49 127.71,79.81 127.71,80.23 125.12,82.82 124.85,82.82 124.76,82.74 124.76,82.5 v2(124.82,82.44)
  IN1 w0.127: 128.09,79.4 128.29,79.19 128.29,77.94 129.09,77.15 129.09,75.48 132.53,72.04 132.53,72.04 133.03,71.54 133.03,69.44 133.4,69.07 133.4,58.22 118.05,42.87 118.05,38.79 118.32,38.53 118.45,38.53 118.57,38.4 118.57,37.74 118.45,37.61 117.45,37.61 117.17,37.34 117.17,35.32 117.45,35.05 118.66,35.05 118.79,34.92 118.79,34.53 118.66,34.4 118.42,34.4 118.12,34.09 118.12,33.22 117.99,33.09 117.58,33.09 117.19,33.48 v2(117.19,33.6)
  BOTTOM w0.102: v2(124.82,82.44) 124.82,82.44 USOC1.T44 ; JDIMM2.152 116.7,30.86 116.77,30.93 117,30.93 117.08,31.02 117.08,31.3 116.47,31.91 116.47,32.99 116.7,33.22 117.06,33.22 117.19,33.35 v2(117.19,33.6)
DDR_A_DQS#6: length 84.8
  IN2 w0.102: v2(127.75,83.47) 127.75,83.66 127.91,83.82 128.09,83.82 129.12,82.78 129.83,82.78 130.64,83.59 131.58,83.59 131.7,83.72 135.14,83.72 135.3,83.56 135.3,83.54 135.35,83.5 135.35,83.48 135.37,83.46
  IN2 w0.127: v2(122.65,41.49) 122.65,41.23 122.73,41.16 123.05,41.16 123.18,41.29 123.18,42.12 123.63,42.57 124.48,42.57 124.78,42.87 125.2,42.87 125.71,42.35 125.89,42.35 126.63,43.09 126.63,43.27 126.09,43.81 126.09,44.2 126.51,44.62 126.9,44.62 128.04,43.49 128.04,42.76 128.32,42.48 128.62,42.48 129.19,43.05 129.19,43.23 127.35,45.07 127.35,45.46 127.77,45.88 128.16,45.88 130,44.04 130.18,44.04 130.45,44.31 130.45,44.49 128.61,46.33 128.61,46.72 129.03,47.14 129.42,47.14 130.87,45.7 131.05,45.7 131.32,45.97 131.32,46.15 129.87,47.59 129.87,47.99 130.29,48.41 130.69,48.41 130.8,48.3 130.98,48.3 140.39,57.71 140.39,76.56 136.98,79.97 136.98,81.85 135.37,83.46
  BOTTOM w0.102: 127.69,82.93 127.69,83.41 v2(127.75,83.47) ; JDIMM2.169 121.8,39.02 121.9,39.12 122.07,39.12 122.18,39.24 122.18,39.48 121.98,39.68 121.98,40.7 122.22,40.94 122.28,40.94 122.66,41.32 122.66,41.47 v2(122.65,41.49)
DDR_A_DQS#7: length 72.7
  IN1 w0.127: v2(133.15,81.12) 132.86,81.12 132.75,81.24 132.75,81.43 133.06,81.75 133.67,81.75 135.25,80.17 135.25,79.45 141.13,73.57 141.13,54.7 135.6,49.18 135.6,48.52 135.43,48.34 134.79,48.34 134.51,48.07 134.51,47.14 134.79,46.86 135.53,46.86 135.65,46.74 135.65,46.36 135.53,46.23 134.52,46.23 134.24,45.95 134.24,45.36 134.52,45.08 135.36,45.08 135.49,44.95 135.49,44.57 135.36,44.45 134.52,44.45 134.24,44.17 134.24,41.8 129.08,36.63 129.08,35.63 128.54,35.09 128.54,32.75 128.38,32.59 128.12,32.59 127.78,32.93 v2(127.78,33.09)
  BOTTOM w0.102: USOC1.AA51 129.28,82.07 130.06,81.82 130.44,81.44 130.66,81.44 130.77,81.33 132.14,81.33 132.24,81.24 133.04,81.24 v2(133.15,81.12) ; v2(127.78,33.09) 127.64,32.95 127.3,32.95 126.94,32.6 126.94,30.86 126.9,30.82 JDIMM2.186
DDR_A_MA0: length 71.1
  IN2 w0.102: v2(123.16,79.82) 123.16,79.46 123.89,78.72 123.92,78.72 124.9,77.73 124.9,75.95 125.34,75.51 125.34,74.47 126.94,72.87 126.94,71.97
  IN2 w0.216: 126.94,71.97 126.94,67.17 118.43,58.66 116.96,58.66 114.82,56.53 113.85,56.53 101.07,43.75 101.07,33.36 100.86,33.15 100.86,32.51 101.15,32.22 101.15,31.91 100.77,31.53 100.64,31.53 100.39,31.28 100.39,30.95 100.25,30.81 99.25,30.81 99.1,30.96 99.1,31.95 99.25,32.1 v2(99.8,32.1)
  BOTTOM w0.165: v2(99.8,32.1) 100.18,32.48 100.77,32.48 100.95,32.3 100.95,31.78 100.5,31.34 JDIMM2.98 ; USOC1.K45 123.24,80.14 123.16,80.06 v2(123.16,79.82)
DDR_A_MA1: length 71.5
  IN2 w0.102: v2(122.62,79.03) 122.99,79.03 123.71,78.31 123.75,78.31 124.46,77.6 124.46,75.8 124.3,75.64 124.3,74.85 125.69,73.46 125.69,70.73
  IN2 w0.216: 125.69,70.73 125.69,69.12 125.19,68.62 125.19,68.4 125.61,67.98 125.61,67.61 125.29,67.29 124.99,67.29 124.58,67.7 124.27,67.7 123.97,67.39 123.97,67.09 124.38,66.68 124.38,66.37 124.07,66.07 123.77,66.07 123.36,66.48 123.05,66.48 122.74,66.17 122.74,65.87 123.15,65.46 123.15,65.15 122.85,64.85 122.54,64.85 122.13,65.26 121.83,65.26 121.52,64.95 121.52,64.65 121.93,64.24 121.93,63.93 121.63,63.62 121.32,63.62 120.91,64.03 120.61,64.03 120.3,63.73 120.3,63.42 120.71,63.01 120.71,62.71 120.41,62.4 120.1,62.4 119.69,62.81 119.38,62.81 119.08,62.51 119.08,62.2 119.49,61.79 119.49,61.49 117.91,59.91 116.44,59.91 114.31,57.77 113.33,57.77 99.76,44.2 99.76,35.15 v2(99.82,35.1)
  BOTTOM w0.102: 122.62,79.03 v2(122.62,79.03)
  BOTTOM w0.165: JDIMM2.97 100.2,36.92 100.3,36.83 100.3,36.37 100.17,36.24 99.69,36.24 99.56,36.11 99.56,35.73 99.69,35.61 100.23,35.61 100.46,35.38 100.46,34.89 100.33,34.76 100.16,34.76 v2(99.82,35.1) ; 123.1,79.22 122.91,79.03 122.62,79.03
DDR_A_MA2: length 70.1
  IN2 w0.102: v2(121.45,81.88) 121.21,82.12 121.21,82.13 121.21,82.25 121.47,82.51 121.84,82.51 121.97,82.38 121.97,81.73 121.59,81.36 121.59,80.98 122.27,80.3 122.27,80.06 123.81,78.52 123.83,78.52 124.66,77.69 124.66,75.72 124.5,75.55 124.5,74.99 126.31,73.18 126.31,71.35
  IN2 w0.216: v2(99.8,33.62) 99.84,33.59 100.29,33.59 100.44,33.75 100.44,44 113.59,57.15 114.56,57.15 116.7,59.29 118.17,59.29 126.31,67.43 126.31,71.35
  BOTTOM w0.165: v2(121.45,81.88) 121.45,81.94 USOC1.L41 ; v2(99.8,33.62) 99.36,33.18 99.36,31.16 99.62,30.9 99.63,30.9 99.69,30.84 99.9,30.63 JDIMM2.96
DDR_A_MA3: length 72.8
  IN2 w0.102: v2(122.08,79.63) 122.16,79.54 122.16,78.75 122.8,78.11 123.66,78.11 124.26,77.52 124.26,76.2 123.54,75.48 123.54,74.53 123.85,74.21 124.64,74.21 125.42,73.44 125.42,71.34 125.07,70.99 125.07,70.33
  IN2 w0.216: 125.07,70.33 125.07,69.38 118.03,62.34 118.03,62.07 118.46,61.64 118.46,61.33 118.15,61.03 117.84,61.03 117.42,61.46 117.11,61.46 114.05,58.4 113.08,58.4 103.08,48.4 102.77,48.4 102.39,48.77 102.09,48.77 101.78,48.47 101.78,48.16 102.16,47.78 102.16,47.48 101.85,47.17 101.55,47.17 101.17,47.55 100.86,47.55 100.56,47.25 100.56,46.94 100.94,46.56 100.94,46.26 100.63,45.95 100.33,45.95 99.95,46.33 99.64,46.33 99.34,46.02 99.34,45.72 99.72,45.34 99.72,45.04 99.14,44.46 99.14,33.75 98.91,33.52 v2(98.35,33.52)
  BOTTOM w0.165: USOC1.H44 122.12,80.07 122.08,80.03 v2(122.08,79.63) ; JDIMM2.95 99.6,36.97 98.93,36.29 98.93,34.09 v2(98.35,33.52)
DDR_A_MA4: length 71.7
  IN2 w0.102: 122.95,70.33 122.95,71.34 123.36,71.75 123.36,73.34 123.21,73.49 123.21,75.54 123.87,76.21 123.87,77.36 v2(123.88,77.36)
  IN2 w0.216: 122.95,70.33 122.95,69.9 117.3,64.25 114.9,64.25 110.65,60 110.34,60 109.88,60.46 109.7,60.46 109.27,60.02 109.27,59.84 109.73,59.39 109.73,59.08 109.42,58.78 109.12,58.78 108.47,59.42 108.17,59.42 107.86,59.12 107.86,58.81 108.51,58.17 108.51,57.86 108.2,57.56 107.9,57.56 107.25,58.2 106.94,58.2 106.64,57.9 106.64,57.59 107.29,56.95 107.29,56.64 106.98,56.33 106.67,56.33 106.03,56.98 105.72,56.98 105.42,56.68 105.42,56.37 106.06,55.72 106.06,55.42 105.76,55.11 105.45,55.11 104.81,55.76 104.5,55.76 97.01,48.27 97.01,35.4 97.78,34.63 97.78,32.57 v2(98.35,32)
  BOTTOM w0.102: USOC1.H50 124.11,77.59 v2(123.88,77.36)
  BOTTOM w0.165: JDIMM2.92 98.7,31.65 v2(98.35,32)
DDR_A_MA5: length 72.5
  IN2 w0.102: v2(124.61,73.52) 125.18,72.94 125.18,71.56 124.45,70.83 124.45,70.33
  IN2 w0.216: 124.45,70.33 124.45,69.64 117.12,62.31 116.9,62.31 116.22,61.63 115.93,61.63 115.25,62.31 114.74,62.31 114.45,62.02 114.45,61.72 115.28,60.88 115.28,60.7 114.85,60.27 114.67,60.27 113.84,61.11 113.53,61.11 113.22,60.8 113.22,60.5 114.06,59.66 114.06,59.48 113.63,59.05 113.45,59.05 112.61,59.88 112.31,59.88 112,59.58 112,59.27 112.39,58.89 112.39,58.59 112.08,58.28 111.77,58.28 111.39,58.66 111.09,58.66 110.78,58.36 110.78,58.05 111.16,57.67 111.16,57.36 110.86,57.06 110.55,57.06 110.17,57.44 109.86,57.44 109.56,57.14 109.56,56.83 109.94,56.45 109.94,56.14 109.64,55.84 109.33,55.84 108.95,56.22 108.64,56.22 108.34,55.91 108.34,55.61 108.72,55.23 108.72,54.92 108.41,54.61 108.11,54.61 107.73,55 107.42,55 107.12,54.69 107.12,54.39 107.5,54 107.5,53.7 107.19,53.39 106.89,53.39 106.5,53.78 106.2,53.78 105.89,53.47 105.89,53.16 106.28,52.78 106.28,52.48 105.97,52.17 105.67,52.17 105.28,52.55 104.98,52.55 104.67,52.25 104.67,51.94 105.05,51.56 105.05,51.26 104.75,50.95 104.44,50.95 104.06,51.33 103.76,51.33 103.45,51.03 103.45,50.72 103.83,50.34 103.83,50.03 103.53,49.73 103.22,49.73 102.84,50.11 102.53,50.11 98.41,45.99 98.41,36.63 v2(98.35,36.57)
  BOTTOM w0.102: v2(124.61,73.52) 124.91,73.82 124.91,73.98 125.54,74.61 125.54,76.21 124.98,76.77 USOC1.G53
  BOTTOM w0.165: v2(98.35,36.57) 98.4,36.62 JDIMM2.91
DDR_A_MA6: length 73
  IN2 w0.102: 121.71,70.5 121.71,72.7 122.34,73.34 122.34,75.13 123.51,76.3 123.51,76.96 123.38,77.09 v2(123.38,77.73)
  IN2 w0.216: 121.71,70.5 116.7,65.49 112.47,65.49 105.89,58.91 105.59,58.91 104.87,59.63 104.56,59.63 104.26,59.33 104.26,59.02 104.98,58.3 104.98,58 104.67,57.69 104.37,57.69 103.65,58.41 103.34,58.41 103.04,58.11 103.04,57.8 103.76,57.08 103.76,56.78 103.45,56.47 103.14,56.47 102.42,57.19 102.12,57.19 101.81,56.88 101.81,56.58 102.53,55.86 102.53,55.55 102.23,55.25 101.92,55.25 101.2,55.97 100.9,55.97 95.76,50.83 95.76,34.64 v2(96.39,34.02)
  BOTTOM w0.102: USOC1.H49 123.6,77.95 v2(123.38,77.73)
  BOTTOM w0.165: v2(96.39,34.02) 97.47,32.93 97.47,31.48 98.1,30.85 JDIMM2.90
DDR_A_MA7: length 69.6
  IN2 w0.102: v2(123.13,76.64) 123.13,76.34 122.11,75.32 122.11,73.44 121,72.33 121,70.95
  IN2 w0.216: v2(96.39,32.49) 95.14,33.74 95.14,38.78 94.67,39.25 94.67,50.76 104.65,60.74 104.96,60.74 105.75,59.95 106.05,59.95 106.36,60.26 106.36,60.56 105.57,61.35 105.57,61.66 105.88,61.96 106.18,61.96 106.97,61.17 107.27,61.17 107.58,61.48 107.58,61.78 106.79,62.57 106.79,62.88 107.1,63.18 107.4,63.18 108.19,62.4 108.5,62.4 112.21,66.11 116.37,66.11 120.95,70.69 120.95,70.9 121,70.95
  BOTTOM w0.102: USOC1.D50 122.8,76.97 v2(123.13,76.64)
  BOTTOM w0.165: JDIMM2.86 96.9,31.98 v2(96.39,32.49)
DDR_A_MA8: length 75.2
  IN2 w0.102: v2(123.71,73.57) 123.71,73.11 123.56,72.96 123.56,70.46 123.57,70.45 123.57,70.33
  IN2 w0.216: 123.57,70.33 123.57,70.17 123.69,70.05 123.69,69.76 117.56,63.62 115.16,63.62 105.61,54.07 105.3,54.07 104.66,54.72 104.35,54.72 104.05,54.42 104.05,54.11 104.69,53.46 104.69,53.16 104.39,52.85 104.08,52.85 103.43,53.5 103.13,53.5 102.82,53.19 102.82,52.89 103.47,52.24 103.47,51.94 103.17,51.63 102.86,51.63 102.21,52.28 101.91,52.28 101.6,51.97 101.6,51.67 102.25,51.02 102.25,50.71 101.94,50.41 101.64,50.41 100.99,51.06 100.69,51.06 100.38,50.75 100.38,50.45 101.03,49.8 101.03,49.49 100.72,49.19 100.42,49.19 99.77,49.83 99.46,49.83 99.16,49.53 99.16,49.22 99.81,48.58 99.81,48.27 99.5,47.97 99.2,47.97 98.55,48.61 98.24,48.61 97.94,48.31 97.94,48 98.58,47.35 98.58,47.05 97.64,46.11 97.64,35.76 v2(98.35,35.05)
  BOTTOM w0.102: v1(123.27,70.59) 123.48,70.8 123.48,73.33 v2(123.71,73.57) 125.29,75.15 125.29,76.16 124.91,76.54 124.86,76.54 124.42,76.98 USOC1.G52
  BOTTOM w0.165: JDIMM2.89 97.8,35.6 v2(98.35,35.05)
DDR_A_MA9: length 71.6
  IN2 w0.102: 122.33,70.5 122.33,72.42 v2(122.95,73.04)
  IN2 w0.216: 122.33,70.5 122.33,70.24 116.96,64.87 114.64,64.87 113.35,63.58 112.97,63.58 112.39,64.15 112.01,64.15 111.68,63.82 111.68,63.51 112.26,62.93 112.26,62.63 111.95,62.32 111.65,62.32 111.07,62.9 110.76,62.9 110.46,62.6 110.46,62.29 111.04,61.71 111.04,61.41 110.73,61.1 110.43,61.1 109.85,61.68 109.54,61.68 101.93,54.06 101.62,54.06 100.97,54.72 100.66,54.72 100.36,54.41 100.36,54.11 101.01,53.45 101.01,53.15 100.7,52.84 100.4,52.84 99.75,53.49 99.44,53.49 99.14,53.19 99.14,52.88 99.79,52.23 99.79,51.93 99.48,51.62 99.18,51.62 98.52,52.27 98.22,52.27 97.91,51.97 97.91,51.66 98.57,51.01 98.57,50.71 98.26,50.4 97.95,50.4 97.3,51.05 97,51.05 96.69,50.75 96.69,50.44 97.34,49.79 97.34,49.48 96.39,48.53 v2(96.39,35.54)
  BOTTOM w0.102: v2(122.95,73.04) 122.95,73.47 123.54,74.05 123.9,74.05 124.48,74.63 124.48,75.97 124.14,76.31 USOC1.E52
  BOTTOM w0.165: JDIMM2.85 96.6,35.76 v2(96.39,35.54)
DDR_A_MA10: length 74.5
  IN2 w0.102: 129.66,74.7 128.84,75.52 127.16,75.52 126.78,75.9 v2(126.78,76.39)
  IN2 w0.216: v2(104.4,33.47) 104.67,33.19 105.1,33.19 105.43,33.53 105.43,34.65 105.89,35.1 105.89,37.77 106.48,38.36 106.48,38.8 106.34,38.95 106.1,38.95 105.89,39.16 105.89,39.77 106.22,40.1 106.63,40.1 106.77,40.24 106.77,41.27 106.99,41.49 107.35,41.49 107.6,41.74 107.6,42.6 114.64,49.63 115.24,49.63 125.11,59.51 125.42,59.51 125.95,58.98 126.12,58.98 126.56,59.41 126.56,59.59 126.03,60.12 126.03,60.42 126.35,60.74 126.65,60.74 127.14,60.25 127.16,60.27 127.54,60.27 127.94,60.66 127.94,60.97 127.41,61.5 127.41,61.8 127.72,62.11 128.02,62.11 128.55,61.58 128.85,61.58 131.47,64.19 131.47,64.6 131.12,64.95 131.12,65.24 131.47,65.58 131.47,72.89 129.66,74.7
  BOTTOM w0.102: USOC1.K48 124.24,78.95 124.85,78.34 125.01,78.34 125.04,78.31 125.21,78.31 125.35,78.17 125.35,77.91 125.47,77.8 125.67,77.8 126.09,77.38 126.64,77.38 126.94,77.08 126.94,76.55 v2(126.78,76.39)
  BOTTOM w0.165: v2(104.4,33.47) 103.27,34.6 103.27,35.34 103.2,35.41 JDIMM2.107
DDR_A_MA11: length 74.3
  IN2 w0.102: v2(122.39,77.35) 121.68,76.64 121.68,73.62 120.23,72.17 120.23,71.76 118.79,70.33
  IN2 w0.216: 118.79,70.33 115.82,67.36 110.11,67.36 109.28,66.53 107.14,66.53 103.56,62.95 103.56,62.65 103.96,62.25 103.96,61.95 103.66,61.64 103.35,61.64 102.95,62.04 102.65,62.04 102.34,61.73 102.34,61.43 102.74,61.03 102.74,60.72 102.44,60.42 102.13,60.42 101.73,60.82 101.43,60.82 101.12,60.51 101.12,60.21 101.52,59.81 101.52,59.5 101.21,59.2 100.91,59.2 100.51,59.59 100.21,59.59 99.9,59.29 99.9,58.98 100.3,58.59 100.3,58.28 99.99,57.97 99.69,57.97 99.29,58.37 98.98,58.37 98.68,58.07 98.68,57.76 99.08,57.36 99.08,57.06 98.77,56.75 98.47,56.75 98.07,57.15 97.76,57.15 97.46,56.85 97.46,56.54 97.85,56.14 97.85,55.84 93.43,51.41 93.43,38.73 93.81,38.35 93.81,35.31 v2(94.47,34.65)
  BOTTOM w0.102: v2(122.39,77.35) 123.17,77.35 USOC1.E51
  BOTTOM w0.165: JDIMM2.84 96.3,30.93 95.78,31.45 95.78,32.91 95.36,33.33 95.36,33.77 v2(94.47,34.65)
DDR_A_MA12: length 70
  IN2 w0.102: v2(122.31,78.03) 122.77,77.58 122.77,76.92 122.72,76.87 122.72,76.45 121.89,75.61 121.89,73.52 120.55,72.19 120.55,71.49 120.51,71.45 ; 120.07,70.7 120.01,70.63
  IN2 w0.216: 120.01,70.63 116.11,66.74 111.96,66.74 111.44,66.22 111.18,66.22 110.67,66.72 110.5,66.72 109.93,66.16 109.93,65.98 110.28,65.63 110.28,65.09 109.93,64.74 109.64,64.74 108.6,65.78 108.42,65.78 107.91,65.26 107.91,65.08 108.94,64.06 108.94,63.88 108.5,63.45 108.33,63.45 106.79,64.98 106.47,64.98 105.83,64.34 105.83,64.04 106.23,63.64 106.23,63.33 105.92,63.03 105.62,63.03 105.22,63.42 104.92,63.42 104.61,63.12 104.61,62.81 105.01,62.41 105.01,62.11 94.05,51.15 94.05,38.99 94.42,38.63 94.52,38.52 94.52,36.23 v2(94.47,36.18) ; 120.07,70.7 120.33,70.95 120.33,71.27 120.51,71.45
  BOTTOM w0.165: v2(94.47,36.18) 95.23,36.18 96,36.95 JDIMM2.83 ; 122.31,78.61 122.31,78.6 v2(122.31,78.03)
DDR_A_MA13: length 71.8
  IN2 w0.102: v2(127.24,75.98) 127.24,76.34 127.82,76.92 128.32,76.92 130.1,75.14
  IN2 w0.216: v2(106.63,36.56) 106.74,36.66 106.74,37.73 108.23,39.22 108.23,42.34 114.9,49.01 116.11,49.01 117.93,50.83 118.19,50.83 118.45,50.58 118.73,50.58 119.04,50.89 119.04,51.19 118.51,51.72 118.51,52.03 118.82,52.33 119.13,52.33 119.65,51.8 119.96,51.8 120.26,52.11 120.26,52.41 119.74,52.94 119.74,53.25 120.04,53.55 120.35,53.55 120.87,53.03 121.18,53.03 121.49,53.33 121.49,53.64 120.96,54.16 120.96,54.47 121.26,54.77 121.57,54.77 122.1,54.25 122.4,54.25 122.71,54.55 122.71,54.86 122.18,55.39 122.18,55.69 122.49,56 122.79,56 123.32,55.47 123.62,55.47 123.96,55.81 123.96,56.11 123.44,56.64 123.44,56.95 123.74,57.25 124.05,57.25 124.57,56.73 124.88,56.73 125.18,57.03 125.18,57.34 124.66,57.86 124.66,58.17 124.96,58.47 125.27,58.47 125.8,57.95 126.1,57.95 132.09,63.94 132.09,73.15 130.1,75.14
  BOTTOM w0.102: v2(127.24,75.98) 126.37,75.98 125.57,76.78 125.57,77.1 125.06,77.61 USOC1.J51
  BOTTOM w0.165: JDIMM2.119 106.8,36.73 v2(106.63,36.56)
DDR_A_MA14: length 71
  IN2 w0.102: 118.26,70.86 118.5,70.86 121.48,73.84 121.48,74.48 120.87,75.09 v2(120.69,75.09)
  IN2 w0.216: 118.26,70.86 117.79,70.39 115.62,70.39 113.21,67.98 109.47,67.98 108.82,67.34 106.55,67.34 96.1,56.88 96.1,56.57 96.75,55.92 96.75,55.61 96.45,55.31 96.14,55.31 95.48,55.96 95.18,55.96 94.87,55.66 94.87,55.35 95.53,54.7 95.53,54.39 95.22,54.09 94.92,54.09 94.26,54.74 93.96,54.74 93.53,54.31 93.53,53.93 94.04,53.42 94.04,52.9 92.77,51.63 92.77,38.1 93.19,37.68 93.19,33.35 93.4,33.13 v2(94.47,33.13)
  BOTTOM w0.102: v2(120.69,75.09) 120.69,75.42 121.07,75.8 121.07,76.06 121.31,76.31 USOC1.B49
  BOTTOM w0.165: v2(94.47,33.13) 95.1,32.5 JDIMM2.80
DDR_A_MA15: length 71.2
  IN2 w0.102: v2(120.23,74.43) 119.52,75.14 117.15,75.14 115.31,73.3
  IN2 w0.216: v2(94.47,31.61) 93.58,31.61 91.88,33.31 91.88,36.27 91.13,37.01 91.13,41.61 91.52,42 91.52,54.73 105.37,68.58 108.31,68.58 110.17,70.44 110.55,70.44 111.44,69.55 111.82,69.55 112.16,69.9 112.16,70.21 111.2,71.17 111.2,71.35 111.63,71.78 111.81,71.78 112.77,70.82 113.08,70.82 115.31,73.05 115.31,73.3
  BOTTOM w0.102: v2(120.23,74.43) 120.49,74.68 121.12,74.68 121.6,75.17 121.6,75.5 121.98,75.88 USOC1.B50
  BOTTOM w0.165: v2(94.47,31.61) 94.5,31.57 JDIMM2.78
DDR_A_ODT0: length 75
  TOP w0.165: v2(109.6,34.99) 110.01,34.99 110.14,35.12 110.14,36.51 110.27,36.63 110.8,36.63 110.93,36.51 110.93,34.44 110.8,34.31 v1(110.29,34.31) 109.48,34.31 RD8.2
  IN2 w0.102: 132.12,77.5 131.78,77.85 130.87,77.85 125.01,83.71 123.87,83.71 v2(123.69,83.53)
  IN2 w0.216: 132.12,77.5 132.14,77.5 135.2,74.44 135.2,62.46 115.61,42.86 114.25,42.86 113.42,42.03 113.42,38.82 112.77,38.16 112.46,38.16 112.34,38.29 112.03,38.29 111.73,37.98 111.73,37.68 111.85,37.55 111.85,37.25 111.55,36.94 111.24,36.94 111.11,37.07 110.81,37.07 110.5,36.76 110.5,36.46 110.63,36.33 110.63,36.03 v2(109.6,34.99)
  BOTTOM w0.165: USOC1.T41 123.82,83.66 v2(123.69,83.53)
DDR_A_ODT2: length 72.8
  TOP w0.165: RD9.2 109.4,33.24 v2(109.6,33.43)
  IN2 w0.102: v2(123,82.86) 123,83.67 123.45,84.11 125.18,84.11 128.55,80.75 128.93,80.75 131.37,78.3 133.1,78.3
  IN2 w0.216: 133.1,78.3 136.45,74.96 136.45,61.8 116.65,42 116.65,39.46 113.17,35.97 112.49,35.97 110.11,33.59 109.76,33.59 v2(109.6,33.43)
  BOTTOM w0.165: v2(123,82.86) 123.03,82.89 USOC1.P42
DDR_A_RAS#: length 69.9
  IN2 w0.102: 130.54,75.58 130.39,75.73 130.39,76.24 125.75,80.89 125.07,80.89 124.81,80.63 v2(123.74,80.63)
  IN2 w0.216: v2(106.22,34.49) 107.36,35.63 107.36,37.48 108.85,38.97 108.85,42.08 115.15,48.39 116.36,48.39 117.91,49.93 118.97,49.93 132.71,63.68 132.71,73.41 130.54,75.58
  BOTTOM w0.165: JDIMM2.110 104.1,30.72 105.71,32.33 105.71,33.98 v2(106.22,34.49) ; v2(123.74,80.63) 123.74,80.98 USOC1.M45
DDR_A_RST#: length 5
  TOP w0.102: v2(77.7,28.32) 77.27,28.74 v1(77.27,29.61) 77.27,29.62 77.5,29.85 CD3.1 RD5.1
  BOTTOM w0.102: JDIMM2.30 v2(77.7,28.32)
DDR_A_RST#_CPU: length 85.7
  TOP w0.102: v2(77.11,32.73) v1(77.87,32.73) 78.15,32.73 79.18,31.71 RD5.2 RD3.2
  IN2 w0.102: v2(122.57,83.27) 122.38,83.08 121.81,83.08 121.46,83.43 121.05,83.43 120.83,83.22 120.54,83.22 120.11,83.65 119.03,83.65 117.96,82.58 112.86,82.58 112.48,82.96 111.49,82.96 110.67,82.15 109.97,82.15
  IN2 w0.127: v2(77.11,32.73) 77.11,54.05 86.01,62.95 86.54,62.95 89.44,65.84 89.44,66.68 91.24,68.49 91.24,69.02 97.49,75.27 98.74,75.27 102.08,78.62 103.79,78.62 107.32,82.15 109.97,82.15
  BOTTOM w0.102: USOC1.P41 122.69,83.39 v2(122.57,83.27)
DDR_A_WE#: length 70.8
  IN2 w0.102: v2(126.97,74.82) 127.16,75.01 127.49,75.01 128.73,73.77
  IN2 w0.216: v2(104.4,36.52) 104.65,36.77 104.65,40.98 104.81,41.14 104.81,42.49 105.45,43.14 105.72,43.14 105.85,43.01 106.25,43.01 106.49,43.25 106.49,43.56 105.91,44.13 105.91,44.31 106.34,44.75 106.52,44.75 107.1,44.17 107.4,44.17 107.71,44.47 107.71,44.78 107.14,45.35 107.14,45.53 107.57,45.96 107.75,45.96 108.32,45.39 108.62,45.39 108.93,45.69 108.93,46 108.36,46.57 108.36,46.74 108.79,47.18 108.97,47.18 109.54,46.61 109.85,46.61 110.15,46.92 110.15,47.22 109.58,47.79 109.58,47.97 110.01,48.4 110.19,48.4 110.76,47.83 111.07,47.83 111.37,48.14 111.37,48.44 110.81,49 110.81,49.18 111.24,49.61 111.42,49.61 111.98,49.05 112.29,49.05 112.59,49.36 112.59,49.66 112.02,50.24 112.02,50.42 112.45,50.85 112.63,50.85 113.21,50.27 113.51,50.27 113.82,50.58 113.82,50.89 113.34,51.36 113.34,51.65 113.57,51.88 114.05,51.88 114.66,51.27 115.11,51.27 130.22,66.38 130.22,72.28 128.73,73.77
  BOTTOM w0.102: 124.55,77.71 124.66,77.71 125.37,77 125.37,76.7 125.8,76.26 125.8,75.99 v2(126.97,74.82)
  BOTTOM w0.165: JDIMM2.113 105,37.12 v2(104.4,36.52)
DDR_CORE_PWROK: length 140
  TOP w0.102: v2(126.08,86.63) 125.63,87.08 124.91,87.08 CC19.1 CC1.1 ; v2(84.45,72.79) 84.14,72.79 RC30.2 84.85,73.44 UC7.4
  IN1 w0.102: v2(126.08,86.63) 128.38,86.63 128.71,86.95 128.72,86.95 129.16,86.95 129.29,86.82 136.46,86.82 136.9,86.38 138.29,86.38
  IN1 w0.127: 138.29,86.38 140.52,86.38 142.36,84.54 143.88,84.54 145.47,82.95 145.47,77.94 v2(145.09,77.55) ; v2(77.03,62.49) 77.03,63.85 78.19,65.01 80.68,65.01 82.8,67.12 82.8,69.12 83.5,69.82 83.5,71.84 v2(84.45,72.79)
  IN2 w0.127: v2(145.09,77.55) 145.73,77.55 147.25,76.03 147.25,69.5 146.39,68.64 146.39,59.55 v2(146.3,59.46)
  BOTTOM w0.102: USOC1.AB42 126.2,85.82 126.2,86.5 v2(126.08,86.63) ; v2(146.3,59.46) 140.48,59.46 138.51,57.49 84.52,57.49 79.5,62.5 77.04,62.5 v2(77.03,62.49)
DDR_PWROK: length 155.7
  TOP w0.102: v2(55.17,55.27) 55.61,55.7 66.13,55.7 v1(66.57,55.27) 68.95,55.27 71.62,57.93 79.08,57.93 v2(79.72,58.58)
  TOP w0.203: v2(55.47,47.8) 55.47,48.64 55.78,48.95 PU200.10
  TOP w0.254: v2(55.47,47.8) 55.05,47.38 PR210.2
  IN1 w0.127: v2(55.47,47.8) 55.17,48.09 v2(55.17,55.27)
  IN2 w0.127: v2(126.61,86.09) 126.77,86.25 127.44,86.25 128.01,85.68 128.41,85.68 128.69,85.41 130.21,85.41 131.7,86.9 137.78,86.9 137.98,86.7 143.52,86.7 147.5,82.71 147.5,70.03 148.04,69.5 148.04,67.62 146.64,66.22 146.64,59.75 146.81,59.58 146.81,59.2 147.25,58.76 v2(147.5,58.76)
  BOTTOM w0.102: v2(147.5,58.76) 140.71,58.76 138.87,56.92 81.39,56.92 v2(79.72,58.58) ; USOC1.AD42 126.84,86.33 v2(126.61,86.09)
DDR_RCOMP0: length 3.7
  TOP w0.254: RC3.2 129.84,85.25 127.48,85.25 v2(127.07,85.66)
  BOTTOM w0.254: USOC1.AD44 127.41,85.66 v2(127.07,85.66)
DDR_RCOMP1: length 2
  TOP w0.254: RC4.2 130.28,86.08 v2(129.34,86.08)
  BOTTOM w0.254: v2(129.34,86.08) 129.25,85.99 USOC1.AF45
DDR_RCOMP2: length 2.1
  TOP w0.254: RC5.2 128.93,84.89 128.15,84.89 v2(128.03,84.77)
  BOTTOM w0.254: v2(128.03,84.77) 128.03,85.28 USOC1.AD45
DDR_TERMN0: length 3.9
  TOP w0.254: v2(128.26,87.09) 128.38,87.21 v1(129.39,87.21) 129.53,87.21 129.9,86.84 130.79,86.84 RC1.2
  BOTTOM w0.254: USOC1.AF42 127.83,87.09 v2(128.26,87.09)
DDR_TERMN1: length 3.8
  TOP w0.254: RC2.2 131.49,87.42 v1(130.8,87.42) 130.17,87.42 129.73,87.86 v2(129.12,87.86)
  BOTTOM w0.254: USOC1.AH42 128.76,87.69 128.84,87.76 129.01,87.76 v2(129.12,87.86)
DEVSLP0: length 152.6
  TOP w0.102: UC10.4 115.47,113.02 115.28,113.21 RC53.2 115.86,113.92 v2(115.99,113.8) ; v2(170.08,24.54) 169.47,25.15 169.47,31.33 170.53,32.38 170.53,36.46 171.34,37.27 v2(171.34,37.46)
  IN2 w0.127: v2(171.34,37.46) 171.35,37.46 171.63,37.74 171.63,45.72 169.89,47.46 167.14,47.46 166.41,48.18 160.33,48.18 159.99,48.52 159.99,50.34 160.58,50.93 162.07,50.93 162.39,51.26 162.39,55.77 164.98,58.35 164.98,67.38 164.39,67.97 164.39,74.95 164.74,75.29 165.36,75.29 165.83,75.76 165.83,76.77 165.83,81.77 166.29,82.23 166.29,86.3 166.56,86.57 166.56,100.16 164.14,102.57 164.14,104.67 159.48,109.33 151.55,109.33 149.96,110.92 149.5,110.92 146.18,114.23 146.13,114.23 146.12,114.24 140.54,114.24 140.3,114 137.08,114 136.58,113.5 131.79,113.5 131.33,113.96 123.24,113.96 122.99,114.22 122.89,114.22 122.77,114.34 121.08,114.34 117.07,114.34 116.52,113.8 v2(115.99,113.8)
  BOTTOM w0.102: RS8.1 v2(170.08,24.54)
DEVSLP0_R: length 15.3
  TOP w0.102: v2(170.08,22.33) 170.08,23.9 169.17,24.81 169.17,31.64 v2(170.05,32.52)
  BOTTOM w0.102: JHDD.5 168.22,31.46 169.28,32.52 v2(170.05,32.52) ; v1(170.08,21.5) v2(170.08,22.33) RS8.2
DEVSLP_SOC: length 14.5
  TOP w0.102: v2(122.52,102.22) 119.54,102.22 v1(116.62,105.14) 116.17,105.59 116.17,109.8 115.87,110.09 115.07,110.09 114.82,110.34 UC10.2
  BOTTOM w0.102: v2(122.52,102.22) 122.52,102.06 122.73,101.85 USOC1.AY14
DH_1.35VP: length 6.1
  IN1 w1.016: 63.11,42.76 63.11,47.06 61.86,48.32
  vias: v2(60.52,49.21) v2(60.9,48.7) v2(62.79,41.68) v2(63.42,41.71)
DH_CHG: length 17
  IN2 w0.762: 159.95,159.34 151.44,159.34 150.68,160.1 144.84,160.1 143.69,158.96
  vias: v1(159.57,160.93) v2(143.29,157.7) v2(143.29,157.12) v2(159.95,160.49) v2(160.58,160.49)
DISPOFF#: length 9.8
  BOTTOM w0.102: DX1.1 105,157.14 RX25.2 RX9.1 105.53,159.39 105.53,160.22 104.87,160.88 v1(103.97,160.88) 103.63,160.88 101.8,162.71 JEDP.21
DL_1.35VP: length 9.5
  IN2 w1.016: 59.18,45.93 59.18,37.74 58.22,36.79
  vias: v2(57.79,35.76) v2(58.48,35.77) v2(59.19,47.37) v2(59.19,46.73)
DL_CHG: length 4.8
  IN2 w0.762: 152.96,155.15 148.14,155.15
  vias: v1(154.27,154.34) v2(146.6,155.04) v2(147.24,155.04) v2(153.46,154.52) v2(153.47,153.88)
DRAM_VDD_S4_CLK: length 5.7
  TOP w0.102: v2(126.15,87.92) v1(126.15,87.23)
  TOP w0.508: RC54.2 128.59,89.16 CC28.1 CC27.1 127.45,88.02 126.76,88.02 126.66,87.92 v2(126.15,87.92)
  BOTTOM w0.254: USOC1.AF38 126.05,88.03 126.06,88.02 ; 126.06,88.02 v2(126.15,87.92) ; 126.06,88.02 USOC1.AD38
E51_RX2: length 4
  TOP w0.102: T15.1 169.74,49.32 v2(168.88,49.32)
  BOTTOM w0.102: v2(168.88,49.32) 169.17,49.32 169.89,48.6 JNGFF.50
EC_LID_OUT#: length 165.9
  TOP w0.102: R26.2 87.43,63.79 87.43,62.06 86.77,61.4 v1(86.44,61.4) v2(85.91,61.4)
  IN1 w0.127: v2(151.83,133.76) 151.83,133.51 151.87,133.47 151.87,131.98 149.71,129.82 149.71,125.73 153.43,122 154.93,122 155.92,121.01 158.33,121.01 160.46,118.89 160.46,114.54 163.59,111.4 163.59,101.64 165.37,99.86 165.37,94.15 165.37,94.15 165.37,91.2 165.37,87.97 164.23,86.83 164.23,83.04 163.07,81.88 163.07,68.92 162.62,68.46 162.62,66.24 161.92,65.54 150.95,65.54 v2(148.58,63.18)
  BOTTOM w0.102: UE1.101 151.63,133.97 v2(151.83,133.76) ; v2(148.58,63.18) 148.51,63.1 138.72,63.1 135.32,59.7 135.07,59.7 102.7,59.7 101.2,61.2 88.76,61.2 88.32,61.63 86.07,61.63 85.91,61.46 v2(85.91,61.4)
EC_MUTE#: length 148.8
  TOP w0.102: v1(149.35,46.88) 149.19,46.88 148.61,47.47 v2(148.6,47.47)
  IN1 w0.127: v2(157.03,127.66) 157.47,127.21 159.3,127.21 161.55,124.96 163.04,124.96 163.63,124.38 163.78,124.38 168.17,119.99 168.17,103.24 168.74,102.66 169.78,102.66 170.2,102.24 170.2,100.61 171.11,99.7 171.11,97.81 170.62,97.31 170.62,93.94 170.11,93.43 170.11,93.26 169.6,92.75 169.6,79.14 170.05,78.7 170.05,72.05 169.94,71.95 169.94,69.53 170.55,68.92 170.55,64.16 168.71,62.31 168.71,62.08 161.98,55.35 161.98,54.63 157.53,50.18 154.74,50.18 154.32,49.77 151.86,49.77 149.56,47.47 v2(148.6,47.47)
  IN2 w0.127: v2(149.31,13.7) 149.21,13.8 149.21,19.21 146.12,22.3 146.12,22.76 146.12,29.97 151.72,35.57 151.72,44.63 148.89,47.47 v2(148.6,47.47)
  BOTTOM w0.102: UA1.47 149.85,14.11 149.45,13.7 v2(149.31,13.7) ; v2(157.03,127.66) 156.64,128.05 RA54.1 155.96,128.38 156.66,128.38 157.02,128.74 157.02,129.69 156.96,129.74 UE1.83
EC_ON: length 228.4
  TOP w0.102: PR115.1 42.09,54.39 v1(40.69,55.79) 38.65,57.83 v2(38.65,59.71)
  IN1 w0.127: v2(148.2,139.78) 149.75,138.23 149.75,131.36 148.65,130.26 148.65,125.32 153.97,120 157.85,120 159.44,118.4 159.44,114.07 162.58,110.93 162.58,103.36 160.29,101.07 158.75,101.07 157.21,99.53 157.21,99.19 157.84,98.55 157.84,91.41 163.21,86.04 163.21,83.47 161.94,82.2 161.94,69.24 161.6,68.9 161.6,66.91 v2(161.44,66.75)
  BOTTOM w0.102: v2(38.65,59.71) 39.06,59.3 39.45,59.3 40.77,60.62 45.73,60.62 47.37,62.26 52.98,62.26 67.18,62.26 67.31,62.4 69.06,64.14 79.44,64.14 79.81,64.51 82.2,64.51 84.23,62.48 101.21,62.48 102.88,60.82 135.14,60.82 138.79,64.46 139.16,64.46 139.17,64.46 148.18,64.46 150.92,64.46 153.21,66.75 v2(161.44,66.75) ; UE1.112 149.23,138.37 148.3,139.3 148.3,139.68 v2(148.2,139.78)
EC_RSMRST#: length 340
  TOP w0.127: CC54.1 33.2,78.27 v2(33.31,78.16) 33.61,77.86 35.49,77.86 35.77,77.58 JDB1.10
  IN1 w0.127: v2(167.38,151.56) 167.28,151.66 151.25,151.66 148.65,149.06 148.65,146.13 151.11,143.67 151.11,133.43 151.25,133.3 v2(151.45,133.3) ; v2(94.86,122.77) 94.43,122.33 94.43,118.4 93.34,117.31 91.03,117.31 90.5,116.78 90.5,96.46 90.5,96.04 77.6,83.14 77.6,82.76 77.6,82.76 77.6,82.68 73.43,78.5 63.87,78.5 62.97,77.6 58.08,77.6 56.4,75.93 47.03,75.93 45.46,77.5 45.46,77.51 44.65,78.32 43.61,78.32 42.7,77.4 34.56,77.4 33.8,78.16 v2(33.31,78.16)
  IN2 w0.127: v2(98.74,113.05) 98.2,113.05 94.43,116.82 94.43,122.33 v2(94.86,122.77) 94.86,123.76 91.99,126.63 91.99,134.7 94.51,137.22 94.51,164.08 97.52,167.09 97.52,171.47 100.65,174.6 103.64,174.6 105.15,176.11 118.29,176.11 119.44,174.96 137.98,174.96 139.06,173.88 159.48,173.88 159.54,173.82 159.57,173.82 160.88,172.51 161.09,172.51 v2(161.11,172.5)
  BOTTOM w0.102: 103.27,88.85 104.46,88.85 104.58,88.73 107.02,88.73 USOC1.B10
  BOTTOM w0.127: 103.27,88.85 101.64,88.85 100.53,87.74 100.53,87.35 98.92,85.75 CC14.1 RC26.1 97.41,87.5 96.98,87.93 96.11,88.79 96.11,88.84 96.11,88.85 96.11,89.94 97.31,91.14 97.31,93.58 98.2,94.47 98.2,98.09 97.56,98.74 97.42,98.87 96.95,99.35 96.95,105.52 97.82,106.39 97.82,112.2 98.67,113.05 v2(98.74,113.05) ; v2(151.45,133.3) 151.43,133.3 151.15,133.57 UE1.100 ; v2(161.11,172.5) 161.63,171.98 164.08,171.98 167.33,168.73 167.33,166.43 168.08,165.68 168.19,165.68 168.84,165.03 168.84,153.22 168.62,153 168.13,153 167.38,152.25 v2(167.38,151.56)
EC_RX: length 101.7
  TOP w0.102: v2(168.7,53.41) 168.42,53.69 v1(168.26,53.69)
  IN2 w0.127: v2(168.7,53.41) 168.7,53.78 169.54,54.62 169.75,54.62 170.29,55.15 170.29,60.57 170.95,61.23 170.95,68.15 169.88,69.21 169.88,70.63 171.08,71.83 171.08,89.81 171.95,90.69 171.95,102.72 171.94,102.73 171.94,113.95 170.03,115.86 170.03,124.75 165.66,129.12 165.66,140.36 164.52,141.5 164.48,141.5 v2(164.46,141.52)
  BOTTOM w0.102: UE1.31 163.76,142.38 164.46,141.69 v2(164.46,141.52) ; v2(168.7,53.41) 169.01,53.1 JNGFF.32
EC_SCI#: length 190.2
  TOP w0.102: v2(110.04,114.38) v1(110.67,115.02) 115.88,115.02 116.26,115.4 116.26,116.92 116.52,117.18 120.71,117.18 121.55,116.34 R29.2
  IN1 w0.127: v2(96.98,122.35) 97.21,122.58 98.98,122.58 100.32,123.92 100.32,143.27 102.35,145.29 102.35,147.41 103.45,148.51 103.45,153.53 104.79,154.87 104.79,156.4 103.18,158.01 103.18,162.77 104.6,164.19 104.6,165.05 104.35,165.3 104.35,167.19 106.74,169.57 106.74,171.65 107.95,172.87 151.19,172.87 151.45,172.6 159.39,172.6 160.65,171.34 164.72,171.34 168.94,167.12 168.94,166.19 169.79,165.34 169.79,151.55 168.37,150.12 163.82,150.12 163.7,150.01 163.7,150.01 162.52,148.83 162.24,148.83 161.98,148.57 161.98,147.63 161.12,146.77 159.65,146.77 158.93,146.06 158.93,143.98 v2(158.43,143.47)
  IN2 w0.127: v2(100.37,114.59) 100.23,114.59 96.98,117.84 v2(96.98,122.35)
  BOTTOM w0.102: v2(110.04,114.38) 105.35,114.38 104.84,114.89 103.76,114.89 103.51,115.15 100.93,115.15 v2(100.37,114.59) ; UE1.20 159.36,145.22 159.38,145.21 159.38,144.48 158.69,143.79 158.69,143.73 v2(158.43,143.47)
EC_SMB_CK1: length 96.1
  TOP w0.102: v2(158.93,171.81) PD1.3 158.43,173.11 158.43,173.21 158.53,173.31 159.06,173.31 159.3,173.55 159.3,174.29 158.68,174.91 158.68,175.14 PR8.2 ; v2(160.14,134.7) 160.08,134.7 159.42,135.36 159.42,135.64 RP36.4 ; v2(165.16,148.34) 165.01,148.34 163.82,147.15 157.85,147.15 v1(157.69,147.32) 157.52,147.15 155.25,147.15 153.98,148.42 149.28,148.42 148.13,147.26 142.71,147.26 142.02,147.96 142.02,148.33 PR717.1
  IN2 w0.127: v2(160.14,134.7) 159.12,135.72 158.71,135.72 157.88,136.55 157.88,147.4 160.43,149.94 162.62,149.94 163.25,149.31 163.25,148.29 163.35,148.2 163.35,148.2 164.27,147.28 165.41,147.28 165.66,147.53 165.66,147.83 v2(165.16,148.34) 165.75,148.93 167.85,148.93 169.41,150.49 169.41,166.38 167.94,167.85 162.09,167.85 160.14,169.8 160.14,170.48 158.93,171.69 v2(158.93,171.81)
  BOTTOM w0.102: v2(160.14,134.7) 160.14,133.22 159.28,132.35 159.28,131.87 159.36,131.78 UE1.77
EC_SMB_CK2: length 302.9
  TOP w0.102: RE15.1 158.43,134.69 v2(158.35,134.77) 158.43,134.85 RP36.2 ; QC3.1 129.04,112.65 128.64,113.05 127.5,113.05 126.25,114.3 124.81,114.3 124.42,114.69 124.42,115.03 v2(124.24,115.2)
  IN2 w0.127: v2(65.03,77.88) 65.53,78.38 72.51,78.38 74.23,80.1 74.8,80.1 74.8,80.1 76.07,80.1 76.7,80.1 76.7,80.1 77.07,80.1 93.02,96.05 93.02,99.4 v2(95.93,102.31) ; v2(158.35,134.77) 158.18,134.6 158.18,133.83 157.72,133.37 153.64,133.37 150.81,130.54 150.81,126.95 146.68,122.83 146.68,121.79 147.29,121.18 147.29,120.99 v2(147.41,120.86) 147.41,120.68 147.22,120.49 147.22,117.1 148.01,116.31 148.01,114.74 150.31,112.44 150.6,112.44 152.16,110.88 159.46,110.88 160.09,110.88 165.67,105.3 165.67,103.24 168.09,100.83 168.09,85.94 168.07,85.92 168.07,79.13 167.36,78.42 167.36,75.13 166.85,74.62 166.85,69.17 166.71,69.03 166.71,57.69 164,54.99 164,51.35 167.38,47.98 170.13,47.98 172.14,45.97 172.14,37.23 170.59,35.68 168.17,35.68 167.75,35.26 167.75,34.82 v2(167.89,34.68)
  BOTTOM w0.102: RE33.1 60.65,75.47 63.06,77.88 v2(65.03,77.88) ; v2(95.93,102.31) 95.6,102.64 95.6,105.99 97.31,107.7 97.31,110.54 97.31,113.66 99.28,115.63 103.71,115.63 103.96,115.37 105.04,115.37 105.51,114.9 115.14,114.9 115.79,115.55 122.07,115.55 122.53,116.01 124.06,116.01 124.42,115.66 124.42,115.38 v2(124.24,115.2) 124.39,115.05 124.39,114.75 124.82,114.32 138.75,114.32 138.77,114.32 138.95,114.32 139.92,115.29 139.92,115.3 139.92,117.84 141.24,119.16 142.78,119.16 144.01,120.39 147,120.39 147.24,120.63 147.24,120.69 v2(147.41,120.86) ; v2(167.89,34.68) 167.71,34.85 167.71,35.07 167.47,35.31 164.91,35.31 164.71,35.12 164.71,34.18 164.14,33.61 159.31,33.61 158.89,33.19 154.19,33.19 153.89,32.89 147.84,32.89 146.66,34.07 137,34.07 136.35,33.43 136.35,28.89 135.36,27.9 132.14,27.9 131.7,28.33 JDIMM2.202
EC_SMB_CK2_EC: length 4.2
  TOP w0.102: RE22.2 158.04,131.48 158.04,132.09 v2(158.18,132.23) 158.04,132.37 158.04,132.85 RE15.2
  BOTTOM w0.102: UE1.79 158.56,131.85 v2(158.18,132.23)
EC_SMB_DA1: length 96.7
  TOP w0.102: PR9.2 158.43,174.96 158.43,174.84 159.07,174.19 159.07,173.64 158.97,173.54 158.43,173.54 158.2,173.31 158.2,172.88 PD1.2 158.3,172.24 v2(158.3,171.8) ; RP36.3 158.93,135.28 159.5,134.71 v2(159.5,134.7) ; v2(165.08,147.76) 164.24,146.92 155.1,146.92 153.83,148.19 149.38,148.19 148.22,147.04 142.61,147.04 141.79,147.86 141.79,148.33 PR719.1
  IN2 w0.127: v2(158.3,171.8) 158.3,171.69 159.82,170.16 159.82,169.76 161.98,167.6 167.83,167.6 169.16,166.27 169.16,150.59 167.75,149.18 165.16,149.18 164.65,148.67 164.65,148.17 165.03,147.79 165.08,147.79 ; v2(159.5,134.7) 159.5,134.7 159.5,134.96 159.19,135.28 158.46,135.28 157.56,136.18 157.56,147.68 160.08,150.2 162.72,150.2 163.51,149.41 163.51,148.4 164.38,147.53 164.83,147.53 165.08,147.79 ; 165.08,147.79 v2(165.08,147.76)
  BOTTOM w0.102: v2(159.5,134.7) 159.91,134.29 159.91,133.33 159.05,132.47 159.05,131.87 158.96,131.78 UE1.78
EC_SMB_DA2: length 308.2
  TOP w0.102: v2(124.82,115.2) 124.64,115.03 124.64,114.88 125,114.53 126.34,114.53 127.56,113.3 128.95,113.3 130.18,112.08 QC4.1 ; RE16.1 157.76,134.5 v2(157.76,134.77) 157.93,134.94 RP36.1
  IN2 w0.127: v2(157.76,134.77) 157.93,134.6 157.93,133.94 157.61,133.62 153.49,133.62 150.55,130.68 150.55,127.06 146.42,122.93 146.42,121.67 146.98,121.12 146.98,120.95 v2(146.83,120.8) 146.96,120.67 146.96,117.01 147.76,116.21 147.76,114.63 150.2,112.19 150.49,112.19 152.05,110.63 159.56,110.63 159.98,110.63 165.42,105.2 165.42,103.14 167.83,100.72 167.83,86.04 167.81,86.02 167.81,79.24 167.1,78.53 167.1,75.23 166.59,74.73 166.59,74.61 166.59,69.28 166.45,69.13 166.45,57.8 163.75,55.09 163.75,51.46 163.75,51.25 167.27,47.73 170.03,47.73 171.89,45.87 171.89,37.34 170.49,35.94 168.07,35.94 167.49,35.36 167.49,34.87 v2(167.3,34.68) ; v2(65.67,77.88) 65.91,78.13 72.61,78.13 74.33,79.85 74.9,79.85 74.91,79.85 75.96,79.85 76.59,79.85 76.97,79.85 76.97,79.85 77.18,79.85 93.28,95.95 93.28,98.87 v2(95.95,101.54)
  BOTTOM w0.102: v2(65.67,77.88) 64.8,77.02 64.8,74.49 62.58,72.27 RE32.1 ; v2(146.83,120.8) 146.72,120.68 143.91,120.68 142.64,119.41 142.32,119.41 141.17,119.41 139.69,117.93 139.69,115.39 138.99,114.69 138.85,114.55 138.66,114.55 138.66,114.55 124.96,114.55 124.64,114.87 124.64,115.03 v2(124.82,115.2) 124.64,115.38 124.64,115.75 124.15,116.24 122.31,116.24 121.85,115.78 115.7,115.78 115.05,115.13 105.61,115.13 105.14,115.6 104.06,115.6 103.8,115.86 99.19,115.86 97.08,113.75 97.08,107.8 95.37,106.08 95.37,102.13 v2(95.95,101.54) ; JDIMM2.200 131.1,28.17 131.63,27.64 135.44,27.64 136.58,28.79 136.58,33.33 137.09,33.84 146.56,33.84 147.75,32.66 153.8,32.66 153.99,32.66 154.29,32.96 158.79,32.96 158.79,32.96 158.98,32.96 159.41,33.38 164.24,33.38 164.94,34.09 164.94,35.02 165,35.09 167.37,35.09 167.48,34.98 167.48,34.85 v2(167.3,34.68)
EC_SMB_DA2_EC: length 4.4
  TOP w0.102: RE23.2 157.82,131.5 157.82,132.01 v2(157.6,132.23) 157.82,132.44 157.82,132.82 RE16.2
  BOTTOM w0.102: v2(157.6,132.23) 158.16,131.66 UE1.80
EC_SMI#: length 235.1
  TOP w0.102: v2(81.54,79.46) 80.32,79.46 76.04,75.18 76.04,71.37 73.72,69.05 v1(73.72,61.55) v2(72.83,60.66) ; R31.2 85.4,77.42 v2(85.9,76.92)
  IN1 w0.127: v2(157.09,144.93) 157.09,142.39 157.52,141.96 157.52,135.26 157.17,134.91 157.17,131.22 156.1,130.16 156.1,126.69 156.41,126.39 158.02,126.39 158.03,126.39 158.11,126.39 160.63,123.87 163.57,123.87 167.15,120.28 167.15,103.12 169.09,101.17 169.09,100.75 170.35,99.49 170.35,98.12 169.86,97.63 169.86,93.89 169.6,93.64 169.6,93.53 168.93,92.86 168.93,85.9 168.69,85.66 168.69,79.16 168.69,78.29 168.69,77.87 168.37,77.55 168.37,76.39 168.37,72.16 168.08,71.86 168.08,67.57 167.19,66.68 167.19,61.64 163.69,58.14 161.23,58.14 156.74,53.64 156.74,52.69 155.2,51.15 154.25,51.15 153.56,50.46 149.95,50.46 148.56,49.07 146.43,49.07 144.37,47.01 143.08,47.01 142.64,47.46 142.17,47.46 v2(141.6,48.03)
  BOTTOM w0.102: v2(157.09,144.93) 157.36,145.2 UE1.15 157.36,148.93 R488.2 ; v2(85.9,76.92) 84.63,78.19 82.99,78.19 81.72,79.46 v2(81.54,79.46) ; v2(141.6,48.03) 141.22,48.03 136.83,52.42 98.86,52.42 97.86,53.42 78.99,53.42 76.18,56.23 76.18,57.34 72.86,60.66 v2(72.83,60.66)
EC_TP_INT#: length 245.7
  TOP w0.102: v2(46.16,72.8) 45.84,72.48 v1(45.84,60.24) 45.84,59.71 v2(45.65,59.52) ; RE29.1 59.19,74.56 57.69,73.06 55.85,73.06 55.59,72.8 52.9,72.8 v2(52.36,72.26)
  IN1 w0.127: v2(154.97,131.98) 154.36,131.37 154.36,127.99 154.11,127.74 154.11,126.49 156.06,124.54 158.39,124.54 164.2,118.73 164.2,118.52 164.2,115.34 166.13,113.41 166.13,102.69 167.91,100.91 167.91,93.1 167.91,86.32 167.67,86.08 167.67,78.74 167.35,78.42 167.35,75.97 167.35,72.58 167.06,72.29 167.06,67.99 165.51,66.44 165.51,63.03 161.72,59.24 160.88,59.24 153.92,52.28 150.97,52.28 150.26,51.57 149.42,51.57 147.96,50.11 146.03,50.11 143.97,48.05 143.48,48.05 142.93,48.6 v2(142.42,48.6)
  IN2 w0.127: v2(154.97,131.98) 155.79,131.15 159.52,131.15 160.37,132 v2(160.37,132.04)
  BOTTOM w0.102: v2(52.36,72.26) 51.81,72.8 v2(46.16,72.8) ; v2(142.42,48.6) 136.59,54.43 80.24,54.43 80.24,54.43 79.68,54.43 79.38,54.43 77.17,56.64 77.17,57.75 76.81,58.11 76.81,58.49 76.05,59.25 74.81,59.25 73,61.07 72.66,61.07 71.69,60.1 71.51,60.1 71.5,60.1 48.01,60.1 47.43,59.52 v2(45.65,59.52) ; UE1.74 160.56,131.84 v2(160.37,132.04)
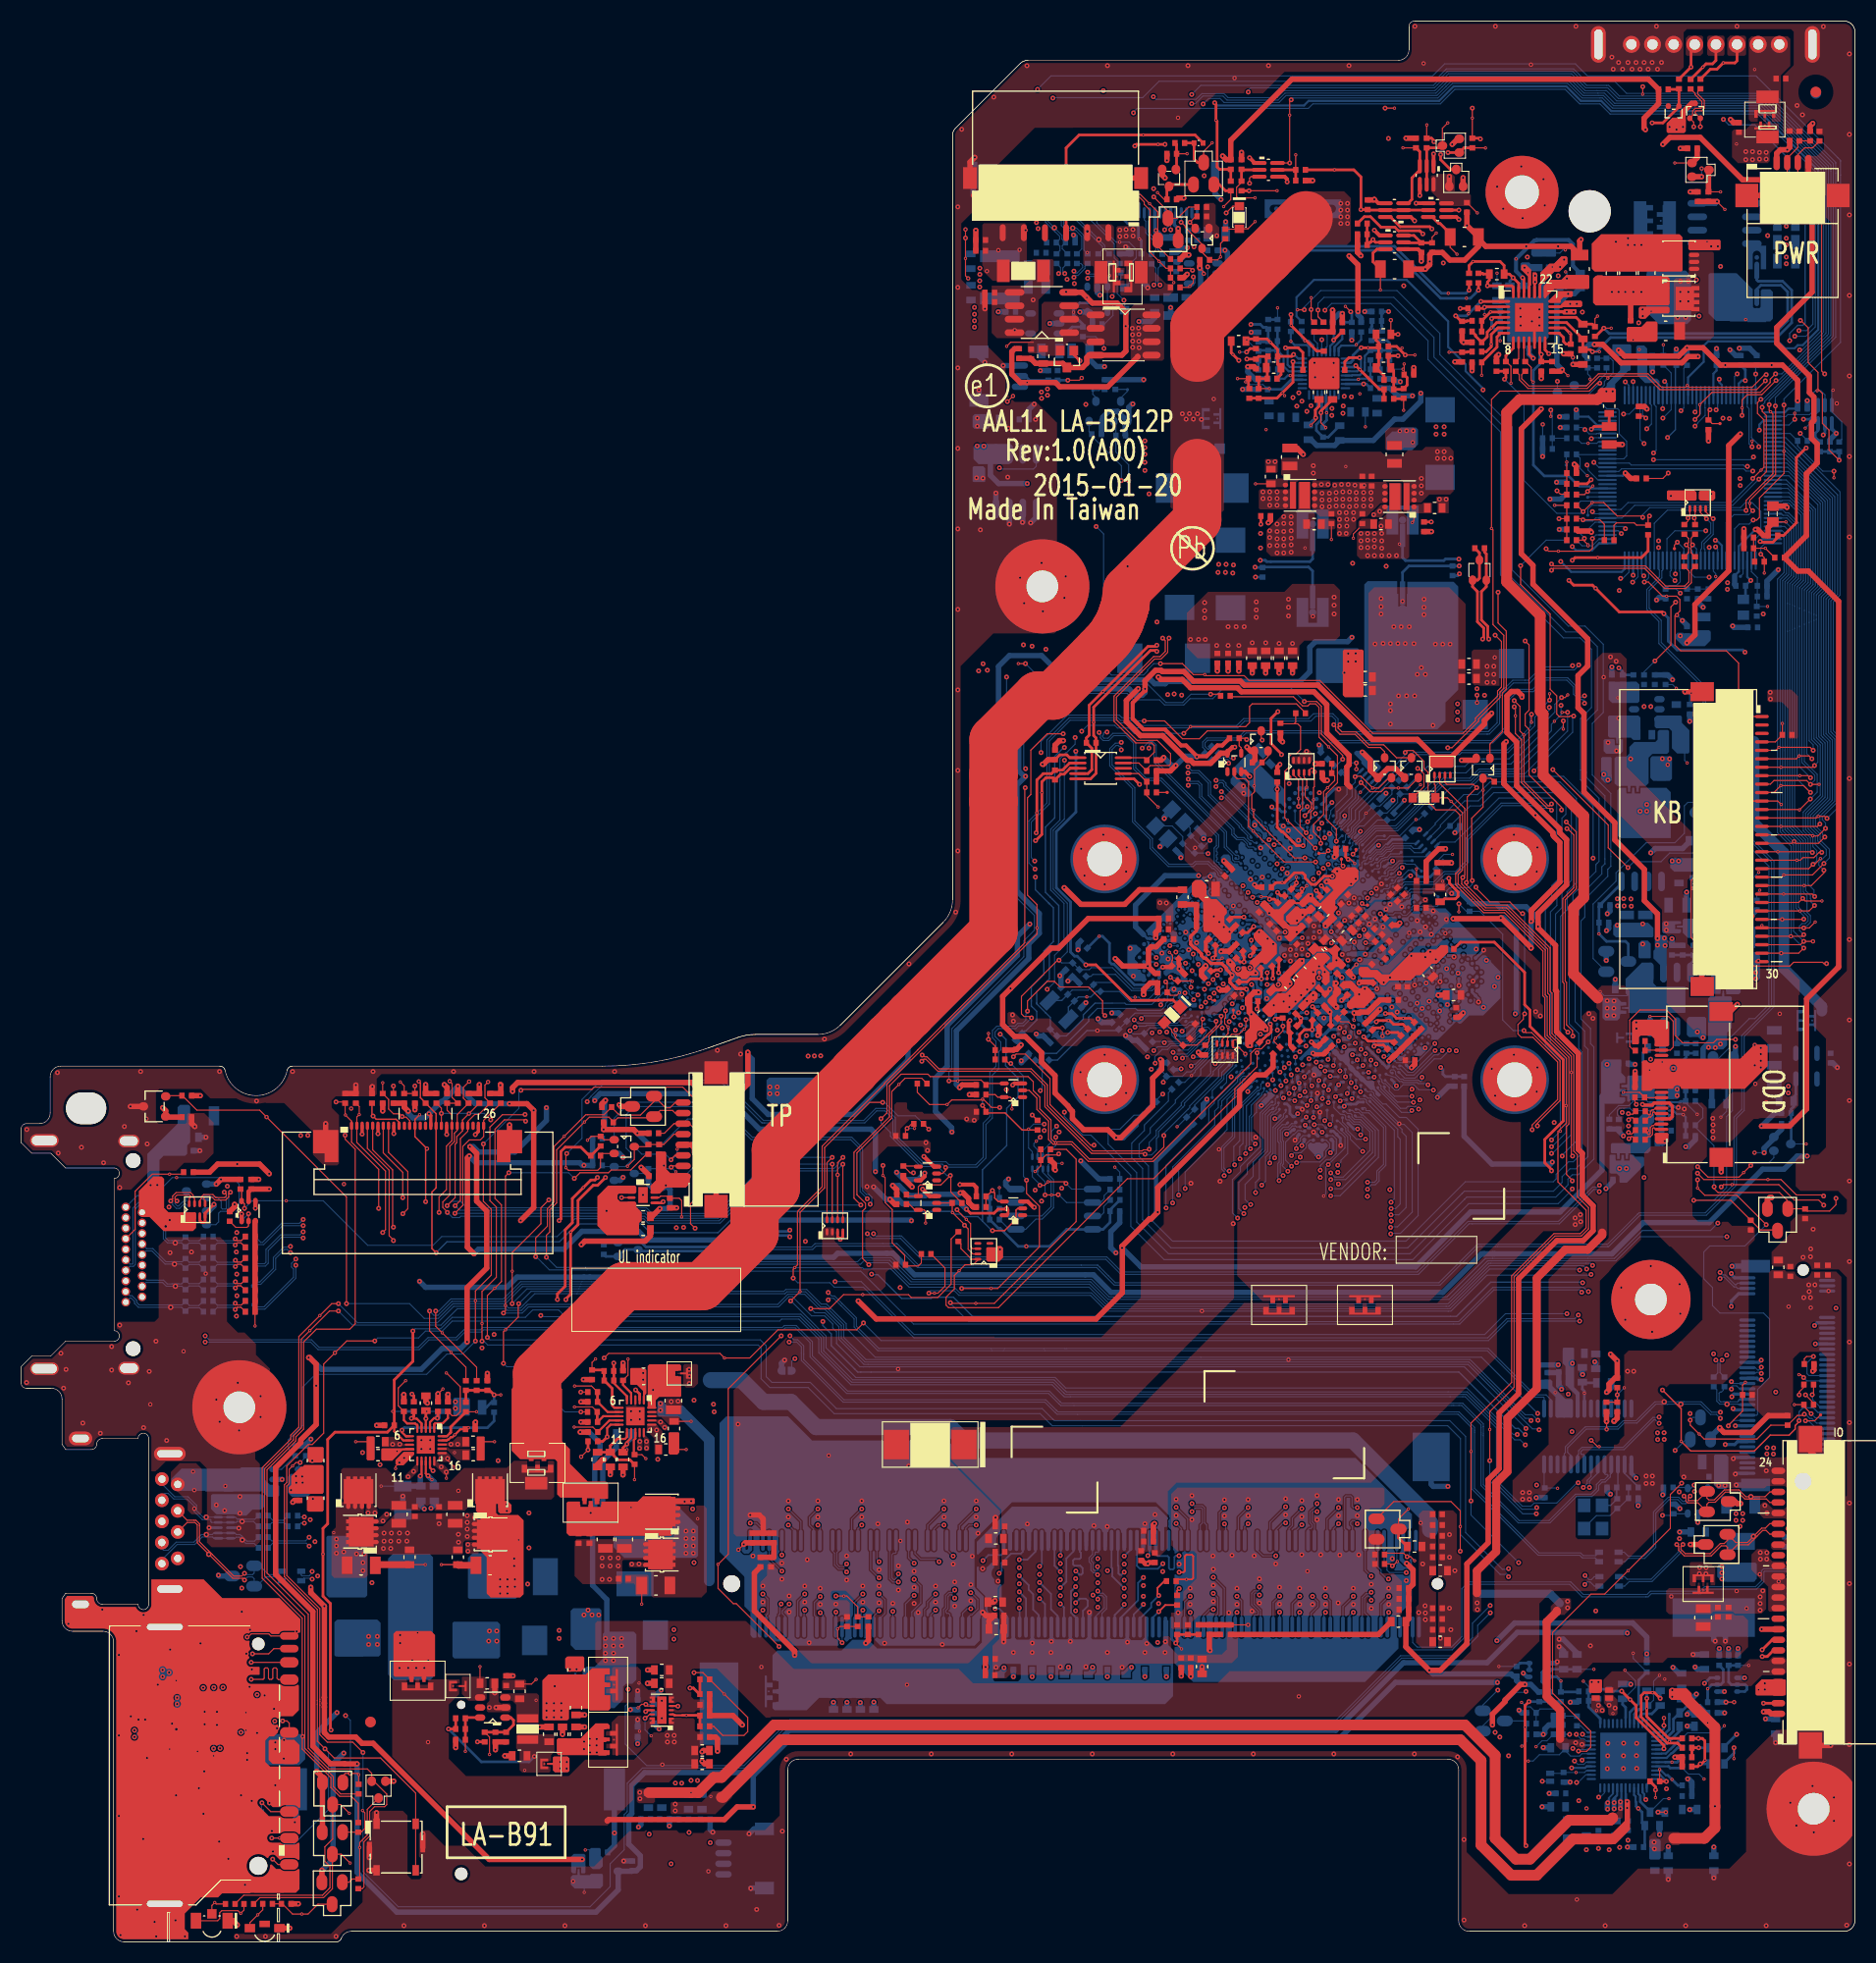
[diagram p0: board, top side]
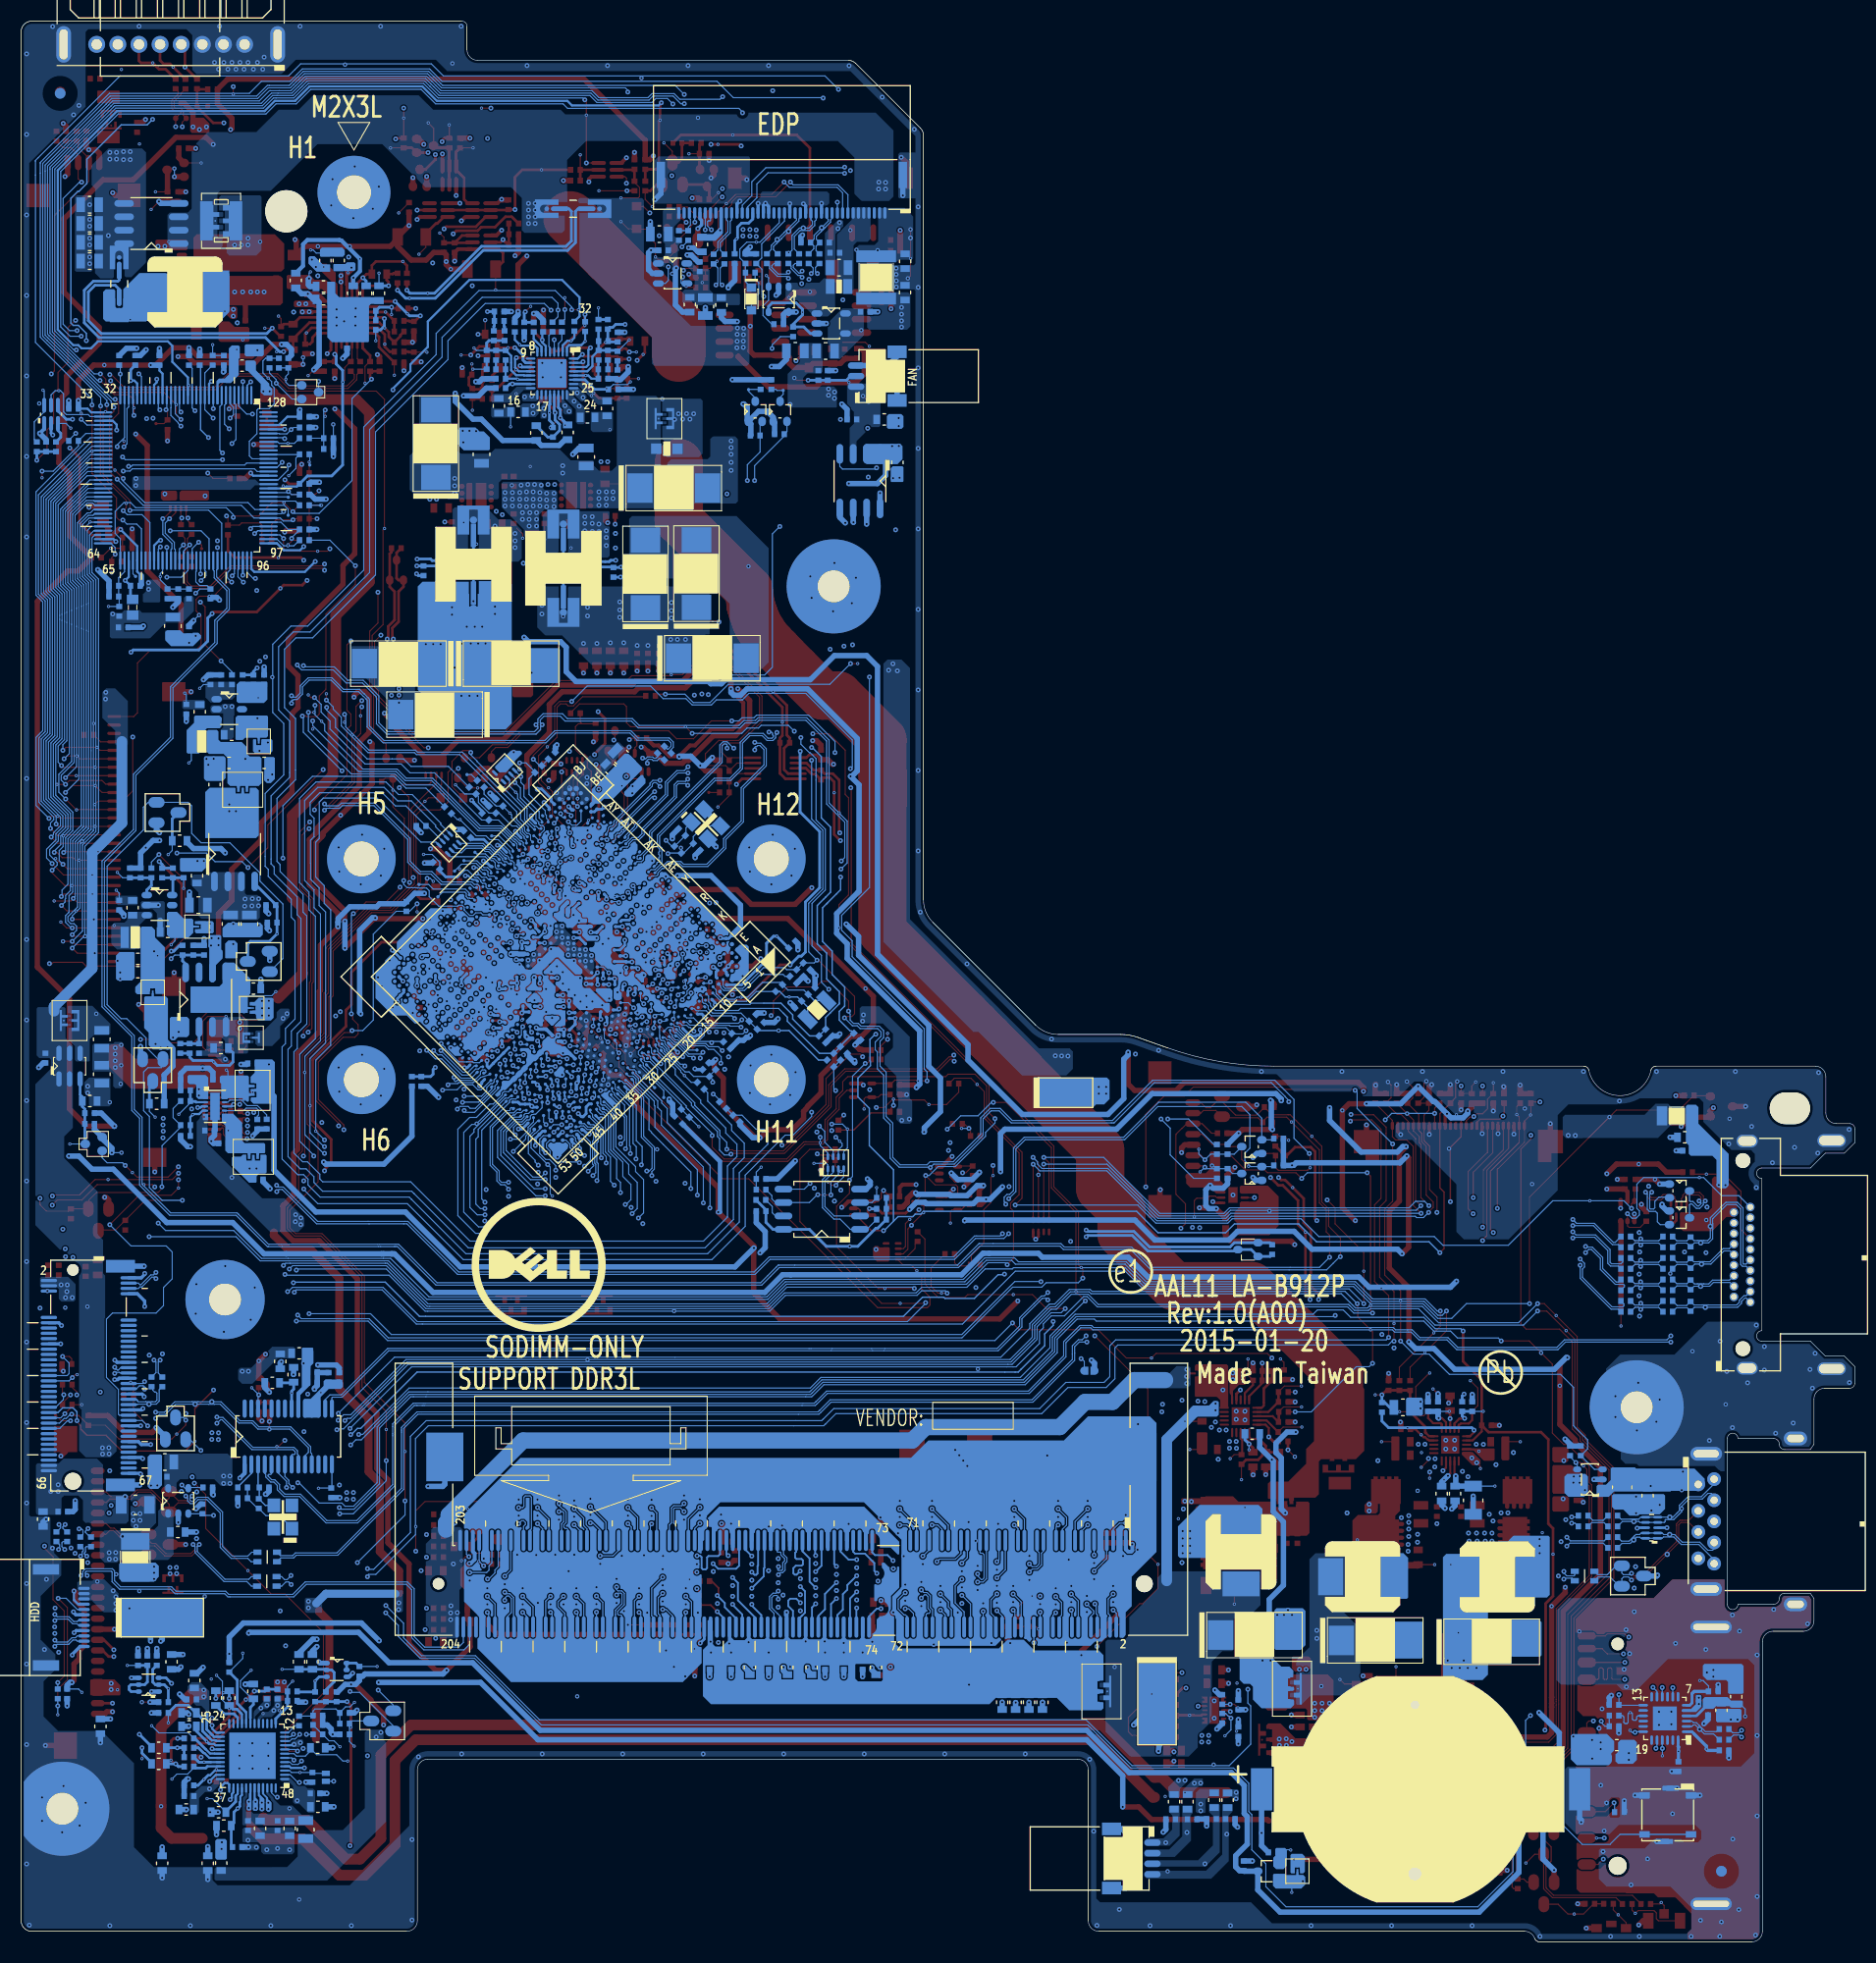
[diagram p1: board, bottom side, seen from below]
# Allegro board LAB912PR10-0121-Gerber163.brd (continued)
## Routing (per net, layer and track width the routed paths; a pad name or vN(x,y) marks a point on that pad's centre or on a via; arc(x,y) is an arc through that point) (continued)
EC_TX: length 102.3
  TOP w0.102: v2(163.82,141.51) v1(163.82,142.06) ; v2(169.63,55.41) 168.98,55.41 168.76,55.19 RM11.2
  IN2 w0.127: v2(163.82,141.51) 163.82,141.31 165.41,139.72 165.41,128.99 169.68,124.72 169.68,115.85 171.68,113.85 171.68,90.78 170.82,89.92 170.82,72.02 169.63,70.83 169.63,68.87 170.69,67.81 170.69,61.33 169.28,59.93 169.28,55.75 v2(169.63,55.41)
  BOTTOM w0.102: UE1.30 163.36,145.29 163.54,145.12 163.54,141.79 v2(163.82,141.51) ; v2(169.63,55.41) 169.02,54.8 169.02,53.78 169.2,53.6 JNGFF.30
ECAGND: length 10.3
  TOP w0.102: LE2.2 v1(167.02,134.4)
  TOP w0.508: LE2.2 165.79,134.32 165.33,133.87 CE9.1 164.9,133.12 164.33,133.69 v2(164.14,133.69)
  BOTTOM w0.203: 162.17,129.31 162.56,129.7 UE1.69 162.56,132.11 v2(164.14,133.69)
  BOTTOM w0.508: 162.17,129.31 162.17,128.47 CE7.2
EDP_CPU_AUX: length 69.7
  IN2 w0.127: v2(98.19,157.91) 98.28,157.82 98.28,132.89 99.5,131.68 99.5,116.29 101.25,114.54 101.25,113.02 102.3,111.97 106.29,111.97 106.71,112.39 106.71,112.96 v2(106.74,112.99)
  BOTTOM w0.102: CX44.1 98.37,158.48 98.37,158.09 v2(98.19,157.91) ; v2(106.74,112.99) 106.74,113.29 106.83,113.38 107.03,113.38 107.21,113.2 107.21,111.64 112.23,106.61 113.87,104.98 113.87,103.61 114.65,102.82 114.65,102.43 114.83,102.25 115.25,102.25 USOC1.AK3
EDP_CPU_AUX#: length 69.6
  IN2 w0.127: v2(106.1,112.99) 106.2,112.99 106.34,112.85 106.34,112.79 106.45,112.67 106.45,112.5 106.18,112.23 102.41,112.23 101.5,113.13 101.5,114.65 99.75,116.4 99.75,131.78 98.54,133 98.54,157.67 v2(98.77,157.91)
  BOTTOM w0.102: v2(98.77,157.91) 98.59,158.09 98.59,158.43 CX43.1 ; v2(106.1,112.99) 106.13,112.99 106.74,113.6 107.12,113.6 107.42,113.29 107.42,111.73 114.08,105.07 114.08,103.69 114.93,102.85 115.15,102.85 115.25,102.75 115.25,102.52 115.2,102.47 115.03,102.47 USOC1.AK2
EDP_CPU_HPD: length 262.4
  TOP w0.102: v2(95.03,109.24) 94.99,109.2 94.99,94.56 87.03,86.6 87.03,86.59 84.88,84.44 84.88,84.44 81.72,81.27 81.72,81.22 75.81,75.31 75.81,71.46 73.49,69.14 73.49,69.07 73.48,69.06 73.48,64.08 v1(73.22,63.83) 73.07,63.67 v2(73.07,62.82) ; v2(107.19,165.16) 108.54,163.81 Q9.1 109.44,163.14 110.51,164.21 R3406.2
  IN1 w0.127: v2(95.03,109.24) 96.16,110.37 96.16,111.61 96.95,112.39 96.95,119.82 100.58,123.45 100.58,143.12 102.6,145.15 102.6,147.3 103.7,148.4 103.7,153.37 105.05,154.72 105.05,156.5 103.43,158.11 103.43,162.59 105.06,164.22 106.25,164.22 v2(107.19,165.16)
  IN2 w0.102: v2(117.29,85.92) 117.53,85.92 117.61,85.99 117.93,85.99 119,87.06 119.58,87.06 119.8,86.84 119.8,86.71 120.6,85.92 121.25,85.92 121.49,86.16 121.81,86.16 122.54,85.43 123.13,85.43 124.74,87.05 126.3,87.05
  IN2 w0.127: 126.3,87.05 126.71,86.63 127.38,86.63 128.08,85.94 128.48,85.94 128.78,85.64 130.06,85.64 131.63,87.21 143.37,87.21 147.76,82.82 147.76,70.14 148.29,69.6 148.29,67.47 147,66.17 147,60.03 147.38,59.65 v2(147.38,59.33)
  BOTTOM w0.102: v2(73.07,62.82) 73.5,62.39 76.54,62.39 76.96,61.97 79.71,61.97 84.51,57.17 138.8,57.17 140.61,58.99 147.03,58.99 v2(147.38,59.33) ; USOC1.K30 117.36,85.84 v2(117.29,85.92)
EDP_CPU_LANE_N0: length 69
  IN2 w0.127: v2(99.64,158.14) 100.21,158.14 100.45,157.89 100.45,156.53 99.76,155.84 99.76,147.16 99.47,146.86 99.47,133.19 100.23,132.43 100.54,132.12 100.54,117.32 102.41,115.45 102.41,114.65 102.55,114.51 v2(102.77,114.51)
  BOTTOM w0.102: CX46.1 100.3,158.86 100.46,158.69 100.46,158.48 99.93,157.95 99.83,157.95 v2(99.64,158.14) ; USOC1.AG1 113.61,101.8 113.38,102.03 113.38,102.14 113.33,102.19 113.21,102.19 113.12,102.28 113.12,102.38 113.2,102.46 113.2,102.61 113.12,102.69 113.12,102.87 113.2,102.94 113.2,103.14 113.12,103.22 113.12,103.45 113.34,103.66 113.34,104.74 107.94,110.14 106.47,110.14 105.49,111.12 105.49,113.55 104.65,114.38 103.32,114.38 102.86,113.93 102.48,113.93 102.36,114.05 102.36,114.17 102.43,114.24 102.43,114.4 102.55,114.51 v2(102.77,114.51)
EDP_CPU_LANE_N1: length 71.1
  IN2 w0.127: v2(100.94,158.04) 101.1,157.88 101.37,157.88 101.65,157.6 101.65,147.8 100.25,146.4 100.25,133.68 101.36,132.57 101.36,118.64 104.84,115.17 104.84,113.54 v2(104.12,112.82)
  BOTTOM w0.102: v2(104.12,112.82) 104.12,113.06 104.06,113.13 103.94,113.13 103.83,113.24 103.64,113.24 103.24,112.85 103.24,111.4 105.4,109.24 105.4,106.09 107.07,104.43 107.07,103.59 108.66,102 110.85,102 111.1,102.26 112.39,102.26 112.83,101.81 112.95,101.81 113.57,101.18 USOC1.AF2 ; v2(100.94,158.04) 101.12,157.86 101.88,157.86 102.51,158.48 102.51,158.64 102.29,158.86 CX47.1
EDP_CPU_LANE_P0: length 69.1
  IN2 w0.127: v2(99.64,157.55) 99.66,157.55 99.99,157.88 100.1,157.88 100.19,157.79 100.19,156.63 99.51,155.95 99.51,147.26 99.22,146.97 99.22,133.08 99.82,132.47 100.28,132.01 100.28,117.21 102.15,115.34 102.15,114.6 v2(102.03,114.47)
  BOTTOM w0.102: USOC1.AG3 114.15,101.27 113.94,101.48 113.57,101.48 112.91,102.14 112.91,103.54 113.12,103.75 113.12,104.66 107.85,109.93 106.38,109.93 105.28,111.03 105.28,113.46 104.56,114.17 103.41,114.17 102.95,113.71 102.39,113.71 102.14,113.96 102.14,114.36 v2(102.03,114.47) ; CX42.1 100.68,158.61 100.68,158.39 100.02,157.73 99.82,157.73 v2(99.64,157.55)
EDP_CPU_LANE_P1: length 71.2
  IN2 w0.127: v2(100.94,157.46) 101.1,157.62 101.26,157.62 101.39,157.49 101.39,147.91 99.99,146.51 99.99,133.58 101.11,132.46 101.11,118.53 104.57,115.07 104.57,113.63 104.42,113.48 104.17,113.48 v2(104.12,113.53)
  BOTTOM w0.102: USOC1.AF3 113.86,100.88 113.42,100.88 113.28,101.03 113.28,101.19 112.87,101.59 112.74,101.59 112.3,102.04 111.19,102.04 110.94,101.79 108.57,101.79 106.85,103.5 106.85,104.34 105.19,106 105.19,109.15 103.03,111.31 103.03,112.94 103.55,113.46 104.04,113.46 v2(104.12,113.53) ; CX45.1 102.72,158.62 102.72,158.39 101.97,157.64 101.12,157.64 v2(100.94,157.46)
EDP_HPD: length 20.2
  TOP w0.102: R3405.1 107.58,160.5 Q9.2 107.58,163.75 v1(106.8,164.52) 105.92,165.4 102.51,165.4 v2(101.34,166.57)
  BOTTOM w0.102: JEDP.9 95.8,165.55 96.32,166.07 100.84,166.07 v2(101.34,166.57)
EN_0.675VSP: length 5.8
  TOP w0.102: v1(52.38,52.61) 53.98,52.61 54.55,52.04 PR208.2
  TOP w0.203: PU200.7 55.51,50.15 PC215.1
  TOP w0.254: PR208.2 54.55,51.12 PC215.1
EN_1.35VP: length 5.6
  TOP w0.102: v1(52.37,50.63) 54.07,50.63 54.52,50.18 PR207.2
  TOP w0.203: PU200.8 55.1,49.75 PC214.1
  TOP w0.254: PR207.2 54.52,49.24 PC214.1
EN_3V: length 11
  TOP w0.203: v2(36.05,48.43) 36.05,48.23 36.42,47.86 PU100.6
  BOTTOM w0.254: v2(36.05,48.43) 36.05,48.46 36.25,48.66 v1(42.34,48.66) 44.13,48.66 44.76,49.3 PR113.1
EN_5V: length 4.5
  TOP w0.102: PR112.1 v1(43.1,50.17)
  TOP w0.203: PU100.20 40.3,47.86 40.59,48.15
  TOP w0.254: PR112.1 40.66,48.74 40.66,48.22 40.59,48.15
EN_5V3V: length 6.6
  TOP w0.102: v2(44.76,51.77) v1(45.4,51.77)
  TOP w0.254: v2(44.76,51.77) 44.33,52.2 PR116.1 PR114.2 PR115.2 PR112.2
  BOTTOM w0.254: PC118.1 44.02,50.59 44.48,51.05 PR113.2 v2(44.76,51.77)
EN_DFAN1: length 165.8
  TOP w0.102: v2(163.92,134.58) 164.27,134.58 164.52,134.83 164.52,136.67 166.84,138.99 166.84,141.07 v1(166.83,141.08) 166.84,141.09 v2(166.84,145.47)
  IN1 w0.127: v2(96.2,175.34) 95.73,174.87 95.73,169.55 94.57,168.4 94.57,147.87 92.44,145.74 92.44,139.67 v2(92.59,139.52)
  BOTTOM w0.102: v2(163.92,134.58) 163.54,134.2 162.62,134.2 162.16,133.74 UE1.70 ; v2(96.2,175.34) 97.47,176.61 133.59,176.61 134.73,177.76 147.1,177.76 147.63,177.22 148.24,176.61 164.19,176.61 164.22,176.59 171.92,168.88 172.19,168.61 172.19,168.55 172.19,168.55 172.19,167.23 172.19,167.23 172.19,151.39 166.84,146.04 v2(166.84,145.47) ; UE3.4 96.07,139.66 95.81,139.4 92.7,139.4 v2(92.59,139.52)
EN_INVPWR: length 1.6
  BOTTOM w0.102: UE1.68 162.96,129.49 T197.1
ENVDD: length 107.9
  TOP w0.102: v2(98.62,114.35) 97.11,114.35 95.56,112.8 95.56,108.61 95.24,108.29 95.24,99.08 96.14,98.18 v1(96.14,95.98) 96.14,95.39 87.25,86.5 87.25,86.49 81.95,81.18 81.95,78.47 81.4,77.92 v2(81.38,77.92) ; R30.2 87.99,70.98 87.99,72.49 v2(87.94,72.54) 87.05,71.65 85.09,71.65 84.91,71.47 U68.4 83.94,70.58 R11.1
  IN1 w0.127: v2(102.48,150.82) 101.82,150.16 101.82,145.49 99.82,143.48 99.82,124.3 98.76,123.25 96.16,123.25 95.68,122.77 v2(95.68,122.64)
  IN2 w0.127: v2(98.62,114.35) 98.27,114.35 95.68,116.94 v2(95.68,122.64)
  BOTTOM w0.102: v2(102.48,150.82) 102.47,150.83 102.47,151.16 101.69,151.94 RX7.2 ; v2(87.94,72.54) 87.61,72.54 86.76,73.38 85.14,73.38 82.28,76.25 82.28,76.61 81.38,77.5 v2(81.38,77.92)
ENVDD_R: length 8.7
  BOTTOM w0.254: UX1.3 98.85,152.23 99.47,152.85 RX7.1 100.49,153.11 99.6,154 v1(99.6,154.25) 99.6,154.53 100.2,155.13 102.48,155.13 102.81,154.8 UX4.4
ERP_LOT6: length 110.1
  TOP w0.102: v2(129.09,173.57) v1(129.98,173.57)
  TOP w0.254: v2(127.95,161.12) 127.95,161.09 ; 127.95,161.09 127.72,160.87 127.64,160.87 PC8.1 PR21.1 PR16.2 ; 127.95,161.09 128.17,160.87 PQ3.2
  IN1 w0.254: v2(129.09,173.57) 129.98,174.46 150.82,174.46 152.08,173.2 152.08,173.2 152.1,173.19 159.62,173.19 160.89,171.92 165.78,171.92 165.78,171.92 166.05,171.92 170.18,167.78 170.36,167.6 170.36,151.31 168.58,149.53 164.03,149.53 162.99,148.48 162.99,148.3 162.87,148.18 162.87,148.15 162.81,148.09 162.78,148.09 162.36,147.68 162.36,147.53 161.19,146.36 159.68,146.36 159.35,146.03 159.35,143.31 158.93,142.9 158.93,137.18 160.65,135.47 160.65,133.62 160.34,133.32 v2(160.34,132.66)
  IN2 w0.254: v2(127.95,161.12) 127.37,161.69 127.37,165.22 126.23,166.36 126.23,170.71 v2(129.09,173.57)
  BOTTOM w0.203: v2(160.34,132.66) 160.47,132.66 160.96,132.17 UE1.73
FAN_SPEED1: length 137.8
  TOP w0.102: v4(100.37,148.03) 100.16,147.81 v2(99.07,147.81)
  IN1 w0.254: v2(99.07,147.81) 98.75,148.13 98.75,155.39 96.82,157.32 96.82,164.73 97.91,165.82 97.91,169.6 103.78,175.47 112.83,175.47 114.23,174.07 119.02,174.07 119.91,174.96 150.86,174.96 152.25,173.57 165,173.57 170.74,167.83 170.74,151.15 168.74,149.15 164.19,149.15 163.44,148.4 163.44,148.04 v2(163.18,147.78)
  BOTTOM w0.203: UE1.28 162.56,147.5 162.84,147.78 v2(163.18,147.78)
  BOTTOM w0.254: JFAN.2 95.04,148.2 95.43,147.81 CE32.1 RE50.2 v2(99.07,147.81) ; v2(163.18,147.78) 163.18,148.8 CE29.1
FB_1.0VALWP:
  vias: v1(151.11,117.75)
FB_1.05VSP: length 4.7
  BOTTOM w0.102: v1(158.17,99.72) PR304.1
  BOTTOM w0.254: PR304.1 PR302.2 ; PR302.2 159.19,99.15 PU300.6 ; PR302.2 PC301.2
FB_1.35VP: length 6.7
  TOP w0.102: PR206.1 54.03,54.85 v1(54.36,55.18)
  TOP w0.203: 55.94,51.01 55.94,50.76 56.14,50.55 PU200.6
  TOP w0.254: PR206.1 55.07,54.14 PC216.1 55.17,53.14 PR204.1 55.94,52.38 55.94,51.01
FB_3V: length 5.1
  TOP w0.203: v2(36.94,49.55) 36.96,49.53 37.44,49.53 37.9,49.07 PU100.4
  TOP w0.254: PR100.2 37.17,49.78 v2(36.94,49.55)
  BOTTOM w0.102: v1(35.17,50.21) PR102.2
  BOTTOM w0.254: v2(36.94,49.55) 37.17,49.78 PR100.2 PR102.2
FB_5V: length 4.8
  TOP w0.203: PU100.2 38.7,49.19 39.08,49.58 v2(39.39,49.58)
  TOP w0.254: PR101.1 39.45,49.65 39.39,49.59 v2(39.39,49.58)
  BOTTOM w0.102: PR101.1 v1(38.39,50.21)
  BOTTOM w0.508: PR103.1 PR101.1 39.45,49.64 v2(39.39,49.58)
FB_+1.8VSP: length 4.6
  TOP w0.102: v1(42.04,18.03) PR404.1
  TOP w0.254: PR404.1 PR402.2 PC401.2 42.11,21.23 PU400.6
GPIO_NC12: length 2.7
  BOTTOM w0.102: T98.1 114.09,81.35 114.09,82.02 114.97,82.9 USOC1.B30
GPIO_NC13: length 7.9
  BOTTOM w0.102: v1(109.4,77.16) 109.43,77.16 110.31,78.04 RC10.2 RC11.1 111.07,79.2 113.63,81.77 113.63,82.29 USOC1.A29
GPIO_NC14: length 4.5
  BOTTOM w0.102: T97.1 112.73,80.57 113.83,81.67 113.83,82.08 114.67,82.91 114.67,83.17 114.88,83.38 USOC1.C29
GPIO_RCOMP: length 1.4
  TOP w0.254: RC32.2 117.05,88.41 v2(116.96,88.31)
  BOTTOM w0.254: USOC1.N26 117.06,88.21 v2(116.96,88.31)
GPIO_S0_SC_56: length 9.3
  TOP w0.102: RC43.2 RC48.1 124.31,110.35 124.31,109.91 v1(123.64,109.24) 123.27,108.87 123.27,106.72 122.31,105.77 122.31,105.06 123,104.37 v2(123,103.98)
  BOTTOM w0.102: USOC1.BC12 123.03,103.95 v2(123,103.98)
GPIO_S0_SC_63: length 1.3
  TOP w0.102: v2(128.64,97.31) 128.68,97.31 RC16.2
  BOTTOM w0.102: v2(128.64,97.31) 128.73,97.22 USOC1.BA30
GPIO_S0_SC_65: length 21.8
  TOP w0.102: v2(137.34,100.45) 137.34,100.58 137.29,100.64 137.29,106.35 138.36,107.42 v1(138.36,109.01) QC1.1 139.11,110.13 RC17.2
  BOTTOM w0.102: v2(137.34,100.45) 137.34,100.1 137.02,99.78 136.07,99.78 136.04,99.75 135.18,99.75 134.93,99.5 134.93,98.94 134.02,98.03 132.23,98.03 132.13,98.12 131.8,98.12 131.79,98.11 131.62,97.94 131.62,97.7 131.62,97.68 131.1,97.16 130.76,97.16 130.52,97.4 130.03,97.4 129.85,97.21 USOC1.BC30
GPIO_S0_SC_92: length 5.3
  BOTTOM w0.102: USOC1.BH30 131.13,99.25 131.19,99.32 131.19,99.33 131.51,99.65 134.55,99.65 134.98,100.08 T110.1
GPIO_S0_SC_93: length 4.1
  BOTTOM w0.102: USOC1.BG30 130.79,98.76 131.07,98.76 131.1,98.8 131.27,98.8 131.42,98.94 131.42,99.24 131.54,99.36 133.66,99.36 T111.1
GPIO_S5_14: length 4.2
  TOP w0.102: v2(113.99,88.13) 113.99,87.46 113.91,87.38 113.91,86.92 v1(114.23,86.6) 114.23,85.98 113.68,85.43 RP65.3
  BOTTOM w0.102: USOC1.J20 113.92,88.2 v2(113.99,88.13)
GPIO_S5_17: length 1.3
  TOP w0.102: v2(114.77,87.55) 114.73,87.6 T104.1
  BOTTOM w0.102: USOC1.J24 115.09,87.39 114.93,87.55 v2(114.77,87.55)
H_PROCHOT#: length 248.4
  TOP w0.102: PQ4.6 v2(120.06,168.37) v1(120.06,172.91) 120.06,174.21 v2(120.2,174.35) ; v2(154.11,134.96) 153.98,134.83 R44.2 152.89,134.09 152.68,134.31 150.98,134.31 150.76,134.08 RE13.1 ; v2(101.54,75.41) 101.22,75.41 97.38,79.25 97.38,81.71 95.05,84.03 94.16,84.03 v2(93.91,83.78) ; PQ4.3 116.39,167.07 116.26,166.95 v2(116.26,166.45)
  IN1 w0.127: v2(101.54,75.41) 101.54,75.71 102.45,76.61 104.48,76.61 107.5,79.63 107.5,80.98 107.88,81.36 v2(108.1,81.36) ; v2(154.11,134.96) 153.07,136 153.07,146.52 153.57,147.02 161.01,147.02 161.73,147.74 161.73,148.68 162.13,149.08 162.41,149.08 163.71,150.38 168.03,150.38 v2(168.33,150.67) ; v2(116.26,166.45) 113.43,163.62 109.12,163.62 107.69,162.19 107.69,161.34 108.25,160.78 108.25,156.06 106.29,154.1 106.29,150.1 103.24,147.04 103.24,144.85 101.21,142.83 101.21,123.08 99.21,121.08 99.21,115.21 99.75,114.66 v2(99.75,113.99)
  IN2 w0.127: v2(93.91,83.78) 94.21,84.08 94.21,85.07 96.07,86.92 96.07,88.9 97.11,89.94 v2(97.11,90.17) ; v2(116.26,166.45) 118.18,168.37 v2(120.06,168.37)
  BOTTOM w0.102: 108.41,81.92 108.41,81.97 RC15.1 ; 108.41,81.92 109.9,81.92 110.33,82.34 110.71,82.34 112.67,84.3 112.67,84.47 112.89,84.69 113.02,84.7 113.21,84.89 113.21,85.06 113.4,85.25 USOC1.C24 ; 108.41,81.92 108.1,81.61 v2(108.1,81.36) ; v2(97.11,90.17) 97.11,90.14 97.81,90.84 97.81,93.38 98.7,94.27 98.7,98.3 97.44,99.55 97.44,105.31 98.32,106.19 98.32,109.95 98.32,109.95 98.32,110.36 98.32,110.37 98.32,111.99 98.88,112.56 98.94,112.56 99.75,113.37 v2(99.75,113.99) ; v2(120.2,174.35) 120.38,174.53 134.09,174.53 135.46,175.9 146.36,175.9 147.74,174.53 149.43,174.53 149.66,174.53 150.62,173.57 164.59,173.57 170.36,167.8 170.36,152.48 168.59,150.71 168.36,150.71 v2(168.33,150.67)
HDA_BIT_CLK: length 5.2
  BOTTOM w0.102: RP64.6 132.58,103.09 131.86,103.09 131.44,103.51 129.94,103.51 129.64,103.21 129.32,103.21 128.97,102.85 128.87,102.76 128.6,102.76 USOC1.BJ21
HDA_BITCLK_AUDIO: length 113.3
  IN2 w0.127: v2(147.73,17.2) 147.69,17.24 147.62,17.24 147.23,17.63 146.63,17.63 146.36,17.9 146.36,19.45 v2(146.55,19.64) 143.91,22.28 143.91,25.66 143.91,35.96 144.91,36.96 144.91,50.4 143.52,51.79 143.52,55.13 144.84,56.44 144.84,70.48 145.34,70.99 145.34,74.84 145.05,75.14 144.96,75.14 v2(144.84,75.27)
  BOTTOM w0.102: v2(147.73,17.2) 147.94,17.41 UA1.6 ; RP64.3 135.11,105.62 CC7.1 137.13,107.51 138.12,107.51 139.37,108.77 145.29,108.77 146.2,107.87 146.2,106.73 145.83,106.36 145.83,104.61 146.16,104.28 146.16,102.12 146.15,102.07 146.15,100.58 145.34,99.77 145.34,98.09 144.74,97.48 144.74,85.09 146.21,83.61 v1(146.21,79.15) 146.21,76.59 144.88,75.27 v2(144.84,75.27) ; R2355.1 v2(146.55,19.64)
HDA_RCOMP: length 5.8
  BOTTOM w0.102: 129.32,103.91 129.16,103.91 128.62,103.37 128.23,103.37 127.7,102.83 127.57,102.83 127.4,102.65 127.4,102.5 127.23,102.33 127.08,102.33 126.89,102.14 126.89,101.71 USOC1.BF20
  BOTTOM w0.254: 129.32,103.91 129.76,104.35 130.85,104.35 RC14.1
HDA_RST#: length 6.2
  BOTTOM w0.102: RP64.5 132.91,102.72 129.63,102.72 129.36,102.45 129.13,102.45 129.03,102.34 128.9,102.34 128.68,102.13 128.68,101.72 128.52,101.55 128.09,101.55 127.89,101.36
HDA_RST_AUDIO#: length 107.9
  IN2 w0.127: v2(144.84,75.9) 145.05,75.9 146.36,74.59 146.36,70.57 145.85,70.06 145.85,56.02 144.54,54.7 144.54,52.42 145.93,51.02 145.93,36.41 144.93,35.4 144.93,22.77 147.77,19.93 v2(147.77,19.66)
  BOTTOM w0.102: UA1.11 148.04,19.41 148.02,19.44 147.99,19.44 v2(147.77,19.66) ; v2(144.84,75.9) v1(145.67,76.74) 145.67,83.45 144.25,84.87 144.25,97.68 144.86,98.29 144.86,99.97 145.67,100.78 145.67,104.09 145.33,104.43 145.33,107.89 144.96,108.26 139.87,108.26 135.7,104.1 134.29,104.1 RP64.4
HDA_SDIN0: length 7.7
  BOTTOM w0.102: USOC1.BG19 127.1,102.83 127.31,103.04 127.31,103.24 128.39,104.33 129.19,104.33 129.55,104.69 130.47,104.69 v1(132.01,106.23) 132.26,106.23 RA130.1
HDA_SDOUT: length 6.2
  BOTTOM w0.102: USOC1.BG20 127.42,102.04 127.62,102.24 127.82,102.24 128,102.43 128,102.55 128.41,102.96 128.78,102.96 128.84,103.01 129.24,103.41 129.55,103.41 129.88,103.74 131.54,103.74 131.79,103.49 132.27,103.49 RP64.7
HDA_SDOUT_AUDIO: length 114.9
  IN2 w0.127: v2(144.84,74.63) 144.71,74.63 144.3,74.23 144.3,56.63 142.96,55.28 142.96,51.63 144.09,50.5 144.09,43.97 144.41,43.65 144.41,37.35 143.4,36.34 143.4,26.29 143.4,26.29 143.4,25.87 143.4,25.45 143.4,20.91 144.48,19.83 144.48,18.47 145.85,17.1 146.83,17.1 146.84,17.12 v2(147.01,17.12)
  BOTTOM w0.102: RP64.2 134.32,105.54 134.32,105.69 136.62,108 137.92,108 139.2,109.28 145.47,109.28 146.72,108.03 146.72,100.46 145.83,99.57 145.83,97.89 145.22,97.28 145.22,85.29 146.69,83.81 146.69,82.32 v1(146.72,82.29) 146.69,82.27 146.69,76.39 144.93,74.63 v2(144.84,74.63) ; v2(147.01,17.12) 147.34,16.8 147.9,16.8 148.12,17.01 UA1.5
HDA_SYNC: length 5
  BOTTOM w0.102: USOC1.BH20 127.7,102.54 128.33,103.16 128.7,103.16 128.87,103.33 129.15,103.61 129.47,103.61 129.83,103.97 132.04,103.97 RP64.8
HDA_SYNC_AUDIO: length 112
  IN2 w0.127: v2(145.85,74.38) 145.85,70.78 145.34,70.27 145.34,56.23 144.03,54.92 144.03,52 145.42,50.61 145.42,36.66 144.42,35.66 144.42,22.56 147.19,19.79 v2(147.19,19.64)
  BOTTOM w0.102: UA1.10 148.12,19.01 147.92,19.21 147.62,19.21 v2(147.19,19.64) ; v2(145.85,74.38) 145.85,74.46 147.17,75.78 147.17,84.01 145.7,85.49 145.7,97.08 146.31,97.69 146.31,99.37 147.2,100.26 147.2,108.23 145.64,109.79 139.02,109.79 137.83,108.59 136.54,108.59 133.84,105.89 133.84,105.77 RP64.1
HDMI_CLK+: length 127.5
  IN2 w0.127: v2(110.46,109.47) 110.29,109.63 109.23,109.63 107.43,107.83 98.04,107.83 92.49,102.28 92.49,96.24 76.9,80.65 76.69,80.65 73.59,80.65 72.08,79.14 64.73,79.14 64.25,78.66 57.21,78.66 56.04,77.49 53.27,77.49 46.73,70.95 35.76,70.95 35.63,70.82 35.63,69.28 35.35,69.01 34.76,69.01 34.48,69.28 34.48,70.82 34.35,70.95 32.8,70.95 32.63,70.78 32.63,70.6 33.35,69.88 33.35,69.49 32.93,69.06 32.54,69.06 31.82,69.78 31.64,69.78 28.65,66.8 26.87,66.8 v2(26.69,66.62)
  BOTTOM w0.102: CX13.2 22.39,63.97 23.12,63.97 23.39,64.23 23.39,65.45 24.64,66.7 26.62,66.7 v2(26.69,66.62) ; v2(110.46,109.47) 110.62,109.63 111.34,109.63 111.52,109.44 111.52,108.33 114.58,105.27 114.58,104.8 114.76,104.61 114.82,104.55 114.83,104.55 114.9,104.48 114.98,104.4 115.06,104.32 115.64,104.32 116.03,103.94 116.03,103.78 116.18,103.63 116.63,103.63 USOC1.AP3
HDMI_CLK-: length 127.5
  IN2 w0.127: v2(26.69,67.21) 26.81,67.1 26.85,67.05 28.55,67.05 31.53,70.04 31.93,70.04 32.65,69.32 32.82,69.32 33.1,69.59 33.1,69.77 32.38,70.49 32.38,70.88 32.7,71.21 34.46,71.21 34.74,70.93 34.74,69.39 34.86,69.26 35.25,69.26 35.37,69.39 35.37,70.93 35.65,71.21 46.62,71.21 53.16,77.74 55.93,77.74 57.11,78.92 64.14,78.92 64.62,79.4 71.97,79.4 73.48,80.91 76.69,80.91 76.8,80.91 92.23,96.34 92.23,102.38 97.94,108.09 107.32,108.09 109.13,109.89 110.29,109.89 v2(110.46,110.05)
  BOTTOM w0.102: v2(26.69,67.21) 26.4,66.91 24.55,66.91 23.17,65.54 23.17,64.32 23.03,64.18 22.14,64.18 21.98,64.35 21.98,64.57 CX12.2 ; USOC1.AP2 115.73,104.52 115.15,104.52 115.04,104.63 114.98,104.7 114.98,104.7 114.91,104.77 114.79,104.89 114.79,105.36 111.74,108.42 111.74,109.53 111.43,109.85 110.67,109.85 v2(110.46,110.05)
HDMI_DDCCLK: length 128.4
  TOP w0.102: v2(85.24,83.35) 85.44,83.55 85.63,83.55 86.77,82.41 95.51,82.41 96.89,81.02 96.89,79.05 100.17,75.78 101.31,74.63 106.29,74.63 v2(106.37,74.56) ; v2(19.22,70.95) 19.41,70.76 19.41,70.6 19.26,70.44 18.44,70.44 18.15,70.73 17.27,70.73 17.05,70.51 17.05,70.32 16.91,70.18 RP15.6
  IN2 w0.127: v2(85.24,83.35) 85.07,83.52 82.85,83.52 77.9,78.58 76.65,78.58 76.65,78.58 76.44,78.58 76.07,78.58 75.43,78.58 75.33,78.58 75.33,78.58 74.86,78.58 72.8,76.51 60.51,76.51 59.7,77.31 57.68,77.31 55.64,75.27 53.98,75.27 50.81,72.09 49.77,72.09 47.25,69.58 43.22,69.58 41.7,68.07 31.09,68.07 26.31,63.28 23.37,63.28 21.04,65.62 21.04,67.22 19.39,68.88 19.39,70.79 v2(19.22,70.95)
  BOTTOM w0.102: v2(19.22,70.95) 19.41,70.76 19.41,69.43 19.36,69.37 19.04,69.37 18.93,69.48 18.93,70.09 18.53,70.49 17.96,70.49 17.9,70.43 Q57.3 ; USOC1.C28 114.59,84.13 114.38,83.92 114.13,83.92 113.98,83.77 113.98,83.55 112.82,82.38 112.82,82.11 110.11,79.4 110.11,79.16 109.96,79.01 109.96,79.01 107.65,76.7 107.65,76.23 107.45,76.03 107.45,74.94 106.99,74.48 106.44,74.48 v2(106.37,74.56)
HDMI_DDCDATA: length 128.1
  TOP w0.102: v2(19.81,70.95) 19.64,70.79 19.64,70.51 19.35,70.22 18.34,70.22 18.05,70.5 17.37,70.5 17.28,70.41 17.28,70.31 17.41,70.18 RP15.5 ; v2(106.76,75.03) 106.7,74.96 106.2,74.96 106.1,74.86 101.4,74.86 100.39,75.87 97.12,79.14 97.12,81.12 95.6,82.63 86.86,82.63 85.72,83.77 85.53,83.77 85.52,83.79 85.42,83.79 v2(85.28,83.94)
  IN2 w0.127: v2(19.81,70.95) 19.64,70.79 19.64,68.98 21.3,67.33 21.3,65.72 23.48,63.54 26.21,63.54 30.99,68.32 41.6,68.32 43.11,69.83 43.32,69.83 47.15,69.83 49.66,72.35 50.7,72.35 53.88,75.52 55.53,75.52 57.58,77.57 59.81,77.57 60.61,76.77 72.69,76.77 74.76,78.83 75.22,78.83 75.22,78.83 75.54,78.83 76.17,78.83 76.55,78.83 76.76,78.83 77.8,78.83 82.74,83.78 85.11,83.78 85.15,83.82 85.16,83.82 v2(85.28,83.94)
  BOTTOM w0.102: v2(19.81,70.95) 19.64,70.79 19.64,69.33 19.45,69.14 18.87,69.14 18.69,68.97 18.69,68.16 18.42,67.89 Q58.3 ; USOC1.C26 113.89,84.6 113.89,84.14 113.76,84.01 113.34,84.01 112.58,83.24 112.58,82.4 112.59,82.38 112.59,82.21 109.8,79.42 109.8,79.17 107.42,76.8 107.42,76.33 106.76,75.67 v2(106.76,75.03)
HDMI_GND: length 9.9
  TOP w0.102: v1(22.14,58.3) R1078.2
  TOP w0.508: Q14.3 22.14,68.19 R1073.2 R1074.2 R1071.2 R1072.2 R1075.2 R1076.2 R1077.2 R1078.2
HDMI_HPD#: length 122.6
  TOP w0.102: v2(108.15,76.32) 108.15,75.23 107.02,74.1 101.1,74.1 99.47,75.72 99.28,75.72 97.77,75.72 97.47,76.03 97.47,77.79 97.39,77.86 97.39,77.87 96.41,78.85 96.41,79.95 95.79,80.57 95.79,81.42 95.31,81.9 86.05,81.9 85.82,82.13 83.27,82.13 82.18,81.03 82.18,78.08 78.82,74.73 78.82,70.39 v2(79.47,69.74) ; v2(21.14,69.43) 21.14,69.85 Q14.6 20.87,71.14 R376.2
  BOTTOM w0.102: v2(21.14,69.43) 21.86,70.14 v1(25.09,70.14) 28.59,70.14 32.8,65.93 38.98,65.93 39.81,66.76 50.73,66.76 52.42,68.45 58.92,68.45 59.34,68.03 66.16,68.03 67.87,69.74 v2(79.47,69.74) ; v2(108.15,76.32) 108.15,76.52 110.42,78.79 110.6,78.97 110.6,79.12 113.33,81.84 113.33,82.59 114.06,83.32 114.47,83.32 114.58,83.43 114.58,83.68 114.73,83.83 114.95,83.83 115.13,84.01 115.13,84.29 114.91,84.51 114.9,84.51 USOC1.D27
HDMI_HPLUG: length 19.8
  TOP w0.102: R121.1 20.32,67.63 21.38,67.63 21.52,67.78 Q14.2 v2(21.52,68.92)
  BOTTOM w0.102: v2(21.52,68.92) 21.1,68.5 20.7,68.5 20.39,68.8 20.39,69.19 20.63,69.43 20.63,71.71 20,72.35 v1(14.71,72.35) 14.31,72.35 12.6,70.63 10.98,70.63 JHDMI1.19
HDMI_TX0+: length 120.6
  IN2 w0.127: v2(26.69,67.79) 28.12,67.79 32.05,71.71 33.12,71.71 46.41,71.71 52.95,78.25 54.86,78.25 56.27,79.66 63.87,79.66 64.22,80.02 69.36,80.02 70.76,81.41 76.59,81.41 91.6,96.43 91.6,102.54 97.68,108.62 107.01,108.62 108.79,110.4 109.96,110.4 110.2,110.64 v2(110.43,110.64)
  BOTTOM w0.102: v2(110.43,110.64) 111.4,110.64 112.36,109.68 112.36,108.52 115.28,105.6 115.28,105.5 115.55,105.23 115.56,105.23 116.07,104.71 116.07,104.47 116.31,104.23 116.49,104.23 116.7,104.02 USOC1.AR3 ; CX15.2 22.39,66 22.95,66 24.74,67.79 v2(26.69,67.79)
HDMI_TX0-: length 120.6
  IN2 w0.127: v2(26.69,68.38) 26.94,68.14 26.95,68.14 27.03,68.05 28.02,68.05 31.94,71.97 33.23,71.97 46.31,71.97 52.84,78.51 54.75,78.51 56.16,79.92 63.76,79.92 64.12,80.27 69.26,80.27 70.66,81.67 76.48,81.67 91.34,96.54 91.34,102.64 97.58,108.87 106.9,108.87 108.68,110.65 109.86,110.65 110.26,111.06 110.27,111.06 v2(110.43,111.22)
  BOTTOM w0.102: CX14.2 22.68,66.21 22.86,66.21 24.66,68.01 26.34,68.01 26.47,68.15 26.47,68.16 v2(26.69,68.38) ; v2(110.43,111.22) 110.62,111.04 110.62,111.03 110.79,110.85 111.49,110.85 112.58,109.77 112.58,108.6 115.49,105.69 115.49,105.59 115.64,105.44 115.7,105.38 115.7,105.37 116.39,104.68 USOC1.AR1
HDMI_TX1+: length 127.1
  IN2 w0.127: v2(25.49,65.24) 25.71,65.46 25.98,65.46 26.26,65.73 26.26,66.37 26,66.62 26,68.45 30.03,72.48 31.73,72.48 31.73,72.48 33.44,72.48 44.94,72.48 45.98,73.53 46.99,73.53 53.93,80.47 63.41,80.47 63.78,80.84 69.11,80.84 70.66,82.39 75.85,82.39 75.85,82.39 76.48,82.39 90.71,96.62 90.71,102.78 97.42,109.48 105.07,109.48 105.61,110.02 107.32,110.02 109.07,111.77 110.61,111.77 111.09,111.28 111.09,109.84 112.4,108.53 113.35,108.53 v2(113.59,108.29)
  BOTTOM w0.102: CX17.2 21.81,62 21.81,62.15 21.9,62.24 22.67,62.24 24.09,63.65 24.09,64.69 24.94,65.54 25.19,65.54 v2(25.49,65.24) ; USOC1.AT2 117.01,104.62 116.91,104.72 116.82,104.72 116.1,105.44 116.1,106.12 115.98,106.24 115.91,106.31 115.9,106.31 113.8,108.42 113.72,108.42 v2(113.59,108.29)
HDMI_TX1-: length 127.1
  IN2 w0.127: v2(25.49,65.82) 25.6,65.71 25.88,65.71 26,65.84 26,66.26 25.75,66.51 25.75,68.55 29.93,72.73 31.62,72.73 31.62,72.74 33.55,72.74 44.83,72.74 45.88,73.78 46.88,73.78 53.83,80.73 63.3,80.73 63.67,81.1 69,81.1 70.55,82.65 75.95,82.65 76.37,82.65 90.45,96.73 90.45,102.88 97.31,109.74 104.97,109.74 105.5,110.27 107.21,110.27 108.97,112.02 110.71,112.02 111.35,111.39 111.35,109.94 112.5,108.79 113.51,108.79 v2(113.59,108.87)
  BOTTOM w0.102: v2(25.49,65.82) 25.42,65.76 24.85,65.76 23.87,64.78 23.87,63.74 22.58,62.45 22.38,62.45 CX16.2 ; v2(113.59,108.87) 113.65,108.87 114.23,108.29 115.99,106.53 116.06,106.47 116.06,106.46 116.31,106.21 116.31,105.52 116.91,104.92 117.13,104.92 117.31,104.73 117.31,104.32 USOC1.AT3
HDMI_TX2+: length 132.3
  IN2 w0.127: v2(113.09,109.94) 112.2,110.83 112.2,112.2 111.55,112.85 107.91,112.85 106.2,111.14 105.13,111.14 104.66,110.67 97.07,110.67 89.63,103.23 89.63,96.98 76.06,83.41 70.11,83.41 68.56,81.86 63.35,81.86 62.99,81.49 53.51,81.49 46.56,74.55 45.56,74.55 44.53,73.52 29.31,73.52 24.57,68.77 24.57,64.73 25.25,64.05 v2(26,64.05)
  BOTTOM w0.102: USOC1.AV3 118.12,104.95 117.99,105.25 117.99,105.43 117.8,105.61 117.62,105.61 117.45,105.78 117.45,106.06 114.03,109.48 114.03,109.67 113.76,109.94 v2(113.09,109.94) ; CX19.2 22.38,59.89 23.07,59.89 26,62.81 v2(26,64.05)
HDMI_TX2-: length 132.4
  IN2 w0.127: v2(26,64.63) 25.83,64.47 25.82,64.47 25.66,64.3 25.35,64.3 24.82,64.84 24.82,68.66 29.42,73.26 44.63,73.26 45.67,74.29 46.67,74.29 53.61,81.24 63.09,81.24 63.46,81.61 68.66,81.61 70.21,83.15 76.16,83.15 89.88,96.88 89.88,103.12 97.17,110.41 104.77,110.41 105.24,110.88 106.31,110.88 108.02,112.59 111.44,112.59 111.94,112.09 111.94,110.72 112.67,110 112.67,109.77 112.91,109.52 112.96,109.52 113.09,109.39 v2(113.09,109.35)
  BOTTOM w0.102: CX18.2 21.86,60.39 21.86,60.21 21.97,60.1 22.98,60.1 25.78,62.9 25.78,63.69 25.59,63.88 25.59,64.22 v2(26,64.63) ; USOC1.AV2 117.61,105.39 117.53,105.39 117.23,105.69 117.23,105.97 114.19,109.01 113.82,109.39 113.82,109.58 113.67,109.72 113.45,109.72 113.26,109.53 113.19,109.53 113.09,109.43 v2(113.09,109.35)
HPOUT-L: length 2.7
  BOTTOM w0.203: UA1.32 155.61,17.01
  BOTTOM w0.254: RA55.1 156.85,17.13 156.85,17.13 156.72,17 156.25,17 v1(156.24,17.01) 155.61,17.01
HPOUT-R: length 5.3
  BOTTOM w0.102: v1(159.28,15.41) 158.81,15.88 157.79,15.88 157.21,16.47 RA56.1
  BOTTOM w0.203: UA1.33 155.92,16.61 155.92,16.61
  BOTTOM w0.254: RA56.1 157.07,16.45 156.08,16.45 155.92,16.61
HSIC_RCOMP: length 9.3
  BOTTOM w0.254: RC49.2 100.9,94.06 v1(102.03,95.18) 102.34,95.18 103,94.52 103,92.76 103.21,92.55 103.4,92.55 105.36,90.59 106.77,90.59
HUB_BUSJ: length 0
  BOTTOM w0.102: R1047.2 143.43,52.97
  vias: v1(145.18,51.99)
HUB_OVCJ: length 4.7
  TOP w0.102: R1051.2 v2(151.06,51.77) C1121.1 R1046.2
  BOTTOM w0.102: v1(151.72,52.45) 151.06,51.79 v2(151.06,51.77) 151.12,51.71 U58.26
HUB_XIN: length 5
  BOTTOM w0.127: Y9.3 150.43,41.32 RC69.2 151.01,41.99 C1133.1 151.12,43.12 U58.3
HUB_XOUT: length 2.7
  BOTTOM w0.127: U58.2 151.76,44.34 153.04,43.06 R1049.1
I2C1_SCL: length 3.2
  BOTTOM w0.102: T114.1 131.62,102.32 130.4,102.32 130.1,102.01 130.07,102.01 129.74,101.68 129.41,101.68 129.07,101.35 USOC1.BH24
I2C1_SDA: length 5
  BOTTOM w0.102: T113.1 131.88,102 131.07,102 130.98,102.09 130.5,102.09 129.86,101.46 129.52,101.46 129.37,101.3 129.37,100.97 129.27,100.87 128.78,100.87 USOC1.BG24
I2C2_SCL_TP: length 167.6
  TOP w0.102: v2(146.39,86.1) 146.03,86.46 146.03,90.72 145.9,90.85 145.9,98.72 146.95,99.77 146.95,104.78 146.36,105.37 v2(146.3,105.37)
  IN1 w0.127: v2(80.36,69.82) 80.36,69.71 80.37,69.7 80.37,68.03 80.26,67.91 80.26,67.21 80.13,67.09 80.12,67.09 80.09,67.06 v2(80.09,67.03)
  IN2 w0.127: v2(130.71,101.68) 131.07,102.04 132.06,102.04 132.59,102.57 137.06,102.57 140.12,105.62 146.04,105.62 v2(146.3,105.37) ; v2(146.39,86.1) 146.39,85.61 148.39,83.6 148.39,71.7 148.89,71.2 149.23,71.2 149.36,71.08 v2(149.36,71.01)
  BOTTOM w0.102: v2(130.71,101.68) 130.41,101.68 129.82,101.09 USOC1.BJ25 ; v2(80.09,67.03) 80.54,66.58 83.22,66.58 85.2,64.6 102.66,64.6 104.08,63.18 132.24,63.18 137.03,67.97 137.33,67.97 137.33,67.97 140.62,67.97 145.59,67.97 148.84,71.22 149.15,71.22 v2(149.36,71.01) ; v2(80.36,69.82) 80.36,69.92 80.51,70.07 80.51,70.48 80.25,70.75 80,70.75 79.64,71.11 79.64,75.13 78.61,76.16 69.21,76.16 65.89,79.47 57.65,79.47 56.13,77.95 QE8.3 55.11,75.92 RE30.2
I2C2_SCL_TP_R: length 6.6
  TOP w0.102: JTP.3 61.88,74.44 61.51,74.07 v2(61.51,74.02)
  BOTTOM w0.102: v1(62.08,75.03) 62.08,74.56 61.55,74.02 v2(61.51,74.02) 60.98,74.56 RE33.2 RE19.2 58.74,74.56 QE8.1
I2C2_SDA_TP: length 171.5
  TOP w0.102: v2(146.86,85.73) 146.83,85.76 146.83,86.24 146.26,86.81 146.26,90.81 146.13,90.94 146.13,98.63 147.18,99.68 147.18,99.82 147.18,99.86 147.18,99.87 147.18,105.06 146.24,106 v2(146.23,106)
  IN1 w0.127: v2(80.08,70.34) 80.13,70.39 80.38,70.39 80.78,69.99 80.78,68.08 80.51,67.81 80.51,67.19 v2(80.67,67.03)
  IN2 w0.102: v2(130.44,101.14) 130.17,101.4 130.17,101.67
  IN2 w0.127: v2(146.86,85.73) 146.86,85.53 148.65,83.74 148.65,71.8 148.99,71.46 149.22,71.46 v2(149.37,71.61) ; v2(146.23,106) 146.11,105.88 140.01,105.88 136.97,102.84 132.5,102.84 131.95,102.29 130.46,102.29 130.17,102 130.17,101.67
  BOTTOM w0.102: USOC1.BG25 129.33,100.57 129.53,100.77 129.94,100.77 130.18,101.01 130.31,101.01 v2(130.44,101.14) ; v2(149.37,71.61) 149.21,71.45 148.74,71.45 145.49,68.19 140.71,68.19 136.94,68.19 132.15,63.41 104.18,63.41 102.75,64.83 85.3,64.83 83.32,66.81 83.13,66.81 80.89,66.81 v2(80.67,67.03) ; RE31.2 55.11,73.38 QE7.3 57.17,73.38 57.73,73.93 57.73,74.66 57.26,75.13 57.26,78.3 58.02,79.07 65.97,79.07 69.11,75.93 78.52,75.93 79.41,75.04 79.41,71.01 v2(80.08,70.34)
I2C2_SDA_TP_R: length 5.5
  TOP w0.102: v2(61.52,73.32) 61.64,73.44 JTP.2
  BOTTOM w0.102: QE7.1 58.91,72.73 RE17.2 RE32.2 61.39,73.19 v2(61.52,73.32) v1(61.97,72.88)
I2C5_SCL_PNL: length 97.1
  TOP w0.102: v2(141.31,117.48) 141.85,116.94 141.85,114.61 v1(142.23,114.23) 142.23,109.82 144.53,107.53 144.66,107.53 v2(144.84,107.7)
  IN2 w0.127: v2(104.82,138.31) 104.65,138.15 104.65,118.63 105.63,117.65 106.52,117.65 108.26,115.91 120.91,115.91 121.1,116.1 134.39,116.1 135.32,115.17 136.09,115.17 136.45,115.53 139.48,115.53 140.28,116.33 140.28,116.72 140.86,117.31 141.13,117.31 v2(141.31,117.48)
  BOTTOM w0.102: v2(144.84,107.7) 144.66,107.53 143.5,107.53 143.24,107.78 140.07,107.78 136.73,104.45 136.73,102.29 135.75,101.3 134.68,101.3 133.7,100.32 130.89,100.32 130.66,100.09 130.46,100.09 130.33,100.09 130.15,99.91 130.15,99.53 129.93,99.32 129.93,99.29 ; v2(104.82,138.31) 104.82,139.81 103.61,141.02 RX3.2 103.61,143.72 QE11.3
I2C5_SCL_PNL_R: length 2.5
  BOTTOM w0.102: RX39.2 104.68,146.95 T99.1 104.7,146.77 104.07,146.13 QE11.1
I2C5_SDA_PNL: length 96.9
  TOP w0.102: v2(141.31,116.9) 141.42,116.79 v1(141.42,116.05) 141.42,114.37 142,113.79 142,109.72 144.43,107.3 144.66,107.3 v2(144.84,107.12)
  IN2 w0.127: v2(104.13,138.31) 104.4,138.04 104.4,118.52 105.52,117.4 106.41,117.4 108.16,115.65 121.01,115.65 121.2,115.84 134.28,115.84 135.21,114.92 136.2,114.92 136.56,115.28 139.59,115.28 140.53,116.22 140.53,116.62 140.97,117.05 141.16,117.05 v2(141.31,116.9)
  BOTTOM w0.102: v2(104.13,138.31) 104.13,139.72 101.33,142.53 RX2.2 101.07,142.96 QE10.3 ; USOC1.BH28 130.69,99.79 130.99,100.09 133.79,100.09 134.77,101.07 135.85,101.07 136.96,102.19 136.96,104.35 140.16,107.55 143.15,107.55 143.4,107.3 144.66,107.3 v2(144.84,107.12)
I2C5_SDA_PNL_R: length 2.3
  BOTTOM w0.102: QE10.1 101.72,146.18 101.43,146.48 T109.1 102.01,146.85 102.11,146.95 RX40.2
ICLK_ICOMP: length 2
  TOP w0.254: RC23.2 116.08,95.53 v2(116.65,96.1)
  BOTTOM w0.254: v2(116.65,96.1) 116.66,96.1 USOC1.AD14
ICLK_RCOMP: length 2.7
  TOP w0.254: v2(115.72,97) 114.59,97 RC22.2
  BOTTOM w0.254: USOC1.AD13 116.68,96.72 116,96.72 v2(115.72,97)
ICLK_USB_TERMN: length 2.9
  TOP w0.102: v1(110.83,90.91) 110.79,90.95 RC42.2 109.12,90.95 v2(108.77,91.29)
  BOTTOM w0.102: v2(108.77,91.29) 108.83,91.24 USOC1.F10
ICLK_USB_TERMP: length 3.1
  TOP w0.102: v1(109.63,89.85) 109.38,89.59 108.76,89.59 108.48,89.87 RC41.2 108.46,90.73 v2(108.32,90.87)
  BOTTOM w0.102: USOC1.D10 108.46,90.73 v2(108.32,90.87)
ILB_RTC_EXTPAD: length 7.8
  BOTTOM w0.102: USOC1.B8 107.33,90.45 107.33,90.33 107.05,90.05 105.09,90.05 103.57,91.57 101.43,91.57 101.25,91.39 CC15.1
ILB_RTC_X1: length 11.9
  BOTTOM w0.102: USOC1.C9 107.78,90.11 107.78,89.78 107.09,89.09 106.85,89.09 106.78,89.02 104.89,89.02 103.96,89.95 RC31.2 102.12,89.95
  BOTTOM w0.127: 102.12,89.95 101.75,89.95 101.24,89.44 v1(100.86,89.44) 100.07,89.44 CC18.1 99.11,88.48 YC2.2
ILB_RTC_X2: length 11.7
  BOTTOM w0.102: USOC1.A9 106.7,89.23 105.99,89.23 105.8,89.42 v1(105.43,89.42) 104.78,89.42 103.39,90.81 101.7,90.81 RC31.1 100.98,90.09 99.47,90.09 CC17.1
  BOTTOM w0.127: YC2.1 98.49,89.11 CC17.1
INT-SPK-L+: length 97.9
  TOP w1.016: 66.27,13.69 66.44,13.69 71.89,19.13 136.2,19.13 138.17,17.17 138.17,9.16 141.03,6.31 143.44,6.31 146.87,9.74 150.53,9.74
  vias: v1(65.27,13.76) v2(61.91,13.04) v2(61.91,12.4) v2(152,13.27) v2(152,12.67)
INT-SPK-L-: length 105.4
  TOP w1.016: 150.63,11.73 150.62,11.73 150.4,11.51 146.49,11.51 142.8,7.83 141.47,7.83 139.5,9.8 139.5,17.67 136.65,20.53 71.27,20.53 66.3,15.57 65.55,15.57 64.12,14.13 v1(63.4,14.13) 59.42,14.13
  vias: v2(58.55,14.14) v2(58.57,13.55) v2(151.36,13.25) v2(151.36,12.63)
INT-SPK-R+: length 93.9
  IN1 w1.016: 64.89,15.06 68.22,15.06 68.73,15.57 68.73,18.02 71.05,20.34 137.03,20.34 139.44,17.93 139.44,15.51 143.69,11.26 149.35,11.26 149.79,11.7
  vias: v2(63.4,15.29) v2(64.01,15.27) v2(150.16,13.17) v2(150.15,12.57)
INT-SPK-R-: length 97.7
  IN1 w1.016: 150.68,10.75 149.79,9.86 143.06,9.86 137.98,14.94 137.98,17.42 136.33,19.07 72,19.07 70.19,17.25 70.19,15.12 68.79,13.72 62.71,13.72 62.24,14.19
  vias: v2(61.92,15.03) v2(62.52,15.02) v2(150.77,13.18) v2(150.77,12.59)
INVT_PWM: length 100
  TOP w0.102: U69.4 91.46,81.25 R9.1 90.85,81.58 88.74,81.58 v1(88.65,81.49) v2(87.81,81.49)
  IN1 w0.127: v2(93.26,119.72) 93.57,120.02 93.57,122.8 94.48,123.72 98.56,123.72 99.53,124.69 99.53,143.55 101.57,145.59 101.57,153.86 103.26,155.54 v2(103.26,155.74)
  BOTTOM w0.102: JEDP.20 101.3,162.88 103.46,160.72 103.46,159.38 RX26.1 103.43,158.31 103.43,155.91 v2(103.26,155.74) ; v2(87.81,81.49) 87.81,82.35 88.08,82.62 88.08,86.43 94.9,93.25 94.9,94.76 95.89,95.75 95.89,97.16 93.26,99.79 v2(93.26,119.72)
ISL88731_ICREF: length 6.9
  TOP w0.254: v2(138.16,155.27) PU700.1 ; v2(135.77,153.91) 136.29,153.39 PR729.2 136.79,153.39 136.84,153.44 PR727.1
  BOTTOM w0.254: v2(138.16,155.27) v1(136.99,154.1) 136.8,153.91 v2(135.77,153.91)
ISL88731_VREF: length 3.5
  TOP w0.254: PR725.2 PR727.2 v1(139.06,154.27) PU700.3
JACK_PLUG#: length 56.5
  TOP w0.254: v2(142.7,22.74) 142.33,22.37 v1(142.33,20.32) 142.33,9.28 142.42,9.19 v2(142.42,9.1) ; JIO1.2 v2(164.9,22.59)
  IN1 w0.254: v2(164.9,22.59) 165.58,21.92 165.58,20.9 165.54,20.86 165.54,19.07 163.19,16.73 163.19,7.89 162.01,6.7 144.82,6.7 v2(142.42,9.1)
  BOTTOM w0.254: v2(142.7,22.74) RA1.2 RA3.1 RA4.2
JACK_SENSE#: length 4
  BOTTOM w0.254: RA34.2 147.38,23.66 RA4.1 v1(145.73,24.7) 145.33,25.09 QA5.3
JHDD_P10: length 13.9
  TOP w0.508: v2(168.75,24.56) 168.55,24.76 168.55,26.31 168.06,26.8 168.06,27.56 167.57,28.05 167.57,31.45 168.41,32.29 168.41,33.07 v2(168.55,33.21)
  BOTTOM w0.102: RS7.2 168.12,23.93 v1(167.8,23.62)
  BOTTOM w0.203: JHDD.4 168.15,31.96 168.55,32.35 v2(168.55,33.21)
  BOTTOM w0.508: RS7.2 169.2,24.29 168.93,24.56 v2(168.75,24.56)
KB_CAPS_PWR: length 3.3
  TOP w0.102: JKB.4 166.02,113.58 RE60.2 v1(166.68,115.32)
KB_RST#: length 205.5
  TOP w0.127: R22.2 v2(95.69,78.26)
  IN1 w0.127: v2(95.69,78.26) 91.33,73.9 88.71,73.9 83.56,68.75 83.56,66.81 80.66,63.91 80.66,63.39 80.49,63.22 v2(80.49,63.2) ; v2(151.82,147.66) 152.38,147.1 152.38,131.77 150.32,129.71 150.32,125.86 153.55,122.64 155.01,122.64 156.13,121.52 158.25,121.52 158.54,121.52 160.97,119.1 160.97,114.75 164.1,111.61 164.1,101.85 165.88,100.07 165.88,93.94 165.88,87.76 165.27,87.15 165.27,82.49 165,82.23 165,80.39 163.9,79.28 163.9,76.4 164.13,76.17 164.13,69.26 163.12,68.25 163.12,65.25 162.91,65.03 151.16,65.03 148.79,62.67 148.37,62.67 148.37,62.67 148.06,62.67 v2(147.78,62.39)
  BOTTOM w0.127: v2(147.78,62.39) 147.73,62.44 139.08,62.44 135.85,59.2 135.27,59.2 90.05,59.2 88.23,61.02 86.23,61.02 86.11,60.9 83.33,60.9 81.08,63.15 80.54,63.15 v2(80.49,63.2) ; UE1.2 152.16,147.32 v2(151.82,147.66)
KSI0: length 45.4
  TOP w0.102: v2(169.75,98.95) 169.51,99.18 v1(166.81,99.18) JKB.22
  BOTTOM w0.102: v2(169.75,98.95) 169.68,99.01 169.68,99.55 169.12,100.11 169.12,104.4 168.46,105.06 168.46,105.07 167.85,105.68 167.85,124.32 167.85,128.35 168.45,128.94 168.45,135.03 167.53,135.95 167.53,135.95 167.29,136.19 166.78,136.19 166.56,135.97 UE1.55
KSI1: length 45.5
  TOP w0.102: v2(169.73,98.09) 169.21,97.58 v1(168.36,97.58) JKB.24
  BOTTOM w0.102: UE1.56 166.68,135.57 167,135.25 167.29,135.25 168.22,134.32 168.22,129.04 167.62,128.44 167.62,126.5 167.62,105.59 167.63,105.58 168.23,104.98 168.23,104.97 168.89,104.31 168.89,99.5 169.34,99.05 169.34,98.74 169.39,98.69 169.39,98.43 v2(169.73,98.09)
KSI2: length 47.5
  TOP w0.102: JKB.26 164.76,95.97 v2(168.71,95.97) 169.23,95.97 v1(169.79,96.53)
  BOTTOM w0.102: UE1.57 166.59,135.17 166.74,135.02 167.19,135.02 167.99,134.23 167.99,129.13 167.39,128.54 167.39,126.6 167.39,124.14 167.39,124.13 167.39,105.49 167.4,105.49 167.53,105.35 167.66,105.22 167.67,105.22 168,104.88 168,104.87 168.66,104.21 168.66,99.37 169.02,99.02 169.02,97.46 169.06,97.42 169.35,97.13 169.35,96.5 168.81,95.97 v2(168.71,95.97)
KSI3: length 44.4
  TOP w0.102: v1(170.43,98.52) 168.85,98.52 v2(168.61,98.76) 168.23,98.38 164.75,98.38 JKB.23
  BOTTOM w0.102: v2(168.61,98.76) 168.43,98.94 168.43,104.12 167.17,105.38 167.17,105.39 167.16,105.4 167.16,124.04 167.16,128.63 167.76,129.23 167.76,134.13 167.12,134.77 UE1.58
KSI4: length 46.3
  TOP w0.102: JKB.27 v4(167.49,95.18) 168.56,95.18 v2(168.71,95.33)
  BOTTOM w0.102: UE1.59 167.01,134.37 167.53,133.85 167.53,129.32 166.93,128.72 166.93,112.74 166.93,112.74 166.93,105.3 166.94,105.3 166.94,105.29 167.07,105.15 168.2,104.02 168.2,97.95 169.12,97.04 169.12,96.64 168.86,96.38 168.54,96.38 168.31,96.14 168.31,95.74 v2(168.71,95.33)
KSI5: length 43.5
  TOP w0.102: JKB.25 v4(166.67,96.78) 168.69,96.78 v2(168.71,96.81)
  BOTTOM w0.102: v2(168.71,96.81) 168.71,97.11 167.98,97.85 167.98,103.91 166.71,105.18 166.71,105.2 166.71,105.21 166.71,128.82 167.3,129.42 167.3,133.57 166.91,133.97 UE1.60
KSI6: length 46.1
  TOP w0.102: JKB.28 168.39,94.38 v2(168.71,94.7) v4(169.59,94.7)
  BOTTOM w0.102: v2(168.71,94.7) 167.75,95.66 167.75,103.82 166.48,105.09 166.48,128.91 167.07,129.51 167.07,133.17 166.67,133.57 UE1.61
KSI7: length 45.4
  TOP w0.102: JKB.29 v4(166.58,93.58) 168.23,93.58 v2(168.71,94.06)
  BOTTOM w0.102: UE1.62 166.56,133.17 166.85,132.89 166.85,129.61 166.22,128.98 166.22,104.99 167.52,103.69 167.52,95.26 v2(168.71,94.06)
KSO0: length 46.7
  TOP w0.102: JKB.13 169.93,106.38 v1(170.08,106.54) 170.69,106.54 170.89,106.34 v2(170.91,106.34)
  BOTTOM w0.102: UE1.39 167.01,142.37 172.14,137.24 172.14,127.46 171.51,126.83 171.51,114.64 172.14,114 172.14,107.57 v2(170.91,106.34)
KSO1: length 47.3
  TOP w0.102: v2(170.77,105.39) 170.06,104.68 v1(169.55,104.68) 169.45,104.78 JKB.15
  BOTTOM w0.102: UE1.40 166.91,141.97 171.91,136.96 171.91,127.56 171.28,126.92 171.28,114.54 171.41,114.41 171.87,113.95 171.87,107.88 170.47,106.47 170.47,106.21 170.77,105.91 v2(170.77,105.39)
KSO2: length 45.5
  TOP w0.102: JKB.14 v1(166.55,105.58) 170.02,105.58 v2(170.24,105.8)
  BOTTOM w0.102: v2(170.24,105.8) 170.24,106.56 171.65,107.97 171.65,113.85 171.32,114.18 171.05,114.45 171.05,127.02 171.65,127.62 171.65,136.78 171.51,136.92 166.86,141.57 UE1.41
KSO3: length 47.5
  TOP w0.102: JKB.16 167.62,103.98 v4(167.8,104.16) 167.98,103.98 170.11,103.98 v2(170.71,104.57)
  BOTTOM w0.102: UE1.42 166.94,141.17 171.42,136.69 171.42,127.71 170.82,127.11 170.82,114.35 171.22,113.95 171.42,113.76 171.42,108.06 169.83,106.48 169.83,105.63 170.49,104.97 170.49,104.79 v2(170.71,104.57)
KSO4: length 50
  TOP w0.102: JKB.20 166.61,100.78 v1(166.82,100.99) 169.54,100.99 v2(170.62,102.07)
  BOTTOM w0.102: UE1.43 166.97,140.77 171.19,136.55 171.19,127.81 170.59,127.21 170.59,114.26 171.19,113.66 171.19,108.16 169.6,106.57 169.6,105.54 170.26,104.88 170.26,104.3 171.14,103.42 171.14,102.59 v2(170.62,102.07)
KSO5: length 50.7
  TOP w0.102: v2(170.62,101.43) 170.62,101.18 169.42,99.98 v1(168.75,99.98) JKB.21
  BOTTOM w0.102: v2(170.62,101.43) 170.14,101.91 170.14,102.16 170.45,102.47 170.85,102.87 170.85,103.39 170.03,104.2 170.03,104.78 169.35,105.47 169.35,106.64 170.96,108.25 170.96,113.57 170.5,114.03 170.36,114.16 170.36,127.3 170.96,127.9 170.96,136.45 167.04,140.37 UE1.44
KSO6: length 47.3
  TOP w0.102: v2(170.41,103.12) 170.16,103.12 169.67,102.62 168.62,102.62 168.38,102.38 v1(168.05,102.38) JKB.18
  BOTTOM w0.102: UE1.45 167.12,139.97 170.36,136.73 170.36,136.72 170.46,136.62 170.6,136.48 170.73,136.35 170.73,127.99 170.14,127.4 170.14,114.07 170.4,113.8 170.4,113.8 170.73,113.47 170.73,108.35 169.12,106.74 169.12,105.37 169.81,104.69 169.81,103.86 170.41,103.25 v2(170.41,103.12)
KSO7: length 48
  TOP w0.102: v1(170.29,102.53) 169.74,101.99 v2(169.59,101.99) 169.18,101.58 JKB.19
  BOTTOM w0.102: UE1.46 167.2,139.57 170.11,136.66 170.11,136.65 170.37,136.39 170.5,136.25 170.5,128.09 169.91,127.49 169.91,125.56 169.91,125.18 169.91,125.18 169.91,113.97 170.31,113.57 170.5,113.38 170.5,108.44 168.89,106.83 168.89,105.28 169.58,104.59 169.58,103.67 169.94,103.3 169.94,102.34 v2(169.59,101.99)
KSO8: length 45.1
  TOP w0.102: JKB.17 v1(166.26,103.18) 169.45,103.18 v2(169.53,103.11)
  BOTTOM w0.102: v2(169.53,103.11) 169.35,103.28 169.35,104.5 168.66,105.18 168.66,106.93 170.27,108.54 170.27,113.28 170.21,113.34 169.68,113.88 169.68,125.08 169.68,127.59 170.27,128.18 170.27,136.16 167.26,139.17 UE1.47
KSO9: length 35.8
  TOP w0.102: v2(169.73,111.34) 169.57,111.18 v1(166.55,111.18) JKB.7
  BOTTOM w0.102: v2(169.73,111.34) 170.05,111.65 170.05,113.19 169.45,113.78 169.45,124.99 169.45,125.74 169.45,125.75 169.45,127.68 170.05,128.28 170.05,136.03 167.31,138.77 UE1.48
KSO10: length 33.5
  TOP w0.102: JKB.5 166.08,112.78 v1(166.36,113.06) 169.32,113.06 v2(169.6,112.78)
  BOTTOM w0.102: UE1.49 167.05,138.37 168.9,136.52 168.9,136.52 169.65,135.77 169.82,135.6 169.82,128.37 169.22,127.78 169.22,125.84 169.22,125.84 169.22,124.89 169.22,124.89 169.22,113.69 169.6,113.31 v2(169.6,112.78)
KSO11: length 33.8
  TOP w0.102: v2(169.48,111.98) 169.21,112.25 v1(168.28,112.25) 168.01,111.98 JKB.6
  BOTTOM w0.102: v2(169.48,111.98) 168.99,112.47 168.99,124.8 168.99,127.87 169.59,128.47 169.59,135.51 169.43,135.67 169.11,135.98 169.11,135.99 168.67,136.42 168.67,136.43 167.13,137.97 UE1.50
KSO12: length 37.8
  TOP w0.102: JKB.12 168.27,107.18 v1(168.31,107.15) v2(169.34,108.17)
  BOTTOM w0.102: UE1.51 167.21,137.57 168.45,136.33 168.45,136.33 168.76,136.02 169.36,135.41 169.36,128.56 168.76,127.97 168.76,126.03 168.76,126.03 168.76,124.7 168.76,111.73 169.98,110.51 169.98,108.82 v2(169.34,108.17)
KSO13: length 36.5
  TOP w0.102: v1(170.16,109.56) v2(169.35,109.56) 168.98,109.93 165.9,109.93 165.55,109.58 JKB.9
  BOTTOM w0.102: UE1.52 167.28,137.17 168.22,136.24 168.22,136.23 168.6,135.85 169.13,135.32 169.13,128.66 168.54,128.06 168.54,126.12 168.53,126.12 168.53,124.61 168.54,124.61 168.54,111.63 169.75,110.41 169.75,109.96 v2(169.35,109.56)
KSO14: length 34.1
  TOP w0.102: v2(169.35,110.19) 169.29,110.19 169.1,110.38 v1(168.33,110.38) JKB.8
  BOTTOM w0.102: v2(169.35,110.19) 168.31,111.23 168.31,124.51 168.31,128.16 168.9,128.75 168.9,135.22 168.44,135.69 167.99,136.14 167.99,136.14 167.36,136.77 UE1.53
KSO15: length 35.7
  TOP w0.102: JKB.10 164.77,108.8 165.89,108.8 v1(166.54,109.44) 168.7,109.44 v2(169.35,108.8)
  BOTTOM w0.102: v2(169.35,108.8) 168.08,110.07 168.08,124.42 168.08,128.25 168.67,128.85 168.67,135.13 167.76,136.04 167.76,136.05 167.39,136.42 166.68,136.42 166.63,136.37 UE1.54
KSO16: length 36.8
  TOP w0.102: v1(166.58,107.65) 166.25,107.98 JKB.11 163.94,107.98 162.99,108.94 v2(162.99,114.04)
  IN2 w0.127: v2(162.99,114.04) 163.02,114 166.43,114 167.06,114.64 167.06,118.83 166.43,119.46 163.69,119.46 162.62,119.46 161.42,120.66 161.42,125.15 160.92,125.65 160.92,128.34 160.09,129.17 v2(159.76,129.17)
  BOTTOM w0.102: v2(159.76,129.17) 158.39,129.17 157.76,129.79 UE1.81
LAN_CLKREQ#: length 4
  TOP w0.102: v2(120.9,107.47) v1(120.9,108.2) 120.9,109.98 120.42,110.46 RP63.1
  BOTTOM w0.102: v2(120.9,107.47) 121.24,107.81 USOC1.BG3
LCD_TEST: length 133.4
  TOP w0.102: v2(166.03,145.37) 166.05,145.37 166.05,138.9 163.61,136.46 v1(163.61,136.15) 163.61,135.75 v2(163.89,135.47)
  IN1 w0.127: v2(96.3,164.66) 97.59,165.95 97.59,174.47 v2(97.64,174.52)
  BOTTOM w0.102: v2(97.64,174.52) 97.68,174.56 106.14,174.56 107.69,176.11 133.72,176.11 134.89,177.27 146.93,177.27 147.44,176.77 148.1,176.11 150.81,176.11 151.95,174.96 165.19,174.96 171.74,168.42 171.74,168.36 171.74,167.42 171.74,167.42 171.74,151.89 166.02,146.18 166.02,145.37 v2(166.03,145.37) ; UE1.72 161.36,134.34 162.11,135.09 163.51,135.09 v2(163.89,135.47) ; JEDP.10 v2(96.3,164.66)
LG_3V: length 2.4
  IN1 w1.016: 34.61,41.41 34.6,41.42 34.6,42.12 35.81,43.33
  vias: v2(34.25,39.84) v2(34.6,40.47) v2(36.62,44.03) v2(37.14,44.53)
LG_5V: length 7.3
  TOP w0.102: v2(40.24,44.47) v1(40.24,43.89)
  IN1 w1.016: 40.51,43.71 40.49,43.7 40.49,37.05 40.51,37.04
  vias: v2(39.76,44.95) v2(42.28,37.61) v2(42.28,36.98)
LGATE1: length 8.8
  IN2 w1.016: 128.77,136.42 128.77,138.58 124.07,143.28
  vias: v2(124.06,145.14) v2(124.05,144.48) v2(128.01,135.09) v2(128.58,135.4)
LGATEG: length 5.7
  IN2 w1.016: 121.66,143.98 121.66,141.88 123.37,140.17 123.37,138.96
  vias: v2(121.68,144.86) v2(122.07,145.4) v2(123.06,137.94) v2(123.69,137.94)
LID_SW#: length 365
  TOP w0.102: v2(30.79,60.41) 30.79,70.51 v4(23.23,78.07) 22.57,78.72 16.63,78.72 15.26,80.09 R1.2 13.75,80.09 U70.3 ; D2401.1 114.69,164.29 v2(114.05,163.65) ; C3.2 169.55,169.81 168.8,169.81 168.15,169.15 JPWR.3 168.15,166.88 v2(167.82,166.56)
  IN1 w0.127: v2(168.26,152.51) 167.37,152.51 167.02,152.17 151,152.17 148.14,149.31 148.14,148.14 ; 148.14,148.14 148.14,144.86 147.38,144.1 147.38,141.44 148.77,140.04 v2(148.85,140.04) 150.01,138.88 150.01,131.19 148.91,130.1 148.91,125.42 154.08,120.25 157.95,120.25 159.7,118.51 159.7,114.22 162.83,111.09 162.83,103.26 160.39,100.82 158.94,100.82 158.1,99.97 158.1,91.52 163.47,86.15 163.47,83.37 162.2,82.1 162.2,69.14 161.85,68.79 161.85,66.56 161.62,66.33 149.83,66.33 147.5,64 v2(147.5,63.58) ; 148.14,148.14 148.13,148.15 145.69,148.15 145.37,148.47 138.73,148.47 136.1,145.85 131.44,145.85 131.06,146.23 131.06,149.37 131.59,149.91 131.59,154.12 129.43,156.28 115.6,156.28 114.48,157.4 114.48,163.22 v2(114.05,163.65)
  BOTTOM w0.102: v2(30.79,60.41) 36.76,60.41 38.16,59.01 39.48,59.01 40.86,60.4 45.82,60.4 47.46,62.03 52.89,62.03 67.27,62.03 69.05,63.81 79.63,63.81 79.74,63.7 82.31,63.7 84.05,61.96 88.32,61.96 88.85,61.43 101.3,61.43 102.8,59.93 134.97,59.93 135.22,59.93 138.98,63.69 147.4,63.69 v2(147.5,63.58) ; v2(168.26,152.51) 168.97,152.51 169.58,153.12 169.58,165.01 168.03,166.56 v2(167.82,166.56) ; v2(148.85,140.04) 149.31,139.57 UE1.115
LINE1-L: length 3.1
  BOTTOM w0.203: UA1.22 153.05,21.23
  BOTTOM w0.254: 153.05,21.23 153.41,21.59 154.34,21.59 CA67.1
LINE1-R: length 5.9
  BOTTOM w0.102: v1(155.06,25.23) 154.5,24.67 154.5,22.89 153.98,22.37 CA68.1
  BOTTOM w0.203: UA1.21 152.65,21.55 152.74,21.64
  BOTTOM w0.254: CA68.1 153.5,22.02 153.12,22.02 152.74,21.64
LINE1-VREFO-L: length 2.9
  BOTTOM w0.203: UA1.31 155.73,17.41 156.18,17.86 156.27,17.86 156.36,17.95
  BOTTOM w0.254: 156.36,17.95 156.77,18.37 RA165.1
LINE1-VREFO-R: length 7.6
  BOTTOM w0.102: v1(161.19,20.45) 161.16,20.42 161.15,20.42 160.51,19.78 157.71,19.78 157.21,19.27 RA166.1
  BOTTOM w0.203: UA1.30 155.23,17.81 155.24,17.83 155.67,17.83 156.09,18.25 156.1,18.25
  BOTTOM w0.254: RA166.1 157.12,19.26 156.1,18.25
LINE-IN-L: length 4.1
  TOP w0.254: RA83.1 RA80.2 v2(158.77,18.37)
  BOTTOM w0.254: RA83.1 RA80.2 v2(158.77,18.37) LA8.1
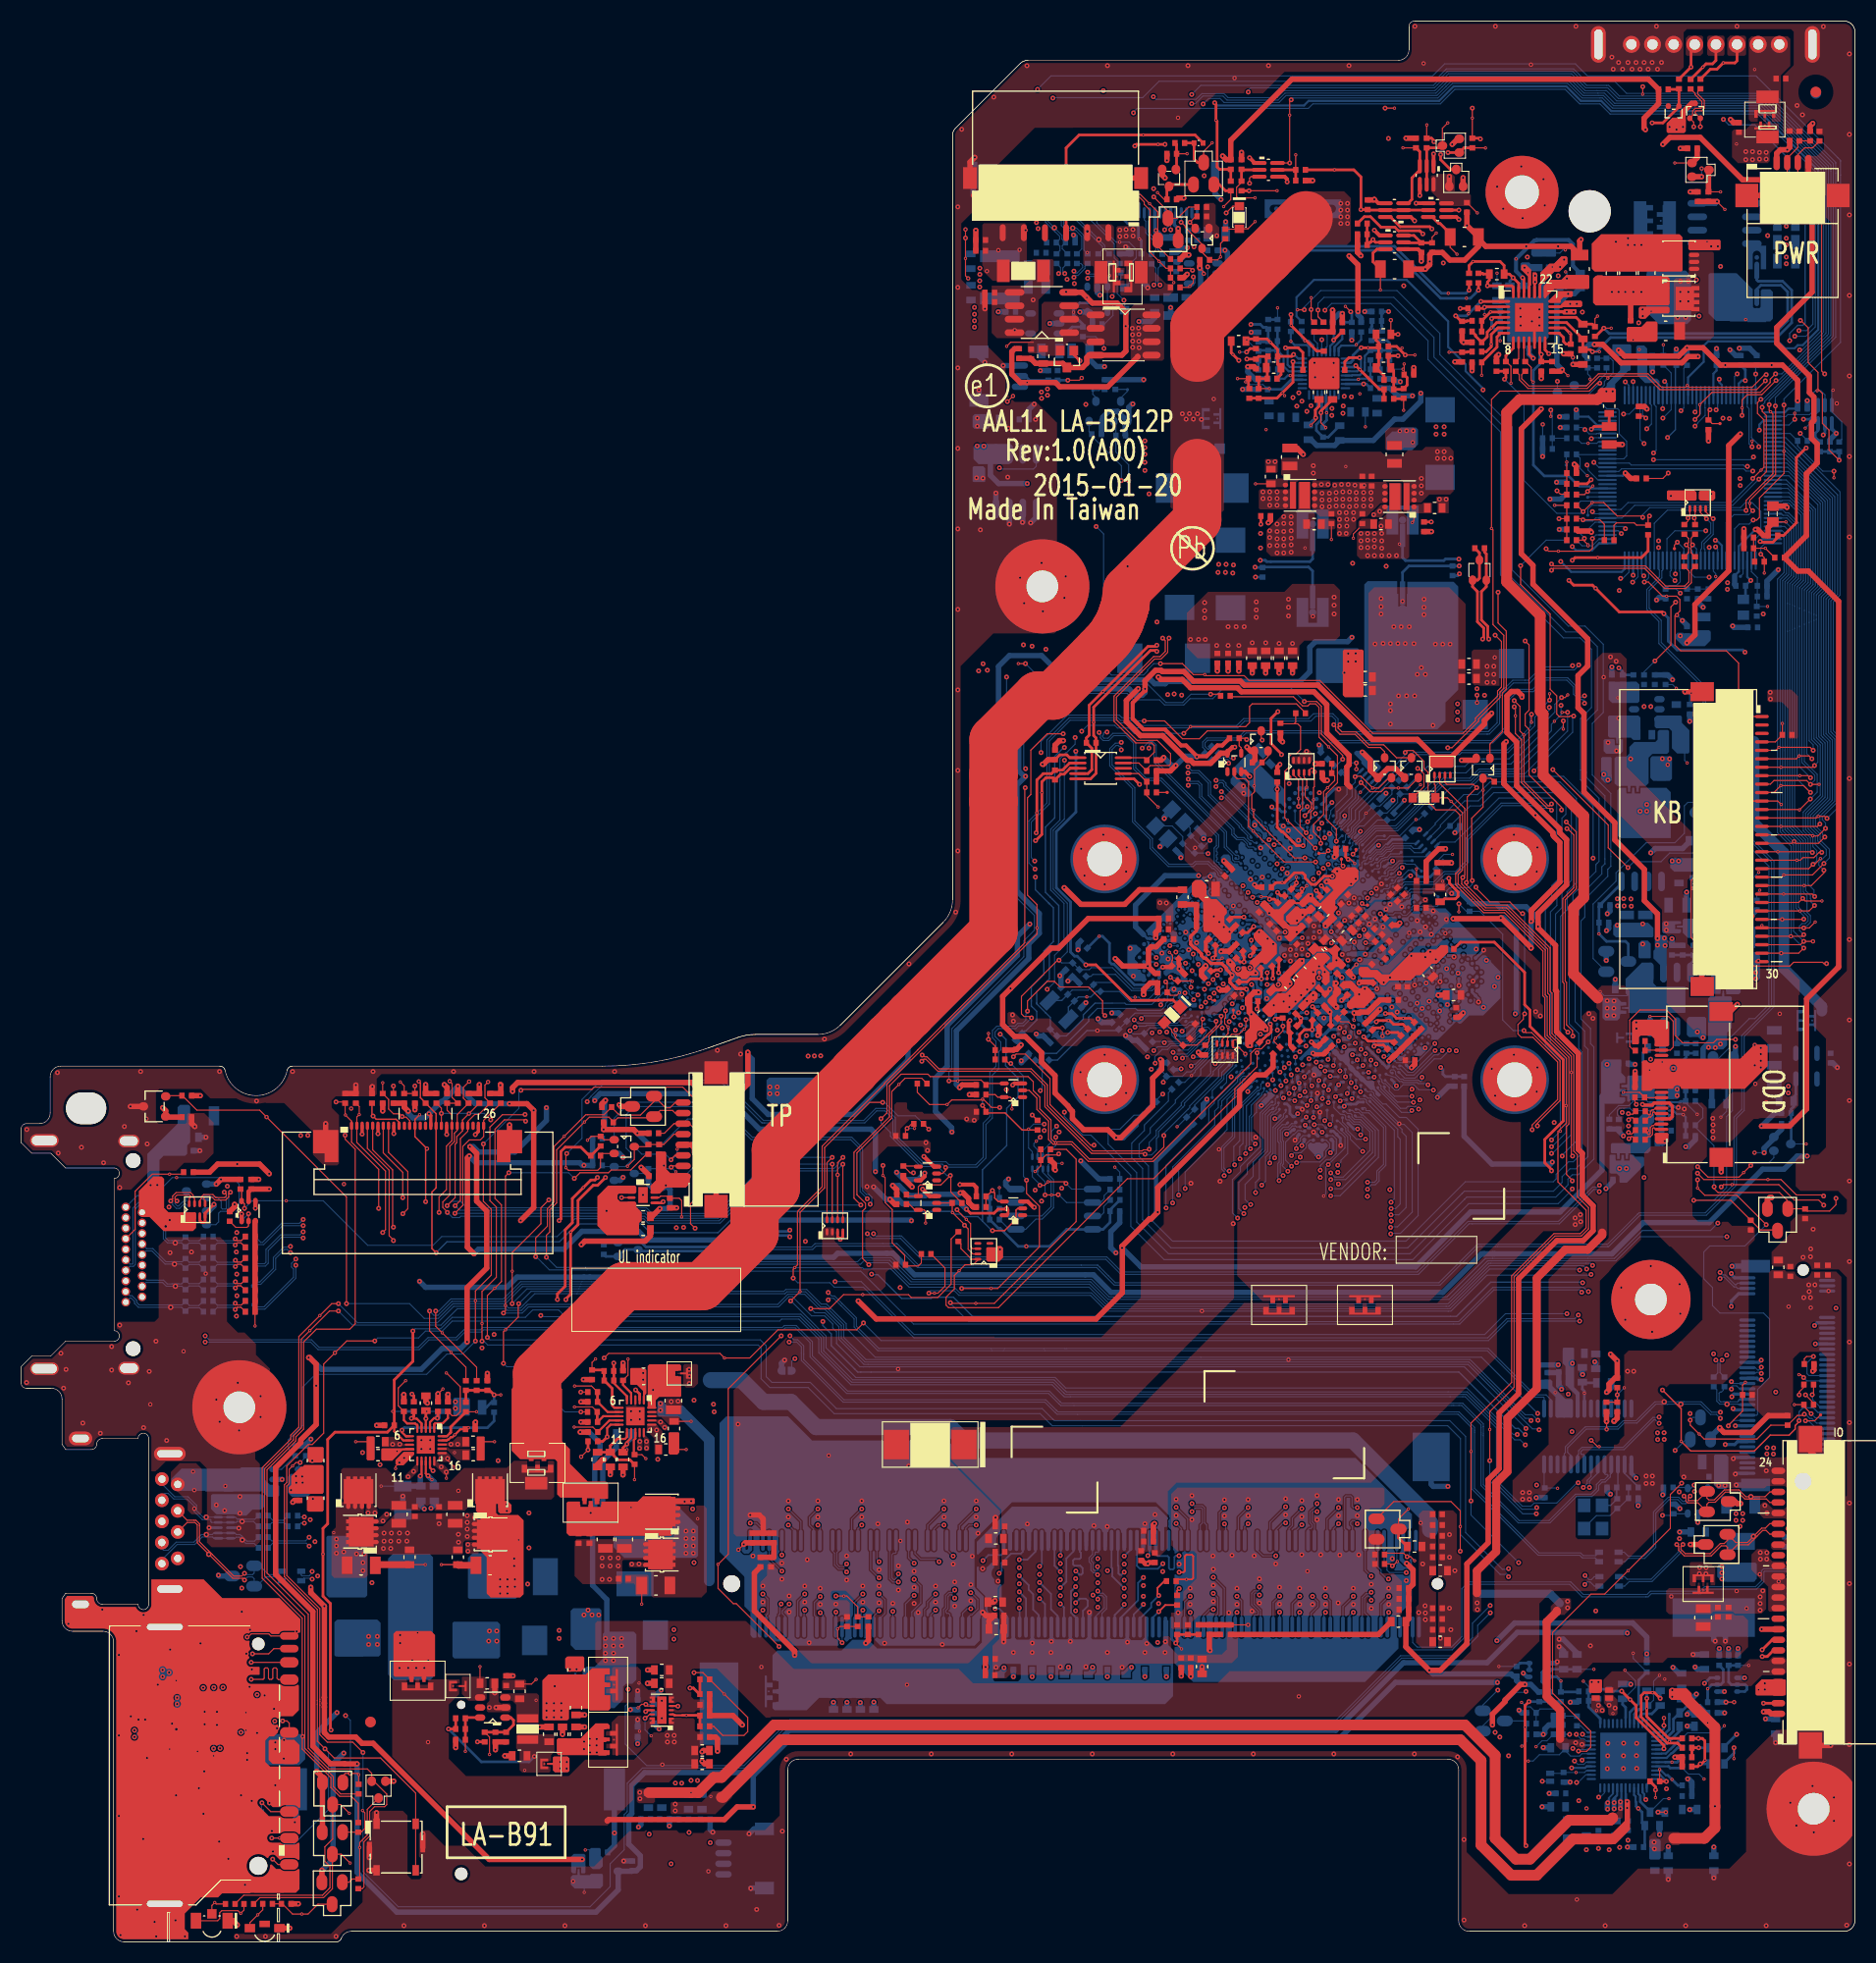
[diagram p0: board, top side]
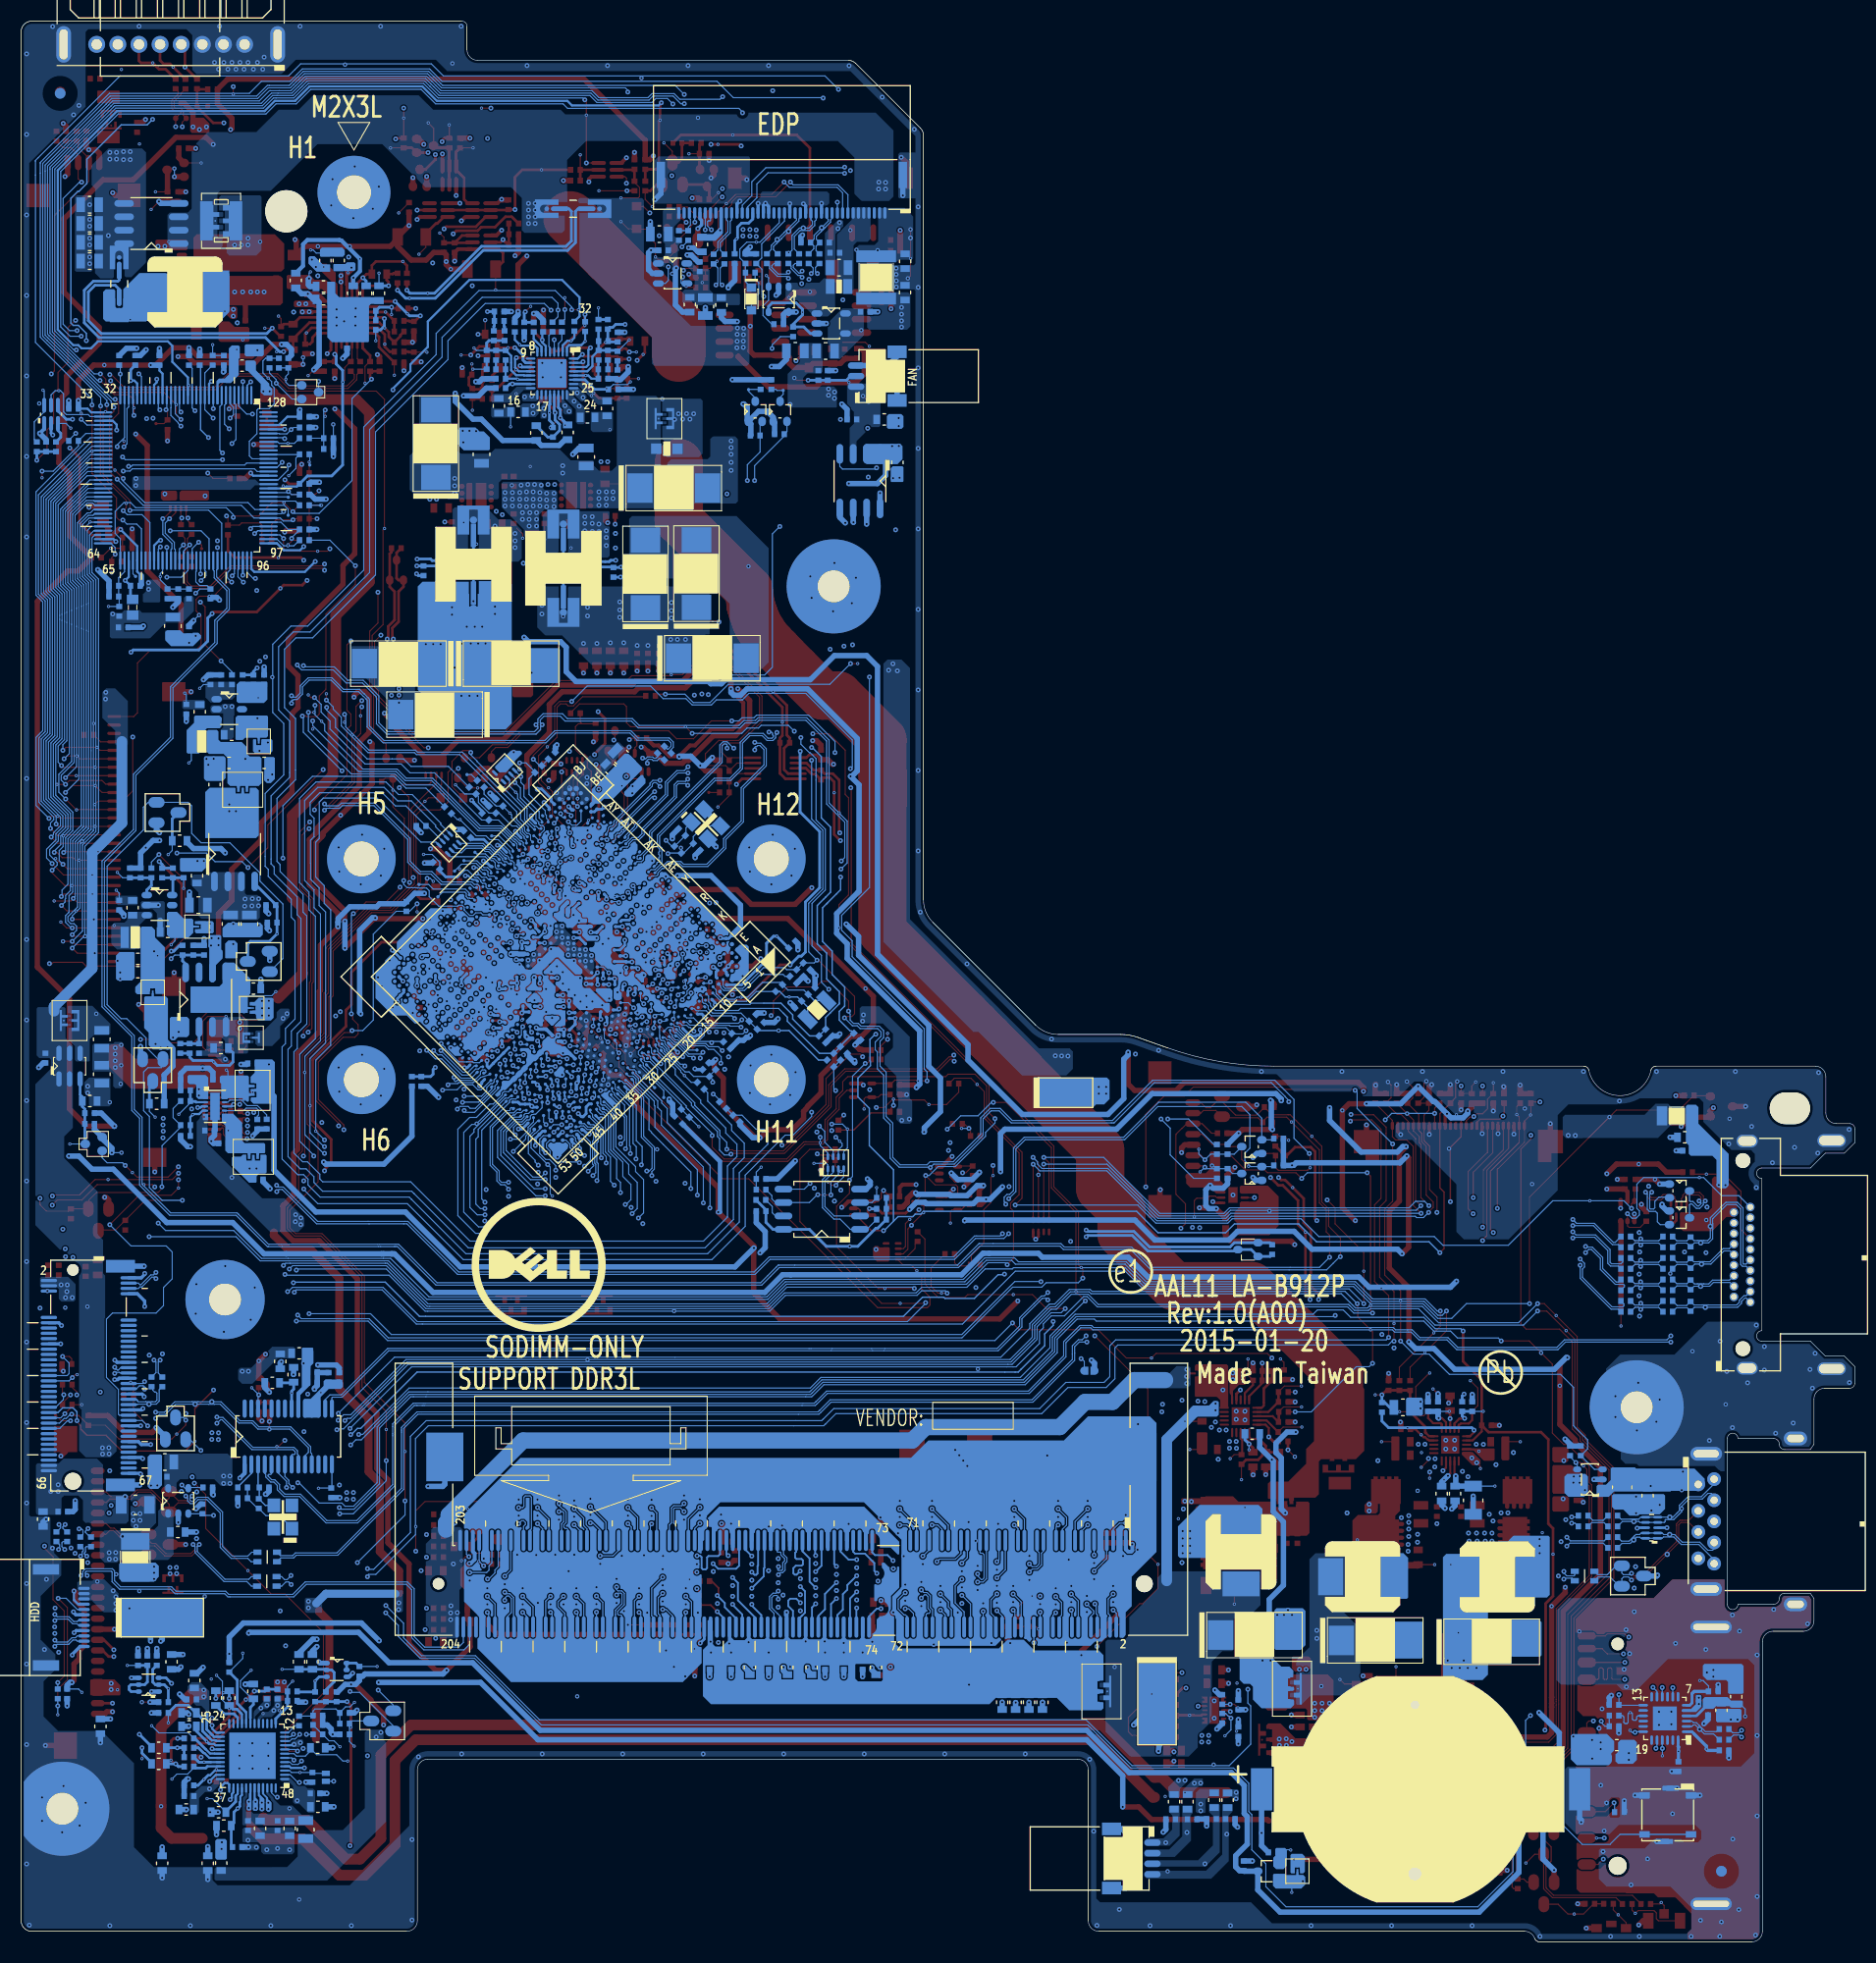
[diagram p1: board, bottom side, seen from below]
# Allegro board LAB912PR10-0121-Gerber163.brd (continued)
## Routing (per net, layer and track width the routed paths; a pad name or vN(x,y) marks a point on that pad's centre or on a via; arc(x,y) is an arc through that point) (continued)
LINE-IN-R: length 7.1
  TOP w0.254: RA84.1 158.67,16.59 v2(158.92,16.85) 159.02,16.85 v1(159.37,17.19) 159.35,17.2 159.35,19.02 159.11,19.26 v2(158.74,19.26) RA82.2
  BOTTOM w0.254: RA84.1 158.67,16.59 v2(158.92,16.85) LA9.1 ; RA82.2 v2(158.74,19.26)
LPC_AD0: length 60.2
  IN2 w0.127: v2(145.74,117.04) 145.28,117.5 145.28,117.65 144.89,118.04 144.89,123.58 148.79,127.48 148.79,130.91 150.74,132.86 150.74,133.26 153.16,135.68 153.16,140.48 155.89,143.21 155.89,144.6 v2(155.36,145.12)
  BOTTOM w0.102: USOC1.BH16 126.76,104.35 126.83,104.35 128.11,105.63 130.08,105.63 134.6,110.14 137.1,110.14 137.97,111.01 141.2,111.01 144.82,114.63 144.82,115.23 v1(145.12,115.53) 145.74,116.15 v2(145.74,117.04) ; UE1.10 v2(155.36,145.12)
LPC_AD1: length 61.4
  TOP w0.102: v2(146.36,116.38) v1(145.84,116.38)
  IN2 w0.127: v2(146.36,116.38) 146.34,116.4 146.34,119.81 145.9,120.24 145.9,123.01 150.02,127.12 150.02,130.55 153.35,133.88 154.49,133.88 155.03,134.42 155.03,140.64 154.74,140.93 v2(154.49,140.93)
  BOTTOM w0.102: USOC1.BJ17 128.27,105.17 130.27,105.17 134.61,109.51 137.12,109.51 138.16,110.55 142.3,110.55 146.36,114.61 v2(146.36,116.38) ; UE1.8 154.56,145.5 154.74,145.32 154.74,141.18 v2(154.49,140.93)
LPC_AD2: length 60.8
  TOP w0.102: v2(142.94,116.19) v1(142.94,115.44)
  IN2 w0.127: v2(142.94,116.19) 143.4,116.64 143.4,124.29 147.52,128.4 147.52,133.61 147.83,133.92 148.09,133.92 148.7,134.53 149.79,134.53 151.06,135.79 151.06,142.22 152.05,143.21 v2(153.85,143.21)
  BOTTOM w0.102: v2(142.94,116.19) 142.83,116.07 142.83,115 140.62,112.8 136.23,112.8 136.04,112.61 131.78,112.61 131.02,111.84 126.28,107.1 126.28,106.25 125.56,105.54 USOC1.BJ13 ; UE1.7 154.16,145.58 154.3,145.45 154.3,143.66 v2(153.85,143.21)
LPC_AD3: length 60
  TOP w0.102: v2(144.66,117.53) v1(144.66,118.13)
  IN2 w0.127: v2(144.66,117.53) 144.63,117.56 144.63,123.93 148.53,127.83 148.53,131.01 150.27,132.75 150.27,133.35 152.79,135.86 152.79,140.48 153.61,141.31 153.61,141.83 v2(153.6,141.82)
  BOTTOM w0.102: v2(153.6,141.82) 153.22,142.2 153.22,145.48 153.36,145.63 UE1.5 ; USOC1.BG14 125.34,104.3 125.34,104.76 125.48,104.9 125.64,104.9 125.89,105.15 125.89,105.47 126.64,106.22 126.64,106.96 132.06,112.38 136.14,112.38 136.33,112.57 140.72,112.57 143.25,115.1 143.25,115.91 144.01,116.67 144.01,116.89 v2(144.66,117.53)
LPC_CLK_0: length 9.7
  BOTTOM w0.102: v1(132.44,109.52) 131.57,108.65 RC51.2 130.27,108.42 130.27,107.85 129.27,106.84 CC25.1 128.31,106.84 127.09,105.62 126.66,105.62 126.3,105.26 126.3,104.98 125.94,104.62 125.94,104.47 125.72,104.25 USOC1.BG15
LPC_CLK_1: length 6.8
  BOTTOM w0.102: RC52.2 129.74,108.64 128.7,107.6 128.69,107.6 128.59,107.51 CC26.1 v1(127.29,106.84) 127.13,106.67 127.13,106.39 126.1,105.36 126.1,105.06 USOC1.BH14
LPC_CLK_EC: length 55.7
  IN2 w0.127: v2(144.63,116.85) 144.53,116.85 144.13,117.25 144.13,124.2 148.02,128.1 148.02,131.22 149.76,132.96 149.76,133.56 152.28,136.07 152.28,141.21 153.49,142.43 154.38,142.43 155.38,143.42 v2(155.38,144.23)
  BOTTOM w0.102: v2(155.38,144.23) 156.16,145.02 UE1.12 156.16,148.5 R2354.2 ; v2(144.63,116.85) 144.63,116.59 143.8,115.76 143.8,114.96 140.8,111.97 138.43,111.97 138.43,111.97 137.36,111.97 136.65,111.26 133.11,111.26 RC51.1
LPC_CLKRUN#: length 71.3
  TOP w0.102: v2(145.79,117.77) 146.12,117.77 v1(146.37,118.03)
  IN1 w0.127: v2(163.95,140.55) 166.93,140.55 168.38,141.99 v2(168.38,142.78)
  IN2 w0.127: v2(154.49,140.29) 154.53,140.25 154.53,134.64 154.28,134.39 153.14,134.39 149.4,130.65 149.4,127.26 145.4,123.26 145.4,118.37 145.79,117.98 v2(145.79,117.77)
  BOTTOM w0.102: v2(163.95,140.55) 163.7,140.29 v2(154.49,140.29) ; RX4.1 169.04,142.12 v2(168.38,142.78) ; USOC1.BG16 125.83,103.6 126.02,103.79 126.02,104.04 126.18,104.2 126.33,104.2 126.73,104.61 126.8,104.61 128.37,106.18 RC60.2 129.96,106.18 134.42,110.65 136.75,110.65 137.59,111.49 141,111.49 144.32,114.8 144.32,115.57 145.15,116.4 145.15,117.14 v2(145.79,117.77)
LPC_FRAME#: length 66
  TOP w0.102: v2(145.95,115.57) v1(145.95,114.79)
  IN2 w0.127: v2(145.95,115.57) 145.8,115.72 142.32,115.72 142.09,115.95 142.09,117.05 142.98,117.94 142.98,124.49 147.26,128.77 147.26,133.5 147.26,133.71 147.73,134.18 147.99,134.18 148.59,134.78 149.69,134.78 150.55,135.64 150.55,143.51 v2(151.66,144.61)
  BOTTOM w0.102: v2(145.95,115.57) 145.95,115.12 141.61,110.78 138.06,110.78 137.2,109.91 134.69,109.91 130.18,105.4 128.17,105.4 126.91,104.15 126.85,104.15 126.63,103.92 126.63,103.53 USOC1.BG17 ; v2(151.66,144.61) 152.2,144.61 152.96,145.37 UE1.4
LPC_RCOMP: length 2.4
  TOP w0.102: v1(126.22,102.07) 125.81,102.47 v2(125.59,102.47)
  TOP w0.254: v2(125.59,102.47) 125.36,102.7 RC50.2
  BOTTOM w0.254: v2(125.59,102.47) 125.74,102.32 USOC1.BF18
LX_1.0VALWP: length 2.1
  BOTTOM w0.102: PL301.1 157.44,111.82 v1(157.68,111.59)
LX_1.05VSP:
  vias: v1(164.75,96.2)
LX_3V: length 10.1
  IN2 w1.016: 34.14,46.68 31.62,44.15 31.62,37.66
  vias: v1(29.58,38.73) v2(29.84,38.12) v2(29.84,37.49) v2(29.84,36.79) v2(30.54,36.91) v2(31.74,36.72) v2(32.35,35.9) v2(32.35,35.14) v2(32.44,36.72) v2(35.16,47.09) v2(35.83,47.1)
LX_5V: length 11.2
  IN2 w1.016: 46.92,37.42 46.92,42.34 42.45,46.81
  vias: v1(47.08,38.04) v2(40.68,47.1) v2(41.32,47.1) v2(45.33,34.31) v2(45.33,33.61) v2(45.33,32.98) v2(46.03,34.31) v2(46.03,33.61) v2(46.03,32.98) v2(46.67,36.28) v2(46.67,35.58) v2(46.73,34.31) v2(46.73,33.61)
LX_+1.8VSP:
  vias: v1(48.74,22.87)
LX_CHG: length 10.1
  IN2 w0.762: 156.39,157.95 151.44,157.95 150.68,158.71 146.61,158.71
  vias: v1(144.91,158.53) v2(145.65,158.53) v2(146.03,159.23) v2(156.77,153.75) v2(157.03,157.18) v2(157.03,156.17) v2(157.03,155.28) v2(157.54,153.75) v2(157.79,157.18) v2(157.79,156.17) v2(157.79,155.28)
M_ODT0: length 5.6
  TOP w0.165: RD8.1 108.2,34.15 107.55,33.5 107.55,32.9 v2(107.67,32.78)
  BOTTOM w0.165: JDIMM2.116 105.9,30.62 106.95,31.68 106.95,32.07 v2(107.67,32.78)
M_ODT1: length 3.7
  TOP w0.165: RD9.1 108.29,31.88 v2(107.67,31.26)
  BOTTOM w0.165: JDIMM2.120 107.1,30.69 v2(107.67,31.26)
MAINPWON: length 1
  TOP w0.102: R2450.2 T217.1
MIC1-L: length 6.2
  BOTTOM w0.102: v1(151.78,25.71) 152.79,24.71 152.79,24.11 151.68,23.01 CA74.1
  BOTTOM w0.203: UA1.19 151.85,21.2
  BOTTOM w0.254: 151.85,21.2 151.85,22.19 151.57,22.47 CA74.1
MIC_CLK: length 301
  TOP w0.102: v2(47.69,78.32) 47.67,78.29 45.54,78.29 44.37,77.12 44.37,76.52 44.37,70.16 44.98,69.55 44.98,62.91 43.62,61.55 v1(43.62,58.53) v2(43.62,56.85)
  IN1 w0.127: v2(47.69,78.32) 48,78.32 48.25,78.06 55.22,78.06 55.64,78.48 57.52,78.48 57.86,78.82 60.56,78.82 61.41,79.67 73.16,79.67 76.59,83.1 76.59,83.18 76.59,83.18 76.59,83.56 89.48,96.46 89.48,117.25 92.61,120.39 92.61,129.64 97.88,134.91 97.88,155.09 95.14,157.83 95.14,165.43 96.08,166.37 96.08,167.22 95.88,167.42 95.64,167.42 v2(95.61,167.39)
  IN2 w0.127: v2(140.77,34.56) 140.79,34.59 140.84,34.54 140.84,29.57 141.18,29.22 141.18,23.5 140.84,23.15 140.84,20.65 141.71,19.77 141.71,17.51 143.05,16.17 144.99,16.17 145.33,15.83 145.33,15.6 144.93,15.2 v2(143.97,15.2)
  BOTTOM w0.102: v2(140.77,34.56) 140.77,34.68 140.67,34.78 139.99,34.78 136.23,38.54 136.23,47.64 135.01,48.85 100.44,48.85 97.59,48.85 97.45,48.99 97.44,48.99 96.44,50 76.96,50 74.48,52.47 70.86,52.47 70.03,53.3 70.03,56.22 69.75,56.5 44.15,56.5 43.78,56.87 43.63,56.87 v2(43.62,56.85) ; LA1.2 v2(143.97,15.2) ; JEDP.27 104.8,164.2 103.92,165.08 103.92,166.39 102.86,167.44 95.66,167.44 v2(95.61,167.39)
MIC_CLK_C: length 4
  BOTTOM w0.102: LA1.1 145.9,15.95 CA22.1 v1(147.16,16.04) 147.96,16.04 148.14,16.21 UA1.3
MIC_DATA: length 303.4
  TOP w0.102: v2(44.13,57.21) 44.13,61.17 v1(44.82,61.86) 45.46,62.5 45.46,69.75 44.85,70.36 44.85,76.72 44.85,76.72 44.85,76.92 45.74,77.81 47.62,77.81 v2(47.75,77.68)
  IN1 w0.127: v2(95.61,167.98) 96.04,167.98 96.59,167.43 96.59,166.16 95.65,165.22 95.65,158.04 98.39,155.3 98.39,134.7 93.12,129.43 93.12,120.18 89.99,117.04 89.99,96.25 77.1,83.35 77.1,82.97 77.09,82.97 77.09,82.89 73.37,79.17 61.62,79.17 60.77,78.32 58.07,78.32 57.73,77.97 55.85,77.97 55.43,77.55 47.87,77.55 v2(47.75,77.68)
  IN2 w0.127: v2(140.77,35.33) 141.34,34.76 141.34,29.78 141.69,29.43 141.69,23.29 141.34,22.94 141.34,20.86 142.22,19.98 142.22,17.72 143.26,16.68 145.2,16.68 145.84,16.04 145.84,15.79 146.09,15.54 146.78,15.54 147.02,15.29 147.02,15.28 v2(147.21,15.09)
  BOTTOM w0.102: v2(95.61,167.98) 95.66,167.93 103.06,167.93 104.4,166.59 104.4,165.28 105.3,164.38 JEDP.28 ; v2(44.13,57.21) 44.35,56.98 69.95,56.98 70.52,56.42 70.52,53.5 71.06,52.95 74.28,52.95 74.28,52.95 74.68,52.95 77.16,50.48 96.64,50.48 97.64,49.47 97.65,49.47 97.79,49.33 100.24,49.33 135.21,49.33 136.71,47.84 136.71,38.74 140.19,35.26 140.71,35.26 v2(140.77,35.33) ; UA1.2 148.08,15.81 147.36,15.09 v2(147.21,15.09)
MIC_GND: length 5
  BOTTOM w0.254: RX20.1 106.01,161.02 v1(105.85,161.18) 105.75,161.29 105.75,162.3 105.37,162.68 104.69,162.68 104.3,163.07 JEDP.26
MMC1_RCOMP: length 7.8
  TOP w0.254: v2(124.09,100.87) 123.31,100.87 122.86,100.42 122.54,100.1 122.13,100.1 121.53,100.7 121.53,100.94 121.28,101.19 120.52,101.19 119.59,100.26 v1(119.35,100.26) 118.76,100.26 RC57.1
  BOTTOM w0.254: v2(124.09,100.87) 124.12,100.84 USOC1.AY18
MS_CLK_SD_WP: length 11.8
  TOP w0.102: JREAD.11 23.64,28.95 23.44,29.15 21.79,29.15 21.48,28.85 v2(21.39,28.85)
  IN2 w0.127: v2(21.39,28.85) 21.08,28.85 17.23,25.01 v2(17.23,24.06)
  BOTTOM w0.102: UR1.8 v2(17.23,24.06)
MS_D1_SD_D3: length 13.7
  TOP w0.102: JREAD.1 v2(23.72,9.82)
  IN2 w0.127: v2(18.83,18.32) 18.83,18.26 18.85,18.23 18.85,14.69 v2(23.72,9.82)
  BOTTOM w0.102: UR1.20 18.73,18.42 v2(18.83,18.32) ; v2(23.72,9.82) v1(24.45,9.82)
MS_D2_SD_CLK: length 8.1
  TOP w0.102: JREAD.5 25.38,20.7 25.16,20.91 v2(24.75,20.91)
  IN2 w0.127: v2(24,20.89) 24,20.6 23.79,20.39 23.79,20.04 24.48,19.35 25.11,19.35 25.42,19.65 25.42,20.24 v2(24.75,20.91)
  BOTTOM w0.102: v2(24,20.89) 24,20.76 23.65,20.4 CR6.1 RR2.2
MS_D2_SD_CLK_R: length 4.7
  BOTTOM w0.102: UR1.15 20.55,21.4 20.65,21.29 20.65,21.08 20.75,20.98 20.95,20.98 21.05,21.08 21.05,21.6 21.16,21.7 v1(21.28,21.7) 21.36,21.7 21.46,21.6 21.46,20.77 21.56,20.67 21.77,20.67 21.87,20.77 21.87,21.29 21.99,21.42 RR2.1
NGFF_BT_ON#: length 3.7
  TOP w0.102: v2(169.41,50) 168.73,50.68 RM9.1 v1(167.81,50.85)
  BOTTOM w0.102: JNGFF.46 169.81,49.6 v2(169.41,50)
NTC: length 2.2
  BOTTOM w0.203: PU500.7 124.3,150.97 125.04,151.72 PR523.1
NTC_1: length 30.5
  TOP w0.102: v2(125.83,154.29) v1(125.33,154.8)
  TOP w0.254: v2(133.46,134.4) PH502.2
  IN2 w0.254: v2(133.46,134.4) 133.64,134.58 134.55,134.58 136.45,136.48 136.45,144.48 132.44,148.5 130.54,148.5 125.83,153.2 v2(125.83,154.29)
  BOTTOM w0.254: v2(125.83,154.29) 125.93,154.19 PR529.1 125.93,153.29 PR523.2
NTCG: length 3.3
  BOTTOM w0.203: PR515.2 v1(120.17,151.5) 120.53,151.14 121.69,151.14 121.9,150.93 PU500.1
NTCG_1: length 29.3
  TOP w0.254: v2(117.33,134.18) PH501.2 ; v2(120.18,154.03) 120.2,154.01 v1(120.2,152.99) 122.62,150.57 PR514.2
  IN2 w0.254: v2(120.18,154.03) 118.67,152.52 118.67,148.17 115.5,144.99 115.5,138.39 116.64,137.24 116.64,134.58 117.04,134.18 v2(117.33,134.18)
  BOTTOM w0.203: PR515.1 120.18,153.36 v2(120.18,154.03)
ODD_DA#: length 90.3
  TOP w0.102: v2(146.81,72.03) 146.81,72.09 146.26,72.64 146.26,77.19 146.49,77.42 146.49,83.73 144.43,85.78 144.43,89.46 144.25,89.64 144.25,93.87 140.48,97.65 140.29,97.65 138.5,97.65 136,100.15 136,101.03 136.4,101.44 136.4,106.88 v1(135.33,107.95) 134.99,108.29 DX2.1 133.84,109.47 133.75,109.56 RP54.1 ; v2(162.25,85.42) 160.48,85.42 160.17,85.1 157.24,85.1 156.58,85.76 156.58,87.33 155.71,88.21 153.21,88.21 152.24,87.24 152.24,84.75 152.63,84.36 RS10.1
  IN1 w0.127: v2(162.25,85.42) 161.83,85 161.83,83.17 161.17,82.5 161.17,73.92 159.38,72.13 159.38,71.85 158.95,71.42 151.12,71.42 150,72.54 147.31,72.54 v2(146.81,72.03)
ODD_DETECT#: length 51.6
  TOP w0.102: v2(136.07,98.26) v1(136.07,97.49) ; RS09.1 152.74,79.4 v2(152.86,79.27) ; v2(142.23,86.25) 142.42,86.06 142.96,86.06 145.65,83.38 145.65,79.63 143.5,77.49 v2(143.5,77.24)
  IN1 w0.127: v2(152.86,79.27) 151.64,79.27 149.38,77.01 143.73,77.01 v2(143.5,77.24)
  IN2 w0.102: 133.72,99.72 133.34,99.72 132.9,99.27 130.01,99.27 127.73,96.99 127.5,96.99 127.09,96.57 v2(127.09,95.81)
  IN2 w0.127: 133.72,99.72 134.11,99.72 135.06,98.76 135.57,98.76 v2(136.07,98.26)
  BOTTOM w0.102: v2(142.23,86.25) 141.22,86.25 140.22,87.25 140.22,95.38 138.06,97.54 RC68.2 136.79,97.54 v2(136.07,98.26) ; USOC1.AU28 126.53,95.89 127.01,95.89 v2(127.09,95.81)
ODD_EN: length 7.8
  BOTTOM w0.102: v1(168.94,75.52) QS3.1
  BOTTOM w0.254: QS2.3 167.97,80.17 167.76,79.97 CS16.1 167.76,79.07 167.52,78.82 RS6.1 RS9.2 167.52,75.56 QS3.1
ODD_EN#: length 68.9
  TOP w0.102: v2(163.7,73.49) v1(163.02,72.82) 162.59,72.39 159.65,72.39 v2(158.67,73.36) ; v2(143.01,76.87) 143.01,77.32 143.42,77.73 145.42,79.73 145.42,83.28 143.09,85.62 141.98,85.62 141.66,85.94 141.66,86.83 142.17,87.33 142.17,87.71 v2(142.3,87.84) ; v2(142.11,97.33) 141.99,97.33 140.89,98.43 139.01,98.43 137.69,99.75 v2(137.69,99.83)
  IN1 w0.127: v2(143.01,76.87) 143.47,76.41 145.85,76.41 148.33,73.93 156.08,73.93 156.89,73.12 158.43,73.12 v2(158.67,73.36)
  IN2 w0.102: 132.87,101.65 131.74,100.53 131.34,100.53 131.33,100.54 129.72,100.54 128.45,99.27 v2(127.8,99.27)
  IN2 w0.127: 132.87,101.65 132.9,101.68 135.12,101.68 135.16,101.64 137.15,101.64 137.8,101 137.8,99.94 v2(137.69,99.83)
  BOTTOM w0.102: v2(142.3,87.84) 142.3,97.14 v2(142.11,97.33) ; QS3.2 165.88,74.21 165.41,73.74 163.95,73.74 v2(163.7,73.49) ; v2(127.8,99.27) 128,99.07 USOC1.BD26
ON/OFFBTN#: length 382.8
  TOP w0.102: v2(33.47,56.88) 30.82,56.88 v4(29.69,55.75) 28.63,54.69 28.63,48.15 27.55,47.07 27.17,47.07 25.14,45.04 25.14,43.48 24.91,43.25 24.91,34.58 28.04,31.45 28.04,22.86 28.04,18.99 v2(28.76,18.27) 29.62,17.41 34.02,17.41 37.34,14.08 SW2.3 SW2.4 ; RE49.1 CE20.1 168.15,170.32 168.15,169.83 167.15,168.83 JPWR.2 167.15,166.65 170.4,163.39 170.4,148.7 v2(170.69,148.41)
  IN1 w0.127: v2(143.44,41.11) 144.77,41.11 146.11,42.44 149.46,42.44 151.82,44.8 154.16,44.8 156.29,46.93 160.51,46.93 161.09,47.52 162.36,47.52 163.44,48.6 163.44,54.41 164.55,55.52 165.75,55.52 172.19,61.96 172.19,71.32 171.47,72.05 171.47,82.93 172.18,83.65 172.18,100.25 171.89,100.54 171.89,107.25 170.94,108.2 170.94,118.66 164.2,125.39 164.05,125.39 163.12,126.32 163.12,130.26 162.49,130.89 162.49,136.23 163.47,137.21 163.47,138.79 v2(163.89,139.21) 163.89,139.89 163.44,140.34 163.44,140.76 163.77,141.09 165.44,141.09 167.32,142.96 167.32,146.01 167.7,146.39 168.46,146.39 170.48,148.41 v2(170.69,148.41)
  BOTTOM w0.102: SW1.3 SW1.4 22.23,10.17 23.17,9.23 25.8,9.23 29.09,12.52 29.09,17.94 v2(28.76,18.27) ; v2(163.89,139.21) 163.25,139.21 163.03,139.43 151.47,139.43 151.21,139.17 UE1.114 ; v2(143.44,41.11) 143.29,40.95 142.04,40.95 139.63,43.37 139.63,48.65 136.68,51.6 136.43,51.6 99.3,51.6 99.3,51.6 98.73,51.6 98.59,51.73 98.58,51.73 97.58,52.74 78.52,52.74 75.49,55.76 75.49,57.06 73.6,58.95 71.98,58.95 71.79,58.76 40.8,58.76 39.85,57.81 38.26,57.81 37.61,57.16 33.75,57.16 v2(33.47,56.88)
P2: length 2.7
  TOP w0.102: v1(93.27,151.02) 93.66,151.4 95.8,151.4
P3: length 16.6
  TOP w0.508: PC701.2 94.04,150.79 93.76,150.52 93.76,148.39 94.56,147.59 v1(95.21,147.59) 97.9,147.59 98.3,147.19 102.84,147.19 105.7,150.05 105.67,150.07
  vias: v2(105.16,152.73) v2(105.19,152.12) v2(105.2,151.51) v2(105.2,150.92) v2(105.76,152.75) v2(105.78,152.15) v2(105.78,151.49) v2(105.81,150.88)
PANEL_BKLEN: length 206
  TOP w0.102: v2(74.73,59.94) 76.51,59.94 77.83,61.26 v1(79.65,61.26) 83.98,61.26 84.24,60.99 86.75,60.99 88.02,62.26 88.02,66.53 R28.1
  IN1 w0.127: v2(143.67,48.47) 143.9,48.7 144.03,48.7 145.91,50.58 147.9,50.58 149.98,52.66 153.64,52.66 165.22,64.24 165.22,66.57 166.81,68.16 166.81,72.39 167.1,72.68 167.1,75.24 167.1,75.24 167.1,75.87 167.1,76.95 166.81,77.24 166.81,81.45 167.05,81.69 167.05,82.75 167.05,86 167.66,86.61 167.66,92.15 167.66,100.81 165.88,102.59 165.88,113.29 163.95,115.22 163.95,118.63 158.29,124.29 155.95,124.29 153.85,126.39 153.85,127.85 154.11,128.1 154.11,131.7 154.62,132.21 154.62,132.25 v2(154.97,132.61)
  IN2 w0.127: v2(154.97,132.61) 155.7,132.61 156.73,131.57 159.35,131.57 v2(159.76,131.99)
  BOTTOM w0.102: UE1.76 v2(159.76,131.99) ; v2(143.67,48.47) 143.58,48.56 143.03,48.56 136.94,54.66 80.15,54.66 79.77,54.66 77.4,57.03 77.4,58.22 76.08,59.55 75.13,59.55 v2(74.73,59.94)
PBTN_OUT#: length 197.6
  TOP w0.102: v2(80.23,64.1) 79.64,64.69 79.64,69.17 79.91,69.45 79.91,69.91 79.1,70.72 79.1,74.68 82.27,77.85 82.4,77.99 82.4,80.49 v1(83.08,81.16) 83.66,81.75 85.22,81.75 R27.2
  IN1 w0.127: v2(148.61,142.29) 148.61,142.11 150.51,140.2 150.51,130.98 149.43,129.9 149.43,125.62 153.39,121.66 154.91,121.66 155.81,120.76 158.17,120.76 160.2,118.72 160.2,114.43 163.34,111.3 163.34,101.54 165.12,99.76 165.12,94.25 165.12,88.08 163.98,86.93 163.98,83.14 162.77,81.94 162.77,68.97 162.36,68.57 162.36,66.34 161.83,65.81 150.5,65.81 v2(148.72,64.03)
  BOTTOM w0.102: UE1.122 148.69,142.37 v2(148.61,142.29) ; v2(148.72,64.03) 148.52,64.23 148.09,64.23 139.07,64.23 138.88,64.23 135.03,60.38 134.78,60.38 102.99,60.38 101.12,62.25 84.08,62.25 82.05,64.28 80.41,64.28 v2(80.23,64.1)
PC_BEEP: length 4.6
  BOTTOM w0.102: DA8.1 142.47,20.91 RA79.2 RA19.1 142.47,18.97 v1(142.03,18.52)
PCH_USB3_RX0_N: length 132
  IN2 w0.127: v2(107.43,93.16) 104.54,93.16 103.1,94.6 96.69,94.6 90.61,88.52 90.61,88 88.62,86.01 88.62,83.28 84.54,79.21 83.94,79.21 82.19,77.45 80.1,77.45 78.43,75.78 76.83,75.78 75.75,74.69 75.75,62.42 73.57,60.24 65.1,60.24 61.94,63.4 51.82,63.4 51.25,63.4 51.24,63.4 50.4,63.4 50.4,63.4 43.11,63.4 40.95,61.23 35.06,61.23 28.19,54.36 28.19,39.51 27.73,39.05 26.77,39.05 26.29,38.57 26.29,37.81 26.64,37.46 v2(27.26,37.46)
  BOTTOM w0.102: v2(107.43,93.16) 107.09,93.51 USOC1.E3 ; v2(27.26,37.46) 26.98,37.74 23.82,37.74 R2367.2
PCH_USB3_RX0_P: length 132
  IN2 w0.127: v2(107.43,92.52) 107.43,92.68 107.34,92.77 107.27,92.77 107.13,92.91 104.43,92.91 103,94.34 96.79,94.34 90.86,88.41 90.86,87.89 88.87,85.91 88.87,83.18 84.65,78.95 84.05,78.95 82.29,77.2 80.21,77.2 78.53,75.52 76.93,75.52 76,74.59 76,62.31 73.68,59.99 64.99,59.99 61.83,63.14 51.72,63.14 51.14,63.14 43.22,63.14 41.06,60.98 35.17,60.98 28.44,54.25 28.44,39.41 27.83,38.79 26.88,38.79 26.55,38.46 26.55,37.91 26.74,37.72 26.92,37.72 27.09,37.88 27.26,37.88 27.36,37.98 27.36,38.2 v2(27.26,38.3)
  BOTTOM w0.102: R2366.2 23.73,37.96 26.92,37.96 v2(27.26,38.3) ; v2(107.43,92.52) 107.2,92.76 USOC1.D4
PCH_USB3_TX0_N: length 130.7
  IN2 w0.102: 105.02,95.28 105.9,94.4 107.58,94.4 108.52,95.34 109.02,95.34 109.65,94.71 109.65,94.28 109.29,93.92 v2(109.29,93.69)
  IN2 w0.127: v2(26.8,39.63) 26.68,39.63 26.22,40.09 26.22,40.98 26.91,41.68 26.91,41.91 26.91,42.24 27.28,42.61 27.28,44.61 26.85,45.04 26.85,46.73 26.74,46.84 26.74,54.05 34.68,62 40.63,62 42.8,64.16 45.1,64.16 45.95,64.16 45.95,64.16 50.08,64.16 52.14,64.16 62.26,64.16 64.74,61.68 73.65,61.68 74.98,63.02 74.98,75.07 76.45,76.54 78.06,76.54 80.54,79.01 81.91,79.01 84.23,81.34 85.55,81.34 87.85,83.64 87.85,86.87 88.18,87.2 88.18,87.2 89.89,88.91 97.05,96.07 104.22,96.07 105.02,95.28
  BOTTOM w0.102: v2(26.8,39.63) 26.47,39.63 CI3.2 ; v2(109.29,93.69) 109.37,93.77 USOC1.K7
PCH_USB3_TX0_N_C: length 2.2
  BOTTOM w0.102: CI3.1 24.9,39.68 23.73,39.68 R2369.2
PCH_USB3_TX0_P: length 130.5
  IN2 w0.102: 104.8,95.06 105.69,94.17 107.67,94.17 108.62,95.11 108.92,95.11 109.41,94.62 109.41,94.38 108.71,93.67 108.53,93.67 108.29,93.91 108.29,94.09 108.49,94.29 v2(108.72,94.29)
  IN2 w0.127: v2(26.8,40.22) 26.47,40.55 26.47,40.88 27.17,41.57 27.17,41.8 27.17,41.8 27.17,42.13 27.54,42.5 27.54,44.71 27.11,45.14 27.11,46.83 26.99,46.95 26.99,53.94 34.79,61.74 40.74,61.74 42.9,63.91 45.21,63.91 45.21,63.91 45.84,63.91 45.84,63.91 50.19,63.91 50.19,63.91 51.46,63.91 51.46,63.91 52.03,63.91 62.15,63.91 64.63,61.43 73.75,61.43 75.24,62.91 75.24,74.97 76.56,76.28 78.17,76.28 80.64,78.76 82.01,78.76 84.34,81.08 85.66,81.08 88.11,83.53 88.11,86.76 88.36,87.01 88.36,87.02 90.15,88.8 97.16,95.81 104.04,95.81 104.8,95.06
  BOTTOM w0.102: v2(26.8,40.22) 26.3,40.22 CI4.2 ; USOC1.K6 108.74,94.27 v2(108.72,94.29)
PCH_USB3_TX0_P_C: length 2.2
  BOTTOM w0.102: R2368.2 23.82,39.9 24.81,39.9 CI4.1
PCIE_CLKREQ_2#: length 5.5
  TOP w0.102: v2(121.49,106.6) 121.86,106.96 121.86,107.04 122.11,107.29 122.11,107.42 122.11,107.42 122.11,107.8 121.53,108.39 121.53,109.14 v1(121.67,109.29) 121.67,109.99 121.42,110.25 RP63.3
  BOTTOM w0.102: v2(121.49,106.6) 121.5,106.6 121.5,106.66 121.68,106.84 121.84,106.84 USOC1.BG5
PCIE_PRX_DTX_N1: length 118.1
  IN2 w0.102: v2(118.87,102.04) 119.03,101.88 119.03,101.78 118.99,101.74 118.99,101.53 118.86,101.4 118.55,101.4 118.26,101.7 118.26,102.38 118.54,102.66 119.11,102.66 119.68,103.24 119.68,103.67 120.57,104.56 120.57,105.6 119.92,106.25 119.92,107.85 121.09,109.01 122.53,109.01 122.68,109.16
  IN2 w0.127: v2(161.87,52.32) 161.87,52.54 161.79,52.61 161.69,52.61 161.53,52.77 160.26,52.77 159.5,53.53 159.5,53.74 159.5,55.94 163.39,59.83 163.39,66.78 162.21,67.96 162.21,74.06 162.81,74.66 162.81,81.35 163.68,82.22 163.68,85.86 165.03,87.21 165.03,99.53 162.61,101.94 162.61,103.97 160.33,106.25 151.84,106.25 145.43,112.67 142.59,112.67 140.87,110.95 137.59,110.95 135.79,109.15 128.2,109.15 128.08,109.03 126.44,109.03 125.88,109.6 124.32,109.6 123.92,109.2 122.72,109.2 122.68,109.16
  BOTTOM w0.102: v2(118.87,102.04) 119.05,102.22 USOC1.AT9 ; JNGFF.35 162.64,52.35 162.35,52.63 161.99,52.63 161.87,52.51 v2(161.87,52.32)
PCIE_PRX_DTX_P1: length 118.2
  IN2 w0.102: v2(119.37,101.58) 118.96,101.17 118.45,101.17 118.02,101.6 118.02,102.48 118.44,102.89 119.01,102.89 119.45,103.33 119.45,103.76 120.34,104.65 120.34,105.51 119.69,106.15 119.69,107.94 120.99,109.24 122.39,109.24 122.49,109.34 122.49,109.34
  IN2 w0.127: v2(161.87,53.03) 160.36,53.03 159.76,53.63 159.76,55.84 163.65,59.72 163.65,66.89 162.47,68.06 162.47,73.95 163.06,74.55 163.06,81.24 163.94,82.11 163.94,85.75 165.29,87.1 165.29,99.63 162.87,102.05 162.87,104.08 160.44,106.51 151.95,106.51 145.53,112.93 142.49,112.93 140.77,111.21 137.48,111.21 135.68,109.41 128.09,109.41 127.98,109.29 126.55,109.29 125.98,109.86 124.21,109.86 123.81,109.46 122.61,109.46 122.49,109.34
  BOTTOM w0.102: v2(161.87,53.03) 162.05,52.85 JNGFF.33 ; USOC1.AT10 119.5,101.71 v2(119.37,101.58)
PCIE_PTX_C_DRX_N1: length 128.6
  IN2 w0.127: v2(164.69,53.81) 165.44,53.81 167.49,55.86 167.49,68.73 167.61,68.85 167.61,74.3 168.12,74.81 168.12,78.11 168.87,78.85 168.87,93.13 169.39,93.66 169.39,97.08 169.29,97.19 169.29,100.71 166.43,103.56 166.43,104.98 166.43,105.62 159.56,112.5 159.56,117.85 157.26,120.15 150.17,120.15 v2(147.96,117.95)
  BOTTOM w0.102: JNGFF.29 164.19,53.85 164.24,53.91 164.6,53.91 v2(164.69,53.81) ; CC6.2 112.03,112.86 111.83,113.06 111.83,113.57 112.21,113.95 115.16,113.95 115.84,114.64 123.04,114.64 123.97,113.71 139.2,113.71 140.58,115.09 140.58,117.62 140.69,117.73 140.69,117.74 141.05,118.11 141.06,118.11 141.51,118.55 143.03,118.55 144.12,119.64 146.37,119.64 147.14,118.88 147.14,118.19 147.52,117.81 147.83,117.81 v2(147.96,117.95)
PCIE_PTX_C_DRX_P1: length 128.5
  IN2 w0.127: v2(147.96,117.23) 147.96,117.43 148.06,117.53 148.13,117.53 148.38,117.77 148.38,118 150.27,119.89 157.15,119.89 159.3,117.74 159.3,112.39 166.18,105.51 166.18,105.09 166.18,103.45 169.03,100.6 169.03,97.08 169.13,96.98 169.13,93.76 168.61,93.24 168.61,78.96 167.86,78.21 167.86,74.92 167.36,74.41 167.36,68.96 167.23,68.83 167.23,55.96 165.33,54.06 165.03,54.06 164.87,54.23 164.86,54.23 v2(164.69,54.39)
  BOTTOM w0.102: v2(147.96,117.23) 147.96,117.47 147.89,117.54 147.79,117.54 147.73,117.6 147.43,117.6 146.92,118.11 146.92,118.79 146.28,119.43 144.21,119.43 143.12,118.33 141.6,118.33 141.15,117.89 141.14,117.89 140.9,117.65 140.9,117.64 140.8,117.53 140.8,115 139.29,113.5 123.88,113.5 122.95,114.42 115.93,114.42 115.25,113.74 112.3,113.74 112.05,113.48 112.05,113.15 112.3,112.9 112.41,112.9 CC5.2 ; v2(164.69,54.39) 164.69,54.28 164.63,54.21 164.53,54.21 164.43,54.12 164.35,54.12 164.13,54.35 JNGFF.27
PCIE_PTX_DRX_N1: length 13
  IN2 w0.102: v2(118.11,104.32) 118.39,104.32 118.53,104.47 118.53,104.81 117.02,106.33 117.02,107.28
  IN2 w0.127: 117.02,107.28 117.02,110.48 116.43,111.07 115.35,111.07 114.85,111.56 114.39,111.56 114.38,111.55 v2(114.28,111.55)
  BOTTOM w0.102: CC6.1 112.8,112 113.16,112 113.34,111.82 113.75,111.82 113.86,111.93 114.19,111.93 114.39,111.73 114.39,111.66 v2(114.28,111.55) ; v2(118.11,104.32) 118.19,104.4 USOC1.AV4
PCIE_PTX_DRX_P1: length 13.1
  IN2 w0.102: v2(118.58,103.85) 118.58,104.19 118.76,104.37 118.76,104.91 117.28,106.4 117.28,107.54
  IN2 w0.127: 117.28,107.54 117.28,110.59 116.54,111.32 115.45,111.32 v2(114.73,112.04)
  BOTTOM w0.102: USOC1.AV6 118.66,103.92 v2(118.58,103.85) ; v2(114.73,112.04) 114.67,111.98 114.45,111.98 114.28,112.15 113.77,112.15 113.66,112.03 113.47,112.03 113.31,112.19 CC5.1
PCIE_RCOMPN: length 1.9
  TOP w0.102: v1(120.69,100.78) v2(120.69,100.24)
  TOP w0.254: v2(120.69,100.24) 120.69,100.12 RC13.2
  BOTTOM w0.254: USOC1.AP13 120.44,100.24 v2(120.69,100.24)
PCIE_RCOMPP: length 1.9
  TOP w0.102: v1(121.67,99.96) 121.37,99.66 v2(121.23,99.66)
  TOP w0.254: v2(121.23,99.66) 121.23,99.36 RC13.1
  BOTTOM w0.254: USOC1.AP14 121.08,99.52 v2(121.23,99.66)
PCU_SMB_ALERT#: length 6.4
  BOTTOM w0.102: USOC1.BG11 124.56,105.38 124.77,105.59 124.96,105.59 124.96,105.59 124.98,105.59 125.67,106.28 125.67,107.31 126.56,108.21 126.56,108.63 v1(126.75,108.82) 127.32,109.39 127.32,109.94 RP68.2
PCU_SMB_CLK: length 10.3
  TOP w0.102: v2(126.25,110.29) 126.29,110.32 126.81,110.32 v1(127.92,109.22) 128.49,109.22 129.46,110.18 QC3.3
  BOTTOM w0.102: RP68.4 v2(126.25,110.29) 126.25,109.74 125.96,109.46 125.96,108.41 124.56,107 124.52,107 124.52,106.37 124.26,106.11 USOC1.BH10
PCU_SMB_DATA: length 13.7
  TOP w0.102: QC4.3 131.27,109.22 v1(130.35,109.22) 129.06,109.22 128.71,108.86 127.68,108.86 v2(126.81,109.73)
  BOTTOM w0.102: USOC1.BG12 124.45,104.83 124.04,105.24 124.04,105.52 124.2,105.67 124.39,105.67 124.39,105.67 124.42,105.67 124.56,105.81 124.56,105.99 124.83,106.25 124.83,106.81 126.29,108.28 126.29,109.22 v2(126.81,109.73) 126.81,110.14 RP68.3
PECI_KB9012: length 5.4
  BOTTOM w0.102: UE1.118 147.23,140.77 RE43.1 147.2,140.79 147.54,140.44 147.54,139.47 v1(148.23,138.78)
PHASE1: length 14.8
  IN2 w1.016: 130.74,131.91 131.44,132.61 131.44,138.9 126.1,144.23
  vias: v1(130.45,132.3) v2(125.13,145.37) v2(125.1,144.69) v2(126.8,133.31) v2(126.8,132.61) v2(126.8,131.97) v2(127.44,133.31) v2(127.44,132.67) v2(127.44,131.97) v2(127.44,131.21) v2(128.07,133.31) v2(128.07,132.67) v2(128.07,132.04) v2(128.07,131.21) v2(128.71,134.01) v2(128.77,133.31) v2(128.77,132.61) v2(128.77,131.91) v2(128.77,131.21) v2(129.47,131.21) v2(130.17,131.21)
PHASEG: length 8.2
  IN2 w1.016: 120.07,135.97 120.07,144.17
  vias: v1(121.51,131.94) v2(118.17,133.56) v2(118.17,132.93) v2(118.17,132.16) v2(118.87,134.2) v2(118.87,133.5) v2(118.87,132.8) v2(118.87,132.16) v2(118.87,131.47) v2(119.5,134.89) v2(119.5,134.26) v2(119.5,133.5) v2(119.5,132.8) v2(119.5,132.16) v2(119.5,131.47) v2(120.2,134.89) v2(120.2,134.26) v2(120.2,133.56) v2(120.2,132.86) v2(120.2,132.23) v2(120.2,131.53) v2(120.73,145.36) v2(121.21,145.83)
PLT_RST#: length 249
  TOP w0.127: RC20.2 91.32,70.51 ; 91.32,70.51 v2(91.92,71.12) 92.14,70.89 92.14,70.4 92.47,70.08 UC5.4 ; 91.32,70.51 CC11.1 ; v2(155.34,52.23) 157.11,50.46 v1(157.11,47.37) 158.03,46.46 164.03,46.46 165.54,47.96 167.33,47.96 167.9,48.53 167.9,48.86 168.27,49.23 v2(168.27,49.33)
  IN1 w0.127: v2(75.88,58.72) 78.89,58.72 85.72,65.55 85.72,66.79 87.8,68.87 89.66,68.87 91.9,71.12 v2(91.92,71.12) ; v2(155.82,142.39) 157.02,141.19 157.02,135.47 156.33,134.79 156.33,131.1 155.59,130.37 155.59,126.48 156.2,125.88 157.85,125.88 160.37,123.36 163.36,123.36 166.64,120.07 166.64,102.91 168.46,101.09 168.46,100.67 169.31,99.82 169.31,97.92 169.35,97.88 169.35,94.1 169.09,93.85 169.09,93.75 168.42,93.07 168.42,92.46 168.42,86.11 168.18,85.87 168.18,78.95 168.18,78.08 167.86,77.76 167.86,76.18 167.86,72.37 167.57,72.08 167.57,67.78 166.68,66.89 166.68,61.85 163.51,58.68 161.04,58.68 156.14,53.79 156.14,53.03 v2(155.34,52.23) 154.83,51.72 154.08,51.72 153.37,51.01 149.62,51.01 148.2,49.59 146.23,49.59 144.16,47.52 143.29,47.52 142.78,48.03 142.37,48.03 v2(142.36,48.02)
  BOTTOM w0.127: v2(142.36,48.02) 142.27,48.1 142.22,48.1 141.72,48.6 141.41,48.6 136.07,53.93 80.45,53.93 79.18,53.93 78.89,54.22 76.68,56.43 76.68,57.55 75.88,58.35 v2(75.88,58.72) ; JNGFF.44 170.07,50.1 169.63,50.54 168.64,50.54 168.27,50.17 v2(168.27,49.33) ; CE36.1 156.56,149.15 UE1.13 156.56,143.13 v2(155.82,142.39)
PMC_ACIN: length 7.9
  TOP w0.102: DC1.2 108.9,86.3 108.9,86.16 v1(109.25,85.81) 109.25,85.57 RC21.2 110,84.88 111.27,84.88 113.1,86.71 v2(113.1,87.14)
  BOTTOM w0.102: USOC1.D20 112.6,87.14 v2(113.1,87.14)
PMC_BATLOW#: length 4
  TOP w0.102: v2(115.91,87.29) 115.91,86.56 v1(115.75,86.4) 115.26,85.91 114.57,85.91 114.18,85.52 RP65.2
  BOTTOM w0.102: USOC1.K26 116.29,87.2 116.21,87.29 v2(115.91,87.29)
PMC_CORE_PWROK: length 298.1
  TOP w0.102: v2(87.5,73.3) 87.5,73.02 87.2,72.73 UC7.2 ; v2(98.23,92.92) 98.1,92.92 94.67,89.49 94.67,87.84 94.93,87.59 95.5,87.59 v2(95.62,87.46) ; JDB1.12 36.77,77.73 36.44,78.06 36.12,78.06 v2(36.06,78.12) 35.8,78.38 35.24,78.38 34.78,78.84 34.78,79.74 CC57.1 v1(34.22,81.31)
  IN1 w0.127: v2(102.42,175.22) 102.99,175.79 113.02,175.79 114.38,174.43 118.92,174.43 119.83,175.34 150.98,175.34 152.44,173.88 165.25,173.88 171.06,168.07 171.06,151 168.9,148.83 164.45,148.83 164.16,148.55 v2(164.16,148.4) ; v2(53.57,79.52) 53.45,79.65 49.59,79.65 48.76,78.82 43.4,78.82 42.5,77.92 36.26,77.92 v2(36.06,78.12)
  IN2 w0.127: v2(102.42,175.22) 100.55,175.22 97.01,171.68 97.01,167.35 94,164.34 94,137.57 91.48,135.06 91.48,126.39 93.92,123.95 93.92,116.13 98.15,111.89 98.69,111.89 v2(98.74,111.84)
  BOTTOM w0.102: USOC1.B7 107.11,90.44 106.92,90.25 105.24,90.25 103.29,92.21 101.29,92.21 101.1,92.02 CC16.1 CE31.1 98.49,92.66 v2(98.23,92.92) 99.02,93.71 99.02,98.3 97.67,99.65 97.67,105.22 98.74,106.28 98.74,111.84 v2(98.74,111.84) ; v2(95.62,87.46) 94.87,86.71 94.41,86.71 94.15,86.44 92.49,86.44 92.17,86.13 92.17,85.71 92.72,85.16 92.72,84.44 92.51,84.23 92.51,82.63 91.92,82.04 91.92,77.97 91.31,77.36 91.31,74.18 90.45,73.32 87.52,73.32 v2(87.5,73.3) 87.18,73.61 85.23,73.61 82.51,76.34 82.51,77.9 81.75,78.66 80.98,78.66 79.84,77.52 70.36,77.52 70.11,77.52 66.3,81.33 55.22,81.33 53.9,80.01 53.9,79.98 53.57,79.65 v2(53.57,79.52) ; RE18.1 164.16,149.13 v2(164.16,148.4) UE1.32
PMC_PCIE_WAKE#: length 3.4
  TOP w0.102: v4(115.86,84.05) 115.27,84.64 114.73,84.64 114.68,84.69 RP65.1 114.68,85.26 114.79,85.37 115.07,85.37 v2(115.25,85.2)
  BOTTOM w0.102: v2(115.25,85.2) 115,85.45 USOC1.F26
PMC_PLTRST#: length 128.4
  TOP w0.102: v2(113.58,87.62) 113.58,86.95 113.3,86.67 113.3,86.62 112.43,85.75 112.43,85.23 CC13.1
  TOP w0.127: UC5.2 94.33,69.43 94.16,69.25 94.16,68.4 93.07,67.32 v2(91.93,67.32) ; v4(37.64,81.44) 37.79,81.29 37.79,79.9 38.28,79.41 CC51.1 39.27,78.39 JDB1.17 39.27,71.37 38.88,70.97 38.88,65.63 v2(39.27,65.24)
  IN1 w0.102: v2(113.58,87.62) 112.93,87.62 112.07,86.76 111.06,86.76 110.87,86.95 107.66,86.95 106.31,88.3 105.81,88.3 105.12,88.98 103.14,88.98
  IN1 w0.127: v2(92.67,85.91) 92.67,88.39 96.14,91.86 98.74,91.86 101.62,88.98 103.14,88.98
  BOTTOM w0.102: USOC1.F20 113.43,87.77 v2(113.58,87.62)
  BOTTOM w0.127: 90.99,68.21 90.99,73.08 93.27,75.37 93.27,78.9 94.35,79.98 94.35,81.75 93.17,82.94 93.17,83.35 93.21,83.39 93.21,85.42 92.69,85.94 v2(92.67,85.91) ; 90.99,68.21 90.55,68.65 89.15,68.65 88.92,68.88 88.4,68.88 88.14,69.15 67.98,69.15 65.96,67.13 59.54,67.13 58.72,67.95 52.63,67.95 50.95,66.26 40.3,66.26 v2(39.27,65.24) ; 90.99,68.21 91.88,67.32 v2(91.93,67.32)
PMC_PWRBTN#: length 36.3
  TOP w0.102: v2(92.61,78.98) 91.85,78.98 91.14,79.69 88.07,79.69 v1(87.64,79.26) 85.97,79.26 84.82,80.41 R27.1
  IN1 w0.102: 106.59,85.53 108.98,85.53 109.11,85.4 113.45,85.4 114.84,86.79 v2(115.41,86.79)
  IN1 w0.127: 106.59,85.53 105.05,85.53 104.74,85.22 100.74,85.22 97.52,82 96.81,82 93.78,78.98 v2(92.61,78.98)
  BOTTOM w0.102: USOC1.J26 115.78,86.7 115.7,86.79 v2(115.41,86.79)
PMC_RSTBTN#: length 8.1
  TOP w0.102: v2(126.37,111.59) v4(126.37,110.99)
  BOTTOM w0.102: v2(126.37,111.59) 125.75,111.59 124.92,110.76 RC24.1 125.48,110.12 125.48,108.61 123.95,107.07 123.95,106.74 123.84,106.63 123.84,106.36 123.67,106.19 USOC1.BG9
PMC_SLP_S3#: length 25.9
  TOP w0.102: v2(98.2,74.58) 98.1,74.48 97,74.48 96.51,74 R1024.1 ; R24.2 R1024.1 ; R1024.1 96.5,73.45 v1(95.97,72.92)
  IN1 w0.102: 109.25,82.87 109.39,83 109.41,83 109.43,83.02 109.91,83.02 110.67,83.78 v2(110.93,83.78)
  IN1 w0.127: v2(98.2,74.58) 98.36,74.58 100.92,77.15 104.3,77.15 106.93,79.78 106.93,81.25 107.79,82.11 108.49,82.11 109.25,82.87
  BOTTOM w0.102: v2(110.93,83.78) 110.95,83.75 111.54,83.75 112.25,84.46 112.25,84.63 112.61,84.99 112.61,85.2 112.71,85.3 112.93,85.3 113.05,85.42 113.1,85.49 113.12,85.62 113.09,85.76 113.13,85.8 USOC1.D22
PMC_SLP_S4#: length 31.8
  TOP w0.102: R25.2 R1033.1 92.18,84.79 v2(91.55,85.43) v1(91.55,85.99)
  IN1 w0.102: v2(113.68,86.5) 110.1,86.5 109.89,86.71 107.61,86.71 106.23,88.1 105.72,88.1 105.33,88.49 103.66,88.49 103.64,88.48
  IN1 w0.127: v2(91.55,85.43) 91.85,85.12 92.89,85.12 93.3,85.53 93.3,88.31 96.29,91.3 97.75,91.3 100.56,88.48 103.64,88.48
  BOTTOM w0.102: v2(113.68,86.5) 113.68,86.77 113.6,86.85 USOC1.F22
PMC_SUSCLK: length 129.4
  TOP w0.102: v2(168.28,51.77) 168.28,52.05 168.73,52.5 RM8.2 ; v2(170.61,69.73) 170.12,70.21 167.81,70.21 166.35,71.67 v1(161.93,71.67) 161.11,71.67 v2(160.9,71.46)
  IN1 w0.102: v2(107.04,86.04) 107.35,85.73 109.07,85.73 109.2,85.6 112.26,85.6 112.78,86.12 113.85,86.12 114.34,86.6 v2(114.34,87.1)
  IN1 w0.127: v2(160.9,71.46) 160.07,70.63 157.79,70.63 157.72,70.56 148.78,70.56 148.08,71.27 v2(146.81,71.27)
  IN2 w0.102: v2(107.04,86.04) 106.56,85.56
  IN2 w0.127: v2(168.28,51.77) 168.28,52.04 169.06,52.81 170.18,52.81 170.83,53.47 170.83,60.4 171.45,61.02 171.45,68.88 v2(170.61,69.73) ; 106.56,85.56 105.61,84.62 101.33,84.62 98.19,81.48 98.19,79.08 v2(98.74,78.53)
  BOTTOM w0.102: v2(146.81,71.27) 146.81,71.21 145.47,69.87 137,69.87 131.7,64.57 108.17,64.57 105.02,67.72 105.02,72.57 101.23,76.36 100.5,76.36 98.74,78.13 v2(98.74,78.53) ; v2(114.34,87.1) 114.36,87.08 114.61,87.08 USOC1.G24
PS_ID: length 102.3
  TOP w0.254: v2(112.96,174.07) 113.09,173.95 v1(113.09,172.42) 113.19,172.32 113.19,168 113.42,167.77 PR4.1 PR1.2
  BOTTOM w0.203: UE1.16 157.76,148.08 159.24,149.55 159.24,151.06 159.67,151.49 166.28,151.49 166.93,150.83 167.84,150.83 168.14,151.13 168.62,151.13 170.08,152.6 170.08,167.68 164.48,173.29 150.51,173.29 149.54,174.25 147.62,174.25 146.25,175.62 135.58,175.62 134.21,174.25 121.85,174.25 121.42,173.82 113.21,173.82 v2(112.96,174.07)
PSID: length 21.8
  TOP w0.254: PJPDC1.3 98.9,169.79 100.13,171.03 v1(106.2,171.03) 111.1,171.03 PL3.2
PSID-1: length 3.6
  TOP w0.102: v1(110.34,169.25) PR5.2
  TOP w0.254: PQ2.2 109.35,167.82 PR5.2 109.35,170.11 PR2.1
PSID-2: length 4.9
  TOP w0.102: v1(107.55,165.57) 108.18,164.93 PR3.2
  TOP w0.254: PR3.2 108.44,165.96 PQ2.1 108.81,166.33 PQ1.2
PSID-3: length 3.6
  TOP w0.102: v1(113.81,164.24) 114.48,164.92 PR1.1
  TOP w0.254: PR1.1 113.99,165.74 113.4,166.33 PQ1.3
PTP_DIS#: length 297.6
  TOP w0.102: RE28.2 60.88,76.54 61.78,77.44 JTP.6 63.23,77.44 63.67,77.01 63.68,77.01 64.26,76.44 64.26,70.76 63.35,69.86 63.35,67.98 v2(63.79,67.55) ; v2(171.57,139.2) v1(171.57,138.58)
  IN1 w0.127: v2(63.68,51.27) 63.75,51.33 63.75,55.5 63.26,55.98 63.26,66.95 63.79,67.47 v2(63.79,67.55) ; v2(139.03,31.83) 139.03,34.68 142.41,38.06 150.17,38.06 151.47,39.36 151.47,41.62 152.41,42.55 154.47,42.55 157.7,45.78 157.7,45.99 161.35,45.99 163.7,48.34 163.7,50.4 165.92,52.62 165.92,55.33 170.58,59.99 v2(171.76,59.99)
  IN2 w0.127: v2(63.68,51.27) 63.68,49.3 64.89,48.09 64.89,33.55 62.22,30.88 60.64,30.88 57.78,28.02 57.78,24.24 v2(57.45,23.91) ; v2(171.57,139.2) 170.43,138.06 170.43,116.23 172.19,114.46 172.19,108.71 172.21,108.69 172.21,90.58 171.34,89.72 171.34,70.2 172.22,69.33 172.22,60.45 v2(171.76,59.99)
  BOTTOM w0.102: v2(171.57,139.2) 170.51,139.2 168.13,141.59 RX4.2 167.43,142.77 UE1.38 ; v2(57.45,23.91) 57.45,22.6 57.18,22.33 57.18,18.71 59.21,16.68 68.42,16.68 72.76,21.02 124.49,21.02 130.55,27.08 135.66,27.08 137.36,28.79 137.36,30.16 v2(139.03,31.83)
PWR_PWM_LED: length 19.9
  TOP w0.102: v1(31.06,12.17) 30.23,13 Q6102.1 29.48,9.74 28.75,9 28.75,7.63 29.23,7.15 29.23,5.12 29.14,5.03 28.52,4.41 21.06,4.41 20.25,3.6 R6107.2
PWR_PWM_LED#: length 277.9
  TOP w0.102: R6104.2 30.24,14 29.55,14.7 29.55,15.63 26.85,18.32 26.85,30.82 23.04,34.63 23.04,44.78 25.77,47.51 25.77,47.9 26.51,48.64 26.51,57.04 v1(27.32,57.86) 29.18,59.71 v2(30.03,59.71)
  IN1 w0.127: v2(153.57,129.29) 153.21,128.93 153.21,126.67 155.46,124.42 155.84,124.04 158.18,124.04 162.49,119.73 162.49,119.52 162.49,116.32 165.63,113.19 165.63,102.48 167.41,100.7 167.41,93.31 167.41,86.72 166.8,86.11 166.8,82.64 166.8,81.8 166.55,81.56 166.55,77.14 166.85,76.85 166.85,75.76 166.85,72.79 166.55,72.5 166.55,68.26 164.97,66.67 164.97,64.35 153.6,52.98 149.85,52.98 147.71,50.83 145.8,50.83 143.92,48.95 143.3,48.95 v2(142.91,49.35)
  BOTTOM w0.102: UE1.92 153.36,129.5 v2(153.57,129.29) ; v2(142.91,49.35) 142.7,49.55 142.37,49.55 137.03,54.88 79.87,54.88 77.63,57.12 77.63,58.32 76.07,59.88 75.57,59.88 74.15,61.3 72.56,61.3 71.6,60.33 47.92,60.33 47.78,60.2 47.78,60.2 47.35,59.77 46.03,59.77 45.88,59.93 41.29,59.93 39.74,58.38 31.36,58.38 v2(30.03,59.71)
PWR_PWM_LED_R#: length 269.2
  TOP w0.102: R6104.1 v1(31.95,15.83) 31.83,15.95 v2(31.16,15.95) 30.68,15.95 30.45,15.72 Q6102.2
  IN1 w0.127: v2(30.7,21.42) 45.75,21.42 47.57,23.24 59.14,23.24 60.75,24.85 63.76,24.85 64.14,25.23 64.14,29.92 64.85,30.63 74.45,30.63 75.28,29.8 76.97,29.8 77.5,30.34 130.08,30.34 132.77,33.03 134.52,33.03 135.01,33.51 135.01,35.19 138.89,39.07 138.89,42.58 140.07,43.77 140.07,48.07 144.96,52.95 144.96,61.82 149.72,66.58 160.68,66.58 161.35,67.25 161.35,70.81 161.67,71.13 161.67,82.29 162.92,83.54 162.92,85.98 157.59,91.31 157.59,98.45 156.95,99.08 156.95,99.64 158.64,101.33 160.18,101.33 162.32,103.47 162.32,110.82 159.06,114.09 159.06,116.1 156.21,118.95 155.42,119.74 153.87,119.74 148.39,125.22 148.39,130.36 149.5,131.47 149.5,136.82 147.78,138.54 147.78,140.67 147.12,141.33 147.12,144.15 145.4,145.88 v2(145.4,147.71)
  BOTTOM w0.102: v2(31.16,15.95) 31.16,20.96 v2(30.7,21.42) ; Q6105.1 v2(145.4,147.71)
REMOTE1+: length 80.1
  TOP w0.254: U2407.2 99.24,111.58 98.56,110.9 C2502.1 97.52,110.57 96.74,110.57 96.13,109.97 v1(96.13,106.87) 96.13,105.04 v2(96.07,104.97)
  IN2 w0.254: v2(96.07,104.97) 96.07,104.73 96.08,104.72 96.21,104.72 96.49,104.44 96.49,104.31 97.02,103.78 97.02,100.36 94.77,98.11 94.77,94.65 86.53,86.41 86.53,83.21 85.38,82.06 82.76,82.06 77.84,77.13 75.68,77.13 73.74,75.2 73.74,67.27 73.32,66.85 72.87,66.85 v2(72.75,66.73)
  BOTTOM w0.254: C2500.1 55.34,64.88 Q2407.2 57.14,65.53 Q2407.1 58.53,65.39 66.91,65.39 68.38,66.86 72.62,66.86 v2(72.75,66.73)
REMOTE1-: length 78.7
  TOP w0.254: v2(96.01,104.24) 96.02,104.24 96.6,104.82 v1(96.6,108.77) 96.6,109.8 97,110.19 97.64,110.19 C2502.2 98.38,110.52 98.72,110.52 99.27,111.08 U2407.3
  IN2 w0.254: v2(72.75,67.37) 72.89,67.23 73.17,67.23 73.36,67.43 73.36,75.36 75.52,77.52 77.68,77.52 82.61,82.44 85.22,82.44 86.15,83.37 86.15,86.56 94.39,94.81 94.39,98.27 96.64,100.52 96.64,103.6 v2(96.01,104.24)
  BOTTOM w0.254: v2(72.75,67.37) 72.62,67.24 68.22,67.24 66.75,65.77 59.14,65.77 58.73,66.18 Q2407.3 55.34,66.18 C2500.2
REMOTE2+: length 59.9
  TOP w0.254: U2407.4 100.97,110.58 101.34,110.96 101.34,112.97 C2504.1 100.82,113.95 101.09,114.22 101.09,117.05 v1(102.38,118.35) 106.65,122.61 107.37,122.61 v2(107.49,122.73) ; v2(138.32,123.31) 138.42,123.41 138.42,124.35 137.83,124.95 137.83,127.81 137.37,128.27 Q2408.2 137.84,128.89 138.02,129.07 Q2408.1 138.02,131.48 C2505.1
  IN2 w0.254: v2(107.49,122.73) 107.7,122.73 109.2,121.23 124.65,121.23 125.2,120.68 127.2,120.68 128.11,121.6 137.65,121.6 138.44,122.39 138.44,123.2 v2(138.32,123.31)
REMOTE2-: length 59.7
  TOP w0.254: v2(107.49,122.14) 107.4,122.23 106.88,122.23 101.5,116.86 v1(101.5,115.44) 101.5,114.18 101.73,113.95 C2504.2 101.73,110.6 101.21,110.08 U2407.5 ; C2505.2 138.5,131.54 138.67,131.38 Q2408.3 138.67,128.27 138.21,127.81 138.21,125.11 138.8,124.51 138.8,123.41 v2(138.91,123.31)
  IN2 w0.254: v2(138.91,123.31) 138.82,123.22 138.82,122.23 137.81,121.22 128.27,121.22 127.35,120.3 125.04,120.3 124.49,120.85 109.04,120.85 107.7,122.19 107.54,122.19 v2(107.49,122.14)
RING2:
  vias: v1(149.1,21.89) v2(149.28,22.39) v2(149.64,21.9)
RING2_R:
  vias: v1(164.43,23.86) v2(148.65,24.6) v2(149.28,24.6) v2(165.03,24.47) v2(165.03,23.88)
RREF: length 4
  BOTTOM w0.254: 15.23,19.71 15.42,19.9 UR1.1
  BOTTOM w0.305: 15.23,19.71 14.05,18.52 v1(14.05,18.25) 13.93,18.12 RR1.1
RTC_RST#: length 14.9
  BOTTOM w0.102: 104.04,86.53 CC22.1 105.42,87.9 108.1,87.9 108.52,88.32 108.52,88.58 108.77,88.83 108.92,88.83 109.08,88.98 109.08,89.42 USOC1.C12
  BOTTOM w0.127: 104.04,86.53 RC35.2 103.76,86.25 v4(101.86,86.25) 100.87,86.25 98.08,83.47 R1089.2
RTC_TEST#: length 116.7
  TOP w0.127: v2(38.28,70.06) 38.28,75.2 37.27,76.22 JDB1.13 37.27,77.85 v1(37.71,78.29)
  IN2 w0.127: v2(38.28,70.06) 38.61,70.39 46.89,70.39 49.53,73.04 50.66,73.04 53.65,76.03 55.3,76.03 57.38,78.11 60.18,78.11 60.92,77.38 72.58,77.38 74.55,79.34 75.11,79.34 75.12,79.34 75.75,79.34 76.38,79.34 76.38,79.34 76.76,79.34 76.97,79.34 76.97,79.34 77.39,79.34 93.79,95.73 93.79,98.58 v2(95.99,100.78)
  BOTTOM w0.102: 101.45,87.94 101.86,88.35 105.46,88.35 105.66,88.16 107.87,88.16 108.32,88.61 108.32,88.81 108.49,88.98 108.49,89.51 USOC1.C11
  BOTTOM w0.127: v2(95.99,100.78) 95.99,99.58 96.44,99.14 97.21,98.36 97.35,98.23 97.69,97.88 97.69,94.68 96.79,93.78 96.79,91.56 95.61,90.37 95.61,89.06 95.6,89.06 95.6,88.58 95.66,88.53 96.12,88.07 96.12,87.26 95.08,86.22 94.95,86.22 CC20.2 94.79,86.01 96.01,84.79 RC34.2 R1088.2 97.99,84.1 101.03,87.14 101.03,87.53 101.45,87.94
SATA_LED: length 6.4
  TOP w0.102: R6108.1 EC6104.1 24.72,3.6 25.69,2.64 v1(26.56,2.64) 27.16,2.64 28.09,3.56 Q6104.1
SATA_LED#_B: length 10.1
  TOP w0.102: Q6104.2 31.03,5.65 31.34,5.95 R6106.2 32.05,6.09 v1(32.05,8.94) 32.05,9.4 32.76,10.11 32.76,12.54 Q6103.1
SATA_LED#_R: length 4
  BOTTOM w0.102: RD15.2 R6110.2 148.27,148.41 148.49,148.18 v1(148.49,147.91) 148.49,147.62 148.2,147.33 Q6105.2
SATA_LED#_SOC: length 14.1
  TOP w0.102: QC2.3 118.01,112.21 RC18.2 116.72,110.93 116.72,108.84 116.47,108.59 116.47,107.29 v1(116.64,107.12) 116.64,106.44 120.48,102.6 v2(121.5,102.6)
  BOTTOM w0.102: v2(121.5,102.6) 121.85,102.6 122.03,102.41
SATA_LED_R: length 2.8
  TOP w0.102: LED2.2 21.65,1.81 v1(22.4,2.56) 22.87,3.03 R6108.2
SATA_PRX_DTX_N0: length 12.2
  IN1 w0.127: v2(170.36,30.41) 170.53,30.57 170.83,30.57 171.08,30.82 171.08,32.45 167.98,35.55 167.98,36.13 167.81,36.3 167.81,36.4 v2(167.93,36.51)
  BOTTOM w0.102: JHDD.8 168.11,29.96 168.26,30.11 168.66,30.11 169.11,30.55 170.22,30.55 v2(170.36,30.41) ; v2(167.93,36.51) 167.77,36.66 167.77,36.91 167.67,37.02 167.67,37.21 167.87,37.41 CS34.2
SATA_PRX_DTX_N0_C: length 135.5
  IN2 w0.102: v2(122.81,101.19) 123.01,100.99 123.01,100.82 122.9,100.72 122.73,100.72 122.45,101 122.2,101 122.04,101.16 122.04,102.26 122.17,102.39 122.17,103.14 121.98,103.34 121.98,104.06 121.13,104.91 121.13,105.84 120.4,106.56 120.4,107.53 120.88,108.01 123.42,108.01 123.62,108.21
  IN2 w0.127: v2(168.07,39.09) 168.07,39.16 167.89,39.34 167.7,39.34 167.63,39.28 167.63,38.92 167.47,38.76 167.47,38.37 167.69,38.15 169.84,38.15 170.4,38.71 170.4,40.64 170.03,41 167.73,41 162.56,46.18 159.75,46.18 158.43,47.51 158.43,55.98 162.51,60.07 162.51,66.56 161.32,67.76 161.32,74.26 162.04,74.98 162.04,81.3 161.55,81.79 161.55,85.61 158.19,88.97 158.19,97.01 156.9,98.3 156.9,101.02 157.33,101.46 157.33,102.69 155.55,104.47 152.54,104.47 145.16,111.85 143.42,111.85 143.41,111.84 142.85,111.84 141.2,110.19 141.17,110.19 141.16,110.19 137.93,110.19 135.91,108.17 133.73,108.17 132.94,107.38 128.94,107.38 128.16,108.16 124.8,108.16 124.62,108.34 123.75,108.34 123.62,108.21
  BOTTOM w0.102: v2(168.07,39.09) 167.84,39.09 167.7,38.95 167.7,38.58 CS34.1 ; v2(122.81,101.19) 122.9,101.1 122.9,100.52 USOC1.AV16
SATA_PRX_DTX_N1: length 2.1
  TOP w0.102: JODD1.5 154.7,78.4 154.56,78.55 154.47,78.55 154.41,78.49 154.41,78.27 154.22,78.07 154.06,78.07 CS14.1
SATA_PRX_DTX_N1_C: length 63.3
  TOP w0.102: CS14.2 152.53,78 152.33,78 v2(152.14,77.81)
  IN2 w0.102: v2(123.71,101.99) 123.87,101.83 124.04,101.83 125.82,103.6 126.86,103.6 127.16,103.31 128.74,103.31 128.76,103.32 128.77,103.32
  IN2 w0.127: 128.77,103.32 129.15,103.32 129.68,103.86 133.27,103.86 133.88,104.47 136.57,104.47 139.73,107.63 143.67,107.63 144.58,108.54 145.59,108.54 151.7,102.44 152.45,102.44 154.35,100.53 154.35,95.82 154.17,95.65 154.17,85.94 153.64,85.41 153.64,80.97 154.17,80.44 154.17,78.71 153.27,77.81 v2(152.14,77.81)
  BOTTOM w0.102: USOC1.BA16 123.78,101.51 123.71,101.58 v2(123.71,101.99)
SATA_PRX_DTX_P0: length 12.2
  IN1 w0.127: v2(170.36,30.99) 170.52,30.83 170.72,30.83 170.82,30.93 170.82,32.34 167.72,35.44 167.72,36.03 167.56,36.19 167.56,36.29 v2(167.34,36.51)
  BOTTOM w0.102: v2(167.34,36.51) 167.56,36.72 167.56,36.82 167.46,36.93 167.46,37.33 167.38,37.41 CS31.2 ; v2(170.36,30.99) 170.13,30.77 169.02,30.77 168.57,30.32 168.23,30.32 168.09,30.46 JHDD.7
SATA_PRX_DTX_P0_C: length 135.5
  IN2 w0.102: v2(122.3,100.58) 122.05,100.82 121.81,101.06 121.81,102.36 121.94,102.48 121.94,103.05 121.75,103.24 121.75,103.96 120.89,104.81 120.89,105.74 120.17,106.47 120.17,107.62 120.79,108.24 123.29,108.24 123.44,108.4
  IN2 w0.127: 123.44,108.4 123.64,108.59 124.73,108.59 124.9,108.42 128.27,108.42 129.05,107.64 132.83,107.64 133.62,108.43 135.81,108.43 137.82,110.44 141.06,110.44 141.06,110.45 141.09,110.45 142.74,112.1 143.3,112.1 143.31,112.11 145.27,112.11 152.65,104.73 155.66,104.73 157.59,102.8 157.59,101.35 157.16,100.92 157.16,98.41 158.45,97.12 158.45,89.08 161.8,85.72 161.8,81.9 162.3,81.4 162.3,74.88 161.58,74.15 161.58,67.86 162.77,66.67 162.77,59.96 158.68,55.88 158.68,47.62 159.86,46.44 162.66,46.44 167.84,41.26 170.14,41.26 170.66,40.74 170.66,38.61 169.94,37.89 167.59,37.89 167.21,38.26 v2(167.21,39.12)
  BOTTOM w0.102: USOC1.AU16 122.48,100.06 122.48,100.39 v2(122.3,100.58) ; v2(167.21,39.12) 167.48,38.85 167.48,38.78 167.02,38.32 CS31.1
SATA_PRX_DTX_P1: length 2.1
  TOP w0.102: CS15.1 154.04,78.29 154.13,78.29 154.2,78.35 154.2,78.58 154.38,78.76 154.52,78.76 154.66,78.91 JODD1.6
SATA_PRX_DTX_P1_C: length 63.3
  TOP w0.102: v2(152.11,78.39) 152.16,78.34 152.52,78.34 CS15.2
  IN2 w0.102: v2(123.24,101.61) 123.31,101.68 123.48,101.68 123.56,101.6 124.14,101.6 125.92,103.37 126.77,103.37 127.06,103.08 128.74,103.08 128.76,103.07 128.77,103.07
  IN2 w0.127: v2(152.11,78.39) 152.16,78.34 152.2,78.34 152.48,78.06 153.16,78.06 153.91,78.82 153.91,80.33 153.38,80.86 153.38,85.51 153.92,86.05 153.92,95.75 154.1,95.93 154.1,100.43 152.34,102.18 151.59,102.18 145.48,108.29 144.69,108.29 143.77,107.37 139.84,107.37 136.68,104.21 133.98,104.21 133.38,103.6 129.79,103.6 129.25,103.07 128.77,103.07
  BOTTOM w0.102: v2(123.24,101.61) 123.37,101.61 123.54,101.44 123.54,101.12 USOC1.AY16
SATA_PTX_DRX_N0: length 15.1
  IN1 w0.127: v2(170.36,28.55) 170.52,28.39 171.19,28.39 171.59,28.8 171.59,32.7 169.66,34.63 169.66,36.9 v2(169.42,37.14)
  BOTTOM w0.102: v2(170.36,28.55) 170.19,28.38 169.15,28.38 168.74,28.79 168.41,28.79 168.23,28.96 JHDD.10 ; v2(169.42,37.14) 169.69,37.41 169.69,37.78 169.58,37.89 CS32.2
SATA_PTX_DRX_N0_C: length 125
  IN2 w0.102: v2(123.1,105.88) 122.92,105.88 122.78,106.03 122.78,106.31 123.11,106.64 124.17,106.64 124.94,105.86 125.67,105.86 125.94,106.13 128.04,106.13 128.06,106.12 128.13,106.12 128.14,106.11 128.16,106.11
  IN2 w0.127: v2(169.39,39.5) 169.58,39.69 169.58,40.02 169.42,40.18 167.29,40.18 162.55,44.92 156.62,44.92 155.73,45.8 152.53,45.8 149.37,48.96 149.37,60.85 150.13,61.62 150.13,66.59 154.26,70.72 154.26,74.97 154.61,75.32 156.34,75.32 159.08,78.07 159.08,84.09 157.43,85.75 157.43,96.59 155.89,98.13 155.89,101.72 155,102.61 155,102.82 155,102.82 155,103.08 154.37,103.71 152.22,103.71 145.87,110.07 143.82,110.07 142.66,108.9 139.16,108.9 136.91,106.65 134.09,106.65 133.55,106.11 128.16,106.11
  BOTTOM w0.102: v2(123.1,105.88) 122.84,106.15 USOC1.BG7 ; v2(169.39,39.5) 169.6,39.29 169.6,39.15 169.26,38.81 CS32.1
SATA_PTX_DRX_N1: length 2.5
  TOP w0.102: CS9.1 153.7,76.72 153.99,76.43 154.1,76.43 154.18,76.51 154.18,77.07 154.38,77.26 154.5,77.26 154.64,77.4 JODD1.3
SATA_PTX_DRX_N1_C: length 71.5
  TOP w0.102: CS9.2 152.79,76.82 152.42,76.45 152.29,76.45 v2(152.13,76.61)
  IN2 w0.102: 124.8,104.79 124.25,105.34 123.44,105.34 123.13,105.04 123.02,105.04 122.83,104.85 122.83,104.62 122.99,104.45 123.33,104.45 v2(123.38,104.5)
  IN2 w0.127: v2(152.13,76.61) 152.27,76.47 156.3,76.47 158.3,78.48 158.3,83.41 156.66,85.05 156.66,96.25 155.12,97.79 155.12,100.69 152.87,102.94 151.91,102.94 145.57,109.28 144.27,109.28 143.12,108.14 139.48,108.14 137.15,105.81 134.46,105.81 133.03,104.38 125.22,104.38 124.8,104.79
  BOTTOM w0.102: v2(123.38,104.5) 123.33,104.55 USOC1.BF10
SATA_PTX_DRX_P0: length 15
  IN1 w0.127: v2(170.01,37.14) 169.92,37.05 169.92,34.74 171.85,32.81 171.85,28.69 171.29,28.13 170.52,28.13 v2(170.36,27.97)
  BOTTOM w0.102: JHDD.11 168.22,28.46 168.33,28.57 168.65,28.57 169.06,28.16 170.17,28.16 v2(170.36,27.97) ; v2(170.01,37.14) 169.91,37.24 169.91,37.59 CS30.2
SATA_PTX_DRX_P0_C: length 124.9
  IN2 w0.102: v2(122.49,106.79) 122.6,106.68 122.82,106.68 123.01,106.87 124.26,106.87 125.04,106.09 125.57,106.09 125.85,106.37 128.16,106.37
  IN2 w0.127: v2(169.97,39.5) 169.83,39.64 169.83,40.12 169.53,40.43 167.39,40.43 162.65,45.17 156.72,45.17 155.83,46.06 152.63,46.06 149.63,49.07 149.63,60.75 150.39,61.51 150.39,66.49 154.52,70.62 154.52,74.86 154.72,75.06 156.44,75.06 159.34,77.96 159.34,84.2 157.68,85.86 157.68,96.7 156.14,98.24 156.14,101.61 156.14,101.83 155.25,102.71 155.25,103.19 154.48,103.96 152.33,103.96 145.97,110.32 143.72,110.32 142.55,109.16 139.05,109.16 136.8,106.91 133.99,106.91 133.45,106.37 128.16,106.37
  BOTTOM w0.102: USOC1.BF6 122.29,106.44 122.49,106.65 v2(122.49,106.79) ; v2(169.97,39.5) 169.82,39.35 169.82,39.17 170.19,38.81 CS30.1
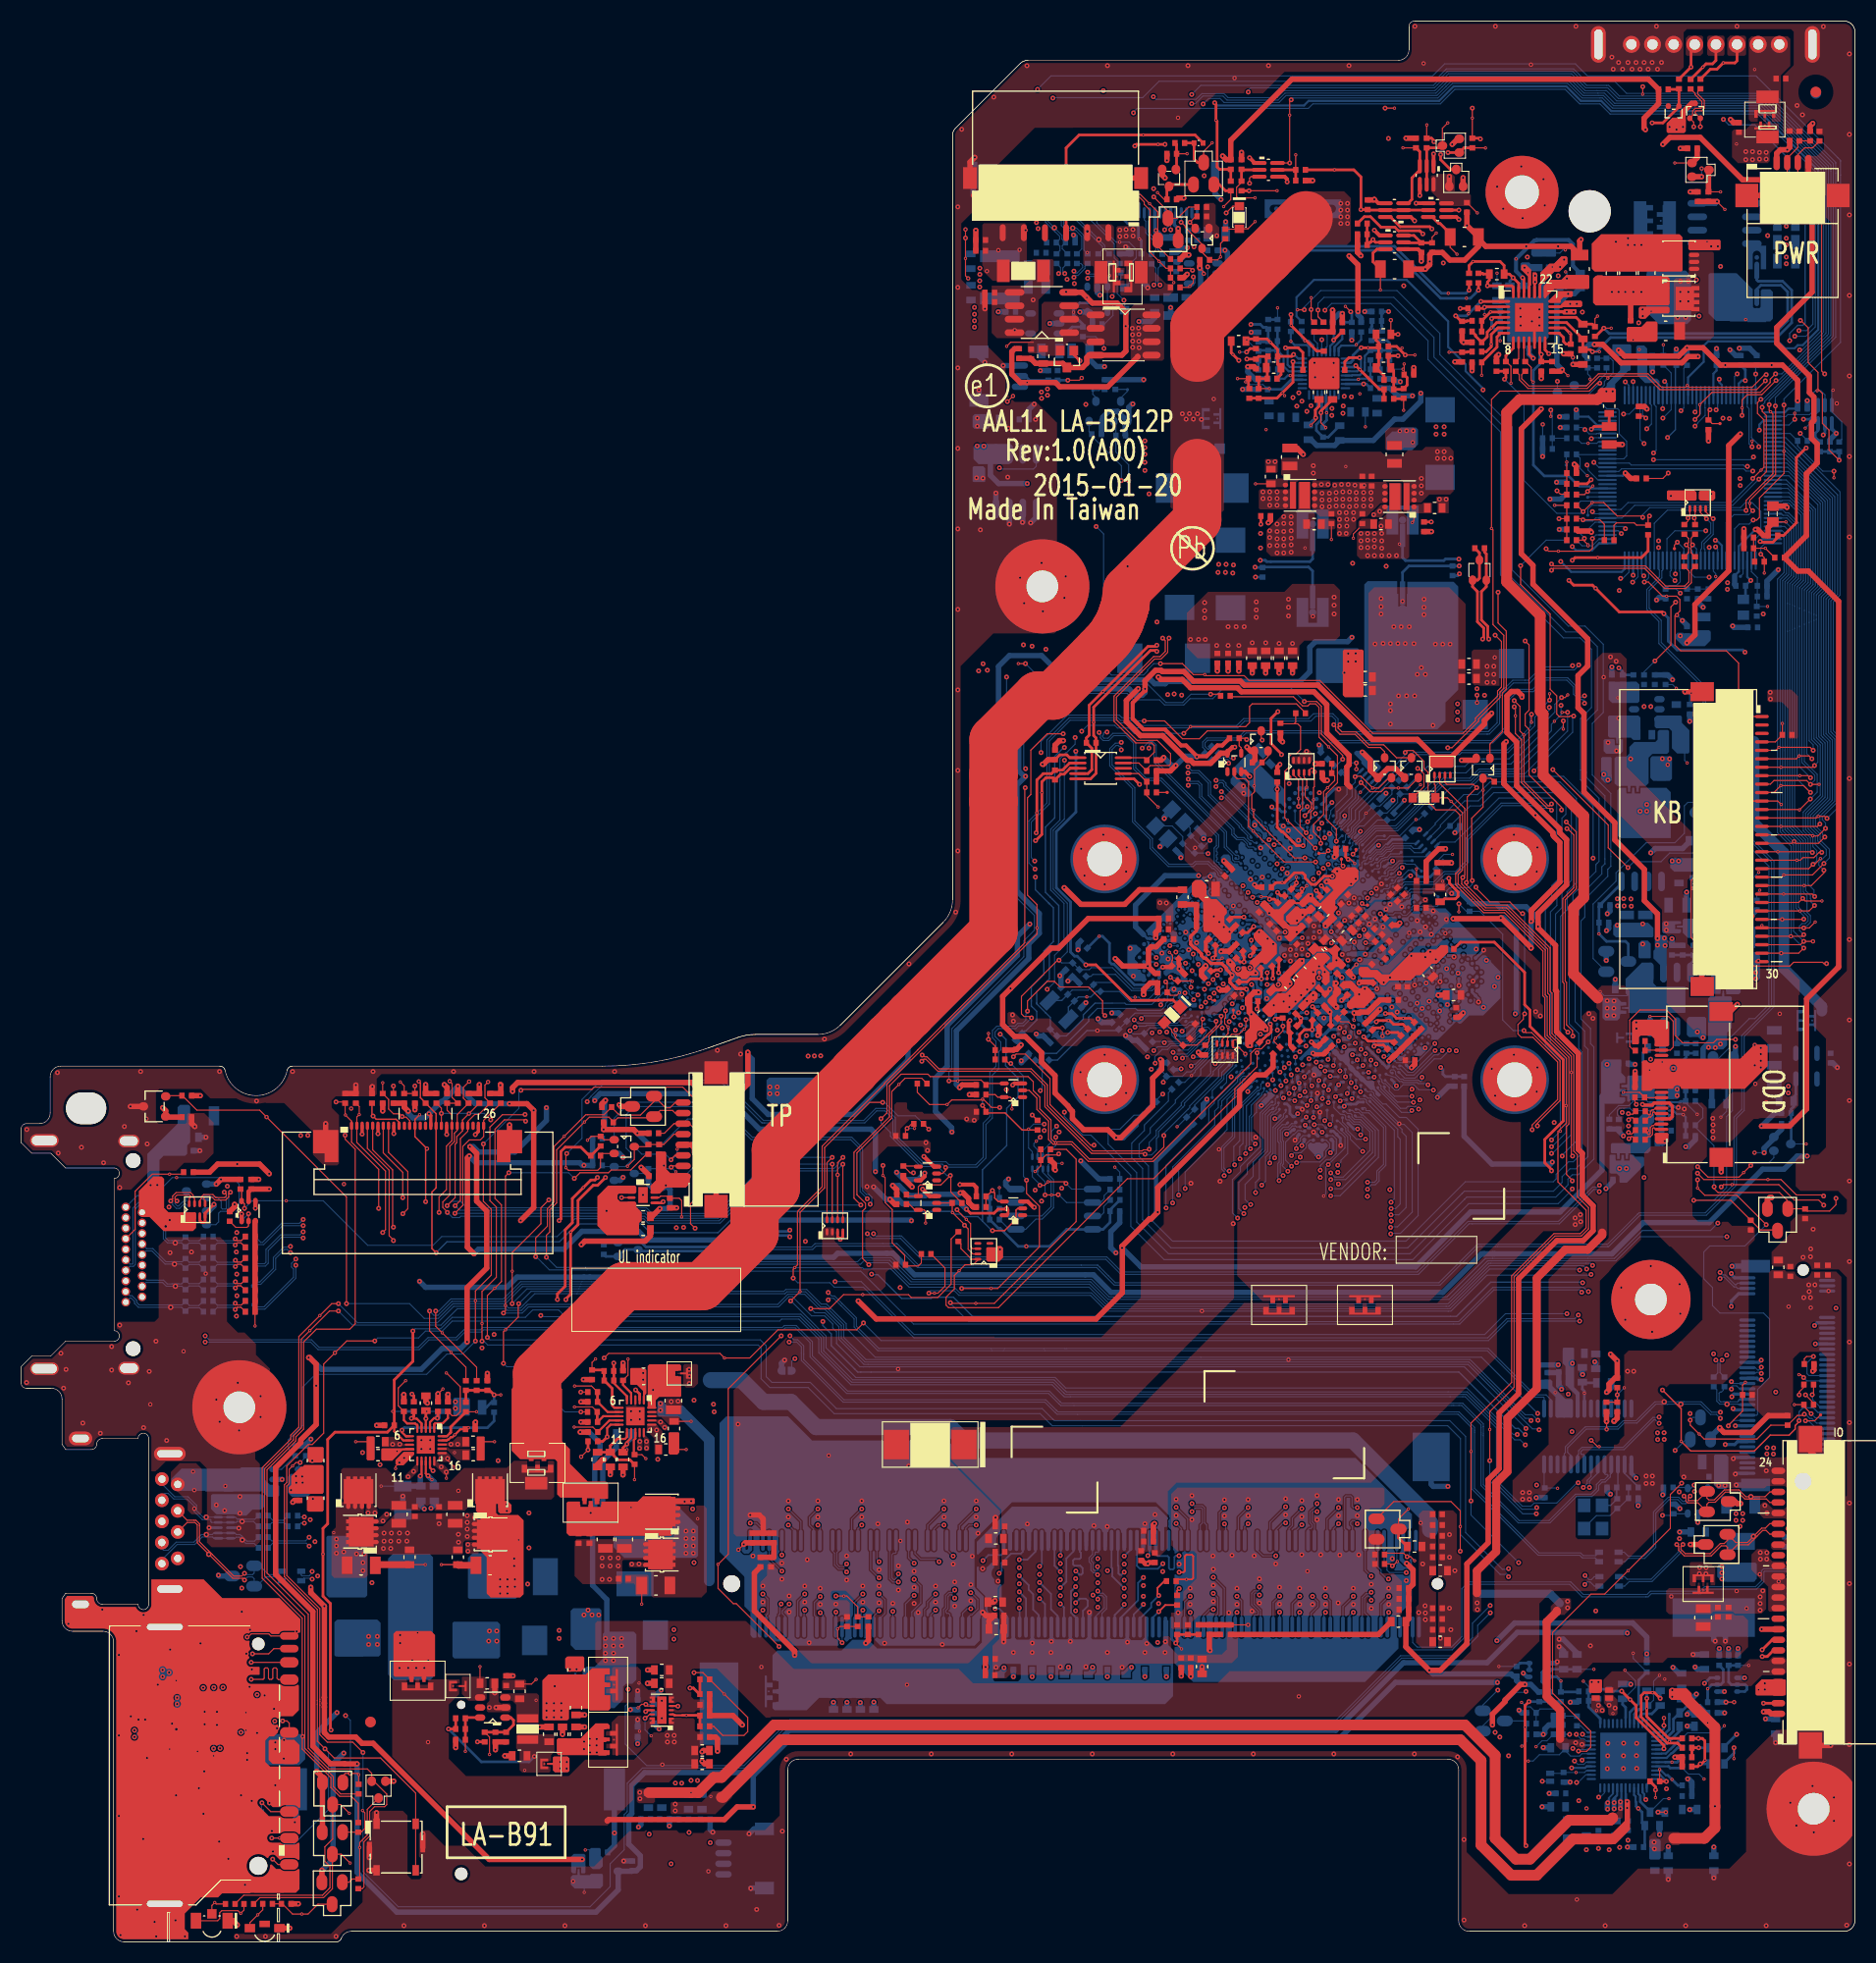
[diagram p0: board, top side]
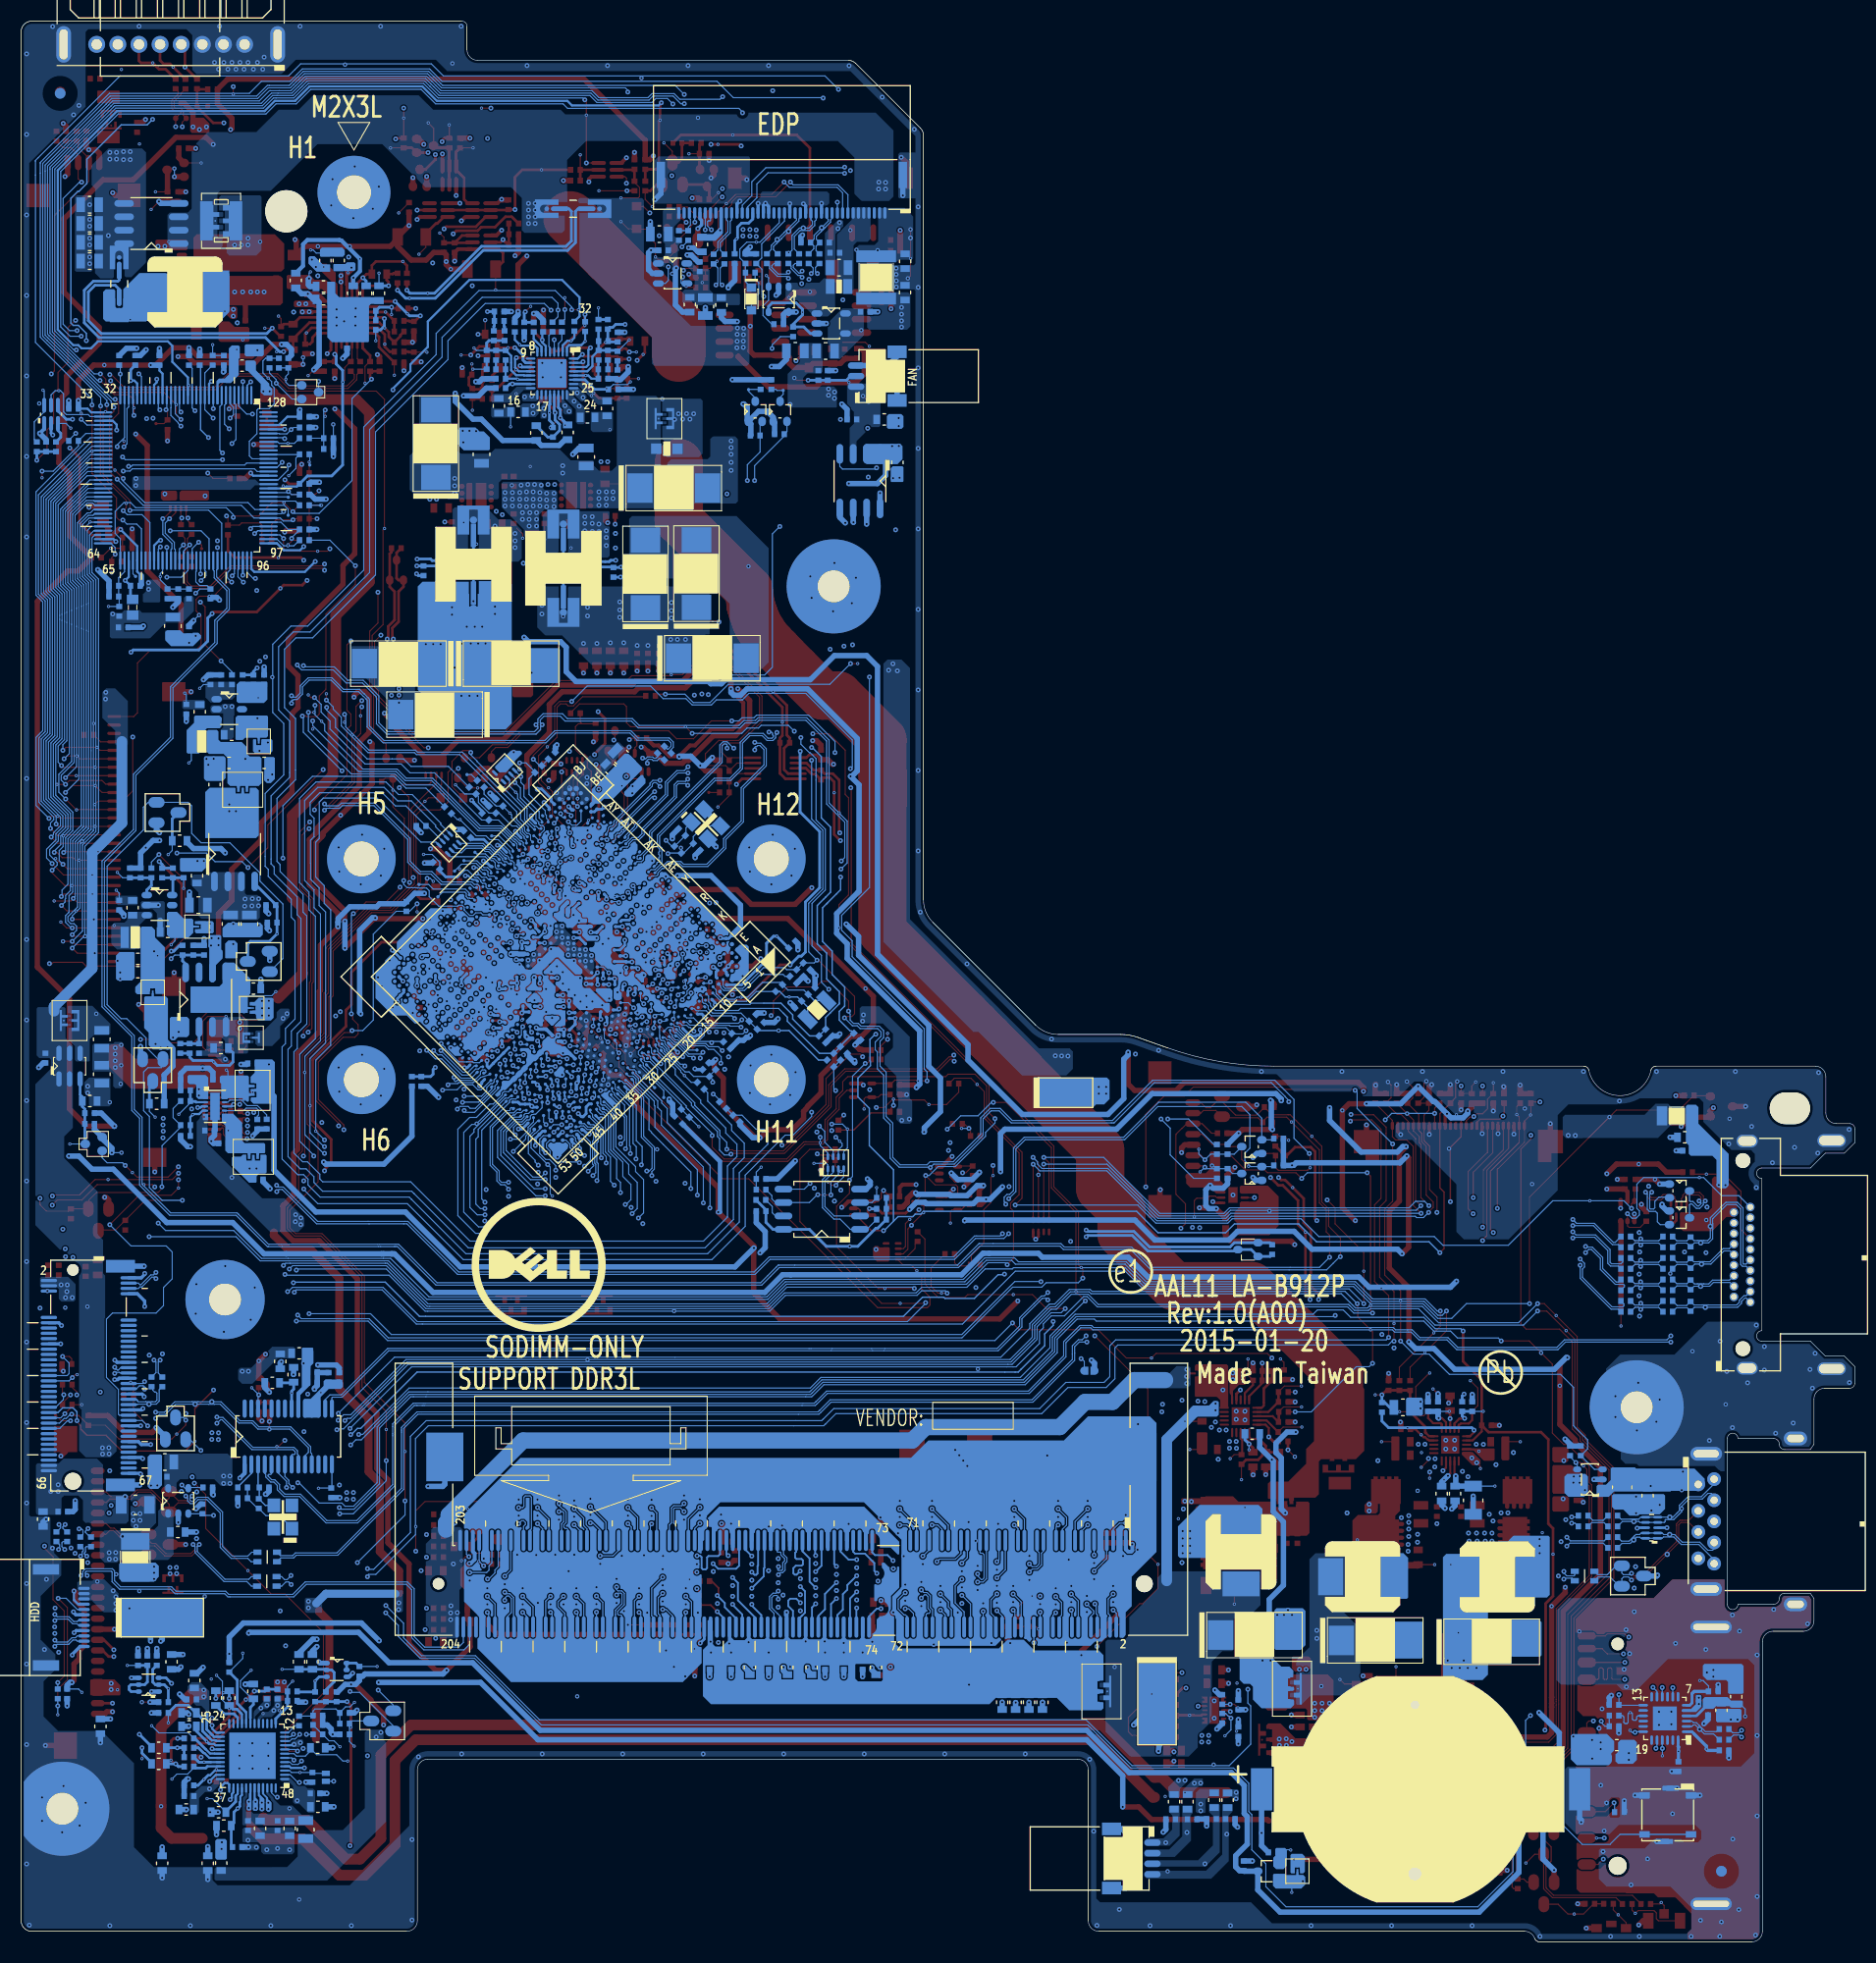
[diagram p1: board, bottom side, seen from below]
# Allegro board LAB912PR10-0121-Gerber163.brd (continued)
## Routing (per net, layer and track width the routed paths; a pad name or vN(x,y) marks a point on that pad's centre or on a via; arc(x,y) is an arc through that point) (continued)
SATA_PTX_DRX_P1: length 2.4
  TOP w0.102: CS8.1 153.99,76.22 154.19,76.22 154.4,76.42 154.4,76.98 154.47,77.05 154.55,77.05 154.69,76.91 JODD1.2
SATA_PTX_DRX_P1_C: length 71.5
  TOP w0.102: CS8.2 152.51,76.21 152.36,76.21 v2(152.16,76.02)
  IN2 w0.102: 124.97,104.95 124.35,105.58 123.34,105.58 123.13,105.36 v2(122.82,105.36)
  IN2 w0.127: 124.97,104.95 125.29,104.63 132.92,104.63 134.35,106.07 137.05,106.07 139.37,108.39 143.02,108.39 144.16,109.54 145.68,109.54 152.01,103.2 152.97,103.2 155.38,100.8 155.38,97.89 156.92,96.35 156.92,85.16 158.56,83.52 158.56,78.37 156.4,76.22 152.37,76.22 v2(152.16,76.02)
  BOTTOM w0.102: USOC1.BD10 122.94,104.72 122.94,105.24 v2(122.82,105.36)
SATA_RCOMPN: length 1.4
  TOP w0.254: RC12.1 122.93,99.14 v2(122.57,99.51)
  BOTTOM w0.254: USOC1.AT18 122.57,98.85 v2(122.57,99.51)
SATA_RCOMPP: length 1.4
  TOP w0.254: v2(123.05,99.96) 123.44,99.58 RC12.2
  BOTTOM w0.254: v2(123.05,99.96) 123.05,99.68 123.11,99.62 USOC1.AU18
SD3_RCOMP: length 9.4
  BOTTOM w0.102: RC59.1 133.93,102.2 134.65,102.93 v1(135.46,102.93) ; USOC1.BF26 128.99,99.67 129.4,99.67 129.55,99.83 129.55,100.1 129.64,100.18 129.88,100.18 130.05,100.35 130.05,100.47 130.06,100.49 130.06,100.49 130.29,100.71 130.29,100.71 130.33,100.75 130.6,100.75 131.28,101.43 131.65,101.43
  BOTTOM w0.254: 131.65,101.43 132.28,100.81 133.36,100.81 133.93,101.37 RC59.1
SD_CD#: length 11.1
  TOP w0.102: v2(21.9,27.26) 23.42,27.26 23.92,27.76 JREAD.10
  IN2 w0.127: v2(21.9,27.26) 22.41,26.75 22.41,23.48 v2(22.33,23.4)
  BOTTOM w0.102: v2(22.33,23.4) CR9.1 22.29,22.4 UR1.13
SD_CMD: length 15.9
  TOP w0.102: JREAD.2 23.63,12.33 v2(22.79,13.17)
  IN2 w0.127: v2(20.81,19.83) 20.81,20.79 20.68,20.91 20.08,20.91 19.96,20.79 19.96,19.74 20.81,18.89 20.81,15.15 v2(22.79,13.17)
  BOTTOM w0.102: UR1.18 20.74,19.9 v2(20.81,19.83) 21.09,19.83 v1(21.28,20.02) ; v2(22.79,13.17) 22.74,13.11 CR11.1
SD_D0: length 14
  TOP w0.102: v2(21.77,24.85) 22.9,24.85 23,24.95 23,25.83 23.1,25.93 23.31,25.93 23.41,25.83 23.41,24.95 23.51,24.85 23.71,24.85 23.82,24.95 23.82,25.83 23.92,25.93 24.12,25.93 24.22,25.83 24.22,24.95 24.35,24.82 JREAD.7
  IN2 w0.127: v2(19.11,24.09) 19.87,24.85 20.26,24.85 20.38,24.72 20.38,24.07 20.51,23.95 20.76,23.95 20.89,24.07 20.89,25.26 21.02,25.38 21.65,25.38 21.77,25.26 v2(21.77,24.85)
  BOTTOM w0.102: v2(19.11,24.09) 18.73,23.71 UR1.11
SD_D1: length 14.5
  TOP w0.102: JREAD.8 v2(21.77,26.45)
  IN2 w0.127: v2(21.77,26.45) 21.77,26.65 21.65,26.78 20.96,26.78 20.83,26.65 20.83,26.3 20.66,26.12 20.41,26.12 19.84,26.69 19.66,26.69 19.48,26.51 19.48,26.33 20.04,25.77 20.04,25.59 19.86,25.41 19.68,25.41 19.12,25.97 18.94,25.97 18.77,25.79 18.77,25.61 19.25,25.13 19.25,24.95 19.07,24.77 18.89,24.77 18.41,25.25 18.23,25.25 18.05,25.07 18.05,24.89 18.46,24.48 18.46,24.3 v2(18.23,24.07)
  BOTTOM w0.102: UR1.10 v2(18.23,24.07)
SD_D2: length 16.1
  TOP w0.102: JREAD.9 24.31,7.32 v2(23.81,7.83)
  IN2 w0.127: v2(23.81,7.83) 18.23,13.41 18.23,18.29 v2(18.22,18.31)
  BOTTOM w0.102: v1(18.22,17.61) v2(18.22,18.31) 18.23,18.32 UR1.21
SERIRQ: length 185.4
  TOP w0.102: v2(95.05,120.99) v1(94.38,120.99) ; R23.1 113.37,118.09 v2(112.58,118.09)
  IN1 w0.127: v2(105.28,173.12) 105.96,172.44 105.96,169.88 102.42,166.34 102.42,157.68 103.69,156.41 103.69,155.52 102.9,154.73 102.9,150.38 102.09,149.56 102.09,145.39 100.07,143.37 100.07,124.05 98.9,122.88 96.69,122.88 95.05,121.24 v2(95.05,120.99)
  IN2 w0.127: v2(152.56,147.68) 152.56,149.42 154.74,151.6 166.68,151.6 167.06,151.98 v2(167.86,151.98)
  BOTTOM w0.102: v2(105.28,173.12) 105.28,173.2 105.61,173.54 121.82,173.54 122.26,173.97 134.32,173.97 135.69,175.34 146.13,175.34 147.5,173.97 149.42,173.97 150.39,173.01 164.36,173.01 169.81,167.56 169.81,152.87 168.92,151.98 v2(167.86,151.98) ; v2(112.58,118.09) 110.72,118.09 109.94,117.31 108.35,117.31 106.62,119.03 97.01,119.03 v2(95.05,120.99) ; UE1.3 v2(152.56,147.68)
SIO_SLP_S3#: length 201.9
  TOP w0.102: R24.1 98.91,75.01 99.85,74.08 99.85,68.18 92.11,60.43 v1(90.35,60.43) 88.02,60.43 87.97,60.49 87.97,60.5 v2(87.95,60.5) ; CE27.1 153.59,144.41 v2(153.77,144.23)
  IN1 w0.127: v2(148.33,61.55) 152.71,57.17 156.35,57.17 163.63,64.45 163.63,68.04 164.69,69.1 164.69,72.07 165.83,73.21 165.83,76.43 165.51,76.74 165.51,81.95 165.78,82.22 165.78,86.94 166.39,87.55 166.39,91.62 166.39,91.62 166.39,93.73 166.39,100.28 164.61,102.06 164.61,111.82 161.47,114.96 161.47,119.31 158.75,122.03 158.69,122.03 156.34,122.03 154.97,123.4 153.52,123.4 150.83,126.09 150.83,129.14 154.11,132.42 154.11,133.65 154.91,134.45 154.91,143.09 v2(153.77,144.23)
  BOTTOM w0.102: UE1.6 153.76,145.57 153.46,145.26 153.46,144.54 v2(153.77,144.23) ; v2(148.33,61.55) 148.27,61.55 147.87,61.95 139.29,61.95 136.05,58.71 135.48,58.71 89.67,58.71 87.97,60.41 87.97,60.5 v2(87.95,60.5)
SIO_SLP_S4#: length 200.4
  TOP w0.102: v2(93.67,83.14) 93.48,83.14 R25.1 ; v2(95.15,72.09) 95.15,70.85 96.37,69.63 96.37,65.79 92.42,61.84 v1(91.8,61.84) v2(89.02,61.84)
  IN1 w0.127: v2(148,143.14) 148,141.83 150.26,139.57 150.26,131.09 149.17,129.99 149.17,125.52 154.18,120.51 158.06,120.51 159.95,118.62 159.95,114.33 163.09,111.19 163.09,103.15 160.5,100.57 160.09,100.57 159.05,100.57 158.35,99.87 158.35,91.63 163.72,86.25 163.72,83.25 162.49,82.02 162.49,69.07 162.11,68.69 162.11,66.45 161.73,66.07 149.95,66.07 148.03,64.15 148.03,63.82 v2(148.16,63.69)
  BOTTOM w0.102: v2(148.16,63.69) 147.85,64 138.98,64 135.13,60.16 134.88,60.16 134.88,60.16 102.89,60.16 101.07,61.97 89.14,61.97 v2(89.02,61.84) ; CE28.1 147.76,143.34 147.95,143.15 147.98,143.15 v2(148,143.14) 148.41,142.73 149.08,142.73 149.12,142.77 UE1.123 ; v2(95.15,72.09) 95.15,72.16 94.86,72.45 94.86,81.94 v2(93.67,83.14)
SLEEVE: length 10.9
  IN2 w0.254: v2(150.86,22.13) 153.19,24.47 v2(159.31,24.47)
  BOTTOM w0.254: QA1.3 159.84,24.99 v2(159.31,24.47)
  vias: v1(150.65,21.61) v2(150.29,22.4)
SLEEVE_R:
  vias: v1(155.56,24.87)
SNB_3V: length 4.8
  TOP w0.102: PC114.1 v1(38.25,35.71)
  TOP w0.635: PR109.2 33.58,35.71 PC114.1
SNB_5V: length 3.3
  TOP w0.127: PC115.1 v1(39.77,35.71)
  TOP w0.635: PC115.1 41.4,35.64 PR110.2
SNB_CHG:
  vias: v1(152.57,151.63)
SOC_KBRST#: length 30.2
  TOP w0.127: v2(90.99,79.17) 90.99,79.13 91.22,78.9 91.22,78.67 R3.2 91.43,78.46 93.13,78.46 94.75,76.84 R22.1
  IN1 w0.127: v2(105.42,86.58) 105.25,86.75 104.08,86.75 103.82,86.49 103.48,86.49 102.99,86 100.39,86 97.27,82.89 96.46,82.89 93.5,79.93 91.99,79.93 91.23,79.17 90.99,79.17 v2(90.99,79.17)
  BOTTOM w0.102: USOC1.B18 110.56,87.06 110.27,86.77 109.51,86.77 109.49,86.75 106.52,86.75 106.45,86.67 105.5,86.67 105.48,86.64
  BOTTOM w0.127: 105.48,86.64 v2(105.42,86.58) ; v2(90.99,79.17) v1(90.99,79.76)
SOC_LID_OUT#: length 49
  TOP w0.102: R26.1 85.2,64.27 84.91,63.98 83.81,63.98 R4.2 83.62,64.17 83.62,64.98 82.44,66.16 82.44,69.31 81.77,69.98 81.77,72.33 v1(81.57,72.54) v2(81.57,73.49)
  IN1 w0.102: 104.75,87.37 105.24,87.37 v2(105.34,87.27)
  IN1 w0.127: v2(81.57,73.49) 84.38,76.31 84.38,77 86.56,79.17 87.18,79.17 88.21,80.19 88.21,80.92 89.11,81.82 94.19,81.82 94.8,82.43 95.77,83.4 96.99,83.4 100.1,86.51 102.78,86.51 103.27,87 103.61,87 103.99,87.37 104.75,87.37
  BOTTOM w0.102: 110.75,87.66 110.55,87.45 109.91,87.45 109.41,86.95 105.66,86.95 105.34,87.27 v2(105.34,87.27)
SOC_ODD_DA#: length 22.7
  TOP w0.102: RP63.4 121.92,110.9 122.1,111.08 122.23,111.08 122.4,110.92 v2(122.4,110.74) 122.4,109.35 122.31,109.27 v1(122.31,108.1) 122.31,107.32 122.31,107.31 122.31,107.21 122.06,106.95 122.06,106.33 v2(121.75,106.03) ; v2(132.17,111.07) 132.25,111.07 132.77,110.55 132.77,109.35 DX2.2
  IN2 w0.127: v2(132.17,111.07) 132.14,111.03 130.72,111.03 129.91,111.84 127.06,111.84 126.87,112.04 125.78,112.04 124.99,111.25 123.11,111.25 122.84,110.98 122.64,110.98 v2(122.4,110.74)
  BOTTOM w0.102: USOC1.BE3 120.56,106.08 120.94,105.69 121.42,105.69 v2(121.75,106.03)
SOC_SATALED#: length 270.3
  TOP w0.102: v2(30.66,76.35) 30.66,75.97 31.62,75.02 31.62,58.5 31.11,58 27.95,58 26.74,56.79 26.74,48.54 26,47.8 26,47.42 23.27,44.69 23.27,34.91 27.17,31.01 27.17,18.33 29.14,16.37 32.77,16.37 33.18,15.96 Q6103.3 33.38,15.21 34.6,13.99 34.6,12.99 34.41,12.8 33.45,12.8 32.99,12.34 32.99,10.02 32.44,9.47 32.44,5.19 32.29,5.04 R6106.1 ; v2(135.02,113.03) 135.42,113.03 137.94,115.55 137.94,115.75 139.96,117.77 139.96,118.3 140.33,118.67 140.33,123.66 139.3,124.68 139.3,133.64 v1(139.16,133.78) 139.16,145.99 139.95,146.78 148.41,146.78 149.15,147.53 v2(149.41,147.53) ; v2(106.29,115.57) 108.22,115.57 109.91,113.88 111.52,113.88 112.26,114.62 QC2.1 117.36,113.85 v2(117.46,113.75)
  IN1 w0.127: v2(30.66,76.35) 31.74,76.35 32.06,76.03 38.54,76.03 39.35,76.84 43.82,76.84 45.5,75.17 57.56,75.17 59.23,76.84 72.85,76.84 77.18,81.18 78.36,82.36 78.36,82.45 78.37,82.45 78.37,82.83 91.26,95.72 91.26,96.78 91.26,106.07 94.85,109.66 94.99,109.66 95.78,110.45 95.78,111.82 v2(96.53,112.57)
  IN2 w0.127: v2(117.46,113.75) 117.8,114.09 120.97,114.09 122.61,114.09 122.9,113.8 123.05,113.8 123.14,113.71 131.18,113.71 131.91,112.99 134.98,112.99 v2(135.02,113.03)
  BOTTOM w0.102: v2(96.53,112.57) 96.53,113.62 99.02,116.11 103.94,116.11 104.2,115.86 105.33,115.86 105.62,115.57 v2(106.29,115.57) ; Q6105.3 147.91,146.03 v2(149.41,147.53) 149.41,147.86 150.04,148.5 RX5.2
SOC_SCI#: length 17.3
  TOP w0.102: R8.2 119.24,115.29 120.47,115.29 ; 120.47,115.29 120.82,115.29 121.09,115.02 121.09,112.86 120.64,112.42 120.22,112.42 119.97,112.16 119.97,111.17 119.59,110.8 119.59,106.41 v1(119.85,106.16) v2(122.48,103.53) ; 120.47,115.29 120.63,115.45 R29.1
  BOTTOM w0.102: USOC1.BA12 122.53,103.48 v2(122.48,103.53)
SOC_SERIRQ: length 24
  TOP w0.102: R23.2 114.52,117.85 120.41,117.85 121.28,116.99 121.77,116.99 121.96,117.18 122.5,117.18 122.83,116.85 122.83,114.03 v1(123.75,113.11) 124.58,112.28 124.58,109.71 123.53,108.66 123.53,106.27 124.48,105.32 v2(124.48,104.18)
  BOTTOM w0.102: v2(124.48,104.18) 124.99,104.69 USOC1.BG13
SOC_SMI#: length 33.9
  TOP w0.102: R31.1 84.28,77.43 v2(83.85,77) 83.7,76.84 R7.2
  IN1 w0.102: v2(106.03,87.4) 105.73,87.69 104.43,87.69
  IN1 w0.127: v2(83.85,77) 83.99,77 86.42,79.42 87.08,79.42 87.95,80.3 87.95,81.02 89.01,82.08 94.09,82.08 94.71,82.7 95.66,83.65 96.88,83.65 99.99,86.76 102.67,86.76 103.16,87.25 103.5,87.25 103.94,87.69 104.43,87.69
  BOTTOM w0.102: v2(83.85,77) v1(84.55,77) ; USOC1.C15 109.86,88.34 109.65,88.13 109.46,88.13 108.71,88.13 108.44,87.87 108.23,87.65 106.28,87.65 v2(106.03,87.4)
SOC_SPI_CLK: length 26.3
  IN1 w0.127: v2(96.45,76.16) 96.26,76.35 96.26,77.55 97,78.29 97,78.29 98.34,78.29 98.52,78.11 99.74,78.11 100.2,78.57 103.74,78.57 105.53,80.36 105.53,83.65 106.11,84.23 107.07,84.23 v2(107.19,84.36)
  BOTTOM w0.102: RP67.6 96.2,74.97 95.85,75.32 95.85,75.56 v1(96.08,75.79) v2(96.45,76.16) ; USOC1.C22 112.71,86.18 112.32,86.58 112.06,86.58 111.95,86.56 111.85,86.49 111.83,86.32 111.83,86.22 111.68,86.07 111.6,86.07 111.52,86.07 110.47,85.02 108.74,85.02 108.45,84.73 107.56,84.73 v2(107.19,84.36)
SOC_SPI_CS0#: length 21.7
  IN1 w0.102: v2(109.91,83.65) 109.53,83.27 109.39,83.27 109.33,83.2 108.92,83.2
  IN1 w0.127: 108.92,83.2 108.52,83.2 106.61,81.29 106.61,80 104.16,77.55 100.62,77.55 100.02,76.96 99.28,76.96 98.48,76.16 v2(97.92,76.16)
  BOTTOM w0.102: v2(97.92,76.16) v1(97.92,75.64) 97.92,75.38 97.2,74.66 RP67.8 ; v2(109.91,83.65) 110.06,83.8 110.4,83.8 111.54,84.94 111.76,84.94 112.2,85.38 112.41,85.38 112.63,85.6 USOC1.C23
SOC_SPI_MISO: length 22.1
  IN1 w0.102: 108.54,83.58 109.02,84.06 v2(109.02,84.2)
  IN1 w0.127: 108.54,83.58 106.3,81.33 106.3,80.05 104.06,77.81 100.51,77.81 99.92,77.21 v2(98,77.21)
  BOTTOM w0.102: v2(98,77.21) 97.49,76.7 97.49,75.69 96.7,74.9 RP67.7 ; v2(109.02,84.2) 109.19,84.03 110.34,84.03 111.46,85.15 111.68,85.15 USOC1.B22
SOC_SPI_MOSI: length 24.6
  IN1 w0.127: v2(96.83,77.4) 97.21,77.78 98.13,77.78 98.31,77.6 99.95,77.6 100.41,78.06 103.95,78.06 106.04,80.15 106.04,82.52 106.68,83.16 107.33,83.16 v2(107.33,83.17)
  BOTTOM w0.102: RP67.5 95.7,74.79 95.34,75.14 v1(95.34,76.93) 95.81,77.4 v2(96.83,77.4) ; v2(107.33,83.17) 107.3,83.2 107.3,83.78 107.99,84.48 108.51,84.48 108.85,84.82 110.55,84.82 111.49,85.76 USOC1.A21
SOC_SPKR: length 121.8
  TOP w0.102: v2(137.22,41.74) v1(137.22,46.41) 137.22,49.11 141.06,52.95 141.06,63.03 145.07,67.04 147.56,67.04 148.11,67.59 148.11,69.26 145.45,71.93 145.45,76.7 146.26,77.51 146.26,83.63 144.2,85.69 144.2,89.37 144.02,89.54 144.02,93.78 140.39,97.42 138.41,97.42 135.9,99.92 135.9,99.92 135.77,100.06 135.77,101.13 136.18,101.53 136.18,106.66 135.69,107.15 133.9,107.15 133.15,107.89 133.15,110.7 132.77,111.08 132.77,111.74 131.75,112.76 131.17,112.76 v2(130.99,112.58)
  IN2 w0.127: v2(141.73,35.9) 141.66,35.83 140.58,35.83 140.26,35.52 140.26,29.33 140.67,28.93 140.67,24.75 v2(139.76,23.83)
  BOTTOM w0.102: v2(137.22,41.74) 137.22,40.41 v2(141.73,35.9) ; DA8.3 138.33,22.41 v2(139.76,23.83) ; USOC1.BH12 125,105.29 125.89,106.18 125.89,107.22 130.41,111.73 130.41,111.78 130.98,112.35 130.98,112.57 v2(130.99,112.58)
SOC_SUS_STAT#: length 1.1
  TOP w0.102: v2(112.48,89.38) 112.74,89.11 T8.1
  BOTTOM w0.102: USOC1.G18 112.75,89.11 v2(112.48,89.38)
SOC_TP_INT#: length 96.2
  TOP w0.102: v2(51.63,74.62) 51.56,74.54 v1(51.56,73.27) 51.8,73.03 54.57,73.03 54.83,73.3 RE34.2 55.03,74.62 QE9.3 ; v2(95.24,88.1) 95.24,89.05 97.11,90.91 97.79,90.91 98.32,90.38 101.02,90.38 102.35,89.05 102.35,87.9 v2(102.57,87.68)
  IN1 w0.102: v2(109.87,86.19) 109.87,86.11 109.57,85.81 109.28,85.81 109.14,85.95 109.12,85.95 108.9,86.17 108.9,86.19 108.58,86.51 107.27,86.51 106.41,87.38 106.41,87.55 106.07,87.89 105.64,87.89 105.56,87.97 104.15,87.97
  IN1 w0.127: 104.15,87.97 103.86,87.97 103.4,87.5 102.74,87.5 v2(102.57,87.68)
  BOTTOM w0.102: USOC1.C19 111.2,86.97 110.99,86.76 110.56,86.76 110.35,86.55 110.24,86.55 v2(109.87,86.19) ; v2(51.63,74.62) 51.64,74.62 53.08,76.06 53.08,79.73 54.9,81.55 66.45,81.55 70.26,77.74 79.74,77.74 80.88,78.89 81.84,78.89 82.73,78 82.73,76.44 85.33,73.84 87.53,73.84 87.82,73.55 90.35,73.55 91.05,74.25 91.05,77.49 91.69,78.13 91.69,82.32 92.26,82.89 92.26,85.25 91.93,85.58 91.93,86.27 92.34,86.67 94.05,86.67 94.32,86.94 94.77,86.94 95.09,87.26 95.09,87.82 95.24,87.97 v2(95.24,88.1)
SOC_TS_INT#: length 146.8
  TOP w0.102: RX41.2 111.17,163.32 v2(110.61,162.76) 111.12,162.25 QE12.3 ; v2(142.35,123.13) 142.72,122.76 142.72,116.58 142.35,116.21 142.35,115.13 142.72,114.76 142.72,110.45 145.79,107.38 v2(145.79,107.15) ; v2(139.5,123.68) 140.1,123.08 140.1,118.76 139.73,118.4 139.73,117.92 137.64,115.82 137.64,115.57 136.47,114.4 127.91,114.4 122.92,119.39 116.21,119.39 115.75,119.85 112.12,119.85 v1(112.02,119.95) 110.94,119.95 109.9,120.99 v2(107.83,120.99)
  IN1 w0.127: v2(142.35,123.13) 142.27,123.21 139.97,123.21 v2(139.5,123.68) ; v2(101.75,133.97) 101.75,143 103.49,144.75 103.49,146.94 106.57,150.02 106.57,154.02 108.59,156.04 108.59,160.45 110.61,162.47 v2(110.61,162.76)
  IN2 w0.102: v2(127.25,94.57) 127.25,94.64 127.16,94.72 127.16,95.27 127.54,95.65 127.81,95.65 131.22,99.07 133.08,99.07
  IN2 w0.127: v2(145.79,107.15) 146.81,106.13 146.81,103.37 142.46,99.02 138.23,99.02 137.05,97.84 135.79,97.84 135.12,98.51 134.68,98.51 134.12,99.07 133.08,99.07
  BOTTOM w0.102: v2(127.25,94.57) 127.32,94.5 USOC1.AU32 ; v2(101.75,133.97) 102.45,133.26 102.45,120.64 103.18,119.91 106.23,119.91 106.61,120.29 106.61,120.4 107.19,120.99 v2(107.83,120.99)
SPI_CLK: length 9.9
  TOP w0.102: v2(96.91,70.7) v1(97.52,70.7) 98.13,70.7 v2(98.15,70.72)
  BOTTOM w0.102: RP67.3 96.2,72.64 96.91,71.94 v2(96.91,70.7) ; RC39.1 102.5,70.63 102.5,70.33 102.15,69.98 UC8.6 98.95,69.98 98.2,70.72 v2(98.15,70.72)
SPI_CS0#: length 12
  BOTTOM w0.102: v1(98.52,73.69) 97.34,73.69 97.2,73.54 RP67.1 97.2,72.65 97.71,72.14 97.71,69.49 96.63,68.41 96.04,68.41 95.07,67.44 UC8.1 93.51,67.44 RC36.2
SPI_HOLD#: length 2.7
  BOTTOM w0.102: RC37.2 102.46,69.61 102.46,69.01 102.16,68.71 UC8.7
SPI_MISO: length 7.6
  BOTTOM w0.102: RP67.2 96.7,72.83 97.48,72.05 97.48,69.58 96.6,68.71 UC8.2
SPI_MOSI: length 7.3
  TOP w0.102: v2(98.89,71.79) 98.74,71.94 v1(97.19,71.94) 96.86,71.61 v2(96.42,71.61)
  BOTTOM w0.102: v2(96.42,71.61) 96.42,71.69 95.7,72.41 RP67.4 ; v2(98.89,71.79) 99.43,71.25 UC8.5
SPI_WP#: length 2.7
  BOTTOM w0.102: UC8.3 93.03,69.98 RC38.2 v1(92.58,71.39)
SPK_L+_CONN:
  vias: v2(61.51,7.39)
SPK_L-_CONN:
  vias: v2(59.44,10.19)
SPK_R+_CONN:
  vias: v2(65.22,9.39)
SPK_R-_CONN:
  vias: v2(63.21,10.36)
SPOK: length 310.9
  TOP w0.102: v2(156.58,126.8) 156.14,126.36 156.14,122.77 154.62,121.24 v2(154.63,121.24)
  TOP w0.203: PU100.7 36.17,47.46 35.31,48.32 PR106.2
  TOP w0.254: PR400.1 v2(43.19,18.93) ; v2(29.33,20.05) 29.27,20.11 29.27,32.02 28.57,32.72 v1(28.57,36.7) 28.57,39.14 29.01,39.58 29.01,47.56 29.7,48.24 34.66,48.24 PR106.2 35.31,53.18 37.08,54.95 v2(37.08,57.82)
  IN1 w0.127: v2(142.36,47.04) 142.64,46.76 144.47,46.76 146.51,48.79 148.74,48.79 150.09,50.15 153.69,50.15 154.26,50.72 155.42,50.72 157.37,52.67 157.37,53.82 161.36,57.82 163.73,57.82 167.51,61.6 167.51,66.6 168.33,67.42 168.33,70.7 169.79,72.16 169.79,77.97 168.94,78.82 168.94,79.26 168.94,85.45 169.22,85.73 169.22,92.79 169.86,93.43 169.86,93.53 170.11,93.79 170.11,97.52 170.61,98.02 170.61,99.6 169.35,100.86 169.35,101.28 167.4,103.22 167.4,120.39 163.67,124.12 162.03,124.12 162.03,124.12 160.75,124.12 158.07,126.8 v2(156.58,126.8) 156.58,128.21 158.76,130.39 158.76,134.94 158.01,135.7 158.01,144.38 v2(158.43,144.8)
  IN2 w0.254: v2(43.19,18.93) 42.49,19.63 40.2,19.63 39.78,20.05 v2(29.33,20.05)
  BOTTOM w0.102: PR308.1 153.6,120.21 v2(154.63,121.24) ; UE1.18 158.56,144.94 v2(158.43,144.8) ; v2(37.08,57.82) 37.29,58.03 39.72,58.03 40.8,59.11 47.72,59.11 48.42,59.81 50.87,59.81 51.27,59.41 73.79,59.41 75.95,57.25 75.95,55.95 78.71,53.2 97.76,53.2 98.77,52.19 98.78,52.19 98.92,52.05 135.05,52.05 136.87,52.05 140.09,48.84 140.09,48.79 141.36,47.52 141.88,47.52 v2(142.36,47.04)
SUSCLK_R: length 3.2
  TOP w0.102: v2(169.51,51.79) 169.64,51.91 RM8.1
  BOTTOM w0.102: v2(169.51,51.79) 169.55,51.75 169.55,51.33 170.28,50.6 JNGFF.42
SUSP: length 143.2
  TOP w0.102: v2(158.29,70.19) 161.8,70.19 R10.2 164.61,67.38 166.16,67.38 Q8.1 ; v2(136.2,36.98) v1(136.2,39.31) 136.2,40.8 135.32,41.68 129.91,41.68 Q2307.2
  IN1 w0.127: v2(158.29,70.19) 158.17,70.06 157.94,70.06 157.93,70.06 148.57,70.06 148.56,70.06 146.18,70.06 144.7,68.58 144.7,53.06 139.82,48.18 139.82,43.87 138.64,42.69 138.64,39.3 136.39,37.05 136.28,37.05 v2(136.2,36.98)
  BOTTOM w0.102: v2(158.29,70.19) 160.2,70.19 161.41,71.39 161.41,78.13 161.96,78.67 161.96,82.34 161.55,82.75 160.29,82.75 160.13,82.91 Q2308.2 160.58,83.55 161.73,84.69 161.73,85.56 163.56,87.39 164.09,87.39 165.41,88.71 165.41,101.81 161.98,105.24 161.98,107.4 161.52,107.86 Q71.2 157.74,107.86 157.41,107.53 157.41,104.92 156.52,104.03 153.79,104.03 150.95,101.19 150.95,100.4 148.77,98.23 148.77,93.07 Q70.2
SUSP#: length 359.5
  TOP w0.102: v2(52.97,52.04) PR208.1 ; R927.2 65.54,20.4 66.4,19.54 68.41,19.54 68.76,19.9 68.76,21.24 v1(66.55,23.46) R926.1 64.52,25.48 v2(63.68,25.48) ; v2(171.76,70.38) 171.76,69.77 171.16,69.17 169.04,69.17 R16.1 168.83,69.39 Q8.2 167.13,69.46 167.13,70.22 166.42,70.92 160.6,70.92 160.24,71.28 160.24,71.46 v2(160.23,71.47) ; v2(160.51,102.92) 158.04,100.45 158.04,95.07 v2(159.34,93.77) 159.33,93.77 160.74,92.36 167.39,92.36 167.75,92.72 170.5,92.72 170.62,92.59 v2(170.87,92.59)
  IN1 w0.127: v2(49.18,59.29) 49.38,59.29 52.42,56.26 52.42,52.59 v2(52.97,52.04) 53.35,52.04 54.16,52.85 54.16,55.65 54.98,56.47 60.7,56.47 62.35,54.82 62.35,51.77 65.46,48.66 65.46,37.8 64.71,37.05 64.71,31.35 63.87,30.51 63.87,25.67 v2(63.68,25.48) ; v2(163.38,139.66) 163.12,139.66 162.01,138.54 162.01,130.49 162.49,130.01 162.49,126.6 163.95,125.14 164.09,125.14 170.68,118.55 170.68,108.1 171.6,107.18 171.6,100.29 171.88,100.01 171.88,97.6 171.88,93.67 170.87,92.67 v2(170.87,92.59) 170.87,92.54 171.76,91.65 171.76,83.59 171.21,83.04 171.21,71.56 171.7,71.08 171.7,70.44 v2(171.76,70.38) 171.89,70.25 171.89,62.02 165.64,55.77 164.04,55.77 163.19,54.93 163.19,54.72 163.19,48.7 162.26,47.77 160.9,47.77 160.38,47.25 156.25,47.25 154.05,45.05 151.72,45.05 150.1,43.44 147.38,43.44 v2(147.36,43.45)
  BOTTOM w0.102: PR300.1 161.22,102.2 v2(160.51,102.92) ; UE1.116 152.21,139.97 152.39,139.78 163,139.78 163.12,139.66 v2(163.38,139.66) ; v2(49.18,59.29) 49.29,59.18 73.7,59.18 75.72,57.15 75.72,55.86 78.61,52.97 97.67,52.97 98.67,51.96 98.69,51.96 98.83,51.82 99.2,51.82 135.14,51.82 136.52,51.82 136.52,51.82 136.78,51.82 139.86,48.74 139.86,43.46 142.08,41.24 142.9,41.24 143.2,41.54 145.33,41.54 147.25,43.45 v2(147.36,43.45) ; v2(160.23,71.47) 160.21,71.49 160.21,75.36 158.45,77.12 R1056.2 159.16,78.01 159.16,78.87 R1055.2
  BOTTOM w0.254: PR409.1 158.55,94.32 159.1,93.77 v2(159.34,93.77)
SW_1.35VP: length 8.6
  IN1 w1.016: 62.73,39.84 61.59,40.98 61.59,46.68 60.65,47.62
  vias: v1(64.03,40.05) v2(59.51,48.45) v2(60.14,48.45) v2(62.92,38.88) v2(62.92,38.18) v2(62.92,37.49) v2(62.92,36.79) v2(63.62,38.88) v2(63.62,38.18) v2(63.62,37.49) v2(63.62,36.79)
SYSON: length 235
  TOP w0.102: v2(52.98,50.16) PR207.1 ; v2(47.09,60.41) 47.05,60.36 47.05,59.14 v1(45.84,57.93) 45.65,57.74 v2(45.65,54.76) ; v2(155.89,139.02) 155.38,138.51 CE26.1
  IN1 w0.127: v2(155.89,139.02) 155.16,138.3 155.16,134.34 154.36,133.54 154.36,132.31 151.38,129.33 v2(151.38,129.05) 151.67,128.76 151.67,127.42 156.55,122.54 157.43,122.54 157.82,122.54 158.9,122.54 158.9,122.54 158.96,122.54 161.98,119.52 161.98,116.11 165.12,112.98 165.12,102.27 166.9,100.49 166.9,93.52 166.9,93.52 166.9,91.83 166.9,87.02 166.29,86.41 166.29,82.43 166.29,82.01 166.05,81.77 166.05,76.93 166.34,76.64 166.34,73 165.19,71.86 165.19,68.87 164.46,68.13 164.46,64.56 153.41,53.51 149.24,53.51 147.14,51.4 144.91,51.4 v2(143.53,50.02)
  BOTTOM w0.102: v2(52.98,50.16) 51.45,50.16 47.17,54.44 45.97,54.44 v2(45.65,54.76) ; v2(151.38,129.05) 151.58,129.05 152.16,129.64 UE1.95 ; v2(47.09,60.41) 48.26,61.58 52.7,61.58 52.7,61.58 54.38,61.58 54.38,61.58 72.2,61.58 72.38,61.76 74.34,61.76 75.73,60.37 76.22,60.37 78.09,58.51 78.09,58.09 80.83,55.34 111.66,55.34 138.21,55.34 v2(143.53,50.02)
THERMAL_SMB_CK2: length 76.7
  TOP w0.102: v2(108.03,123.4) 108.18,123.26 108.18,123.26 108.29,123.16 108.29,122.15 107.79,121.65 107.18,121.65 103.43,117.91 103.43,115.53 105.48,113.48 107,113.48 107.24,113.24 107.24,112.61 106.53,111.89 R2449.2 106.3,112.08 U2407.10 ; RE22.1 158.07,129.83 158.07,128.63 157.54,128.1 155.55,128.1 154.67,128.97 153.64,130.01 145.01,130.01 v2(144.84,129.83)
  IN2 w0.127: v2(144.84,129.83) 144.67,129.99 144.1,129.99 136.11,122 127.59,122 127.08,122.51 124.69,122.51 123.86,121.69 109.49,121.69 108.26,122.91 108.26,123.17 v2(108.03,123.4)
THERMAL_SMB_DA2: length 79.5
  TOP w0.102: RE23.1 157.84,129.75 157.84,128.73 157.44,128.33 155.64,128.33 154.84,129.14 153.74,130.23 145.01,130.23 v2(144.84,130.41) ; U2407.9 105.78,111.58 R2451.2 106.53,111.01 106.86,111.34 108.64,111.34 108.79,111.48 108.79,112.46 107.52,113.72 105.62,113.72 103.66,115.68 103.66,117.81 107.27,121.42 107.88,121.42 108.51,122.05 108.51,123.27 v2(108.64,123.4)
  IN2 w0.127: v2(108.64,123.4) 108.51,123.27 108.51,123.02 109.59,121.94 123.75,121.94 124.58,122.77 127.18,122.77 127.69,122.26 136,122.26 143.99,130.25 144.67,130.25 v2(144.84,130.41)
TMDS_L_TX0N: length 16.1
  BOTTOM w0.102: JHDMI1.9 10.29,64.16 10.54,64.16 10.59,64.2 10.59,69.46 11.12,70 12.22,70 13.68,68.54 v3(13.68,67.72) 13.68,66.63 13.93,66.38 14.28,66.38 14.29,66.39 14.88,66.39 14.9,66.38 15.22,66.38 RC71.2 15.9,66.36 16.85,66.36 R2360.2
TMDS_L_TX0P: length 16.1
  BOTTOM w0.102: JHDMI1.7 9.89,63.55 10.28,63.94 10.63,63.94 10.8,64.11 10.8,69.38 11.21,69.78 12.13,69.78 13.46,68.45 13.46,68 13.45,67.99 13.45,67.46 13.46,67.45 13.46,66.54 13.84,66.16 v3(14.59,66.16) 15.18,66.16 RC71.1 15.9,66.14 16.85,66.14 R2361.2
TMDS_L_TX1N: length 6.6
  BOTTOM w0.102: R2362.2 16.86,62.3 15.89,62.3 RC72.2 15.18,62.27 14.91,62.27 14.9,62.29 14.3,62.29 14.29,62.27 13.83,62.27 13.47,62.63 11.87,62.63 JHDMI1.6
TMDS_L_TX1P: length 6.6
  BOTTOM w0.102: R2363.2 16.85,62.09 15.91,62.09 RC72.1 15.22,62.06 v3(14.6,62.06) 13.74,62.06 13.38,62.41 11.81,62.41 JHDMI1.4
TMDS_L_TX2N: length 8.5
  BOTTOM w0.102: R2365.2 16.82,60.23 15.93,60.23 RC73.1 15.22,60.28 14.46,60.28 14.45,60.29 13.86,60.29 13.84,60.28 11.19,60.28 10.95,60.52 10.95,60.71 10.5,61.16 10.29,61.16 JHDMI1.3
TMDS_L_TX2P: length 8.4
  BOTTOM w0.102: R2364.2 16.88,60.02 15.87,60.02 RC73.2 15.18,60.07 v3(14.15,60.07) 11.1,60.07 10.73,60.43 10.73,60.62 10.41,60.94 10.29,60.94 JHDMI1.1
TMDS_L_TXCN: length 6.9
  BOTTOM w0.102: JHDMI1.12 11.89,65.62 12.47,65.62 13.71,64.37 14.2,64.37 14.21,64.38 14.81,64.38 14.82,64.37 15.25,64.37 RC70.2 15.89,64.33 16.86,64.33 R2358.2
TMDS_L_TXCP: length 6.9
  BOTTOM w0.102: JHDMI1.10 11.8,65.4 12.38,65.4 13.63,64.15 v3(14.51,64.15) 15.16,64.15 RC70.1 15.91,64.12 16.85,64.12 R2359.2
TMDS_TX0N: length 4.7
  TOP w0.102: R1073.1 20.84,66.38 20.43,66.38 v2(20.27,66.54)
  BOTTOM w0.102: R1073.1 20.84,66.38 20.43,66.38 v2(20.27,66.54) 20.08,66.36 18.57,66.36 R2360.1
TMDS_TX0P: length 4.8
  TOP w0.102: R1074.1 20.8,66.16 20.47,66.16 v2(20.27,65.96)
  BOTTOM w0.102: R1074.1 20.8,66.16 20.47,66.16 v2(20.27,65.96) 20.08,66.14 18.57,66.14 R2361.1
TMDS_TX1N: length 4.7
  TOP w0.102: R1075.1 20.84,62.31 20.44,62.31 v2(20.28,62.48)
  BOTTOM w0.102: R2362.1 18.57,62.29 20.09,62.29 v2(20.28,62.48) 20.44,62.31 20.84,62.31 R1075.1
TMDS_TX1P: length 4.8
  TOP w0.102: R1076.1 20.8,62.1 20.48,62.1 v2(20.28,61.89)
  BOTTOM w0.102: R1076.1 20.8,62.1 20.48,62.1 v2(20.28,61.89) 20.09,62.08 18.57,62.08 R2363.1
TMDS_TX2N: length 4.7
  TOP w0.102: v2(20.27,60.45) 20.43,60.28 20.84,60.28 R1077.1
  BOTTOM w0.102: R2365.1 18.57,60.26 20.08,60.26 v2(20.27,60.45) 20.43,60.28 20.84,60.28 R1077.1
TMDS_TX2P: length 4.8
  TOP w0.102: R1078.1 20.8,60.07 20.47,60.07 v2(20.27,59.86)
  BOTTOM w0.102: R1078.1 20.8,60.07 20.47,60.07 v2(20.27,59.86) 20.08,60.05 18.57,60.05 R2364.1
TMDS_TXCN: length 4.7
  TOP w0.102: v2(20.28,64.51) 20.44,64.35 20.84,64.35 R1071.1
  BOTTOM w0.102: R1071.1 20.84,64.35 20.44,64.35 v2(20.28,64.51) 20.09,64.33 18.57,64.33 R2358.1
TMDS_TXCP: length 4.8
  TOP w0.102: R1072.1 20.8,64.13 20.48,64.13 v2(20.28,63.93)
  BOTTOM w0.102: R1072.1 20.8,64.13 20.48,64.13 v2(20.28,63.93) 20.09,64.11 18.57,64.11 R2359.1
TON_1.35VP: length 4.9
  TOP w0.102: v1(52.34,48.73) 54.11,48.73 PR205.2
  TOP w0.203: PR205.2 55.68,49.35 PU200.9
TOUCH_RST#: length 110.4
  TOP w0.102: v2(166.08,147.79) 164.74,146.44 163.37,146.44 162.87,145.94 v1(162.87,145.19) v2(162.87,144.48)
  IN2 w0.127: v2(111,160.43) 112.2,161.63 112.2,165.34 112.66,165.8 112.66,171.78 110.79,173.65 v2(110.79,173.99)
  BOTTOM w0.102: v2(166.08,147.79) 166.34,147.79 170.82,152.27 170.82,167.8 170.82,167.99 165.05,173.76 164.78,174.02 150.81,174.02 149.85,174.99 149.24,174.99 147.93,174.99 147.33,175.58 146.55,176.36 135.27,176.36 134.76,175.85 133.9,174.99 119.62,174.99 118.96,174.33 114.13,174.33 113.75,174.71 111.84,174.71 111.12,173.99 v2(110.79,173.99) ; RX1.1 110.42,161.02 v2(111,160.43) ; v2(162.87,144.48) 162.96,144.58 UE1.29
TOUCH_RST#_R: length 2.7
  BOTTOM w0.102: JEDP.38 110.3,163.13 110.2,163.03 110.2,162.5 110.39,162.31 110.39,162 RX1.2 RX24.2
TP2_CORE_VCC_S0IX: length 1.9
  TOP w0.102: T112.1 117.93,91.26 117.93,91.26 v2(117.93,91.73)
  BOTTOM w0.102: USOC1.AA22 118.47,92.27 v2(117.93,91.73)
TP_CLK: length 213.5
  TOP w0.102: JTP.8 61.91,79.44 61.41,78.95 60.99,78.95 DE3.3 59.9,79.55 58.6,78.25 56.65,78.25 56.51,78.39 56.48,78.39 55.92,78.95 55.92,78.98 RE9.2 55.16,78.29 53.62,78.29 53.44,78.29 52.86,77.71 v1(51.39,76.25) 50.96,75.82 50.96,75.82 50.45,75.31 50.45,70.04 49.8,69.39 49.8,67.74 48.7,66.63 v2(48.7,64.85)
  BOTTOM w0.102: UE1.87 155.36,129.85 155.28,129.76 155.28,129.11 154.08,127.91 154.08,126.22 155.23,125.08 155.23,122.99 159.42,118.8 159.42,114.02 162.92,110.52 162.92,105.28 165.89,102.3 165.89,88.51 163.07,85.69 163.07,78.69 162.34,77.95 162.34,71.62 159.49,68.77 153.21,68.77 150.24,65.81 150.13,65.81 139.72,65.81 139.53,65.81 139.53,65.81 138.23,65.81 138.23,65.81 138.12,65.81 137.93,65.81 134.28,62.16 103.46,62.16 102.65,62.97 102,63.62 102,63.62 101.8,63.83 100.43,63.83 84.84,63.83 82.8,65.86 82.76,65.86 75.23,65.86 74.91,65.54 68.55,65.54 66.62,63.61 53.54,63.61 53.54,63.61 49.99,63.61 49.38,64.22 48.75,64.85 v2(48.7,64.85)
TP_CORE_V1P05_S4: length 1.1
  TOP w0.102: v2(122.83,91.24) 122.85,91.27 T195.1
  BOTTOM w0.254: USOC1.AF30 123.36,91.24 v2(122.83,91.24)
TP_DATA: length 209.7
  TOP w0.102: v2(49.71,64.8) 49.71,66.89 50.03,67.2 50.03,69.29 50.68,69.94 50.68,74.96 v1(53.32,77.6) 53.78,78.06 55.62,78.06 56.04,77.64 RE10.2 56.47,78 59.78,78 DE3.2 60.48,78.7 61.65,78.7 61.9,78.44 JTP.7
  BOTTOM w0.102: v2(49.71,64.8) 50.68,63.84 53.45,63.84 66.52,63.84 68.46,65.77 74.82,65.77 75.13,66.09 81.55,66.09 82.9,66.09 84.93,64.05 100.33,64.05 100.33,64.05 101.89,64.05 102.09,63.85 102.88,63.07 103.55,62.39 134.19,62.39 137.83,66.04 138.02,66.04 138.13,66.04 139.82,66.04 148.93,66.04 148.93,66.03 150.03,66.03 150.03,66.04 150.15,66.04 152.98,68.87 153.11,69 159.39,69 162.11,71.72 162.11,78.05 162.85,78.79 162.85,85.78 165.66,88.6 165.66,102.2 162.69,105.18 162.69,110.43 159.19,113.93 159.19,118.7 155,122.89 155,124.98 153.85,126.13 153.85,128 155.05,129.2 155.05,129.86 154.96,129.94 UE1.88
TP_EN: length 227.1
  TOP w0.102: v2(49.94,70.23) 49.19,69.48 49.19,67.97 46.48,65.25 v1(46.48,63.48) v2(46.48,60.41) ; UE4.3 v2(56.83,70.45)
  IN1 w0.127: v2(147.69,61.49) 152.27,56.91 156.45,56.91 164.01,64.47 164.01,68.06 164.94,68.99 164.94,71.96 166.08,73.11 166.08,76.53 165.79,76.82 165.79,81.87 166.03,82.12 166.03,82.33 166.03,86.74 166.64,87.35 166.64,91.73 166.64,100.39 164.86,102.17 164.86,112.87 161.73,116.01 161.73,119.41 158.86,122.28 158.8,122.28 156.44,122.28 155.07,123.66 154.61,123.66 151.25,127.01 v2(151.25,127.91)
  IN2 w0.127: v2(151.25,127.91) 155.38,127.91 156.32,128.85 v2(156.52,128.85) ; v2(56.83,70.45) 56.61,70.23 v2(49.94,70.23)
  BOTTOM w0.102: v2(147.69,61.49) 147.69,61.53 147.5,61.72 139.38,61.72 136.15,58.48 135.57,58.48 84.46,58.48 79.46,63.48 69.04,63.48 67.5,61.94 67.37,61.81 54.29,61.81 47.87,61.81 v2(46.48,60.41) ; UE1.85 156.16,129.8 156.06,129.7 156.06,129.31 v2(156.52,128.85)
TP_INT#: length 7.2
  TOP w0.102: v1(57.38,73.41) 58.03,74.06 QE9.1 59.16,75.27 RE29.2 RE20.2 60.81,75.47 61.79,76.44 JTP.5
TS_EN: length 116.4
  TOP w0.102: v2(166.05,148.41) 166.05,148.42 165.54,147.91 165.54,147.59 164.61,146.67 160.04,146.67 v1(158.87,145.5) 158.87,144.55 158.43,144.1 v2(158.42,144.1)
  IN2 w0.127: v2(112.3,158.54) 112.71,158.95 112.71,165.13 113.16,165.59 113.16,172.66 v2(111.87,173.96)
  BOTTOM w0.102: v2(112.3,158.54) 112.3,157.26 112.59,156.97 UX3.3 ; UE1.19 158.96,144.64 v2(158.42,144.1) ; v2(111.87,173.96) 112.39,174.48 113.47,174.48 113.85,174.1 119.06,174.1 119.72,174.76 133.99,174.76 134.72,175.49 135.37,176.13 146.46,176.13 146.97,175.62 146.97,175.62 147.1,175.49 147.83,174.76 149.33,174.76 149.75,174.76 150.72,173.79 164.69,173.79 164.82,173.66 170.59,167.89 170.59,152.37 166.64,148.41 v2(166.05,148.41)
TS_INT#: length 8.6
  TOP w0.102: R5205.1 113.52,160.75 v1(113.52,159.48) 113.24,159.2 RX42.2 111.77,159.91 QE12.1 111.77,160.68 110.18,162.26 110.18,162.39 109.8,162.77 v2(109.78,162.77)
  BOTTOM w0.102: JEDP.37 109.8,162.78 v2(109.78,162.77)
TXE_DBG: length 32.2
  TOP w0.102: v2(139.78,127.74) 139.78,124.84 140.56,124.06 140.56,118.57 140.19,118.21 140.19,114.55 139.01,113.37 QC1.2 ; v2(144.33,131.86) 144.56,131.63 v1(145.48,131.63) 148.44,131.63 148.71,131.9 v2(148.71,132.82)
  IN2 w0.127: v2(144.33,131.86) 140.16,131.86 139.78,131.48 v2(139.78,127.74)
  BOTTOM w0.102: UE1.99 149.06,133.17 v2(148.71,132.82)
UG_3V: length 4.3
  TOP w0.102: v1(35.44,44.8) 35.44,45 v2(35.79,45.36)
  IN2 w1.016: 33.2,41.56 33.2,42.82 34.85,44.47
  vias: v2(32.84,40.61) v2(33.48,40.61) v2(36.25,45.8)
UG_5V: length 6.6
  TOP w0.102: v1(41.04,44.92) 40.35,45.6 v2(40.35,45.75)
  IN2 w1.016: 41.36,45.56 45.22,41.7
  vias: v2(39.73,45.73) v2(45.97,41.42) v2(45.97,40.79)
UGATE1: length 11.4
  IN2 w1.016: 134.36,137.63 134.36,138.45 126.9,145.91
  vias: v2(125.22,146.29) v2(125.9,146.24) v2(134.23,136.55) v2(134.87,136.55)
UGATE1-1: length 1.1
  TOP w0.102: 131.82,135.36 131.82,134.5 v1(131.67,134.35)
UGATEG1: length 5
  IN2 w1.016: 119.37,145.75 118.55,144.93 118.55,141.12
  vias: v2(118.04,140.1) v2(118.67,140.1) v2(120.37,146.17) v2(120.92,146.62)
UGATEG1-1: length 1.5
  TOP w0.102: PR506.2 v1(116.82,138.01)
USB3_REXT0: length 2.3
  TOP w0.381: v2(112.38,93.56) 112.38,93.6 112.13,93.85 112.13,94.65 RC40.1
  BOTTOM w0.254: USOC1.M12 112.16,93.34 v2(112.38,93.56)
USB3RN2_JUSB1_R: length 10.9
  BOTTOM w0.102: R2367.1 22.04,37.71 21.26,37.71 v3(20.93,38.05) 20.67,38.3 20.35,38.3 20.25,38.2 DI1.10 DI1.1 18.24,38.2 18.12,38.32 17.14,38.32 16.43,37.61 14.76,37.61 13.32,36.17 JUSB1.5
USB3RP2_JUSB1_R: length 10.9
  BOTTOM w0.102: R2366.1 22.08,37.93 21.37,37.93 20.88,38.42 20.86,38.42 20.72,38.56 20.36,38.56 20.22,38.7 DI1.9 DI1.2 18.24,38.7 18.09,38.55 v3(17.53,38.55) 17.06,38.55 16.34,37.83 14.67,37.83 13.91,37.07 13.47,37.07 13.32,37.21 JUSB1.6
USB3TN2_JUSB1_R: length 11.4
  BOTTOM w0.102: JUSB1.8 13.32,42.19 13.58,42.45 13.91,42.45 14.45,41.92 15.7,41.92 15.78,41.84 16.39,41.23 16.39,40.72 16.6,40.51 16.7,40.41 17.14,39.97 17.9,39.97 17.96,39.92 17.96,39.77 18.02,39.7 DI1.4 DI1.7 20.34,39.7 20.43,39.79 v3(20.91,39.79) 22,39.79 R2369.1
USB3TP2_JUSB1_R: length 11.4
  BOTTOM w0.102: JUSB1.9 13.32,43.35 14.53,42.13 15.79,42.13 15.87,42.06 16.6,41.32 16.6,40.81 16.76,40.66 16.85,40.57 17.22,40.2 v3(17.52,40.2) DI1.5 DI1.6 20.27,40.2 20.46,40.01 20.6,40.01 20.61,40.02 21.21,40.02 21.22,40.01 22.12,40.01 R2368.1
USB20_CAM_N2_R: length 4.5
  BOTTOM w0.102: JEDP.30 106.3,163 106.44,162.86 106.44,161.76 107.38,160.82 107.38,160.13 RX21.1
USB20_CAM_P2_R: length 4.5
  BOTTOM w0.102: RX22.1 107.6,160.14 107.6,160.9 106.66,161.85 106.66,162.86 106.8,163 JEDP.31
USB20_CPU_N3: length 134.4
  IN2 w0.102: v2(110.2,92.63) 110.55,92.99 110.55,93.17 110.45,93.27 109.94,93.27 109.18,92.52 108.01,91.34 107.38,91.34 107.07,91.65 105.83,91.65 105.76,91.72 105.63,91.85 103.23,91.85 102.44,92.64 102.42,92.64 102.4,92.66
  IN2 w0.127: 102.4,92.66 102.09,92.97 98.99,92.97 98.53,93.43 97.01,93.43 91.93,88.35 91.93,87.88 89.84,85.79 89.84,82.71 89.84,82.71 89.84,82.54 88.02,80.72 88.02,80 86.21,78.19 85.53,78.19 85.53,78.19 84.43,78.19 82.65,76.41 80.51,76.41 78.53,74.43 78.53,73.18 76.79,71.44 76.79,63.94 77.72,63.02 77.72,62.08 76.48,60.84 76.46,60.84 v2(76.38,60.76)
  BOTTOM w0.102: v2(76.38,60.76) 76.54,60.92 76.89,60.92 77.6,60.21 78.83,58.97 78.83,58.2 81.08,55.95 91.89,55.95 96.88,55.95 138.77,55.95 143.16,51.56 143.34,51.56 143.34,51.56 144.07,51.56 144.14,51.49 U58.15 ; USOC1.H10 110.6,92.38 110.6,92.56 110.53,92.63 v2(110.2,92.63)
USB20_CPU_P3: length 134.3
  IN2 w0.102: 102.58,92.84 102.6,92.82 102.6,92.8 103.32,92.08 105.73,92.08 105.93,91.88 107.16,91.88 107.47,91.57 107.91,91.57 109.09,92.75 109.84,93.5 v2(110.93,93.5)
  IN2 w0.127: 102.58,92.84 102.2,93.23 99.1,93.23 98.64,93.69 96.9,93.69 91.67,88.46 91.67,87.99 89.59,85.9 89.59,82.82 89.58,82.81 89.58,82.65 87.76,80.83 87.76,80.11 86.1,78.45 85.64,78.45 84.32,78.45 82.54,76.67 80.4,76.67 78.28,74.54 78.28,73.28 76.54,71.54 76.54,63.84 77.46,62.91 77.46,62.19 76.75,61.48 76.4,61.48 v2(76.38,61.46)
  BOTTOM w0.102: v2(110.93,93.5) 110.96,93.48 USOC1.K10 ; U58.16 144.77,51.33 144.33,51.77 143.25,51.77 138.85,56.17 98.98,56.17 98.8,56.17 98.8,56.17 96.79,56.17 91.81,56.17 81.17,56.17 79.05,58.29 79.05,59.06 77.69,60.43 76.98,61.13 76.71,61.13 v2(76.38,61.46)
USB20_CR_N3_R: length 3.7
  BOTTOM w0.102: RR5.1 13.38,19.68 14.24,19.68 v3(14.69,20.12) 14.84,20.28 15.09,20.53 15.29,20.53 15.42,20.4 UR1.2
USB20_CR_P3_R: length 3.6
  BOTTOM w0.102: RR4.1 13.09,19.9 14.14,19.9 14.31,20.07 14.31,20.08 14.74,20.5 14.75,20.5 15,20.75 15.27,20.75 15.42,20.9 UR1.3
USB20_HUB_N1: length 197.5
  IN2 w0.127: v2(160.82,49.55) 160.84,49.55 161.09,49.8 162.45,49.8 163.19,50.54 163.19,55.35 165.94,58.11 165.94,68.35 165.17,69.12 165.17,70.92 166.09,71.83 166.09,74.4 166.09,74.94 166.59,75.45 166.59,81.16 167.06,81.63 167.06,85.99 167.32,86.26 167.32,100.51 164.91,102.93 164.91,104.99 159.77,110.12 151.84,110.12 150.28,111.68 149.97,111.68 146.6,115.06 140.15,115.06 139.86,114.77 136.77,114.77 136.3,114.3 132.26,114.3 131.83,114.73 123.56,114.73 123.18,115.11 116.75,115.11 116.41,114.77 112.18,114.77 111.8,115.15 107.85,115.15 106.33,116.67 105.52,116.67 103.64,118.55 103.64,146.48 109.91,152.76 109.91,159.36 107.7,161.57 107.7,162.32 108,162.62 108.37,162.62 108.45,162.54 108.45,162.28 v2(108.22,162.05)
  BOTTOM w0.102: v2(108.22,162.05) 108.59,162.41 108.59,162.83 108.52,162.89 108.37,162.89 108.3,162.96 JEDP.34 ; U58.10 146.68,46.02 146.36,46.34 146.36,46.77 148.13,48.53 151.14,48.53 151.71,49.11 152.93,49.11 154.72,50.9 155.23,50.9 155.24,50.88 155.82,50.88 155.84,50.9 v3(157.08,50.9) 158.92,50.9 159.9,49.92 160.46,49.92 v2(160.82,49.55)
USB20_HUB_N2: length 30.1
  IN2 w0.127: v2(160.79,62.78) 160.64,62.94 160.48,62.94 160.33,62.79 160.33,59.08 156.07,54.81 156.07,49.63 155.67,49.23 155.17,49.23 v2(155.02,49.09)
  BOTTOM w0.102: U58.8 147.95,46.07 147.88,46.13 147.69,46.13 147.62,46.21 147.62,46.4 147.81,46.59 151.71,46.59 154.54,49.42 154.67,49.42 155,49.09 v2(155.02,49.09) ; JNGFF.5 162.45,61.85 162.31,61.99 162.11,61.99 161.19,62.91 160.94,62.91 160.93,62.92 v2(160.79,62.78)
USB20_HUB_N3: length 19.5
  IN2 w0.127: v2(148.43,43.01) 148.43,43.07 148.11,43.4 148.11,43.48 148.21,43.58 150.17,43.58 150.87,42.88 150.87,37.87 149.6,36.6 149.6,34.72 149.13,34.25 147.68,34.25 147.55,34.37 147.55,34.55 147.68,34.68 v2(148.01,34.68)
  BOTTOM w0.102: U58.6 149.22,44.38 148.43,43.6 v2(148.43,43.01) ; LI6.4 148.89,34.57 148.61,34.29 148.38,34.29 148.01,34.65 v2(148.01,34.68)
USB20_HUB_N4: length 199.1
  IN2 w0.127: v2(17.42,56.77) 17.25,56.93 15.7,56.93 14.85,56.09 14.85,49.21 20,44.07 20,29.74 16.82,26.56 13.01,26.56 12.5,26.06 12.5,20.15 11.87,19.52 10.85,19.52 v2(10.72,19.39)
  BOTTOM w0.102: v2(10.72,19.39) 10.92,19.58 11.47,19.58 RR5.2 ; v2(17.42,56.77) 27.39,56.77 28.11,56.05 37.67,56.05 38.6,56.98 41.25,56.98 41.99,57.72 42.23,57.72 42.24,57.72 43.55,57.72 43.77,57.93 72.13,57.93 72.32,58.12 73.26,58.12 74.67,56.71 74.67,55.38 78.13,51.91 97.23,51.91 98.24,50.91 98.25,50.91 98.39,50.77 99.64,50.77 135.4,50.77 135.58,50.77 136.09,50.77 136.34,50.77 138.17,48.94 138.17,48.69 138.17,48.18 138.17,48 138.17,43.19 141.7,39.66 144.69,39.66 147.2,42.16 148.67,42.16 149.31,42.79 149.31,43.2 149.63,43.52 149.92,43.52 150.4,44 150.4,44.25 150.49,44.34 U58.4
USB20_HUB_P1: length 197.6
  IN2 w0.127: v2(108.81,162.05) 108.71,162.15 108.71,162.64 108.48,162.87 107.89,162.87 107.45,162.43 107.45,161.47 109.66,159.26 109.66,152.86 103.38,146.59 103.38,118.45 105.42,116.42 106.22,116.42 107.75,114.89 111.69,114.89 112.07,114.51 116.52,114.51 116.86,114.85 123.07,114.85 123.45,114.47 131.72,114.47 132.15,114.04 136.4,114.04 136.87,114.51 139.97,114.51 140.26,114.8 146.49,114.8 149.87,111.42 150.17,111.42 151.74,109.86 159.67,109.86 164.65,104.88 164.65,102.82 167.07,100.4 167.07,86.36 166.81,86.1 166.81,81.74 166.34,81.27 166.34,77.19 166.34,75.55 165.83,75.04 165.83,74.83 165.83,74.3 165.83,71.94 164.91,71.02 164.91,69.01 165.69,68.24 165.69,58.22 162.93,55.46 162.93,50.65 162.34,50.06 160.9,50.06 v2(160.82,50.13)
  BOTTOM w0.102: JEDP.35 108.8,162.05 v2(108.81,162.05) ; v2(160.82,50.13) 159.99,50.13 159.01,51.11 157.37,51.11 157.36,51.13 156.8,51.13 156.79,51.11 v3(155.5,51.11) 154.63,51.11 152.84,49.32 151.62,49.32 151.05,48.75 148.04,48.75 146.14,46.86 146.14,46.3 146.04,46.2 U58.11
USB20_HUB_P2: length 30.2
  IN2 w0.127: v2(160.79,63.37) 160.62,63.19 160.37,63.19 160.08,62.9 160.08,59.18 155.81,54.92 155.81,49.74 155.56,49.49 155.21,49.49 v2(155.02,49.67)
  BOTTOM w0.102: v2(160.79,63.37) 161.03,63.13 161.28,63.13 162.2,62.21 162.31,62.21 162.45,62.35 JNGFF.3 ; U58.9 147.31,46.07 147.4,46.16 147.4,46.49 147.72,46.81 151.62,46.81 154.45,49.64 154.99,49.64 v2(155.02,49.67)
USB20_HUB_P3: length 19.5
  IN2 w0.127: v2(147.99,33.83) 148.15,33.99 149.24,33.99 149.86,34.61 149.86,36.49 151.13,37.76 151.13,42.99 150.28,43.84 148.1,43.84 147.85,43.58 v2(147.85,43.01)
  BOTTOM w0.102: U58.7 148.58,44.05 148.22,43.69 148.22,43.38 v2(147.85,43.01) ; v2(147.99,33.83) 148.17,34.01 148.18,34.01 148.23,34.07 148.49,34.07 148.89,33.67 LI6.1
USB20_HUB_P4: length 199.2
  IN2 w0.127: v2(10.72,20.02) 10.98,19.77 11.76,19.77 12.25,20.26 12.25,26.16 12.9,26.82 16.71,26.82 19.74,29.84 19.74,43.97 14.6,49.11 14.6,56.2 15.59,57.19 17.25,57.19 v2(17.42,57.35)
  BOTTOM w0.102: v2(10.72,20.02) 10.95,19.79 11.56,19.79 RR4.2 ; v2(17.42,57.35) 17.79,56.99 27.48,56.99 28.2,56.27 37.58,56.27 38.51,57.2 41.16,57.2 41.9,57.93 42.32,57.93 43.46,57.93 43.68,58.15 72.04,58.15 72.23,58.34 73.35,58.34 74.89,56.8 74.89,55.46 78.22,52.13 97.32,52.13 98.33,51.13 98.34,51.13 98.48,50.99 99.55,50.99 135.31,50.99 135.49,50.99 135.49,50.99 136.18,50.99 136.43,50.99 138.39,49.03 138.39,48.78 138.39,48.09 138.39,47.91 138.39,43.28 141.79,39.87 144.61,39.87 147.11,42.38 148.58,42.38 149.09,42.88 149.09,43.29 149.54,43.74 149.83,43.74 150.18,44.09 150.18,44.17 150.11,44.24 149.93,44.24 149.85,44.32 U58.5
USB20_JUSB1_N0_R: length 14.8
  TOP w0.102: JUSB1.2 15.71,39.91 16.37,39.91 16.55,39.91 16.88,39.57 16.88,39.39 16.88,37.87 17.72,37.03 17.73,37.03 18.11,36.66 18.11,36.64 19.09,35.66 20.12,34.63 20.88,34.63 v2(21.14,34.88)
  BOTTOM w0.102: v2(21.14,34.88) 21.27,34.76 21.9,34.76 22.05,34.91 D27.2 22.59,35.59 23.42,34.76 24.34,34.76 LI2.2
USB20_JUSB1_P0_R: length 14.9
  TOP w0.102: JUSB1.3 15.71,39.69 16.46,39.69 16.67,39.48 16.67,37.78 v3(17.76,36.69) 20.03,34.41 20.97,34.41 v2(21.14,34.25)
  BOTTOM w0.102: v2(21.14,34.25) 21.43,34.54 21.89,34.54 22.05,34.37 D27.3 22.29,33.66 23.17,34.54 24.3,34.54 LI2.3
USB20_JUSB2_N1_R: length 22.7
  TOP w0.102: v2(157.97,42.2) 157.78,42.01 157.78,41.8 157.82,41.77 158.67,41.77 D25.2 159.54,42.02 159.73,41.83 160.24,41.83 161.19,42.78 162.58,42.78 163.23,42.13 v3(163.71,42.13) 165.05,42.13 165.5,42.59 JIO1.22
  BOTTOM w0.102: v2(157.97,42.2) 157.79,42.02 157.79,41.74 157.54,41.49 157.17,41.49 156.79,41.87 155.97,41.87 154.7,40.6 154.7,37.34 153.66,36.3 152.09,36.3 151.78,35.98 LI5.2
USB20_JUSB2_P1_R: length 22.7
  TOP w0.102: JIO1.21 165.5,41.59 165.18,41.92 164.08,41.92 164.07,41.91 163.39,41.91 163.38,41.92 163.14,41.92 162.49,42.57 161.28,42.57 160.33,41.61 159.73,41.61 159.54,41.42 D25.3 158.71,41.55 157.73,41.55 157.57,41.71 157.57,42.01 v2(157.38,42.2)
  BOTTOM w0.102: LI5.3 151.73,36.88 152.09,36.51 153.57,36.51 154.49,37.43 154.49,40.69 155.89,42.08 156.88,42.08 157.26,41.7 157.45,41.7 157.57,41.83 157.57,41.98 157.51,42.05 157.51,42.07 v2(157.38,42.2)
USB20_JUSB3_N3_R: length 20.1
  TOP w0.102: JIO1.18 165.5,38.59 165.15,38.95 164.83,38.95 164.33,38.45 164.33,38.43 163.9,38 163.88,38 163.47,37.59 162.44,37.59 D26.2 161.5,37.33 161.35,37.49 160.9,37.49 159.95,36.53 157.41,36.53 156.88,37.07 156.88,37.43 v2(156.69,37.61)
  BOTTOM w0.102: v2(156.69,37.61) 156.88,37.43 156.88,36.94 154.26,34.32 152,34.32 151.75,34.57 LI6.3
USB20_JUSB3_P3_R: length 20.1
  TOP w0.102: v2(157.28,37.61) 157.09,37.43 157.09,37.16 157.5,36.75 159.86,36.75 160.81,37.7 161.18,37.7 161.5,38.02 D26.3 162.27,37.8 163.38,37.8 v3(163.95,38.37) 164.74,39.16 165.08,39.16 165.5,39.59 JIO1.19
  BOTTOM w0.102: LI6.2 151.75,33.67 152.19,34.11 154.35,34.11 157.09,36.85 157.09,37.43 v2(157.28,37.61)
USB20_N0: length 138.1
  IN2 w0.102: v2(112.81,91.08) 112.81,91.58 112.64,91.75 111.85,91.75 111.29,91.19 109.68,91.19 109.15,90.66 109,90.66 108.55,90.21 107.86,90.21 107.1,90.98 105.88,90.98 105.7,90.79 103.52,90.79 103.52,90.79 103.33,90.79 103.09,91.03 103.02,91.1 102.24,91.1 102.23,91.09 102.12,91.09
  IN2 w0.127: v2(27.54,35.06) 27.54,34.93 27.2,34.59 27.07,34.59 26.93,34.73 26.93,35.36 28.51,36.93 28.51,38.27 29.2,38.96 29.2,39.08 29.21,39.09 29.21,39.94 29.21,53.81 35.61,60.21 41.37,60.21 43.54,62.38 51.4,62.38 61.52,62.38 65.55,58.35 74.7,58.35 75.69,59.33 76.09,59.33 78.57,61.81 78.57,66.84 77.9,67.51 77.9,71.31 79.3,72.72 79.3,74.07 80.84,75.61 83.82,75.61 84.44,76.23 85.61,77.4 86.54,77.4 88.82,79.67 88.82,79.89 89.53,80.6 89.53,81.09 90.61,82.16 90.61,85.47 92.96,87.82 92.96,88.18 96.96,92.18 99.71,92.18 100.8,91.09 102.12,91.09
  BOTTOM w0.102: v2(27.54,35.06) 27.54,34.92 27.26,34.64 26.59,34.64 26.51,34.72 LI2.1 ; USOC1.K16 113.06,90.83 v2(112.81,91.08)
USB20_N1: length 155.7
  IN2 w0.102: v2(112,90.17) 112,90.51 111.77,90.73 110.35,90.73 109.74,90.12 109.74,89.94 109.37,89.57 108.86,89.57 108.74,89.68 107.54,89.68 106.91,90.3 105.54,90.3 105.32,90.09 102.89,90.09 102.83,90.02 102.14,90.02 102.13,90.01 102.12,90.01
  IN2 w0.127: v2(72.69,56.78) 75.04,56.78 78.59,60.33 78.59,60.7 79.37,61.48 79.37,67.98 78.94,68.41 78.94,71.21 80.31,72.58 80.31,73.96 81.19,74.83 84.18,74.83 85.5,76.15 86.56,76.15 86.57,76.16 86.57,76.18 89.14,78.75 89.78,78.75 90.85,79.81 90.85,81.27 92.64,83.06 92.64,84.52 94.68,86.57 94.68,88.48 97.3,91.09 97.7,91.09 98.78,90.01 102.12,90.01
  BOTTOM w0.102: v2(112,90.17) 111.83,90.33 111.36,90.33 ; LI5.1 148.97,36.34 147.76,36.34 147.5,36.6 143.58,36.6 137.34,42.83 137.34,48.6 136,49.94 99.98,49.94 98.05,49.94 97.91,50.08 97.89,50.08 96.89,51.09 77.79,51.09 73.84,55.03 73.84,55.72 73.84,56.33 73.4,56.78 v2(72.69,56.78)
USB20_N2: length 80.1
  IN2 w0.102: v2(110.82,91.92) 110.82,92.29 110.79,92.33 110.79,92.8 111.34,93.36 111.34,94.05 111.94,94.64 111.94,94.95 110.64,96.26 110.64,100.89
  IN2 w0.127: v2(107.21,156.83) 107.37,156.67 107.37,151.82 102.57,147.02 102.57,118.15 107.33,113.39 112.3,113.39 112.86,112.84 112.86,111.15 112.86,110.89 114.28,109.46 114.28,108.31 114.1,108.13 114.1,108.08 113.81,107.78 113.75,107.78 110.64,104.66 110.64,100.89
  BOTTOM w0.102: v2(110.82,91.92) 111.16,91.58 USOC1.J12 ; v2(107.21,156.83) 107.39,157.02 107.39,158.42 RX21.2
USB20_P0: length 138.1
  IN2 w0.102: v2(113.21,91.51) 112.73,91.98 111.75,91.98 111.19,91.42 109.59,91.42 109.05,90.89 108.9,90.89 108.45,90.44 107.96,90.44 107.19,91.21 105.78,91.21 105.6,91.02 103.43,91.02 103.19,91.27 103.12,91.33 102.14,91.33 102.13,91.35 102.12,91.35
  IN2 w0.127: 102.12,91.35 100.91,91.35 99.81,92.44 96.85,92.44 92.7,88.29 92.7,87.93 90.35,85.58 90.35,82.27 89.27,81.19 89.27,80.7 88.56,79.99 88.56,79.77 86.44,77.66 85.5,77.66 84.18,76.34 83.71,75.87 80.74,75.87 79.05,74.18 79.05,72.82 77.64,71.41 77.64,67.41 78.31,66.74 78.31,61.91 75.99,59.59 75.58,59.59 74.6,58.61 65.65,58.61 61.62,62.63 51.51,62.63 50.93,62.63 43.43,62.63 41.27,60.47 35.51,60.47 28.95,53.92 28.95,39.83 28.95,39.83 28.95,39.2 28.95,39.19 28.95,39.07 28.25,38.37 28.25,37.04 26.68,35.47 26.68,34.63 26.97,34.34 v2(27.54,34.34)
  BOTTOM w0.102: v2(113.21,91.51) 113.57,91.15 USOC1.M16 ; LI2.4 26.76,34.42 27.45,34.42 v2(27.54,34.34)
USB20_P1: length 155.7
  IN2 w0.102: v2(112.37,90.69) 112.14,90.69 111.87,90.97 110.26,90.97 109.51,90.21 109.51,90.03 109.27,89.8 108.95,89.8 108.84,89.91 107.64,89.91 107.01,90.54 105.44,90.54 105.23,90.32 102.8,90.32 102.74,90.25 102.13,90.25 102.12,90.27
  IN2 w0.127: v2(72.76,57.36) 73.09,57.03 74.93,57.03 78.34,60.44 78.34,60.81 79.11,61.58 79.11,67.88 78.68,68.31 78.68,71.32 80.05,72.69 80.05,74.06 81.08,75.09 84.07,75.09 85.39,76.41 86.44,76.41 89.04,79 89.68,79 90.59,79.92 90.59,81.37 92.38,83.16 92.38,84.63 94.43,86.67 94.43,88.58 97.19,91.35 97.8,91.35 98.88,90.27 102.12,90.27
  BOTTOM w0.102: LI5.4 149.01,36.56 147.85,36.56 147.59,36.81 143.67,36.81 137.56,42.92 137.56,48.25 137.56,48.69 136.09,50.16 135.83,50.16 99.89,50.16 98.14,50.16 98,50.3 97.98,50.3 96.98,51.3 77.88,51.3 74.06,55.12 74.06,55.63 74.06,56.42 73.49,56.99 73.13,56.99 v2(72.76,57.36) ; v2(112.37,90.69) 112.23,90.84 USOC1.J14
USB20_P2: length 80.1
  IN2 w0.102: v2(111.42,92.53) 111.26,92.36 111.08,92.36 111.02,92.42 111.02,92.7 111.58,93.26 111.58,93.95 112.18,94.55 112.18,95.05 110.89,96.33 110.89,101.13
  IN2 w0.127: v2(107.79,156.83) 107.63,156.67 107.63,151.72 102.83,146.92 102.83,118.26 107.43,113.65 112.41,113.65 113.12,112.95 113.12,111.04 113.12,110.99 114.54,109.57 114.54,108.2 114.36,108.02 114.36,107.97 113.91,107.52 113.86,107.52 110.89,104.56 110.89,101.13
  BOTTOM w0.102: v2(107.79,156.83) 107.61,157.02 107.61,158.42 RX22.2 ; v2(111.42,92.53) 111.42,92.27 USOC1.K12
USB_EN#: length 302
  TOP w0.102: v2(32.35,17.93) 31.38,18.91 28.97,18.91 28.27,19.61 28.27,22.41 28.27,22.77 28.27,22.96 28.27,31.55 25.14,34.67 25.14,43.15 25.37,43.38 25.37,44.72 v1(25.69,45.05) 26.02,45.37 v2(26.41,45.37)
  IN1 w0.127: v2(166.06,52.04) 165.7,52.04 163.95,50.29 163.95,48.24 162.24,46.52 158.95,43.24 v2(158.34,43.24) 158.34,43.73 157.65,44.42 156.7,44.42 154.58,42.3 152.51,42.3 151.73,41.51 151.73,39.17 150.36,37.8 142.61,37.8 139.5,34.69 139.5,31.61 v2(139.05,31.15)
  IN2 w0.127: v2(156.56,129.47) 156.61,129.47 157.79,128.29 157.79,123.71 158.24,123.26 158.24,120.85 160.06,119.02 160.06,116.37 168.08,108.35 168.08,102.69 170.76,100.02 170.76,94.27 169.82,93.33 169.82,77.96 168.63,76.77 168.63,74.6 168.4,74.37 168.4,69.44 170.29,67.54 170.29,61.29 168.43,59.44 168.43,54.41 v2(166.06,52.04)
  BOTTOM w0.102: CI26.1 157.66,43.01 UI4.4 158.04,42.94 v2(158.34,43.24) ; v2(32.35,17.93) 32.35,6.65 35.68,3.32 53.84,3.32 55.75,5.23 55.75,7.39 57.07,8.71 57.07,12.04 57.36,12.33 57.36,15.01 58.81,16.45 68.51,16.45 72.59,20.53 124.32,20.53 130.64,26.86 135.79,26.86 137.85,28.91 137.85,29.95 v2(139.05,31.15) ; UE1.84 v2(156.56,129.47) ; CI13.1 26.96,45.92 v2(26.41,45.37) 26.28,45.24 UI5.4
USB_OC0#: length 135.6
  TOP w0.102: v2(67.11,71.46) 67.11,78.32 65.37,80.06 63.47,80.06 62.62,80.91 54.24,80.91 54.02,80.69 47.39,80.69 v2(47.3,80.6) ; v2(43.74,75.52) 43.74,70.1 44.49,69.35 44.49,63.11 43,61.61 v1(43,60.68) v2(43,56.87)
  IN1 w0.127: v2(67.11,71.46) 67.16,71.41 78.75,71.41 79.71,72.37 81.29,72.37 84.77,75.85 84.77,76.83 86.63,78.7 90.7,78.7 90.74,78.66 91.55,78.66 92.3,79.41 93.7,79.41 96.55,82.25 97.42,82.25 100.65,85.49 103.54,85.49 104.29,86.24 v2(104.94,86.24)
  BOTTOM w0.102: v2(104.94,86.24) 105.25,85.94 106.24,85.94 RC44.2 106.83,86.52 108.76,86.52 108.9,86.38 108.9,85.81 109.28,85.43 110.3,85.43 111.23,86.36 111.23,86.53 111.37,86.67 111.67,86.67 111.86,86.87 USOC1.C20 ; v2(43.74,75.52) 47.11,78.89 47.11,80.41 v2(47.3,80.6) ; v2(43,56.87) 41.76,55.63 40.29,55.63 38.37,53.72 27.86,53.72 26.63,52.49 26.63,48.86 25.29,47.52 25.29,46.67 CI15.1 24.64,44.72 UI5.3
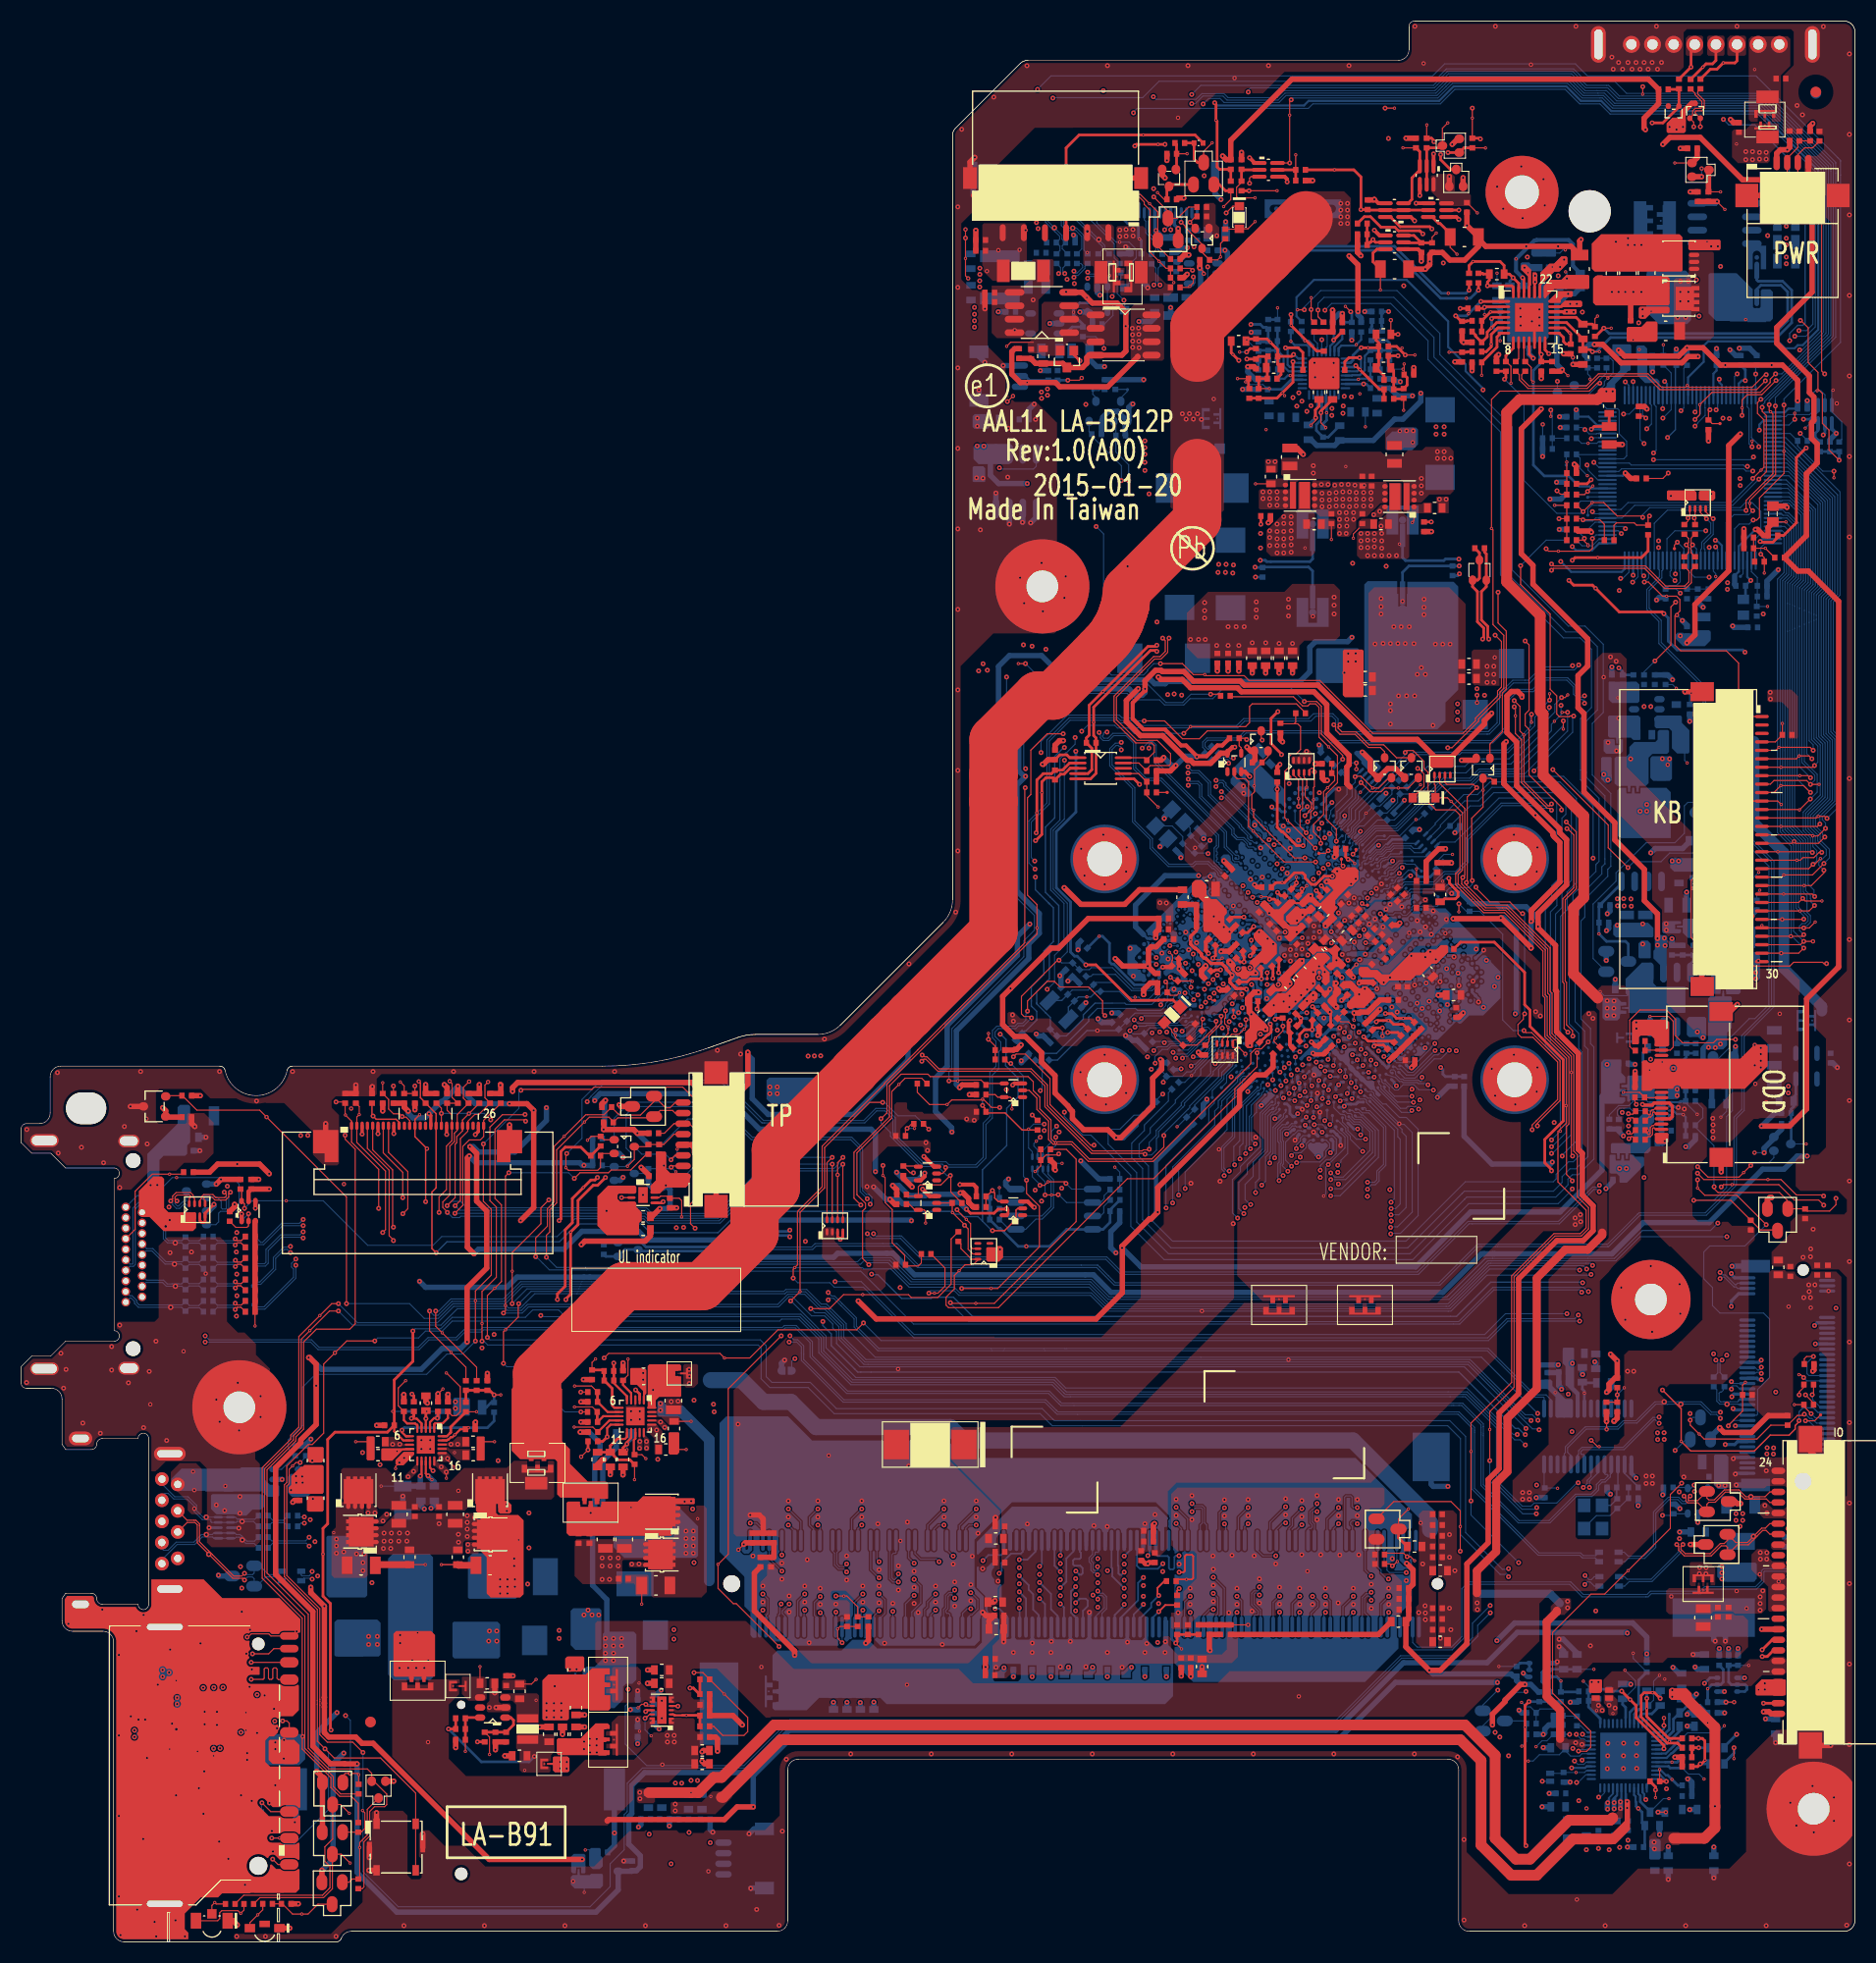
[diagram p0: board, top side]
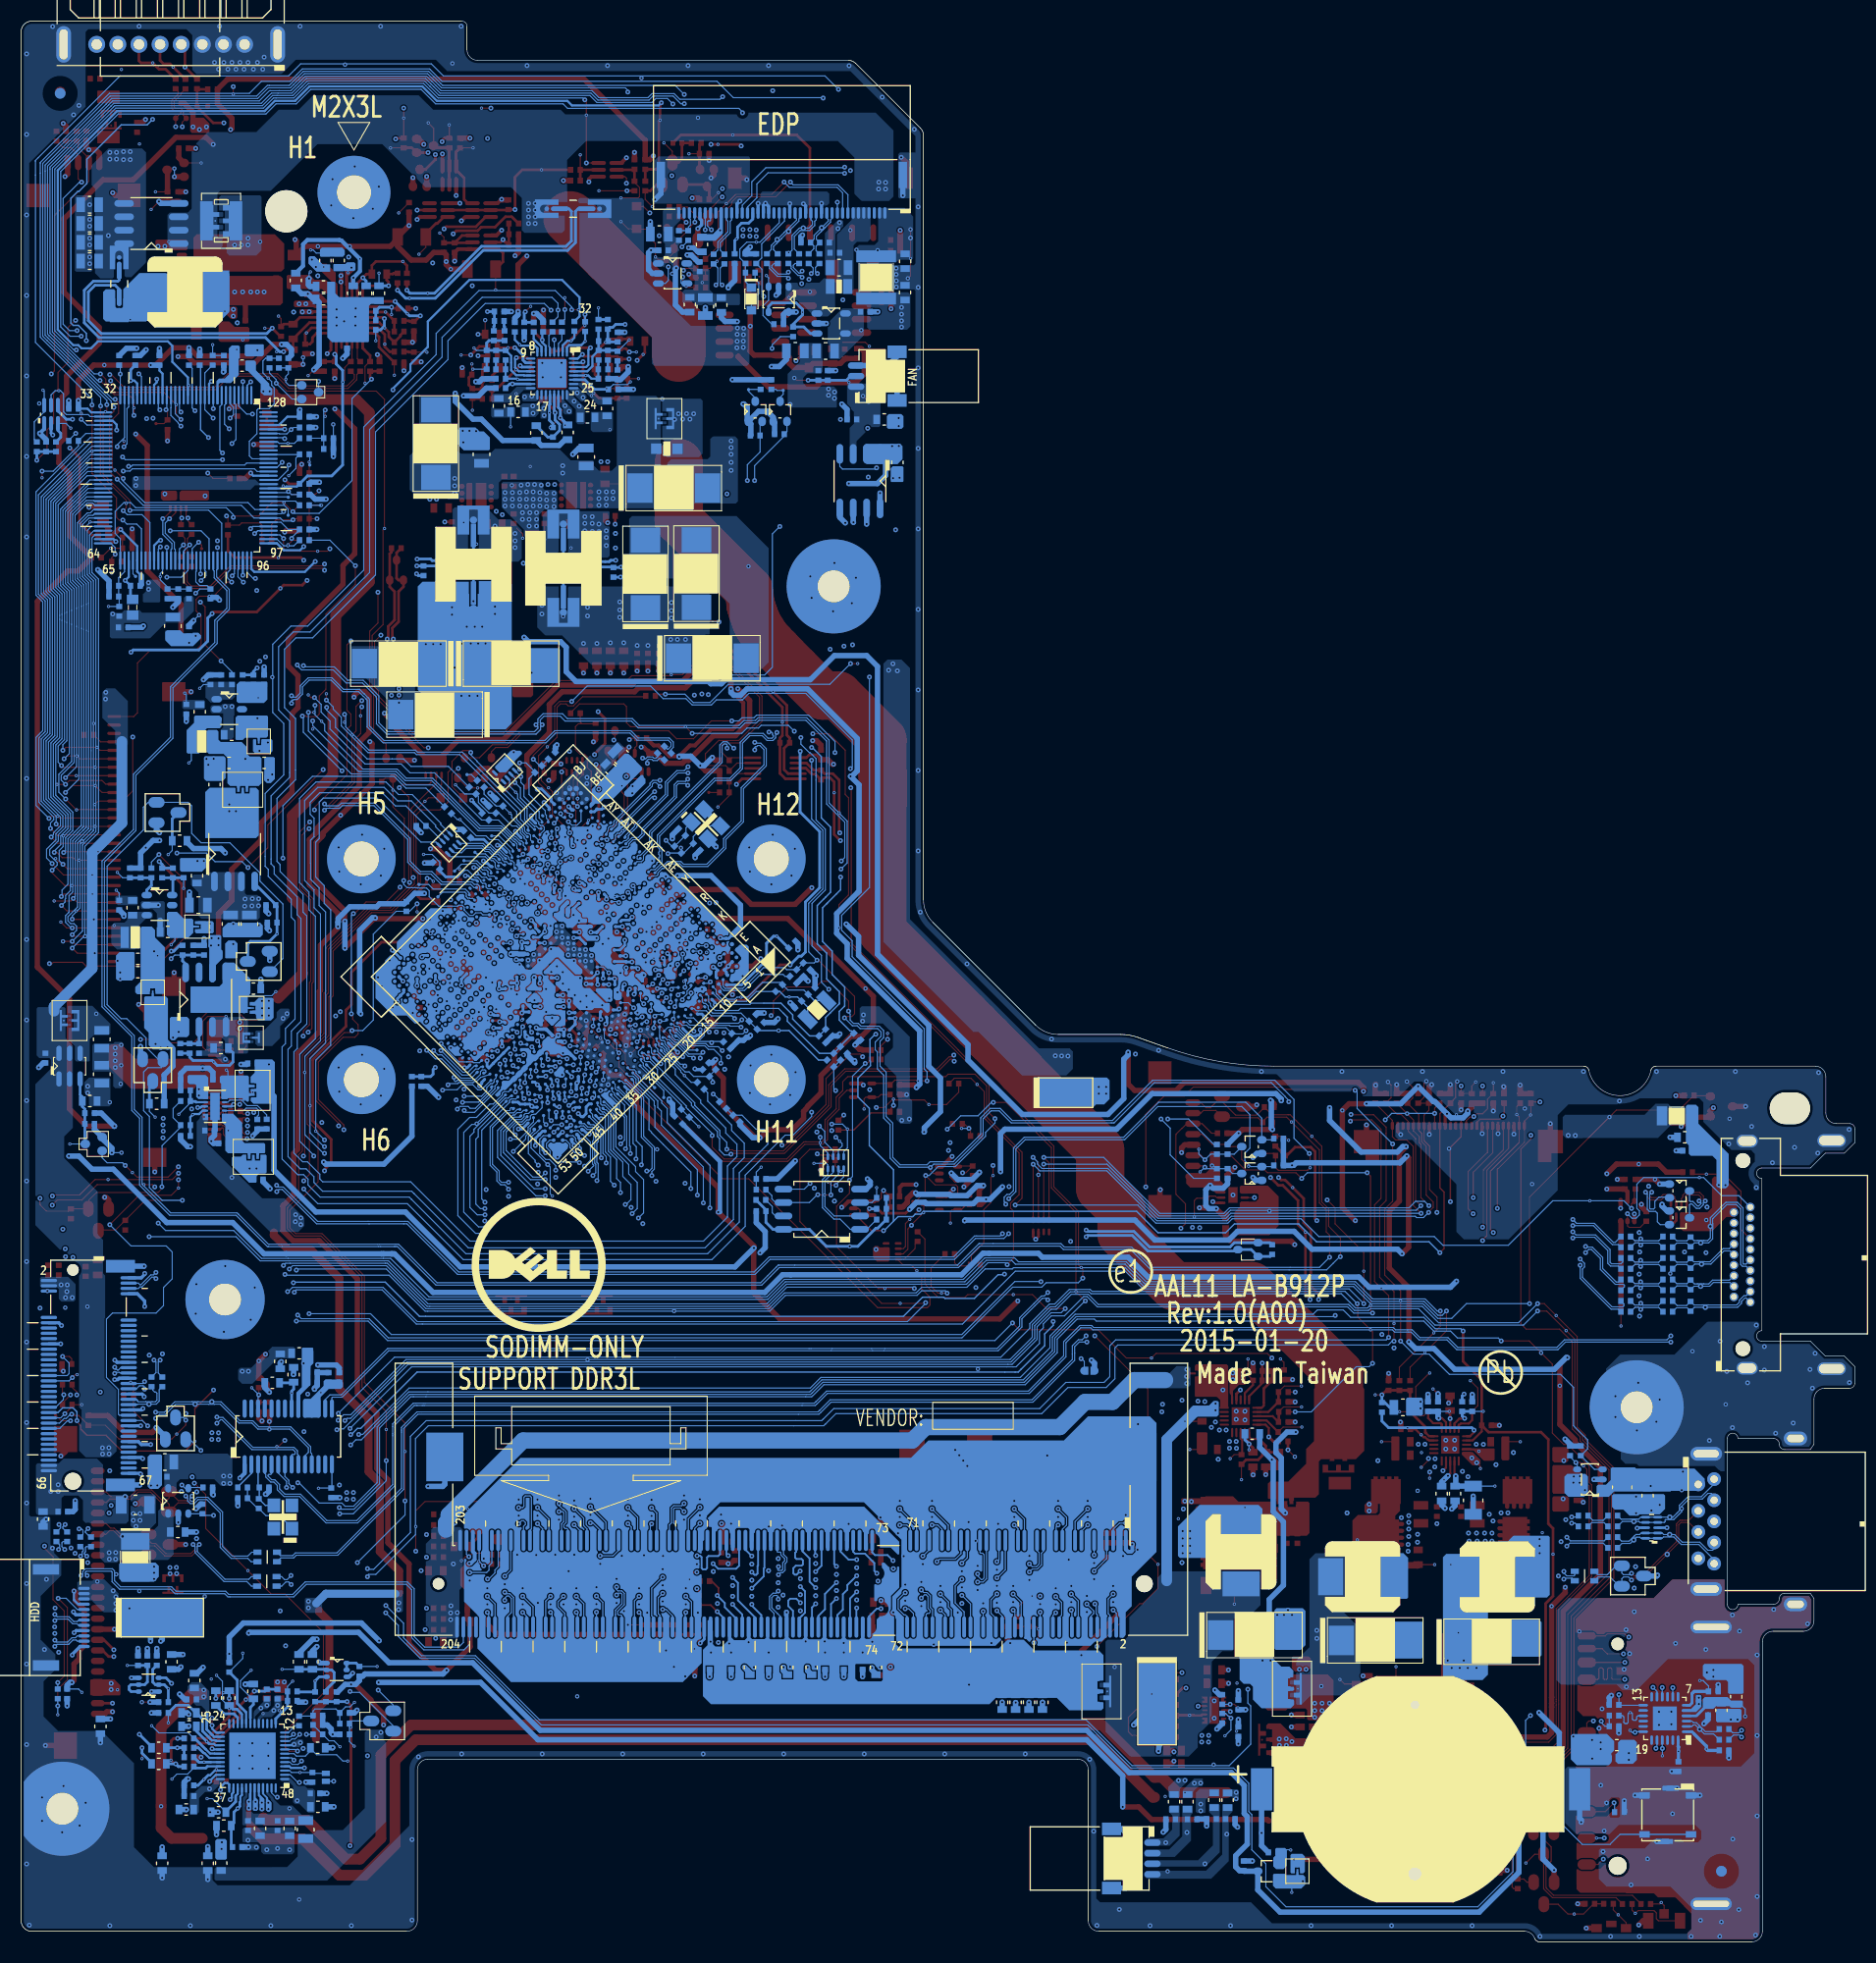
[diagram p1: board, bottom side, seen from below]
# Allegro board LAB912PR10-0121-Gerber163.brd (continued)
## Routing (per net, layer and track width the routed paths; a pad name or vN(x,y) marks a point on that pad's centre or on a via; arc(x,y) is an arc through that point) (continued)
USB_OC1#: length 186.2
  TOP w0.102: v2(71.74,27.96) 67.68,32.01 67.4,32.01 65.96,33.46 v1(65.96,35.73) 66.92,36.7 66.92,52.34 v2(71.94,57.36)
  IN1 w0.102: 106.83,85.29 107.82,85.29 107.99,85.11 v2(108.2,85.11)
  IN1 w0.127: v2(71.74,27.96) 73.07,27.96 74.09,26.94 135.44,26.94 139.76,31.26 139.76,32.76 144.54,37.55 150.47,37.55 153.29,40.37 v2(155.34,40.37) ; 106.83,85.29 106.69,85.15 105.31,85.15 105.13,84.97 100.85,84.97 97.6,81.72 96.92,81.72 93.61,78.41 90.63,78.41 90.59,78.45 86.74,78.45 85.16,76.87 85.16,75.89 83.81,74.54 83.81,72.94 83.18,72.31 82.54,72.31 81.76,71.52 81.76,66.44 80.71,65.4 77.67,65.4 74.73,62.47 74.73,60.96 71.94,58.16 v2(71.94,57.36)
  BOTTOM w0.102: UI4.3 157.71,40.52 CI17.1 156.24,40.37 v2(155.34,40.37) ; 107.07,85.19 107.1,85.22 108.09,85.22 v2(108.2,85.11) 108.31,85.22 110.38,85.22 USOC1.B20
USB_PLL_MON: length 3
  TOP w0.102: v2(112.79,93.12) 112.94,92.97 113.53,92.97 v1(113.67,93.11)
  TOP w0.254: v2(112.79,93.12) 113.03,93.36 RC47.2
  BOTTOM w0.254: USOC1.M13 112.66,92.99 v2(112.79,93.12)
USB_RCOMP: length 3.7
  TOP w0.102: RC45.2 108.91,92.86 108.97,92.92 108.97,93.37 v1(108.68,93.67)
  TOP w0.406: v2(108.04,92.27) 108.78,92.27 RC45.2
  BOTTOM w0.254: v2(108.04,92.27) 107.93,92.27 USOC1.D6 107.79,91.8 107.79,91.33 USOC1.C7
VCIN0_PH: length 5
  TOP w0.102: PR13.2 147.96,136.99 v2(148.25,137.28) 148.25,137.31 v1(148.75,137.8)
  BOTTOM w0.102: PR13.2 147.96,136.99 v2(148.25,137.28) 148.36,137.17 UE1.109
VCIN1_BATT_DROP: length 3.9
  TOP w0.102: v2(164.65,131.34) 164.98,131.01 PR36.2 v1(164.98,129.56)
  BOTTOM w0.102: v2(164.65,131.34) 164.65,131.97 165.05,132.37 UE1.64
VCIN1_PROCHOT: length 5.9
  TOP w0.102: v1(148.29,132.24) 147.95,132.58 v2(147.95,132.84) 147.78,132.67 PR15.2
  BOTTOM w0.102: v2(147.95,132.84) 147.95,132.9 147.2,133.65 R697.1 148.28,133.69 148.96,134.37 UE1.102
VCORE_GSNS: length 248.6
  TOP w0.254: RC58.1 118.01,85.88 118.06,85.88 118.3,86.12 118.3,86.71 118.23,86.76 v2(118.23,86.88) ; v2(55.3,72.35) 54.56,71.61 54.14,71.61 52.7,70.17 52.7,67.88 v1(52,67.18) 52,61.3 51.56,60.85 v2(51.56,60.79) ; PC535.2 125.28,148.79 125.28,149.56 125.66,149.94 v2(126.68,149.94) ; v2(119.67,150.88) 120.86,150.88 121.31,150.43 PC503.2
  IN1 w0.254: v2(119.67,150.88) 116.29,150.88 116.19,150.99 112.81,150.99 107.69,145.86 107.69,143.48 108.26,142.91 108.26,131.02 103.94,126.7 103.94,122.39 100.7,119.15 100.7,115.99 101.39,115.31 101.39,113.87 100.93,113.41 100.93,110.74 99.75,109.56 98.69,109.56 92.77,103.63 92.77,95.94 92.77,95.94 92.77,95.52 79.57,82.33 79.57,81.95 79.57,81.86 78.39,80.68 72.92,75.2 59.31,75.2 57.38,73.27 57.37,73.27 57.19,73.09 55.7,73.09 55.3,72.69 v2(55.3,72.35)
  IN2 w0.254: v2(51.56,60.79) 51.94,61.17 61.02,61.17 68.12,54.07 73.69,54.07 74.11,54.07 82.25,62.21 82.51,62.21 83.11,62.82 83.11,63.63 86.96,67.47 86.96,73.65 88.32,75.01 88.97,75.01 90.76,76.8 92.13,78.18 92.13,79.23 92.13,80.84 93.45,82.15 94.82,82.15 95.79,83.12 95.79,84.05 97.04,85.3 99.68,85.3 100.29,85.91 103.33,85.91 105.28,87.85 106.22,87.85 106.35,87.71 108.38,87.71 108.77,88.11 109.31,88.11 112.68,84.74 115.44,84.74 116.16,85.46 116.16,86.17 116.87,86.88 v2(118.23,86.88) ; v2(119.67,150.88) 120.17,151.39 120.94,151.39 121.42,150.91 125.59,150.91 126.06,150.44 126.18,150.44 v2(126.68,149.94)
  BOTTOM w0.203: v2(119.67,150.88) 119.86,150.68 119.86,149.27 120.07,149.06 PU500.30 ; v2(126.68,149.94) 126.8,149.82 126.8,149 126.52,148.71 126.46,148.66 PU500.12
  BOTTOM w0.254: USOC1.N28 118.1,87.46 118.1,87 v2(118.23,86.88)
VCORE_VSNS: length 242.5
  TOP w0.254: v2(118.68,87.33) 118.78,87.43 RC56.2 ; v2(50.76,60.8) 50.76,61.32 51.49,62.06 51.49,67.39 52.16,68.06 52.16,70.35 v1(53.21,71.39) 53.93,72.11 54.31,72.11 v2(54.54,72.35)
  IN1 w0.254: v2(129.42,154.31) 129.27,154.31 127.95,152.99 120.07,152.99 118.67,151.6 112.71,151.6 107.18,146.07 107.18,143.27 107.75,142.7 107.75,131.23 103.43,126.91 103.43,122.6 100.2,119.36 100.2,115.78 100.88,115.1 100.88,114.08 100.42,113.62 100.42,110.95 99.54,110.07 98.48,110.07 92.26,103.84 92.26,95.73 79.06,82.54 79.06,82.16 79.06,82.16 79.06,82.07 77.88,80.89 72.71,75.71 59.1,75.71 57.17,73.78 57.16,73.78 56.98,73.6 55.49,73.6 54.79,72.9 54.79,72.55 54.59,72.35 v2(54.54,72.35)
  IN2 w0.254: v2(50.76,60.8) 51.63,61.68 61.23,61.68 68.33,54.58 73.9,54.58 82.04,62.72 82.3,62.72 82.61,63.03 82.61,63.84 86.45,67.68 86.45,73.86 88.11,75.52 88.75,75.52 91.62,78.4 91.62,79.44 91.62,81.05 93.24,82.66 94.61,82.66 95.28,83.33 95.28,84.26 96.83,85.81 99.47,85.81 100.08,86.42 103.12,86.42 105.07,88.36 106.43,88.36 106.57,88.22 108.17,88.22 108.56,88.62 109.52,88.62 112.3,85.83 115.11,85.83 115.38,86.1 115.38,86.1 116.66,87.38 118.44,87.38 118.49,87.33 v2(118.68,87.33)
  BOTTOM w0.254: v2(118.68,87.33) 118.74,87.39 118.74,87.98 USOC1.P28 ; v2(129.42,154.31) PC533.2 PC527.1 128.76,152.97 128.81,152.92 PR542.1
VCOUT0_PH: length 217.8
  TOP w0.102: v2(39.24,59.71) 39.24,58.26 v1(39.85,57.65) 43.11,54.39 PR114.1
  IN1 w0.127: v2(160.58,68.03) 160.58,70.4 161.42,71.24 161.42,82.4 162.67,83.64 162.67,85.87 157.28,91.25 157.28,98.32 156.67,98.93 156.67,100.08 158.98,102.39 159.38,102.39 160.33,103.34 160.74,103.34 161.51,104.1 161.51,110.59 158.81,113.29 158.81,116 156.03,118.77 155.31,119.49 153.67,119.49 153.24,119.92 148.68,124.48 148.68,124.48 148.61,124.55 148.14,125.02 148.14,130.91 149.13,131.9 149.13,134.96 v2(148.71,135.38)
  BOTTOM w0.102: v2(148.71,135.38) 148.92,135.17 UE1.104 ; v2(160.58,68.03) 159.88,67.33 153.44,67.33 150.79,64.69 148.28,64.69 139.26,64.69 139.26,64.69 138.58,64.69 134.94,61.04 102.97,61.04 101.31,62.71 84.37,62.71 82.34,64.74 79.53,64.74 79.16,64.37 68.96,64.37 67.08,62.49 54,62.49 47.27,62.49 45.63,60.85 40.67,60.85 39.53,59.71 v2(39.24,59.71)
VCOUT1_PH: length 128.1
  TOP w0.102: RE13.2 149.84,134.17 149.42,134.6 v2(147.82,134.6) 147.71,134.7 PR18.2 ; v2(164.47,138.45) 164.47,138.45 165.17,139.15 165.17,144.47 164.78,144.86 v2(164.78,145.25) ; v1(118.87,165.74) v2(116.21,165.74)
  TOP w0.254: PR17.1 v2(116.21,165.74)
  IN2 w0.127: v2(116.21,165.74) 115.82,166.14 115.82,169.06 116.13,169.38 v2(116.13,175.09)
  BOTTOM w0.102: v2(147.82,134.6) 147.92,134.49 148.74,134.49 149.02,134.77 UE1.103 151.51,134.77 152.71,135.97 161.99,135.97 164.46,138.45 v2(164.47,138.45) ; v2(116.13,175.09) 116.13,175.26 116.36,175.49 133.75,175.49 134.04,175.77 135.08,176.82 146.74,176.82 147.25,176.31 148.07,175.49 150.16,175.49 151.16,174.48 164.97,174.48 165.51,173.95 165.51,173.95 171.28,168.17 171.28,167.61 171.28,152.08 171.01,151.81 165.03,145.83 165.03,145.69 164.78,145.44 v2(164.78,145.25)
VFB: length 4.9
  TOP w0.254: PU700.15 145.56,152.27 145.98,151.85 145.98,151.47 146.22,151.23 PR726.1 146.67,152.18 v1(146.55,152.29) 146.08,152.77 PU700.16
VGA_V1P35_S3_F1:
  vias: v1(116.69,109.42)
VGATE: length 35.6
  IN1 w0.254: v2(146.81,132.07) 146.81,133.95 146.36,134.4 146.36,137.92 144.84,139.43 140.11,139.43 134.61,144.93 129.59,144.93 v2(127.06,147.46)
  BOTTOM w0.203: UE1.97 149.34,132.37 148.68,131.72 147.15,131.72 v2(146.81,132.07)
  BOTTOM w0.254: PR530.1 127.31,147.46 v2(127.06,147.46) PU500.15
VGFX_VSNS: length 74.3
  TOP w0.254: v2(121.32,103.76) 120.72,103.76 119.39,105.09 119.29,105.09 118.88,105.49 v2(118.88,109.1) RC55.2 ; v2(119.28,112.38) 119.28,112.43 118.29,113.42 118.29,115.79 v2(118.94,116.44)
  IN2 w0.254: v2(118.94,116.44) 118.33,117.05 116.39,117.05 116.13,116.8 108.62,116.8 107.22,118.19 107.22,119.44 106.58,120.07 106.58,123.54 107.08,124.04 107.87,124.04 108.39,124.56 108.39,136.67 108.26,136.8 108.26,147.26 114.09,153.09 v2(116.39,153.09) ; v2(119.28,112.38) 119.72,111.95 119.72,111.12 118.88,110.29 v2(118.88,109.1)
  BOTTOM w0.254: PC502.1 117.91,151.44 PR504.2 118.02,151.55 PR501.2 117.85,152.81 117.56,152.81 117.28,153.09 v2(116.39,153.09) ; USOC1.BB8 121.44,103.88 v2(121.32,103.76)
VL: length 3.2
  TOP w0.102: v2(38.51,44.11) v1(38.88,43.75)
  TOP w0.203: v2(38.51,44.11) 38.3,44.33 PU100.13
  BOTTOM w0.508: PC117.1 39.11,43.52 v2(38.51,44.11)
VR_HOT#: length 50.5
  TOP w0.254: v2(146.81,130.77) 147.06,131.02 v1(149.21,131.02) 153.35,131.02 153.98,131.66 R44.1 ; v2(124.23,151.62) 125.02,152.41 PR525.1
  IN1 w0.254: v2(124.23,151.62) 124.72,152.1 126.8,152.1 128.2,150.71 128.2,147.4 130.08,145.53 134.58,145.53 140.01,140.1 144.73,140.1 146.74,138.09 146.74,134.55 147.29,134.01 147.29,131.87 146.77,131.35 146.77,130.82 146.81,130.78 v2(146.81,130.77)
  BOTTOM w0.203: PU500.6 123.9,151.05 124.23,151.38 v2(124.23,151.62) 124.23,152.31 PC520.1
VR_ON: length 39.9
  TOP w0.102: v2(144.77,144.99) v1(144.77,144.39)
  IN1 w0.127: v2(138.36,146.9) 139.25,146.01 143.76,146.01 v2(144.77,144.99)
  BOTTOM w0.102: v2(144.77,144.99) 144.91,144.85 RE1.2 ; CE34.1 RE1.2 ; RE1.2 RE12.2
  BOTTOM w0.203: v2(138.36,146.9) 138.36,147.02 136.71,148.67 136.71,149.31 135.06,150.96 135.06,153.37 131.12,157.31 122.36,157.31 120.71,155.66 120.71,153.86 PR516.1
VR_ON_EC: length 3.2
  BOTTOM w0.102: UE1.121 149.26,141.97 149.13,141.84 v1(148.3,141.84) 147.68,141.84 RE12.1
VR_ON_R: length 2.7
  BOTTOM w0.203: PU500.2 122.3,151.11 121.86,151.54 v1(121.49,151.54) 121.49,151.53 121.19,151.84 PR516.2
VR_SVID_ALERT#: length 172
  TOP w0.102: v2(121.44,154.48) v1(120.81,154.48)
  IN2 w0.127: v2(121.44,154.48) 121.44,153.3 v2(123.1,151.64)
  BOTTOM w0.102: RC28.2 RC27.2 105.32,78.24 103.99,76.92 103.26,76.92 102.88,76.54 102.88,75.51 105.58,72.8 105.58,68.14 108.59,65.13 131.46,65.13 136.59,70.26 136.64,70.32 136.82,70.49 145.25,70.49 146.25,71.49 146.25,71.5 146.4,71.65 146.4,72.2 146.81,72.61 147.37,72.61 148.85,74.1 148.85,84.71 148.53,85.02 148.53,86.44 147.63,87.35 147.63,96.63 147.99,96.99 147.99,98.68 150.16,100.85 150.16,100.86 150.16,101.51 150.45,101.81 150.45,101.81 150.45,108.7 148.7,110.45 148.7,115.32 149.74,116.37 149.74,122.82 148.01,124.54 146.42,124.54 141.13,129.84 141.13,143.38 134.27,150.24 134.27,152.24 130.22,156.29 122.99,156.29 121.44,154.74 v2(121.44,154.48) ; v2(123.1,151.64) PU500.4
VR_SVID_ALERT#_SOC: length 8.4
  IN1 w0.102: v2(110.73,82.9) 110.71,82.89 110.71,82.1 110.37,81.75
  IN1 w0.127: 110.37,81.75 108.86,80.24 v2(108.05,80.24)
  BOTTOM w0.102: v2(110.73,82.9) 110.89,83.06 111.14,83.06 112.45,84.37 112.45,84.54 112.91,85 ; v2(108.05,80.24) 108.01,80.24 107.45,79.68 RC28.1
VR_SVID_CLK: length 169.5
  TOP w0.102: v1(122.09,155.62) v2(122.09,154.5) 122.09,153.58 PR527.1
  IN2 w0.127: v2(123.4,154.44) 122.92,154.92 122.48,154.92 122.09,154.53 v2(122.09,154.5)
  BOTTOM w0.102: v2(123.4,154.44) 124.03,155.07 129.63,155.07 133.15,151.55 133.15,149.77 140.01,142.91 140.01,130.48 140.01,129.38 145.96,123.43 147.55,123.43 148.62,122.35 148.62,116.83 147.58,115.79 147.58,110.92 147.58,109.99 149.33,108.24 149.33,102.27 149.17,102.1 149.04,101.98 149.04,101.91 149.04,101.31 146.87,99.14 146.87,97.46 146.51,97.1 146.51,86.88 147.41,85.98 147.41,84.56 147.73,84.24 147.73,74.67 146.9,73.84 146.46,73.84 145.28,72.66 145.28,72.22 145.01,71.94 136.68,71.94 131.07,66.33 108.97,66.33 106.7,68.6 106.7,73.44 105.81,74.33 105.81,75.51 106.86,76.56 106.86,77.03 109.24,79.41 109.24,79.67 111.64,82.08 111.64,82.62 113.3,84.27 113.3,84.51 113.5,84.72 USOC1.C25 ; PR527.1 122.09,153.58 v2(122.09,154.5)
VR_SVID_CLK_R: length 2
  BOTTOM w0.102: PU500.3 122.7,151.28 122.37,151.61 PR520.2
VR_SVID_DATA: length 165.3
  TOP w0.102: PR526.1 122.74,153.82 v2(122.74,154.45)
  BOTTOM w0.102: PR526.1 122.74,153.82 v2(122.74,154.45) 122.74,155.09 123.31,155.66 129.91,155.66 133.71,151.86 133.71,150 140.57,143.15 140.57,130.25 140.57,129.61 146.19,123.99 147.78,123.99 149.18,122.59 149.18,116.6 148.14,115.56 148.14,110.68 148.14,110.22 149.89,108.47 149.89,102.5 149.89,102.04 149.6,101.75 149.6,101.74 149.6,101.08 147.43,98.91 147.43,97.23 147.07,96.87 147.07,87.11 147.97,86.21 147.97,84.79 148.29,84.48 148.29,74.33 147.14,73.17 146.58,73.17 145.84,72.43 145.84,71.88 145.69,71.73 145.69,71.72 145.01,71.05 136.59,71.05 136.41,70.87 136.36,70.82 131.23,65.69 108.82,65.69 106.14,68.37 106.14,73.2 105.11,74.23 105.11,75.6 106.31,76.79 106.31,77.31 108.58,79.59 108.58,80.38 RC29.2
VR_SVID_DATA_R: length 2.1
  BOTTOM w0.102: PU500.5 123.5,150.9 123.6,151.01 123.6,152.05 PR521.2
VR_SVID_DATA_SOC: length 4.8
  BOTTOM w0.102: RC29.1 110.13,81.35 v1(110.77,81.99) 111.12,82.35 111.12,82.47 112.98,84.33 USOC1.A25
VSUM+: length 8.9
  TOP w0.254: PC529.1 128.99,148.23 PC530.1 128.48,149.22 PR541.1 PR535.1 ; PR536.2 128.24,151.6 128.48,151.35 PR535.1 ; v2(126.83,150.88) v1(127.48,150.88) 128.35,150.88 PR535.1
  BOTTOM w0.254: v2(126.83,150.88) 126.76,150.88 126.05,150.17 126.05,149.71 125.86,149.53 125.79,149.46 PU500.10
VSUM-: length 42
  TOP w0.102: PC534.1 v1(130.89,149.35)
  TOP w0.254: v2(130.31,150.12) PR541.2 129.39,149.22 PC530.2 129.9,148.71 PC529.2 129.9,146.95 PR540.2 130.77,146.95 PC532.2 131.17,147.35 131.17,148.06 PC534.1
  IN2 w0.254: v2(130.31,150.12) 130.31,150.27 130.87,150.83 132.39,150.83 137.47,145.75 137.47,134.66 135.18,132.37 135.18,130.98 135.94,130.23 v2(136.1,130.23)
  BOTTOM w0.254: v2(136.1,130.23) PH503.2 131.35,130.23 130.74,129.62 PL501.3
VSUMG+: length 9.1
  TOP w0.254: PR513.2 116.12,151.72 PR500.2 117.91,151.72 v1(118.24,151.39) 118.93,150.71 118.93,150.07 ; PC514.2 119.24,148.35 PC513.2 118.92,149.32 PR509.2 118.93,150.07 ; v2(120.43,150.25) 120.25,150.07 118.93,150.07
  BOTTOM w0.203: PU500.32 120.87,149.86 120.48,150.25 v2(120.43,150.25)
VSUMG-: length 37.8
  TOP w0.102: v1(118.14,147.02) PR507.1
  TOP w0.254: v2(116.01,149.82) PC512.1 117.12,150.06 PR509.1 117.84,149.9 PC513.1 117.94,148.91 PC514.1 PR502.2 117.13,147.91 PR507.1
  IN2 w0.254: v2(116.01,149.82) 115.86,149.97 115.77,149.97 115.54,150.2 114.91,150.2 114.36,149.65 114.36,147.12 114.36,147.12 114.36,137.84 115.63,136.57 115.63,131.28 v2(116.78,130.12)
  BOTTOM w0.254: PL500.3 122.23,129.75 121.85,130.13 117.54,130.13 PH500.1 116.82,130.09 v2(116.78,130.12)
VTTREF_1.35VP: length 4.4
  TOP w0.102: v1(57.44,55.16) 57.44,53.64 56.97,53.17 PC212.1
  TOP w0.203: PC212.1 56.97,52.71 57.73,51.94 PU200.4
WL_OFF#: length 152.1
  TOP w0.102: v2(146.93,116.02) 146.92,116.04 146.59,116.04 146.53,115.97 145.57,115.97 145.33,116.21 145.33,117.94 144.71,118.56 144.71,125.69 141.92,128.48 v2(141.92,130.26) ; v2(138.99,45.55) v1(138.99,48.5) 138.99,50.19 141.29,52.48 141.29,62.94 145.17,66.81 147.66,66.81 148.34,67.49 148.34,69.49 147.29,70.54 147.29,74.5 146.94,74.84 146.94,83.92 144.89,85.97 144.89,89.8 144.71,89.97 144.71,94.06 140.65,98.13 138.69,98.13 136.78,100.03 v2(136.78,100.27) 136.78,100.3 136.86,100.38 136.86,108.36 137.75,109.25 v2(137.75,109.25) 137.44,109.56 134.93,109.56 134.75,109.73 RP54.3
  IN1 w0.127: v2(143.19,110.84) 142.94,110.84 141.41,109.3 137.83,109.3 137.75,109.23 137.75,109.25 v2(137.75,109.25) ; v2(143.4,40.52) 143.4,40.53 143.41,40.53 144.58,40.53 146.23,42.18 149.6,42.18 151.97,44.55 154.57,44.55 v2(156.53,46.52)
  IN2 w0.102: 131.95,100.22 133.12,101.4 ; 131.61,100.22 129.79,100.22 128.37,98.81 v2(127.42,98.81)
  IN2 w0.127: 131.61,100.22 131.95,100.22 ; 133.12,101.4 134.92,101.4 134.93,101.39 136.63,101.39 136.86,101.16 136.86,100.38 136.78,100.3 v2(136.78,100.27)
  BOTTOM w0.102: v2(141.92,130.26) 144.33,132.67 RE14.2 ; v2(143.4,40.52) 142.12,40.52 138.99,43.65 v2(138.99,45.55) ; QM30.3 157.57,47.56 v2(156.53,46.52) ; v2(127.42,98.81) 127.37,98.75 USOC1.BA26 ; v2(143.19,110.84) 146.84,114.5 146.84,115.93 v2(146.93,116.02)
WL_OFF#_EC: length 3.4
  BOTTOM w0.102: RE14.1 147.73,132.14 v1(148.3,132.14) 148.7,132.14 149.33,132.77 UE1.98
WLAN_CLKREQ#: length 127.5
  TOP w0.102: v2(165.16,67.88) 162.37,70.67 159.34,70.67 v1(158.66,71.35) v2(158.66,72.13) ; v2(152.08,101.68) 150.21,103.55 150.21,105.71 v2(144.96,110.96) ; RP63.2 120.92,110.36 121.28,110.01 121.28,107.3 121.04,107.07 121.04,105.57 v2(121.63,104.98)
  IN1 w0.127: v2(158.81,103.06) 158.81,102.93 156.17,100.29 156.17,98.72 156.77,98.11 156.77,91.04 161.27,86.55 161.27,83.33 160.66,82.71 160.66,74.13 v2(158.66,72.13)
  IN2 w0.102: v2(121.63,104.98) 121.63,105.29 121.35,105.56 121.35,106 121.01,106.34 121.01,106.9 121.13,107.02 121.98,107.02 122.34,107.38 124.46,107.38
  IN2 w0.127: v2(144.96,110.96) 144.58,111.34 143.06,111.34 141.39,109.66 138.84,109.66 136.78,107.6 133.96,107.6 133.23,106.87 128.47,106.87 127.97,107.38 124.46,107.38
  BOTTOM w0.102: v2(121.63,104.98) 121.63,105.11 121.73,105.22 USOC1.BD7 ; JNGFF.45 164.25,49.85 164.34,49.94 164.34,52.29 165.47,53.42 165.47,58.95 164.9,59.52 160.78,59.52 160.08,60.22 160.08,61.93 159.25,62.76 159.25,65.3 159.82,65.87 163.15,65.87 v2(165.16,67.88) ; v2(158.81,103.06) 156.01,103.06 155.2,102.24 152.63,102.24 v2(152.08,101.68)
WLAN_RADIO_DIS#_R: length 16.4
  TOP w0.102: v2(168.76,49.94) 168.65,49.83 168.12,49.83 RM110.2 165.59,48.9 164.28,47.59 159.29,47.59 v1(158.82,48.06) 157.97,48.92 v2(157.97,49.39)
  BOTTOM w0.102: JNGFF.48 169.92,49.1 169.48,49.54 169.28,49.54 168.88,49.94 v2(168.76,49.94) ; v2(157.97,49.39) 158.22,49.64 QM30.1
WLAN_WAKE#: length 109.8
  TOP w0.102: v2(161.58,48.84) 161.58,48.89 162.92,50.24 R490.2 162.92,52.7 v1(163.19,52.97)
  IN1 w0.127: v2(161.58,48.84) 162.62,49.88 162.62,55.07 163.82,56.28 165.26,56.28 171.02,62.04 171.02,70.76 170.71,71.07 170.71,83.1 169.86,83.95 169.86,92.43 169.86,92.65 170.36,93.15 170.36,93.32 171.37,94.33 171.37,99.8 171.09,100.08 171.09,103.21 169.6,104.69 169.6,107.53 170.15,108.07 170.15,118.37 163.88,124.63 163.74,124.63 163.06,125.31 161.65,125.31 159.34,127.62 159.34,133.46 v2(159.44,133.56)
  BOTTOM w0.102: UE1.86 155.76,132.8 156.52,133.56 v2(159.44,133.56) ; v2(161.58,48.84) 162.09,49.35 JNGFF.47
XDP_H_PRDY#: length 110.6
  TOP w0.102: v2(34.22,67.14) 34.49,67.41 34.49,72.96 31.77,75.67 JDB1.2 31.77,78.08 v1(32,78.3) 32,79.07 CC52.1 ; v2(111.83,87.35) 111.76,87.28 RC65.2
  IN1 w0.102: v2(111.83,87.35) 111.05,87.35 110.91,87.49 110.53,87.49 109.85,88.17 108.52,88.17 108.25,87.9 107.28,87.9 106.48,88.7 105.97,88.7 105.29,89.39 103.74,89.39 103.43,89.7 102.78,89.7 102.73,89.75 102.37,89.75
  IN1 w0.127: 102.37,89.75 102,89.75 98.4,93.34 98.05,93.34 97.34,92.63 95.55,92.63 88.06,85.14 86.6,85.14 85.99,84.52 85.99,83.06 82.28,79.35 82.28,79.18 81.85,78.75 80.68,78.75 79.94,78.01 79.94,73.39 78.47,71.92 71.1,71.92 70.74,72.27 62.86,72.27 61.41,70.82 59.75,70.82 56.06,67.14 v2(34.22,67.14)
  BOTTOM w0.102: v2(111.83,87.35) 111.75,87.43 USOC1.D18
XDP_H_PREQ_BUF#: length 114.5
  TOP w0.102: v2(33.84,69.43) 33.84,73.12 31.27,75.69 JDB1.1 31.27,77.68 v1(30.69,78.27) 30.66,78.29 CC50.1 30.55,79.5 v2(29.8,79.5) ; RC61.2 v2(35.24,81.01)
  IN1 w0.102: 102.12,91.14 102.34,91.14 103.18,90.3 103.68,90.3 103.98,90.01 106.05,90.01 106.07,90.04 107.05,90.04 108.31,88.78 110.1,88.78 110.49,88.39 111.41,88.39 111.54,88.51 v2(111.68,88.51)
  IN1 w0.127: 102.12,91.14 101.19,92.08 101.19,92.65 100.94,92.9 99.92,92.9 98.72,94.1 97.74,94.1 97.02,93.39 95.86,93.39 93.78,93.39 81.79,81.41 81.79,81.02 81.79,80.94 81.24,80.39 79.18,78.32 79.18,77.22 79.18,73.7 78.15,72.68 76.03,72.68 75.67,73.04 62.55,73.04 61.91,72.4 60.86,72.4 60.46,71.99 58.49,71.99 57.61,71.12 43.8,71.12 41.23,68.54 39.47,68.54 38.58,69.43 v2(33.84,69.43)
  IN2 w0.127: v2(35.24,81.01) 34.33,81.01 33.51,80.18 30.49,80.18 v2(29.8,79.5)
  BOTTOM w0.102: v2(111.68,88.51) 111.68,88.55 111.55,88.67 USOC1.F16
XDP_H_TCK: length 105.1
  TOP w0.102: RP66.6 v4(77.27,72.6) 77.27,73.74 v2(77.78,74.25) ; v2(41.05,68.96) 41.8,69.71 41.8,75.29 42.41,75.9 43.45,75.9 43.77,76.22 JDB1.26 43.77,77.76 CC65.1
  IN1 w0.102: 102.12,92.23 102.19,92.23 103.24,91.18 103.67,91.18 104.23,90.62 105.79,90.62 105.82,90.65 107.3,90.65 108.27,89.68 108.56,89.39 109.72,89.39 v2(110.15,89.82)
  IN1 w0.127: v2(77.78,74.25) 77.78,78 79.85,80.07 81.03,81.25 81.03,81.34 81.03,81.34 81.03,81.72 93.46,94.15 94.92,94.15 96.18,94.15 96.18,94.15 96.71,94.15 97.42,94.86 100.05,94.86 101.95,92.97 101.95,92.4 102.12,92.23
  BOTTOM w0.102: v2(110.15,89.82) 110.15,89.59 USOC1.D14 ; v2(41.05,68.96) 59.06,68.96 59.53,68.49 65.97,68.49 70.69,73.21 76.94,73.21 77.36,73.63 77.36,73.83 v2(77.78,74.25)
XDP_H_TDI: length 108.5
  TOP w0.102: v2(76.76,74.25) 76.27,73.76 RP66.8 ; CC61.1 v4(42.38,78.4) 41.77,77.79 JDB1.22 41.77,76.76 41.23,76.22 41.23,75.65 41.07,75.49 41.07,70.44 v2(40.32,69.68)
  IN1 w0.102: v2(110.97,89.17) 110.98,89.19 110.98,89.91 111.1,90.02 111.1,90.51 110.88,90.73 110.21,90.73 109.27,89.8 108.73,89.8 108.44,90.09 107.47,91.05 105.65,91.05 105.62,91.03 104.68,91.03 104.13,91.59 103.59,91.59 102.46,92.72
  IN1 w0.127: v2(76.76,74.25) 76.76,77.71 79.34,80.28 80.52,81.47 80.52,81.55 80.52,81.93 93.25,94.66 94.71,94.66 96.5,94.66 97.83,95.99 99.74,95.99 102.46,93.28 102.46,92.72 102.46,92.72
  BOTTOM w0.102: v2(76.76,74.25) 71.09,74.25 65.78,68.94 59.72,68.94 59.19,69.48 42.2,69.48 41.59,70.09 40.72,70.09 v2(40.32,69.68) ; v2(110.97,89.17) 110.98,89.17 110.98,89.26 110.53,89.72 110.53,90 110.15,90.37 USOC1.F12
XDP_H_TDO: length 104.6
  TOP w0.102: v2(39.55,69.05) 39.55,70.51 40.25,71.2 40.25,75.32 40.77,75.84 JDB1.20 40.77,78.25 40.32,78.71 CC56.1 RC63.2 40.79,79.93 40.79,81.24 v4(40.56,81.47)
  IN1 w0.102: 102.12,91.66 103.27,90.51 103.77,90.51 104.06,90.22 105.96,90.22 105.99,90.24 107.13,90.24 108.39,88.98 110.18,88.98 110.58,88.59 111.21,88.59 111.56,88.93 v2(112.1,88.93)
  IN1 w0.127: v2(39.55,69.05) 39.9,69.39 39.9,69.86 41.41,71.37 57.44,71.37 58.36,72.3 60.41,72.3 60.76,72.65 61.8,72.65 62.44,73.29 75.78,73.29 76.14,72.93 78.05,72.93 78.92,73.81 78.92,76.48 78.92,76.49 78.92,77.33 78.92,78.43 80.36,79.86 80.36,79.86 81.14,80.64 81.54,81.04 81.54,81.13 81.54,81.51 93.67,93.64 95.13,93.64 95.13,93.64 95.97,93.64 96.92,93.64 97.63,94.36 98.82,94.36 100.03,93.15 101.05,93.15 101.44,92.76 101.44,92.19 101.98,91.66 102.12,91.66
  BOTTOM w0.102: USOC1.G16 112.06,88.97 v2(112.1,88.93)
XDP_H_TMS: length 108.3
  TOP w0.102: v2(41.08,69.68) 41.57,70.18 41.57,76.03 42.27,76.73 JDB1.23 42.27,77.66 42.93,78.32 43.31,78.32 CC63.1 44.38,79.41 43.9,79.89 43.9,81.1 v4(44.19,81.39) ; RP66.7 v2(76.77,73.61)
  IN1 w0.102: v2(111.37,89.63) 111.37,90.53 110.22,91.67 105.54,91.67 105.42,91.79 103.89,91.79 102.71,92.97
  IN1 w0.127: v2(76.77,73.61) 76.35,74.04 76.35,77.65 79.09,80.39 80.27,81.57 80.27,81.66 80.27,81.66 80.27,82.04 93.15,94.91 94.6,94.91 96.39,94.91 97.73,96.25 99.84,96.25 102.71,93.38 102.71,92.97
  BOTTOM w0.102: v2(41.08,69.68) 41.51,69.25 59.09,69.25 59.63,68.71 65.87,68.71 70.77,73.61 v2(76.77,73.61) ; v2(111.37,89.63) 111.16,89.83 USOC1.F14
XDP_H_TRST#: length 108.8
  TOP w0.102: v4(42.4,81.43) 41.85,80.88 41.85,79.87 42.34,79.38 CC59.1 41.27,78.31 JDB1.21 41.27,76.81 41,76.54 41,75.74 40.57,75.32 40.57,70.7 39.91,70.04 39.91,69.52 40.32,69.11 40.32,69.07 v2(40.34,69.05) ; RP66.5 v2(77.77,73.61)
  IN1 w0.102: 102.26,92.51 103.39,91.38 103.77,91.38 104.32,90.83 105.71,90.83 105.73,90.85 107.39,90.85 108.35,89.88 108.64,89.59 109.38,89.59 110.04,90.25 110.62,90.25 v2(110.72,90.35)
  IN1 w0.127: v2(77.77,73.61) 77.36,74.01 77.36,77.94 79.6,80.18 79.6,80.18 80.78,81.36 80.78,81.4 80.78,81.45 80.78,81.83 93.36,94.4 94.81,94.4 96.6,94.4 97.94,95.74 99.63,95.74 102.2,93.17 102.2,92.57 102.26,92.51
  BOTTOM w0.102: USOC1.G12 110.66,90.41 v2(110.72,90.35) ; v2(77.77,73.61) 77.14,72.98 70.78,72.98 66.06,68.26 59.44,68.26 59.02,68.68 41.6,68.68 41.47,68.55 40.83,68.55 v2(40.34,69.05)
XDP_OBSDATA_A0: length 111.6
  TOP w0.102: JDB1.4 32.77,75.1 34.83,73.05 34.83,66.84 35.24,66.44 v2(35.24,66.38)
  IN1 w0.102: v2(115.59,88.41) 114.25,88.41 114.14,88.52 113.54,88.52 111.99,86.96 111.15,86.96 110.83,87.28 110.45,87.28 109.76,87.97 108.6,87.97 108.33,87.7 107.2,87.7 106.4,88.5 105.89,88.5 105.2,89.19 103.64,89.19 103.34,89.49 102.63,89.49
  IN1 w0.127: v2(35.24,66.38) 35.49,66.63 56.19,66.63 60.13,70.57 61.52,70.57 62.97,72.02 70.64,72.02 70.99,71.66 78.58,71.66 80.19,73.28 80.19,77.9 80.79,78.49 81.95,78.49 82.53,79.07 82.53,79.25 86.24,82.96 86.24,84.41 86.71,84.88 88.16,84.88 95.65,92.37 98.95,92.37 101.83,89.49 102.63,89.49
  BOTTOM w0.102: v2(115.59,88.41) 116.08,88.9 USOC1.N24
XDP_OBSDATA_A1: length 109.1
  TOP w0.102: JDB1.5 33.27,74.96 35.16,73.07 35.16,67.72 v2(35.24,67.65)
  IN1 w0.102: v2(114.62,88.79) 112.98,88.79 112.13,87.93 110.37,87.93 109.93,88.37 108.43,88.37 108.16,88.1 107.37,88.1 106.57,88.91 106.06,88.91 105.37,89.59 103.82,89.59 103.51,89.9 102.87,89.9 102.47,90.29 102.12,90.29
  IN1 w0.127: v2(35.24,67.65) 55.22,67.65 58.68,71.12 61.35,71.12 62.76,72.53 71.65,72.53 72.01,72.17 78.36,72.17 79.69,73.49 79.69,78.11 80.58,79 81.74,79 82.02,79.28 82.02,79.54 85.73,83.25 85.73,84.62 86.5,85.39 87.71,85.39 88.11,85.78 88.11,86.69 94.29,92.88 95.44,92.88 97.24,92.88 97.95,93.59 98.51,93.59 101.81,90.29 102.12,90.29
  BOTTOM w0.102: v2(114.62,88.79) 114.93,89.09 USOC1.M20
XDP_OBSDATA_A2: length 101.3
  TOP w0.102: JDB1.7 34.27,74.68 36.12,72.84 v2(36.12,70.44)
  IN1 w0.102: v2(112.91,89.8) 112.13,89.8 111.13,88.79 110.66,88.79 110.27,89.19 108.47,89.19 108.18,89.48 107.22,90.44 105.9,90.44 105.88,90.42 104.14,90.42 103.59,90.98 103.16,90.98 102.19,91.94 102.12,91.94
  IN1 w0.127: v2(36.12,70.44) 37.3,71.63 57.33,71.63 58.26,72.55 60.3,72.55 60.65,72.91 61.7,72.91 62.34,73.54 75.88,73.54 76.24,73.19 77.94,73.19 78.67,73.91 78.67,76.38 78.67,78.53 80.1,79.97 81.03,80.89 81.03,80.89 81.29,81.15 81.29,81.24 81.29,81.62 93.57,93.9 95.02,93.9 96.81,93.9 97.53,94.61 99.95,94.61 101.69,92.86 101.69,92.3 102.05,91.94 102.12,91.94
  BOTTOM w0.102: USOC1.J18 113.25,89.46 v2(112.91,89.8)
XDP_OBSDATA_A3: length 105.6
  TOP w0.102: JDB1.8 34.77,74.73 36.59,72.91 36.59,69.39 v2(36.12,68.92)
  IN1 w0.102: v2(113.77,90.67) 113.77,90.07 111.84,88.13 110.46,88.13 110.01,88.58 108.35,88.58 108.08,88.31 107.45,88.31 106.65,89.11 106.14,89.11 105.46,89.8 103.9,89.8 103.6,90.1 103.1,90.1 102.31,90.89 102.12,90.89
  IN1 w0.127: v2(36.12,68.92) 38.73,68.92 39.36,68.29 42.35,68.29 44.93,70.87 57.76,70.87 58.26,71.37 60.2,71.37 60.97,72.14 62.01,72.14 62.65,72.78 75.57,72.78 75.93,72.42 78.26,72.42 79.43,73.6 79.43,76.7 79.43,78.22 80.87,79.65 81.35,80.13 81.35,80.13 82.05,80.83 82.05,80.92 82.05,81.3 86.39,85.64 86.7,85.64 94.19,93.13 95.34,93.13 97.13,93.13 97.84,93.85 98.61,93.85 101.57,90.89 102.12,90.89
  BOTTOM w0.102: USOC1.M18 114.03,90.45 113.81,90.67 v2(113.77,90.67)
XDP_RSTBTN#: length 129.6
  TOP w0.102: v2(121.44,117.41) 122.6,117.41 123.06,116.95 123.06,114.32 125.08,112.3 v2(125.08,111.93) ; JDB1.18 v2(39.77,78.42) 39.77,78.91 CC53.1 ; v2(37.27,81.01) CC49.1 RC62.2 36.25,81.02 v1(35.88,81.39)
  IN1 w0.127: v2(95.07,111.04) 91.01,106.99 91.01,96.67 91.01,95.83 78.11,82.93 78.11,82.55 78.11,82.55 78.11,82.47 76.93,81.29 76.93,81.28 72.74,77.09 63.39,77.09 63.39,77.1 58.29,77.1 56.61,75.42 46.82,75.42 44.44,77.79 v2(44.44,77.81)
  IN2 w0.127: v2(39.77,78.42) 39.77,78.5 v2(37.27,81.01)
  BOTTOM w0.102: v2(95.07,111.04) 94.89,111.22 94.89,113.76 99.29,118.17 104.68,118.17 105.29,117.56 107.74,117.56 108.22,117.08 110.03,117.08 110.63,117.67 112.78,117.67 113.98,118.87 119.98,118.87 v2(121.44,117.41) ; v2(44.44,77.81) 43.83,78.42 v2(39.77,78.42) ; CC12.1 RC24.2 124.47,111.33 v2(125.08,111.93)
XTAL_25M_IN: length 14.8
  IN2 w0.102: 111.59,101.85 111.59,101.75 111.91,101.43 111.91,100.64 113.23,99.32 114.1,99.32 115.04,98.39 v2(116.98,98.39)
  IN2 w0.127: v2(112.52,104.26) 112.52,104.05 111.59,103.12 111.59,101.85
  BOTTOM w0.102: v2(116.98,98.39) 117.06,98.46 USOC1.AH12 ; v2(112.52,104.26) 112.52,104.25 112.03,103.76 111.77,103.76 RC19.1 111.69,103.71 CC9.1 110.63,104.77 110.63,105.45 YC1.1
XTAL_25M_OUT: length 13.8
  IN2 w0.102: v2(116.55,98.87) 116.48,98.8 115.26,98.8 112.34,101.72 112.34,102.6
  IN2 w0.127: v2(112.34,103) 112.34,102.6
  BOTTOM w0.102: YC1.3 108.94,105.62 109.94,104.62 CC10.1 110.84,103.06 RC19.2 112.28,103.06 v2(112.34,103) ; v2(116.55,98.87) 116.64,98.96 117.15,98.96
N17188574: length 1.6
  TOP w0.102: PC400.2 v1(43.43,26.04)
N17188613: length 1.7
  TOP w0.102: v1(48.74,24.84) 48.3,24.4 PR401.2
N17227658: length 2.8
  BOTTOM w0.102: 152.04,89.64 151.95,89.56 149.83,89.56 v1(149.45,89.94)
N17227663: length 3.4
  BOTTOM w0.254: PR410.2 PC413.2 PR412.1 PU402.2
N17227696: length 5
  BOTTOM w0.102: PR409.2 159.01,93.4 v2(159.35,93.06)
  BOTTOM w0.254: PU402.8 157.98,92.55 158.27,92.84 PR409.2 PC415.1 PR411.1
N17253612: length 6.2
  TOP w0.203: v2(37.78,44.09) 37.9,44.21 PU100.12
  BOTTOM w0.102: v1(34.07,43.14) PR111.2
  BOTTOM w0.508: v2(37.78,44.09) 37.78,43.2 PC116.1 PR111.2
N17256470: length 3.8
  TOP w0.203: v2(57.33,47.12) 57.33,47.31 57.73,47.71 PU200.12
  TOP w0.254: PC210.2 56.97,46.76 v2(57.33,47.12)
  BOTTOM w0.102: v2(57.33,47.12) v1(57.33,46.58)
  BOTTOM w0.254: v2(57.33,47.12) 57.73,47.52 PR209.2
N17256593: length 1.8
  TOP w0.102: PR202.2 v1(58.73,31.97)
N17322320: length 127.2
  TOP w0.102: 146.28,137.03 PR13.1 ; 146.28,137.03 PR10.2 PC7.1 v1(146.28,140.06) ; 146.28,137.03 145.68,137.03 v2(145.36,137.35)
  TOP w0.254: v2(144.84,72.98) 144.84,73.11 144.2,73.74 144.2,75.95 145.95,77.7 145.95,83.51 142.8,86.65 142.8,88.2 142.3,88.7 142.3,91.75 139.43,94.62 136.23,94.62 PH1.1
  IN1 w0.127: v2(145.36,137.35) 146.04,136.66 146.04,134.26 146.17,134.14 146.17,130.72 147.28,129.62 147.28,125.53 148.43,124.37 148.46,124.35 153.17,119.64 153.57,119.24 155.21,119.24 155.93,118.52 158.55,115.89 158.55,113.18 161.25,110.49 161.25,104.26 160.59,103.59 160.23,103.59 159.28,102.64 158.88,102.64 156.42,100.18 156.42,98.82 157.03,98.21 157.03,91.15 161.52,86.65 161.52,83.22 160.91,82.61 160.91,74.02 159.09,72.2 159.09,71.92 158.84,71.67 151.22,71.67 150.11,72.79 147.5,72.79 147.06,73.24 145.09,73.24 v2(144.84,72.98)
N17322935: length 5.1
  TOP w0.102: PR12.2 v1(128.64,156.36)
  TOP w0.254: PR12.2 127.95,159.02 127.95,159.85 128.31,160.22 PQ3.3
N17322941: length 5.8
  TOP w0.102: PR14.1 133.53,161.35 v1(133.93,161.74)
  TOP w0.254: PR19.2 131.82,161.52 PQ3.6 ; PR19.2 130.89,160.82 PQ3.5 ; PR19.2 PR14.1
N17330968: length 1.2
  BOTTOM w0.102: RC52.1 130.94,110.48 T211.1
N17354752: length 36.1
  TOP w0.102: v4(129.63,153.5) PR536.1
  TOP w0.254: PR536.1 v2(130.31,152.15)
  IN2 w0.254: v2(130.31,152.15) 131.79,152.15 137.98,145.96 137.98,134.45 135.69,132.16 135.69,131.26 v2(136.07,130.88)
  BOTTOM w0.254: PL501.2 130.74,131.02 131.02,130.74 134.65,130.74 134.8,130.89 136.06,130.89 v2(136.07,130.88)
N17407779: length 2.1
  BOTTOM w0.102: CE12.1 155.42,150.15 R2354.1 v1(155.42,151.17)
N17434553: length 1.1
  BOTTOM w0.102: RE36.1 T218.1
N17434554: length 3.1
  BOTTOM w0.102: RE36.2 147.6,136.37 UE1.107
N18943829: length 26.8
  TOP w0.102: v2(149.79,152.74) v1(150.49,152.74)
  TOP w0.254: PR724.1 149.02,151.96 v2(149.79,152.74)
  BOTTOM w0.254: v2(149.79,152.74) 150.3,152.23 165.97,152.23 167.19,153.45 167.19,156.17 166.55,156.8 164.65,156.8 164.27,156.42 PR720.2
N18944147: length 33.7
  TOP w0.102: v2(148.71,150.52) v1(149.37,150.52)
  TOP w0.254: PU700.17 146.26,153.27 PC722.2 PC726.1 148.52,150.71 v2(148.71,150.52)
  BOTTOM w0.254: PR720.3 164.27,157.31 164.39,157.18 166.71,157.18 167.57,156.33 167.57,153.25 166.17,151.85 150.42,151.85 149.09,150.52 v2(148.71,150.52)
N18956218: length 5.3
  TOP w0.102: PR724.2 148.95,153.64 v1(149.19,153.88)
  TOP w0.254: PU700.18 147.16,153.77 PC722.1 148.71,153.12 PR724.2
N18967347: length 2.2
  TOP w0.102: PC727.1 v1(135.15,150.46)
  TOP w0.254: PR723.2 136.89,150.52 136.84,150.46 PC727.1
N18967375: length 3.9
  TOP w0.254: PU700.4 139.3,153.77 v2(139.17,153.64)
  BOTTOM w0.102: PC721.1 v1(139.99,151.54)
  BOTTOM w0.254: v2(139.17,153.64) 139.17,152.94 139.54,152.57 PC721.1
N18967379: length 3.7
  TOP w0.254: PU700.6 139.76,152.77 139.13,152.14 v1(139.13,151.23) 139.13,150.99 138.66,150.52 PR723.1
N18967435: length 5
  TOP w0.102: PC723.1 v1(138.23,148.28)
  TOP w0.254: PC723.1 139.68,150.95 139.68,151.91 140.03,152.27 PU700.7
N18967441: length 4.5
  TOP w0.254: PR725.1 137.65,152.09 137.65,151.99 PR728.2 138.75,151.93 138.75,152.37 v1(139.15,152.76) 139.65,153.27 PU700.5
N18999155: length 7.3
  TOP w0.254: PR704.2 138.31,157.93 138.39,157.86 PC709.1 138.96,157.28 138.78,157.11 v2(138.78,156.75) 141.08,156.75 141.23,156.6 PU700.28
  BOTTOM w0.102: v1(139.68,157.95) PC706.1
  BOTTOM w0.254: PC706.1 v2(138.78,156.75)
N19000258: length 8.6
  TOP w0.254: PU700.27 141.73,156.99 v2(141.2,157.51) 140.86,157.86 PC709.2 140.35,158.67 139.97,159.05 v1(137.42,159.05) 137.04,158.67 PR705.2
  BOTTOM w0.254: v2(141.2,157.51) 140.9,157.21 PC707.1
N19021042: length 13.5
  TOP w0.254: v2(142.1,157.51) 142.23,157.39 PU700.26
  BOTTOM w0.381: PC710.1 142.12,157.5 v2(142.1,157.51) 141.48,158.13 v1(141.48,159.29) 143.23,161.04 143.43,161.08 143.44,161.08 146.46,161.08 146.87,160.68 146.87,158.63 147.55,157.95
N19093256: length 4.1
  TOP w0.102: PU700.10 142.23,149.69 PR717.2 142.36,149.58 142.92,149.02 142.92,147.81 v1(143.1,147.63)
N19093259: length 1.9
  TOP w0.102: PU700.9 141.73,149.85 PR719.2
N19095003: length 4.4
  TOP w0.102: v1(141,147.53) 141,149.13 140.56,149.58 PR722.2
  TOP w0.254: PU700.8 141.23,150.86 140.52,150.15 PR722.2
N19142937: length 61.7
  TOP w0.508: PC701.1 95.54,149.88 PR701.2 96.02,149.4 PC700.2 98.6,149.4 PQ707.1 100.45,149.02 100.86,149.42 100.86,149.97 101.07,150.19 PQ705.4 104.17,150.19 104.55,150.57 104.55,152.92 v2(104.54,152.93) 104.55,152.94 104.55,154.27 103.71,155.11 101.39,155.11 v1(100.86,155.64) 100.37,156.13 PQ704.4 ; v2(131.07,170.72) PR703.1
  IN1 w0.508: v2(104.54,152.93) 104.54,153.04 105.9,154.4 105.9,160.59 106.28,160.97 106.28,161.41 108.94,164.07 110.14,164.07 110.85,164.78 110.85,167.48 113.43,170.06 130.41,170.06 v2(131.07,170.72)
N19565438: length 56.5
  TOP w0.254: PQ707.2 99.63,150.23 v2(100.21,149.65) ; v2(134.35,169.17) 134.35,168.69 135.27,167.76 PQ708.1 ; v2(105.4,169.98) 105.56,170.14 v1(107.6,170.14) v2(108.26,170.14)
  IN1 w0.254: v2(134.35,169.17) 134.35,169.45 133.91,169.88 132.77,169.88 131.37,171.28 109.4,171.28 v2(108.26,170.14) ; v2(105.4,169.98) 105.4,169.77 101.45,165.82 101.45,154.43 100.21,153.18 v2(100.21,149.65)
N19565442: length 7.5
  TOP w0.102: PR703.2 v1(130.78,169.81)
  TOP w0.254: PR703.2 132.38,169.44 PQ709.3 132.38,167.71 131.63,166.96 131.63,164.93 131.26,164.56 PQ710.3
N19565444: length 7.4
  TOP w0.102: PQ712.1 134.51,171.66 v1(135.02,172.17)
  TOP w0.254: PQ712.1 134.31,169.81 PR712.2 PQ709.2 PQ709.5
N19565472: length 3.2
  TOP w0.102: PR708.1 v1(160.84,165.64)
  TOP w0.508: PQ711.1 159.7,167.69 PR708.1
N22321388: length 2.7
  TOP w0.102: T212.1 156.47,132.2 v2(156.75,132.48)
  BOTTOM w0.102: UE1.82 157.36,131.87 v2(156.75,132.48)
N23955686: length 3.6
  BOTTOM w0.102: T105.1 110.43,84.41 111.4,85.37 111.62,85.37 111.92,85.68 111.92,85.83 112.13,86.04 USOC1.C21
N23993932: length 2.3
  BOTTOM w0.102: v1(103.51,73.32) 103.97,72.86 CC24.2 RC39.2
N24334655: length 1.4
  BOTTOM w0.102: v1(159.35,94.38) 159,94.74 PC300.2
N24334673: length 1.1
  BOTTOM w0.102: v1(164.55,99.54) 164.27,99.26 PC305.1
N24559749:
  vias: v4(151.19,115.82)
N24559796: length 1.1
  BOTTOM w0.102: v1(158.07,118.19) 157.92,118.04 PC306.1
N24654163: length 1.4
  TOP w0.102: PC112.2 v1(31.67,47.34)
N24654248: length 1.3
  TOP w0.102: PC113.1 v1(44.8,47.34)
N25654694: length 3.7
  BOTTOM w0.102: RA2.2 v1(139.86,26.07)
  BOTTOM w0.254: RA2.2 141.85,26.39 QA5.6 QA5.5
N25654700: length 7.2
  BOTTOM w0.102: CA1.1 v1(148.85,25.8)
  BOTTOM w0.254: CA1.1 CA2.1 144.71,25.8 QA5.2 144.16,25.74 143.92,25.5 143.92,24.62 144.71,23.83 RA3.2
N25858228: length 3.8
  TOP w0.102: v1(151.63,80.41) 153.17,80.41 153.64,79.94 RS09.2 153.69,79.91 JODD1.8
N25860239: length 6.5
  BOTTOM w0.102: R1049.2 C1132.1 151.16,41.03 RC69.1 150.37,40.34 149.08,40.34 148.34,39.6 148.34,39.53 Y9.1
N25865342: length 5.4
  TOP w0.102: v1(107.61,107.42) 106.53,108.49 R2450.1 R2448.2 105.76,110.58 U2407.7
N26297922: length 3.2
  TOP w0.102: CX52.1 110.51,156.6 v1(110.61,156.7) 110.94,157.03 v2(110.94,157.59)
  BOTTOM w0.102: UX3.4 111.03,156.97 111.09,157.03 111.09,157.44 v2(110.94,157.59)
N26299865: length 4.3
  TOP w0.102: UE4.6 60.39,70.45 60.52,70.58 61.21,70.58 CE60.1 62.29,70.39 62.52,70.16 v1(62.52,68.61)
N26526512: length 4.7
  TOP w0.102: PC10.1 PR35.1 ; PR35.1 164.06,131.81 PR36.1 ; PR35.1 v1(165.08,131.91) PR34.1
N26599744: length 58
  TOP w0.102: v2(168.4,153.47) 168.43,153.47 169.13,152.78 169.13,149.48 170.06,148.55 170.06,146.98 170.48,146.56 170.48,143.72 171.1,143.1 171.1,141.21 v2(172.07,140.24) ; v2(145.55,134.7) PR18.1 ; PR18.1 PR11.2 v1(145.12,135.97) ; PR18.1 PR20.1 PR15.1
  IN2 w0.127: v2(145.55,134.7) 145.55,136.1 150.08,140.63 150.08,144.56 151.22,145.7 151.22,148.44 154.64,151.85 166.58,151.85 168.2,153.47 v2(168.4,153.47)
  BOTTOM w0.254: PR22.1 PC12.1 PR23.1 v2(172.07,140.24)
N26600179: length 2.7
  TOP w0.203: PR117.1 41.57,48.52 v1(41.05,47.99) 40.82,47.77 40.67,47.77 40.43,47.53 40.36,47.53 40.29,47.46 PU100.19
N26695162: length 5.4
  BOTTOM w0.102: RX10.2 102.51,153.12 103.33,153.94 103.33,154.86 102.81,155.38 UX4.3 102.81,157.51 v1(103.02,157.72)
N26916933: length 2.3
  TOP w0.102: v1(58.39,22.16) 58.72,22.49 v2(59.12,22.49) 59.28,22.33 U11.7
  BOTTOM w0.102: v2(59.12,22.49) C976.2
N26916935: length 3.8
  TOP w0.102: v2(59.05,21.17) 59.18,21.29 59.24,21.29 59.47,21.53 U11.9
  BOTTOM w0.102: C967.2 59.54,21.62 59.54,21.62 59.29,21.37 59.24,21.37 59.05,21.18 v2(59.05,21.17) 59.05,20.07 v1(59.62,19.5)
N26924121: length 4.3
  BOTTOM w0.102: C1123.2 151.2,78.15 151.07,78.28 151.07,78.71 151.28,78.91 152.25,78.91 152.49,78.68 U12.7
N26924123: length 5.1
  BOTTOM w0.102: C1127.2 150.31,78.28 151.19,79.15 152.16,79.15 152.69,79.67 153.79,79.67 153.99,79.48 U12.9
N26952483: length 3.5
  BOTTOM w0.102: v1(145.41,42.93) 145.38,42.96 R1048.1 144.14,43.02 U58.14
N26952856: length 3.9
  BOTTOM w0.254: R1050.2 147.82,52.92 C1119.1 147.76,52.32 147.95,52.13 v1(147.95,51.94) U58.21
N27019358: length 1.3
  TOP w0.102: T103.1 127.07,98.13 v2(126.91,98.29)
  BOTTOM w0.102: USOC1.AY26 126.87,98.25 v2(126.91,98.29)
N27069111: length 4.7
  BOTTOM w0.102: v1(147.85,24.67) 148.34,24.18 RA34.1
  BOTTOM w0.254: RA34.1 RA155.1 148.34,22.23 149.45,21.12 UA1.13
N27069175: length 3.4
  TOP w0.102: v2(154.68,14.38) v1(154.68,13.65)
  TOP w0.254: CA24.1 154.68,14.68 v2(154.68,14.38)
  BOTTOM w0.203: v2(154.68,14.38) 154.68,14.64 154.29,15.04 154,15.04 153.85,14.89 UA1.37
N27069177: length 3
  TOP w0.102: v1(155.07,16.31) CA24.2
  TOP w0.254: CA24.2 155.7,15.2 v2(155.71,15.18)
  BOTTOM w0.203: v2(155.71,15.18) 155.71,15.22 155.12,15.81 UA1.35
N27069191: length 3.3
  BOTTOM w0.203: 155.76,18.74 155.29,18.74 155.16,18.61 UA1.28
  BOTTOM w0.254: 155.76,18.74 v1(155.99,18.97) 156.97,19.95 CA23.2
N27069244: length 7.4
  BOTTOM w0.102: CA65.2 145.98,21.37 CA69.1 145.93,21.85 145.74,22.04 143.76,22.04 RA81.2 ; v1(142,22.66) 142.42,22.25 142.84,22.25 143.39,21.7 RA81.2 ; RA81.2 RA79.1
N27069257: length 1.6
  BOTTOM w0.102: UA1.12 148.25,19.81 147.61,20.45 CA65.1
N27069271: length 3.1
  BOTTOM w0.203: UA1.34 155.22,16.21 155.66,15.77 155.85,15.77
  BOTTOM w0.254: 155.85,15.77 v1(156.24,15.37) 156.8,14.82 CA25.2
N27069366: length 127.7
  TOP w0.102: v2(147.39,18.06) 147.41,18.04 148.16,18.04 148.55,18.42 148.55,19.95 144.94,23.55 144.94,29.28 148.57,32.91 149.86,32.91 v1(152.09,35.14) 156.08,39.14 156.08,42.34 v2(157.16,43.42)
  IN2 w0.127: v2(157.16,43.42) 155.34,45.23 152.38,45.23 148.43,49.18 148.43,60.82 149.24,61.63 149.24,66.96 152.67,70.39 152.67,74.39 151.09,75.98 151.09,78.7 151.56,79.17 151.56,88.58 152.96,89.99 152.96,99.65 151.95,100.67 150.68,100.67 v2(148.77,102.57)
  BOTTOM w0.102: v2(148.77,102.57) 148.77,107.53 145.98,110.32 138.25,110.32 137.13,109.2 135.24,109.2 RA130.2 ; UA1.8 147.58,18.21 147.43,18.06 v2(147.39,18.06)
N27069480: length 5
  BOTTOM w0.102: 154.17,12.3 155.43,13.56 v1(155.95,13.56)
  BOTTOM w0.203: UA1.39 153.05,14.02 153.24,13.83
  BOTTOM w0.254: CA63.2 154.17,12.34 153.24,13.27 153.24,13.83
N27069495: length 7.1
  BOTTOM w0.102: UA1.7 147.72,17.81 147.49,17.58 146.65,17.58 146.17,18.07 146.17,18.31 ; v1(142.64,17.11) 143.1,17.11 143.69,17.71 145.57,17.71 146.17,18.31 ; 146.17,18.31 CA64.2
N27069508: length 8.2
  BOTTOM w0.102: v1(159.62,20.73) RA154.2
  BOTTOM w0.203: UA1.27 155.08,19.01 155.14,19.07 155.49,19.07 155.64,19.22
  BOTTOM w0.254: RA154.2 158.9,22.4 157.74,22.4 157.02,21.67 CA62.2 156.38,21.09 156.38,19.96 155.64,19.22
N27069623: length 3.4
  BOTTOM w0.102: CA21.1 145.04,19.64 R2355.2 144.41,19.03 143.94,19.03 v1(143.38,18.47)
N27070739: length 6.6
  TOP w0.254: v2(153.85,23.05) v1(153.85,22.08) 153.85,21.33 155.92,19.26 RA82.1
  BOTTOM w0.254: CA68.2 v2(153.85,23.05)
N27070741: length 10
  TOP w0.254: RA80.1 156.85,18.73 156.85,18.73 156.76,18.82 155.79,18.82 153.32,21.29 153.32,23.3 153.6,23.58 v1(154.39,23.58) 154.59,23.58 v2(155.12,23.05)
  BOTTOM w0.254: CA67.2 v2(155.12,23.05)
N27098098: length 7.9
  BOTTOM w0.102: v1(152.57,27.33) 152.57,26.83 153.85,25.55 R2356.1
  BOTTOM w0.203: UA1.20 152.25,21.73 152.29,21.76
  BOTTOM w0.254: R2356.1 153.09,24.77 153.09,22.56 152.29,21.76
N27098403: length 6.7
  BOTTOM w0.102: v1(163.51,26.17) RA17.2
  BOTTOM w0.254: QA1.6 163.13,23.69 163.33,23.89 163.33,24.17 163.16,24.34 QA1.5 161.85,24.34 161.6,24.6 RA16.2 RA17.2
N27098689: length 4.7
  BOTTOM w0.254: RA18.1 161.09,25.79 161.09,24.6 160.84,24.34 QA1.2 160,24.34 v1(159.62,23.96) RA20.1
N27376108:
  vias: v1(100.91,159.9)
N27796256: length 8.5
  TOP w0.102: v1(154.16,87.59) 154.17,87.6 155.9,87.6 156.36,87.14 156.36,84.69 156.07,84.4 JODD1.17 153.73,84.4 RS10.2 CS17.1
N28004468: length 2.8
  TOP w0.102: v1(53.6,75.88) 53.97,76.25 R36.1 55.17,75.92 QE9.2
N28121198:
  vias: v1(117.82,143.14)
N28124976: length 5.4
  BOTTOM w0.102: PR23.2 172.31,142.21 172.31,143.87 171.37,144.81 PQ10.6 171.37,146.76 v1(171.48,146.87)
N28125082: length 3.4
  BOTTOM w0.102: PQ10.3 169.3,143.72 v1(168.85,143.28)
  BOTTOM w0.254: PR22.2 169.81,142.41 169.81,142.79 170.07,143.06 PQ10.3
N28199307: length 3.2
  TOP w0.102: v1(85.6,68.04) 85.6,69.14 85.45,69.28 U68.5 84.59,69.28 84.05,69.82 R34.1
N28199357: length 3.6
  TOP w0.102: R32.1 92.18,80.2 92.43,79.95 U69.5 93.61,79.95 93.77,79.79 v1(93.77,78.84)
N28392619: length 3.5
  BOTTOM w0.203: PR524.2 126.82,151.64 v1(126.36,151.18) 126.27,151.09 124.95,151.09 124.7,150.83 PU500.8
N28393122: length 6
  TOP w0.102: v2(122.52,144.25) 122.52,144.01 v1(122.07,143.56)
  TOP w0.254: v2(122.52,144.25) 122.48,144.29 122.48,144.99 122.84,145.35 PC517.2
  BOTTOM w0.254: PR518.1 122.2,143.96 122.22,143.96 v2(122.52,144.25) 122.52,145.04 122.7,145.22 PU500.22
N28398304: length 14.6
  BOTTOM w0.102: UE1.117 151.67,140.37 151.95,140.65 151.95,142.03 151.24,142.74 151.24,144.98 151.1,145.12 150.07,145.12 149.6,145.59 149.6,147.1 149.84,147.34 149.84,147.68 v1(150.17,148.01) 150.67,148.51 150.67,149.64 150.41,149.89 RX5.1 RD15.1
N28546463: length 3.1
  TOP w0.102: v1(116.78,162.82) 116.11,162.15 D2401.2 115.26,162.11 R5205.2
N29841026: length 4.9
  TOP w0.102: PR730.2 135.25,160.38 v1(135.9,159.74)
  TOP w0.254: PQ713.3 133.55,163.26 134.17,162.64 134.3,162.64 135.25,161.69 PR730.2
N39970373: length 16.5
  TOP w0.102: v1(138.59,169.79) 138.58,169.81 PR718.2
  TOP w0.254: PR718.2 136.56,169.81 PQ712.2 v2(135.04,169.36) ; PQ710.6 129.59,163.26 130.51,162.34 133.32,162.34 v2(133.52,162.14)
  IN2 w0.254: v2(135.04,169.36) 135.04,168.25 134.17,167.37 134.17,162.78 v2(133.52,162.14)
N40812716: length 4.7
  BOTTOM w0.102: v1(14.67,24.73) 14.36,24.73 13.85,24.23 CR3.2
  BOTTOM w0.254: UR1.6 15.63,22.4 15.41,22.61 15.41,23.49
  BOTTOM w0.305: 15.41,23.49 15.2,23.71 CR3.2
N47007898: length 4.2
  TOP w0.102: PC11.2 v1(120.63,169.15)
  TOP w0.254: PR26.1 PC11.2 PQ4.5
N47008110: length 6.3
  TOP w0.102: PR17.2 115.5,166.53 115.03,166.06 115.03,165.18 115.14,165.07 v1(116.78,165.07)
  TOP w0.254: PR17.2 PC9.1 115.55,167.72 PQ4.2
N47008134: length 5.6
  TOP w0.102: v1(112.72,170.28) 111.92,169.48 PQ1.1
  TOP w0.254: PR2.2 PL3.1 111.01,168.75 111.34,168.42 PQ1.1
N48037563: length 4
  TOP w0.102: v1(130.24,36) 129.84,35.59 v2(129.77,35.59) 129.6,35.77 RD6.2
  BOTTOM w0.102: v2(129.77,35.59) 130.2,36.02 JDIMM2.197
N48037565: length 4.8
  TOP w0.102: RD7.2 129.17,36.79 130.84,36.79 v2(131.17,36.46) 131.5,36.46 v1(131.88,36.08)
  BOTTOM w0.102: JDIMM2.201 131.4,36.68 v2(131.17,36.46)
N48039107: length 5.3
  TOP w0.102: v2(109.28,28.28) v1(109.82,27.73)
  TOP w0.254: RD4.1 CD21.1 CD22.1 109.4,28.41 v2(109.28,28.28)
  BOTTOM w0.254: v2(109.28,28.28) 108.9,28.66 JDIMM2.126
N52907207: length 4.8
  TOP w0.102: v1(161.25,163.98) 160.51,164.71 v2(160.51,164.73)
  TOP w0.508: v2(160.51,164.73) PR708.2 PR706.1
  BOTTOM w0.508: v2(160.51,164.73) 160.33,164.55 PQ706.4
N52907447: length 3.2
  TOP w0.102: v1(156.51,168.37) PQ711.2
  TOP w0.508: PQ711.2 158.63,168.87 PR714.1
N55201771: length 10.2
  TOP w0.102: RX12.2 15.19,72.66 v1(14.05,72.66) 12.41,72.66 10.79,71.05 10.79,67.44 JHDMI1.13
N59110906: length 1
  BOTTOM w0.102: T203.1 146.23,140.75 RE43.2
N61580896: length 4.3
  TOP w0.102: Q2307.1 130.36,40.04 v1(131.29,40.97)
  TOP w0.254: R2314.2 130.36,38.25 Q2307.1
N61580898: length 3.8
  BOTTOM w0.102: v1(160.86,78.06) 161.41,78.61 R2315.2
  BOTTOM w0.254: R2315.2 161.41,81.15 Q2308.1
N100764683: length 2
  TOP w0.102: v1(115.12,147.96) PR502.1
  TOP w0.254: PR502.1 116.16,147.1 PC506.1
N100764685: length 7.6
  TOP w0.254: v2(120.37,149.56) 120.37,147.63 v1(119.35,146.61) 118.85,146.11 PR507.2 PC506.2
  BOTTOM w0.203: PU500.31 120.48,149.46 v2(120.37,149.56)
N100764689: length 2.1
  TOP w0.102: PC532.1 v1(130.84,144.97)
  TOP w0.254: PC532.1 130.79,146.06 PR539.2
N100764691: length 5.5
  TOP w0.254: v2(126.32,149.2) v1(126.71,148.81) 128.57,146.95 PR540.1 PR539.1
  BOTTOM w0.254: v2(126.32,149.2) 126.18,149.06 PU500.11
N100764720: length 9.8
  TOP w0.102: v2(123.02,144.74) 123.02,143.78 v1(123.48,143.33)
  TOP w0.254: v2(123.02,144.74) 123.02,144.9 PC518.1
  BOTTOM w0.254: PU500.21 123.1,146.42 123.1,144.82 v2(123.02,144.74) 123.02,144.05 122.59,143.62 122.59,143.06 PR522.2 123.71,142.43 PR519.2
N100764741: length 4.2
  BOTTOM w0.203: PC504.1 118.9,149.33 118.92,149.31 PR503.1 PR508.1 119.57,147.96 119.87,148.26 v1(120.11,148.26) PU500.28
N100764791: length 9.1
  BOTTOM w0.102: PR505.1 117.07,150.56 v1(116,151.63)
  BOTTOM w0.203: PU500.29 119.96,148.66 119.48,149.14 119.48,150.05 PC504.2
  BOTTOM w0.254: PC505.1 118.9,152.63 PR504.1 118.9,151.5 PC504.2 PC507.2 117.18,150.64 PR505.1
N100764795: length 4.2
  BOTTOM w0.203: PU500.14 126.52,147.86 v1(126.56,147.9) 126.62,147.96 PR534.2 PC531.2 127.7,149.71 PC528.2
N100764809: length 9.7
  BOTTOM w0.102: PR533.2 130.47,150.64 v1(130.69,150.86)
  BOTTOM w0.203: PU500.13 125.94,148.26 125.98,148.29 126.7,148.29 127.17,148.76 127.17,149.47 127.17,150.11 PC528.1
  BOTTOM w0.254: PR538.2 PR542.2 129.27,151.57 129.49,151.35 PR533.2 PR543.1 PC528.1
N100764813: length 0.9
  BOTTOM w0.203: PC507.1 118.02,149.24 118.02,148.86 PR503.2
N100764860: length 6
  BOTTOM w0.102: PR510.2 117.96,146.96 117.52,147.4 116.15,147.4 v1(115.89,147.66)
  BOTTOM w0.254: PR510.2 119.28,146.95 120.2,147.86 PU500.27
N100764905: length 0.9
  BOTTOM w0.203: PC531.1 128.61,149.71 PR543.2
N100764954: length 1
  BOTTOM w0.254: PC527.2 127.84,152.92 127.79,152.87 PR538.1
N100764996: length 26.9
  TOP w0.254: PR500.1 116.31,150.81 v2(115.98,150.48)
  IN2 w0.254: v2(116.82,129.18) 115.12,130.88 115.12,136.36 113.85,137.63 113.85,149.86 114.7,150.71 115.75,150.71 v2(115.98,150.48)
  BOTTOM w0.102: v2(115.98,150.48) v1(115.32,150.48)
  BOTTOM w0.254: PH500.2 116.83,129.17 v2(116.82,129.18)
N100765028: length 2.2
  BOTTOM w0.102: v1(130.79,148.86) PC525.2
  BOTTOM w0.203: PC525.2 PR533.1
N100765040: length 2
  BOTTOM w0.102: v1(118.91,154.66) PC505.2
  BOTTOM w0.254: PC505.2 PR501.1
N100765116: length 29.2
  TOP w0.102: v2(130.99,150.2) v1(131.91,150.2)
  TOP w0.254: PR535.2 130.18,151.01 v2(130.99,150.2)
  IN2 w0.254: v2(130.99,150.2) 132.31,150.2 136.96,145.54 136.96,134.87 134.68,132.59 134.68,130.72 135.91,129.48 v2(136.12,129.48)
  BOTTOM w0.254: v2(136.12,129.48) 135.96,129.32 PH503.1
N100765769: length 0.9
  BOTTOM w0.254: PC511.1 PR505.2
N100765781: length 3.2
  BOTTOM w0.254: PR522.1 123.22,143.7 123.55,144.03 v1(123.55,144.74) 123.55,145.47 123.5,145.53 PU500.20
N100768097: length 1.2
  TOP w0.102: 126.64,133.82 126.08,133.26 v1(126.08,132.86)
N100768278: length 1.5
  TOP w0.102: PC516.1 v1(124.01,132.74)
N100768460: length 1.4
  BOTTOM w0.102: PC524.1 v1(127.22,143.4)
N100768540: length 29.2
  TOP w0.254: PR513.1 114.52,150.41 v1(114.69,150.25) v2(115.25,149.69)
  IN2 w0.254: v2(115.25,149.69) 115.12,149.69 114.86,149.44 114.86,146.91 114.86,146.91 114.86,138.05 116.13,136.78 116.13,131.99 117.28,130.85 v2(117.28,130.77)
  BOTTOM w0.254: PL500.2 122.23,130.89 121.98,130.64 118.27,130.64 117.88,130.64 117.8,130.72 117.75,130.77 v2(117.28,130.77)
N102723193: length 1.1
  TOP w0.102: T102.1 126.33,103.24 v2(126.05,102.95)
  BOTTOM w0.102: v2(126.05,102.95) 126.27,102.73 USOC1.BG18
N102723222: length 2.7
  BOTTOM w0.102: USOC1.BH18 127.01,103.38 128.31,104.68 T101.1
N102723231: length 3.3
  BOTTOM w0.102: USOC1.BG21 127.93,101.94 128.14,102.15 128.34,102.15 128.4,102.15 128.8,102.55 128.95,102.55 129.05,102.65 129.28,102.65 129.61,102.98 130.45,102.98 T100.1

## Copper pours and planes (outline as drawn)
+0.675VS on TOP: 132.01,31.71 132.26,31.96 132.26,36.03 132.3,36.06 132.3,40.49 132.64,40.84 133.86,40.84 133.9,40.8 133.9,37.81 133.92,37.81 133.92,37.61 133.9,37.61 133.9,36.79 133.92,36.79 133.92,34.69 133.88,34.68 133.25,33.9 133.88,33.12 133.92,33.11 133.92,30.64 133.93,30.62 133.93,27.94 133.78,27.78 132.57,27.78 132.01,28.34
+0.675VS on TOP: 63.94,54.69 62.79,54.69 62.67,54.57 62.67,53.87 62.1,53.87 62.1,53.74 62.67,53.74 62.67,52.73 62.92,52.47 63.68,52.47 64.06,52.85 64.06,54.57
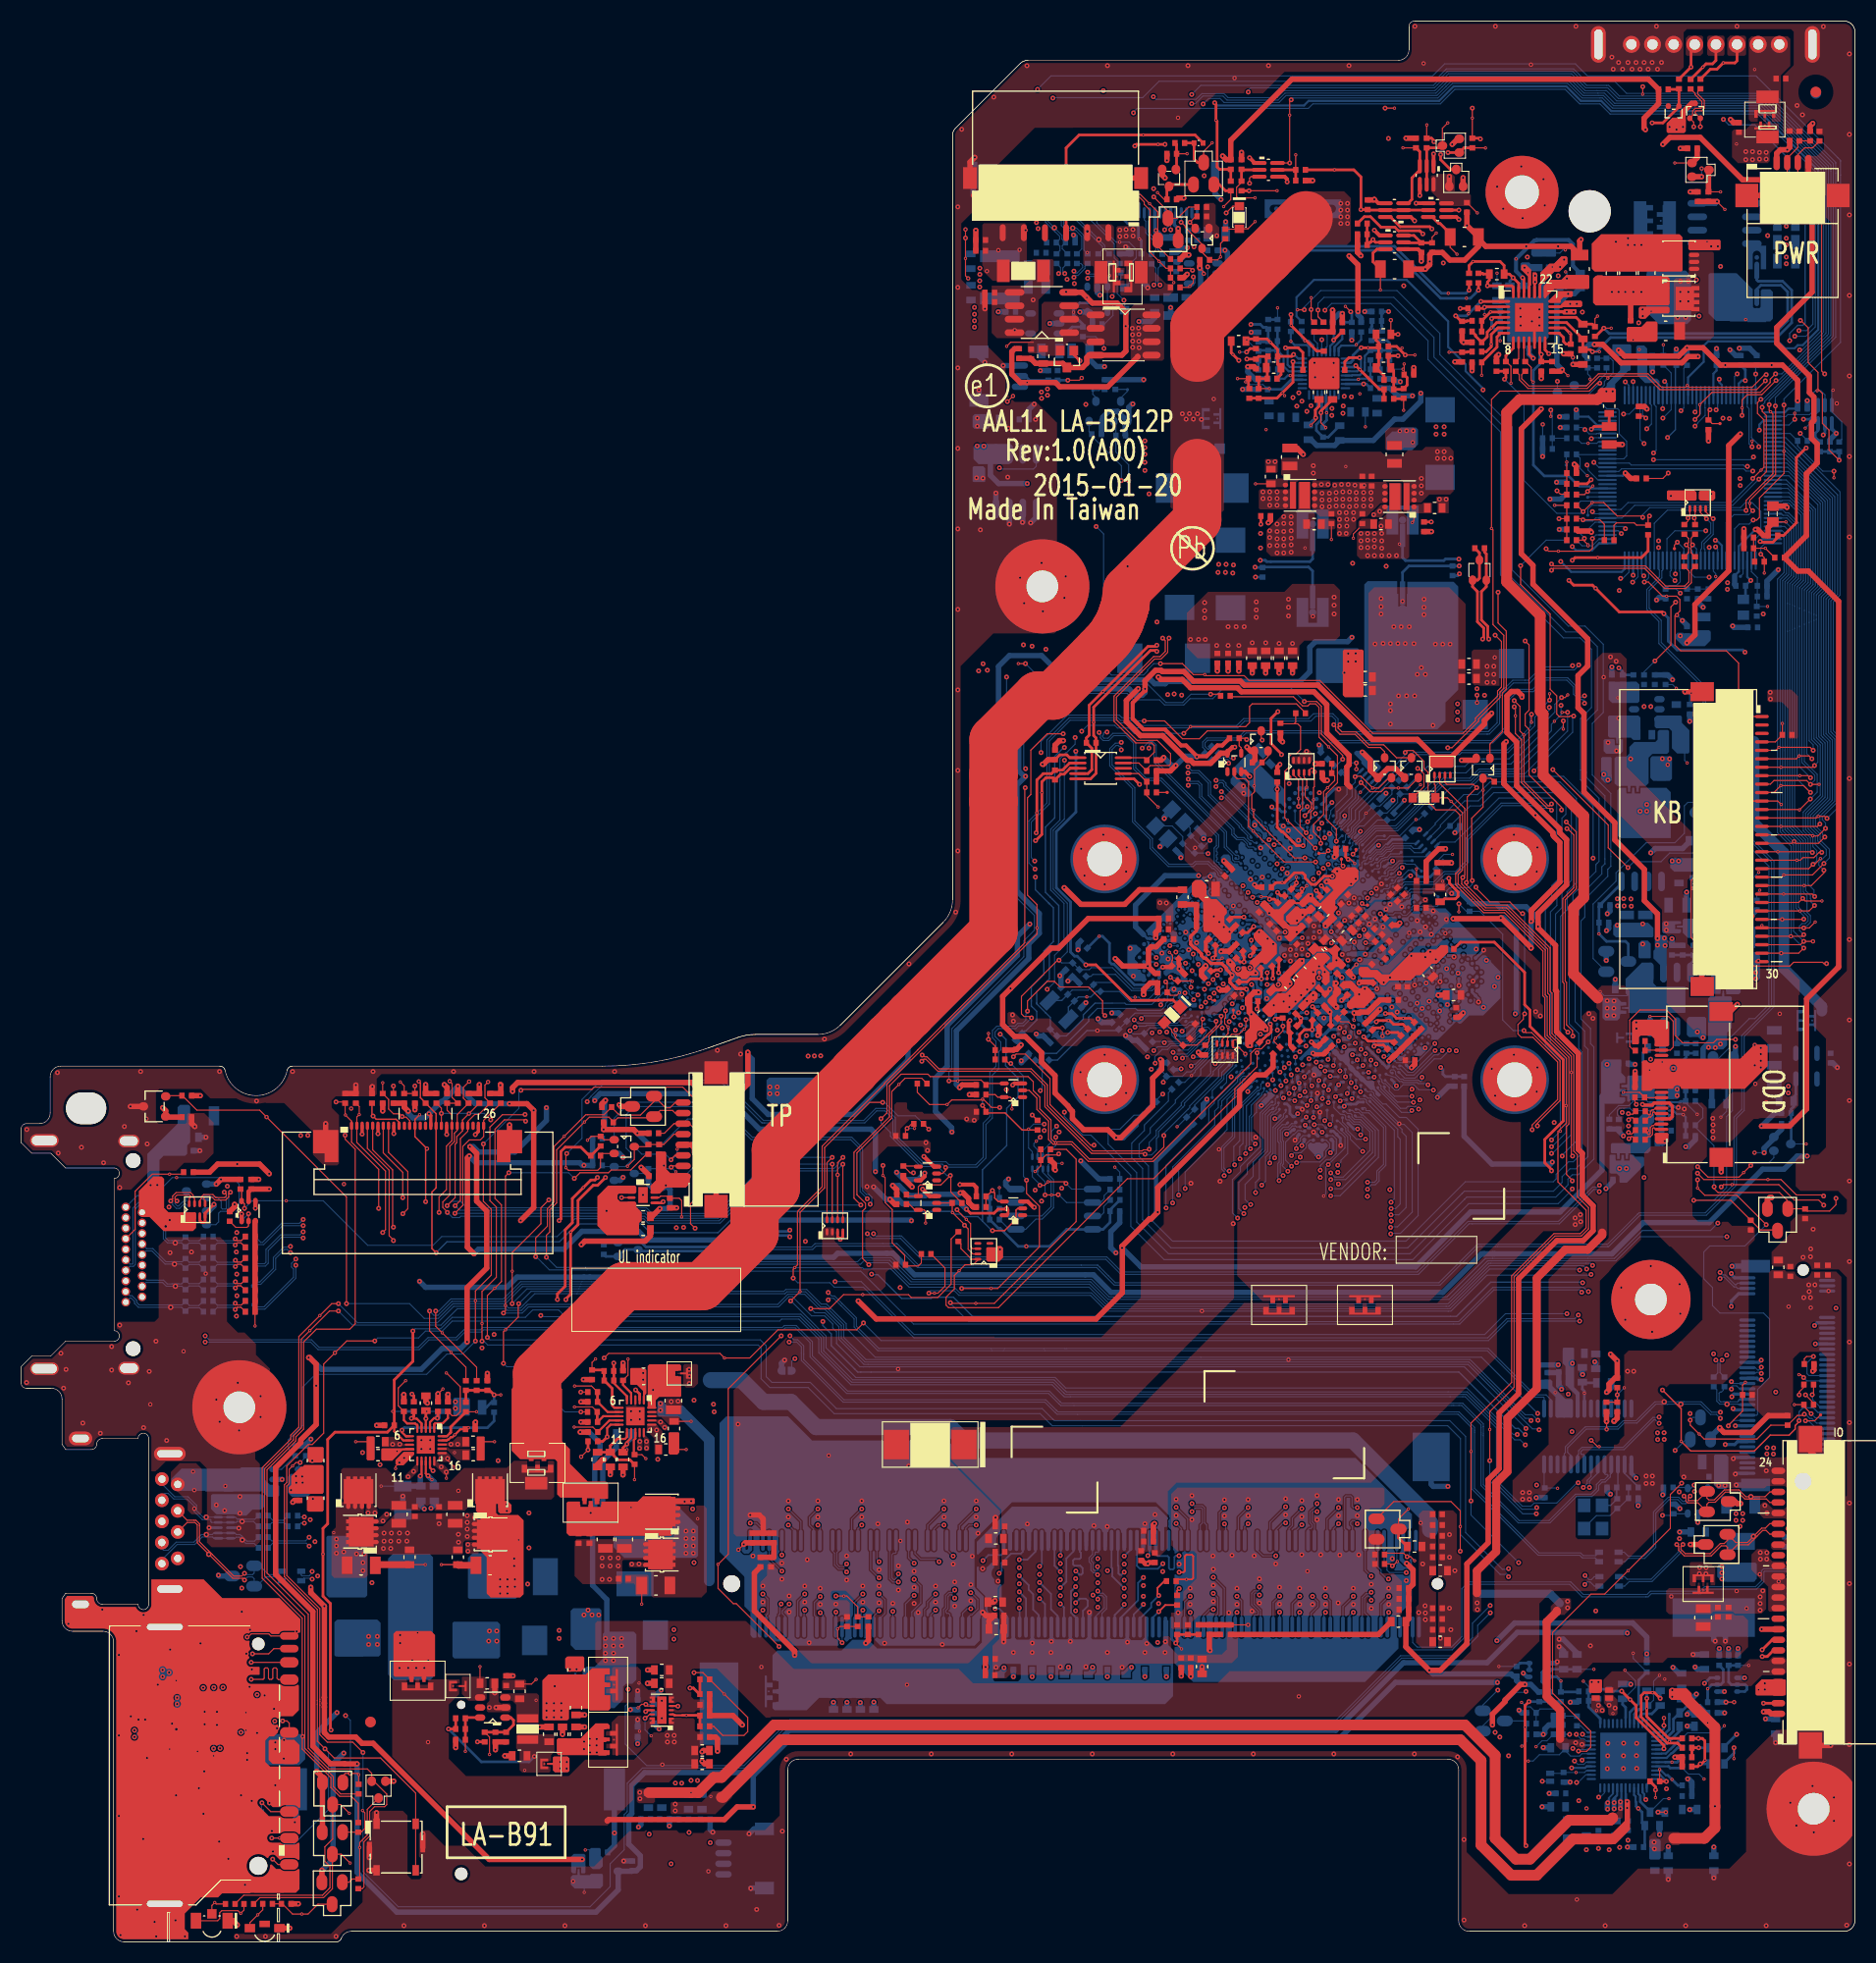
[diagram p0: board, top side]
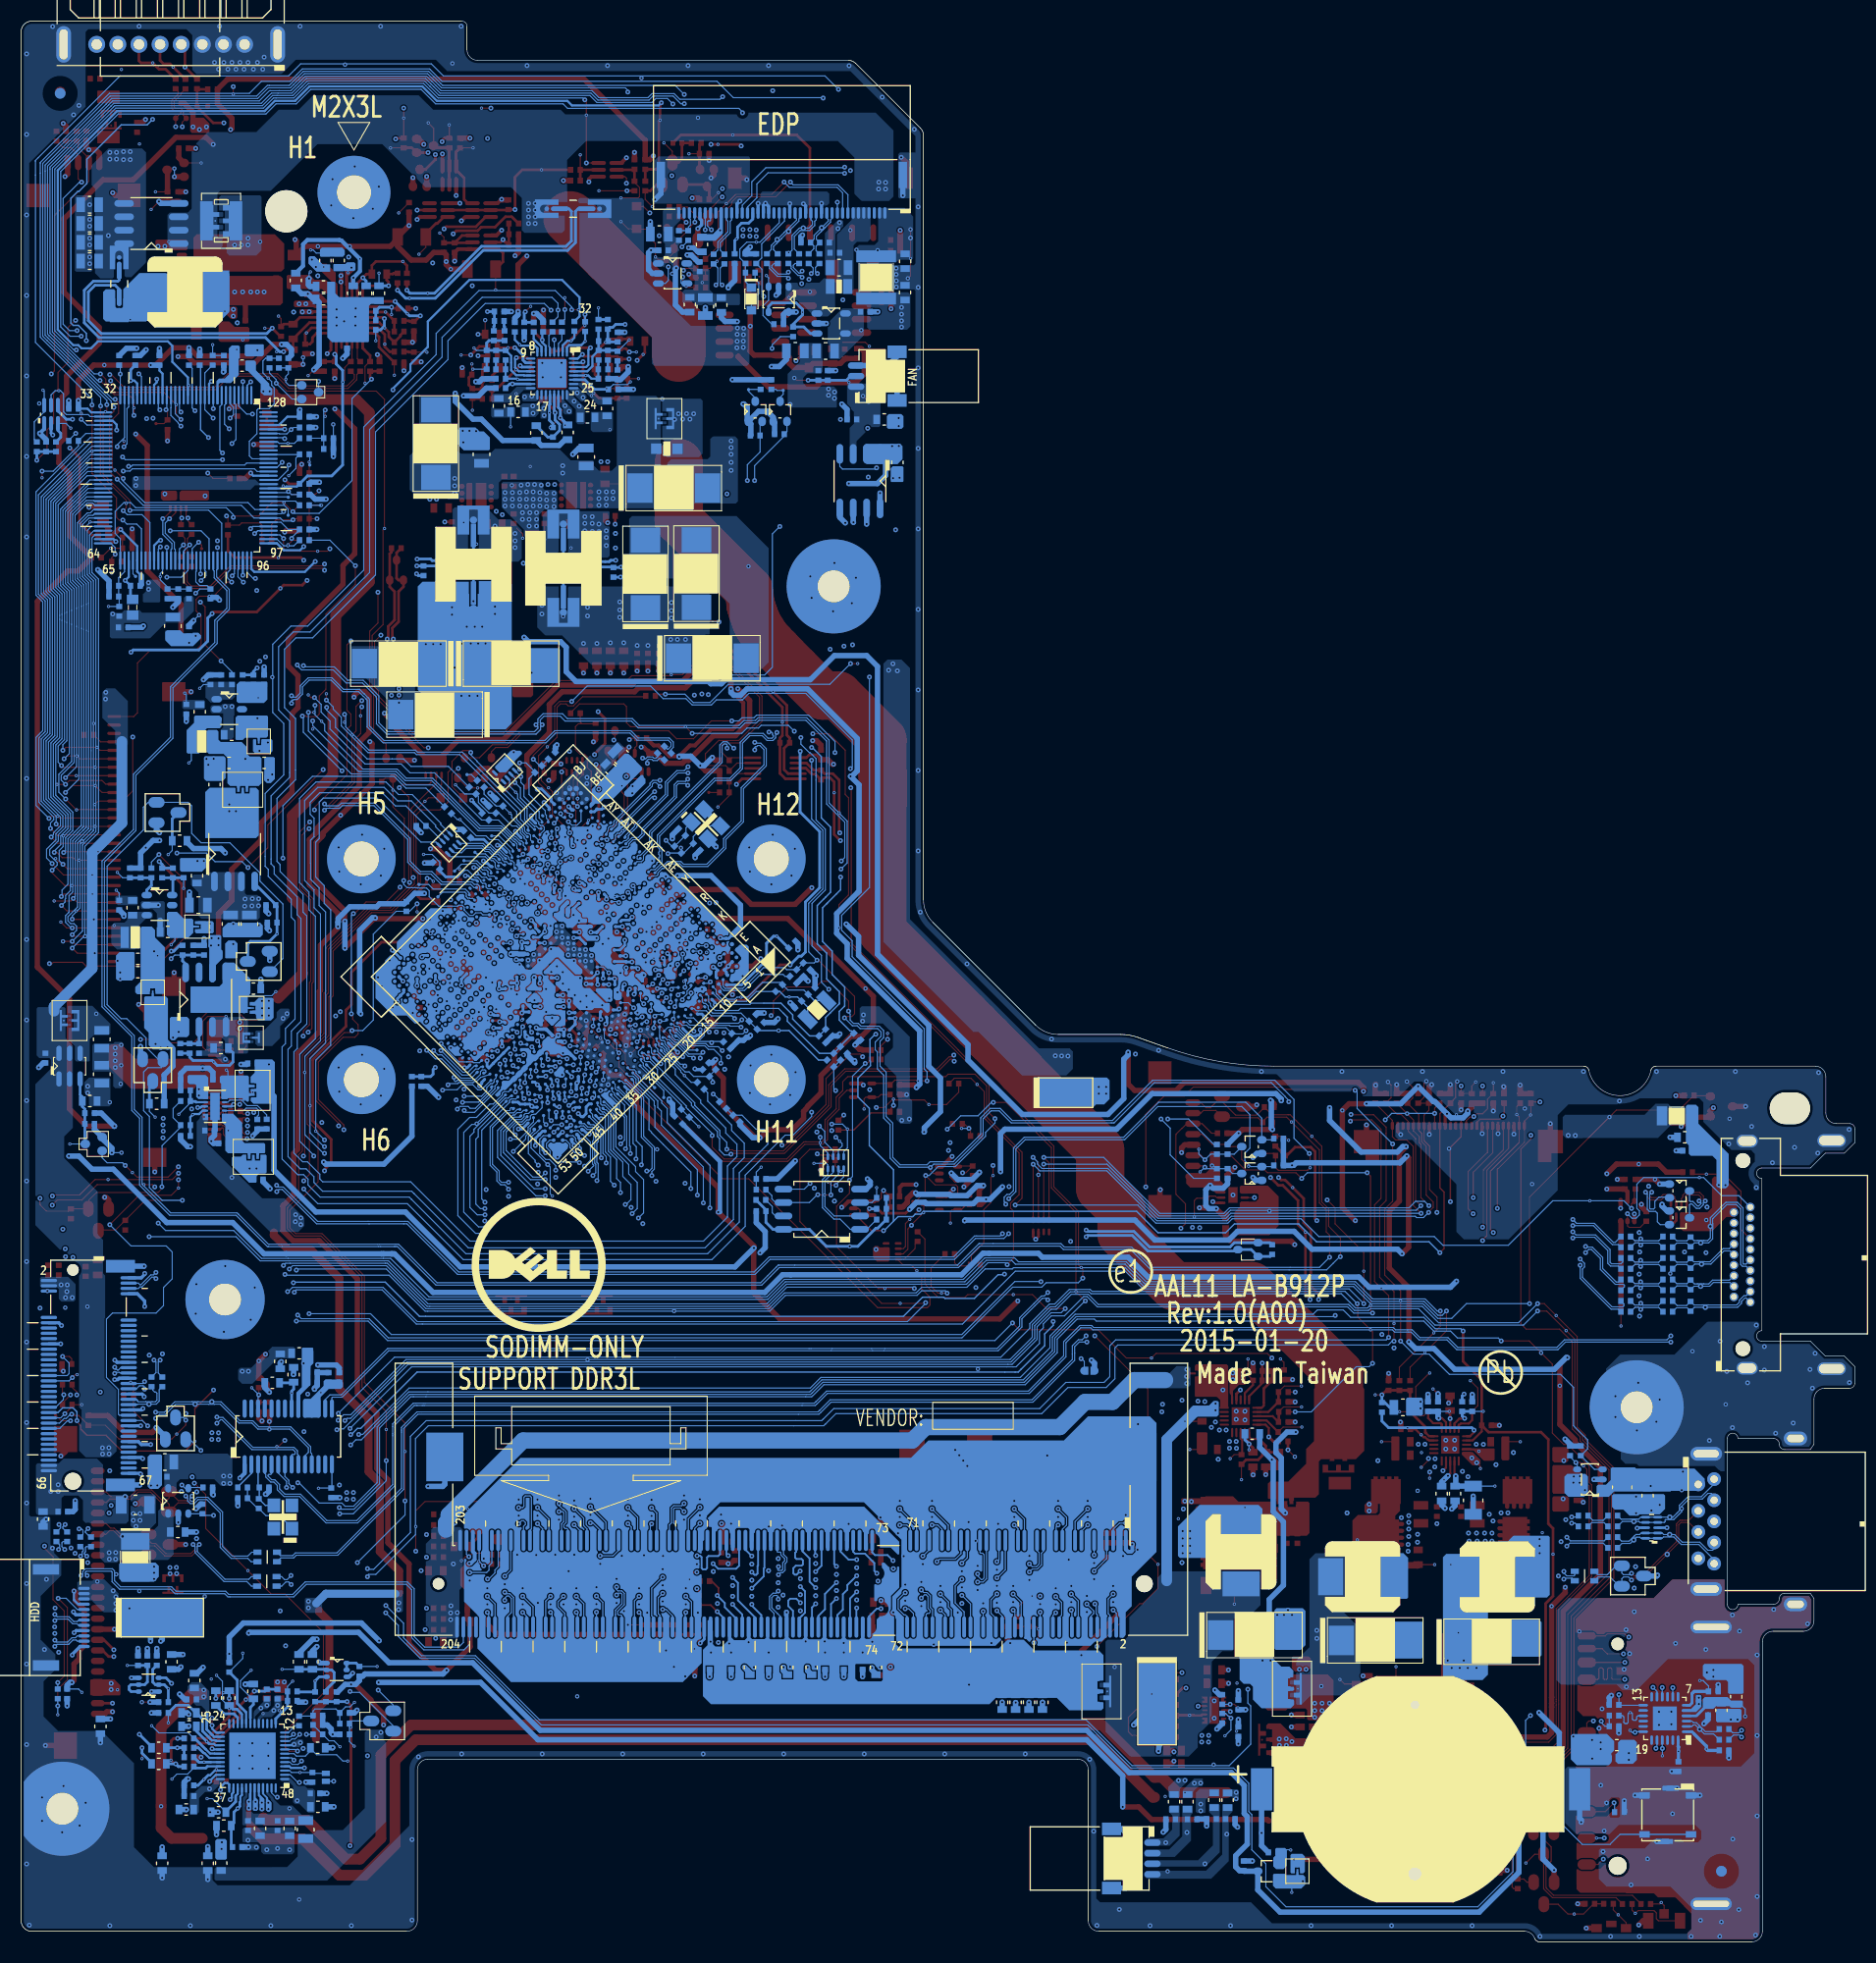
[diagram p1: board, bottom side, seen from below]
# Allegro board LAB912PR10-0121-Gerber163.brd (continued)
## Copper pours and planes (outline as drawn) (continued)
+0.675VS on BOTTOM: 132.07,28.98 132.33,28.72 134.61,28.72 135.25,29.36 135.25,37.68 134.74,38.18 134.74,39.01 134.49,39.26 132.01,39.26 131.76,39.01 131.76,33.61 132.07,33.29
+0.675VS on BOTTOM: 62.86,54.31 62.86,52.73 63.18,52.41 65.14,52.41 65.27,52.54 65.27,53.42 64.19,54.5 63.05,54.5
+0.675VSP on TOP (solid shape): 62.46,54.54 62.46,54.06 61.91,54.06 61.91,53.53 62.46,53.53 62.46,51.66 62.39,51.58 60.38,51.58 60.06,51.27 60.06,50.57 60,50.5 59.37,50.5 59.3,50.57 59.3,54.5 59.47,54.67 62.34,54.67
+1.0VALW on BOTTOM (solid shape): 152.7,109.22 152.7,108.72 152.72,108.69 153.23,108.69 153.26,108.72 153.26,109.19 153.31,109.24 155.71,109.24 156.13,108.82 156.13,104.48 151.31,104.48 151.06,104.73 151.06,108.99 151.31,109.24 151.89,109.24 151.91,109.22 151.91,108.73 151.95,108.69 152.43,108.69 152.46,108.72 152.46,109.22 152.49,109.25 152.66,109.25
+1.0VALW on IN1: 112.72,96.77 112.84,96.73 112.96,96.74 113.06,96.71 113.08,96.61 113.14,96.33 113.4,96.2 113.48,96.16 113.5,96.09 113.61,95.8 113.91,95.73 114,95.71 114.04,95.62 114.23,95.3 114.6,95.37 114.62,95.39 114.66,95.39 116.25,93.8 116.27,93.71 116.21,93.64 116.08,93.09 116.63,93.21 116.7,93.28 116.8,93.25 117.85,92.2 117.87,92.11 117.81,92.04 117.66,91.54 118.17,91.5 118.19,91.52 118.26,91.52 118.26,91.44 118.25,91.43 118.17,91.29 118.16,91.13 118.16,91.11 118,90.94 117.97,90.94 117.8,90.92 117.66,90.81 117.36,90.81 117.11,91.06 116.43,91.06 116.36,91.14 115.89,91.14 115,92.03 104.12,92.03 103.03,93.12 103.03,98.81 105.14,100.92 105.14,110.09 106.1,111.06 106.1,118.44 106.58,118.92 109.16,118.92 110.22,117.86 110.22,116.2 112.72,113.7
+1.0VALW on IN1: 137.74,119.1 139.38,119.1 149.29,109.18 153.99,109.18 154.37,108.8 154.37,106.89 153.87,106.38 147.76,106.38 137.47,116.67 137.47,118.83
+1.0VALW on IN2: 119.68,117.29 119.67,117.31 110.67,117.31 110.29,117.69 108.51,117.69 107.88,118.32 107.88,119.72 108.13,119.97 134.75,119.97 134.78,120 134.8,119.97 137.6,119.97 138.87,118.7 138.87,117.81 138.61,117.56 120.71,117.56 120.44,117.29
+1.0VALWP on BOTTOM (solid shape): 155.96,114.6 155.96,112.63 155.77,112.44 154.39,112.44 154.03,112.08 154.03,109.67 153.76,109.41 153.16,109.41 153.1,109.35 153.1,108.86 153.09,108.85 152.88,108.85 152.86,108.86 152.86,109.37 152.83,109.41 152.33,109.41 152.3,109.38 152.3,108.87 152.28,108.85 152.09,108.85 152.06,108.87 152.06,109.38 152.04,109.41 151.06,109.41 150.81,109.66 150.81,112.03 150.96,112.19 151.92,112.19 152.2,112.48 152.2,113.09 152.68,113.57 154.67,113.57 154.88,113.79 154.88,114.56 155.03,114.71 155.85,114.71
+1.0VALWP_ON on BOTTOM: 153.5,119.27 155.94,119.27 156.1,119.11 156.1,117.79 155.62,117.31 154.73,117.31 154.46,117.57 153.6,117.57 153.31,117.86 153.31,119.08
+1.0VS on TOP (solid shape): 122.5,97.81 122.5,97.71 122.11,97.31 121.77,97.31 120.82,96.37 120.81,96.37 120.72,96.27 120.13,96.27 119.72,96.68 119.72,97.09 120.63,98 120.84,98 121.04,97.8 121.63,97.8 122.01,98.18 122.13,98.18
+1.0VS on BOTTOM (solid shape): 124.01,87.53 124.01,87.38 123.35,86.72 123.23,86.72 122.59,87.36 122.59,87.51 122.74,87.66 123.89,87.66
+1.0VS on BOTTOM (solid shape): 125.63,89.23 125.64,89.21 125.64,89.01 125.55,88.95 125.45,88.96 125.42,88.97 125.34,88.97 125.22,88.86 124.72,88.86 124.67,88.91 124.35,88.91 124.32,88.94 124.3,88.99 124.26,89.12 124.34,89.24 124.42,89.28 124.42,89.44 124.81,89.83 125.04,89.83
+1.0VS on BOTTOM (solid shape): 122.54,97.96 122.54,97.67 122.6,97.62 122.6,97.61 122.67,97.52 122.76,97.45 122.79,97.42 122.88,97.41 122.93,97.41 123.06,97.41 123.16,97.32 123.16,97.07 122.65,96.56 122.36,96.56 122.35,96.57 122.26,96.57 122.25,96.58 122.17,96.5 122.16,96.5 121.98,96.32 121.98,96.17 121.8,95.99 121.32,95.99 120.87,96.44 120.11,96.44 119.99,96.56 119.99,96.81 120.04,96.86 120.41,96.86 120.59,97.04 120.59,97.27 121.17,97.85 121.33,97.85 121.47,97.72 121.47,97.05 121.66,96.86 121.92,96.86 122.14,97.08 122.14,97.82 121.66,98.3 121.66,98.48 121.75,98.57 121.93,98.57
+1.0VS on TOP: 125.3,96.43 124.39,97.34 124.39,97.44 124.75,97.8 124.75,98 124.55,98.2 124.55,98.53 125.67,99.65 125.79,99.65 126.58,100.44 126.58,103.68 124.32,105.95 124.32,109.23 124.47,109.39 125.97,109.39 126.48,108.87 126.48,108.62 126.57,108.53 126.62,108.51 126.69,108.48 130.8,104.37 130.8,99.78 129.65,98.63 128.07,98.63 125.87,96.43
+1.0VS on TOP: 126.82,94.92 126.96,95.34 126.97,95.44 127.06,95.48 127.25,95.52 127.38,95.66 127.39,95.69 127.6,95.69 128.54,94.75 128.54,94.65 128.23,94.34 128.14,94.34 128.11,94.32 127.83,94.32 127.81,94.29 127.79,94.29 127.31,93.81 126.7,93.81 126.18,94.33 125.97,94.54 125.97,94.77 126.23,95.03 126.31,95.06 126.38,95.02
+1.0VS on BOTTOM: 152.52,101.25 155.39,101.25 155.41,101.23 155.9,101.23 156.11,101.02 157.21,101.02 157.47,100.76 157.47,100.03 156.77,99.33 156.77,97.11 156.5,96.84 154.42,96.84 154.29,96.71 151.19,96.71 150.96,96.93 150.96,98.86 151.19,99.09 152.2,99.09 152.37,99.26 152.37,101.1
+1.0VS on IN2: outline of 137 points within 114.89,86.34 152.71,101.94
+1.05VS on BOTTOM (solid shape): 161.17,89.49 161.8,89.49 161.91,89.39 161.91,86.49 161.47,86.06 161.47,84.87 161.07,84.47 159.13,84.47 159.02,84.58 159.02,84.75 159.66,85.39 159.66,89.29 159.86,89.49 161.02,89.49 161.02,90.05 161.17,90.05
+1.05VS on BOTTOM (solid shape): 125.21,91.41 125.21,90.74 125.59,90.36 125.61,90.35 125.64,90.32 125.67,90.29 125.67,90.13 125.57,90.03 124.37,90.03 124.3,90.11 124.3,90.27 124.31,90.29 124.31,90.35 124.35,90.39 124.38,90.39 124.45,90.38 124.52,90.39 124.63,90.39 124.81,90.56 124.81,91.1 124.76,91.15 124.76,91.45 124.79,91.45 124.83,91.49 124.86,91.51 124.9,91.53 125.09,91.53
+1.5VS on TOP: 148.14,75.17 148.14,70.75 149.13,69.76 149.13,67.83 149.14,67.81 149.14,66.9 149.21,66.84 150.04,66.84 150.12,66.91 150.12,72.83 149.13,73.82 149.13,87.89 148.88,88.14 148.23,88.14 147.73,87.64 147.73,75.59
+1.5VS on TOP: 146.56,32.55 145.55,32.55 144.76,31.76 144.76,31.22 145.04,30.95 146.06,30.95 146.69,31.58 146.69,32.42
+1.5VS on TOP: 146.41,19.16 147.86,19.16 148.06,18.96 148.06,18.45 147.81,18.19 145.68,18.19 145.27,18.6 145.27,19.16 145.42,19.31 146.26,19.31
+1.5VS on TOP: 137.39,31.33 137.52,31.2 138.08,31.2 138.18,31.3 138.18,33.04 138.06,33.17 137.46,33.17 137.39,33.1
+1.5VS on TOP: 126.96,93.25 126.55,93.25 126.4,93.1 126.4,92.74 126.68,92.46 127.44,92.46 127.79,92.11 128.45,92.11 128.89,91.68 129.44,91.68 132.04,94.27 133.97,94.27 134.7,95 139.93,95 142.98,91.96 142.98,87.76 143.36,87.39 143.94,87.39 144.05,87.5 144.05,88.6 143.8,88.86 143.8,92.67 140.44,96.02 134.58,96.02 133.51,94.95 131.81,94.95 129.34,92.49 128.94,92.49 128.33,93.1 127.11,93.1
+1.5VS on BOTTOM: 145.09,31.15 146.56,31.15 146.69,31.28 146.69,32.47 146.59,32.57 145.22,32.57 145.07,32.42 145.07,31.17
+1.5VS on BOTTOM: 137.42,33.21 137.42,31.33 137.55,31.2 138.08,31.2 138.31,31.43 138.31,33.15 138.18,33.28 137.5,33.28
+1.5VS on BOTTOM: 148.9,18.7 148.11,18.7 147.76,19.06 147.47,19.06 147.34,19.18 146.97,19.18 146.87,19.08 146.87,18.79 147.24,18.42 147.86,18.42 147.94,18.5 148.88,18.5 148.93,18.55 148.93,18.68
+1.5VS on BOTTOM: 149.79,84.79 151.16,84.79 151.41,85.05 151.41,85.4 151.47,85.46 151.92,85.46 151.98,85.52 151.98,85.65 151.92,85.71 151.47,85.71 151.41,85.78 151.41,86.13 151.28,86.25 150.59,86.25 149.37,87.47 149.37,88 149.04,88.33 148.23,88.33 148.04,88.14 148.04,87.3 148.89,86.45 148.89,85.7
+1.5VS on BOTTOM: 152.89,9.28 151.21,9.28 150.98,9.05 150.98,8.82 151.16,8.64 152.86,8.64 152.94,8.72 152.94,9.23
+1.5VS on IN1: 143.24,88.27 148.72,88.27 149.14,87.85 149.14,87.35 148.93,87.14 148.62,87.14 148.38,87.38 143.67,87.38 143.14,87.92 143.14,88.17
+1.05VS on IN1: 124.87,92.57 120.71,88.41 120.71,87.4 120.96,87.14 121.66,87.14 123.82,89.3 124.64,89.3 125.09,88.86 125.09,88.22 125.53,87.78 140.29,87.78 140.91,88.4 148.67,88.4 149.87,89.61 151.35,89.61 151.86,89.09 151.86,88.66 157.16,83.37 159.75,83.37 159.75,83.38 160.62,83.38 160.93,83.69 160.93,83.7 161.07,83.84 161.07,85.81 159.87,87 158.41,87 152.84,92.57
+1.5VS on IN2: 146.89,18.96 148.49,18.96 149.03,18.42 149.03,13.34 151.42,10.96 151.42,10.04 152.3,9.15 152.3,8.67 152.18,8.54 151.21,8.54 150.35,9.41 150.35,10.6 148.06,12.89 148.04,12.89 147.91,13.01 147.91,17.76 147.4,18.27 146.95,18.27 146.77,18.45 146.77,18.83
+1.05VS_SOC on TOP (solid shape): 122.71,89.76 122.71,89.31 122.31,88.91 122.3,88.91 122.14,88.91 121.33,88.1 121.28,88.1 120.87,88.51 120.87,88.63 122.24,90.01 122.47,90.01
+1.05VSP on BOTTOM (solid shape): 162.24,95.97 162.24,90.89 162.74,90.38 162.74,89.87 162.57,89.7 161.37,89.7 161.37,90.24 161.04,90.24 161.03,90.25 160.84,90.25 160.84,89.75 160.81,89.72 160.1,89.72 159.95,89.87 159.95,94.14 160.86,95.05 160.88,95.05 160.88,95.78 161.19,96.1 162.11,96.1
+1.5VSP on BOTTOM: 155.76,85.83 155.76,87.36 155.57,87.55 152.46,87.55 152.08,87.17 152.08,86.15 152.01,86.09 151.57,86.09 151.5,86.02 151.5,85.9 151.57,85.83 152.01,85.83 152.08,85.77 152.08,85.39 152.01,85.33 151.57,85.33 151.5,85.26 151.5,85.14 151.57,85.07 152.01,85.07 152.08,85.01 152.08,84.18 152.18,84.08 154.16,84.08 154.26,84.18 154.26,85.28 154.63,85.64 155.57,85.64
+1.8VALW on TOP (solid shape): 150.93,146.92 150.93,145.89 150.77,145.73 149.36,145.73 149.22,145.87 149.22,146.85 149.46,147.09 150.77,147.09
+1.8VALW on TOP (solid shape): 51.9,17.37 51.9,16.19 51.76,16.05 51.55,16.05 51.54,16.05 50.51,16.05 50.33,16.23 50.33,16.74 50.31,16.76 49.79,16.76 49.76,16.78 49.76,16.91 49.79,16.94 50.31,16.94 50.32,16.95 50.32,17.46 50.41,17.55 51.72,17.55
+1.8VALW on BOTTOM (solid shape): 157.79,81.95 157.79,81.34 157.64,81.19 157.09,81.19 156.98,81.07 156.98,80.62 156.98,80.61 156.98,79.98 156.77,79.77 155.92,79.77 155.84,79.85 155.84,81.81 156.07,82.04 157.71,82.04
+1.8VALW on BOTTOM (solid shape): 152.34,149.59 152.34,148.79 152.24,148.7 152.1,148.7 150.87,147.47 150.87,146.68 150.57,146.38 149.86,146.38 149.78,146.46 149.78,147 150.07,147.29 150.07,147.49 151.33,148.75 151.33,149.55 151.45,149.67 152.25,149.67
+1.8VALW on BOTTOM (solid shape): 151.47,88.96 151.87,88.96 151.92,88.91 151.92,88.63 151.36,88.63 151.36,88.17 151.39,88.15 151.9,88.15 151.92,88.12 151.92,87.87 151.9,87.84 151.42,87.84 151.32,87.75 151.32,87.68 151.31,87.68 151.31,87.46 151.06,87.21 149.92,87.21 149.66,87.46 149.66,89.24 149.79,89.37 151.06,89.37
+1.8VALW on BOTTOM (solid shape): 117.88,90.26 117.92,90.26 117.96,90.26 119.04,90.26 119.17,90.13 119.17,89.98 118.15,88.96 118.13,88.96 118.01,88.99 117.9,88.97 117.89,88.96 117.74,88.96 117.57,89.13 117.57,89.27 117.58,89.28 117.58,89.3 117.6,89.4 117.58,89.5 117.58,89.51 117.58,90.04 117.8,90.26
+1.8VALW on IN1 (solid shape): outline of 92 points within 149.65,79.68 157.11,89.44
+1.8VALW on TOP: 83.78,79.46 82.86,79.46 82.63,79.23 82.63,77.91 79.43,74.71 79.43,71.51 80.71,70.23 80.71,69.71 79.9,68.89 79.9,65.58 80.63,64.85 80.63,63.88 80.42,63.67 79.65,63.67 76.99,66.33 76.99,67.52 76.89,67.62 76,67.62 75.8,67.42 75.8,64.78 78.95,61.63 81.39,61.63 81.82,62.06 81.82,63.33 82.15,63.66 83.04,63.66 83.17,63.79 83.17,64.9 82.23,65.84 82.23,69.38 81.55,70.05 81.55,71.65 80.55,72.65 80.55,73.82 82,75.27 85.32,75.27 85.48,75.12 85.48,74.76 85.6,74.63 85.96,74.63 86.09,74.76 86.09,75.65 85.78,75.95 85.52,75.95 85.41,75.85 83.32,75.85 83.22,75.95 83.22,76.97 84.08,77.83 89.19,77.83 89.46,77.55 90.35,77.55 90.67,77.87 90.67,78.99 90.4,79.26 88.02,79.26 87.15,78.39 85.45,78.39 85.27,78.57 84.16,78.57 83.85,78.87 83.85,79.38
+1.8VALW on TOP: 108.49,82.51 108.49,83.62 108.24,83.88 106.25,83.88 104.43,85.71 100.84,85.71 99.92,84.78 98.52,84.78 97.21,86.09 94.16,86.09 93.35,86.9 93.35,87.89 93.48,88.02 93.96,88.02 94.57,87.41 97.31,87.41 98.66,86.06 99.24,86.06 100.59,87.41 103.69,87.41 103.69,87.46 104.58,88.35 109.05,88.35 109.56,87.84 110.09,87.84 110.41,88.16 111.96,88.16 112.4,88.6 113.09,88.6 114.48,90 115.75,90 115.75,89.39 115.53,89.16 114.51,89.16 113.11,87.76 111.74,87.76 111.54,87.56 111.54,86.67 111.18,86.32 111.18,85.3 110.93,85.05 110.8,85.05 110.24,85.61 110.24,86.42 109,87.66 108.04,87.66 107.32,86.94 107.32,86.62 107.35,86.6 107.37,86.6 108.31,85.66 108.6,85.66 110.74,83.52 112.64,83.52 112.9,83.78 112.9,84.09 113.3,84.49 114.85,84.49 115.18,84.16 115.18,83.46 113.59,81.87 109.12,81.87
+1.8VALW on TOP: 153.31,73.64 153.31,66.47 149.41,62.57 149.41,47.48 143.54,41.61 141.31,41.61 141.15,41.77 141.15,43.67 144.56,47.07 144.56,62.72 146.81,64.97 148.58,64.97 150.25,66.63 150.25,71.33 150.23,71.34 150.23,73.12 149.38,73.97 149.38,88.11 149.08,88.41 149.08,90.01 149.58,90.51 151.74,90.51 152.24,90.01 152.24,79.79 152.32,79.71 152.32,74.63
+1.8VALW on BOTTOM: 94.09,86.93 94.19,87.03 94.19,88.35 93.99,88.55 92.34,88.55 89.44,85.66 89.44,79.84 89.21,79.61 89.21,77.66 89.44,77.43 90.3,77.43 90.71,77.83 90.71,81.95 91.83,83.07 91.83,83.85 91.04,84.64 91.04,85.96 92,86.93
+1.8VALW on IN1: 79.53,71.79 80.78,71.79 81.11,71.46 81.11,70.92 80.85,70.67 79.71,70.67 79.38,70.34 79.18,70.34 79,70.52 79,71.25
+1.8VALW on IN1: 61.78,67.34 62.92,67.34 64.09,68.51 64.09,69.3 63.94,69.45 62.21,69.45 61.74,68.98 61.74,67.76 61.7,67.72 61.7,67.42
+1.8VALW on IN1: 88.04,78.32 90.2,78.32 90.48,78.04 90.48,77.6 90.23,77.35 88.32,77.35 86.06,75.09 86.06,74.73 85.99,74.66 85.55,74.66 85.3,74.91 85.3,75.8 85.88,76.39 86.11,76.39
+1.8VALW on IN2: 113.93,91.12 113.93,92.15 113.63,92.45 113.63,93.37 113.8,93.5 113.86,93.71 113.86,93.73 114.06,93.93 114.47,93.93 116,95.47 116.04,95.51 116.37,95.51 116.78,95.1 116.78,94.87 116.68,94.77 116.67,94.74 116.49,94.56 116.46,94.55 116.36,94.46 116.36,94.43 114.84,92.92 114.77,92.89 114.69,92.93 114.12,92.79 114.57,92.41 114.67,92.41 114.72,92.32 114.72,91.94 114.69,91.87 114.62,91.84 114.35,91.3 114.94,91.42 115.01,91.49 115.11,91.46 115.12,91.45 115.61,91.45 115.63,91.47 116.19,91.47 116.2,91.46 117.09,91.46 117.4,91.14 117.4,90.26 118.2,89.46 118.2,89.26 117.64,88.7 116.92,88.7 116.26,89.37 115.5,89.37 115.23,89.63 115.25,89.65 115.25,90.32 114.99,90.57 114.48,90.57
+1.8VALW on IN2: 62.82,67.95 62.95,67.83 62.95,66.84 62.79,66.68 61.27,66.68 61.26,66.69 60.71,66.69 60.57,66.82 60.57,67.84 60.7,67.97 61.18,67.97 61.19,67.95
+1.8VALW on IN2: 68.19,25.36 116.45,25.36 116.55,25.26 133.12,25.26 133.16,25.3 133.78,25.3 136.28,27.8 136.28,38.31 140.75,42.78 143.08,42.78 143.19,42.68 143.19,38.5 139.88,35.2 139.88,24.91 136.71,21.74 63.68,21.74 62.05,20.1 53.4,20.1 52.76,19.46 52.76,16.26 52.42,15.92 49.14,15.92 48.23,16.84 48.23,23.15 48.89,23.81 52.91,23.81 52.97,23.75 56.44,23.75 56.44,23.76 66.59,23.76
+1.8VALWP on TOP: 46.98,19.64 46.86,19.52 46.86,18.31 47.17,17.99 47.17,16.28 47.43,16.02 49.97,16.02 50.09,16.15 50.09,16.59 49.59,16.59 49.59,17.1 50.16,17.1 50.16,17.67 50.48,17.99 50.48,19.52 50.35,19.64
+1.8VS on BOTTOM (solid shape): 128.69,111.26 128.69,111.11 128.28,110.7 127.67,110.7 126.94,111.44 126.84,111.53 126.84,111.76 126.16,112.44 126.16,112.59 126.32,112.75 127.2,112.75
+1.8VS on BOTTOM (solid shape): 151.44,83.48 151.44,82.27 151.83,81.87 151.83,81.31 151.81,81.29 151.31,81.29 151.29,81.26 151.29,80.75 151.31,80.73 151.81,80.73 151.83,80.7 151.83,80.5 151.81,80.48 151.3,80.48 151.28,80.45 151.28,79.95 151.3,79.93 151.76,79.93 151.82,79.87 151.82,79.59 151.57,79.33 149.79,79.33 149.54,79.59 149.54,83.27 149.79,83.52 151.4,83.52
+1.8VS on BOTTOM (solid shape): 127.23,93.79 127.28,93.76 127.4,93.64 127.4,93.41 127.24,93.25 127.17,93.25 127.12,93.23 126.89,93.23 126.7,93.3 126.5,93.24 126.49,93.23 126.38,93.23 126.36,93.25 125.92,93.25 125.86,93.31 125.79,93.31 125.76,93.34 125.64,93.34 125.59,93.33 125.54,93.35 125.5,93.35 125.45,93.4 125.45,93.54 125.56,93.65 125.74,93.65 125.83,93.74 126.09,93.74 126.14,93.74 126.19,93.74 126.47,93.74 126.53,93.79
+1.8VS on TOP: 128.71,94.45 128.83,94.45 129.22,94.06 129.22,93.99 129.17,93.94 129.17,93.48 129.47,93.18 129.47,92.92 129.22,92.67 128.96,92.67 128.45,93.18 127.18,93.18 126.93,93.43 126.93,93.56 127.06,93.68 127.95,93.68
+1.8VS on TOP: 120.33,112.23 120.2,112.1 120.2,111.59 120.33,111.46 121.89,111.46 122.23,111.81 122.23,112.48 121.79,112.92 121.6,112.92 120.9,112.23
+1.8VS on TOP: 112.07,164.59 112.86,164.59 113.06,164.38 113.06,162.61 113.39,162.28 113.39,161.29 113.32,161.21 111.96,161.21 111.88,161.29 111.88,164.4
+1.8VS_OUT on BOTTOM (solid shape): 154.74,81.87 154.74,81.35 154.61,81.22 154.61,80.7 154.61,80.7 154.61,79.82 154.56,79.77 154.03,79.77 153.95,79.86 152.52,79.86 152.19,79.53 152.06,79.53 151.99,79.59 151.99,80.03 151.95,80.08 151.46,80.08 151.45,80.09 151.45,80.29 151.48,80.32 151.97,80.32 151.99,80.35 151.99,80.86 151.98,80.88 151.46,80.88 151.44,80.9 151.44,81.1 151.47,81.13 151.97,81.13 151.99,81.15 151.99,81.88 152.11,82 154.61,82
+1.35V on BOTTOM (solid shape): outline of 431 points within 90.44,36.66 108.58,41.19
+1.35V on BOTTOM (solid shape): outline of 635 points within 71.11,21.93 109.02,35.89
+1.35V on TOP: outline of 81 points within 87.94,24.94 147.88,69.55
+1.35V on BOTTOM: 155.88,78.39 156.35,78.39 156.64,78.1 156.64,77.95 156.93,77.65 156.93,74.14 149.98,67.19 147.33,67.19 146.74,67.78 146.74,68.85 148.27,70.38 150.74,70.38 155.91,75.54 155.91,77.71 155.83,77.78 155.83,78.34
+1.35V_SOC on BOTTOM (solid shape): 122.7,82.71 122.75,82.64 122.81,82.59 122.9,82.45 123.05,82.36 123.06,82.36 123.09,82.32 123.1,82.29 123.1,82.06 122.93,81.88 122.9,81.88 122.73,81.88 122.59,81.8 122.27,81.8 122.25,81.82 122.2,81.88 122.14,81.93 122.09,81.98 122.09,82.18 122.18,82.37 122.11,82.57 122.1,82.59 122.1,82.63 122.34,82.87 122.55,82.87
+1.35V_SOC on TOP: outline of 157 points within 115.09,60.64 141.94,94.18 ; 1 cut-out
+1.35VP on BOTTOM (solid shape): 61.11,50.78 61.35,50.78 61.37,50.76 62.64,50.76 62.9,50.5 62.9,50 62.62,49.72 60.38,49.72 60.2,49.89 60.2,51.09 60.31,51.19 60.7,51.19
+1.35VP on TOP: 59.37,50.25 60.13,50.25 60.25,50.38 60.25,51.14 60.32,51.2 60.76,51.2 60.83,51.14 60.83,50.06 60.76,50 59.37,50 59.3,50.06 59.3,50.19
+1.35VP on BOTTOM: 65.97,34.5 65.97,33.42 68.67,30.72 68.67,29.01 69.08,28.6 70.73,28.6 70.92,28.41 70.92,24.6 70.99,24.53 71.43,24.53 71.49,24.47 71.49,24.15 71.43,24.09 70.99,24.09 70.92,24.02 70.92,23.39 70.99,23.33 71.43,23.33 71.49,23.26 71.49,22.94 71.43,22.88 70.99,22.88 70.92,22.82 70.92,19.9 68.57,17.55 63.05,17.55 62.19,18.41 62.19,19.58 62.02,19.74 62.01,19.74 60.86,20.9 60.86,26.53 59.87,27.52 58.95,27.52 58.81,27.66 58.79,27.66 58.79,29.33 58.79,29.34 58.79,30.63 58.26,31.16 56.97,31.16 56.25,31.87 56.25,35.01 56.32,35.07 65.4,35.07
+1.35VS on TOP (solid shape): 124.7,90.84 124.7,90.65 124.58,90.53 124.58,90.47 124.93,90.12 124.93,89.78 124.52,89.37 124.52,88.86 124.76,88.61 124.76,88.34 124.63,88.21 124.38,88.21 123.66,88.93 123.66,89.21 124.14,89.69 124.14,89.97 124.22,90.05 124.22,90.35 124.12,90.45 124.12,90.91 124.22,91.01 124.52,91.01
+1.35VS on BOTTOM (solid shape): 116.47,108.84 116.47,108.59 116.27,108.39 115.74,108.39 114.46,109.66 114.46,110.06 114.63,110.23 114.63,110.34 114.74,110.45 114.86,110.45
+1.35VS on BOTTOM (solid shape): 152.76,74.32 153.51,74.32 153.6,74.23 153.6,73.48 151.97,71.85 151.35,71.85 151.27,71.94 151.27,72.46 151.01,72.72 150.44,72.72 150.32,72.84 150.32,74.43 150.41,74.51 150.9,74.51 150.9,73.95 151.45,73.95 151.45,74.5 151.7,74.5 151.7,73.95 152.24,73.95 152.24,74.51 152.57,74.51
+1.35VS on BOTTOM (solid shape): 120.89,96.22 120.89,96.02 120.79,95.92 120.56,95.92 120.46,95.81 120.46,95.78 120.45,95.76 120.4,95.58 120.45,95.4 120.46,95.39 120.46,95.23 119.98,94.75 118.99,94.75 118.86,94.87 118.86,95.13 118.99,95.26 119.08,95.25 119.13,95.26 119.52,95.26 119.53,95.25 119.62,95.24 119.72,95.25 119.77,95.26 119.82,95.3 119.86,95.33 119.89,95.38 119.93,95.41 119.93,95.44 119.96,95.57 119.93,95.7 119.93,95.71 119.93,95.76 119.77,95.92 119.54,95.92 119.44,96.02 119.44,96.17 119.57,96.3 120.81,96.3
+1.35VS on TOP: 118.11,97.04 119.32,95.84 119.34,95.84 119.36,95.81 119.36,95.77 119.35,95.76 119.29,95.56 119.37,95.36 119.37,94.85 119.19,94.67 118.78,94.67 116.14,97.31 115.9,97.31 115.72,97.35 115.57,97.32 115.56,97.31 114.72,97.31 113.14,98.89 112.64,98.89 112.35,99.18 112.35,100.1 111.48,100.97 111.44,100.97 111.44,101.05 110.1,102.38 110.1,104.2 112.51,106.61 112.51,107.04 115.24,109.77 115.72,109.77 115.94,109.55 115.94,107.88 112.33,104.27 112.33,103.51 112.3,103.44 112.23,103.41 111.93,103.02 112.35,102.76 112.38,102.77 114.35,100.81 114.35,100.78 114.76,100.37 114.78,100.37 115.33,99.83 115.33,99.82 115.4,99.72 115.5,99.66 115.5,99.65 115.76,99.39 115.76,99.37 115.86,99.08 116.15,98.98 116.18,98.98 116.23,98.93 116.22,98.91 116.32,98.64 116.59,98.54 116.61,98.54 116.67,98.49 116.66,98.46 116.75,98.15 117.06,98.07 117.08,98.07 117.8,97.36 117.8,97.34 117.89,97.14 118.1,97.04
+1.35VS on IN1: 117.59,90.59 117.6,90.55 118.21,91.17 118.21,91.52 113.21,96.52 113.21,109.56 113.72,110.07 115.25,110.07 116.32,108.99 116.32,96.06 116.33,96.05 116.42,95.87 116.6,95.78 116.61,95.77 116.83,95.55 116.83,95.54 116.93,95.35 117.12,95.25 117.14,95.25 120.14,92.25 120.14,90.76 119.06,89.68 119.06,89.11 121.09,87.08 121.8,87.08 123.67,88.94 123.69,88.94 124,89.25 124.26,89.25 124.9,88.61 124.9,87.84 123.43,86.38 123.43,86.29 123.1,85.96 123.02,85.96 122.72,86.15 122.43,85.96 122.32,85.96 122.3,85.99 121.81,86.45 121.17,86.26 120.75,85.85 118.86,85.85 118.84,85.83 118.76,85.83 118.33,85.41 118.3,85.4 118.26,85.41 117.84,85.46 117.72,85.06 117.71,84.96 117.62,84.92 116.84,84.92 115.63,86.13 115.94,86.44 115.94,88.95
+1.35VS on IN2: 151.44,75.07 151.44,85.3 151.43,85.31 151.43,86.66 150.88,87.21 149.54,87.21 147.31,89.43 128.39,89.43 127.76,88.79 124.26,88.79 123.69,88.22 123.69,87.9 123.79,87.81 123.79,87.24 123.5,86.95 123.12,86.95 122.93,87.14 122.04,87.14 121.85,86.95 121.85,86.38 122.23,86 123.88,86 125.02,87.14 127.06,87.14 127.63,86.57 130.87,86.57 131.72,87.43 140.36,87.43 141.41,88.48 144.65,88.48 146.55,86.57 147.63,86.57 149.15,85.05 149.15,74.63 149.17,74.61 149.17,72.75 150.09,71.84 151.89,71.84 152.2,72.15 152.2,74.31
+1.35VS_OUT on BOTTOM (solid shape): 154.55,78.32 154.55,77.6 154.22,77.27 154.22,74.89 153.98,74.65 152.09,74.65 152.09,74.1 151.84,74.1 151.84,74.65 151.29,74.65 151.29,74.1 151.04,74.1 151.04,74.65 150.52,74.65 150.45,74.71 150.45,75.5 150.56,75.61 152.04,75.61 152.05,75.6 152.4,75.6 152.63,75.83 152.63,77.54 153.47,78.38 154.49,78.38
+3VALW on BOTTOM (solid shape): 157.1,96.61 157.1,96.34 156.54,96.34 156.54,95.85 157.11,95.85 157.11,95.59 156.98,95.46 155.43,95.46 155.32,95.57 155.32,96.47 155.46,96.61 157.01,96.61
+3VALW on BOTTOM (solid shape): 159.9,123.96 159.9,123.19 159.35,122.64 157.28,122.64 156.52,123.4 156.52,123.66 156.77,123.91 157.28,123.91 157.35,123.85 158.18,123.85 158.48,124.14 159.72,124.14
+3VALW on BOTTOM (solid shape): 150.82,113.77 150.82,113.32 150.87,113.27 151.25,113.27 151.3,113.32 151.3,113.8 151.33,113.83 151.57,113.83 151.61,113.79 151.61,112.7 151.36,112.46 150.01,112.46 149.76,112.71 149.76,113.72 149.88,113.84 150.76,113.84
+3VALW on IN1 (solid shape): outline of 1395 points within 60.86,18.64 155.75,49.33
+3VALW on IN2 (solid shape): 157.92,123.15 157.92,122.64 157.16,121.88 152.58,121.88 151.57,120.86 151.43,120.86 151.42,120.87 151.21,120.94 151,120.87 150.99,120.86 150.88,120.86 150.86,120.87 150.84,120.88 150.66,121.01 150.43,121.01 150.34,121.02 150.3,121.1 150.17,121.23 150.17,121.75 150.42,122 150.55,122 151.82,123.27 153.82,123.27 153.89,123.27 153.95,123.27 154.23,123.27 154.87,123.91 157.16,123.91
+3VALW on TOP: 151.38,122 151.95,121.43 151.95,111.21 158.07,105.09 158.07,100.86 157.71,100.5 157.71,94.47 158.78,93.4 159.56,93.4 160.84,92.12 165.7,92.12 165.71,92.11 167.26,92.11 168.33,91.04 168.33,79.03 167.2,77.9 163.99,77.9 161.79,75.7 160.05,75.7 159.92,75.83 159.92,78.39 161.98,80.44 163.25,80.44 165.42,82.62 165.42,84.89 164.57,85.75 158.87,85.75 155.72,88.9 155.72,90.65 155.74,90.67 155.74,95.31 155.3,95.75 155.3,97.7 154.36,98.64 154.36,103.59 148.9,109.05 148.9,121.24 149.66,122
+3VALW on TOP: 63.56,21.23 61.33,21.23 61.27,21.17 61.27,20.28 60.83,19.83 59.87,19.83 59.68,19.64 59.68,18.94 57.99,17.25 53.39,17.25 51.85,15.71 42.09,15.71 40.47,17.32 40.47,22.47 41.46,23.45 41.46,23.96 40.95,23.96 40.95,24.47 41.52,24.47 41.52,24.79 41.46,24.85 38.54,24.85 38.54,24.34 37.71,24.34 37.71,24.91 37.33,24.91 37.33,24.34 36.51,24.34 36.51,24.85 35.24,24.85 35.11,24.72 35.11,17.04 41.14,11.01 55.48,11.01 57.92,13.44 57.92,14.69 58.31,15.08 61.31,15.08 62.5,16.28 63.94,16.28 64.13,16.47 64.13,18.35 64.57,18.79 64.57,19.83 64.51,19.9 63.87,19.9 63.75,20.02 63.75,21.04
+3VALW on IN2: 161.54,77.97 161.29,78.22 160,78.22 159.9,78.12 159.9,77.66 156.5,74.25 155.35,74.25 155.13,74.03 155.13,70.45 151.48,66.8 151.48,63.99 151.52,63.95 151.52,60.83 150.65,59.96 150.65,48.39 152.48,46.57 155.44,46.57 155.82,46.95 155.82,48.28 155.45,48.65 154.76,48.65 154.43,48.98 154.43,54.53 159.52,59.62 159.52,62.91 160.48,63.88 160.48,65.07 160.5,65.08 160.5,74.34 161.54,75.38
+3VALW_EC on TOP (solid shape): 160.33,137.22 160.33,136.62 160.12,136.41 159.45,136.41 159.43,136.43 158.93,136.43 158.79,136.57 158.79,137.24 158.9,137.36 160.19,137.36
+3VALW_EC on BOTTOM (solid shape): 152.39,151.1 152.39,150.19 152.27,150.07 150.73,150.07 150.59,150.22 150.59,151.15 150.64,151.21 152.28,151.21
+3VALW_EC on BOTTOM: 157.37,127.41 157.96,127.41 158.15,127.22 158.15,126.41 158.74,125.81 162.11,125.81 162.35,126.05 163.58,126.05 163.6,126.04 163.79,126.04 164.01,125.81 164.72,125.81 164.85,125.94 165.03,125.94 165.16,125.81 165.16,123.53 165.01,123.38 161.35,123.38 160.1,124.64 158.52,124.64 157.2,125.95 157.2,127.25
+3VALW_SOC on BOTTOM (solid shape): 115,91.66 115.28,91.66 115.41,91.53 115.41,91.4 114.82,90.82 114.65,90.82 114.6,90.87 114.6,91.2 114.39,91.4 114.39,91.63 114.6,91.83 114.82,91.83
+3VALWP on TOP (solid shape): 39.17,29.04 39.17,25.17 39.11,25.1 38.28,25.1 38.28,24.6 37.97,24.6 37.97,25.1 37.14,25.1 37.14,24.6 36.76,24.6 36.76,25.1 35.36,25.1 35.24,25.23 35.24,29.17 35.49,29.42 38.79,29.42
+3VALWP on BOTTOM (solid shape): 38.98,36.41 38.98,25.04 38.73,24.79 35.24,24.79 34.73,25.29 34.73,36.28 35.17,36.72 38.66,36.72
+3VLP on BOTTOM (solid shape): 53.41,8.22 53.41,6.56 53.34,6.49 53.02,6.49 53,6.51 53,7.02 52.98,7.05 52.54,7.05 52.52,7.03 52.52,6.51 52.49,6.49 52.21,6.49 52.06,6.64 52.06,8.08 52.3,8.33 53.3,8.33
+3VLP on BOTTOM: 150.2,137.88 149.22,137.88 149.19,137.9 149.19,138.02 149.26,138.09 151.06,138.09 151.39,138.42 152.04,138.42 152.35,138.73 162.87,138.73 163.03,138.58 163.03,137.46 163,137.43 151.84,137.43 151.4,137.88 150.2,137.88
+3VLP on BOTTOM: 161.73,128.8 161.61,128.93 160.63,128.93 160.38,128.67 160.38,126.88 160.48,126.78 161.94,126.78 162.04,126.87 162.04,127.53 161.73,127.84
+3VLP on IN2: 162.42,139.51 162.49,139.58 163.02,139.58 163.08,139.52 163.63,139.52 165.28,137.87 165.28,130.45 163.38,128.54 163.38,128.35 163.4,128.34 163.4,127.76 163.31,127.68 161.34,127.68 161.21,127.81 161.21,128.87 161.45,129.12 162.22,129.12 163.57,130.46 163.57,136.53 162.42,137.68
+3VS on TOP (solid shape): 135.56,112.26 135.57,112.26 135.57,111.26 135.44,111.13 133.39,111.13 133.28,111.24 133.28,112.19 133.49,112.4 135.43,112.4
+3VS on TOP (solid shape): 158.56,137.2 158.56,136.52 158.46,136.41 157.13,136.41 157.11,136.43 155.9,136.43 155.76,136.57 155.76,137.28 155.86,137.38 158.38,137.38
+3VS on TOP (solid shape): 55.71,20.49 55.71,20.15 55.17,20.15 55.16,20.14 55.16,19.34 55.71,19.34 55.72,19.32 55.72,18.98 55.15,18.98 55.12,18.96 55.12,18.17 55.15,18.14 55.71,18.14 55.71,18.02 55.71,18.01 55.71,17.74 55.64,17.67 50.86,17.67 50.69,17.84 50.69,19.13 50.82,19.26 52.95,19.26 54.37,20.68 55.52,20.68
+3VS on BOTTOM (solid shape): 14.4,26.14 14.4,25.19 13.99,24.79 12.19,24.79 11.99,24.6 11.99,23.57 11.91,23.48 10.64,23.48 10.53,23.58 10.53,26.12 10.72,26.31 14.23,26.31
+3VS on TOP: 133.72,101.56 134.42,101.56 134.55,101.43 134.55,100.48 135.63,99.4 135.63,99.08 135.5,98.95 135.31,98.95 134.87,99.4 133.79,99.4 133.53,99.14 132.64,99.14 132.64,99.65 132.71,99.72 133.47,99.72 133.66,99.91 133.66,101.49
+3VS on BOTTOM: 148.9,15.51 148.08,15.51 147.31,14.75 146.68,14.75 146.42,14.5 145.92,14.5 145.73,14.31 145.73,12.34 145.85,12.21 146.36,12.21 147.19,13.04 147.63,13.04 147.82,13.23 147.82,14.75 148.27,15.2 148.9,15.2 148.96,15.26 148.96,15.45
+3VS on BOTTOM: 160.97,42.38 163.12,42.38 163.19,42.31 163.19,39.39 162.93,39.14 161.28,39.14 160.78,39.64 160.78,42.18
+3VS on BOTTOM: 154.36,15.51 155.19,15.51 155.31,15.39 155.31,15.07 155.63,14.75 156.52,14.75 157.16,14.12 157.54,14.12 157.6,14.05 157.6,12.09 157.54,12.02 156.97,12.02 156.71,12.28 156.71,13.61 156.14,14.18 155.44,14.18 154.3,15.32 154.3,15.45
+3VS on BOTTOM: 77.21,84.58 74.31,84.58 74.01,84.27 74.01,82.63 74.64,82 78.81,82 82.93,86.12 83.43,86.12 91.94,94.64 91.94,120.99 91.56,121.37 90.23,121.37 89.43,120.57 89.43,96.79
+3VS on BOTTOM: 97.88,151.33 99.83,151.33 99.94,151.21 99.94,149.47 101.01,148.41 101.01,145.36 100.87,145.22 96.42,145.22 96.35,145.3 96.35,146.93 96.63,147.21 99.19,147.21 99.54,147.56 99.54,148.04 99.12,148.46 97.86,148.46 97.69,148.62 97.69,151.14
+3VS on IN1: 90.56,119.96 90.2,120.31 90.2,137.28 92.63,139.71 92.63,139.72 94.1,141.19 94.1,147.1 94.56,147.56 97.19,147.56 97.57,147.18 97.57,140.94 92.07,135.44 92.07,120.31 91.71,119.96
+3VS on IN1: 68.93,80.22 49.78,80.22 48.92,79.36 28.28,79.36 25.44,76.53 25.44,66.19 22.71,63.46 22.71,56.45 22.02,55.75 21.95,55.75 18.19,51.99 18.19,48.86 19.92,47.14 19.92,30.34 14.08,24.49 13.53,24.49 13.14,24.89 13.14,26.86 17.27,30.98 17.27,35.3 16.4,36.17 16.4,47.21 15.36,48.24 15.36,52.79 20.78,58.21 20.78,64.08 23.15,66.44 23.15,72.79 23.49,73.13 23.49,77.49 27.54,81.54 68.18,81.54 71.18,84.54 75.71,84.54 75.94,84.31 75.94,83.46 75.62,83.14 71.85,83.14
+3VS on IN2: 161.82,40.76 161.54,40.47 161.54,33.61 163.28,31.87 163.28,31.15 163.6,30.83 164.17,30.83 164.4,31.06 166.68,31.06 167.07,30.67 167.07,28 167.76,27.31 167.76,21.04 162.93,16.21 162.93,8.34 161.6,7.01 153.35,7.01 152.19,8.16 150.3,8.16 147.66,10.8 147.66,13.44 147.3,13.8 143.12,13.8 141.03,15.9 141.03,19.71 139.38,21.36 66.86,21.36 63.87,18.37 58.22,18.37 56.83,19.77 53.6,19.77 53.07,19.24 53.07,16.24 52.6,15.77 34.41,15.77 25.18,6.54 18.22,6.54 15.21,9.55 15.21,20.87 14.84,21.24 14.83,21.24 14.27,21.8 14.27,25.9 14.16,26.01 13.22,26.01 12.88,25.67 12.88,8.26 16.72,4.43 26.76,4.43 34.61,12.28 70.1,12.28 70.73,12.91 70.73,16.98 72.51,18.75 136.14,18.75 137.41,17.48 137.41,5.93 140.46,2.88 171.32,2.88 172.14,3.7 172.14,33.29 171.38,34.06 167.63,34.06 167.06,34.63 167.06,37.87 164.17,40.76
+3VS_CAM on BOTTOM (solid shape): 107.46,164.04 107.46,162.25 108.07,161.64 109.52,161.64 109.57,161.59 109.57,161.09 109.48,161.01 107.84,161.01 107.13,161.72 107.13,164.05 107.22,164.14 107.36,164.14
+3VS_CARD on BOTTOM (solid shape): 14.4,22.96 14.4,22.18 15.07,21.51 16.31,21.51 16.38,21.45 16.38,21.33 16.31,21.27 14.94,21.27 14.15,22.06 13.39,22.06 13.14,22.31 11.87,22.31 11.74,22.18 10.72,22.18 10.6,22.31 10.6,22.74 10.7,22.84 11.73,22.84 12.06,23.17 14.18,23.17
+3VS_LCDIN on BOTTOM: 93.83,154.6 95.83,154.6 97.21,153.22 97.21,150.05 96.97,149.8 96.04,149.8 93.78,152.06 93.78,154.55
+3VS_OUT on TOP: 59.47,21.64 59.92,21.64 59.98,21.59 59.98,20.73 59.34,20.1 59.34,18.79 58.22,17.67 56,17.67 55.94,17.74 55.94,18.31 55.37,18.31 55.37,18.75 55.89,18.75 55.89,19.5 55.87,19.52 55.34,19.52 55.34,19.81 55.37,19.83 55.37,19.96 55.87,19.96 55.87,20.77 55.95,20.85 55.95,20.86 55.96,20.86 56.52,21.42 59.25,21.42
+3VS_TP on TOP (solid shape): 61.05,74.7 61.05,73.15 61.44,72.77 63.05,72.77 63.29,72.52 63.29,71.78 62.91,71.39 61.02,71.39 60.45,70.82 59.65,70.82 59.58,70.89 59.58,71.59 60.08,72.08 60.08,74.77 60.12,74.81 60.94,74.81
+3VS_TPIN on TOP (solid shape): 58.22,71.46 58.22,70.95 58.1,70.82 56.57,70.82 56.44,70.7 56.44,70.32 56.7,70.06 58.1,70.06 58.22,69.93 58.22,69.55 58.73,69.05 58.73,68.28 58.48,68.03 58.48,67.01 58.35,66.89 55.43,66.89 54.54,67.78 54.54,70.57 55.53,71.56 55.53,71.59 58.1,71.59
+3VS_WLAN_NGFF on TOP: 165.66,63.58 166.93,63.58 167.06,63.46 171.76,63.46 172.27,62.95 172.27,42.63 171.89,42.25 169.92,42.25 169.73,42.44 169.73,44.92 170.87,46.06 170.87,55.33 170.36,55.84 168.33,55.84 167.7,55.2 167.7,49.68 167.51,49.49 165.66,49.49 165.65,49.47 165.11,49.47 163.51,51.07 163.51,52.28 163.89,52.66 164.65,52.66 165.41,53.42 165.41,63.33
+3VS_WLAN_NGFF on BOTTOM: 172.01,45.3 169.98,45.3 169.54,45.74 166.36,45.74 165.79,45.17 165.79,42.63 165.47,42.31 163.51,42.31 163.38,42.18 163.38,39.84 163.63,39.58 167.38,39.58 167.7,39.9 167.7,41.8 168.14,42.25 169.47,42.25 169.73,41.99 169.73,40.5 169.8,40.43 172.01,40.43 172.14,40.55 172.14,45.17
+3VS_WLAN_NGFF on BOTTOM: 171.63,62.95 169.09,62.95 168.4,62.25 168.4,60.79 168.59,60.6 169.73,60.6 169.98,60.85 169.98,61.81 170.11,61.93 171.63,61.93 171.76,62.06 171.76,62.82
+5V_AUDIO on TOP (solid shape): 158.11,23.51 158.11,23.01 158,22.9 156.18,22.9 155.94,23.14 155.94,23.86 156.08,24 157.62,24
+5V_AUDIO on BOTTOM (solid shape): 155.17,9.57 155.17,7.93 155.03,7.79 154.18,7.79 154.08,7.89 154.08,9.58 154.23,9.74 155.01,9.74
+5V_AUDIO on TOP: 156.88,10.4 154.5,10.4 154.08,9.98 154.08,9.01 154.53,8.57 155.33,8.57 155.91,9.15 156.89,9.15 157.09,9.36 157.09,10.18
+5V_AUDIO on BOTTOM: 157.54,23.43 157.37,23.43 157.21,23.26 157.21,22.59 156.97,22.35 156.5,22.35 156.11,21.97 156.11,20.62 155.87,20.62 155.73,20.76 155.73,22.5 155.75,22.52 155.75,23.74 156.46,24.45 156.46,24.46 156.58,24.58 157.41,24.58 157.79,24.2 157.79,23.68
+5V_HDD on TOP: 158.68,33.49 155.95,33.49 155.7,33.23 155.7,31.29 155.97,31.01 159.89,31.01 160.14,31.26 161.99,31.26 162.2,31.06 164.7,31.06 165.16,31.52 165.16,33.36 165.03,33.49 159.7,33.49 159.7,33.99 159.51,33.99 159.51,33.49 158.87,33.49 158.87,33.99 158.68,33.99
+5V_HDD on BOTTOM: 164.52,31.2 165.75,31.2 166.87,32.31 167.98,32.31 168.08,32.41 168.08,33.12 168.24,33.28 168.24,34 168.05,34.18 166.8,34.18 166.65,34.34 165.69,34.34 165.03,33.68 165.03,33.66 165.02,33.66 164.33,32.98 164.33,31.39
+5V_HUB on BOTTOM (solid shape): 146.98,56.17 146.98,52.52 147.5,52 147.5,49.7 147.41,49.61 147.23,49.61 147.12,49.71 147.12,51.77 146.16,52.73 146.16,54.25 146.15,54.26 146.15,54.49 145.89,54.76 145.89,55.93 145.91,55.95 145.91,56.18 145.97,56.24 146.9,56.24
+5V_PVDD on BOTTOM: 147.88,12.91 149.03,12.91 149.66,13.55 149.66,13.67 150.15,14.16 150.15,14.79 150.22,14.87 150.3,14.87 150.35,14.82 150.35,13.98 149.92,13.55 149.92,13.39 149.69,13.17 149.69,12.43 149.98,12.14 151.54,12.14 151.71,12.3 152.2,12.3 152.28,12.38 152.28,13.52 152.13,13.67 152.13,14.74 152.18,14.79 152.33,14.79 152.36,14.77 152.36,13.85 152.61,13.6 152.61,11.09 152.56,11.04 145.93,11.04 145.89,11.08 145.89,11.95 145.97,12.02 147,12.02
+5V_USB_PWR1 on BOTTOM (solid shape): 23.11,44.79 23.11,43.71 23.55,43.26 24.31,43.26 24.44,43.14 24.44,42.25 24.31,42.12 23.3,42.12 22.79,42.63 17.46,42.63 17.39,42.69 14.81,42.69 14.22,43.29 14.22,43.84 15.17,44.79 20.69,44.79 20.82,44.92 22.98,44.92
+5V_USB_PWR1 on TOP: 15.01,45.32 16.55,45.32 17.11,44.76 17.11,40.61 16.85,40.35 16.25,40.35 15.76,40.84 15.76,41.65 14.17,43.24 14.17,44.48
+5V_USB_PWR2 on TOP: 165.73,36.03 165.48,36.28 165.48,36.92 165.2,37.19 164.3,37.19 163.76,36.65 163.76,35.2 165.35,33.61 165.35,31.39 165.47,31.26 166.93,31.26 168.78,33.1 168.78,35.77 168.52,36.03
+5V_USB_PWR2 on BOTTOM: 166.11,38.5 165.66,38.95 161.03,38.95 160.58,39.39 160.58,40.79 160.39,40.98 159.25,40.98 159.12,40.85 159.12,36.66 159.63,36.15 164.21,36.15 164.47,35.89 165.64,35.89 166.11,36.36
+5VALW on TOP (solid shape): 28.6,45.04 28.63,45.04 28.63,42.55 28.51,42.43 25.46,42.43 25.32,42.57 25.32,43 25.56,43.25 25.56,44.07 26.47,44.98 26.65,44.98 26.81,45.14 28.5,45.14
+5VALW on BOTTOM (solid shape): 27.49,44.03 27.49,42.5 27.11,42.12 25.63,42.12 25.27,42.49 25.27,44.05 25.51,44.29 27.22,44.29
+5VALW on BOTTOM (solid shape): 155.81,95.17 155.81,95.05 155.82,95.04 155.82,94.17 155.75,94.09 155.75,91.02 155.54,90.81 155.35,90.81 155.12,91.04 155.12,92.45 154.49,93.09 154.49,93.81 154.62,93.94 154.62,95.19 154.72,95.3 155.68,95.3
+5VALW on BOTTOM (solid shape): 58.22,29.12 58.22,24.8 57.85,24.43 57.24,24.43 56.97,24.15 56.97,22.93 56.15,22.12 53.4,22.12 53.08,22.44 53.08,22.88 53.14,22.94 53.59,22.94 53.65,23.01 53.65,23.71 53.59,23.77 53.14,23.77 53.08,23.83 53.08,24.09 53.14,24.15 53.59,24.15 53.65,24.21 53.65,24.98 53.59,25.04 53.21,25.04 53.14,25.1 53.14,25.67 53.52,26.06 54.29,26.06 55.05,26.82 55.05,29.15 55.25,29.36 57.98,29.36
+5VALW on IN2 (solid shape): outline of 137 points within 154.62,78.42 157.85,95.25
+5VALW on TOP: outline of 110 points within 54.35,21.23 164.08,79.43 ; 1 cut-out
+5VALW on BOTTOM: 159.86,46.22 154.02,46.22 153.55,45.75 153.55,43.28 153.65,43.18 154.65,43.18 155.26,43.78 158.5,43.78 158.83,43.45 158.83,42.73 159.05,42.51 159.72,42.51 160,42.79 160,46.08
+5VALW on BOTTOM: 152.83,54.34 151.77,54.34 149.78,56.33 147.76,56.33 147.64,56.21 147.64,55.24 149.26,55.24 151.68,52.82 152.63,52.82 153,53.2 153,54.16
+5VALW on IN2: 26.59,44.43 26.86,44.16 26.85,44.15 26.85,43.01 25.71,41.87 25.71,34.37 29.01,31.07 29.01,26.44 29.68,25.77 35.43,25.77 35.45,25.76 35.47,25.74 35.81,25.55 36.14,25.74 36.16,25.76 36.19,25.77 36.25,25.77 36.28,25.76 36.3,25.74 36.63,25.55 36.97,25.74 36.99,25.76 37.04,25.76 37.06,25.74 37.39,25.55 37.73,25.74 37.75,25.76 37.8,25.76 37.82,25.74 38.16,25.55 38.49,25.74 38.51,25.76 38.54,25.77 42.19,25.77 42.67,26.25 49.76,26.25 50.79,27.27 52.92,27.27 54.73,29.08 57.23,29.08 57.46,28.85 57.46,25.23 56.19,23.96 48.44,23.96 45.62,21.14 28.65,21.14 25.3,24.49 25.3,29.86 23.13,32.02 23.13,36.51 22.92,36.72 22.92,43.75 23.6,44.43
+5VALWP on BOTTOM: 51.05,36.79 48.57,36.79 48.32,36.53 48.32,31.14 46.79,29.61 46.79,24.15 47.62,23.33 51.49,23.33 52.38,22.44 52.83,22.44 52.89,22.5 52.89,23.07 52.95,23.13 53.4,23.13 53.46,23.2 53.46,23.52 53.4,23.58 52.95,23.58 52.89,23.64 52.89,24.28 52.95,24.34 53.4,24.34 53.46,24.4 53.46,24.72 53.4,24.79 52.95,24.79 52.89,24.85 52.89,26.63 51.62,27.9 51.62,36.22
+5VS on TOP (solid shape): 55.71,25.3 55.26,25.3 55.22,25.26 55.22,24.6 55.28,24.54 55.73,24.54 55.77,24.5 55.77,24.14 55.73,24.11 55.24,24.11 55.22,24.08 55.22,23.38 55.26,23.34 55.73,23.34 55.77,23.31 55.77,22.07 55.59,21.9 53.85,21.9 53.66,22.08 51.97,22.08 51.85,21.95 51.85,21.12 51.7,20.96 49.46,20.96 49.33,21.09 49.33,24.75 49.9,25.31 53.44,25.31 54.03,25.9 55.71,25.9
+5VS on BOTTOM (solid shape): 93.87,141.51 93.87,140.23 93.52,139.87 90.61,139.87 90.14,140.34 90.14,141.57 90.35,141.79 93.59,141.79
+5VS on IN1 (solid shape): 91.5,142.71 91.5,141.44 91.37,141.31 90.23,141.31 90.1,141.44 90.1,142.58 90.48,142.96 91.24,142.96
+5VS on IN1 (solid shape): 162.05,145.61 162.05,144.93 161.92,144.8 161.92,143.91 161.82,143.81 161.09,143.81 160.78,144.13 160.78,144.36 160.9,144.48 160.9,145.6 161.16,145.85 161.8,145.85
+5VS on TOP: 165.41,118.53 167.54,118.53 168.17,117.91 168.17,114.01 168.04,113.88 167.37,113.88 167.27,113.99 167.27,116.73 166.65,117.34 165.41,117.34 165.27,117.49 165.27,118.39
+5VS on TOP: 159.76,35.96 158.04,35.96 157.92,35.83 157.92,33.8 158.04,33.68 158.49,33.68 158.49,34.25 159.12,34.25 159.12,33.68 159.31,33.68 159.31,34.25 159.89,34.25 159.89,33.74 160.27,33.74 160.33,33.8 160.33,35.39
+5VS on BOTTOM: 25.76,76.07 25.74,76.09 18.63,76.09 17.36,77.36 17.36,79.01 17.68,79.33 18.87,79.33 19.91,78.29 27.43,78.29 27.65,78.06 27.65,76.37 27.35,76.07
+5VS on BOTTOM: 164.65,118.64 165.49,118.64 165.87,118.27 165.87,115.86 164.65,114.64 164.65,113.37 164.52,113.24 163.57,113.24 163.44,113.37 163.44,117.44
+5VS on BOTTOM: 165.09,45.87 164.52,46.44 164.52,52.54 165.6,53.61 165.6,63.08 165.79,63.27 165.79,66.44 166.3,66.95 166.3,71.01 169.47,74.19 169.47,76.22 168.65,77.05 168.65,84.86 169.35,85.56 169.35,86.7 168.84,86.7 168.84,86.89 169.35,86.89 169.35,87.52 168.84,87.52 168.84,87.71 169.35,87.71 169.35,88.35 169.47,88.48 171.95,88.48 172.08,88.35 172.08,83.9 171.82,83.65 170.87,83.65 170.74,83.52 170.74,82.63 172.21,81.17 172.21,67.84 168.52,64.16 168.52,63.65 168.08,63.2 168.08,46.5 167.44,45.87
+5VS on BOTTOM: 145.55,10.57 143.11,10.57 141.03,12.66 141.03,19.83 140.77,20.09 139.44,20.09 139.25,19.9 139.25,19.13 138.99,18.88 138.99,11.39 144.58,5.8 155.12,5.8 155.25,5.93 155.25,6.94 155.12,7.07 149.82,7.07 149.8,7.08 148.38,7.08 147.38,8.09 147.38,10.16 147.3,10.23 145.89,10.23
+5VS on IN1: 23.46,61.08 26.19,63.81 26.19,76.6 26.36,76.77 28.25,76.77 28.96,76.06 28.96,60.93 25.33,57.3 25.33,45.93 24.06,44.66 24.06,34.25 26.54,31.77 26.54,25.34 30.84,21.04 45.9,21.04 47.73,22.86 53.98,22.86 56.04,20.81 56.06,20.81 58.63,18.25 62.41,18.25 63.18,19.01 63.18,20.53 66.6,23.96 66.6,25.87 67.46,26.72 135.09,26.72 141.15,32.79 141.15,33.99 144.9,37.74 151.63,37.74 156.14,42.25 160.27,42.25 165.28,47.26 166.3,47.26 167.06,46.5 167.06,41.11 159.44,33.49 150.11,33.49 144.93,28.31 144.93,22.53 141.47,19.07 139.63,19.07 138.01,20.69 69.94,20.69 68.32,19.07 68.32,16.57 67.82,16.07 62.17,16.07 61.03,14.93 58.89,14.93 58.4,14.45 54.92,14.45 53,12.53 45.71,12.53 40.7,17.55 29.33,17.55 23.2,23.67 23.2,28.56 21.93,29.83 21.93,47.36 23.49,48.92 23.49,53.17 23.46,53.2
+5VS on IN2: 159.81,119.53 158.32,121.01 158.32,130.11 158.31,130.12 158.78,130.59 160.24,130.59 161.01,131.36 161.01,137.29 160.04,138.26 160.04,143.02 160.39,143.38 160.39,144.1 160.84,144.55 161.68,144.55 161.99,144.23 161.99,143.09 162.31,142.77 162.31,137.69 163.28,136.72 163.28,130.59 162.1,129.41 160.45,129.41 160.18,129.14 160.18,125.67 161.37,124.48 161.37,119.71 161.79,119.29 165.72,119.29 166.05,118.96 166.05,117.43 165.79,117.18 162.24,117.18 159.89,119.53
+5VS_ODD on TOP (solid shape): outline of 101 points within 153.39,80.55 165.29,84.93
+5VS_ODD on BOTTOM: 164.7,85.17 164.01,85.17 163.89,85.05 163.89,82.51 163.89,82.51 163.89,81.03 164.11,80.81 164.65,80.81 164.83,80.99 164.83,82.11 165.1,82.38 166.68,82.38 166.81,82.51 166.81,84.87 166.65,85.03 164.84,85.03
+5VS_ODD_R1 on BOTTOM: 169.09,88.6 166.81,88.6 165.09,86.89 165.09,85.99 165.25,85.84 166.66,85.84 167.06,85.43 167.06,83.4 167.13,83.33 168.33,83.33 168.46,83.46 168.46,84.79 169.09,85.43 169.09,86.51 168.59,86.51 168.59,87.14 169.09,87.14 169.09,87.33 168.59,87.33 168.59,87.9 169.16,87.9 169.16,88.54
+5VS_OUT on TOP: 56.05,26.03 55.9,25.88 55.9,25.24 55.84,25.18 55.42,25.18 55.37,25.13 55.37,24.79 55.4,24.75 55.86,24.75 55.9,24.71 55.9,24.02 55.86,23.99 55.39,23.99 55.35,23.95 55.35,23.6 55.42,23.54 55.85,23.54 55.9,23.49 55.9,22.79 56.04,22.65 58.86,22.65 59.04,22.83 59.05,22.82 59.24,22.82 59.49,22.56 60,22.56 60.06,22.63 60.06,23.71 59.94,23.83 59.37,23.83 58.67,24.53 58.67,25.71 58.35,26.03
+5VS_TOUCH on BOTTOM: 111.19,164.19 112.46,164.19 112.82,163.84 112.82,160.94 112.62,160.74 112.62,159.63 112.81,159.44 113.61,159.44 113.73,159.32 113.73,158.71 113.61,158.58 112.79,158.58 112.46,158.25 111.5,158.25 111.4,158.35 111.4,159.95 110.98,160.37 110.98,161.27 111.04,161.34 111.61,161.34 111.75,161.48 111.75,162.11 111.75,162.12 111.75,162.35 111.14,162.95 111.14,164.14
+VCC_3IN1 on TOP (solid shape): 26.35,18.63 26.35,17.1 26.09,16.85 23.81,16.85 23.42,17.23 23.42,19.01 23.55,19.13 25.84,19.13
+VCC_3IN1 on BOTTOM (solid shape): 24.84,19.67 26.73,19.67 26.88,19.52 26.88,17.28 26.32,16.72 23.3,16.72 23.04,16.98 23.04,17.86 22.79,18.12 22.79,19.01 23.46,19.67 24.83,19.67
+VCC_3IN1 on BOTTOM (solid shape): 15.06,23.29 15.06,22.48 15.51,22.03 16.3,22.03 16.38,21.95 16.38,21.83 16.31,21.76 15.02,21.76 14.52,22.26 14.52,23.29 14.62,23.39 14.97,23.39
+VCC_3IN1 on IN2: 14.65,23.43 21.55,23.43 23.46,21.52 23.46,19.89 24.31,19.03 24.31,17.86 24.22,17.78 22.36,17.78 21.58,18.55 21.58,21.42 20.69,22.31 14.56,22.31 14.37,22.5 14.37,23.15
+VCC_LPC on BOTTOM (solid shape): 153.89,150.82 153.89,148.36 154.29,147.96 154.83,147.96 155.06,147.73 155.06,145.57 155.02,145.52 154.93,145.52 154.86,145.59 154.86,147.45 154.75,147.56 154.18,147.56 154.17,147.54 153.7,147.54 152.96,148.29 152.96,149.82 152.86,149.93 152.86,150.98 152.98,151.11 153.61,151.11
+VCC_LPC_SOC on IN2 (solid shape): 128.71,95.27 128.71,94.95 128.07,94.31 128.04,94.31 127.83,94.24 127.7,94.06 127.7,94.04 127.65,94 127.52,93.87 126.93,93.87 126.68,93.62 125.93,93.62 125.7,93.85 125.62,93.85 125.22,94.25 124.01,94.25 123.82,94.45 123.82,94.7 123.88,94.76 125.34,94.76 125.85,94.25 126.8,94.25 126.96,94.41 127.51,94.38 127.31,94.9 127.31,94.9 127.31,95.21 127.56,95.46 128.52,95.46
+VCC_LPC_SOC on TOP: 132.33,100.73 131.82,100.73 131.76,100.67 131.76,97.56 131.82,97.49 132.33,97.49 132.39,97.56 132.39,98.13 132.58,98.32 133.09,98.32 133.15,98.38 133.15,98.83 133.09,98.89 132.58,98.89 132.39,99.08 132.39,100.67
B+_3/5V on TOP: 34.54,44.85 30.47,44.85 30.28,44.66 30.28,42.06 30.54,41.8 33.01,41.8 33.84,40.98 34.85,40.98 35.05,40.79 41.97,40.79 43.05,41.87 50.18,41.87 50.46,42.15 50.46,45.44 50.37,45.53 49.85,45.53 49.85,44.98 49.1,44.98 49.1,45.54 48.65,45.54 48.65,44.99 47.9,44.99 47.9,45.54 46.65,45.54 45.97,44.86 43.91,44.86 43.9,44.85 41.9,44.85 40.57,43.52 35.87,43.52
GND on TOP (solid shape): 28.63,46.76 28.63,45.55 28.44,45.36 27.3,45.36 27.11,45.55 27.11,46.76 27.17,46.82 28.57,46.82
GND on TOP (solid shape): 28.63,42.06 28.63,40.85 28.5,40.72 27.17,40.72 27.04,40.85 27.04,41.99 27.23,42.18 28.5,42.18
GND on TOP (solid shape): 124.77,149.82 124.77,147.09 124.64,146.96 122.04,146.96 121.85,147.15 121.85,149.63 122.17,149.94 124.64,149.94
GND on TOP (solid shape): 127.06,122.19 127.06,117.94 126.93,117.81 125.28,117.81 125.09,118 125.09,122.19 125.22,122.32 126.93,122.32
GND on TOP (solid shape): 155.9,76.47 155.9,75.71 155.71,75.53 154.82,75.53 154.61,75.74 154.61,76.46 154.71,76.56 155.81,76.56
GND on TOP (solid shape): 156.01,157.44 156.01,155.02 155.89,154.9 149.03,154.9 148.77,155.15 148.77,157.44 149.03,157.69 155.76,157.69
GND on TOP (solid shape): 53.3,26.91 53.3,25.89 52.99,25.59 52.99,25.58 51.84,25.58 51.49,25.93 51.49,26.82 51.68,27.01 53.19,27.01
GND on TOP (solid shape): 157.55,172.49 157.55,171.37 157.38,171.2 155.86,171.2 155.73,171.33 155.73,172.12 156.28,172.66 157.37,172.66
GND on TOP (solid shape): 59.18,54.12 59.18,51.9 59.05,51.77 59.05,50.95 58.86,50.95 58.86,52.15 58.29,52.73 57.71,52.73 57.64,52.8 57.64,54.24 57.71,54.31 58.98,54.31
GND on TOP (solid shape): 92.93,65.68 92.93,64.77 92.55,64.38 91.5,64.38 91.34,64.54 91.34,65.65 91.43,65.74 92.32,65.74 92.45,65.87 92.74,65.87
GND on TOP (solid shape): 147.22,154.47 147.22,154.14 147.11,154.03 145.95,154.03 145.84,154.15 144.62,154.15 144.54,154.22 144.54,154.39 144.61,154.45 145.97,154.45 146.05,154.54 147.15,154.54
GND on TOP (solid shape): 155.97,87.06 155.97,84.88 155.84,84.75 154.67,84.75 154.6,84.82 154.6,85.45 154.28,85.78 153.27,85.78 153.12,85.63 153.12,85.04 153.03,84.96 152.49,84.96 152.46,84.98 152.46,87.09 152.66,87.29 155.74,87.29
GND on TOP (solid shape): 126.61,90.25 126.8,90.25 126.99,90.44 127.37,90.44 128.14,89.68 128.14,89.43 127.12,88.41 126.1,88.41 125.98,88.29 125.72,88.29 125.47,88.54 125.47,88.86 126.17,89.56 126.17,89.81 125.72,90.25 125.34,90.25 125.22,90.13 125.15,90.13 124.77,90.51 124.77,90.57 125.15,90.95 125.91,90.95
GND on TOP (solid shape): 112.2,100.03 112.2,99.12 112.62,98.7 113.13,98.7 114.11,97.72 114.11,97.34 113.88,97.11 113.88,96.83 113.83,96.78 113.88,96.73 113.88,96.4 114.51,95.76 114.51,94.93 114.08,94.49 113.73,94.49 112.64,95.58 112.01,95.58 111.88,95.72 111.88,98.38 111.41,98.85 111.11,98.85 110.8,99.16 110.8,100.2 111.11,100.5 111.73,100.5
GND on TOP (solid shape): 135.06,94.22 135.06,93.66 133.99,92.59 133.52,92.59 132.42,91.5 132.02,91.5 131.51,90.99 129.48,90.99 129.04,90.56 128.74,90.56 128,91.29 126.86,91.29 126.58,91.57 126.58,92.11 126.76,92.28 127.44,92.28 127.72,92 128.36,92 128.79,91.57 129.5,91.57 131.56,93.63 132.88,93.63 133.18,93.93 133.44,93.93 133.44,93.94 133.94,93.94 134.35,94.34 134.93,94.34
GND on TOP (solid shape): 122.82,94.21 123.18,94.21 123.25,94.14 123.33,94.21 123.53,94.21 123.71,94.04 123.99,94.04 124.33,94.38 124.45,94.38 124.85,93.97 124.85,93.93 124.62,93.71 124.62,93.3 125.39,92.54 125.39,92.41 125.06,92.08 124.85,92.08 124.65,92.28 124.42,92.28 124.09,91.95 123.86,91.95 123.48,92.33 123.85,92.7 124.03,92.7 124.09,92.77 124.09,93.38 123.74,93.73 123.41,93.73 123.4,93.73 122.64,93.73 122.34,93.43 122.26,93.43 121.8,93.88 121.8,93.96 122.39,94.54 122.49,94.54
GND on TOP (solid shape): 117.43,89.94 117.43,89.77 117.26,89.59 116.78,89.59 116.52,89.34 116.52,88.17 117.91,86.78 117.91,86.77 117.98,86.66 118.07,86.58 118.07,86.21 117.97,86.11 117.61,86.11 117.49,86.24 117.36,86.24 117.29,86.25 117.21,86.24 117.11,86.24 116.98,86.11 116.98,86.03 116.98,86.03 116.96,85.92 116.98,85.81 116.98,85.8 116.98,85.48 116.6,85.1 116.6,84.71 116.47,84.59 116.06,84.59 115.84,84.82 115.84,86.06 116.27,86.49 116.27,87.2 116.24,87.23 116.24,87.26 116.24,87.33 116.22,87.42 116.22,87.64 115.96,87.89 115.96,88.52 115.88,88.61 115.85,88.65 115.81,88.68 115.81,89.39 116.58,90.16 117.21,90.16
GND on TOP (solid shape): 121.48,93.05 121.48,92.65 120.12,91.29 120.12,91.1 120.31,90.91 120.31,90.59 119.82,90.1 119.83,90.08 119.7,89.96 118.98,89.96 118.97,89.97 118.96,89.96 118.74,89.96 118.3,89.52 118.18,89.52 117.85,89.86 117.85,90.03 118.11,90.3 118.11,90.3 118.48,90.66 118.58,90.68 118.65,90.59 119.21,90.38 119,90.94 118.91,91.01 118.93,91.11 120.95,93.13 121.4,93.13
GND on TOP (solid shape): 118.85,94.41 118.85,93.52 117.87,92.55 117.64,92.55 117.49,92.7 117.31,92.7 116.81,92.19 116.81,92.18 116.74,92.12 117.11,91.75 117.11,91.58 116.98,91.45 116.29,91.45 115.95,91.12 115.56,91.12 115.28,91.39 115.27,91.39 115.24,91.43 115.21,91.39 115.1,91.39 114.95,91.55 114.94,91.56 114.85,91.74 114.68,91.83 114.66,91.83 114.49,92 114.49,92.18 114.03,92.64 114.03,92.89 114.21,93.07 114.46,93.07 114.9,92.64 114.9,92.54 114.95,92.49 114.98,92.41 114.95,92.34 115.09,91.78 115.49,92.2 115.51,92.29 115.59,92.33 115.86,92.33 115.93,92.3 115.96,92.23 116.51,91.96 116.29,92.53 116.25,92.55 116.23,92.58 116.23,92.66 117.41,93.84 117.41,94.21 116.75,94.88 116.74,94.89 116.71,94.98 116.65,95.05 116.65,95.41 117.11,95.87 117.4,95.87
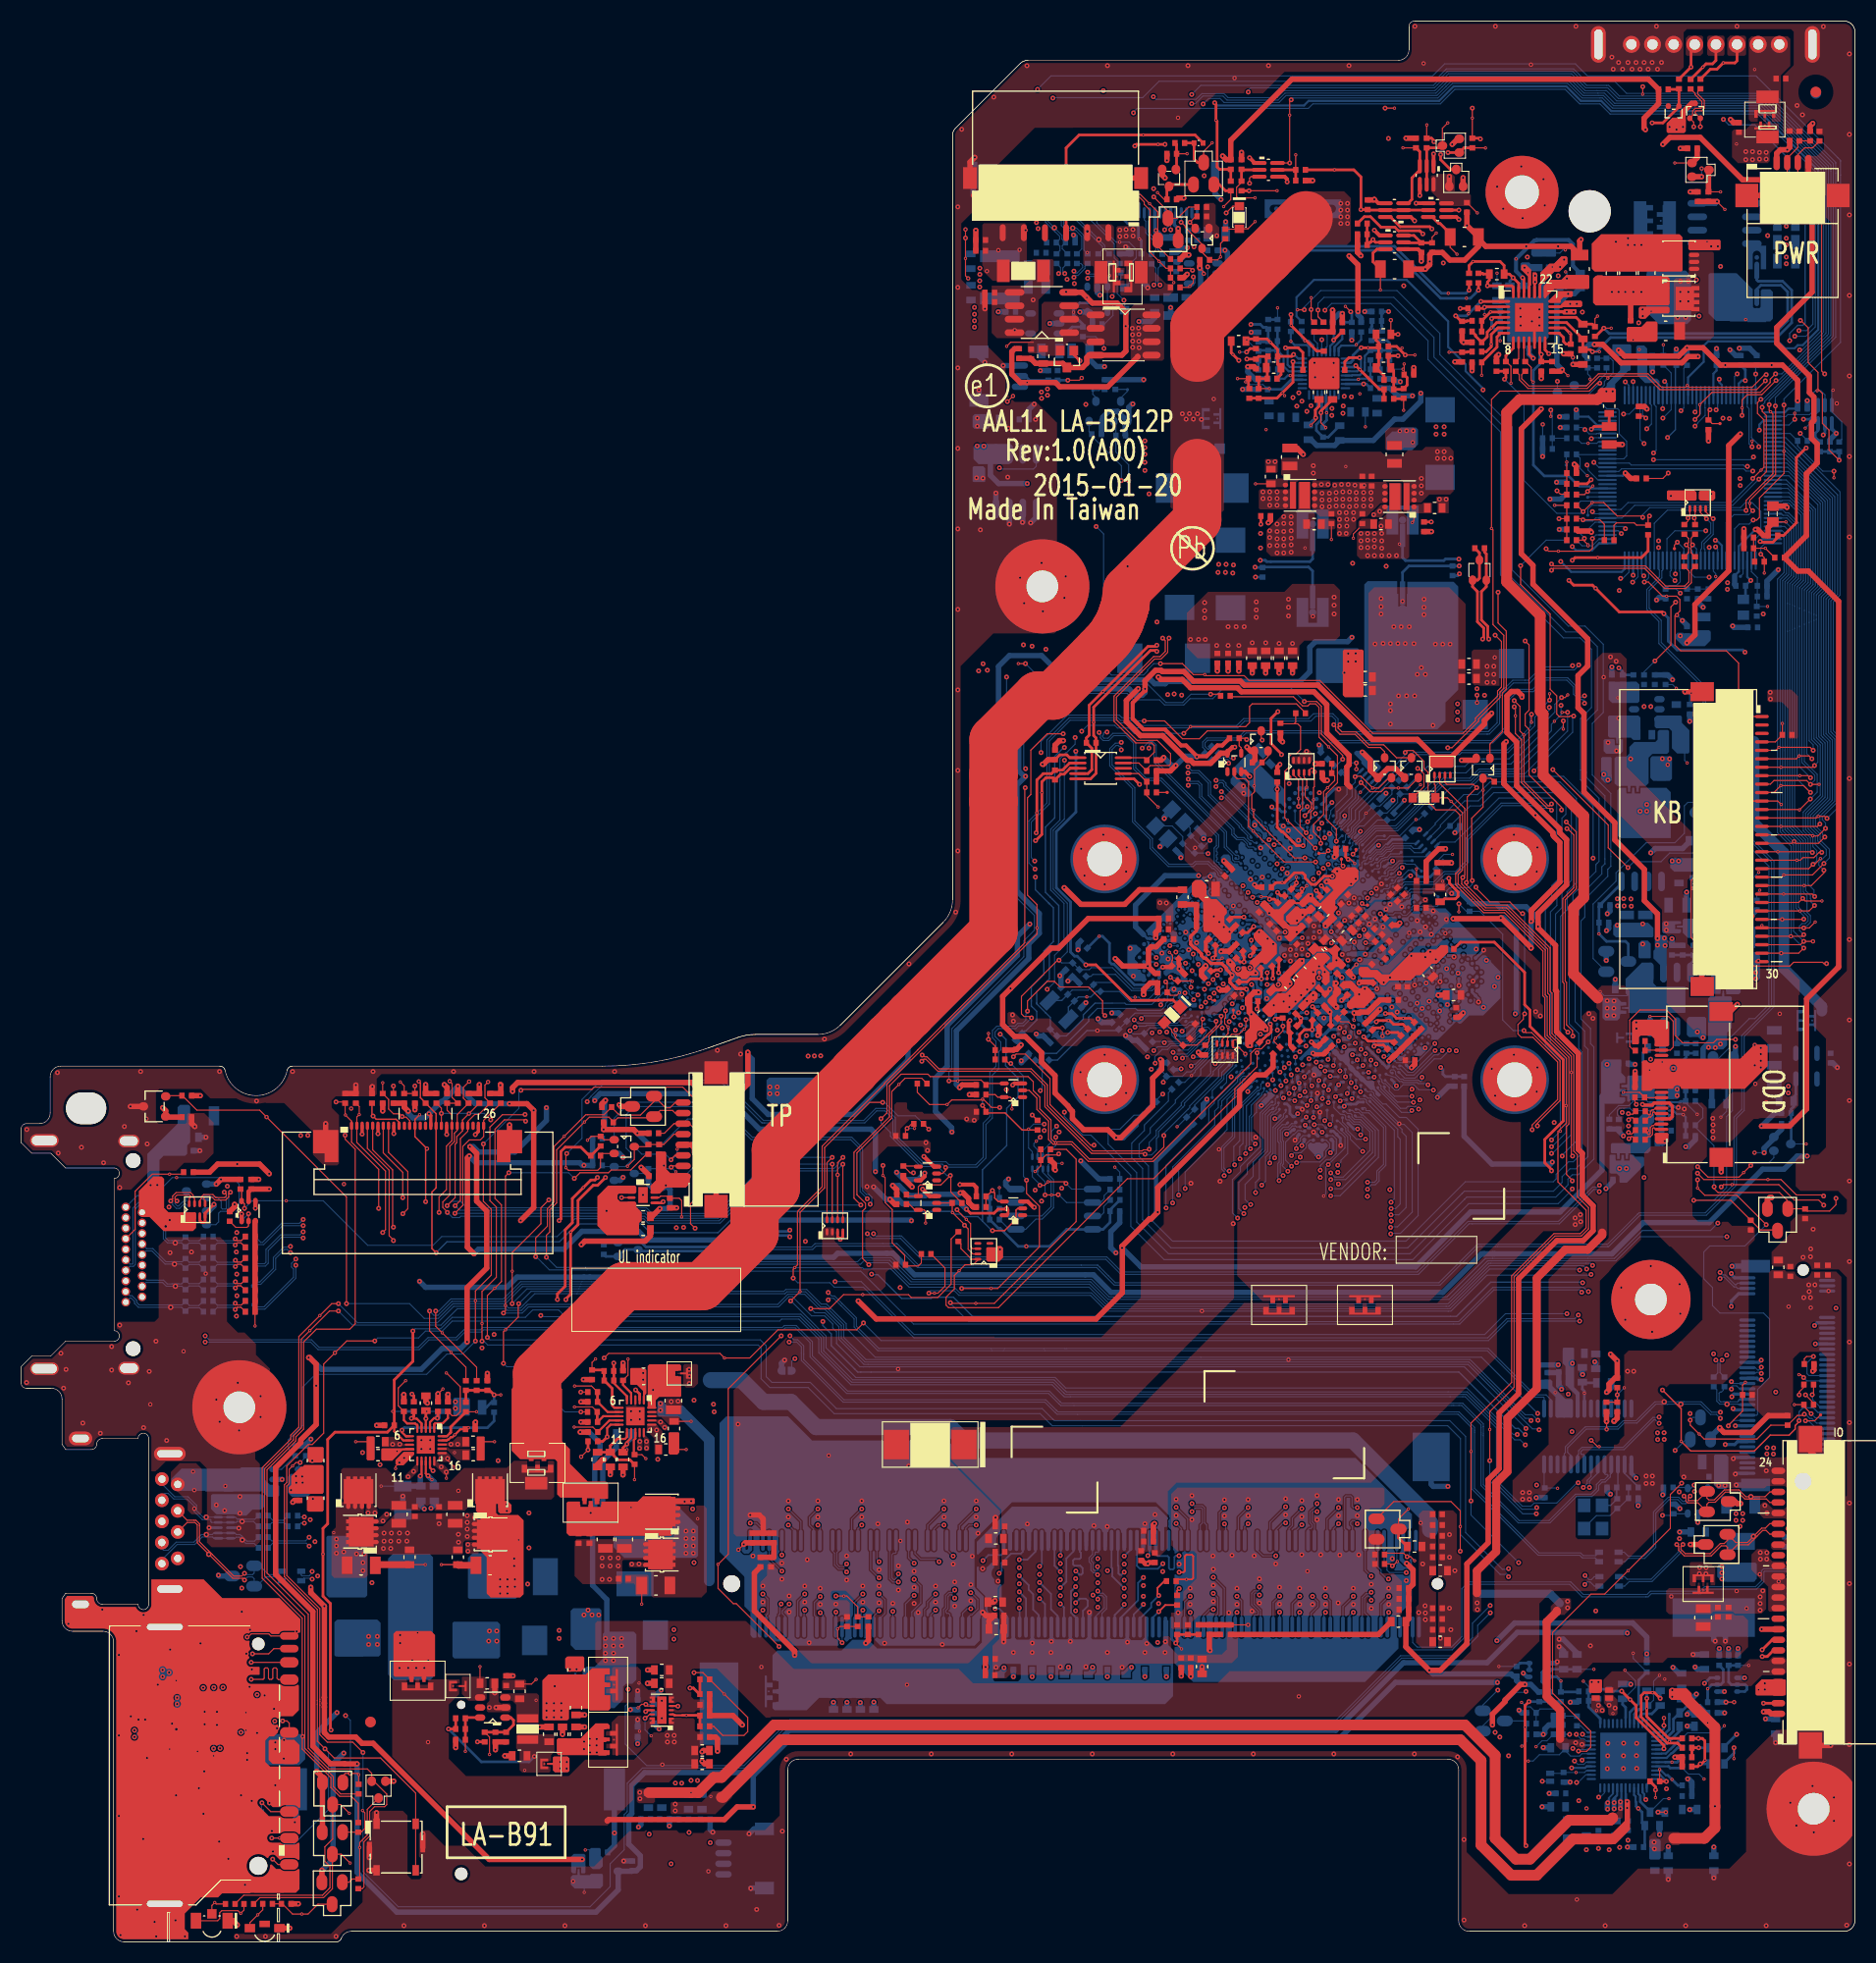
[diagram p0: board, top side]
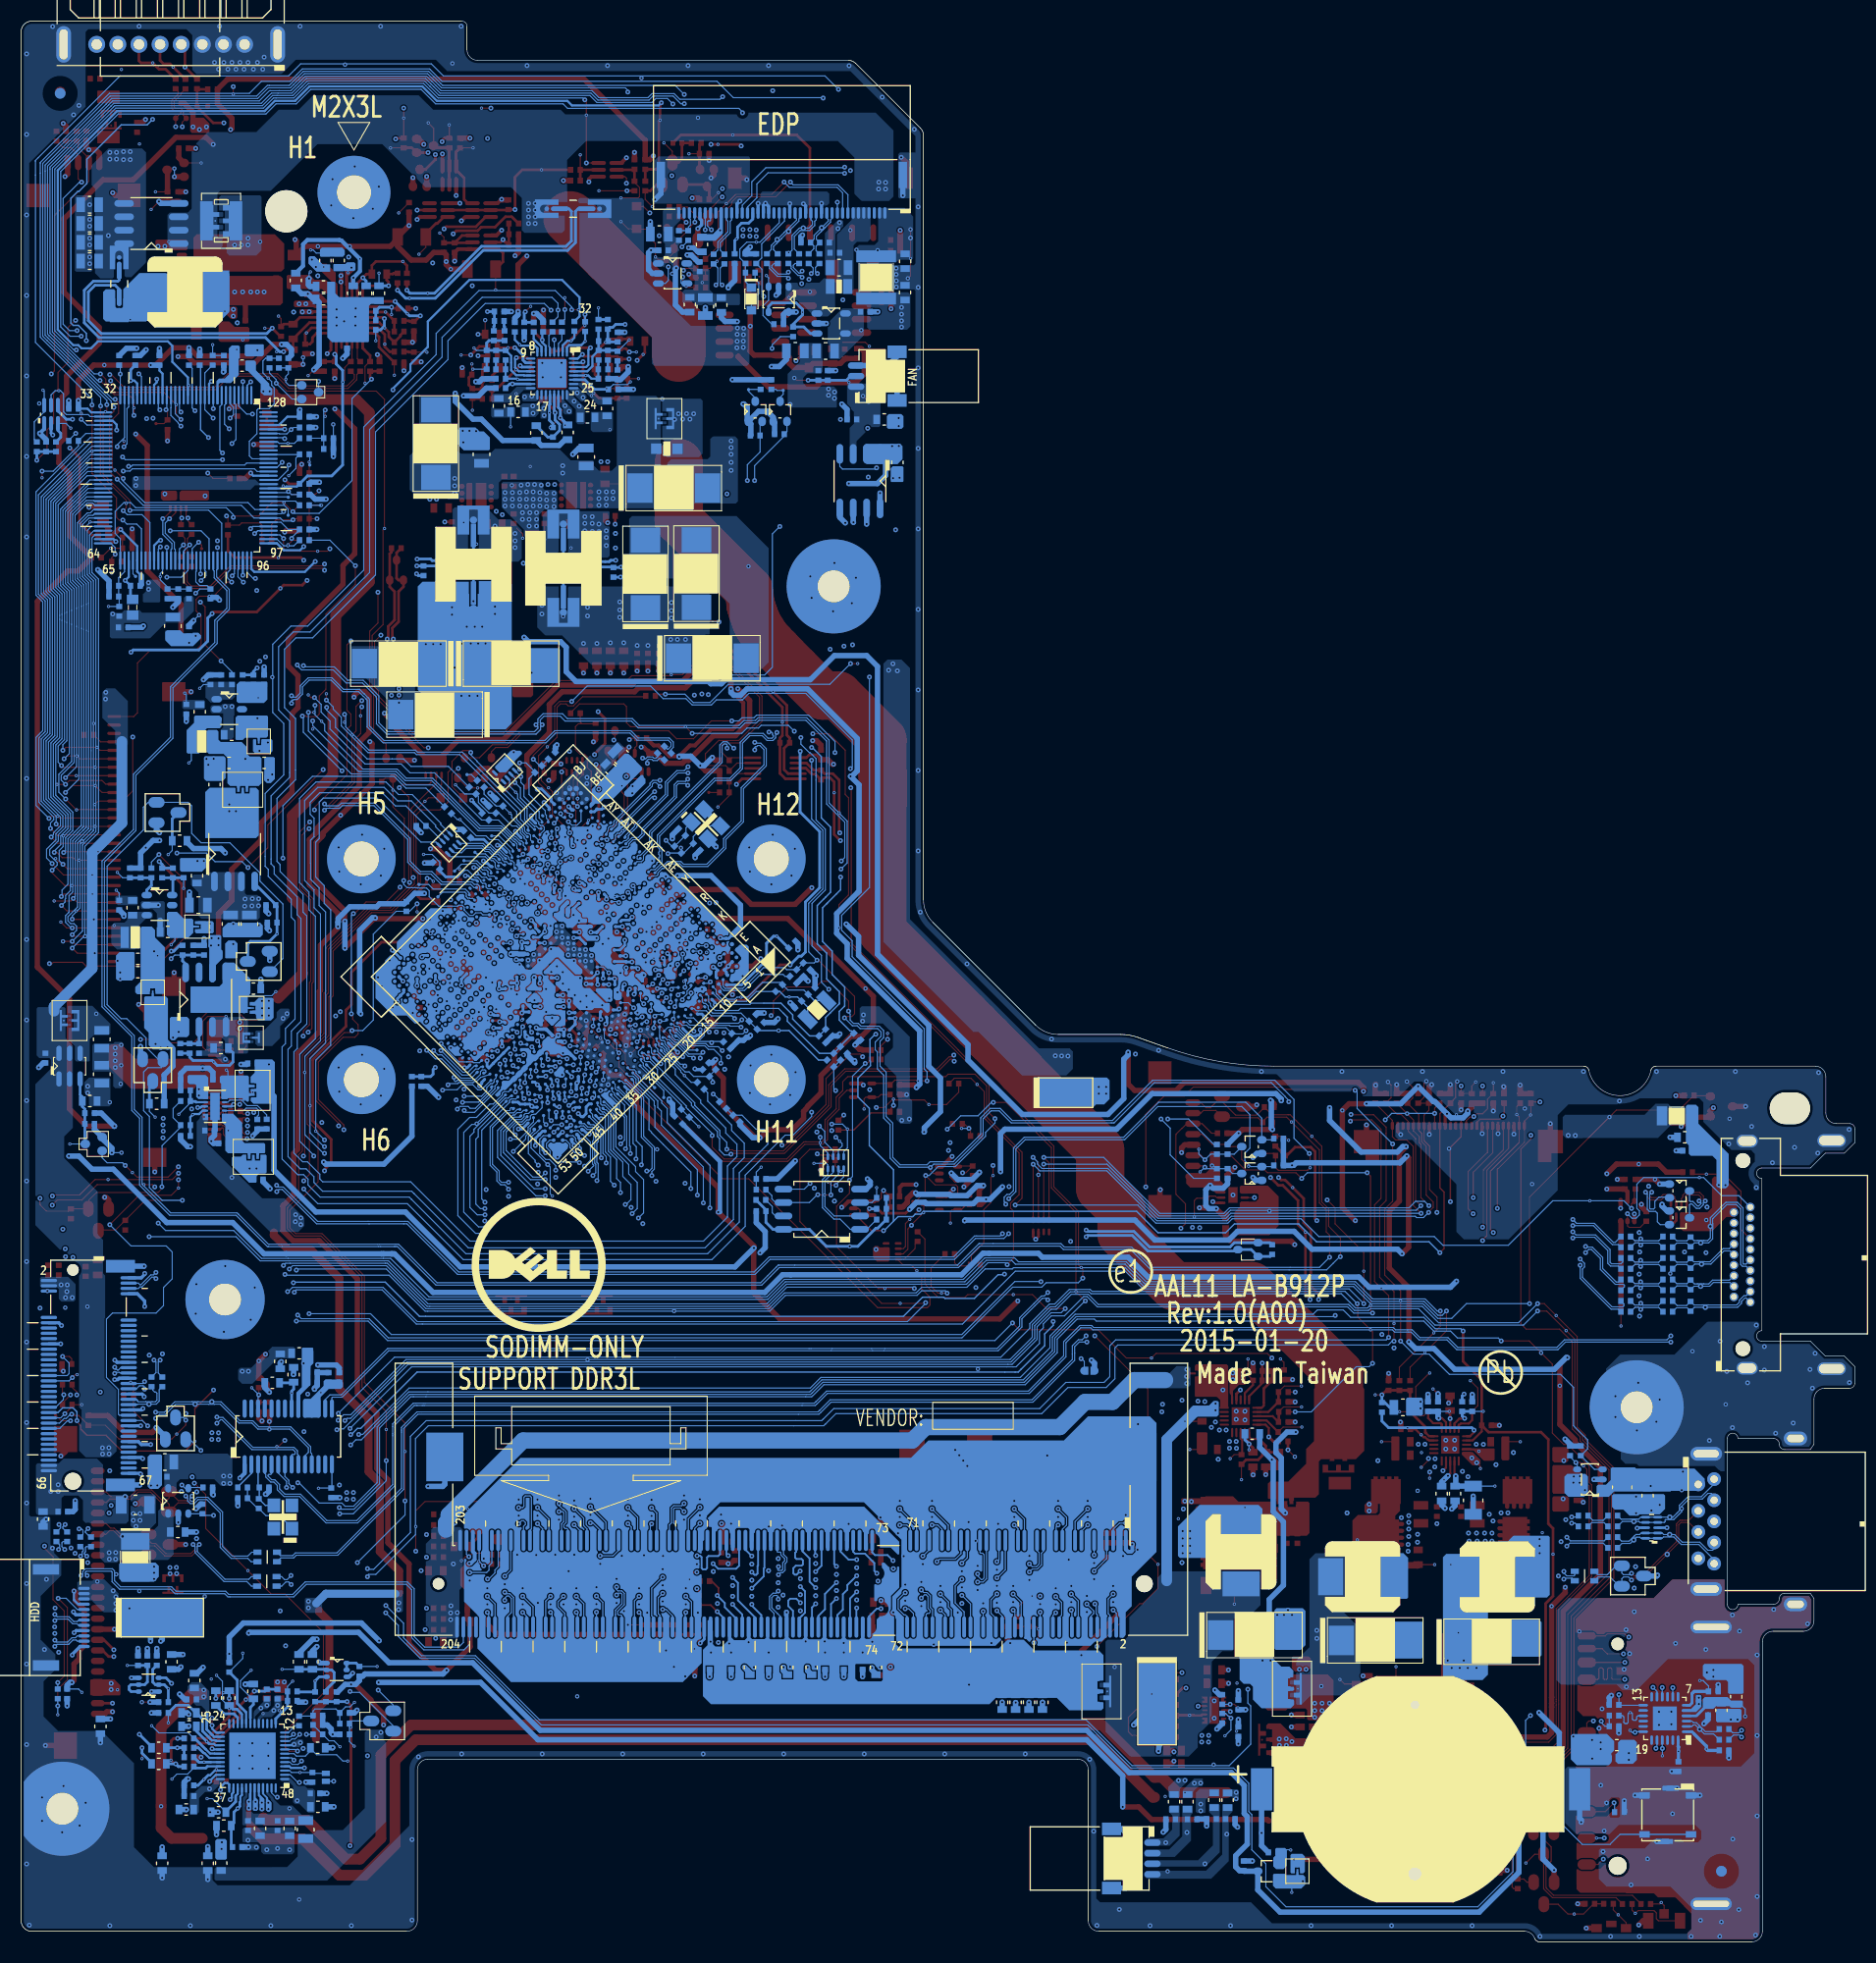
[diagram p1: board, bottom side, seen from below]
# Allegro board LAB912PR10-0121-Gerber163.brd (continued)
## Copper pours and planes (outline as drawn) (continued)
GND on TOP (solid shape): outline of 92 points within 117.23,94.67 126.57,101.72
GND on TOP (solid shape): outline of 1214 points within 4.12,0.25 26.42,34.31
GND on BOTTOM (solid shape): 13.14,21.93 13.14,20.91 13.01,20.79 10.98,20.79 10.72,21.04 10.72,21.93 10.85,22.06 13.01,22.06
GND on BOTTOM (solid shape): 34.03,30.18 34.03,27.2 33.84,27.01 29.77,27.01 29.65,27.14 29.65,30.25 29.9,30.5 33.71,30.5
GND on BOTTOM (solid shape): 42.47,51.39 42.47,49.87 42.41,49.8 41.01,49.8 40.89,49.93 40.89,51.39 41.01,51.52 42.35,51.52
GND on BOTTOM (solid shape): 54.92,31.39 54.92,27.77 54.79,27.64 52.44,27.64 52,28.09 52,31.33 52.25,31.58 54.73,31.58
GND on BOTTOM (solid shape): 91.24,139.48 91.24,138.23 91.19,138.18 90.12,138.18 90.05,138.25 90.05,139.57 90.15,139.67 91.05,139.67
GND on BOTTOM (solid shape): 91.61,144.41 91.61,143.34 91.48,143.21 90.23,143.21 90.05,143.39 90.05,144.41 90.25,144.61 91.41,144.61
GND on BOTTOM (solid shape): 158.51,102.51 158.51,101.43 158.38,101.29 156.44,101.29 156.06,101.67 156.06,102.5 156.15,102.59 158.44,102.59
GND on BOTTOM (solid shape): 161.58,45.91 161.58,43.1 161.35,42.87 160.58,42.87 160.22,43.24 160.22,46.02 160.33,46.13 161.35,46.13
GND on BOTTOM (solid shape): 164.27,35.77 164.27,34.37 163.98,34.09 161,34.09 160.52,34.56 160.52,35.58 160.84,35.9 164.14,35.9
GND on BOTTOM (solid shape): 164.57,93.35 164.57,91.16 164.41,90.99 163.06,90.99 162.81,91.24 162.81,93.61 162.9,93.7 164.23,93.7
GND on BOTTOM (solid shape): 154.23,94.49 154.23,93.15 154.18,93.1 153.17,93.1 153.07,93.2 153.07,94.5 153.35,94.78 153.94,94.78
GND on BOTTOM (solid shape): 22.41,18.88 22.41,17.99 22.66,17.74 22.66,17.1 22.41,16.85 21.01,16.85 20.63,17.23 20.63,18.88 20.88,19.13 22.15,19.13
GND on BOTTOM (solid shape): 45.33,30.06 45.33,27.01 45.14,26.82 41.01,26.82 40.82,27.01 40.82,30.18 40.95,30.31 45.08,30.31
GND on BOTTOM (solid shape): 77.72,81.3 77.72,79.14 77.59,79.01 72.07,79.01 71.81,79.27 71.05,79.27 70.54,79.78 70.54,81.55 70.8,81.81 77.21,81.81
GND on BOTTOM (solid shape): 150.54,112.06 150.54,110.42 150.55,110.41 150.55,109.94 150.3,109.69 149.92,109.69 149.54,110.07 149.54,112.03 149.65,112.15 150.45,112.15
GND on BOTTOM (solid shape): 126.71,122.23 126.71,119.58 126.28,119.15 122.68,119.15 122.55,119.27 122.55,122.32 122.68,122.45 126.5,122.45
GND on BOTTOM (solid shape): 154.1,96.35 154.11,96.35 154.49,95.97 154.49,95.21 154.36,95.08 150.93,95.08 150.68,95.33 150.68,96.22 150.69,96.22 150.93,96.46 153.98,96.46
GND on BOTTOM (solid shape): 156.24,112.12 156.24,110.09 156.03,109.88 154.47,109.88 154.2,110.16 154.2,111.98 154.21,112 154.21,112.07 154.36,112.23 156.14,112.23
GND on BOTTOM (solid shape): 22.98,42.25 22.98,41.17 22.73,40.91 21.9,40.91 21.33,40.34 20.5,40.34 20.38,40.47 18.47,40.47 17.96,40.98 17.96,42.25 18.09,42.38 22.85,42.38
GND on BOTTOM (solid shape): 159.48,87.42 159.48,85.5 159.31,85.34 159.01,85.34 158.71,85.64 157.85,85.64 157.66,85.83 157.66,87.36 157.85,87.55 159.35,87.55
GND on BOTTOM (solid shape): 144.57,151.86 144.13,151.42 140.7,151.42 140.63,151.48 140.63,154.85 140.44,155.04 139.24,155.04 139.24,155.67 143.45,155.67 143.82,156.04 143.82,157.06 143.9,157.13 144.57,157.13
GND on BOTTOM (solid shape): 132.2,143.15 132.2,141.72 131.66,141.18 129.28,141.18 129.18,141.28 129.18,142.39 129.76,142.96 130.17,142.96 130.55,143.34 132.01,143.34
GND on BOTTOM (solid shape): 126,86.22 126,85.59 125.68,85.26 125.04,85.26 125.01,85.3 125,85.36 124.98,85.4 124.98,85.6 125.08,85.71 125.41,85.71 125.72,86.01 125.72,86.26 125.74,86.28 125.94,86.28
GND on BOTTOM (solid shape): 122.92,75.68 123.13,75.57 123.35,75.64 123.42,75.67 123.48,75.64 123.65,75.47 123.65,75.26 123.53,75.13 123.53,75.1 123.33,74.91 123.33,74.88 123.26,74.8 123.26,74.38 122.94,74.06 122.75,74.06 122.4,74.41 122.4,74.52 121.82,75.1 121.82,75.17 121.81,75.22 121.79,75.28 121.79,75.46 121.97,75.64 122.03,75.67 122.1,75.64 122.32,75.57 122.53,75.68
GND on BOTTOM (solid shape): 116.67,106.22 116.7,106.23 116.74,106.22 117.05,105.9 117.05,105.62 117.44,105.23 117.44,105.22 117.58,105.07 117.78,105.05 117.85,105.05 117.91,105 117.94,104.91 117.94,104.89 117.93,104.78 117.96,104.67 117.97,104.64 117.94,104.61 117.85,104.52 117.79,104.41 117.73,104.34 117.64,104.35 117.59,104.38 117.53,104.39 117.52,104.39 117.49,104.42 117.49,104.81 117.2,105.1 116.98,105.1 116.48,105.6 116.48,106.03
GND on BOTTOM (solid shape): 106.01,93.91 106.01,93.84 105.41,93.24 105.41,92.99 105.69,92.7 105.71,92.66 105.71,92.6 105.55,92.25 105.87,92.02 105.94,92 105.97,91.92 106.07,91.7 106.29,91.61 106.36,91.58 106.39,91.51 106.41,91.41 106.45,91.32 106.45,91.19 106.49,91.15 106.49,91 106.34,90.84 106.14,90.84 106.04,90.95 105.37,90.95 104.69,91.62 104.69,94.2 104.88,94.38 105.54,94.38
GND on BOTTOM (solid shape): 132.99,84.84 133.04,84.8 133.1,84.78 133.13,84.74 133.13,84.5 132.49,83.86 131.94,83.86 131.92,83.89 131.89,83.91 131.86,83.93 131.83,83.99 131.87,84.03 132.09,84.21 132.02,84.49 131.99,84.58 132.05,84.65 132.12,84.7 132.17,84.77 132.24,84.82 132.33,84.8 132.55,84.71 132.75,84.84 132.77,84.87 132.96,84.87
GND on BOTTOM (solid shape): 125.02,40.84 125.08,40.75 125.08,39.93 125.02,39.84 124.91,39.85 124.5,39.89 124.33,39.51 124.33,39.49 124.32,39.47 124.02,39.17 124.02,39.1 124.02,39.08 123.97,39.03 123.9,39 123.82,39.03 123.78,39.08 123.78,39.1 123.78,39.95 124.58,40.75 124.6,40.76 124.62,40.75 124.77,40.76 124.91,40.83
GND on BOTTOM (solid shape): 117.9,80.62 117.97,80.56 118.11,80.43 118.3,80.43 118.31,80.44 118.36,80.44 118.4,80.41 118.41,80.4 118.49,80.31 118.6,80.25 118.66,80.2 118.67,80.13 118.65,80.09 118.31,79.75 118.3,79.75 118.21,79.69 118.16,79.6 118.15,79.59 117.36,78.8 117.16,78.8 117.07,78.89 117.07,79.24 117.76,79.92 117.77,79.93 117.98,80.17 117.81,80.44 117.78,80.45 117.78,80.57 117.81,80.59
GND on BOTTOM (solid shape): 115.33,88.72 115.33,88.65 115.32,88.64 115.25,88.3 115.49,88.06 115.53,88.04 115.56,88.01 115.54,87.94 115.53,87.86 115.5,87.84 115.46,87.83 115.31,87.69 115.07,87.69 115.06,87.71 114.91,87.86 114.7,87.88 114.49,87.86 114.32,87.72 114.27,87.6 114.27,87.47 114.26,87.44 114.24,87.42 114.17,87.39 114.11,87.35 114.1,87.33 114.02,87.33 113.92,87.43 113.92,87.52 113.94,87.59 113.93,87.67 113.95,87.74 114.02,87.78 114.25,87.9 114.34,88.15 114.33,88.21 114.31,88.27 114.31,88.36 114.4,88.44 114.52,88.44 114.53,88.44 114.84,88.51 114.98,88.8 115,88.83 115.22,88.83
GND on BOTTOM (solid shape): 109.17,90.49 109.19,90.48 109.21,90.47 109.42,90.34 109.65,90.37 109.66,90.38 109.73,90.38 109.91,90.2 109.94,90.12 109.91,90.05 109.82,89.78 109.98,89.53 109.99,89.53 110.1,89.41 110.1,89.39 110.24,89.11 110.54,89.13 110.59,89.11 110.62,89.07 110.7,88.95 110.82,88.87 111.02,88.83 111.2,88.91 111.29,88.81 111.29,88.53 111.19,88.43 110.84,88.43 110.65,88.51 110.46,88.43 110.32,88.43 110.31,88.46 110.15,88.6 109.93,88.58 109.9,88.56 109.59,88.86 109.61,88.9 109.63,89.12 109.47,89.28 109.46,89.29 109.46,89.43 109.47,89.81 109.09,89.8 108.95,89.8 108.94,89.83 108.84,89.94 108.7,89.99 108.67,90 108.65,90.04 108.65,90.26 108.86,90.47 108.89,90.46 108.99,90.46 109.08,90.48 109.09,90.49
GND on BOTTOM (solid shape): outline of 149 points within 120.94,79.99 128.71,86.07
GND on BOTTOM (solid shape): outline of 6329 points within 66.1,24.6 131.63,49.74
GND on BOTTOM (solid shape): outline of 13449 points within 106.4,83.38 140.01,105.93
GND on TOP: 58.44,48.42 58.44,48.59 58.48,48.63 58.59,48.63 58.62,48.6 58.62,47.7 58.81,47.51 58.81,46.58 58.71,46.48 58.4,46.48 58.3,46.58 58.3,47.52 58.45,47.66 58.45,48.42
GND on TOP: 108.85,94.58 108.77,94.66 108.77,95.3 108.54,95.52 108.4,95.52 108.34,95.59 108.34,97.35 108.04,97.65 107.65,97.65 107.45,97.85 107.45,98.63 107.58,98.76 108.42,98.76 109.05,98.12 109.05,95.9 109.43,95.52 109.43,94.67 109.33,94.57 108.91,94.57
GND on TOP: 135.5,40.85 134.23,40.85 134.11,40.72 134.11,27.96 134.3,27.77 135.57,27.77 136.26,28.47 136.26,36.47 135.88,36.85 135.88,40.47
GND on TOP: 87.53,45.9 92.64,40.79 92.64,33.74 92.45,33.55 92.45,29.17 89.66,26.37 74.8,26.37 69.97,31.2 69.97,34.06 70.61,34.69 70.61,35.71 70.8,35.9 71.56,35.9 71.75,36.09 71.75,38.25 71.62,38.37 67.68,38.37 67.43,38.63 67.43,52.22 72.51,57.3 92.07,57.3 92.13,57.23 102.23,57.23 105.97,60.98 105.97,65.74 108.13,67.9 108.13,70.95 113.85,76.67 116.71,76.67 117.4,75.97 117.4,74.63 114.8,72.03 114.8,60.92 103.24,49.36 88.13,49.36 87.53,48.76 ; 2 cut-outs
GND on TOP: 129.22,141.18 130.61,141.18 130.87,141.44 131.88,141.44 132.01,141.56 132.01,143.09 131.76,143.34 129.47,143.34 129.09,142.96 129.09,141.31
GND on TOP: 129.8,93.3 129.72,93.3 129.34,93.68 129.34,93.81 129.47,93.94 129.47,94.12 127.57,96.02 127.35,96.02 126.97,96.12 126.76,95.79 126.76,95.77 126.47,95.47 126.42,95.44 126.39,95.4 126.22,95.23 126,95.23 125.44,95.79 125.44,95.89 125.86,96.31 126.03,96.31 128.16,98.44 129.82,98.44 130.93,99.55 130.93,99.55 131.17,99.55 131.5,99.22 131.5,97.56 131.76,97.3 132.45,97.3 132.58,97.43 132.58,98.13 132.64,98.19 133.47,98.19 134.23,97.43 134.93,97.43 135.12,97.24 135.12,96.48 134.99,96.35 134.75,96.35 133.51,95.11 131.6,95.11 ; 1 cut-out
GND on TOP: outline of 327 points within 0.25,0.25 173.3,181.55 ; 1 cut-out
GND on TOP: 58.16,51.71 58.1,51.71 58.03,51.65 58.03,50.82 57.97,50.76 57.27,50.76 57.21,50.69 57.21,48.98 57.33,48.85 58.98,48.85 59.05,48.92 59.05,50.57 58.92,50.69 58.29,50.69 58.22,50.76 58.22,51.65
GND on TOP: 12.37,44.53 12.34,44.55 12.32,44.58 12.32,47.65 11.72,48.39 10.87,47.94 10.85,47.91 10.83,47.9 7.7,47.9 7.13,47.67 6.82,46.93 6.65,46.85 4.38,46.85 4.35,46.86 4.34,46.88 4.12,47.18 4.12,51.4 3.76,52.29 2.87,52.65 0.5,52.65 0.33,52.73 0.25,52.9 0.25,54.34 1.11,55.2 2.9,55.2 4.31,56.6 8.8,56.6 9.54,57.2 9.09,58.05 9.06,58.07 9.05,58.1 9.05,58.55 9.2,58.69 12.63,58.69 13.01,59.08 13.01,65.87 13.84,66.7 18.85,66.7 19.49,66.06 19.49,58.69 20.5,57.68 21.14,57.68 22.22,56.6 22.22,55.58 23.55,54.25 23.55,47.77 22.15,46.38 22.15,45.68 22.6,45.23 22.6,37.87 22.09,37.36 18.03,37.36 17.58,37.81 17.58,44.81 16.92,45.47 13.7,45.47 12.88,44.66 12.83,44.66 12.7,44.53
GND on TOP: 52.57,38.12 52.38,37.93 52.38,34.63 53.14,33.87 56.76,33.87 56.89,33.99 56.89,36.03 57.02,36.15 59.43,36.15 59.49,36.22 59.49,37.99 59.37,38.12
GND on TOP: 128.9,43.01 109.47,43.01 108.83,42.38 108.83,37.55 109.4,36.98 110.99,36.98 111.25,36.72 111.25,34.37 109.98,33.1 109.98,31.58 109.83,31.44 108.83,31.44 108.83,29.74 108.96,29.61 110.67,29.61 110.8,29.74 110.8,30.25 111.44,30.88 130.49,30.88 130.68,31.07 130.68,34.12 129.91,34.88 128.77,34.88 128.52,35.14 128.52,36.98 128.83,37.3 128.83,38.63 128.52,38.95 127.56,38.95 127.12,39.39 127.12,40.47 127.69,41.04 128.64,41.04 129.03,41.42 129.03,42.88
GND on TOP: 129.15,138.2 129.34,138.01 129.34,136.29 129.22,136.16 128.64,136.16 127.37,134.89 126.74,134.89 126.36,134.51 126.36,133.7 125.65,132.99 124.64,132.99 124.52,133.12 124.52,134.77 124.39,134.89 122.93,134.89 122.1,135.72 122.1,137.31 122.29,137.5 123.82,137.5 124.07,137.75 124.07,138.13 124.14,138.2
GND on TOP: 162.05,31.07 160.33,31.07 159.82,30.56 146.55,30.56 145.15,29.17 145.15,25.29 145.47,24.98 147.31,24.98 148.77,26.44 155.38,26.44 155.82,26.88 162.43,26.88 163.44,27.9 163.44,30.44 163,30.88 162.24,30.88
GND on TOP: 45.14,24.98 44.44,24.98 44.32,24.85 44.32,22.82 44.06,22.56 44.06,21.86 44.19,21.74 46.22,21.74 46.35,21.86 46.35,22.44 46.22,22.56 45.4,22.56 45.21,22.75 45.21,24.91
GND on TOP: 61.08,51.46 62.35,51.46 62.54,51.27 62.54,50 62.48,49.93 61.02,49.93 60.95,50 60.95,51.33
GND on TOP: 139.82,122.32 137.47,122.32 137.28,122.13 137.28,119.21 137.6,118.89 140.07,118.89 140.07,122.07
GND on TOP: 35.49,40.6 42.92,40.6 43.24,40.28 43.24,38.06 43.17,37.99 42.03,37.99 41.84,37.8 41.84,36.79 41.71,36.66 33.58,36.66 33.08,37.17 33.08,39.01 33.08,39.02 33.08,39.18 33.25,39.35 34.25,39.35
GND on TOP: 106.18,162.4 106.5,162.09 106.5,159.96 107.26,159.2 107.26,158.07 108.39,156.94 108.96,156.94 109.06,156.84 109.06,156.24 108.63,155.81 104.13,155.81 104.03,155.91 104.03,156.64 104.04,156.65 104.59,156.65 104.59,157.41 104.03,157.41 104.03,157.86 104.58,157.86 104.58,158.61 104.04,158.61 104.04,159.29 103.66,159.67 103.66,162.28 103.79,162.4
GND on BOTTOM: 88.61,169.36 90.38,169.36 90.54,169.2 90.54,165.13 90.43,165.02 88.61,165.02 88.44,165.2 88.44,169.18
GND on BOTTOM: 103.82,120.1 102.8,121.12 102.8,131.91 105.85,134.96 115.73,134.96 116.01,134.68 116.01,129.46 115.6,129.05 108.9,129.05 106.48,126.64 106.48,123.5 106.75,123.24 106.75,120.87 105.97,120.1
GND on BOTTOM: 127.95,138.2 124.33,138.2 124.14,138.01 124.14,137.56 124.01,137.43 122.99,137.43 122.8,137.24 122.8,135.66 122.87,135.59 124.01,135.59 124.52,135.09 124.52,133.05 124.58,132.99 125.85,132.99 125.98,133.12 125.98,133.69 128.07,135.78 128.07,138.07
GND on BOTTOM: 154.49,117.18 153.47,117.18 153.36,117.07 153.36,116.09 153.43,116.02 153.43,114.02 153.64,113.82 154.59,113.82 154.66,113.89 154.66,114.72 154.42,114.96 154.42,116.29 155.5,116.29 155.63,116.42 155.63,116.92 155.5,117.05 154.62,117.05
GND on BOTTOM: 12.37,44.53 12.34,44.55 12.32,44.58 12.32,47.65 11.72,48.39 10.87,47.94 10.85,47.91 10.83,47.9 7.7,47.9 7.13,47.67 6.82,46.93 6.65,46.85 4.38,46.85 4.35,46.86 4.34,46.88 4.12,47.18 4.12,51.4 3.76,52.29 2.87,52.65 0.5,52.65 0.33,52.73 0.25,52.9 0.25,54.34 1.11,55.2 2.9,55.2 4.31,56.6 8.8,56.6 9.54,57.2 9.09,58.05 9.06,58.07 9.05,58.1 9.05,58.55 9.2,58.69 13.96,58.69 17.07,55.58 22.22,55.58 23.55,54.25 23.55,47.77 22.15,46.38 22.15,45.68 21.73,45.25 20.88,45.25 20.87,45.25 20.66,45.25 20.45,45.04 13.26,45.04 12.88,44.66 12.83,44.66 12.7,44.53
GND on BOTTOM: 97.28,165.68 103.38,165.68 103.59,165.48 103.59,165.13 104.03,164.69 104.03,164.43 103.94,164.35 97.28,164.35 97.06,164.56 97.06,165.46
GND on BOTTOM: 97.48,157.81 97.4,157.73 96.5,157.73 96.44,157.79 96.44,161.67 95.74,162.36 95.74,162.87 95.85,162.99 96.22,162.99 97.48,161.73
GND on BOTTOM: 89.39,158.71 92.13,158.71 92.27,158.57 92.27,156.8 91.88,156.41 89.49,156.41 89.36,156.54 89.36,158.68
GND on BOTTOM: 168.33,165.31 167.06,165.31 166.81,165.06 166.81,158.2 166.93,158.07 168.33,158.07 168.46,158.2 168.46,165.18
GND on BOTTOM: 104.68,168.99 113.23,168.99 113.81,168.41 113.81,164.63 113.71,164.52 105.4,164.52 104.58,165.35 104.58,168.89
GND on BOTTOM: 165.22,81.81 167.13,81.81 167.57,81.36 167.57,80.41 167.13,79.97 167.13,79.21 167,79.08 165.22,79.08 165.09,79.21 165.09,81.68
GND on BOTTOM: 162.11,98.51 160.08,98.51 159.95,98.38 159.95,95.21 160.08,95.08 160.58,95.08 160.71,95.21 160.71,97.37 161.09,97.75 162.11,97.75 162.24,97.87 162.24,98.38
GND on BOTTOM: 105.72,136.33 105.72,142.25 105.96,142.49 108.08,142.49 108.34,142.24 108.34,140.58 108.58,140.34 112.02,140.34 112.39,139.97 112.39,136.39 112.13,136.14 105.91,136.14
GND on BOTTOM: outline of 267 points within 0.25,0.25 173.3,181.55 ; 1 cut-out
GND on BOTTOM: 135.82,146.36 132.96,146.36 132.84,146.23 132.84,142.42 133.03,142.23 135.69,142.23 135.88,142.42 135.88,146.29
GND on BOTTOM: 155.95,85.26 154.53,85.26 154.41,85.15 154.41,84.07 153.87,83.52 153.87,83.23 153.92,83.18 154.53,83.18 155.22,83.87 156.9,83.87 156.97,83.93 156.97,84.31 156.9,84.37 156.2,84.37 156.01,84.56 156.01,85.2
GND on BOTTOM: 120.93,107.87 120.86,107.8 120.84,107.79 120.71,107.74 120.61,107.63 120.59,107.6 120.26,107.6 120.19,107.64 120.12,107.67 120.11,107.67 119.65,108.13 119.65,109.23 117.54,111.33 117.54,111.61 116.39,112.76 116.39,112.99 116.97,113.56 117.15,113.56 117.4,113.3 118.67,113.3 119.32,112.65 119.37,112.65 123.18,108.84 123.18,108.33 123.18,108.29 122.77,107.88 122.44,107.88 122.43,107.91 122.32,108.05 122.15,108.1 122.07,108.13 122.04,108.2 121.75,108.53 121.43,108.22 121.4,108.14 121.33,108.12 121.3,108.12 121.22,108.14 121.19,108.22 120.68,108.45 120.86,107.92 120.88,107.92
GND on BOTTOM: 142.23,122.64 136.52,122.64 136.26,122.39 136.26,118.19 135.57,117.5 135.57,115.02 135.88,114.7 138.8,114.7 138.87,114.77 138.87,117.56 140.9,119.59 142.23,119.59 142.36,119.72 142.36,122.51
GND on BOTTOM: 152.46,10.83 147.88,10.83 147.68,10.63 147.68,8.49 147.88,8.29 150.6,8.29 150.83,8.52 150.83,9.13 151.12,9.42 152.53,9.42 152.61,9.49 152.61,10.68
GND on BOTTOM: outline of 232 points within 113.61,80.85 121,88.09
GND on VCC: outline of 117 points within 0.26,0.26 173.3,181.55 ; 2 cut-outs
GND on IN1: 127.5,138.2 128.07,137.63 128.07,135.59 127.37,134.89 126.74,134.89 126.36,134.51 126.36,133.43 125.91,132.99 124.64,132.99 124.52,133.12 124.52,134.77 124.39,134.89 123.25,134.89 122.74,135.4 122.74,137.37 122.87,137.5 123.82,137.5 124.07,137.75 124.07,138.13 124.14,138.2
GND on IN1: outline of 233 points within 0.25,0.25 173.3,181.55
GND on IN2: 76.07,53.3 66.41,53.3 65.27,52.15 65.27,50.06 66.22,49.11 66.22,31.26 66.99,30.5 75.75,30.5 76.38,31.14 76.38,52.98
GND on IN2: 149.6,19.64 153.41,19.64 153.6,19.45 153.6,16.66 153.98,16.28 155.5,16.28 156.27,15.51 158.3,15.51 158.62,15.2 158.62,12.15 158.3,11.83 157.28,11.83 156.65,12.47 156.65,12.85 156.14,13.36 155,13.36 153.92,14.44 153.92,14.69 153.22,15.39 149.79,15.39 149.41,15.77 149.41,19.45
GND on IN2: outline of 236 points within 0.25,0.25 173.3,181.55
GND on IN2: 147.95,26.56 147.5,27.01 147.5,31.9 151.76,36.15 151.76,42.31 151.69,42.38 151.69,44.47 152.46,45.23 154.55,45.23 156.77,43.01 157.54,43.01 159,44.47 162.36,44.47 165.47,41.36 165.47,40.47 165.28,40.28 165.09,40.28 164.27,41.11 161.6,41.11 161.16,40.66 161.16,33.49 162.87,31.77 162.87,27.96 161.85,26.94 155.7,26.94 155.31,26.56 ; 1 cut-out
GND on GND: outline of 117 points within 0.26,0.26 173.3,181.55 ; 1 cut-out
GNDA on VCC: 153.45,7.7 153.09,8.06 153.09,12.13 152.58,12.64 152.58,14.71 152.69,14.82 152.99,14.82 153.35,14.46 153.35,14.2 154.76,12.78 155.91,12.78 156.14,12.55 156.14,12.17 157.05,11.26 158.53,11.26 159.19,11.92 159.19,15.43 158.53,16.09 156.5,16.09 155.74,16.85 154.21,16.85 154.11,16.95 154.11,19.75 153.71,20.15 149.51,20.15 148.14,21.53 148.14,24.74 149.13,25.74 155.61,25.74 156.12,26.25 162.6,26.25 164.14,27.79 164.14,30.08 164.63,30.56 166.45,30.56 166.55,30.46 166.55,27.79 167.06,27.28 167.06,21.27 166.83,21.04 166.07,21.04 162.24,17.21 162.24,9.08 160.86,7.7
GNDA on IN1: 164.65,30.44 166.43,30.44 166.55,30.31 166.55,27.77 167.06,27.26 167.06,21.29 166.81,21.04 165.92,21.04 162.11,17.23 162.11,8.97 160.84,7.7 153.6,7.7 153.09,8.21 153.09,12.28 152.58,12.78 152.58,14.69 152.71,14.82 152.96,14.82 153.35,14.44 153.35,14.18 154.74,12.78 155.89,12.78 156.14,12.53 156.14,12.15 157.03,11.26 158.55,11.26 159.19,11.9 159.19,15.58 158.68,16.09 156.52,16.09 155.76,16.85 154.36,16.85 154.11,17.1 154.11,19.9 153.73,20.28 149.54,20.28 148.27,21.55 148.27,24.85 149.15,25.74 155.63,25.74 156.14,26.25 162.62,26.25 164.14,27.77 164.14,29.93
GNDA on IN2: 167.06,21.29 166.81,21.04 165.92,21.04 162.11,17.23 162.11,8.97 160.84,7.7 153.6,7.7 153.09,8.21 153.09,12.28 152.58,12.78 152.58,14.69 152.71,14.82 152.96,14.82 153.35,14.44 153.35,14.18 154.74,12.78 155.89,12.78 156.14,12.53 156.14,12.15 157.03,11.26 158.55,11.26 159.19,11.9 159.19,15.58 158.68,16.09 156.52,16.09 155.76,16.85 154.36,16.85 154.11,17.1 154.11,19.9 153.73,20.28 149.54,20.28 148.27,21.55 148.27,24.85 149.15,25.74 155.63,25.74 156.14,26.25 162.62,26.25 164.14,27.77 164.14,27.77 164.14,30.08 164.63,30.56 166.45,30.56 166.55,30.46 166.55,27.78 167.06,27.27
GNDA on GND: 153.45,7.7 153.09,8.06 153.09,12.13 152.58,12.64 152.58,14.71 152.69,14.82 152.99,14.82 153.35,14.46 153.35,14.2 154.76,12.78 155.91,12.78 156.14,12.55 156.14,12.17 157.05,11.26 158.53,11.26 159.19,11.92 159.19,15.43 158.53,16.09 156.5,16.09 155.74,16.85 154.21,16.85 154.11,16.95 154.11,19.75 153.71,20.15 149.51,20.15 148.14,21.53 148.14,24.74 149.13,25.74 155.61,25.74 156.12,26.25 162.6,26.25 164.14,27.79 164.14,30.08 164.63,30.56 166.45,30.56 166.55,30.46 166.55,27.79 167.06,27.28 167.06,21.27 166.83,21.04 166.07,21.04 162.24,17.21 162.24,9.08 160.86,7.7
V1 on TOP: 135.44,167.34 134.04,167.34 133.91,167.22 133.53,167.22 133.41,167.09 133.41,165.69 134.17,164.93 134.17,164.42 134.3,164.3 137.09,164.3 137.22,164.42 137.22,165.31 136.96,165.57 135.82,165.57 135.69,165.69 135.69,167.09
VDDP_LDO on TOP (solid shape): 146.86,156.18 146.86,155.8 146.73,155.67 145.97,155.67 145.71,155.42 145.71,155.23 145.65,155.16 144.63,155.16 144.57,155.23 144.57,155.35 145.46,156.24 146.79,156.24
VIN on TOP: 91.87,156.76 94.94,156.76 95.62,157.45 95.62,159.1 95.79,159.27 97.62,159.27 97.72,159.16 97.72,156.84 96.28,155.41 96.28,152.51 95.57,151.8 92.34,151.8 91.85,152.28 91.85,156.75
+CHGRTC on BOTTOM (solid shape): 52.85,6.87 52.85,6.36 52.88,6.33 53.82,6.33 53.94,6.44 54.97,6.44 55.06,6.36 55.06,6.2 55.07,6.2 55.07,5.31 54.81,5.05 52.39,5.05 52.02,5.41 52.02,6.15 52.21,6.33 52.63,6.33 52.67,6.38 52.67,6.46 52.67,6.46 52.67,6.87 52.69,6.89 52.83,6.89
+FAN_POWER on BOTTOM: 95.23,147.49 95.38,147.34 95.38,145.46 94.74,144.81 94.74,143.7 95.14,143.29 95.14,140.08 94.95,139.89 94.62,139.89 94.48,140.03 94.48,142.04 93.15,143.38 92.36,143.38 92.22,143.52 92.22,146.95 92.54,147.26 92.54,147.28 92.75,147.49
+INV_PWR_SRC on BOTTOM: 92.36,164.13 89.95,164.13 89.12,163.3 89.12,159.35 89.26,159.22 90.48,159.22 90.75,158.95 94.44,158.95 94.54,159.05 94.54,160.32 94.25,160.61 92.78,160.61 92.45,160.94 92.45,164.04
+LCDVDD on BOTTOM: 96.75,157.45 97.59,157.45 98,157.04 101.06,157.04 101.2,156.9 101.2,155.35 100.84,155 99.64,155 98.48,153.84 97.19,153.84 96.51,154.52 96.51,157.21
+LCDVDD_CONN on BOTTOM: 93.25,164.19 94.86,164.19 94.95,164.1 94.95,162.99 96.35,161.59 96.35,156.18 96.15,155.98 94.91,155.98 94.76,156.13 94.76,160.59 94.43,160.92 93.43,160.92 93.15,161.2 93.15,164.09
+RTCBATT_R on BOTTOM (solid shape): 54.84,8.8 54.84,8.16 55.04,7.96 55.04,7.16 54.77,6.89 54.08,6.89 53.76,7.21 53.76,8.71 53.93,8.89 54.76,8.89
+SOC_VCC on TOP (solid shape): 123.87,93.18 123.87,93.05 123.28,92.46 123.28,92.29 123.84,91.72 123.84,90.87 123.51,90.54 123.4,90.54 123.07,90.87 123.07,90.98 123.08,91 123.17,91.15 123.17,91.33 123.13,91.43 123.07,91.5 123.05,91.54 123.04,91.58 122.87,92.06 122.64,91.6 122.63,91.56 122.61,91.52 122.54,91.45 122.49,91.36 122.47,91.2 122.53,91.05 122.53,90.59 122.25,90.31 122.26,90.3 119.9,87.94 118.73,87.94 118.35,87.56 118.06,87.56 117.5,88.12 117.5,88.36 118.94,89.8 119.7,89.8 120.51,90.62 120.51,90.97 120.4,91.09 120.4,91.34 122.67,93.61 123.43,93.61
+SOC_VCC on BOTTOM (solid shape): 130.23,126.39 131.18,126.39 131.18,128.74 135.57,128.74 136.01,128.29 136.01,118.51 134.8,117.31 134.8,115.53 134.04,114.77 127.69,114.77 127.12,115.34 127.12,128.48 127.44,128.8 130.23,128.8
+SOC_VCC on BOTTOM (solid shape): 122.86,93.02 122.99,92.95 124.1,91.84 124.1,91.69 124.01,91.6 123.59,91.6 123.53,91.54 123.45,91.54 123.37,91.55 123.29,91.54 123.16,91.54 123.13,91.51 123.06,91.51 123.05,91.52 122.49,91.35 122.86,90.89 122.88,90.89 122.98,90.79 122.98,90.72 122.98,90.62 122.33,89.97 121.98,89.97 121.86,89.84 121.86,89.55 121.71,89.41 121.64,89.41 121.58,89.39 121.37,89.39 121.32,89.34 121.32,88.8 120.72,88.2 120.15,88.2 120.14,88.2 120.04,88.22 119.94,88.2 119.93,88.2 119.52,88.2 119.33,88.39 118.57,88.39 118.14,87.96 117.97,87.96 117.84,88.1 117.84,88.78 117.91,88.86 118.3,88.86 119.71,90.27 120.28,90.27 120.42,90.42 120.42,90.53 120.42,90.54 120.45,90.68 120.42,90.82 120.42,90.83 120.42,91.28 120.58,91.44 120.83,91.44 120.84,91.44 121.16,91.44 121.69,91.97 121.69,91.97 122.74,93.02
+SOC_VCC on TOP: 135.12,128.23 128.07,128.23 127.5,127.66 127.5,115.4 128.33,114.57 136.39,114.57 136.71,114.89 136.71,126.64
+SOC_VCC on VCC: 116.49,87.59 116.26,87.82 116.26,91.55 116.75,92.03 121.32,92.03 127.69,98.4 127.69,113.09 125.41,115.38 125.41,127.23 125.77,127.59 136.86,127.59 137.98,126.47 137.98,88.71 136.86,87.59
+SOC_VCC on IN1: 119.12,89.62 119.9,90.4 119.93,90.38 120.37,90.53 120.23,90.97 120.2,90.99 120.2,91.97 128.32,100.09 128.32,100.91 128.33,100.92 128.33,113.18 126.42,115.08 126.42,127.27 127.95,128.8 136.33,128.8 137.92,127.21 137.92,119.71 137.39,119.18 137.39,116.21 137.92,115.68 137.92,97.81 133.79,93.68 125.66,93.68 120.07,88.1 119.82,88.1 119.12,88.8
+SOC_VNN on TOP: 112.32,127.78 119.56,127.78 120.31,128.53 124.24,128.53 124.82,127.95 124.82,123.62 124.36,123.16 121.46,123.16 120.96,122.66 120.96,121.75 120.71,121.5 111.34,121.5 110.32,122.51 110.32,125.78
+SOC_VNN on TOP: 120.01,92.6 119.32,93.28 119.32,93.29 119.06,93.55 119.06,94.19 119.39,94.52 119.72,94.52 119.8,94.44 120.31,94.44 120.78,94.92 120.87,94.95 120.94,94.89 121.48,94.79 121.38,95.33 121.33,95.4 121.35,95.49 121.8,95.94 121.8,96.17 121.43,96.54 121.43,96.81 121.73,97.11 122.24,97.11 122.72,97.59 122.87,97.59 123.46,97.01 123.46,96.96 122.97,96.47 122.97,96.09 123.3,95.76 123.57,95.76 123.64,95.73 123.67,95.65 124.19,95.35 124.06,95.94 123.98,96.01 124.01,96.11 124.55,96.65 124.8,96.65 125.23,96.22 125.23,95.74 125.87,95.1 125.87,94.9 125.87,94.9 125.87,94.78 125.86,94.77 125.86,94.52 126.02,94.34 126.03,94.33 126.43,93.93 126.43,93.3 125.82,92.69 125.51,92.69 124.8,93.4 124.8,93.6 125.08,93.88 125.08,94.14 124.62,94.6 124.39,94.6 124.04,94.25 123.79,94.25 123.7,94.34 123.16,94.34 122.69,94.8 122.39,94.8 121.58,93.99 121.58,93.89 122.06,93.4 122.06,93.33 121.85,93.12 121.63,93.12 121.47,93.28 120.95,93.28 120.26,92.6
+SOC_VNN on BOTTOM: outline of 98 points within 119.31,91.55 125.82,96.37
+SOC_VNN on BOTTOM: 121.72,128.29 108.9,128.29 108.39,127.78 108.39,120.86 109.21,120.04 112.77,120.04 113.59,120.86 119.56,120.86 122.36,123.66 123.95,123.66 124.71,124.42 124.71,128.16 124.58,128.29 122.68,128.29 122.68,126 121.79,126 121.79,128.23
+SOC_VNN on VCC: 116.75,92.54 116.26,93.03 116.26,109.41 109.28,116.39 109.28,126.6 110.27,127.59 124.54,127.59 124.9,127.23 124.9,115.17 127.18,112.88 127.18,98.61 121.11,92.54
+SOC_VNN on IN1: 120.09,92.56 118.64,94 118.61,94.09 118.67,94.16 118.81,94.58 118.42,94.77 118.32,94.79 118.29,94.89 118.09,95.26 117.69,95.13 117.61,95.08 117.53,95.11 117.42,95.23 117.39,95.29 117.41,95.36 117.45,95.75 117.09,95.9 117,95.93 116.98,96.03 116.94,96.27 116.74,96.42 116.7,96.43 116.54,96.59 116.54,109.16 115.32,110.38 113.24,110.38 113.09,110.54 113.09,113.69 110.42,116.35 110.42,127.97 111.05,128.61 124.9,128.61 125.79,127.72 125.79,117.18 125.82,117.15 125.82,114.86 127.86,112.82 127.86,100.08 120.34,92.56
+V_TS on BOTTOM: 110.95,159.18 110.28,159.18 109.47,158.36 108.53,158.36 108.4,158.24 108.4,156.4 108.01,156 105.62,156 105.52,155.9 105.52,155.01 105.61,154.92 110.64,154.92 110.97,155.25 110.97,156.17 110.72,156.41 109.96,156.41 109.81,156.56 109.81,157.3 110,157.49 110,158.06 110.51,158.57 110.9,158.57 111.05,158.72 111.05,159.08
+VDISPLAY_VCC on TOP (solid shape): 13.53,72.22 13.53,69.47 13.94,69.05 16.48,69.05 16.56,68.98 16.56,67.58 16.26,67.28 13.49,67.28 12.16,68.61 11.41,68.61 11.14,68.88 11.14,71.07 12.52,72.45 13.3,72.45
+VDISPLAY_VCC on BOTTOM (solid shape): 15.99,79.08 15.99,75.67 15.72,75.39 15.72,74.6 15.53,74.41 13.48,74.41 13.09,74.01 13.09,71.64 12.79,71.33 12.21,71.33 11.94,71.6 11.94,74.58 14.81,77.44 14.81,79 15.04,79.23 15.85,79.23
ADPIN on TOP: 90.96,158.21 91.95,157.22 94.85,157.22 95.18,157.55 95.18,162.5 95.01,162.68 91.13,162.68 90.96,162.51
B+ on TOP (solid shape): 51.19,52.33 51.19,47.38 51.94,46.64 51.94,45.26 53.63,43.57 55.35,43.57 55.56,43.37 55.56,41.99 55.49,41.93 54.73,41.93 54.73,41.42 54.29,41.42 54.29,41.99 53.52,41.99 53.52,41.42 53.14,41.42 53.14,41.99 53.09,42.04 51.05,42.04 50.73,42.37 50.73,45.46 50.5,45.69 47.22,45.69 46.42,46.49 46.42,52.34 46.63,52.54 50.98,52.54
B+ on TOP: 108.77,149.69 108.77,138.07 108.77,138.07 108.77,135.8 109.22,135.36 113.69,135.36 113.85,135.52 113.85,149.94 113.59,150.2 109.28,150.2
B+ on TOP: 125.47,160.61 120.9,160.61 120.58,160.93 120.58,164.23 122.04,165.69 125.22,165.69 125.85,165.06 125.85,160.99
B+ on BOTTOM: 120.94,173.13 121.62,173.82 134.93,173.82 136.07,174.96 145.98,174.96 147.12,173.82 148.77,173.82 151.29,171.31 155.9,171.31 157.42,169.79 157.42,164.04 157.78,163.67 159.49,163.67 159.7,163.47 159.7,160.49 159.44,160.23 154.74,160.23 154.49,160.49 154.49,161.26 154.98,161.26 154.98,162.07 154.43,162.07 154.43,162.52 154.98,162.52 154.98,163.28 154.43,163.28 154.43,163.72 154.97,163.72 154.97,165.47 154.7,165.74 149.92,165.74 145.51,170.15 139.36,170.15 135.29,166.07 127.18,166.07 126.17,165.06 126.17,162.01 125.91,161.76 122.36,161.76 121.85,162.26 121.85,163.53 123.37,163.53 123.63,163.79 123.63,164.3 123.5,164.42 121.98,164.42 121.85,164.55 121.85,165.69 121.88,165.72 121.88,168.64 120.07,170.45 96.26,170.45 94.68,168.88 94.68,165.45 94.01,164.78 91.41,164.78 90.99,165.2 90.99,171.45 92.68,173.13
B+ on BOTTOM: 91.23,156.14 89.6,156.14 89.39,155.93 89.39,152.9 89.69,152.6 93.27,152.6 93.48,152.8 93.48,154.78 93.64,154.95 94.47,154.95 94.56,155.04 94.56,156.14 94.51,156.19 91.28,156.19
B+ on BOTTOM: 109.23,146.06 109.05,145.88 109.05,140.88 109.38,140.55 112.44,140.55 112.59,140.7 112.59,141.97 112.87,142.25 112.87,143.51 112.31,143.51 112.31,144.05 112.87,144.05 112.87,144.31 112.31,144.31 112.31,144.85 112.88,144.85 112.88,145.92 112.74,146.06
B+ on IN1: 90.11,167.08 92.7,167.08 92.89,166.89 92.89,153.14 92.44,152.69 90.07,152.69 89.73,153.03 89.73,166.7
B+_1.35VP on TOP (solid shape): 61.65,41.99 61.65,38.57 61.52,38.44 51.87,38.44 51.62,38.69 51.62,41.55 51.75,41.68 52.89,41.68 52.89,41.17 53.71,41.17 53.71,41.74 54.1,41.74 54.1,41.17 54.92,41.17 54.92,41.68 58.35,41.68 58.86,42.18 61.46,42.18
BATT+ on TOP: 166.37,170.16 165.5,169.3 165.5,168.56 165.3,168.36 162.47,168.36 161.92,168.92 161.92,170.96 161.92,170.96 161.92,171.37 162.1,171.55 163.23,171.55 163.81,172.13 166.27,172.13 166.37,172.03
BATT+ on BOTTOM: 161.73,169.38 161.73,158.96 163.12,157.56 163.63,157.56 163.76,157.69 163.76,159.09 164.01,159.34 164.52,159.34 164.78,159.09 164.78,157.56 164.9,157.44 166.05,157.44 166.55,157.95 166.55,165.95 167.06,166.45 167.06,167.98 165.28,169.76 162.11,169.76
BATT++ on TOP: 167.19,180.36 163.76,180.36 163.51,180.11 163.51,172.49 163.72,172.28 164.35,172.28 164.35,172.83 164.9,172.83 164.9,172.28 165.16,172.28 165.16,172.83 165.7,172.83 165.7,172.27 166.5,172.27 166.55,172.32 166.55,176.68 167.44,177.57 167.44,180.11
BATT_PRS on TOP: 159.06,180.42 157.79,180.42 157.54,180.17 157.54,178.65 157.66,178.52 158.93,178.52 159.19,178.77 159.19,180.3
BOOT1 on BOTTOM: 124.92,147.2 126.65,147.2 127.31,146.54 128.84,146.54 129.06,146.31 129.06,145.8 128.95,145.69 127.17,145.69 125.98,146.88 124.93,146.88 124.85,146.96 124.85,147.13
BOOT_1.35VP on TOP: 59.3,49.87 60.83,49.87 60.89,49.8 62.16,49.8 62.35,49.61 62.35,49.04 62.22,48.92 61.33,48.92 60.57,49.68 59.3,49.68
BOOTG on BOTTOM: 121.67,147.58 120.22,147.58 119.27,146.62 119.26,146.62 118.9,146.26 117.67,146.26 117.61,146.2 117.61,145.5 117.63,145.48 118.98,145.48 120.82,147.32 121.67,147.32 121.73,147.38 121.73,147.52
BST on TOP (solid shape): 142.92,158.26 142.92,156.81 142.86,156.75 142.86,155.74 142.79,155.67 142.67,155.67 142.6,155.74 142.6,157.64 141.97,158.28 141.97,158.63 142.09,158.76 142.42,158.76
BST on BOTTOM (solid shape): 142.87,158.81 143.95,158.81 144,158.76 144,158.21 143.94,158.15 142.03,158.15 141.9,158.28 141.9,158.85 142.03,158.97 142.7,158.97
BST_1.35VP on TOP (solid shape): 62.29,48.15 62.29,46.31 62.1,46.12 61.4,46.12 61.27,46.25 61.27,48.15 61.33,48.22 62.22,48.22
BST_3V on TOP (solid shape): 37.22,46.68 37.22,46.55 37.17,46.5 36.09,46.5 35.12,45.54 34.19,45.54 34.09,45.64 34.09,46.65 34.16,46.72 36.05,46.72 36.06,46.73 37.17,46.73
BST_5V on TOP: 41.2,45.67 41.2,45.67 41.29,45.59 42.47,45.59 42.53,45.64 42.53,46.58 42.45,46.66 40.57,46.66 40.4,46.83 39.43,46.83 39.37,46.77 39.37,46.6 39.44,46.54 40.34,46.54
BST_CHGA on BOTTOM (solid shape): 145.27,160.18 145.27,159.58 145.19,159.51 143.1,159.51 142.92,159.68 142.92,160.12 143.17,160.37 145.08,160.37
CHG on BOTTOM (solid shape): 163.89,156.42 163.89,154.77 164.01,154.64 164.52,154.64 164.65,154.77 164.65,156.29 164.78,156.42 165.54,156.42 165.79,156.17 165.79,153.63 165.54,153.37 161.75,153.37 161.71,153.39 161.7,153.42 160.41,153.42 159.7,154.14 159.7,157.82 159.82,157.95 162.36,157.95
CHG_B+ on TOP (solid shape): 157.23,161.35 157.23,158.2 157.13,158.1 148.93,158.1 148.65,158.38 148.65,160.74 149.54,161.63 156.95,161.63
CHG_B+ on BOTTOM: 150.93,165.31 154.62,165.31 154.82,165.11 154.82,163.87 154.27,163.87 154.27,163.13 154.82,163.13 154.82,162.68 154.28,162.68 154.28,161.93 154.82,161.93 154.82,161.4 154.11,161.4 154.11,159.85 153.85,159.6 151.31,159.6 150.81,160.1 150.81,165.18
CLK_SMB on TOP: 163.12,180.42 161.73,180.42 161.47,180.17 161.47,178.65 161.6,178.52 163.12,178.52 163.25,178.65 163.25,180.3
CPU_B+ on TOP: 120.71,138.13 120.71,135.66 120.64,135.59 117.23,135.59 117.14,135.68 117.14,137.37 117.27,137.5 120.01,137.5 120.07,137.56 120.07,138.64 119.94,138.77 119.37,138.77 119.25,138.9 119.25,140.29 119.44,140.48 121.72,140.48 122.29,141.05 128.71,141.05 128.96,140.8 130.87,140.8 131.25,141.18 132.58,141.18 132.9,141.5 135.18,141.5 135.57,141.12 135.57,137.31 135.25,136.99 133.28,136.99 132.52,136.23 131.5,136.23 131.44,136.16 131.44,135.47 131.37,135.4 130.87,135.4 130.8,135.47 130.8,138.2 130.55,138.45 121.02,138.45
CPU_B+ on BOTTOM: 113.46,146.32 113.02,145.89 113.02,144.7 112.46,144.7 112.46,144.44 113.02,144.44 113.02,143.91 112.46,143.91 112.46,143.66 113.01,143.66 113.01,136.02 113.35,135.68 121.05,135.68 122.58,137.21 122.58,138.1 122.87,138.39 128.07,138.39 128.33,138.13 128.33,136.67 128.45,136.55 133.15,136.55 133.72,137.12 136.45,137.12 136.77,137.43 136.77,140.67 136.14,141.31 132.39,141.31 131.95,140.86 129.15,140.86 128.71,141.31 122.61,141.31 121.53,140.23 119.44,140.23 119.37,140.17 119.37,139.76 118.87,139.25 117.65,139.25 117.17,139.73 117.17,146.04 116.88,146.32
DAT_SMB on TOP: 161.09,180.42 159.7,180.42 159.57,180.3 159.57,178.65 159.7,178.52 161.09,178.52 161.22,178.65 161.22,180.3
DCIN on TOP (solid shape): 148.42,157.69 148.42,156.55 148.32,156.45 145.09,156.45 144.32,155.67 144.19,155.67 144.13,155.74 144.13,156.75 144.7,157.32 145.78,157.32 146.23,157.78 148.33,157.78
DH_1.35VP on TOP (solid shape): 63.75,41.93 63.75,41.49 63.68,41.42 61.84,41.42 61.78,41.49 61.78,41.87 61.91,41.99 63.68,41.99
DH_1.35VP on IN1 (solid shape): 63.65,42.91 63.65,41.58 63.4,41.33 62.64,41.33 62.45,41.52 62.45,42.72 62.76,43.04 63.53,43.04
DH_1.35VP on IN1 (solid shape): 62.3,48.57 62.3,48.32 61.79,47.81 61.47,47.81 60.27,49.02 60.27,49.27 60.46,49.46 61.41,49.46
DH_1.35VP on TOP: 59.54,49.45 60.61,49.45 61.25,48.81 61.25,48.52 61.13,48.4 60.89,48.4 60.03,49.26 59.32,49.26 59.29,49.29 59.29,49.42 59.31,49.45 59.54,49.45
DH_CHG on TOP (solid shape): 160.84,161.02 160.84,160.23 160.71,160.1 157.92,160.1 157.79,160.23 157.79,160.99 157.92,161.12 160.74,161.12
DH_CHG on TOP (solid shape): 143.49,157.89 143.49,157.01 143.36,156.88 143.36,155.67 143.3,155.61 143.17,155.61 143.11,155.67 143.11,156.88 143.05,156.94 143.05,158 143.07,158.02 143.36,158.02
DH_CHG on IN2 (solid shape): 160.84,160.61 160.84,159.09 160.71,158.96 159.57,158.96 159.31,159.22 159.31,160.61 159.44,160.74 160.71,160.74
DH_CHG on IN2 (solid shape): 144.05,158.95 144.05,156.89 143.97,156.81 143.08,156.81 142.93,156.97 142.93,158.87 143.08,159.02 143.97,159.02
DL_1.35VP on IN2 (solid shape): 58.92,36.91 58.92,35.52 58.86,35.45 57.65,35.45 57.52,35.58 57.52,37.04 57.78,37.3 58.54,37.3
DL_1.35VP on IN2 (solid shape): 59.44,47.43 59.44,46.55 59.68,46.31 59.68,45.55 59.37,45.23 58.6,45.23 58.54,45.3 58.54,46.12 58.93,46.52 58.93,47.49 59.06,47.62 59.25,47.62
DL_1.35VP on TOP: 58.85,48.09 58.85,48.55 58.9,48.61 59,48.61 59.03,48.58 59.03,48 59.45,47.57 59.45,46.56 59.35,46.45 59.06,46.45 58.94,46.58 58.94,47.66 58.84,47.75 58.84,48.09
DL_CHG on TOP (solid shape): 156.01,154.64 156.01,154.26 155.89,154.14 154.23,154.14 153.73,153.63 153.22,153.63 153.09,153.75 153.09,154.64 153.22,154.77 155.89,154.77
DL_CHG on TOP (solid shape): 147.75,155.23 147.75,154.85 147.62,154.72 145.9,154.72 145.84,154.66 144.63,154.66 144.57,154.72 144.57,154.85 144.63,154.91 145.66,154.91 146.11,155.35 147.62,155.35
DL_CHG on IN2 (solid shape): 148.37,155.53 148.37,154.81 148.29,154.73 146.51,154.73 146.36,154.88 146.36,155.16 146.99,155.79 148.11,155.79
DL_CHG on IN2 (solid shape): 153.73,155.28 153.73,153.75 153.6,153.63 152.71,153.63 152.46,153.88 152.46,155.41 152.58,155.53 153.47,155.53
FB_1.0VALWP on BOTTOM (solid shape): 153.16,119.01 153.16,117.42 153,117.27 150.57,117.27 150.25,117.59 150.25,119.21 150.31,119.27 152.89,119.27
HUB_BUSJ on BOTTOM (solid shape): 144.92,53.06 144.92,52.62 146.15,51.4 146.74,51.4 146.86,51.28 146.86,49.7 146.78,49.62 145.34,49.62 145.21,49.75 145.21,51.57 144.45,52.33 143.31,52.33 143.1,52.54 143.1,52.96 143.36,53.22 144.77,53.22
INT-SPK-L+ on TOP (solid shape): 152.27,13.36 152.27,10.63 150.89,9.25 150.42,9.25 150.37,9.3 150.37,10.07 151.76,11.45 151.76,13.48 152.14,13.48
INT-SPK-L+ on BOTTOM (solid shape): 151.95,14.97 151.95,14.08 151.99,14.04 151.99,13.59 152.18,13.41 152.18,12.53 152.1,12.45 151.82,12.45 151.75,12.53 151.75,14.98 151.78,15.02 151.9,15.02
INT-SPK-L+ on TOP: 61.58,13.24 64.42,13.24 65.42,14.24 66.99,14.24 67.29,13.94 67.29,13.69 65.63,12.02 61.64,12.02 61.47,12.19 61.47,13.14
INT-SPK-L+ on BOTTOM: 60.18,14.47 61.99,14.47 62.38,14.09 62.38,12.33 62.25,12.2 61.51,12.2 61.45,12.26 61.45,13.43 61.12,13.76 60.22,13.76 60.14,13.84 60.14,14.44
INT-SPK-L- on BOTTOM (solid shape): 151.56,14.96 151.56,13.43 151.62,13.37 151.62,12.48 151.54,12.4 151.26,12.4 151.14,12.52 151.14,13.44 151.35,13.65 151.35,14.98 151.38,15.01 151.5,15.01
INT-SPK-L- on TOP: 58.38,14.5 59.73,14.5 59.99,14.24 59.99,13.27 59.85,13.13 58.43,13.13 58.26,13.29 58.26,14.38
INT-SPK-L- on TOP: 151.25,13.48 151.44,13.48 151.57,13.36 151.57,11.74 151.49,11.67 150.48,11.67 150.4,11.74 150.4,12.05 150.5,12.15 150.91,12.15 151.12,12.36 151.12,13.36
INT-SPK-L- on BOTTOM: 59.85,14.45 58.43,14.45 58.3,14.32 58.3,13.46 58.43,13.33 58.71,13.33 58.83,13.46 58.83,13.58 58.95,13.7 59.84,13.7 59.87,13.74 59.87,14.42
INT-SPK-R+ on BOTTOM (solid shape): 150.76,14.99 150.76,14 150.39,13.63 150.39,12.49 150.2,12.3 150.06,12.3 149.85,12.5 149.85,13.18 150.17,13.5 150.17,13.65 150.55,14.03 150.55,14.99 150.58,15.02 150.73,15.02
INT-SPK-R+ on BOTTOM: 64.01,13.63 64.85,13.63 64.99,13.77 64.99,14.65 64.14,15.5 63.2,15.5 63.13,15.43 63.13,15.22 63.87,14.47 63.87,13.77
INT-SPK-R+ on IN1: 65.14,15.57 63.29,15.57 63.16,15.44 63.16,14.99 63.61,14.55 65.18,14.55 65.33,14.7 65.33,15.37
INT-SPK-R+ on IN1: 150.3,13.48 149.66,13.48 149.47,13.29 149.47,11.51 149.73,11.26 149.98,11.26 150.36,11.64 150.36,13.42
INT-SPK-R- on BOTTOM (solid shape): 151.15,14.96 151.15,13.83 150.98,13.66 150.98,12.48 150.88,12.38 150.63,12.38 150.53,12.48 150.53,13.51 150.56,13.55 150.56,13.56 150.96,13.95 150.96,14.96 151.03,15.03 151.07,15.03
INT-SPK-R- on BOTTOM: 62.72,13.65 63.52,13.65 63.58,13.71 63.58,14.36 63.58,14.37 63.58,14.42 62.53,15.46 61.74,15.46 61.71,15.43 61.71,14.82 61.94,14.59 62.24,14.59 62.58,14.24 62.58,13.79
INT-SPK-R- on IN1: 151,13.42 150.68,13.42 150.55,13.29 150.55,11.51 150.42,11.39 150.42,10.5 150.62,10.31 150.87,10.31 151.19,10.63 151.19,12.28 151.06,12.4 151.06,13.36
INT-SPK-R- on IN1: 61.86,15.27 62.62,15.27 62.74,15.15 62.74,13.52 62.64,13.42 62.21,13.42 61.64,13.99 61.64,15.06
LG_3V on TOP: 37.59,44.55 36.8,43.77 36.44,43.77 36.32,43.89 36.32,44.15 36.49,44.32 36.5,44.32 37.39,45.21 37.39,45.85 37.46,45.91 37.52,45.91 37.59,45.85
LG_3V on TOP: 34.25,39.56 33.19,39.56 33.14,39.61 33.14,39.97 33.23,40.06 33.81,40.06 34.47,40.72 34.73,40.72 34.85,40.6 34.85,40.17
LG_3V on IN1: 33.84,40.09 33.84,39.77 34.09,39.52 34.35,39.52 35.17,40.34 35.17,41.49 35.1,41.56 34.26,41.56 34.03,41.33 34.03,40.28
LG_3V on IN1: 37.33,44.85 36.7,44.85 35.62,43.77 35.62,43.33 35.81,43.14 36.25,43.14 37.46,44.34 37.46,44.72
LG_5V on IN1 (solid shape): 40.89,44.53 40.89,43.65 40.82,43.58 39.81,43.58 39.43,43.96 39.43,45.11 39.55,45.23 40.19,45.23
LG_5V on IN1 (solid shape): 42.67,37.61 42.67,36.66 42.54,36.53 40.25,36.53 40,36.79 40,37.3 40.13,37.42 40.89,37.42 40.95,37.36 41.9,37.36 42.03,37.49 42.03,37.8 42.09,37.87 42.41,37.87
LG_5V on TOP: 39.97,44.26 39.2,45.03 39.19,45.02 39.08,45.02 38.97,45.13 38.97,45.92 39.02,45.97 39.17,45.97 39.22,45.92 39.22,45.64 39.62,45.25 39.92,45.25 40.51,44.66 40.51,44.28 40.39,44.17 40.11,44.17 40.09,44.17 40.08,44.18 40.03,44.22
LG_5V on TOP: 43.24,37.87 42.09,37.87 42.03,37.8 42.03,36.85 42.16,36.72 43.24,36.72 43.3,36.79 43.3,37.8
LGATE1 on TOP: 129.28,136.04 128.71,136.04 127.82,135.15 127.82,134.89 127.88,134.83 128.71,134.83 129.34,135.47 129.34,135.97
LGATE1 on BOTTOM: 124.02,146.85 124.02,145.7 124.39,145.33 124.39,144.2 124.36,144.18 123.83,144.18 123.47,144.54 123.47,145.58 123.74,145.85 123.74,146.84 123.79,146.89 123.98,146.89
LGATE1 on IN2: 128.26,136.67 128.26,135.91 127.63,135.28 127.63,135.02 127.88,134.77 128.83,134.77 129.41,135.34 129.41,136.61 129.22,136.8 128.39,136.8
LGATE1 on IN2: 124.47,145.12 124.47,144.31 124.58,144.19 124.58,143.15 124.33,142.9 123.56,142.9 123.44,143.02 123.44,145.18 123.68,145.42 124.16,145.42
LGATEG on TOP: 122.29,137.63 123.74,137.63 123.95,137.83 123.95,138.2 123.82,138.32 122.29,138.32 122.17,138.2 122.17,137.75
LGATEG on BOTTOM: 122.17,146.86 122.17,145.89 121.39,145.12 121.39,144.66 121.48,144.57 122.09,144.57 122.26,144.74 122.26,145.12 122.42,145.29 122.42,146.85 122.34,146.94 122.24,146.93
LGATEG on IN2: 122.03,145.72 122.28,145.72 122.41,145.58 122.41,143.74 122.33,143.67 121.21,143.67 121.14,143.75 121.14,144.83
LGATEG on IN2: 122.68,138.83 122.68,137.82 122.8,137.69 123.82,137.69 124.01,137.88 124.01,138.77 123.82,138.96 122.8,138.96
LX_1.0VALWP on BOTTOM (solid shape): 157.18,115.95 157.18,115.39 157.88,114.69 157.88,112.58 157.78,112.48 156.72,112.48 156.24,112.96 156.24,114.59 155.96,114.87 154.76,114.87 154.59,115.03 154.59,115.86 154.81,116.07 157.05,116.07
LX_1.05VSP on BOTTOM: 163.38,97.49 161.22,97.49 161.09,97.37 161.09,96.99 161.22,96.86 161.73,96.86 162.49,96.1 162.49,94.19 162.74,93.94 164.48,93.94 165.02,94.47 165.02,96.17 164.71,96.48 163.76,96.48 163.51,96.73 163.51,97.37
LX_3V on BOTTOM (solid shape): 32.76,37.99 32.76,32.79 32.57,32.6 29.14,32.6 28.89,32.85 28.89,38.31 29.01,38.44 32.31,38.44
LX_3V on IN2 (solid shape): 36.11,47.23 36.11,46.65 35.99,46.53 34.14,46.53 34.02,46.65 34.02,47.16 34.21,47.35 35.99,47.35
LX_3V on TOP: 35.99,47.35 36.23,47.11 37.17,47.11 37.22,47.06 37.22,46.93 37.19,46.91 36.05,46.91 35.99,46.85 34.21,46.85 34.12,46.93 34.12,47.75 34.17,47.8 35.34,47.8 35.78,47.35
LX_3V on TOP: 32.31,41.61 29.9,41.61 29.77,41.49 29.77,39.23 29.38,38.83 29.38,34.72 29.66,34.44 32.57,34.44 32.82,34.69 32.82,40.09 32.44,40.47 32.44,41.49
LX_3V on IN2: 31.04,37.93 31.04,36.85 31.49,36.41 32.7,36.41 32.82,36.53 32.82,37.3 32,38.12 31.24,38.12
LX_5V on TOP (solid shape): 44.95,41.61 44.95,40.6 45.14,40.41 47.05,40.41 47.55,39.9 47.55,32.91 47.24,32.6 44.44,32.6 44.06,32.98 44.06,36.41 43.49,36.98 43.49,40.34 43.05,40.79 43.05,41.49 43.24,41.68 44.89,41.68
LX_5V on BOTTOM (solid shape): 47.05,36.41 47.05,32.72 46.79,32.47 42.41,32.47 42.28,32.6 42.28,36.34 42.73,36.79 46.67,36.79
LX_5V on TOP: 40.44,46.96 39.45,46.96 39.4,47.01 39.4,47.16 39.45,47.21 40.37,47.21 40.51,47.35 40.81,47.35 41.28,47.82 42.37,47.82 42.47,47.72 42.47,46.88 42.4,46.81 40.6,46.81
LX_5V on IN2: 46.28,37.3 46.28,35.52 46.54,35.26 47.3,35.26 47.43,35.39 47.43,37.3 47.3,37.42 46.41,37.42
LX_5V on IN2: 42.97,46.46 42.84,46.34 40.68,46.34 40.43,46.59 40.43,47.42 40.62,47.61 42.72,47.61 42.97,47.35
LX_+1.8VSP on TOP: 45.4,23.52 48.82,23.52 49.02,23.33 49.02,20.79 48.95,20.72 46.92,20.72 46.86,20.79 46.86,22.44 46.48,22.82 45.4,22.82 45.33,22.88 45.33,23.45
LX_CHG on TOP (solid shape): 146.35,159.42 146.35,158.85 145.59,158.08 145.12,158.08 143.87,156.84 143.87,155.67 143.81,155.61 143.68,155.61 143.62,155.67 143.62,156.93 143.76,157.07 143.76,157.12 143.78,157.14 143.78,157.99 144.63,158.85 145.08,158.85 145.78,159.55 146.22,159.55
LX_CHG on BOTTOM (solid shape): 158.04,157.69 158.04,153.5 157.66,153.12 155,153.12 153.85,154.26 153.85,158.2 157.54,158.2
LX_CHG on BOTTOM (solid shape): 146.35,159.42 146.35,158.85 145.59,158.08 144.32,158.08 144.32,158.72 144.95,158.72 145.78,159.55 146.22,159.55
LX_CHG on IN2 (solid shape): 158.17,157.95 158.17,157.18 157.92,156.93 156.27,156.93 156.01,157.18 156.01,158.07 156.27,158.33 157.79,158.33
LX_CHG on IN2 (solid shape): 146.87,159.22 146.87,158.33 146.78,158.24 145.47,158.24 145.34,158.36 145.34,159.22 145.6,159.47 146.61,159.47
LX_CHG on TOP: 157.94,159.98 160.08,159.98 160.2,159.85 160.2,151.98 159.82,151.6 156.52,151.6 156.39,151.72 156.39,157.26 156.62,157.49 157.54,157.49 157.82,157.77 157.82,159.85
P2 on TOP: 103.31,155.23 103.93,154.6 103.93,151.25 103.75,151.06 100.82,151.06 100.45,151.43 99.14,151.43 98.82,151.11 98.82,150.17 98.77,150.12 96.61,150.12 96.39,150.35 95.41,150.35 95.26,150.5 95.26,151.29 96.58,152.61 96.58,154.99 96.82,155.23
P3 on TOP: 107.98,155.05 105.4,155.05 105.01,154.66 105.01,149.83 105.19,149.65 108.01,149.65 108.18,149.82 108.18,154.85
P3 on BOTTOM: 119.18,164.55 120.71,164.55 120.83,164.68 120.83,164.93 120.71,165.06 114.8,165.06 114.61,164.87 114.61,157.41 110.15,152.95 106.52,152.95 106.51,152.97 105.06,152.97 104.62,152.52 104.62,150.64 104.62,150.64 104.62,149.4 104.85,149.17 104.86,149.18 113.65,149.18 113.85,149.39 113.85,151.86 120.71,158.72 120.71,163.66 119.18,163.66 119.06,163.79 119.06,164.42
PHASE1 on TOP: 130.61,138.07 129.52,138.07 129.47,138.02 129.47,135.4 128.45,134.39 128.45,133.62 128.39,133.56 126.68,133.56 126.42,133.31 126.42,131.21 126.74,130.89 131.18,130.89 131.37,131.08 131.37,134.7 130.68,135.4 130.68,138.01
PHASE1 on BOTTOM: 126.21,144.32 126.28,144.39 126.28,145.41 126.07,145.62 124.81,145.62 124.45,145.98 124.45,146.83 124.37,146.92 124.21,146.92 124.15,146.86 124.15,145.83 124.57,145.41 124.57,144.64 124.88,144.32
PHASE1 on BOTTOM: 132.52,135.78 129.53,135.78 128.39,134.64 127.18,134.64 126.17,133.62 126.17,130.96 126.49,130.64 129.98,130.64 130.23,130.89 130.23,134.39 130.3,134.45 131.18,134.45 131.25,134.39 131.25,131.91 131.44,131.72 132.52,131.72 132.71,131.91 132.71,135.59
PHASE1 on IN2: 130.74,132.16 129.34,132.16 129.22,132.04 129.22,131.08 129.28,131.02 130.8,131.02 130.99,131.21 130.99,131.91
PHASE1 on IN2: 124.95,145.65 125.89,145.65 126.29,145.25 126.29,144.08 126.1,143.88 125.35,143.88 124.82,144.41 124.82,145.53
PHASEG on TOP: 121.98,138.2 120.83,138.2 120.77,138.13 120.77,135.47 120.58,135.28 119.56,135.28 117.85,133.56 117.85,131.59 118.29,131.15 122.1,131.15 122.45,131.5 122.45,135.18 122.04,135.59 122.04,138.13
PHASEG on BOTTOM: 122.04,146.85 122.04,146.03 121.06,145.05 121.06,143.84 120.86,143.64 120.33,143.64 120.2,143.77 120.2,145.22 121.88,146.9 121.99,146.9
PHASEG on BOTTOM: 117.93,135.42 117.85,135.34 117.85,131.21 118.04,131.02 121.6,131.02 121.79,131.21 121.79,134.01 121.85,134.07 122.61,134.07 122.68,134.01 122.68,131.59 122.8,131.47 123.95,131.47 124.2,131.72 124.2,135.02 123.81,135.42
PHASEG on IN2: 119.25,136.04 119.25,134.83 119.44,134.64 120.45,134.64 120.58,134.77 120.58,136.1 120.45,136.23 119.44,136.23
PHASEG on IN2: 121.52,145.92 121.52,145.4 120.96,144.84 120.96,144.51 120.45,144 119.59,144 119.49,144.1 119.49,144.53 120.1,145.14 120.11,145.14 120.24,145.27 120.24,145.27 121.04,146.08 121.36,146.08
RING2 on TOP: 149.38,23.38 148.6,23.38 148.57,23.35 148.57,22.39 148.58,22.38 148.58,22.11 149.03,21.65 149.79,21.65 149.92,21.78 149.92,22.11 149.49,22.54 149.49,23.27
RING2 on BOTTOM: 149.51,23.35 149,23.35 148.9,23.25 148.9,22.21 149.84,21.27 150.65,21.27 150.96,20.96 150.96,20.43 151.01,20.38 151.11,20.38 151.16,20.43 151.16,21.22 150.6,21.78 150.16,21.78 149.59,22.35 149.59,23.27
RING2_R on TOP (solid shape): 149.62,24.76 149.62,23.71 149.49,23.57 148.47,23.57 148.39,23.64 148.39,24.72 148.52,24.85 149.54,24.85
RING2_R on TOP (solid shape): 167.02,24.77 167.02,23.41 166.93,23.33 164.25,23.33 164.15,23.43 164.15,24.27 164.73,24.85 166.93,24.85
RING2_R on IN1: 162.27,23.11 148.82,23.11 148.3,23.63 148.3,24.7 149.22,25.61 164.78,25.61 165.41,24.98 165.41,23.71 165.16,23.45 162.62,23.45
SLEEVE on TOP: 150.6,23.4 149.84,23.4 149.79,23.35 149.79,22.56 150.2,22.15 150.2,21.56 150.36,21.4 150.9,21.4 151.09,21.59 151.09,22.92
SLEEVE on BOTTOM: 150.55,23.3 149.97,23.3 149.92,23.25 149.92,22.26 150.15,22.03 150.6,22.03 151.34,21.29 151.34,20.53 151.39,20.48 151.52,20.48 151.54,20.51 151.54,21.7 151.52,21.72 151.52,21.83 150.65,22.69 150.65,23.2
SLEEVE_R on TOP: 151.4,24.21 150.72,23.53 149.93,23.53 149.75,23.71 149.75,24.81 150.55,25.61 162.43,25.61 163.57,26.75 165.54,26.75 165.79,27.01 166.81,27.01 167.06,26.75 167.06,25.48 166.81,25.23 164.78,25.23 163.76,24.21
SNB_CHG on TOP (solid shape): 154.87,153.25 154.87,151.6 154.71,151.44 152.04,151.44 151.95,151.54 151.95,152.74 152.08,152.87 153.35,152.87 153.85,153.37 154.74,153.37
SPK_L+_CONN on BOTTOM: 60.23,13.08 61.07,13.08 61.13,13.01 61.13,12.31 60.76,11.95 60.76,9.13 62.17,7.72 67.04,7.72 67.25,7.5 67.25,7.31 67.06,7.12 61.46,7.12 60.1,8.48 60.1,12.95
SPK_L-_CONN on BOTTOM: 58.92,13.05 59.78,13.05 59.87,12.96 59.87,8.26 61.4,6.74 67.04,6.74 67.25,6.52 67.25,6.21 67.02,5.98 60.92,5.98 59.26,7.63 59.26,11.96 58.91,12.31 58.91,13.04
SPK_R+_CONN on BOTTOM: 64.76,12.95 64,12.95 63.9,12.85 63.9,10.8 63.91,10.8 63.91,10.05 64.85,9.1 67.09,9.1 67.25,9.27 67.25,9.55 67,9.8 65.44,9.8 64.61,10.63 64.61,11.97 64.94,12.3 64.94,12.77
SPK_R-_CONN on BOTTOM: 62.71,12.91 63.61,12.91 63.66,12.86 63.66,9.99 64.9,8.75 67.09,8.75 67.25,8.58 67.25,8.14 67.16,8.05 64.36,8.05 62.83,9.57 62.83,12.03 62.67,12.2 62.67,12.87
SW_1.35VP on BOTTOM (solid shape): 64.06,39.33 64.06,36.53 63.87,36.34 57.08,36.34 56.06,37.36 56.06,40.98 56.44,41.36 62.03,41.36
SW_1.35VP on IN1 (solid shape): 63.94,39.9 63.94,38.82 63.75,38.63 62.54,38.63 62.29,38.88 62.29,39.77 62.67,40.15 63.68,40.15
SW_1.35VP on IN1 (solid shape): 60.9,48.06 60.9,47.62 60.59,47.3 60.27,47.3 59.25,48.32 59.25,48.57 59.44,48.76 60.2,48.76
